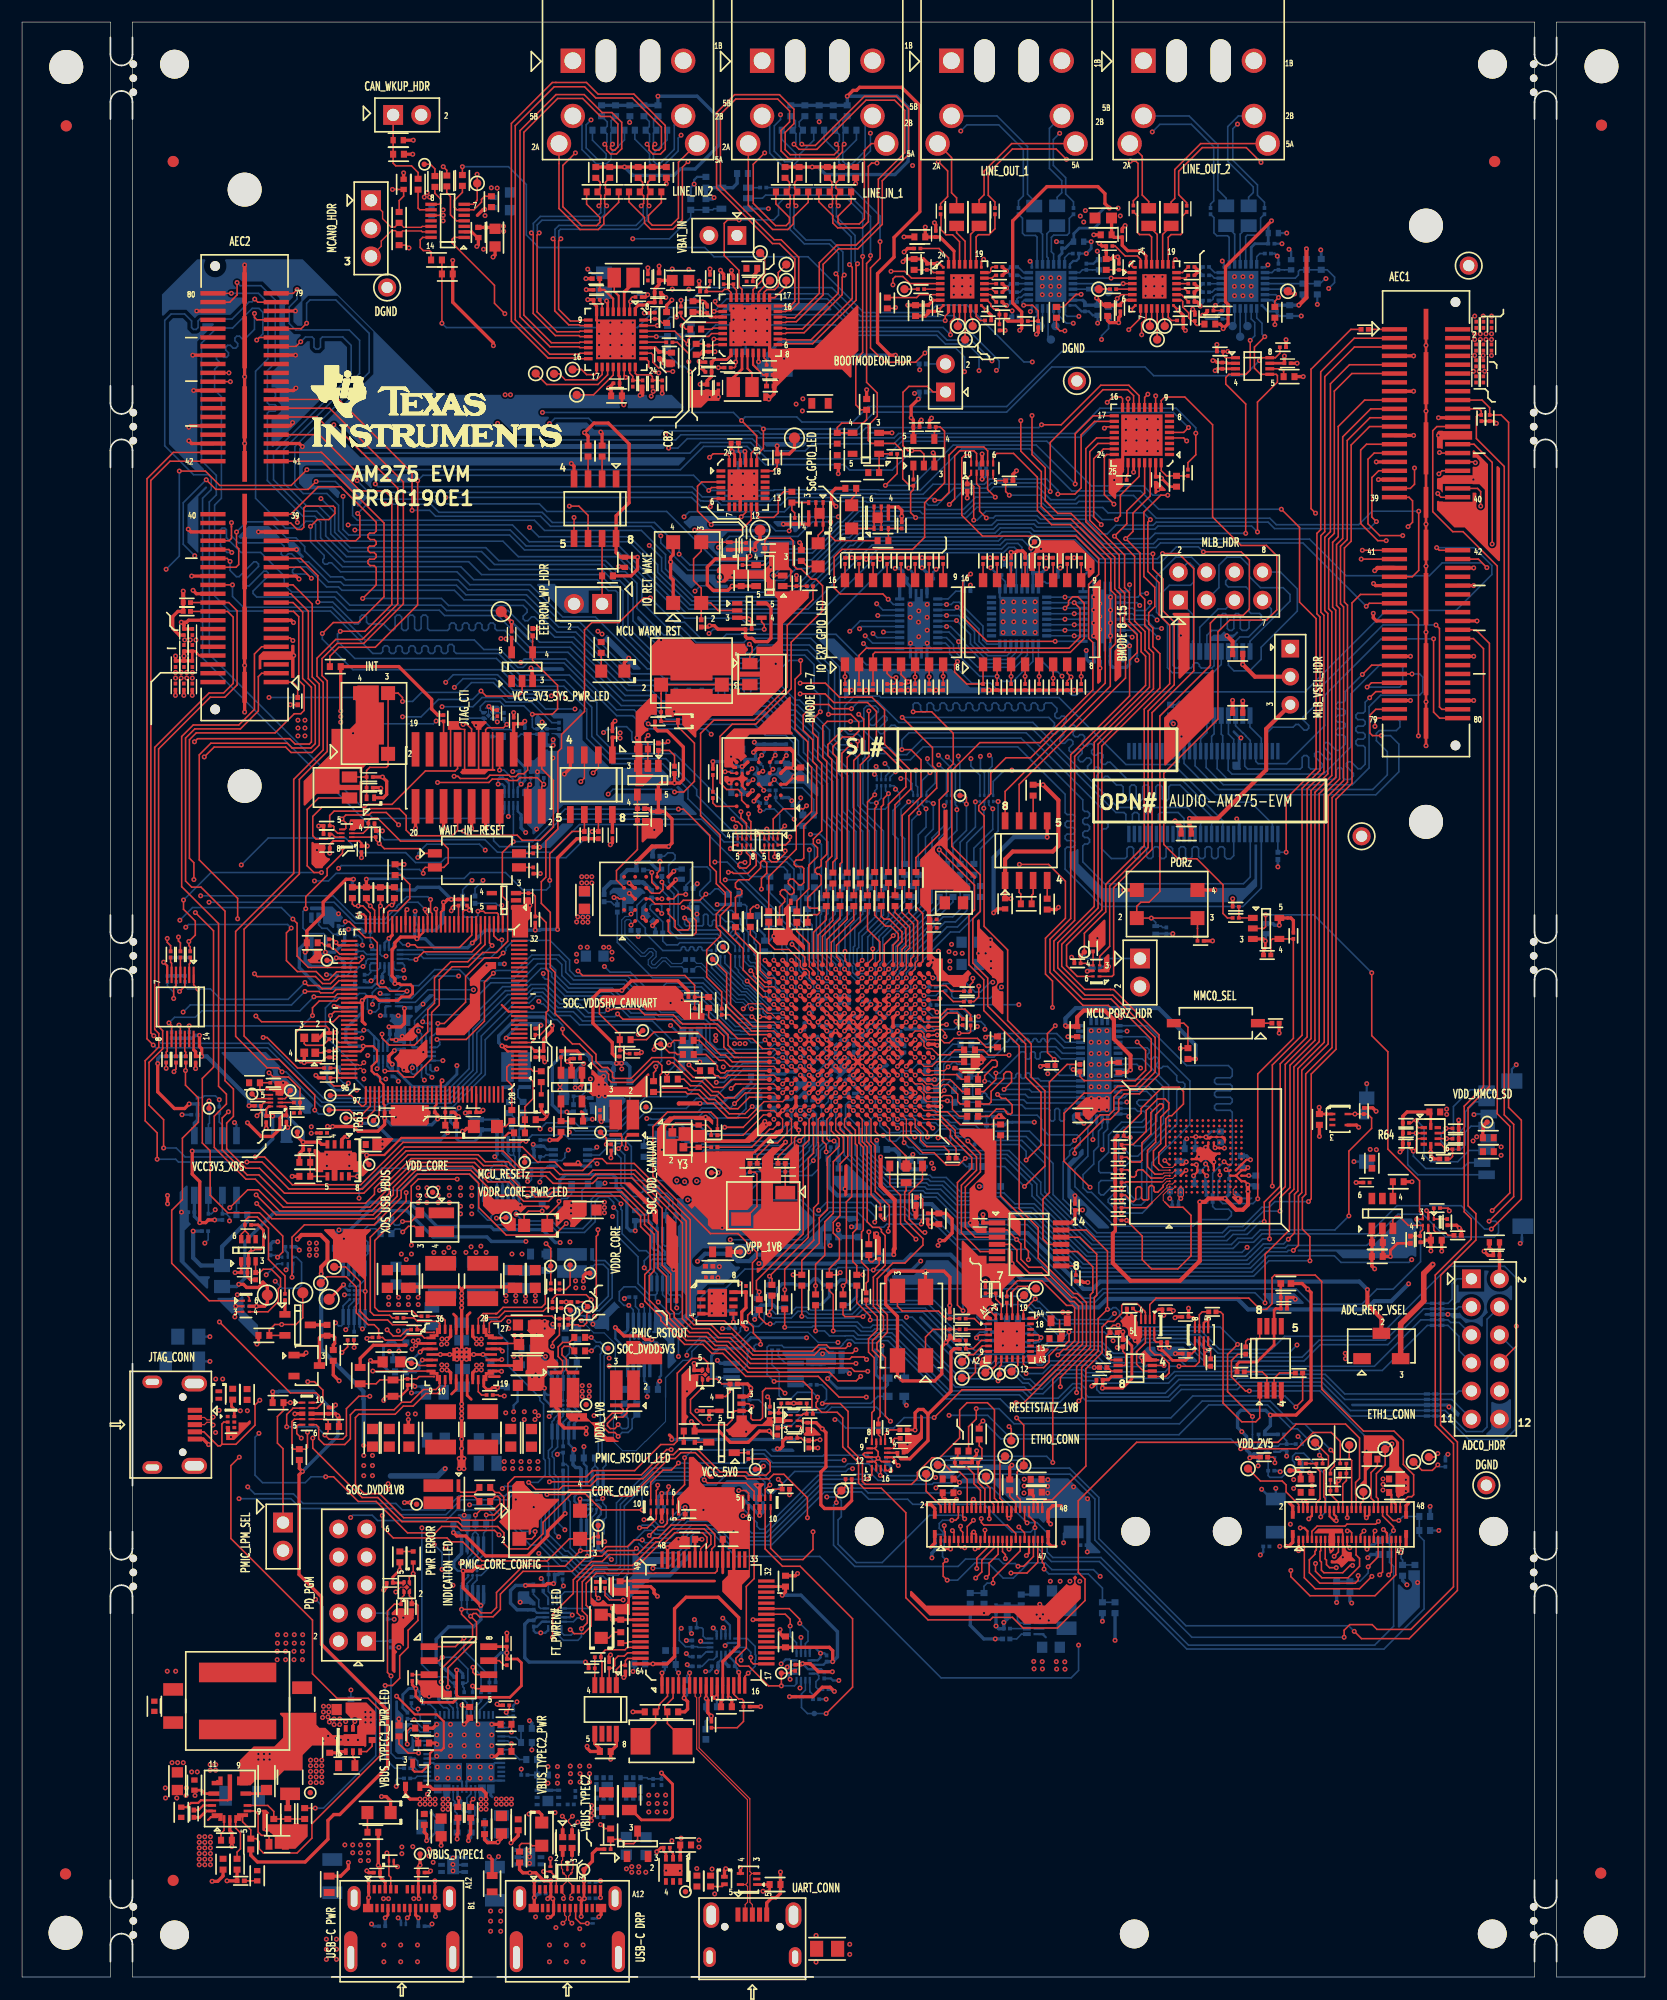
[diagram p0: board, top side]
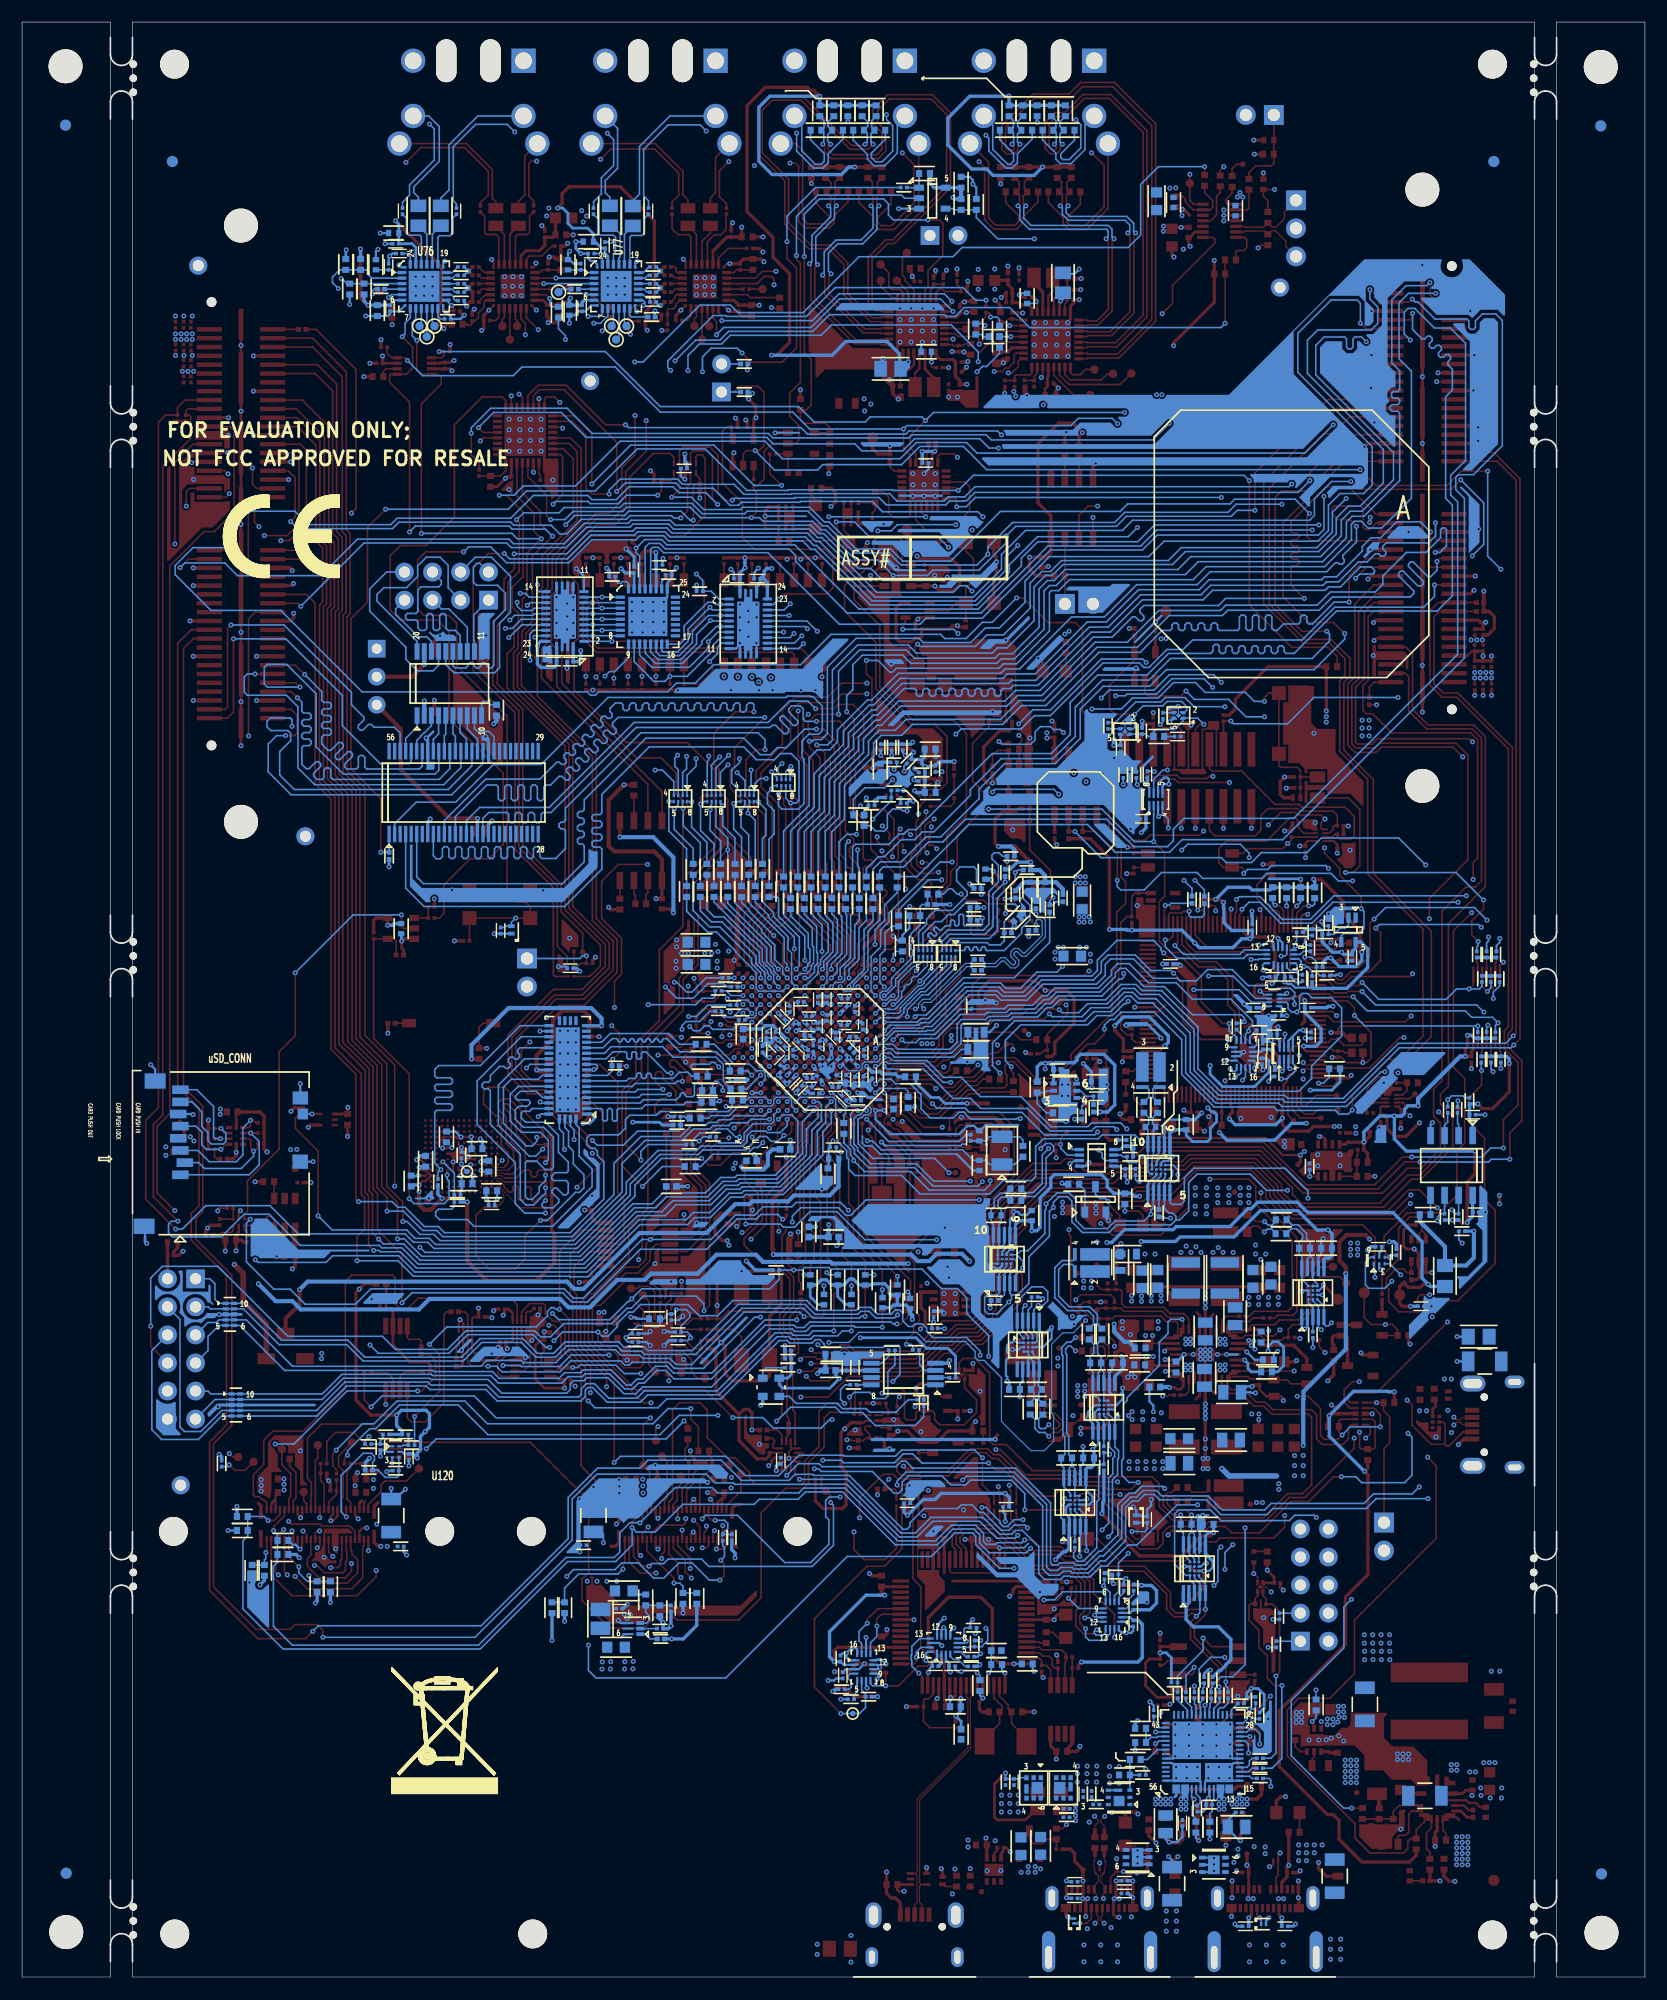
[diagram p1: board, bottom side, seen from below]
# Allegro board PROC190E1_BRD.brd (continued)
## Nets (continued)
EMMC_D2: R263.2 U49.A5(DAT2) U57.28(C6)
EMMC_D3: R275.2 U49.B2(DAT3) U57.40(C1)
EMMC_D4: R270.2 U49.B3(DAT4) U57.24(C8)
EMMC_D5: R267.2 U49.B4(DAT5) U57.26(C7)
EMMC_D6: R264.2 U49.B5(DAT6) U57.33(C4)
EMMC_D7: R262.2 U49.B6(DAT7) U57.31(C5)
EMMC_RSTN: R117.2 R5822.1 U26.4(Y) U49.K5(RST_N)
EN_VSYS_5V0: R3028.1 R3727.2 R5740.2 U134.7(EN/SYNC)
EPWM0_A: J12.3 U136.T2(SPI2_CS0)
EPWM0_B: J12.5 U136.R2(SPI2_CLK)
EPWM1_A: J13.3 U136.R1(SPI2_CS2)
EXT_CLKOUT0: R170.1 R337.1
EXT_CLKOUT0_R: R170.2 R5685.2 R5788.2 U136.P1(EXT_REFCLK1)
EXT_VMON2_1: J18.2 TP95.1(TP)
EXT_VMON2_2: J19.2 TP94.1(TP)
FT4232_DO: R321.1 R323.2 U61.4(DO)
FT4232_EECLK: R328.1 U61.2(CLK) U64.62(EECLK)
FT4232_EECS: R333.1 U61.1(CS) U64.63(EECS)
FT4232_EEDATA: R323.1 U61.3(DI) U64.61(EEDATA)
FT4232_REF: R609.2 U64.6(REF)
FT4232_RESET: C282.2 R357.1 U64.14(R\E\S\E\T\)
FT4232_SOC_UART2_RX_3V3: U64.16(ADBUS0) U125.13(2B1)
FT4232_SOC_UART2_TX_3V3: U64.17(ADBUS1) U125.15(1B1)
FT4232_SOC_UART3_RX_3V3: U64.26(BDBUS0) U126.13(2B1)
FT4232_SOC_UART3_TX_3V3: U64.27(BDBUS1) U126.15(1B1)
FT4232_UART2_RXD_1V8: R612.2 U125.8(2A1) U2351.7(S2B)
FT4232_UART2_TXD_1V8: R611.2 U125.6(1A1) U2351.9(S1B)
FT4232_UART3_RXD_1V8: R361.2 TP97.1(TP) U126.8(2A1) U2352.7(S2B)
FT4232_UART3_TXD_1V8: R631.2 TP117.1(TP) U126.6(1A1) U2352.9(S1B)
FT4232_USB_DM: J22.2(D-) U64.7(DM) U67.5(IO2)
FT4232_USB_DP: J22.3(D+) U64.8(DP) U67.3(IO1)
FT4232_USB_VBUS: C287.2 C291.2 C295.1 D3.2 J22.1(VBUS) TP96.1(TP) U66.4(EN) U66.6(IN) U67.1(VCC)
FT4232_WKUP_UART0_CTSN_3V3: U64.40(CDBUS2) U117.12(2B2)
FT4232_WKUP_UART0_RTSN_3V3: U64.41(CDBUS3) U117.14(1B2)
FT4232_WKUP_UART0_RXD_3V3: U64.38(CDBUS0) U117.13(2B1)
FT4232_WKUP_UART0_TXD_3V3: U64.39(CDBUS1) U117.15(1B1)
FT_PWREN#: R330.1 U64.60(P\W\R\E\N\)
GPIO1_23_INTN: R108.1 R547.2 U136.C7(WKUP_TIMER_IO1)
GPIO2_BUF_EN: R277.1 R278.2 U51.5(OE)
GPIO_CPSW1_RST: R364.1 U18.11(P11)
GPIO_CPSW2_RST: R604.1 U18.10(P10)
GPIO_EMMC_RSTN: R116.1 U21.9(P10)
GPIO_HYPERRAM_RSTN: R5697.1 U136.C12(OSPI1_CSN1)
GPIO_MCU_SOC: R546.1 R547.1 U98.5(2Y)
GPIO_MCU_SOC_INTN: R546.2 U136.C8(MCU_GPIO0_2)
GPIO_PCM1_RST: R84.1 U21.17(P20)
GPIO_PCM2_RST: R414.1 U21.19(P22)
HW/SW_CTRL_SEL: R83.2 R85.1 U15.23(HW_SW_CTRL)
HYPERBUS0_CK: R5694.1 R5754.2 U140.B2(CK)
HYPERBUS0_CK#: R5695.1 R5753.1 U140.B1(CK#)
HYPERBUS0_CS#: R5693.1 R5696.1 U140.A3(CS#)
HYPERBUS0_DQ0: R5715.1 RA8.1 U140.D3(DQ0)
HYPERBUS0_DQ1: R5716.1 RA8.2 U140.D2(DQ1)
HYPERBUS0_DQ2: R5712.1 RA8.4 U140.C4(DQ2)
HYPERBUS0_DQ3: R5710.1 RA8.3 U140.D4(DQ3)
HYPERBUS0_DQ4: R5717.1 RA9.1 U140.D5(DQ4)
HYPERBUS0_DQ5: R5714.1 RA9.4 U140.E3(DQ5)
HYPERBUS0_DQ6: R5713.1 RA9.2 U140.E2(DQ6)
HYPERBUS0_DQ7: R5711.1 RA9.3 U140.E1(DQ7)
HYPERBUS0_RST#: R5698.1 R5820.2 U140.A4(RESET#) U2348.4(Y)
HYPERBUS0_RWDS: R5709.1 R5752.1 R5810.1 U136.B15(OSPI1_DQS)
I2C0_SCL_1V8: C188.2 R234.2 R296.1 R598.2 U5.7(SCL) U6.7(SCL) U7.25(SCL_MOSI) U8.25(SCL_MOSI) U11.5(SCL_A) U15.12(SCL/GPIO3) U21.29(SCL) U76.7(SCL) U77.7(SCL) U2358.6(SCL)
I2C0_SCL_1V8_RC: R234.1 U136.M3(I2C0_SCL)
I2C0_SDA_1V8: C182.2 R210.2 R294.1 R603.2 U5.8(SDA) U6.8(SDA) U7.26(SDA_SSZ) U8.26(SDA_SSZ) U11.4(SDA_A) U15.19(SDA/GPIO2) U21.30(SDA) U76.8(SDA) U77.8(SDA) U2358.5(SDA)
I2C0_SDA_1V8_RC: R210.1 U136.N3(I2C0_SDA)
I2C3_SCL_1V8: J12.18 R465.2 U136.N1(UART0_CTSN)
I2C3_SDA_1V8: J12.20 R464.2 U136.L3(UART0_RTSN)
I2C5_SCL_1V8: J13.18 R685.2 U136.L4(MCAN0_TX)
I2C5_SDA_1V8: J13.20 R684.2 U136.M4(MCAN0_RX)
I2C_ADDR0_A0: J18.47 R641.1 R642.2
I2C_ADDR0_A2: J18.37 R638.1 R639.2
I2C_ADDR1_A0: J19.47 R628.2 R630.1
I2C_ADDR1_A2: J19.37 R626.2 R629.1
INA_ALERT: R305.2 R505.2 R586.2 R596.2 R597.1 R608.2 R5778.2 R5782.2 TP46.1(TP)
IO_EXP0_INTN: R108.2 R5761.2 U21.32(I\N\T\)
IO_EXP1_INTN: R98.1 U18.22(I\N\T\)
IO_EXP_ADDR: R456.1 U82.26(ADDR)
IO_EXP_TEST_LED: R441.1 U18.12(P12)
IO_MCAN0_EN: R5639.2 U21.10(P11)
IO_MCAN0_STB#: R102.2 R5692.1 U21.12(P13)
IORET_WAKE: U136.D7(MCU_GPIO0_16) U3070.4(Y)
JTAG_CTI_RTCK: J14.9 R476.1
JTAG_CTI_TCK: J14.11 R485.1 R487.1 U87.1(B) U88.1(B)
JTAG_DIR: R569.2 U110.4(1DIR) U110.5(2DIR)
JTAG_EMU0: J14.13 R211.2 U39.7(B1)
JTAG_EMU1: J14.14 R212.2 U39.6(B2)
JTAG_EMU_RSTN: J14.15 R482.2 U86.6(C)
JTAG_TCK: R483.1 U110.14(1B2)
JTAG_TDI: J14.3 U110.12(2B2)
JTAG_TDIS: J14.4 R490.2
JTAG_TDO: J14.7 U90.7(B1)
JTAG_TMS: J14.1 U110.13(2B1)
JTAG_TRST#: J14.2 R489.2 U110.15(1B1)
LDO_1V8: C303.1 U129.35(LDO_1V8)
LDO_3V3: C292.1 C300.2 C319.2 R195.1 R374.1 R378.1 R644.1 R646.1 R658.1 R660.1 R664.1 R678.1 R679.1 U69.8(VCC) U71.5(VCC) U129.9(LDO_3V3)
LM61460_BOOT: C3494.1 R5805.2 U134.14(CBOOT)
LM61460_FB: C3639.2 R3651.1 R3720.2 U134.4(FB)
LM61460_RT: R3652.1 U134.6(RT)
LM61460_SW: C3494.2 L24.1 U134.10(SW)
LM61460_VCC: C3627.2 U134.2(VCC)
MCAN0_CAN_H: J9.3 R88.2 U3068.13(CANH)
MCAN0_CAN_L: J9.1 R93.1 U3068.12(CANL)
MCAN0_EN: R5638.1 R5639.1 U3068.6(EN)
MCAN0_FAULT#: R5637.1 U3068.8(NFAULT)
MCAN0_RX: R81.1 U136.B4(MCU_GPIO0_6)
MCAN0_RX_R: R81.2 U3068.4(RXD)
MCAN0_STB#: R102.1 U3068.14(NSTB)
MCAN0_T: C107.1 R88.1 R93.2
MCAN0_TX: R82.2 U136.C4(MCU_GPIO0_5)
MCAN0_TX_R: R82.1 U3068.1(TXD)
MCAN0_WAKE_R: R5635.1 U3068.9(WAKE)
MCAN1_RX: R5670.1 U136.D5(MCU_GPIO0_8)
MCAN1_RX_R: J13.53 R5670.2
MCAN1_TX: J13.51 R5671.1
MCAN1_TX_R: R5671.2 U136.A4(MCU_GPIO0_7)
MCAN4_RX: R5650.1 U136.B6(MCU_GPIO0_14)
MCAN4_RX_R: J12.53 R5650.2
MCAN4_TX: J12.51 R5649.1
MCAN4_TX_R: R5649.2 U136.R4(SPI2_CS1)
MCASP0_ACLKR: J12.43 R5648.1 RA7.7
MCASP0_ACLKR_R: R5648.2 U136.R16(MCASP0_AXR12)
MCASP0_ACLKX: J12.37 R178.1 RA6.8
MCASP0_AFSR: J12.41 R498.2 RA7.6
MCASP0_AFSR_R: R498.1 U136.T17(MCASP0_AXR13)
MCASP0_AFSX: J12.39 R191.2 RA2.8
MCASP0_AFSX_R: R191.1 U136.M19(MCASP0_AFSX)
MCASP0_AXR0: J12.27 R176.2 RA5.8
MCASP0_AXR0_R: R176.1 U136.N17(MCASP0_AXR0)
MCASP0_AXR1: J12.29 R499.2 RA2.7
MCASP0_AXR1_R: R499.1 U136.M16(MCASP0_AXR1)
MCASP0_AXR2: J12.28 R493.2 RA2.6
MCASP0_AXR2_R: R493.1 U136.N18(MCASP0_AXR2)
MCASP0_AXR3: J12.30 R494.2 RA6.5
MCASP0_AXR3_R: R494.1 U136.M18(MCASP0_AXR3)
MCASP0_AXR4: J12.32 R495.2 RA7.5
MCASP0_AXR4_R: R495.1 U136.N16(MCASP0_AXR4)
MCASP0_AXR5: J12.34 R492.2 RA5.6
MCASP0_AXR5_R: R492.1 U136.P17(MCASP0_AXR5)
MCASP0_AXR6_R: R5718.1 U136.P18(MCASP0_AXR6)
MCASP0_AXR7: J12.38 R177.2 RA2.5
MCASP0_AXR7_R: R177.1 U136.P19(MCASP0_AXR7)
MCASP0_AXR8_R: R5719.1 U136.P16(MCASP0_AXR8)
MCASP0_AXR9: J12.40 R491.2 RA7.8
MCASP0_AXR9_R: R491.1 U136.R17(MCASP0_AXR9)
MCASP1_ACLKR_R: R179.2 U136.T18(MCASP0_AXR14)
MCASP1_ACLKX_R: R5646.2 U136.H19(MCASP1_ACLKX)
MCASP1_AFSR_R: R5640.1 U136.T19(MCASP0_AXR15)
MCASP1_AFSX_R: R5647.1 U136.J17(MCASP1_AFSX)
MCASP1_AXR0_R: R500.1 U136.J18(MCASP1_AXR0)
MCASP1_AXR1_R: R5645.1 U136.J19(MCASP1_AXR1)
MCASP1_AXR2_R: R190.1 U136.J16(MCASP1_AXR2)
MCASP2_ACLKR: J13.43 R5669.1
MCASP2_ACLKR_R: R5669.2 U136.G17(MCASP4_AXR1)
MCASP2_ACLKX: J13.37 R5668.1
MCASP2_ACLKX_R: R5668.2 U136.L19(MCASP2_ACLKX)
MCASP2_AFSR: J13.41 R5667.2
MCASP2_AFSR_R: R5667.1 U136.G16(MCASP4_AXR2)
MCASP2_AFSX: J13.39 R5666.2
MCASP2_AFSX_R: R5666.1 U136.K19(MCASP2_AFSX)
MCASP2_AXR0: J13.27 R5660.2
MCASP2_AXR0_R: R5660.1 U136.L17(MCASP2_AXR0)
MCASP2_AXR1: J13.29 R5661.2
MCASP2_AXR1_R: R5661.1 U136.K16(MCASP2_AXR1)
MCASP2_AXR2: J13.28 R5662.2
MCASP2_AXR2_R: R5662.1 U136.L18(MCASP2_AXR2)
MCASP2_AXR3: J13.30 R5663.2
MCASP2_AXR3_R: R5663.1 U136.K18(MCASP2_AXR3)
MCASP2_AXR4: J13.32 R5664.2
MCASP2_AXR4_R: R5664.1 U136.L16(MCASP2_AXR4)
MCASP2_AXR5: J13.34 R5665.2
MCASP2_AXR5_R: R5665.1 U136.M17(MCASP2_AXR5)
MCASP3_ACLKR: J13.78 R5683.1
MCASP3_ACLKX: J13.77 R5677.1
MCASP3_AFSR: J13.80 R5682.2
MCASP3_AFSX: J13.79 R5676.2
MCASP3_AXR0: J13.67 R5672.2
MCASP3_AXR1: J13.69 R5673.2
MCASP3_AXR2: J13.71 R5674.2
MCASP3_AXR3: J13.73 R5675.2
MCASP4_ACLKR: J12.78 U3072.54(1B1)
MCASP4_ACLKR_FET: R5651.1 RA6.6 U3072.2(1A)
MCASP4_ACLKR_HDR: J28.3 U2345.20(B1)
MCASP4_ACLKR_LT: U2345.1(A1) U3072.53(1B2)
MCASP4_ACLKR_R: R5651.2 U136.R18(MCASP0_AXR10)
MCASP4_ACLKX: J12.77 U3072.39(8B1)
MCASP4_ACLKX_FET: R5653.1 U3072.18(8A)
MCASP4_ACLKX_HDR: J28.1 U2345.12(B8)
MCASP4_ACLKX_LT: U2345.9(A8) U3072.37(8B2)
MCASP4_ACLKX_R: R5653.2 R5683.2 U136.F18(MCASP4_ACLKX)
MCASP4_AFSR: J12.80 U3072.52(2B1)
MCASP4_AFSR_FET: R5652.2 RA6.7 U3072.4(2A)
MCASP4_AFSR_HDR: J28.7 U2345.18(B2)
MCASP4_AFSR_LT: U2345.3(A2) U3072.51(2B2)
MCASP4_AFSR_R: R5652.1 U136.R19(MCASP0_AXR11)
MCASP4_AFSX: J12.79 U3072.41(7B1)
MCASP4_AFSX_FET: R5655.2 U3072.15(7A)
MCASP4_AFSX_HDR: J28.5 U2345.13(B7)
MCASP4_AFSX_LT: U2345.8(A7) U3072.40(7B2)
MCASP4_AFSX_R: R5655.1 R5682.1 U136.F17(MCASP4_AFSX)
MCASP4_AXR0: J12.67 U3072.50(3B1)
MCASP4_AXR0_FET: R5654.2 U3072.6(3A)
MCASP4_AXR0_HDR: J28.8 U2345.17(B3)
MCASP4_AXR0_LT: U2345.4(A3) U3072.48(3B2)
MCASP4_AXR0_R: R5654.1 U136.F19(MCASP4_AXR0)
MCASP4_AXR3: J12.69 U3072.43(6B1)
MCASP4_AXR3_FET: R5658.2 U3072.13(6A)
MCASP4_AXR3_LT: U2345.7(A6) U3072.42(6B2)
MCASP4_AXR3_MLB0_SIG_HDR: J28.6 U2345.14(B6)
MCASP4_AXR3_R: R5658.1 U136.U18(MLB0_MLBSIG)
MCASP4_AXR4: J12.71 U3072.47(4B1)
MCASP4_AXR4_FET: R5656.2 U3072.9(4A)
MCASP4_AXR4_LT: U2345.5(A4) U3072.46(4B2)
MCASP4_AXR4_MLB0_CLK_HDR: J28.4 U2345.16(B4)
MCASP4_AXR4_R: R5656.1 U136.U19(MLB0_MLBCLK)
MCASP4_AXR5: J12.73 U3072.45(5B1)
MCASP4_AXR5_FET: R5657.2 U3072.11(5A)
MCASP4_AXR5_LT: U2345.6(A5) U3072.44(5B2)
MCASP4_AXR5_MLB0_DAT_HDR: J28.2 U2345.15(B5)
MCASP4_AXR5_R: R5657.1 U136.V19(MLB0_MLBDAT)
MCASP4_FET_SEL: R5681.1 R5764.1 U18.4(P03) U3072.1(S)
MCASP_VSEL_HDR: C3702.1 J29.2 U2345.19(VCCB)
MCU_INTN: R299.1 U136.M2(I2C1_SDA)
MCU_OSC0_XI: R249.2 R252.2 U136.A2(MCU_OSC0_XI)
MCU_OSC0_XO: R253.2 R254.2 U136.B1(MCU_OSC0_XO)
MCU_PORZ: J32.1 R238.1 R242.2 R5775.1 R5776.1 TP49.1(TP) U43.4(Y) U136.E3(MCU_PORZ)
MCU_RESETZ: R550.2 TP50.1(TP) U98.7(1Y) U136.D9(MCU_RESETZ)
MCU_SAFETY_ERRORZ_1V8: R281.1 TP54.1(TP) U136.F3(MCU_ERRORN)
MIC1_BIAS: C3.1 C329.1 C379.1 R7.1 R8.1 R9.1 R10.1 R405.1 R406.1 R407.1 R408.1 U7.6(MICBIAS)
MIC2_BIAS: C2.1 C330.1 C363.1 R3.1 R4.1 R5.1 R6.1 R409.1 R410.1 R411.1 R412.1 U8.6(MICBIAS)
MMC0_CLK: R558.1 U57.2(A0)
MMC0_FET_EN: R5215.2 R5216.2 U18.3(P02) U57.8(EN)
MMC0_SD_EN: R21.1 U21.4(P03)
MMC0_SD_LS_EN: R17.1 R5823.2 U2.4(Y) U4.3(ON)
MMC0_SDIO_VSEL: U56.11(GPIO5) U3087.4(Y)
MMC0_SEL_1V8: U3077.4(A3) U3086.1(O\E\) U3087.1(B)
MMC0_SEL_3V3: R5758.1 U3077.11(B3)
OBSCLK0: R5719.2 RA5.5 TP587.1(TP)
OSC0: C217.2 U48.88(OSC0) Y5.3
OSC1: C223.2 U48.89(OSC1) Y5.1
OSC1_XI: R3732.1 U136.C1(OSC1_XI)
OSC1_XO: R3733.1 U136.C2(OSC1_XO)
OSPI0_CSN0: R206.2 U136.A17(OSPI0_CSN0)
OSPI0_RESET_OUT0: R121.1 U136.A16(OSPI0_CSN3)
OSPI_CLK: R197.1 R451.1 U28.B2(CK)
OSPI_CS: R206.1 R447.1 R5826.2 R5827.2
OSPI_DQ0: R446.1 RA3.1 U28.D3(DQ0)
OSPI_DQ1: R450.1 RA3.2 U28.D2(DQ1)
OSPI_DQ2: R452.1 RA3.3 U28.C4(DQ2)
OSPI_DQ3: R449.1 RA3.4 U28.D4(DQ3)
OSPI_DQ4: R448.1 RA4.1 U28.D5(DQ4)
OSPI_DQ5: R445.1 RA4.2 U28.E3(DQ5)
OSPI_DQ6: R444.1 RA4.3 U28.E2(DQ6)
OSPI_DQ7: R443.1 RA4.4 U28.E1(DQ7)
OSPI_DQS: R453.1 U28.C3(DS)
OSPI_DQS_SOC: R453.2 R454.1 R504.1 U136.B19(OSPI0_DQS)
OSPI_INTN: R123.1 R125.1
OSPI_RSTN: R124.1 R5821.2 U27.4(Y) U28.A4(RESET#)
P2_PP_EXT_ENABLE: R669.1 U129.49(GPIO17/PP_EXT2)
PCM1_ADDR_0: R20.2 R26.1 U7.24(ADDR0_SCLK)
PCM1_ADDR_1: R22.1 R23.2 U7.23(ADDR1_MISO)
PCM1_AREG: C89.1 C378.1 U7.2(AREG)
PCM1_BSTOUT: C92.2 C96.1 U7.5(BSTOUT)
PCM1_DREG: C81.1 C82.1 U7.32(DREG)
PCM1_GPIO1: R34.2 R432.1 U7.28(GPIO1)
PCM1_IN1N: C17.2 R9.2 U7.10(IN1M)
PCM1_IN1P: C18.2 R10.2 U7.9(IN1P)
PCM1_IN2N: C15.2 R7.2 U7.12(IN2M)
PCM1_IN2P: C16.2 R8.2 U7.11(IN2P)
PCM1_IN3N: C334.2 R408.2 U7.14(IN3M)
PCM1_IN3P: C333.2 R407.2 U7.13(IN3P)
PCM1_IN4N: C332.2 R406.2 U7.16(IN4M)
PCM1_IN4P: C331.2 R405.2 U7.15(IN4P)
PCM1_INT_1V8: R34.1 U21.15(P16)
PCM1_MCASP1_AXR0: R38.2 U7.29(SDOUT)
PCM1_RESETN: R68.2 R78.1 U7.22(SHDNZ) U14.4(Y)
PCM1_VREF: C87.1 U7.7(VREF)
PCM2_ADDR_0: R62.2 R63.1 U8.24(ADDR0_SCLK)
PCM2_ADDR_1: R60.2 R61.1 U8.23(ADDR1_MISO)
PCM2_AREG: C64.1 C368.1 U8.2(AREG)
PCM2_BSTOUT: C54.1 C60.2 U8.5(BSTOUT)
PCM2_IN1N: C13.2 R5.2 U8.10(IN1M)
PCM2_IN1P: C14.2 R6.2 U8.9(IN1P)
PCM2_IN2N: C11.2 R3.2 U8.12(IN2M)
PCM2_IN2P: C12.2 R4.2 U8.11(IN2P)
PCM2_IN3N: C338.2 R412.2 U8.14(IN3M)
PCM2_IN3P: C337.2 R411.2 U8.13(IN3P)
PCM2_IN4N: C336.2 R410.2 U8.16(IN4M)
PCM2_IN4P: C335.2 R409.2 U8.15(IN4P)
PCM2_INT_1V8: R46.1 U21.16(P17)
PCM2_MCASP1_AXR0: R431.2 R433.1
PCM2_RESETN: R415.2 R416.1 U8.22(SHDNZ) U75.4(Y)
PCM2_VREF: C65.1 U8.7(VREF)
PCM6240_MCASP1_ACLKR: R179.1 U7.30(BCLK) U8.30(BCLK)
PCM6240_MCASP1_AFSR: R5640.2 U7.31(FSYNC) U8.31(FSYNC)
PCM6240_MCASP1_AXR0: R38.1 R431.1 R500.2
PCM6240_MCASP1_AXR2: R190.2 R435.1
PD_GPIO0: R674.2 U129.16(GPIO0)
PD_HRESET: C301.1 R662.1 U129.44(HRESET)
PD_I2C_IRQ: R645.2 R655.1 U18.6(P05)
PD_MS_I2C1_IRQ: R660.2 U129.29(I\2\C\1\_\I\R\Q\)
PD_MS_I2C1_SCL: R633.1 R664.2 U129.27(I2C1_SCL)
PD_MS_I2C1_SDA: R627.1 R658.2 U129.28(I2C1_SDA)
PD_S_I2C2_IRQ: R655.2 U129.34(I\2\C\2\_\I\R\Q\)
PD_S_I2C2_SCL: R657.2 U129.32(I2C2_SCL)
PD_S_I2C2_SDA: R656.2 U129.33(I2C2_SDA)
PD_SPI_CLK: J21.7 R652.2 U69.6(CLK)
PD_SPI_MISO: J21.5 R644.2 R654.2 U69.2(DO(IO1))
PD_SPI_MOSI: J21.8 R653.2 U69.5(DI(IO0))
PD_SPI_SS: J21.9 R646.2 R651.2 U69.1(C\S\)
PD_VIN_3V3: C320.2 U129.5(VIN_3V3)
PMIC_EN: R317.2 U56.17(EN/PB/VSENSE)
PMIC_ENABLE: U54.6(C) U2356.10(D1)
PMIC_I2C_SCL_1V8: R296.2 TP72.1(TP) U56.1(SCL_I2C1/SCK_SPI)
PMIC_I2C_SDA_1V8: R294.2 TP73.1(TP) U56.2(SDA_I2C1/SDI_SPI)
PMIC_INT_B: R288.2 R299.2 R300.2 TP70.1(TP) U56.27(I\N\T\/EN_DRV)
PMIC_INTN: R205.1 R300.1 U136.P3(EXTINTN)
PMIC_LPM_EN0: R5737.1 R5750.2 TP75.1(TP) U2356.2(S1A) U2356.7(S2B)
PMIC_LPM_SEL: J16.1 R318.1 U2356.1(SEL1) U2356.5(SEL2)
PMIC_NSLEEP: U56.10(GPIO4) U2356.6(D2)
PMIC_POWERGOOD: R290.1 U86.1(A)
PMIC_RSTOUT: R286.1 R290.2 R291.2 TP67.1(TP) U56.28(R\S\T\O\U\T\)
PORT1_15W: R386.1 R5767.1 U71.2(A)
PORT2_15W: R381.1 R390.1 U71.1(B)
PP1_CABLE: C309.1 U129.25(PP1_CABLE)
PP2_CABLE: C631.1 R665.2 U129.46(PP2_CABLE)
PRI/SEC_REF_SEL: R75.2 R76.1 U15.4(REFSEL)
RESET_STATZ: R5738.1 TP592.1(TP) U136.H4(RESETSTATZ)
RESETSTATZ: R366.1 R605.1 U18.24(R\E\S\E\T\) U3077.13(B1)
RESETSTATZ_1V8: J12.55 J13.55 R377.2 R5738.2 R5760.2 TP100.1(TP) U2.3(B) U14.2(B) U15.8(PDN) U21.28(R\E\S\E\T\) U26.2(B) U27.2(B) U75.2(B) U2348.2(B) U3077.2(A1)
RGMII1_INH_3V3: J18.26 TP65.1(TP)
RGMII1_RX_ER: J18.39 TP99.1(TP)
RGMII1_RX_LINK: J18.43 R360.2 TP98.1(TP)
RGMII2_INH_3V3: J19.26 TP59.1(TP)
RGMII2_RX_ER: J19.39 TP89.1(TP)
RGMII2_RX_LINK: J19.43 R347.2 TP91.1(TP)
SD_MMC0_CLK: J26.5(CLK) R54.1 R202.1 U10.6(IO4) U57.41(B0)
SD_MMC0_CMD: J26.3(CMD) R66.1 U10.1(IO1) U57.23(B9)
SD_MMC0_D0: J26.7(DAT0) R65.1 U10.8(IO6) U57.38(B2)
SD_MMC0_D1: J26.8(DAT1) R57.1 U10.7(IO5) U57.36(B3)
SD_MMC0_D2: J26.1(DAT2) R64.1 U10.2(IO2) U57.29(B6)
SD_MMC0_D3: J26.2(CD/DAT3) R55.1 U10.3(IO3) U57.39(B1)
SD_MMC0_SDCD: J26.9(CD) R70.1 U12.5(IO2) U136.N2(I2C1_SCL)
SEC_REF_N: R74.1 U15.2(SECREF_N)
SEC_REF_P: R73.1 U15.1(SECREF_P)
SEL_XDS: U39.5(OE) U93.4(Y) U97.1(1\O\E\) U97.16(2\O\E\) U109.4(O\E\)
SEL_XDS110_INV: J14.8 R531.2 R536.1 U90.4(O\E\) U93.2(A) U102.5(OE) U110.1(1\O\E\) U110.16(2\O\E\) U2355.2(A)
SEL_XDS110_INV_3V3: R5735.1 U87.2(A) U88.2(A) U2355.4(Y)
SOC_CLKIN: R249.1 R349.2
SOC_DVDD1V8: C429.1 C437.1 C440.1 C453.1 C461.1 C502.1 C506.1 R334.3 TP86.1(TP) U56.24(FB_B3) U136.E13(VDDSHV1#E13) U136.F8(VDDSHV_MCU#F8) U136.F9(VDDSHV_MCU#F9) U136.F12(VDDSHV1#F12) U136.H14(VDDSHV3#H14) U136.J6(VMON_1P8_SOC) U136.J14(VDDSHV3#J14) U136.K6(VDDSHV0#K6) U136.K14(VDDSHV3#K14) U136.M6(VDDSHV0#M6)
SOC_DVDD1V8_N: C603.2 R335.1 U123.D1(BUS) U123.D2(IN-) U124.8(VBUS) U124.9(IN-)
SOC_DVDD1V8_P: C603.1 R331.1 U123.D3(IN+) U124.10(IN+)
SOC_DVDD3V3: C451.1 C471.1 FL19.1 R327.3 TP83.1(TP) U56.22(FB_B4) U136.H5(VMON_3P3_SOC) U136.P11(VDDSHV2#P11) U136.P12(VDDSHV2#P12)
SOC_DVDD3V3_FB1: C3645.1 FL19.2 U136.R9(VDDA_3P3_USB)
SOC_DVDD3V3_N: C428.2 R539.1 U91.8(VBUS) U91.9(IN-) U92.D1(BUS) U92.D2(IN-)
SOC_DVDD3V3_P: C428.1 R540.1 U91.10(IN+) U92.D3(IN+)
SOC_EMU0: R225.2 SW3.1 U39.2(A1) U102.2(A1) U136.C9(EMU0)
SOC_EMU1: R220.2 SW3.2 U39.3(A2) U102.3(A2) U136.C10(EMU1)
SOC_GPIO1_49: R213.1 U136.K17(MCASP1_AXR3)
SOC_HYPERBUS0_DQ0: RA8.8 U136.A13(OSPI1_D0)
SOC_HYPERBUS0_DQ1: RA8.7 U136.D12(OSPI1_D1)
SOC_HYPERBUS0_DQ2: RA8.5 U136.D13(OSPI1_D2)
SOC_HYPERBUS0_DQ3: RA8.6 U136.C13(OSPI1_D3)
SOC_HYPERBUS0_DQ4: RA9.8 U136.A15(OSPI1_D4)
SOC_HYPERBUS0_DQ5: RA9.5 U136.C15(OSPI1_D5)
SOC_HYPERBUS0_DQ6: RA9.7 U136.B14(OSPI1_D6)
SOC_HYPERBUS0_DQ7: RA9.6 U136.C14(OSPI1_D7)
SOC_I2C0_SCL: J18.40 J19.40 R56.2 R622.2 R625.1 R657.1 U11.8(SCL_B) U18.19(SCL) U25.2(SCLA) U91.2(A0) U91.5(SCL) U92.A1(SCL) U92.B3(A0) U113.A1(SCL) U114.5(SCL) U115.A1(SCL) U116.5(SCL) U118.1(A1) U118.5(SCL) U119.A1(SCL) U119.C3(A1) U123.A1(SCL) U124.5(SCL) U2357.8(SCL) U3078.5(SCL) U3079.2(A0) U3079.5(SCL) U3080.A1(SCL) U3081.A1(SCL) U3081.B3(A0)
SOC_I2C0_SDA: J18.42 J19.42 R58.2 R616.1 R618.2 R656.1 U11.1(SDA_B) U18.20(SDA) U25.3(SDAA) U91.4(SDA) U92.A2(SDA) U113.A2(SDA) U114.4(SDA) U115.A2(SDA) U116.4(SDA) U118.4(SDA) U119.A2(SDA) U123.A2(SDA) U124.4(SDA) U2357.7(SDA) U3078.2(A0) U3078.4(SDA) U3079.4(SDA) U3080.A2(SDA) U3080.B3(A0) U3081.A2(SDA)
SOC_MMC0_CLK: R558.2 U136.V5(MMC0_CLK)
SOC_MMC0_CMD: R5819.1 U57.14(A9)
SOC_MMC0_CMD_R: R5819.2 U136.T6(MMC0_CMD)
SOC_MMC0_DAT0: R5811.1 U57.4(A2)
SOC_MMC0_DAT0_R: R5811.2 U136.W4(MMC0_DAT0)
SOC_MMC0_DAT1: R5812.1 U57.5(A3)
SOC_MMC0_DAT1_R: R5812.2 U136.W5(MMC0_DAT1)
SOC_MMC0_DAT2: R5813.1 U57.11(A6)
SOC_MMC0_DAT2_R: R5813.2 U136.V6(MMC0_DAT2)
SOC_MMC0_DAT3: R5814.1 U57.3(A1)
SOC_MMC0_DAT3_R: R5814.2 U136.U6(MMC0_DAT3)
SOC_MMC0_DAT4: R5815.1 U57.13(A8)
SOC_MMC0_DAT4_R: R5815.2 U136.U7(MMC0_DAT4)
SOC_MMC0_DAT5: R5816.1 U57.12(A7)
SOC_MMC0_DAT5_R: R5816.2 U136.T7(MMC0_DAT5)
SOC_MMC0_DAT6: R5817.1 U57.6(A4)
SOC_MMC0_DAT6_R: R5817.2 U136.V7(MMC0_DAT6)
SOC_MMC0_DAT7: R5818.1 U57.7(A5)
SOC_MMC0_DAT7_R: R5818.2 U136.W7(MMC0_DAT7)
SOC_OSPI_CLK: R197.2 U136.B17(OSPI0_CLK)
SOC_OSPI_DQ0: RA3.8 U136.B16(OSPI0_D0)
SOC_OSPI_DQ1: RA3.7 U136.D17(OSPI0_D1)
SOC_OSPI_DQ2: RA3.6 U136.C17(OSPI0_D2)
SOC_OSPI_DQ3: RA3.5 U136.D16(OSPI0_D3)
SOC_OSPI_DQ4: RA4.8 U136.E16(OSPI0_D4)
SOC_OSPI_DQ5: RA4.7 U136.B18(OSPI0_D5)
SOC_OSPI_DQ6: RA4.6 U136.D18(OSPI0_D6)
SOC_OSPI_DQ7: RA4.5 U136.C18(OSPI0_D7)
SOC_PORZ: R480.2 U43.3(B) U86.4(Y)
SOC_PORZ_PB: R268.2 TP55.1(TP) U43.1(A) U98.2(3Y)
SOC_RGMII_MDC: R338.1 R352.1 R548.2
SOC_RGMII_MDIO: R340.1 R345.1 R541.2
SOC_TCK: R534.1 R544.1 R566.1 U136.A10(TCK)
SOC_TDI: R554.1 U97.6(1A1) U110.9(2A2) U136.D10(TDI)
SOC_TDO: R542.1 U90.2(A1) U109.2(A1)
SOC_TMS: R533.1 U97.8(2A1) U110.8(2A1) U136.C11(TMS)
SOC_TRST#: R564.1 U97.9(2A2) U110.6(1A1) U136.B10(TRSTN)
SOC_UART0_RXD: R5734.2 U136.L2(UART0_RXD)
SOC_UART0_RXD_XDS: R5730.1 U2353.15(1B1)
SOC_UART0_TXD: R5732.2 U2353.8(2A1)
SOC_UART0_TXD_XDS: R5731.1 U2353.13(2B1)
SOC_USB0_DM: L10.4(OUT2) R400.1 U136.W9(USB0_DM)
SOC_USB0_DP: L10.1(IN1) R399.1 U136.V9(USB0_DP)
SOC_USB0_DRVVBUS: U136.W2(USB0_DRVVBUS) U3077.5(A4)
SOC_USB0_DRVVBUS_3V3: R673.1 R674.1 U3077.10(B4)
SOC_USB0_RCALIB: R553.1 U136.V8(USB0_RCALIB)
SOC_USB0_VBUS: R398.1 R560.1 U136.U9(USB0_VBUS)
SOC_VDD_CANUART: C224.1 R3731.1 R5786.2 TP52.1(TP) U136.F6(VDD_CANUART)
SOC_VDD_CANUART_N: C3761.2 R5780.1 U3078.8(VBUS) U3078.9(IN-) U3080.D1(BUS) U3080.D2(IN-)
SOC_VDD_CANUART_P: C3761.1 R5781.1 U3078.10(IN+) U3080.D3(IN+)
SOC_VDDSHV5_SDIO: C3655.1 R243.2 U136.P9(VDDSHV5#P9) U136.R8(VDDSHV5#R8)
SOC_VDDSHV_CANUART: C512.1 R5787.2 TP597.1(TP) U136.F7(VDDSHV_CANUART)
SOC_VDDSHV_CANUART_N: C3763.2 R5784.1 U3079.8(VBUS) U3079.9(IN-) U3081.D1(BUS) U3081.D2(IN-)
SOC_VDDSHV_CANUART_P: C3763.1 R5785.1 U3079.10(IN+) U3081.D3(IN+)
SPI0_CLK: J12.17 R216.1
SPI0_CLK_R: R216.2 U136.M1(SPI0_CLK)
SPI0_CS0: J12.23 U136.J3(SPI0_CS0)
SPI0_CS1: J12.24 U136.J4(SPI0_CS1)
SPI0_D0: J12.19 U136.K3(SPI0_D0)
SPI0_D1: J12.21 U136.K4(SPI0_D1)
SPI1_CLK: J13.17 R5659.1
SPI1_CLK_R: R5659.2 U136.U2(SPI1_CLK)
SPI1_CS0: J13.23 U136.U1(SPI1_CS0)
SPI1_CS1: J13.24 U136.D15(OSPI0_CSN2)
SPI1_D0: J13.19 U136.T3(SPI1_D0)
SPI1_D1: J13.21 U136.U3(SPI1_D1)
SPI_HOLDN: R374.2 U69.7(H\O\L\D\(IO3))
SPI_WPN: R378.2 U69.3(W\P\(IO2))
SW_2V5: L11.1 U127.5(SW)
SYNC1_OUT: R5788.1 U3083.2(A1)
SYNC1_OUT_3V3: R5793.1 U3084.1(CLKIN)
SYNC1_OUT_ETH1: J18.38 R5791.2 TP93.1(TP)
SYNC1_OUT_ETH2: J19.38 R5792.2 TP87.1(TP)
SYS_BOOTMODE0: R153.1 SW2.1 U81.10(A8) U82.1(P00)
SYS_BOOTMODE1: R154.1 SW2.2 U81.9(A7) U82.2(P01)
SYS_BOOTMODE2: R155.1 SW2.3 U81.8(A6) U82.3(P02)
SYS_BOOTMODE3: R156.1 SW2.4 U81.7(A5) U82.4(P03)
SYS_BOOTMODE4: R157.1 SW2.5 U81.6(A4) U82.5(P04)
SYS_BOOTMODE5: R158.1 SW2.6 U81.5(A3) U82.6(P05)
SYS_BOOTMODE6: R159.1 SW2.7 U81.4(A2) U82.7(P06)
SYS_BOOTMODE7: R160.1 SW2.8 U81.3(A1) U82.8(P07)
SYS_BOOTMODE8: R145.1 SW1.1 U82.9(P10) U83.10(A8)
SYS_BOOTMODE9: R146.1 SW1.2 U82.10(P11) U83.9(A7)
SYS_BOOTMODE10: R147.1 SW1.3 U82.11(P12) U83.8(A6)
SYS_BOOTMODE11: R148.1 SW1.4 U82.12(P13) U83.7(A5)
SYS_BOOTMODE12: R149.1 SW1.5 U82.13(P14) U83.6(A4)
SYS_BOOTMODE13: R150.1 SW1.6 U82.14(P15) U83.5(A3)
SYS_BOOTMODE14: R151.1 SW1.7 U82.15(P16) U83.4(A2)
SYS_BOOTMODE15: R152.1 SW1.8 U82.16(P17) U83.3(A1)
SYSBOOT_BUF_ENZ: R377.1 U23.1(A)
TAD1_ADDR1: R29.2 R37.2 U5.13(ADDR)
TAD1_DREG_OUT: C42.1 C45.1 U5.1(DREG)
TAD1_GPI1: R31.1 U5.12(GPI1)
TAD1_MICBIAS: C66.1 U5.14(MICBIAS)
TAD1_VREF: C38.1 U5.24(VREF)
TAD2_ADDR2: R33.2 R36.2 U77.13(ADDR)
TAD2_DREG_OUT: C356.1 C358.1 U77.1(DREG)
TAD2_GPI1: R429.1 U77.12(GPI1)
TAD2_MICBIAS: C370.1 U77.14(MICBIAS)
TAD2_VREF: C354.1 U77.24(VREF)
TAD3_ADDR3: R30.1 R35.1 U6.13(ADDR)
TAD3_DREG_OUT: C43.1 C46.1 U6.1(DREG)
TAD3_GPI3: R32.1 U6.12(GPI1)
TAD3_MICBIAS: C67.1 U6.14(MICBIAS)
TAD3_VREF: C35.1 U6.24(VREF)
TAD4_ADDR4: R27.1 R28.1 U76.13(ADDR)
TAD4_DREG_OUT: C355.1 C357.1 U76.1(DREG)
TAD4_GPI4: R430.1 U76.12(GPI1)
TAD4_MICBIAS: C369.1 U76.14(MICBIAS)
TAD4_VREF: C353.1 U76.24(VREF)
TAD5212_1_DIN: R5641.2 U5.5(DIN)
TAD5212_2_DIN: R5642.2 U77.5(DIN)
TAD5212_3_DIN: R5643.2 U6.5(DIN)
TAD5212_4_DIN: R5644.2 U76.5(DIN)
TAD5212_MCASP1_ACLKX: R418.2 R419.1 R5646.1 U5.2(BCLK) U6.2(BCLK) U76.2(BCLK) U77.2(BCLK)
TAD5212_MCASP1_AFSX: R422.2 R423.1 R5647.2 U5.3(FSYNC) U6.3(FSYNC) U76.3(FSYNC) U77.3(FSYNC)
TAD5212_MCASP1_AXR1: R5641.1 R5642.1 R5643.1 R5644.1 R5645.2
TCA6424_EXP_INT: R457.1 U82.32(I\N\T\)
TEST_GPIO1: Q7.1(G) R235.1 R526.2
TEST_GPIO2: R283.1 R285.2 U21.18(P21)
TEST_GPIO3: J10.1 R227.1 R439.1 R516.2 U23.2(B)
TEST_GPIO4: R221.1 R511.2 U82.28(R\E\S\E\T\)
TEST_PORZN: R219.1 R507.2 U43.6(C)
TEST_POWERDOWN: R233.1 R524.2 U54.1(A)
TEST_WARMRESETN: Q12.1(G) R224.1 R513.2
TM4C129_TCK: TP66.1(TP) U48.100(PC0/TCK/SWCLK)
TM4C129_TDI: TP64.1(TP) U48.98(PC2/TDI)
TM4C129_TDO: TP62.1(TP) U48.97(PC3/TDO/SWO)
TM4C129_TMS: TP63.1(TP) U48.99(PC1/TMS/SWDIO)
TMP411_ALERT: R5741.2 U2357.6(A\L\E\R\T\/T\H\E\R\M\2\)
TMP411_THERM: R5742.2 U2357.4(T\H\E\R\M\)
TPS65224_EN: Q4.2(S) R303.1 R317.1 TP81.1(TP)
UART2_FET_SEL: R5799.2 U21.13(P14) U2351.1(SEL1) U2351.5(SEL2)
UART2_RXD: J12.62 U2351.4(S2A)
UART2_RXD_FET: R5718.2 RA5.7 U2351.6(D2)
UART2_TXD: J12.60 U2351.2(S1A)
UART2_TXD_FET: U136.T4(SPI1_CS1) U2351.10(D1)
UART3_FET_SEL: R5800.2 U21.14(P15) U2352.1(SEL1) U2352.5(SEL2)
UART3_RXD: J13.62 U2352.4(S2A)
UART3_RXD_FET: U136.C6(MCU_GPIO0_13) U2352.6(D2)
UART3_TXD: J13.60 U2352.2(S1A)
UART3_TXD_FET: U136.N4(GPIO1_47) U2352.10(D1)
UART_SHIELD: J22.6(SH1) J22.7(SH2) J22.8(SH3) J22.9(SH4) R385.2
USB_TYPEC1_EARTH: C648.1 J24.SH1 J24.SH2 J24.SH3 J24.SH4 R404.1
USB_TYPEC2_EARTH: C651.1 J25.SH1 J25.SH2 J25.SH3 J25.SH4 R403.1
USBC_CONN1_CC1: C307.1 D7.1(CATHODE) J24.A5(CC1) U129.24(C1_CC1)
USBC_CONN1_CC2: C306.1 D17.1(CATHODE) J24.B5(CC2) U129.26(C1_CC2)
USBC_CONN2_CC1: C305.1 D8.1(CATHODE) J25.A5(CC1) U129.45(C2_CC1)
USBC_CONN2_CC2: C312.1 D16.1(CATHODE) J25.B5(CC2) U129.47(C2_CC2)
USBC_CONN2_DM: D9.3(IO2) J25.A7(D-_1) J25.B7(D-_2) L10.3(OUT1) R400.2
USBC_CONN2_DP: D9.2(IO1) J25.A6(D+_1) J25.B6(D+_2) L10.2(IN2) R399.2
VMAIN: C310.1 C3625.1 C3628.1 C3629.1 C3630.1 C3631.1 C3697.2 R395.1 R5636.1 R5740.1 TP104.1(TP) U73.1(VOUT) U134.8(VIN1) U134.12(VIN2) U3068.10(VSUP)
VMAIN_EN: LD14.1(CATHODE) R382.1 U71.4(Y)
VMAIN_PD: C302.1 C322.1 C323.1 C324.1 U73.6(VIN) U129.1(PP_HV2) U129.11(PP_HV1)
VMON1: C3750.2 R5773.1 R5774.2 U56.9(VMON1)
VPHY_3V3_FT4232: C606.2 FL17.1 U64.4(VPHY)
VPLL_3V3_FT4232: C607.2 FL18.1 R357.2 U64.9(VPLL)
VPP_1V8: C517.1 R304.2 TP69.1(TP) U136.G5(VPP)
VPP_EN: R319.1 U21.5(P04)
VPP_SUPPLY: C247.2 C251.2 R304.1 U59.1(OUT)
VSEL_SD_SOC: R5751.2 U3086.2(A)
WD_DISABLE: R281.2 R282.2 TP56.1(TP) U56.29(GPIO6)
WKUP_I2C0_SCL: C245.1 R284.1 R297.1 R301.2
WKUP_I2C0_SCL_RC: R284.2 U136.B9(WKUP_I2C0_SCL)
WKUP_I2C0_SDA: C248.1 R256.1 R259.2 R307.1
WKUP_I2C0_SDA_RC: R256.2 U136.A8(WKUP_I2C0_SDA)
WKUP_LFOSCO_XI: C216.2 R568.1 U136.E1(WKUP_LFOSC0_XI) Y4.1
WKUP_LFOSCO_XO: C213.2 R261.2 R568.2 Y4.2
WKUP_UART0_CTSN: R322.2 U117.9(2A2) U136.D6(WKUP_UART0_CTSN)
WKUP_UART0_RTSN: R593.2 U117.7(1A2) U136.C5(WKUP_UART0_RTSN)
WKUP_UART0_RXD: R326.2 U117.8(2A1) U136.B5(WKUP_UART0_RXD)
WKUP_UART0_TXD: R592.2 U117.6(1A1) U136.A5(WKUP_UART0_TXD)
XDS110_DIR: R555.2 U97.4(1DIR) U97.5(2DIR)
XDS110_EMU0: R237.2 U48.42(PF0) U102.7(B1)
XDS110_EMU1: R236.2 U48.43(PF1) U102.6(B2)
XDS110_TCK: U48.35(PA2/SSI0CLK) U97.14(1B2)
XDS110_TDI: U48.38(PA5/SSI0XDAT1) U97.15(1B1)
XDS110_TDO: U48.37(PA4/SSI0XDAT0) U109.7(B1)
XDS110_TMS: U48.36(PA3/SSI0FSS) U97.13(2B1)
XDS110_TRST#: U48.40(PA6) U97.12(2B2)
XDS_GPIO1: R235.2 U40.2(1Y)
XDS_GPIO2: R283.2 U51.2(A1)
XDS_GPIO3: R227.2 U40.4(2Y)
XDS_GPIO4: R221.2 U40.6(3Y)
XDS_PORZN: R219.2 U40.8(4Y)
XDS_POWERDOWN: R233.2 U40.12(6Y)
XDS_RSTN: R549.1 R556.1 TP51.1(TP) U48.70(R\S\T\)
XDS_SHIELD: C605.2 J17.6(SH1) J17.7(SH2) J17.8(SH3) J17.9(SH4) R610.2
XDS_USB_DM: J17.2(D-) U48.93(PL7/USB0DM)
XDS_USB_DP: J17.3(D+) U48.94(PL6/USB0DP)
XDS_USB_ID: J17.4(ID) R271.2 U60.2(IO2)
XDS_USB_VBUS: C244.1 C250.1 C267.1 D1.2 J17.1(VBUS) R295.1 R314.1 R576.1 TP78.1(TP) U55.1(IN1) U55.2(IN2) U60.6(VCC)
XDS_VREF: C190.1 C215.2 R241.2 U41.3(CATHODE) U48.9(VREFA+)
XDS_WARMRESETN: R224.2 U40.10(5Y)
ZENER_CLAMP: D2.3(C) R298.1 R308.1
N16856152: C270.1 U64.3(OSCO) Y6.2
N16856224: C269.1 U64.2(OSCI) Y6.1
N16857368: C283.2 U66.2(NR/FB)
N16878497: R562.1 TP116.1(TP) U49.H5(DS)
N16880083: R18.1 R21.2 U2.1(A)
N16956459: R121.2 R122.1 U27.1(A)
N16994873: R483.2 U88.4(Y)
N16994875: R476.2 U87.4(Y)
N16995245: C417.1 R487.2
N16997746: R218.1 U48.59(RBAIS)
N17030208: R544.2 U97.7(1A2)
N17031262: LD9.2(ANODE) R402.2
N17078974: J10.2 R438.2
N17269599: R363.1 R366.2 U68.6(C)
N17269609: R362.1 R364.2 R367.1 U68.1(A)
N17378539: LD7.1(CATHODE) R330.2
N17479799: R314.2 U55.8(EN)
N17479805: C243.2 R306.2 R313.1 U55.5(NR/FB)
N17479881: C203.2 R246.1 U48.68(VBAT)
N17481587: LD5.2(ANODE) R287.2
N17481598: C225.2 R576.2 U48.96(PB1/USB0VBUS)
N17481613: R271.1 U48.95(PB0/USB0ID)
N17481619: R289.1 R295.2 U48.1(PD0/AIN15)
N17481621: R232.2 R520.1 U48.60(PK7)
N17481627: R276.1 U48.3(PD2/AIN13)
N17481631: LD3.2(ANODE) R276.2
N17481633: R229.2 R523.1 U48.63(PK4)
N17481635: R231.2 R521.1 U48.61(PK6)
N17481637: R287.1 U48.4(PD3/AIN12)
N17481641: R230.2 R522.1 U48.62(PK5)
N17824845: R654.1 U129.36(SPI_MISO/GPIO8)
N17824852: R653.1 U129.37(SPI_MOSI/GPIO9)
N17824859: R652.1 U129.38(SPI_CLK/GPIO10)
N17824866: R651.1 U129.39(S\P\I\_\S\S\/GPIO11)
N19741013: R390.2 U129.18(GPIO2)
N19806973: R566.2 U110.7(1A2)
N21761137: R5750.1 U136.A7(PMIC_LPM_EN0)
N21784165: R548.1 U136.V11(MDIO0_MDC)
N21784176: R541.1 U136.U11(MDIO0_MDIO)
N22498870: R602.1 R605.2 U120.6(C)
N22498881: R601.1 R604.2 R606.1 U120.1(A)
N22682556: J21.1 R633.2
N22682559: J21.3 R627.2
N24306091: C3746.2 R293.1 U3076.5(QOD) U3076.6(OUT)
N24306103: Q4.1(G) R293.2
N24306157: D5.3(K) R308.2
N24306190: Q4.3(D) R298.2
N24307354: R5828.2 U56.4(FB_B1)
N24307356: R5829.2 U56.6(FB_B2)
N24478126: C70.1 U4.4(CT)
N24517110: R214.2 SW3.3
N24517112: R217.2 SW3.4
N24605604: C18.1 J2.5A
N24605606: C16.1 J2.2A
N24605709: R84.2 R90.1 U14.1(A)
N24605835: TP5.1(TP) U7.20(GPIO2)
N24605846: L3.2 U7.4(BSTSW)
N24605909: C333.1 J2.5B
N24606047: TP8.1(TP) U7.19(GPI1)
N24606049: TP9.1(TP) U7.17(GPI2)
N24606166: C331.1 J2.2B
N24847876: R421.1 U77.4(DOUT)
N24847884: C348.1 J3.5B
N24847886: C347.1 J3.2B
N24847888: C347.2 U77.21(OUT2P)
N24847892: C344.2 U77.19(OUT1M)
N24847894: C343.2 U77.22(OUT2M)
N24847910: C348.2 U77.20(OUT1P)
N24847912: TP113.1(TP) U77.11(GPO1)
N24847957: C367.1 U77.15(IN1P)
N24847963: C365.1 U77.16(IN1M)
N24847969: C362.1 U77.17(IN2P)
N24847975: C360.1 U77.18(IN2M)
N24847993: TP112.1(TP) U77.9(GPIO1)
N24847995: TP115.1(TP) U77.10(GPIO2)
N24848039: R24.1 U5.4(DOUT)
N24848041: C25.1 J3.5A
N24848043: C24.1 J3.2A
N24848045: C24.2 U5.21(OUT2P)
N24848047: C23.2 U5.19(OUT1M)
N24848049: C22.2 U5.22(OUT2M)
N24848518: C25.2 U5.20(OUT1P)
N24848523: TP18.1(TP) U5.11(GPO1)
N24848568: C61.1 U5.15(IN1P)
N24848574: C56.1 U5.16(IN1M)
N24848580: C50.1 U5.17(IN2P)
N24848586: C47.1 U5.18(IN2M)
N24848600: R24.2 TP12.1(TP)
N24848612: R421.2 TP109.1(TP)
N24848616: TP17.1(TP) U5.9(GPIO1)
N24848618: TP22.1(TP) U5.10(GPIO2)
N24851304: R420.1 U76.4(DOUT)
N24851306: R420.2 TP14.1(TP)
N24851312: C346.1 J4.5B
N24851314: C345.1 J4.2B
N24851316: C345.2 U76.21(OUT2P)
N24851320: C342.2 U76.19(OUT1M)
N24851322: C341.2 U76.22(OUT2M)
N24851338: C346.2 U76.20(OUT1P)
N24851340: TP111.1(TP) U76.11(GPO1)
N24851385: C366.1 U76.15(IN1P)
N24851391: C364.1 U76.16(IN1M)
N24851397: C361.1 U76.17(IN2P)
N24851403: C359.1 U76.18(IN2M)
N24851421: TP110.1(TP) U76.9(GPIO1)
N24851423: TP114.1(TP) U76.10(GPIO2)
N24851452: R25.1 U6.4(DOUT)
N24851454: R25.2 TP11.1(TP)
N24851456: C27.1 J4.5A
N24851458: C26.1 J4.2A
N24851460: C26.2 U6.21(OUT2P)
N24851462: C21.2 U6.19(OUT1M)
N24851464: C20.2 U6.22(OUT2M)
N24851486: C27.2 U6.20(OUT1P)
N24851488: TP20.1(TP) U6.11(GPO1)
N24851535: C62.1 U6.15(IN1P)
N24851541: C57.1 U6.16(IN1M)
N24851547: C51.1 U6.17(IN2P)
N24851553: C48.1 U6.18(IN2M)
N24851571: TP19.1(TP) U6.9(GPIO1)
N24851573: TP23.1(TP) U6.10(GPIO2)
N25521527: TP6.1(TP) U7.18(GPIO3)
N25809420: C610.1 J18.SH1 J18.SH2 J18.SH3 J18.SH4 R623.2
N25815350: C611.1 J19.SH1 J19.SH2 J19.SH3 J19.SH4 R624.2
N26271323: R386.2 U129.17(GPIO1)
N27107689: C308.1 U73.3(CT)
N27107697: R382.2 U73.5(EN/UVLO)
N27107782: R395.2 U73.2(QOD)
N27116765: R319.2 R320.1 U59.5(EN)
N27118410: R240.2 U46.3(EN)
N27118414: R255.2 R258.1 U46.4(FB)
N27132714: R137.1 SW2.13
N27132716: R136.1 SW2.14
N27132718: R135.1 SW2.15
N27132720: R134.1 SW2.16
N27132816: R131.1 SW1.11
N27132818: R130.1 SW1.12
N27132820: R129.1 SW1.13
N27132822: R128.1 SW1.14
N27132824: R133.1 SW1.9
N27132826: R132.1 SW1.10
N27132828: R127.1 SW1.15
N27132836: R126.1 SW1.16
N27133243: R141.1 SW2.9
N27133247: R140.1 SW2.10
N27133249: R139.1 SW2.11
N27133251: R138.1 SW2.12
N27148451: R125.2 U28.A5(INT#)
N27161108: D6.3(C) R398.2 R401.1
N27162147: C640.1 Q8.1(S1) Q8.2(S2) Q8.5(S3) Q8.6(S4) Q8.8(S5) Q9.1(S1) Q9.2(S2) Q9.5(S3) Q9.6(S4) Q9.8(S5) R680.1
N27162183: C317.2 C318.2 C638.2 C639.2 C640.2 Q8.3(G) Q9.3(G) R675.2 R676.2 R677.1 R680.2
N27162293: Q10.1(D1) Q10.2(D2) Q10.5(D3) Q10.6(D4) Q10.8(D5) R677.2
N27162479: Q10.3(G) R669.2 R672.1 R673.2
N27173972: Q1.3(G) R203.2 R213.2
N27173989: Q5.3(G) R441.2 R442.2
N27174010: LD10.1(CATHODE) Q5.1(D1) Q5.2(D2) Q5.5(D3) Q5.6(D4) Q5.8(D5)
N27174034: LD1.1(CATHODE) Q1.1(D1) Q1.2(D2) Q1.5(D3) Q1.6(D4) Q1.8(D5)
N27174097: LD1.2(ANODE) R180.1
N27174144: LD10.2(ANODE) R440.1
N27175817: C104.2 R74.2 Y1.1
N27175821: C105.1 R73.2 Y1.3
N27175987: C121.1 C382.1 C383.1 C384.1 C385.1 C386.1 C387.1 R97.1 U15.3(VDD_REF) U15.15(VDDO_34) U15.16(VDDO_12) U15.24(VDD_VCO)
N27176057: TP36.1(TP) U15.7(OUT0)
N27176072: R89.2 U15.22(OUT1_P)
N27176107: TP39.1(TP) U15.21(OUT1_N)
N27176638: TP37.1(TP) U15.11(GPIO4)
N27176640: TP38.1(TP) U15.20(GPIO1)
N27224404: R432.2 R433.2 R435.2 U8.29(SDOUT)
N27224468: C337.1 J1.5B
N27224561: L2.2 U8.4(BSTSW)
N27224667: C335.1 J1.2B
N27224751: TP27.1(TP) U8.18(GPIO3)
N27224753: TP31.1(TP) U8.20(GPIO2)
N27224897: C14.1 J1.5A
N27225024: C77.1 C78.1 U8.32(DREG)
N27225078: C12.1 J1.2A
N27225127: TP26.1(TP) U8.19(GPI1)
N27225129: TP25.1(TP) U8.17(GPI2)
N27225150: R46.2 U8.28(GPIO1)
N27226002: R413.1 R414.2 U75.1(A)
N27239473: R591.2 U117.5(2DIR)
N27239479: R590.1 U117.4(1DIR)
N27239926: R635.2 U126.5(2DIR)
N27239932: R636.1 U126.4(1DIR)
N27240077: R613.2 U125.5(2DIR)
N27240083: R614.1 U125.4(1DIR)
N27243596: TP61.1(TP) U51.3(A2)
N27243598: TP58.1(TP) U51.6(B2)
N27248134: R579.2 U107.2(SCLA)
N27248136: R580.2 U107.3(SDAA)
N27566274: LD2.1(CATHODE) Q2.3(COLLECTOR)
N27566278: LD2.2(ANODE) R260.1
N27566306: Q2.1(BASE) R272.2
N27566380: LD4.2(ANODE) R292.1
N27566388: LD4.1(CATHODE) Q3.3(D)
N27566452: C613.2 D13.2 SW7.2
N27765807: C3639.1 R3661.2
N27766023: R5805.1 U134.13(RBOOT)
N27780868: R3723.2 R3724.1 U135.2(FB)
N27781327: R3725.2 U135.4(EN)
N27827107: TP594.1(TP) U136.A12(RSVD_A12)
N27866324: LD6.2(ANODE) R324.1
N27969798: R329.1 U62.1(OE/NC)
N27969912: R348.1 U65.2(1G)
N27970038: R349.1 U65.3(Y0)
N27970040: R358.1 U65.5(Y2)
N27970042: R359.1 U65.8(Y1)
N27972730: R261.1 U136.D2(WKUP_LFOSC0_XO)
N27975044: C205.2 R252.1 Y3.1
N27975050: C209.2 R253.1 Y3.3
N27975317: C3657.2 R3733.2 Y8.1
N27975321: C3658.1 R3732.2 Y8.3
N27995683: R5752.2 U140.C3(RWDS)
N28011359: R5758.2 R5759.1 SW9.2 U57.9(SEL1) U57.10(SEL2)
N28038972: R5213.1 U2.6(C)
N28044811: C1.1 J34.1 R5635.2 R5636.2
N28049053: R69.2 U11.6(OE)
N28061850: R178.2 U136.N19(MCASP0_ACLKX)
N28066355: R5672.1 U136.G18(MCASP3_AXR0)
N28066391: R5673.1 U136.H16(MCASP3_AXR1)
N28066418: R5674.1 U136.H18(MCASP3_AXR2)
N28066445: R5675.1 U136.H17(MCASP3_AXR3)
N28066472: R5676.1 U136.G19(MCASP3_AFSX)
N28066500: R5677.2 U136.E19(MCASP3_ACLKX)
N28071414: R5684.1 U2345.10(OE)
N28080788: R143.1 U29.4(O\E\)
N28081065: R5686.2 U2347.7(COM)
N28082506: TP586.1(TP) U136.B11(WKUP_CLKOUT0)
N28084397: R530.1 U136.U13(RGMII1_TD0)
N28084399: R535.1 U136.W13(RGMII1_TD1)
N28084409: R537.1 U136.T14(RGMII1_TD2)
N28084411: R529.1 U136.U14(RGMII1_TD3)
N28084427: R509.1 U136.V16(RGMII2_TD0)
N28084429: R518.1 U136.W16(RGMII2_TD1)
N28084431: R527.1 U136.V17(RGMII2_TD2)
N28084433: R528.1 U136.W18(RGMII2_TD3)
N28084995: R5687.1 U120.3(B)
N28086994: R5688.1 U68.3(B)
N28087268: R538.1 U136.V1(AUDIO_EXT_REFCLK0)
N28088261: R5694.2 U136.A14(OSPI1_CLK)
N28088302: R5695.2 U136.B13(OSPI1_LBCLKO)
N28088339: R5696.2 U136.B12(OSPI1_CSN0)
N28088462: R5697.2 R5699.1 U2348.1(A)
N28118724: R5730.2 U48.33(PA0/U0RX)
N28118727: R5731.2 U48.34(PA1/U0TX)
N28118756: R5732.1 U136.L1(UART0_TXD)
N28122339: R542.2 U136.A11(TDO)
N28129103: R5736.1 U2356.4(S2A) U2356.9(S1B)
N28133286: R5743.1 U2357.2(D+)
N28133288: R5743.2 U2357.3(D-)
N28157125: LD13.2(ANODE) R3933.2
N28224119: R297.2 U56.36(GPIO2)
N28224122: R307.2 U56.35(GPIO1)
N28224348: R5751.1 U136.B7(WKUP_TIMER_IO0)
N28238385: R166.2 U3077.8(OE)
N28248996: R5637.2 TP593.1(TP)
N28268314: R5757.1 U136.C16(OSPI0_CSN1)
N28271262: R115.2 R116.2 U26.1(A)
N28389021: R5766.1 U54.4(Y) U3076.3(ON)
N28496978: J12.1 R5775.2
N28497016: J13.1 R5776.2
N28557174: C615.2 R632.1 R634.2 U127.3(FB)
N28557887: R5777.2 U127.1(EN)
N28895418: R5790.2 U3084.2(1G)
N28895646: R5791.1 U3084.3(Y0)
N28895649: R5792.1 U3084.8(Y1)
N28896188: R5789.1 U3083.4(O\E\)
N28896306: R5793.2 U3083.7(B1)
N28962728: R5806.1 U3086.4(Y) U3087.2(A)
N29136309: R5808.1 U2353.5(2DIR)
N29136335: R5733.1 U2353.4(1DIR)
N29218455: R5734.1 U2353.6(1A1)
N29295413: R5826.1 U28.C2(CS#)
N29295438: R5827.1 U28.A3(DNU2)
N271759124: TP32.1(TP) U15.5(PRIREF_P)
N271759125: TP33.1(TP) U15.6(PRIREF_N)
N275664200: Q3.1(G) R286.2
N280409620: R3736.1 SW9.1
N284070661: LD14.2(ANODE) R195.2

Pads without a net: D2 2; D6 2; J12 13 14 48 52 54 56 59 61 63 64 68 70 72 74; J13 5 13 14 38 40 48 52 54 56 59 61 63 64 68 70 72 74; J14 17 18 19; J21 4 6; J22 4; J24 A2 A3 A6 A7 A8 A10 A11 B2 B3 B6 B7 B8 B10 B11; J25 A2 A3 A8 A10 A11 B2 B3 B8 B10 B11; J31 10; U10 4 9; U12 2 3; U15 9 10 13 14 17 18; U18 1 2 5 7 8 13 14 15 16 17; U21 1 2 3 6 7 8 11 20; U25 5; U28 A2 B1 B5 C5; U41 2 4 5; U48 2 5 6 11 12 13 14 15 18 19 20 21 22 23 24 25 27 29 30 31 32 41 44 45 46 53 54 56 57 65 67 75 83 84 85 86 91 92 102 103 104 105 106 107 108 109 110 111 112 116 117 118 119 120 121 123 124 125 126 127 128; U49 A1 A2 A7 A8 A9 A10 A11 A12 A13 A14 B1 B7 B8 B9 B10 B11 B12 B13 B14 C1 C3 C5 C7 C8 C9 C10 C11 C12 C13 C14 D1 D2 D3 D4 D12 D13 D14 E1 E2 E3 E5 E8 E9 E10 E12 E13 E14 F1 F2 F3 F10 F12 F13 F14 G1 G2 G3 G10 G12 G13 G14 H1 H2 H3 H12 H13 H14 J1 J2 J3 J12 J13 J14 K1 K2 K3 K6 K7 K10 K12 K13 K14 L1 L2 L3 L12 L13 L14 M1 M2 M3 M7 M8 M9 M10 M11 M12 M13 M14 N1 N3 N6 N7 N8 N9 N10 N11 N12 N13 N14 P1 P2 P7 P8 P9 P10 P11 P12 P13 P14; U55 7; U57 15 16 18 19 20 21 25 27 32 34; U59 2 3 6 7; U60 1 4 5; U61 6 7; U64 18 19 21 22 23 24 28 29 30 32 33 34 36 43 44 45 46 48 52 53 54 55 57 58 59; U65 7; U66 5; U67 2; U82 17 18 19 20 21 22 23 24; U92 B2 C2; U93 1; U113 B2 C2; U115 B2 C2; U119 B2 C2; U123 B2 C2; U129 21 22 23 30 31 40 41 42 43 48 50 53 54 55; U136 A3 A18 B3 E2 E4 G3 W8; U140 A2 A5 B5 C2 C5; U2355 1; U2358 1; U3068 11; U3070 1; U3072 3 5 7 10 12 14 16 20 21 22 23 24 25 26 27 28 29 30 31 32 33 34 35 36 55 56; U3076 4; U3077 6 9; U3080 B2 C2; U3081 B2 C2; U3084 5 7

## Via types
v1: diameter 0.457, hole 0.203, TOP to BOTTOM, 2888 vias

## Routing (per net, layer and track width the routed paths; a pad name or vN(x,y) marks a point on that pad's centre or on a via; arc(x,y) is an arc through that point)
AVDD_3V3_DAC: length 82.3
  TOP w0.254: U5.23 84.42,156.27 ; U6.23 101.82,155.83 101.35,156.3 100.15,156.3
  TOP w0.305: v1(90.37,149.1) 90.54,149.28 R33.1 ; 84.42,156.27 83.15,157.54 C29.1 81.82,157.54 C32.1 v1(81.81,158.44) ; v1(113.17,159) 109.01,154.84 109.01,151.66 109.24,151.43 R28.2 109.24,149.68 v1(108.8,149.24) 108.8,149.38 108.53,149.66 R35.2 ; FL1.2 98.69,159.26 C31.1 98.92,157.51 C30.1 99.65,156.79 100.15,156.3 ; R29.1 89.09,150.12 89.28,149.93 R33.1 ; v1(98.49,160.17) 98.09,160.57 98.09,161.47 97.45,162.1 92.83,162.1 89.73,159 89.73,151.56 90.54,150.75 R33.1
  L03_SIG1 w0.381: v1(90.37,149.1) 91.13,149.86 92.02,149.86 93.13,150.98 99.01,150.98 99.53,151.5 101.51,151.5 103.17,149.83 108.21,149.83 v1(108.8,149.24)
  BOTTOM w0.254: v1(98.49,160.17) 98.03,160.17 97.55,159.69 97.55,158.78 97.12,158.34 95.76,158.34 95.27,157.85 95.27,157.12 C350.1 95.08,157.12 94.49,156.52 C352.1 94.2,156.52 94.2,156.07 93.94,155.81 U77.23 ; U76.23 111.34,156.6 111.67,156.93 C351.1 C349.1 112.88,158.71 v1(113.17,159)
  vias: v1(99.28,160.15) v1(99.48,159.45)
DGND: length 1426
  TOP w0.091: U3087.3 61.04,54.54 C3774.1 ; U71.3 34.28,35.29 v1(33.85,34.86) ; v1(110.15,70.48) 109.85,70.79 109.8,70.79 109.71,70.88 109.71,71.3 U49.N2
  TOP w0.132: v1(70.35,76.68) 70.35,76.34 70.06,76.05 ; U136.W6 v1(82.64,81.26) ; 68.74,76.58 68.89,76.73 68.89,77.66 U136.B2 68.1,78.45 66.84,78.45 65.32,76.94
  TOP w0.147: C21.1 105.49,160.64 104.77,161.37 104.77,163.5 106.9,165.63 110.89,165.63 v1(112.23,164.3) ; v1(94.6,164.58) 93.67,165.51 89.71,165.51 87.52,163.32 87.52,161.32 88.13,160.71 C23.1 ; v1(77.44,164.24) 76.95,164.24 76.66,163.94 76.66,158.92 76.1,158.37 73.88,158.37 73.44,158.81 73.44,159.47 72.17,160.74 C17.1 ; v1(50.12,165.16) 48.99,164.03 48.99,160.27 50.69,158.57 52.04,158.57 52.34,158.88 52.34,159.31 51.14,160.51 C11.1 ; C22.1 83.2,160.56 83.84,161.2 83.84,163.52 v1(82.99,164.38) ; v1(100.38,164.4) 100.89,164.4 101.08,164.21 101.08,161.24 100.66,160.82 C20.1 ; C13.1 54.98,160.71 56.38,159.31 56.38,158.8 56.94,158.24 58.95,158.24 59.81,159.11 59.81,163.86 v1(60.32,164.36) ; C15.1 68.28,160.53 69.51,159.31 69.51,158.88 69.2,158.57 68.25,158.57 66.23,160.59 66.23,164.12 v1(67.27,165.16)
  TOP w0.152: v1(77.54,46.96) 77.54,47.57 77.24,47.86 ; v1(77.54,46.96) 77.24,46.66 ; v1(77.54,46.96) 77.44,47.06 U2353.11 76.41,47.06 76.16,47.31 76.32,47.46 U2353.10 ; v1(77.54,46.96) 77.84,46.66 U2353.1 ; U2353.9 77.24,47.86 ; 77.24,47.86 77.39,48.01 77.39,48.45 U2353.7 ; v1(103.51,73.93) 103.89,73.55 U49.A6 ; U2353.14 77.37,46.53 77.24,46.66 ; v1(84.92,44.78) 84.61,45.09 C272.2 ; C223.1 27.5,83.26 27.03,82.79 v1(25.56,82.79) 25.2,82.79 24.81,83.18 24.81,85.52 25.37,86.08 27.56,86.08 27.81,85.83 C217.1 ; 77.24,46.66 U2353.12 ; v1(23.65,80.96) 23.65,80.76 23.39,80.5 U51.4 ; R254.1 63.06,74.65 66.39,74.65 68.32,76.58 68.74,76.58 ; 69.74,73.39 69.74,74.24 69.97,74.48 69.97,75.96 70.06,76.05 ; U2353.16 78.17,46 78.33,45.85 v1(78.68,45.85)
  TOP w0.178: U39.4 30.11,103.91 30.27,104.06 30.27,104.32 30.07,104.52 v1(29.86,104.52) ; 65.32,76.94 v1(63.64,76.94) ; Y3.4 60.5,76.47 60.76,76.22 C205.1 61.33,76.22 61.81,75.74 66.18,75.74 U136.A1
  TOP w0.203: U3083.3 107.04,56.91 v1(107.21,56.74) ; J18.5 84.01,38.84 v1(84.1,38.75) 83.51,38.75 83.21,39.05 J18.1 ; U3083.6 107.04,59.22 v1(107.33,59.51) 107.44,59.41 U3083.5 ; U49.P4 111.02,72.55 111.04,72.57 v1(111.12,72.57) ; U48.55 34.73,96.51 v1(34.87,96.65) ; J19.16 118.44,41.71 118.84,41.31 v1(119.04,41.31) 119.04,41.68 118.84,41.88 J19.18 ; v1(111.27,73.99) 110.9,73.99 U49.P6 U49.N5 ; J18.8 84.41,42.69 84.42,42.7 84.42,43.02 v1(84.65,43.25) ; U48.48 37.53,96.63 v1(37.48,96.69) ; J18.21 87.22,39.63 v1(87.22,40.46) ; J19.41 123.64,40.19 v1(123.31,40.51) ; J19.8 116.84,41.79 116.82,41.77 116.82,41.75 v1(116.55,41.48) ; J13.8 16.06,119.64 15.67,120.04 C168.2 ; U48.17 v1(46.22,87.81) ; U68.2 69.11,50.37 68.96,50.51 R367.2 68.08,50.51 v1(68.04,50.47) ; U48.58 33.53,94.33 ; J19.21 v1(119.64,38) ; U49.K8 108.24,74.55 107.96,74.27 v1(107.96,73.8) U49.J5 ; J18.31 89.21,38.93 v1(89.4,38.74) 89.61,38.94 J18.33 ; U29.5 101.36,57.95 101.03,57.63 v1(100.83,57.63) ; v1(90.97,38.16) 91.21,38.39 J18.41 ; v1(92.19,55.85) 91.91,56.14 U15.A3 ; C55.2 66.19,153.76 66.37,153.94 v1(66.37,153.96) ; v1(115.78,40.66) 116.14,40.66 116.44,40.37 J19.5 ; U48.64 31.13,96.01 30.93,96.22 v1(30.55,96.22) ; J19.15 118.44,38.92 v1(118.59,38.77) 118.84,39.02 J19.17 ; v1(106.6,74.27) 106.38,74.05 U49.E7 ; v1(28.26,87.88) 28.59,87.88 28.67,87.81 U48.80 ; U5.A1 83.12,155.12 82.91,155.12 v1(82.9,155.13) ; J18.34 89.61,41.74 v1(89.4,41.53) 89.21,41.72 J18.32 ; U6.A2 v1(100.42,150.92) ; U136.A1 67.52,77.25 67.3,77.47 v1(67.28,77.47) ; U6.A1 100.66,154.8 100.46,155 v1(100.46,155.18) ; v1(107.31,72.54) 106.96,72.89 U49.G5 ; U40.7 13.14,91.56 v1(12.82,91.88) ; v1(87.1,155.52) 86.89,155.32 U5.A4 ; J18.15 86.01,40.17 86.12,40.28 v1(86.2,40.28) 86.41,40.08 J18.17 ; U5.A3 v1(87.33,150.91) ; J19.1 115.64,39.02 115.63,39.02 v1(115.63,38.6) ; D8.2 v1(47.86,10.71) ; U48.10 v1(43.85,85.01) ; J18.18 86.41,43.01 v1(86.16,43.25) 86.01,43.1 J18.16 ; J19.33 122.04,38.94 v1(121.83,38.74) 121.64,38.93 J19.31 ; D9.1 v1(49.39,10.33) ; v1(34,9.98) 33.87,9.98 33.67,10.19 D7.2 ; v1(38.04,81.15) 38.04,81.13 37.93,81.02 U48.114 ; C3750.1 34.92,53.2 34.3,52.58 R5773.2 32.96,52.58 32.76,52.37 v1(32.76,52.2) ; J19.24 v1(120.04,41.59) ; J19.32 121.64,41.71 v1(121.77,41.58) 122.04,41.84 J19.34 ; U6.A3 v1(104.73,150.91) ; U6.A4 104.29,155.32 v1(104.47,155.5) ; U54.2 v1(19.35,60.73) ; U49.H10 107.46,75.36 v1(107.21,75.11) ; C203.1 28.14,93.96 v1(28.43,93.67) 28.43,93.63 28.65,93.41 U48.66 ; U49.C4 104.96,72.56 v1(105.43,73.03) ; J18.24 v1(87.61,41.48) ; U5.A2 v1(83.02,150.92)
  TOP w0.229: v1(127.22,69.38) 127.38,69.23 U2.2
  TOP w0.254: C89.2 v1(63.07,145.71) ; v1(65.3,134.09) 65.05,133.84 U18.9 ; 62.97,25.51 U64.11 ; J12.81 v1(127.17,147.73) J12.82 v1(127.17,141.78) J12.83 J12.84 v1(127.17,131.54) J12.85 v1(127.17,127.73) J12.86 v1(127.17,121.76) J12.87 v1(127.17,115.46) J12.88 v1(127.17,111.48) ; v1(69.92,108.69) 69.22,107.99 U28.C1 ; C172.2 C168.2 ; U64.35 64.47,38.93 ; v1(58.74,88.19) 59.79,87.14 C245.2 ; U7.8 67.71,147.8 v1(67.49,148.02) ; U66.3 58.32,11.19 58.12,11.39 C283.1 57.86,11.71 v1(57.49,11.33) ; v1(63.42,67.84) 63.13,68.13 63.13,69.69 63.42,69.98 63.79,69.98 64.84,71.02 Y8.2 65.13,71.96 65.37,72.2 C3658.2 ; U10.5 v1(127.6,74.66) ; v1(46.39,7.18) J25.A1 v1(46.39,8.7) ; v1(62.48,60.1) 62.32,60.1 62.28,60.05 U59.4 ; U64.15 64.97,27.54 ; v1(112.62,93.8) 112.62,93.14 112.45,92.98 R5822.2 ; C97.1 v1(63.07,143.06) ; C182.1 77.64,66.65 77.41,66.88 v1(77.41,67.28) ; U64.25 v1(66.21,32.35) ; v1(42.28,115.04) 42.61,114.71 C415.1 ; v1(69.15,75.59) 67.43,73.87 67.43,73.53 ; U64.13 63.97,25.35 ; 52.04,150.02 U8.8 52.04,151.27 ; v1(37.39,8.7) J24.A12 v1(37.39,7.18) ; v1(98.42,91.48) 98.42,91.32 98.2,91.09 U43.2 ; U140.B3 55.51,97.61 v1(55,98.12) ; C3659.2 v1(94.73,85.14) ; U64.1 v1(57.97,27.53) ; v1(47.54,78.16) 47.54,77.9 47.27,77.63 R289.2 ; v1(107.21,56.74) 107.12,56.65 107.12,55.45 107.27,55.3 R5789.2 ; C3746.1 21.38,68.1 21.86,67.61 21.86,66.17 21.61,65.91 v1(20.9,65.91) 20.5,65.52 U3076.2 20.5,64.25 20.41,64.16 C3747.2 20.41,63.39 20.68,63.12 R5766.2 ; R5821.1 68.4,129.36 68.89,128.86 U27.3 ; U3068.2 40.74,158 41.25,157.49 ; U21.25 99.68,136.48 ; U64.51 v1(54.81,34.85) ; R5733.2 80.21,48.24 v1(80.21,48.23) 79.85,47.88 C3721.1 ; v1(58.31,152.06) 57.87,152.5 C63.2 C68.2 ; v1(123.94,65.24) 123.94,65.79 124.58,66.42 R5823.1 ; v1(31.39,7.18) J24.A1 v1(31.39,8.7) ; U11.2 109.16,146.11 109.1,146.17 C101.2 108.23,146.17 108.04,146.35 v1(107.87,146.35) ; v1(61.92,77.85) 59.05,77.85 57.96,76.75 v1(57.96,74.9) ; v1(29.12,62.67) 28.41,61.96 28.41,61.95 TP106.1 ; v1(83.23,78.82) 82.82,78.82 82.78,78.86 U136.W3 ; v1(18.92,48.89) 18.62,49.19 U60.3 ; J25.A12 v1(52.39,7.18) ; U64.5 v1(59.97,25.25) ; U64.10 62.47,25.47 ; U64.47 58.47,38.86
  TOP w0.279: v1(92.25,82.45) 92.32,82.52 R5216.1 ; v1(98.26,82.63) 98.45,82.81 C787.2
  TOP w0.305: U136.U5 v1(80.9,80.06) U136.U4 ; J14.16 v1(38.18,104) ; J12.50 v1(131.49,125.98) ; U55.9 28.63,73.58 28.6,73.58 28.31,73.28 U55.6 ; C270.2 60.03,24 60.28,24.26 60.28,24.94 v1(59.97,25.25) ; SW6.4 SW6.1 v1(57.88,121.05) ; v1(40.02,46.03) v1(40.02,46.94) 39.82,47.14 ; v1(40.02,46.03) 39.82,46.23 39.82,46.25 ; v1(40.02,46.03) v1(39.59,46.03) ; v1(39.82,56.36) v1(39.82,56.79) U56.32 v1(39.82,60.59) v1(39.82,61.02) v1(39.82,61.46) v1(39.82,61.89) 39.82,62.23 ; v1(39.82,56.36) v1(39.82,55.93) U56.14 v1(39.82,51.88) v1(39.82,51.45) v1(39.82,51.02) v1(39.82,50.58) v1(39.82,48.7) v1(39.82,47.85) 39.82,47.17 ; v1(39.82,56.36) v1(39.39,56.36) v1(38.73,56.36) ; v1(39.82,56.36) v1(40.25,56.36) v1(40.91,56.36) ; v1(54.81,34.85) C263.2 ; U46.2 49.77,82.61 49.49,82.89 v1(49.39,82.89) 49.65,83.16 C197.2 ; SW7.4 v1(50.54,43.29) ; 39.82,47.14 39.82,46.25 ; 39.82,47.14 39.82,47.17 ; 39.82,46.25 v1(39.59,46.03) ; J12.25 v1(126.05,139.58) ; C323.2 44.94,12.8 v1(44.29,12.14) ; C61.2 v1(89.18,152.93) C56.2 ; R217.1 v1(46.88,102.29) ; v1(46.39,7.18) 46.39,6.29 J25.B12 ; v1(73.7,87.25) U136.J13 v1(74.5,87.25) ; J13.57 24.58,143.64 v1(24.81,143.87) ; v1(75.3,85.65) U136.K12 v1(74.5,85.65) ; v1(47.34,59.35) 46.83,59.35 C242.2 46.83,58.71 v1(47.34,58.71) ; C149.1 70.07,108.53 v1(69.92,108.69) ; J13.88 J13.87 v1(20.16,144.89) J13.86 v1(20.16,138.85) J13.85 ; U136.G4 v1(72.1,79.26) U136.F4 ; U69.4 v1(36.87,25.41) ; C275.1 59.48,39.63 59.48,39.62 v1(59.45,39.62) ; U136.G6 v1(72.1,80.86) ; 39.82,62.23 40.08,62.49 44.56,62.49 C228.2 ; 39.82,62.23 39.56,62.49 35.08,62.49 C227.2 ; v1(55.97,143.21) 56.21,143.44 R61.2 ; U136.N6 v1(77.7,80.86) U136.P6 ; v1(79.3,88.05) U136.R14 v1(78.5,87.25) ; R37.1 v1(89.05,149.08) ; v1(60.22,53.03) 60.87,53.67 C3774.1 ; U136.E18 70.9,90.85 v1(70.5,90.45) ; 52.04,151.27 51.76,151.55 51.76,151.87 C65.2 v1(51.24,151.87) ; C3744.2 132.91,66.03 133.27,65.67 C3745.1 132.8,65.33 v1(132.43,65.71) ; v1(37.56,22.88) 37.22,22.53 C306.2 ; U136.G8 v1(72.1,83.26) U136.G9 ; C92.1 68.24,145.06 68.44,144.86 v1(68.44,144.61) ; LD5.1 40.75,76.83 40.27,76.83 40.02,76.58 v1(39.9,76.58) ; C3704.1 97.32,53.8 97.01,53.49 v1(96.89,53.49) ; v1(20.16,114.53) J13.81 v1(20.16,118.75) J13.82 J13.83 J13.84 ; U136.N13 v1(76.9,86.45) U136.M12 ; C326.2 36.86,9.46 v1(37,9.6) ; U136.T10 v1(79.3,84.85) ; U2348.3 55.74,111.15 R5760.1 v1(55.71,112.19) ; U136.N5 v1(76.9,80.06) ; v1(56.1,83.72) 55.98,83.6 C248.2 ; v1(24.71,50.98) 24.72,51 U2356.3 ; v1(77.7,82.46) U136.N7 v1(77.7,81.66) ; R303.2 21.41,57.44 v1(21.28,57.3) ; v1(52.25,5.45) 52.44,5.65 J25.B1 ; C235.1 v1(22.12,76.83) ; C305.2 v1(42.54,22.88) ; v1(97.58,156.97) 97.83,156.72 C35.2 98.2,156.17 98.2,156.17 C43.2 98.64,155.55 98.83,155.74 v1(99.24,155.74) 99.35,155.62 C46.2 ; v1(68.42,47.83) 68.67,47.83 68.9,48.06 68.9,48.52 69.18,48.8 R373.2 ; v1(26.61,81.64) 26.84,81.41 27.36,81.41 C225.1 ; v1(127.6,74.66) 127.6,74.37 127.91,74.07 R202.2 ; v1(87.16,59.82) 87.34,59.64 U15.A1 ; U136.D1 70.1,76.94 v1(70.35,76.68) ; v1(39.59,46.03) v1(39.59,46.94) 39.82,47.17 ; C3773.2 v1(61.12,51.26) ; C264.1 v1(53.5,33.33) ; C69.2 v1(120.84,71.93) ; C324.2 v1(37.96,11.91) ; R341.1 v1(121.79,47.64) ; J12.57 122.68,122.78 122.39,123.06 v1(122.39,123.47) ; C76.2 98.33,149.97 98.52,149.78 v1(99.33,149.78) 99.33,150.24 99.48,150.39 C73.2 ; R278.1 v1(23.65,80.96) ; TP41.1 66.85,130.23 66.41,129.79 v1(66.41,129.23) 66.35,129.29 C3741.1 65.09,129.29 65.03,129.23 D18.1 ; U136.F15 v1(72.1,88.85) ; v1(36.59,77.72) 36.83,77.96 C232.2 ; v1(68.7,9.51) C295.2 68.7,7.57 68.28,7.16 67.9,7.16 67.45,6.71 J22.5 ; v1(100.27,59.94) 100.07,60.15 R143.2 ; C233.2 39.13,78.29 v1(39.51,77.9) 39.31,77.7 C240.2 ; v1(87.33,150.91) 87.78,150.45 R31.2 ; v1(34.6,100.74) 34.59,100.75 R218.2 ; v1(73.93,136.11) 73.93,136.72 C109.2 ; U136.C3 v1(68.9,78.46) U136.B2 ; R560.2 81.02,69.62 v1(80.84,69.44) ; v1(67.64,142.86) 68.11,143.34 C96.2 ; v1(103.9,57) 103.73,57.17 C151.1 ; C3769.1 v1(104.46,56.44) ; Q5.7 Q5.4 R442.1 v1(68.95,131.55) ; U136.E14 v1(71.3,88.05) U136.F14 ; v1(106.04,151) 106.04,150.98 106.23,150.78 R30.2 ; C60.1 51.12,152.76 v1(51.1,152.77) ; C223.1 v1(28.34,83.26) ; C249.2 31.69,55.69 v1(31.56,55.82) ; C322.2 43.42,12.53 v1(43.1,12.21) 43.05,12.16 42.17,12.16 41.89,12.44 C325.2 ; J13.35 v1(21.4,130.84) ; v1(64.45,40.35) C281.1 64.45,38.95 64.47,38.93 ; v1(49.12,108.92) 49.66,109.46 U25.4 ; R85.2 v1(88.21,62.97) ; C172.2 C171.2 ; C171.2 v1(14.66,119.6) C167.2 C168.2 ; C171.2 C170.2 v1(13.9,119.6) ; v1(46.98,86.16) 46.7,85.87 C215.1 ; R27.2 107.36,150.77 107.05,150.46 v1(106.94,150.46) ; v1(70.25,36.53) 70.05,36.33 C289.1 ; U136.D14 v1(69.7,88.05) ; R381.2 34.33,32.75 v1(34.54,32.54) 34.59,32.59 35.12,32.59 35.3,32.77 R5767.2 ; Y3.2 58.18,75.13 v1(57.96,74.9) ; U136.F10 v1(71.3,84.85) ; v1(71.3,84.85) U136.E11 ; v1(71.3,84.85) U136.F11 ; v1(71.3,84.85) U136.E10 ; v1(39.41,12.5) 39.41,12.93 39.48,13 C319.1 ; v1(94.12,58.47) 94.12,57.89 C121.2 ; v1(68.39,138.63) R94.2 69.49,137.9 69.97,138.38 TP44.1 ; v1(104.73,150.91) 105.18,150.45 R32.2 105.18,149.28 v1(105.37,149.08) ; J13.65 v1(24.76,146.84) ; SW8.1 99.82,98.42 v1(99.79,98.39) ; C38.2 80.21,156.5 v1(79.89,156.18) ; U136.G15 v1(72.1,88.05) ; v1(79.8,155.31) 80.05,155.55 C42.2 81.65,155.55 81.95,155.24 C45.2 v1(82.9,155.13) ; v1(56.67,152.31) 56.46,152.11 C64.2 ; U4.2 123.22,66.54 C33.1 123.26,65.25 C28.2 v1(123.94,65.24) ; v1(26.71,102.03) 26.91,102.22 C3730.1 ; C32.2 v1(79.89,157.55) ; v1(61.71,42.29) 61.33,41.91 R5799.1 ; v1(31.18,99.39) 31.19,99.39 R230.1 ; U136.L7 v1(75.3,81.66) ; J13.46 15.35,138.84 v1(15.11,139.09) ; U136.U10 v1(80.9,84.85) ; v1(106.72,151.28) 106.72,151.37 106.44,151.66 C67.2 C62.2 v1(106.58,152.93) C57.2 ; v1(115.33,61.37) 115.18,61.52 C3772.1 C3771.1 ; 63.97,25.35 v1(64.1,25.22) 64.29,25.03 C280.1 ; C300.1 33.02,35.29 v1(32.76,35.03) ; v1(89.65,46.34) 89.46,46.15 R355.1 ; C147.2 53.47,102.7 v1(53.28,102.51) ; Y5.4 v1(25.56,82.79) ; v1(66.62,44.5) 66.81,44.31 U2352.3 ; v1(79.3,87.25) U136.R13 U136.R12 ; C31.2 v1(97.08,157.74) ; U136.P5 v1(77.7,80.06) ; SW10.4 58.98,128.78 58.74,128.55 v1(58.74,128.12) 58.74,126.72 58.98,126.49 SW10.1 ; D12.1 60.09,114.1 59.61,114.58 v1(59.07,114.58) 58.49,114.58 C609.1 ; J24.B1 v1(37.44,5.48) ; v1(34.99,50.47) 34.99,49.67 C257.2 ; U136.V18 v1(81.7,90.46) ; v1(121.07,76.93) 120.87,77.13 U12.4 ; U136.F16 v1(71.3,88.85) ; U136.M15 v1(76.1,88.05) ; v1(83.02,150.92) 82.91,150.81 82.08,150.81 C72.2 82.08,150.64 81.83,150.39 C75.2 ; U136.R7 v1(79.3,81.66) ; v1(71.52,49.53) 71.5,49.53 71.4,49.63 C293.2 ; U136.C19 v1(68.9,92.06) ; v1(75.3,84.85) U136.L10 76.07,84.09 v1(76.07,84.07) 75.7,83.71 U136.L9 ; C174.2 v1(13.89,116.04) ; J13.58 v1(15.55,143.64) ; U14.3 v1(78.79,139.81) ; J12.58 v1(131.79,122.78) ; v1(89.17,151.33) 89.1,151.33 88.8,151.64 C66.2 ; U136.R6 v1(78.5,80.86) ; v1(25.39,138.56) 25.11,138.84 J13.45 ; v1(99.92,158.57) 99.65,158.31 C30.2 ; v1(61.45,145.76) 61.46,145.76 C90.2 ; C221.2 C222.2 47.24,83.03 47.34,82.93 v1(47.34,82.85) ; U136.K11 v1(74.5,84.85) ; v1(31.39,7.18) 31.34,7.13 J24.B12 ; R155.2 v1(76.45,116.51) R154.2 ; Q1.7 Q1.4 79.38,133.1 79.68,132.8 v1(79.68,132.27) R203.1 ; C48.2 v1(106.58,154.45) C51.2 ; C231.1 33.59,78.29 33.85,78.03 v1(33.85,77.84) ; C100.2 53.36,143.64 v1(53.13,143.86) C95.2 ; v1(96.84,78.54) 96.54,78.24 C3660.2 ; C126.1 102.68,134.9 102.86,134.72 102.86,134.72 v1(102.9,134.67) ; v1(98.93,135.54) R107.2 99.5,136.29 99.68,136.48 ; v1(32.56,16.33) 32.99,16.33 33.38,15.94 LD13.1 ; v1(81.83,63.91) 78.76,63.91 78.22,63.37 78.22,60.88 79.29,59.81 Y1.2 79.29,54.42 79.75,53.97 82.66,53.97 83.31,54.62 83.31,57.08 v1(83.69,57.45) 84.03,57.8 C104.1 84.46,57.64 R76.2 ; v1(81.83,63.91) 83.5,63.91 84.04,63.37 v1(84.04,60.8) C105.2 ; v1(81.83,63.91) 81.83,63.72 81.83,63.71 Y1.4 ; C52.2 v1(57.7,154.91) ; LD6.1 54.56,119.01 v1(54.96,119.41) ; J12.26 v1(128.3,139.58) ; C3750.1 35.44,53.6 v1(35.58,53.47) ; C309.2 37.46,21.18 v1(37.58,21.06) ; U136.R15 v1(79.3,88.85) ; J13.22 15.79,125.24 15.49,125.55 v1(15.49,125.55) ; R26.2 61.41,153.03 61.33,153.1 v1(61.33,153.54) ; J13.26 v1(15.36,126.84) ; C303.2 40.54,23.37 v1(40.05,22.88) ; J12.35 v1(122.86,135.58) ; U136.D11 v1(70.5,84.85) ; J13.16 15.08,122.84 14.9,122.66 14.44,122.66 ; U3086.3 65.7,52.56 66.01,52.86 v1(66.01,53.31) 66.01,53.39 65.7,53.7 R5806.2 ; U136.V4 v1(80.9,79.26) ; U61.5 51.88,21.11 52.34,20.66 C262.1 51.48,20.42 51.18,20.72 v1(51.18,20.89) ; J12.76 v1(131.49,115.58) ; U136.U8 v1(80.1,82.46) ; v1(54.04,127.71) 54.25,127.71 54.33,127.63 C3733.2 ; U136.N14 v1(77.7,88.05) U136.N15 ; C241.2 26.65,76.42 26.65,76.42 ; v1(34.13,23.37) 34.14,23.36 C307.2 ; v1(49.75,137.03) 50,136.79 U2358.4 ; C312.2 42.91,19.98 v1(42.54,19.98) ; U136.T5 v1(80.1,80.06) ; C29.2 82.76,158.66 82.64,158.78 v1(82.64,158.83) ; v1(40.43,12.34) 40.43,12.78 40.63,12.97 C320.1 ; C164.2 v1(85.9,68.28) ; v1(88,96.35) 88.36,96.71 C3732.1 ; U136.W10 82.66,84.45 82.76,84.35 v1(82.9,84.35) ; v1(65.07,9.9) U67.4 ; v1(97.4,94.06) 97.01,93.67 R238.2 ; U2357.5 v1(92.85,103.2) ; C321.2 36.43,13.11 36.64,12.9 v1(36.64,12.34) ; C3731.2 28.16,51.56 v1(28.39,51.79) ; v1(52.42,139.88) 52.54,139.76 R5745.1 ; C70.2 v1(125.9,72) ; U136.L14 v1(76.1,87.25) U136.L13 ; R36.1 92.04,148.88 v1(91.89,148.73) ; v1(82.38,141.14) 82.2,140.96 R112.1 ; LD3.1 47.03,78.46 47.33,78.16 v1(47.54,78.16) ; U15.A4 91.76,59.64 v1(91.86,59.74) ; SW8.4 v1(108.06,98.42) ; C49.2 66.59,154.46 66.34,154.12 66.34,153.99 v1(66.37,153.96) ; v1(86.89,82.83) 86.84,82.87 R553.2 ; C301.2 43.13,24.6 v1(43.03,24.7) ; R156.2 v1(79.01,116.51) R157.2 v1(80.24,116.51) R158.2 ; v1(22.12,13.39) 22.17,13.33 R3727.1 23.54,13.33 23.85,13.02 R3652.2 ; J14.12 v1(40.72,104) ; U136.H3 v1(72.9,78.46) ; v1(68.66,31.46) 68.66,31.08 68.92,30.83 C288.1 ; C50.2 v1(89.18,154.45) C47.2 ; C74.2 62.07,151.41 61.81,151.66 v1(61.64,151.66) 61.57,151.73 C71.2 ; v1(71.3,89.65) U136.E17 ; R159.2 v1(82.78,116.51) R160.2 ; v1(56.36,150.66) 56.87,150.66 56.91,150.7 C78.2 ; C3.2 v1(75.51,162.38) ; C84.2 57.69,146.58 57.8,146.58 58.11,146.28 58.11,146.17 v1(58.12,146.16) 58.19,146.09 C85.2 ; v1(67.81,127.64) 68.01,127.83 U27.3 ; R152.2 v1(95.3,116.51) R151.2 R150.2 R149.2 R148.2 R147.2 R146.2 v1(87.6,116.51) R145.2 ; 14.44,122.66 14.65,122.46 14.65,122.41 14.66,122.39 C160.2 C161.2 ; 14.44,122.66 v1(14.42,122.66) ; C102.1 v1(117.51,76.11) ; U136.E5 v1(71.3,80.86) ; U134.3 18.82,13.25 19,13.07 C3627.1 v1(19,11.82) ; J13.25 24.81,126.84 v1(25.09,126.57) ; C3695.1 42.84,155.91 v1(42.66,155.73) ; R5800.1 v1(69.51,43.66) ; J12.15 v1(126.05,143.58) ; D2.1 25.52,56.31 v1(25.72,56.52) ; C246.2 v1(46.52,54.63) ; v1(73.7,88.85) U136.J15 v1(74.5,88.85) U136.K15 ; v1(16.9,48.2) 16.39,48.71 J17.5 ; R214.1 v1(46.94,99.9) ; J13.7 v1(24.6,119.64) ; C148.2 v1(64.33,126.91) ; U136.K8 v1(74.5,82.46) ; 62.47,25.47 62.69,25.25 62.83,25.25 v1(62.88,25.3) 62.88,25.43 62.97,25.51 ; C190.2 45.87,97.14 v1(46,97.01) 45.81,96.83 U41.1 ; v1(112.62,93.8) 112.43,93.99 U26.3 ; U3084.4 v1(114.06,51.84) ; v1(76.5,143.71) 76.5,143.7 R68.1 ; v1(34.56,163.35) C107.2 ; C234.2 40.2,78.29 v1(40.15,78.23) ; U28.B3 v1(66.29,106.46) ; U136.P14 v1(78.5,88.05) U136.P15 v1(78.5,88.85) ; v1(15.11,140.31) 15.24,140.44 J13.50 ; v1(81.45,140.97) 81.3,140.82 C136.2 ; U2347.4 101.63,55.87 v1(101.41,56.08) ; J12.49 122.6,125.98 v1(122.42,126.16) ; C165.1 v1(95.37,70.74) ; Q3.2 v1(65.59,49.37) ; v1(80.9,84.06) 81.3,84.45 U136.V10 ; R232.1 R231.1 R230.1 ; v1(63.74,9.8) 63.62,9.68 D3.1 ; Y5.2 26.93,85.03 27.38,85.48 C217.1 28.22,85.48 28.26,85.52 v1(28.44,85.52) ; C236.1 23.94,77.04 v1(24.07,76.91) ; U136.E9 v1(70.5,84.06) ; v1(52.47,77.44) 52.34,77.57 C207.2 ; J12.36 v1(131.46,135.58) ; C86.2 61.4,146.21 v1(61.33,146.28) ; U136.D19 v1(69.7,92.06) ; U3077.7 89.47,64.38 v1(89.68,64.59) ; v1(42.31,10.9) 42.58,10.63 R403.2 ; U2351.3 v1(57.94,41.25) ; C87.2 68.39,145.95 68.67,146.23 68.72,146.23 v1(69.03,146.53) ; v1(68.27,118.9) 68.12,118.75 Q12.3 ; J12.75 v1(125.76,115.58) ; R63.2 v1(57.99,143.38) ; U140.C1 v1(56.22,95.93) ; R230.1 R229.1 ; 58.47,38.86 v1(58.46,38.86) ; R153.2 v1(75.14,116.51) ; C495.2 C497.2 82.29,93.29 82.11,93.12 82.11,92.44 v1(82.5,92.06) U136.W19 ; TP42.1 44.34,122.68 v1(44.34,122.68) C3728.1 ; R5820.1 56.4,104.25 56.78,103.86 v1(57.27,103.86) 57.45,103.86 57.64,104.04 C3705.2 ; J13.66 v1(15.46,146.84) ; LD9.1 47.07,14.69 46.82,14.94 46.11,14.94 v1(45.92,14.75) ; U136.L5 v1(76.1,80.06) ; R404.2 28.86,9.13 29.56,9.83 v1(29.56,10.36) ; v1(24.58,122.63) 24.37,122.84 J13.15 ; v1(69.7,78.46) U136.D3 U136.D4 ; v1(115.49,146.11) C99.2 ; v1(62.76,147.16) C81.2 61.71,147.16 v1(61.69,147.14) 61.64,147.14 61.38,146.89 C82.2 ; R22.2 63.55,154.18 63.26,154.46 v1(63.26,154.53) ; v1(31.23,9.61) 31.39,9.45 C327.2 ; R258.2 48.82,76.09 48.51,75.78 v1(47.8,75.78) ; J12.7 v1(126.05,146.78) ; J13.36 15.3,130.84 v1(15.05,131.09) ; U3070.3 65.72,123.07 v1(65.85,122.94) 66.09,122.7 C3740.1 ; v1(116.62,45.66) 116.8,45.48 C273.2 ; 64.97,27.54 v1(64.92,27.59) ; C53.1 v1(56.69,154.75) ; U136.G13 v1(72.1,86.45) ; C77.2 58.38,151.35 v1(58.86,151.83) ; C175.2 v1(14.65,116.04) ; C1.2 v1(35.44,166.31) ; v1(72.9,85.65) U136.G12 ; U136.W1 v1(82.5,76.85) ; 33.53,94.33 v1(33.23,94.03) ; C169.2 v1(44.53,114.48) ; C3729.1 v1(30.74,101.35) ; v1(62.28,143.04) 62.05,143.27 C98.2 ; U136.A19 v1(67.3,92.06) ; C176.2 v1(15.42,116.04) ; R313.2 v1(24.46,72.49) ; J14.10 v1(41.99,104) ; U136.T9 v1(79.3,84.06) U136.R10 v1(78.5,84.85) ; U28.E5 v1(64.23,110.49) ; v1(82.52,138) 82.64,137.89 U23.3 ; v1(44.72,43.23) 45.04,42.91 SW7.1 ; J12.46 v1(131.49,127.58) ; U2355.3 46.24,117.93 46.19,117.98 46.19,118.41 v1(46.09,118.52) ; C37.2 v1(128.59,65.73) ; U136.H6 v1(72.9,80.86) ; J12.65 v1(125.76,119.58) ; J12.22 v1(128.3,141.18) ; C54.2 v1(51.07,153.77) ; J13.49 24.28,140.44 24.5,140.67 v1(24.5,140.74) ; C192.2 v1(15.72,82.25) ; v1(46.2,54.32) 46.2,53.89 C254.2 46.83,53.89 v1(46.83,54.31) ; J14.20 v1(35.64,104) ; D11.1 32.72,106.77 33.03,107.07 33.03,108.26 v1(32.64,108.65) C489.1 ; J12.31 v1(122.67,137.18) ; 41.25,157.49 C3692.1 41.33,156.83 v1(41.19,156.69) ; J13.75 v1(24.76,150.84) ; U136.T16 v1(80.1,89.65) ; v1(17.21,8.66) 17.72,8.66 18.2,9.14 R3651.2 ; v1(104.28,60.33) 104.23,60.33 104.11,60.45 C150.1 ; U136.T8 v1(79.3,82.46) ; U15.A2 87.3,56.14 v1(87.07,55.91) ; U136.J11 v1(73.7,85.65) U136.H11 ; v1(86.96,135.61) U2346.3 ; U136.M8 v1(76.9,83.26) U136.N9 ; U136.L15 v1(76.1,88.85) ; C292.2 v1(43.91,31.14) ; U136.D8 v1(69.7,83.26) ; C3738.2 v1(46.61,58.17) ; C140.2 53.47,113.47 v1(53.71,113.72) ; v1(104.44,59.69) 104.51,59.77 C3768.1 ; J12.66 v1(131.49,119.58) ; C2.2 v1(58.36,162.36) ; C202.2 82.48,68.16 v1(82.26,67.94) 82.03,68.18 C483.2 ; U136.R5 v1(78.5,80.06) ; U136.J7 v1(73.7,82.46) ; U136.E15 v1(70.5,88.85) ; U136.U17 v1(80.9,90.46) ; U136.E12 v1(70.5,85.65) ; 52.04,150.02 v1(52.27,149.8) ; R3736.2 v1(113.87,85.46) ; v1(24.86,129.24) J13.31 ; v1(55.33,24) C269.2 ; U140.E5 v1(59.03,100.11) ; C282.1 v1(66.9,24.48) ; J13.76 v1(15.82,150.84) ; U136.M5 v1(76.9,80.86)
  TOP w0.381: v1(109.14,121.44) 109.65,120.92 C3702.2 ; SW5.4 30.61,113.24 v1(29.98,112.61) 29.98,111.38 SW5.1 28.39,110.75 27.46,109.81 Q7.3 ; J13.88 v1(20.16,155.02) ; J12.45 122.77,127.58 v1(122.52,127.33) ; C3698.2 104.99,104.12 v1(104.44,104.67) ; C3701.2 v1(109.65,115.59)
  L02_GND1 w0.381: v1(37.39,8.7) v1(37.39,7.18) 37.39,6 37.44,5.95 v1(37.44,5.48) 37.44,5.1 v1(37.14,4.79) ; v1(31.65,4.79) 31.65,5.26 31.39,5.52 v1(31.39,7.18) v1(31.39,8.7) ; v1(52.39,8.7) v1(52.39,7.18) 52.39,6.07 52.25,5.92 v1(52.25,5.45) ; 50.46,4.93 50.54,4.85 50.54,4.39 v1(50.51,4.37) ; v1(46.39,7.18) v1(46.39,8.7)
  L03_SIG1 w0.102: v1(51.71,59.11) 50.94,59.87 50.49,59.87 50.38,59.77 48.07,59.77 47.67,60.17 41.6,60.17 41.22,59.79 36.85,59.79 34.13,57.07 v1(34.13,56.67)
  L04_PWR1 w0.102: v1(71.3,80.86) 70.51,80.86 70.11,80.46 66.33,80.46 65.46,79.59 65.46,77.1 62.17,73.81 59.68,73.81 54.17,68.3 54.17,63.86 52.52,62.2 52.52,59.59 52.04,59.11 v1(51.71,59.11)
  BOTTOM w0.091: U88.3 v1(47.1,113.63) ; U87.3 42.25,114.95 42.28,114.99 v1(42.28,115.04)
  BOTTOM w0.147: C342.1 107.65,160.52 107.94,160.81 107.94,165.71 105.91,167.74 103.06,167.74 v1(102.37,167.06) ; C341.1 112.54,160.68 111.9,161.32 111.9,162.26 109.67,164.49 109.67,167.34 v1(110.1,167.76) ; v1(85.03,167.14) 85.58,167.69 88.47,167.69 90.7,165.47 90.7,161.26 90.26,160.83 C344.1 ; v1(93.99,166.93) 93.41,166.36 93.41,164.02 94.53,162.91 94.53,161.44 95.24,160.74 C343.1 ; v1(68.7,168.61) 68.7,168.18 68.14,167.61 68.14,165.3 69.09,164.35 69.68,164.35 70.07,164.74 70.07,165.13 68.81,166.38 C334.1 ; v1(51.54,168.14) 51.1,167.7 51.1,165.61 52.15,164.55 52.74,164.55 52.91,164.73 52.91,165.06 51.67,166.31 C338.1 ; C336.1 55.51,166.41 56.84,165.07 56.84,164.26 57.32,163.78 57.88,163.78 59.43,165.33 59.43,166.49 v1(59.69,166.76) ; v1(76.84,166.94) 76.84,165.33 75.29,163.78 74.47,163.78 73.98,164.26 73.98,165.07 72.65,166.41 C332.1
  BOTTOM w0.152: 62.34,74.51 69.27,74.51 70.01,75.25 70.62,75.25 70.89,75.51 70.89,76.15 ; 61.56,75.41 61.82,75.41 61.94,75.29 68.85,75.29
  BOTTOM w0.178: U3081.C3 44.25,72.61 45.02,71.83 U3079.1
  BOTTOM w0.203: v1(61.92,27.66) 62.27,27.66 62.48,27.86 C608.1 ; C498.2 107.73,76.55 v1(107.23,76.05) ; v1(73.7,85.65) 73.56,85.51 C462.2 73.04,85.51 v1(72.9,85.65) ; C122.1 64.88,136.53 v1(65.3,136.12) ; U125.16 64.98,29.44 65.17,29.25 65.17,28.72 v1(65.13,28.67) ; U125.12 64.12,31.84 v1(63.47,32.49) ; U90.5 43.7,107.8 43.5,108 v1(43.12,108) 43.12,108.46 43.27,108.6 43.55,108.6 44.1,108.06 U90.6 ; v1(45.13,69.87) 45.13,70.02 45.02,70.13 U3079.1 ; v1(106.72,151.28) 106.73,151.29 106.73,151.37 106.96,151.59 C369.2 ; U81.13 98.58,124.95 v1(98.59,124.93) ; 52.71,154.2 51.67,154.2 v1(51.24,154.63) ; v1(39.72,37.47) 39.92,37.47 40.22,37.16 U123.C1 ; C642.2 41.9,12.69 42.37,12.21 v1(43.1,12.21) 43.42,12.53 C644.2 ; U117.16 47.65,31.41 47.4,31.16 v1(46.98,31.16) 46.53,31.16 46.35,31.34 C575.1 46.65,31.72 47.09,32.17 U117.1 ; U102.4 32.61,88.95 32.49,89.07 v1(32.43,89.07) ; C384.2 87.51,59.47 v1(87.16,59.82) ; U83.13 80.47,120.76 v1(80.48,120.77) ; v1(69.57,26.95) 69.46,27.07 69.46,27.34 69.59,27.47 U126.9 ; U76.A4 108.86,155.22 v1(108.72,155.36) ; v1(52.39,7.18) 52.34,7.12 C653.2 ; v1(90.11,57.18) 90.42,57.49 C387.2 ; v1(87.73,127.59) 88.15,127.18 R456.2 88.15,126.6 88.56,126.19 U82.25 88.56,124.93 88.86,124.63 v1(88.86,124.5) ; U118.7 51.14,46.22 50.88,46.48 C598.2 50.88,48.01 v1(50.89,48.02) ; U114.2 30.58,58.88 30.78,58.67 v1(30.83,58.67) 30.87,58.67 31.08,58.88 U114.1 ; U125.10 63.32,31.43 v1(63.52,31.63) 63.72,31.43 U125.11 ; C361.2 v1(106.58,154.45) C359.2 ; v1(48.08,110.37) 47.68,110.37 47.49,110.56 C416.1 ; v1(72.1,80.86) 72.35,81.11 C3751.2 ; v1(121.83,38.74) 122.24,39.15 122.51,39.15 R622.1 ; 31.89,85.17 31.34,85.72 v1(30.95,85.72) 30.93,85.72 30.76,85.55 C516.1 ; 31.89,85.17 32.29,84.77 U109.6 ; 31.89,85.17 U109.5 ; C434.2 71.41,87.95 v1(71.3,88.05) ; U3080.C1 58.22,65.68 57.52,66.38 U3078.7 57.52,68.59 57.19,68.91 v1(57.19,69.29) 56.81,69.29 56.53,69.01 55.98,69.01 55.59,69.4 C3762.2 ; U83.11 82.34,120.27 81.98,120.63 v1(81.98,120.77) 81.97,120.76 U83.12 ; U76.A1 112.63,154.8 v1(112.85,155.02) ; v1(55.03,167.92) 55.06,167.94 C330.2 ; C394.1 82.53,127.19 v1(82.8,127.46) ; v1(106.32,76.08) 106.28,76.04 C504.2 ; v1(32.16,82.24) 32.29,82.37 U109.3 ; U132.1 45.87,10.2 v1(45.96,10.3) ; C494.2 76,87.15 v1(76.1,87.25) ; C443.2 78.22,82.46 v1(77.7,82.46) ; D14.1 103.65,94.47 C622.1 v1(104.23,94.46) ; C388.2 64.26,110.53 v1(64.23,110.49) ; C485.2 74.45,84.81 v1(74.5,84.85) 74.61,84.74 C466.2 ; C538.2 19.58,60.73 v1(19.35,60.73) ; U110.11 36.71,83.37 v1(36.34,83.74) 36.37,83.77 U110.10 ; C617.1 73.27,27.03 73.45,26.85 v1(73.98,26.85) ; C555.2 44.89,52.12 44.52,51.75 v1(44.52,51.18) ; v1(76.9,80.06) 76.73,80.22 C429.2 ; v1(68.76,28.35) 69.16,28.75 69.54,28.75 69.62,28.67 U126.12 ; C473.1 v1(14.44,69.25) ; C216.1 60.86,73.02 62.34,74.51 ; v1(55.34,27.66) 55.46,27.78 C599.1 ; v1(42.54,19.98) 42.74,19.78 U129.51 ; R662.2 44.5,24.58 v1(44.82,24.91) ; C657.2 73.82,87.13 v1(73.7,87.25) ; v1(89.68,150.85) 89.7,150.83 89.7,150.3 ; C3727.1 44.48,109.18 v1(44.44,109.14) ; v1(43.15,10.9) 42.83,10.58 C651.2 ; U124.7 40.31,40.33 40.05,40.58 C604.2 v1(40.05,41.8) ; v1(69.03,146.53) 69.13,146.43 69.13,145.61 ; v1(29.15,66.84) 29.32,66.67 C525.2 29.32,65.98 29.32,65.44 29.58,65.19 U114.7 ; C484.2 70.59,83.96 v1(70.5,84.06) ; v1(135.35,82.6) 134.95,82.2 J26.SH2 ; R562.2 106.99,74.69 106.6,74.3 v1(106.6,74.27) ; C501.2 74.3,82.66 v1(74.5,82.46) ; C663.2 75.6,85.15 v1(75.3,84.85) 75.34,84.81 C658.2 ; C614.2 91.36,34.63 R632.2 ; v1(131.51,78.08) 131.57,78.13 J26.6 ; v1(77.7,88.05) 77.58,87.93 C662.2 ; Q10.7 Q10.4 ; U76.A2 112.85,150.81 C371.2 113.67,150.58 113.86,150.39 C373.2 v1(115.87,150.39) ; C469.1 34.53,90.55 v1(34.64,90.45) ; v1(69.15,75.59) 68.83,75.27 ; U117.11 49.64,32.57 v1(49.84,32.77) 49.64,32.97 U117.10 ; C350.2 v1(96.84,157.12) ; C224.2 71.39,80.95 v1(71.3,80.86) 71.17,80.98 C509.2 70.4,80.98 C3653.2 ; U126.16 71.35,29.65 71.52,29.82 71.82,29.82 v1(72.33,29.31) ; v1(80.1,80.06) v1(80.9,80.06) ; v1(72.1,79.26) 72,79.35 C508.2 ; C500.1 35.99,87.76 v1(36.31,88.09) ; C3655.2 79.3,84.42 v1(79.3,84.06) ; v1(74.5,82.46) 74.64,82.6 C3758.2 ; v1(74.5,82.46) 74.63,82.32 C660.2 ; v1(113.56,44.24) C611.2 113.17,43.28 v1(112.28,44.16) ; v1(28.66,96.26) R531.1 28.35,95.73 28.17,95.91 U93.3 ; v1(66.62,44.5) 66.89,44.23 66.89,43.6 66.55,43.27 C3719.2 ; v1(68.9,78.46) v1(69.7,78.46) 69.7,77.65 68.36,76.31 62.11,76.31 61.36,77.06 60.78,77.06 60.34,76.62 C213.1 60.24,76.62 59.72,77.14 56.75,77.14 ; C3718.2 58.14,42.1 57.94,41.9 v1(57.94,41.25) ; U77.A3 91.46,150.93 v1(91.33,150.8) ; v1(39.03,10.77) 39.07,10.8 U133.1 ; v1(48.58,68.5) 48.82,68.74 Q2.2 ; C641.2 37.79,14.18 C643.2 37.79,13.41 36.75,12.37 36.67,12.37 v1(36.64,12.34) ; U77.A4 91.46,155.18 v1(91.3,155.34) ; R609.1 60.24,25.51 59.98,25.25 v1(59.97,25.25) ; v1(57.97,27.53) 58.23,27.79 C606.1 ; v1(88.84,58.45) 88.46,58.45 88.4,58.39 C382.2 ; C351.2 v1(114.12,156.93) ; C437.2 73.03,80.72 v1(72.9,80.86) ; 135.86,66.98 135.86,67.88 J26.SH1 ; U107.4 19.42,77.18 v1(19.24,77.36) ; C385.2 91.33,59.59 91.48,59.74 v1(91.86,59.74) ; v1(52.67,81.53) 52.89,81.75 C3644.1 ; C368.2 56.53,152.45 v1(56.67,152.31) ; C493.2 77.03,83.38 v1(76.9,83.26) ; U115.C1 47.86,51.78 47.31,52.33 47.31,52.83 47.32,52.83 47.32,52.95 ; v1(89.17,151.33) 89.32,151.33 89.56,151.57 C370.2 ; R613.1 60.45,29 v1(60.17,29.28) ; C505.2 77.51,81.85 v1(77.7,81.66) ; v1(52.25,5.45) 52.09,5.29 D16.2 ; U126.10 69.5,27.87 v1(69.31,28.06) 69.31,28.07 69.51,28.27 U126.11 ; C440.2 70.62,85.78 v1(70.5,85.65) ; U132.3 45.93,11.5 v1(45.96,11.46) ; v1(41.75,56.36) 42.39,55.72 C561.2 ; C3767.2 76.25,84.26 v1(76.07,84.07) 75.93,84.07 C3752.2 ; U97.10 32.83,93.63 v1(33.23,94.03) U97.11 ; C367.2 v1(89.18,152.93) C365.2 ; U125.7 61.67,30.24 61.51,30.4 v1(61.46,30.4) ; C468.2 74.68,85.84 v1(74.5,85.65) ; 46.64,109.16 v1(46.68,109.12) ; v1(46.68,109.12) R489.1 ; v1(46.68,109.12) R490.1 ; v1(61.38,82.85) 60.83,82.85 60.6,83.08 60.06,83.08 59.85,83.29 R545.2 ; C455.1 v1(26.92,92.02) ; C358.2 97.05,155.13 97.47,155.55 97.55,155.55 97.55,156.1 v1(97.4,156.26) ; C602.2 v1(111.96,46.28) ; v1(70.46,26.17) 70.55,26.25 U126.7 ; U126.1 72.07,28.67 72.33,28.93 v1(72.33,29.31) ; R623.1 96.49,39.04 v1(96.49,38.49) ; v1(86.96,135.61) 87.04,135.61 87.33,135.9 C3703.2 ; U126.14 v1(70.55,30.75) ; U81.11 96.11,126.82 v1(96.78,127.49) ; U113.B3 U113.C3 31,62.16 v1(31.08,62.08) ; v1(44.05,105.07) 44.05,105.09 44.1,105.14 U90.3 ; C3649.2 78.5,84.82 v1(78.5,84.85) ; J26.SH4 v1(121.8,80.88) ; v1(39.03,10.19) 39.06,10.15 U133.2 ; v1(129.15,59.99) U2349.3 U2349.8 ; U77.A1 94.91,155.08 95.21,155.37 95.5,155.37 95.73,155.6 C354.2 v1(96.4,156.04) ; v1(64.92,27.59) 64.77,27.73 64.77,27.74 64.77,27.93 C612.1 64.56,28.5 64.12,28.94 U125.1 ; v1(72.83,25.15) R635.1 ; v1(59.76,88.44) 60.14,88.44 60.39,88.19 R564.2 ; v1(50.54,43.29) 50.66,43.17 U119.C1 ; C366.2 v1(106.58,152.93) C364.2 ; v1(46.6,103.94) 46.6,104.32 46.53,104.39 46.53,104.7 46.36,104.86 C3726.1 ; U132.2 45.93,10.85 v1(45.96,10.88) ; 47.32,52.95 47.57,52.7 48.24,52.7 48.51,52.97 U116.7 48.51,54.75 48.25,55 C560.2 ; 47.32,52.95 v1(47.32,53.31) ; C607.1 62.95,24.99 62.88,25.06 v1(62.88,25.3) ; v1(113.96,45.75) 113.95,45.75 113.86,45.84 R607.2 ; C378.2 65.55,147.93 v1(65.46,148.02) ; v1(72.1,88.05) 72.29,87.86 C448.2 ; C3645.2 79.35,84.85 v1(79.3,84.85) 79.45,85.01 C446.2 ; U76.A3 108.86,150.85 108.66,150.65 108.46,150.65 108.17,150.35 R430.2 107.28,150.13 v1(106.94,150.46) ; C340.2 61.15,162.99 60.88,162.71 v1(60.88,162.33) 60.57,162.02 R415.1 ; U3081.C1 44.25,73.84 43.52,74.57 U3079.7 43.52,77.24 43.14,77.63 C3764.2 ; v1(46.35,42.55) 46.09,42.28 D13.1 45.66,41.81 45.54,41.69 C613.1 45.09,42.33 44.72,42.7 v1(44.72,43.23) ; v1(57.3,56.81) 57.27,56.78 56.77,56.78 56.52,57.03 U92.C1 ; v1(68.1,94.23) 67.7,93.83 R504.2 67.26,94.33 66.62,94.96 R5709.2 ; C529.1 v1(14.49,78.07) ; v1(63.68,30) 63.93,30.24 U125.14 ; C360.2 v1(89.18,154.45) C362.2 ; R591.1 47.21,35.89 v1(47.02,36.08) ; U91.7 56.36,53.95 56.62,53.69 C427.2 56.62,52.55 v1(56.63,52.54) ; C352.2 93.84,157.08 93.79,157.12 v1(93.69,157.12) ; C386.2 90.31,58.25 v1(90.11,58.45) ; C518.2 111.71,72.52 111.17,72.52 v1(111.12,72.57) ; v1(50.36,73.74) 50.68,73.42 U98.4 ; v1(95.24,44.38) C610.2 v1(96.51,43.3) ; U115.C3 49.81,51.78 50.45,51.15 v1(50.45,50.56) 50.01,50.12 U116.1 ; C502.2 71.7,84.41 71.7,84.58 71.42,84.85 v1(71.3,84.85) 71.3,85 C3759.2 ; v1(72.33,29.31) 72.67,29.31 C618.1 ; R3724.2 52.64,79.15 52.8,79.31 v1(52.8,79.78) 52.99,79.59 U135.3 ; C353.2 113.47,156.04 v1(113.7,155.81) 113.8,155.71 C357.2 ; v1(34.07,5.35) 34.32,5.1 D17.2 ; v1(45.12,33.93) 45.24,34.06 45.79,34.06 46.04,33.81 C574.1 ; v1(39.03,9.6) 39.13,9.5 U133.3 ; U77.A2 95.43,151.35 95.97,150.81 C372.2 96.63,150.81 96.99,150.45 C374.2 v1(97.43,149.74) ; U3080.C3 58.22,64.47 58.63,64.06 v1(59.02,64.06) U3078.1 ; C605.1 v1(17.01,55.74) ; C511.1 v1(34.07,87.04) ; U86.2 24.07,64.19 v1(23.91,64.03) ; v1(88.94,128.44) 88.94,128.22 89,128.16 C391.1 ; v1(74.5,88.85) 74.82,88.85 C461.2 ; R422.1 v1(117.33,151.44) ; R618.1 v1(128.33,40.43) ; v1(112.62,93.8) 112.62,94.05 112.66,94.09 C146.2 ; v1(52.39,8.7) 52.31,8.61 C650.2 ; R610.1 v1(17.01,57.98) ; 114.95,155.55 114.95,156.24 v1(114.76,156.43) ; C408.2 99.14,119.37 v1(99.5,119.73) ; v1(37.56,19.98) 37.36,19.78 U129.20 ; v1(35.58,53.47) 36.06,53.47 C572.2 35.71,52.94 35.65,52.88 v1(35.27,52.88) ; v1(105.43,73.03) 105.31,72.92 C514.2 ; 81.31,146.05 v1(81.31,145.51) ; C329.2 v1(72.2,167.97) ; C453.2 73.78,88.77 v1(73.7,88.85) ; C349.2 v1(114.55,157.9) ; C520.2 107.18,72.41 v1(107.31,72.54) ; U81.12 97.08,124.95 v1(97.07,124.93) ; v1(72.1,88.85) 72.1,88.7 C432.2 ; v1(98.42,91.48) 97.77,91.48 C421.1 ; C441.2 73.52,82.63 v1(73.7,82.46) 73.65,82.41 C3647.2 ; v1(59.03,100.11) 59.23,100.31 C3708.2 ; v1(93,32.28) 92.76,32.04 U127.4 ; C460.2 75.32,85.65 v1(75.3,85.65) ; U120.2 113.93,47.55 114.08,47.69 R606.2 ; 36.88,56.36 v1(37.89,56.36) ; J26.SH3 v1(120.64,73.82) ; C3724.1 34.69,82.24 v1(34.59,82.14) ; U75.3 v1(67.6,160.11) ; C490.2 76.18,88.13 v1(76.1,88.05) ; C527.2 104.18,70.26 v1(103.96,70.49) 103.98,70.51 C521.2 ; C390.2 64.25,107.96 v1(64.05,108.15) ; C515.1 33.88,85.34 v1(33.88,84.84) ; C470.1 31.71,90.2 v1(31.62,90.2) 31.56,90.14 31.46,90.14 31.37,90.06 31.15,90.06 R555.1 ; U125.9 62.92,31.29 v1(62.6,31.6) ; R682.2 v1(39.41,12.5) ; v1(80.31,127.56) 80.58,127.29 80.58,127.24 80.69,127.12 C395.2 ; v1(29.12,62.67) 29.12,62.56 29.51,62.17 29.52,62.17 29.52,62.16 U113.C1 ; C3725.1 34.61,84.99 v1(34.43,85.17) 34.61,85.34 R569.1 ; v1(27.58,90.75) 27.96,90.75 28.04,90.68 R556.2 ; v1(40.43,12.34) 40.68,12.59 R681.2 ; C631.2 v1(46.17,20.56) ; v1(72.1,86.45) 72.25,86.3 C447.2 ; v1(112.16,38.21) 112.43,38.47 R624.1
  BOTTOM w0.254: C389.2 69.36,108.87 69.37,108.88 69.73,108.88 v1(69.92,108.69) ; C383.2 88.39,57.63 v1(88.84,57.18) ; v1(104.44,104.67) 104.44,104.67 104.75,104.36 U3072.19 ; v1(105.02,112.32) 105.02,112.12 104.75,111.86 U3072.38 ; v1(129.25,51.61) 129.08,51.79 U2350.3 U2350.8 ; R418.1 117.68,156.33 v1(117.63,156.37) ; C467.2 77.07,86.28 v1(76.9,86.45) 76.76,86.31 C463.2 ; v1(37.14,4.79) 36.93,4.59 C654.2 ; C659.2 72.29,83.45 v1(72.1,83.26) ; C655.2 31.86,4.59 v1(31.65,4.79) ; C3717.2 72.22,60.88 72.23,60.88 72.38,60.88 72.56,61.06 72.58,61.06 73.12,61.6 C3716.2 ; 135.86,66.98 135.86,66.57 v1(135.7,66.42) ; C3652.2 75.24,81.6 v1(75.3,81.66) 75.37,81.58 C454.2 ; C3661.2 77.51,81.05 v1(77.7,80.86) 77.88,81.04 C445.2 ; C3713.2 75.61,61.6 74.88,60.88 C3712.2 ; v1(72.1,80.86) 72.26,80.86 C517.2 ; R5829.1 33.28,54.79 32.73,55.33 32.73,57.02 33.22,57.51 33.7,57.51 34.13,57.07 v1(34.13,56.67) ; C3656.2 75.64,80 C506.2 75.94,80.21 v1(76.1,80.06) ; v1(92.3,129.3) 91.56,128.57 C393.1 ; R5728.2 74,71.6 74.26,71.35 v1(74.54,71.35) ; R5681.2 v1(113.75,100.51) ; v1(72.1,83.26) 72.3,83.06 C449.1 ; v1(72.1,83.26) 71.89,83.05 C512.2 ; C528.1 33.72,81.54 34.08,81.18 v1(34.08,81.1) ; v1(72.1,79.26) 72.24,79.4 C451.2 ; C520.2 107.18,71.27 107.29,71.17 R561.2 ; C284.1 C286.1 72.33,56.23 v1(72.51,56.41) 72.54,56.38 C290.2 ; U3072.8 110.25,104.62 v1(110.03,104.85) ; C478.1 v1(47.8,75.78) ; R451.2 66.67,106.46 v1(66.29,106.46) ; v1(96.4,156.04) 96.84,156.49 v1(96.84,157.12) ; v1(55,98.12) 55.16,97.96 R5754.1 ; U3072.49 110.25,112.04 v1(110.41,112.19) ; C188.1 v1(88.49,77.9) ; v1(78.5,87.25) C465.2
  BOTTOM w0.305: v1(62.98,55.83) 63.25,55.57 U65.4 ; C616.2 92.58,33.35 v1(92.19,33.74) ; v1(42.07,91.58) 42.21,91.72 C208.2 ; 67.7,60.95 67.82,60.83 68.06,60.83 68.3,60.6 C3715.2 ; 67.7,60.95 67.58,60.83 66.93,60.83 66.62,60.52 C3714.2 ; 67.7,60.95 C3710.2 68.26,61.74 68.45,61.93 68.45,62.35 68.86,62.76 69.98,62.76 70.08,62.66 C3711.2 71.18,62.66 71.71,63.19 72.04,63.19 72.57,62.66 C3716.2 73.68,62.66 74.14,63.12 74.6,63.12 75.06,62.66 C3713.2 ; U62.2 79.91,51.96 v1(80.1,51.77) ; C649.2 46.41,8.72 v1(46.39,8.7) ; v1(77.91,57.16) C265.2 C266.1 ; C471.2 78.6,84.85 v1(78.5,84.85) ; v1(40.15,78.23) 40.75,77.63 C3764.2 ; C488.2 28.81,87.76 28.69,87.88 v1(28.26,87.88) ; v1(77.7,82.46) 77.86,82.29 C477.2 ; v1(126.41,35.71) 126.17,35.95 R628.1 ; v1(78.68,45.85) 78.68,46.25 78.48,46.46 C3720.1 ; C3709.2 54.93,98.2 v1(55,98.12) 55.08,98.2 C3706.1 ; C430.1 35.57,96.03 35.6,96.06 v1(35.6,96.49) ; C409.1 v1(97.64,118.5) ; C414.1 24.81,66.12 v1(25.11,65.81) ; R626.1 v1(119.08,33.91) ; v1(63.49,60.1) 63.7,60.3 R320.2 ; C652.2 46.77,7.56 v1(46.39,7.18) ; C503.2 110.92,74.34 v1(111.27,73.99) ; R639.1 v1(87.13,32.95) ; R642.1 v1(97.86,32.21) ; C3707.2 56.22,95.95 v1(56.22,95.93) ; R606.2 v1(114.55,47.16)
  BOTTOM w0.381: U2345.11 105.37,121.05 v1(104.96,121.46) ; v1(92.85,103.2) 89.83,103.2 88,101.37 v1(88,96.35) ; v1(66.36,59.54) 66.36,59.89 66.57,60.1 C3714.2
  vias: v1(13.58,19.41) v1(14.09,19.41) v1(14.6,19.41) v1(15.36,18.57) v1(15.87,18.57) v1(17.04,19.23) v1(17.04,18.72) v1(17.54,54.14) v1(17.53,49.3) v1(17.54,19.23) v1(17.54,18.72) v1(17.85,51.31) v1(18.17,54.14) v1(21.4,20.19) v1(21.4,19.68) v1(21.91,20.19) v1(21.91,19.68) v1(22.42,20.19) v1(22.42,19.68) v1(26.2,76.98) v1(26.19,76.39) v1(27.29,21.37) v1(27.61,74.46) v1(27.61,73.44) v1(27.73,21.83) v1(28.42,21.62) v1(28.87,21.48) v1(29.24,11.96) v1(29.53,21.46) v1(29.64,74.46) v1(29.64,73.44) v1(29.95,11.96) v1(29.95,11.25) v1(30.42,21.46) v1(30.66,11.96) v1(30.66,11.25) v1(30.66,10.54) v1(30.95,81.31) v1(31.1,23.99) v1(31.11,23.52) v1(31.1,23.06) v1(31.31,83.44) v1(31.37,11.96) v1(31.37,11.25) v1(31.37,10.54) v1(31.56,23.97) v1(31.58,23.51) v1(31.58,23.05) v1(32.64,75.18) v1(32.65,75.66) v1(33.21,61.54) v1(33.2,60.9) v1(34.1,61.54) v1(34.1,60.88) v1(34.08,58.5) v1(34.99,61.54) v1(34.99,60.88) v1(34.96,50.98) v1(35.62,50.98) v1(35.88,61.54) v1(35.88,60.88) v1(36.43,161.16) v1(36.69,161.56) v1(36.91,161.16) v1(37.56,21.91) v1(38.81,22.88) v1(38.81,21.91) v1(38.81,20.95) v1(38.81,19.98) v1(39.39,56.79) v1(39.39,55.93) v1(40.05,21.91) v1(40.05,20.95) v1(40.05,19.98) v1(40.25,56.79) v1(40.25,55.93) v1(41.11,113.33) v1(41.3,22.88) v1(41.3,21.91) v1(41.3,20.95) v1(41.3,19.98) v1(41.8,156.44) v1(42.5,161.99) v1(42.54,21.91) v1(42.54,20.95) v1(43.04,161.97) v1(43.83,61.69) v1(43.83,61.19) v1(43.81,51.08) v1(44.52,50.47) v1(44.72,61.69) v1(44.72,61.19) v1(45.49,51.18) v1(45.49,50.47) v1(45.61,61.64) v1(45.61,61.17) v1(46.49,61.69) v1(46.49,61.19) v1(46.46,51.18) v1(46.46,50.47) v1(46.78,50.83) v1(47.63,19.05) v1(47.63,17.55) v1(48.28,14.88) v1(48.35,4.47) v1(48.49,19.05) v1(48.49,18.18) v1(48.49,17.55) v1(48.73,80.8) v1(48.73,80.34) v1(49.73,69.62) v1(49.73,69.14) v1(49.75,70.08) v1(50.23,92.6) v1(50.23,91.97) v1(50.34,14.02) v1(50.58,93.24) v1(50.69,99.62) v1(50.69,99.06) v1(51.15,99.62) v1(51.15,99.06) v1(51.19,93.24) v1(51.61,99.62) v1(51.61,99.06) v1(52.24,80.8) v1(52.24,79.78) v1(52.27,148.78) v1(52.27,147.76) v1(52.27,146.75) v1(52.8,80.8) v1(53.28,149.8) v1(53.28,148.78) v1(53.28,147.76) v1(53.28,146.75) v1(54.3,149.8) v1(54.3,148.78) v1(54.3,147.76) v1(54.3,146.75) v1(54.74,9.79) v1(55.23,9.99) v1(55.23,9.48) v1(55.32,149.8) v1(55.32,148.78) v1(55.32,147.76) v1(55.32,146.75) v1(55.86,9.99) v1(55.86,9.48) v1(56.5,9.48) v1(58.34,9.63) v1(59.58,9.61) v1(61.12,9.81) v1(61.31,12.4) v1(61.31,11.76) v1(62.48,61.87) v1(62.48,60.99) v1(62.5,9.78) v1(63.04,63.32) v1(63.16,64.31) v1(63.49,61.87) v1(63.49,60.99) v1(64.28,136.12) v1(64.28,135.1) v1(64.28,134.09) v1(64.44,151.07) v1(64.44,150.05) v1(64.44,149.04) v1(64.44,148.02) v1(65.02,62.81) v1(65.3,135.1) v1(65.46,151.07) v1(65.46,150.05) v1(65.46,149.04) v1(66.31,136.12) v1(66.31,135.1) v1(66.31,134.09) v1(66.47,151.07) v1(66.47,150.05) v1(66.47,149.04) v1(66.47,148.02) v1(67.49,151.07) v1(67.49,150.05) v1(67.49,149.04) v1(74.97,2.96) v1(74.97,2.05) v1(80.46,124.27) v1(80.46,123.11) v1(81.22,123.69) v1(81.19,122.67) v1(81.22,121.35) v1(81.98,124.27) v1(81.98,123.11) v1(81.98,121.94) v1(84.39,153.84) v1(84.39,153.08) v1(84.39,152.32) v1(84.9,43.86) v1(85.16,153.84) v1(85.16,153.08) v1(85.16,152.32) v1(85.92,153.84) v1(85.92,153.08) v1(85.92,152.32) v1(86.65,92.68) v1(87.28,92.68) v1(87.71,93.9) v1(87.71,93.27) v1(87.76,91.97) v1(87.76,91.34) v1(88.86,123.66) v1(88.86,122.7) v1(88.86,121.73) v1(89.83,124.5) v1(89.83,123.66) v1(89.83,122.7) v1(89.83,121.73) v1(90.79,124.5) v1(90.79,123.66) v1(90.79,122.7) v1(90.79,121.73) v1(91.76,124.5) v1(91.76,123.66) v1(91.76,122.7) v1(91.76,121.73) v1(91.9,32.81) v1(92.2,32.46) v1(92.41,153.84) v1(92.41,153.08) v1(92.41,152.32) v1(92.47,32.83) v1(92.92,45.03) v1(92.89,44.43) v1(92.9,43.82) v1(93.18,153.84) v1(93.18,153.08) v1(93.18,152.32) v1(93.68,28.55) v1(93.71,27.88) v1(93.94,153.84) v1(93.94,153.08) v1(93.94,152.32) v1(94.45,28.53) v1(94.47,27.87) v1(96.84,85.67) v1(96.84,84.63) v1(96.84,83.62) v1(96.84,82.63) v1(96.84,81.61) v1(96.84,80.59) v1(96.84,79.55) v1(97.07,123.77) v1(97.07,122.6) v1(97.07,121.43) v1(97.63,124.35) v1(97.63,123.18) v1(97.63,122.01) v1(97.55,85.67) v1(97.55,84.63) v1(97.55,83.62) v1(97.55,82.63) v1(97.55,81.61) v1(97.55,80.59) v1(97.55,79.55) v1(97.55,78.54) v1(98.26,85.67) v1(98.26,84.63) v1(98.26,83.62) v1(98.26,81.61) v1(98.26,80.59) v1(98.26,79.55) v1(98.26,78.54) v1(98.59,123.77) v1(98.59,122.6) v1(98.59,121.43) v1(99.99,141.05) v1(99.99,140.08) v1(99.99,139.12) v1(99.99,138.15) v1(100.95,141.05) v1(100.95,140.08) v1(100.95,139.12) v1(100.95,138.15) v1(101.77,153.95) v1(101.79,153.08) v1(101.77,152.22) v1(101.92,141.05) v1(101.92,140.08) v1(101.92,139.12) v1(101.92,138.15) v1(102.53,153.95) v1(102.53,152.22) v1(102.56,153.08) v1(102.88,141.05) v1(102.88,140.08) v1(102.88,139.12) v1(102.88,138.15) v1(103.29,153.95) v1(103.32,153.08) v1(103.29,152.22) v1(109.82,153.95) v1(109.81,153.08) v1(109.82,152.22) v1(110.58,153.95) v1(110.58,153.08) v1(110.58,152.22) v1(111.35,153.95) v1(111.34,153.08) v1(111.35,152.22) v1(116.84,44.48) v1(125.34,45.03) v1(125.34,44.5) v1(125.34,43.99) v1(129.04,78.58) v1(129.05,78.1) v1(131.58,150.38) v1(131.58,146.82) v1(132.35,150.38) v1(132.34,146.82) v1(133.11,150.38) v1(133.1,146.82) v1(133.98,75.16) v1(133.97,74.4)
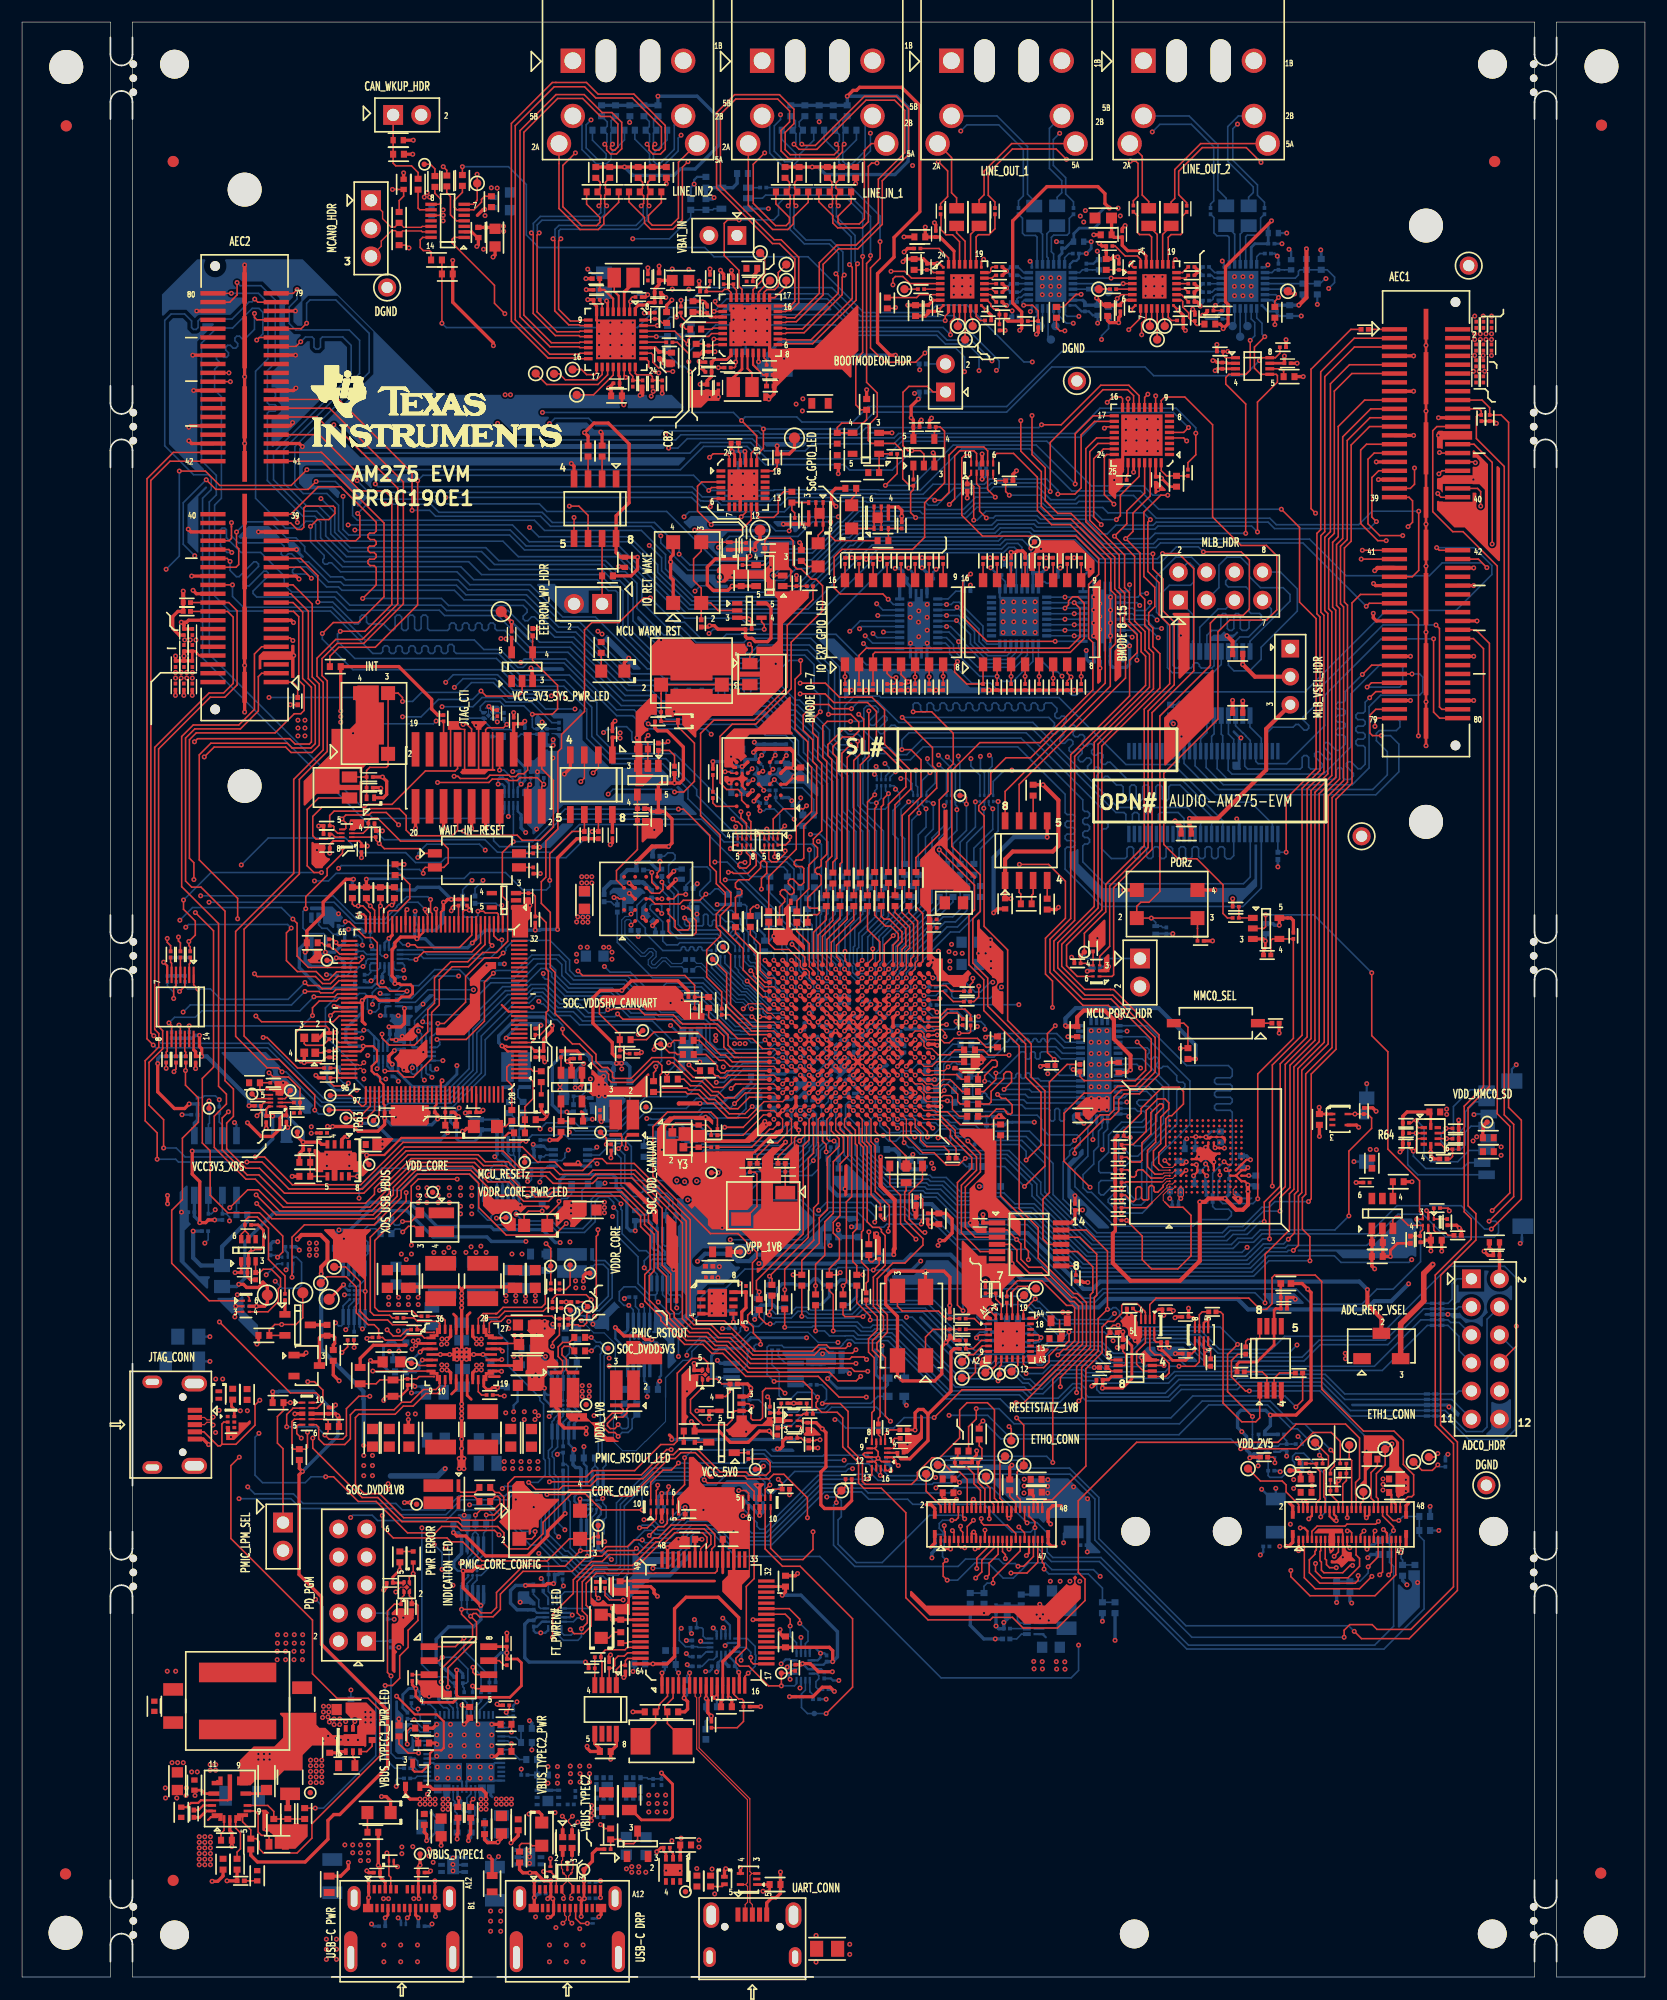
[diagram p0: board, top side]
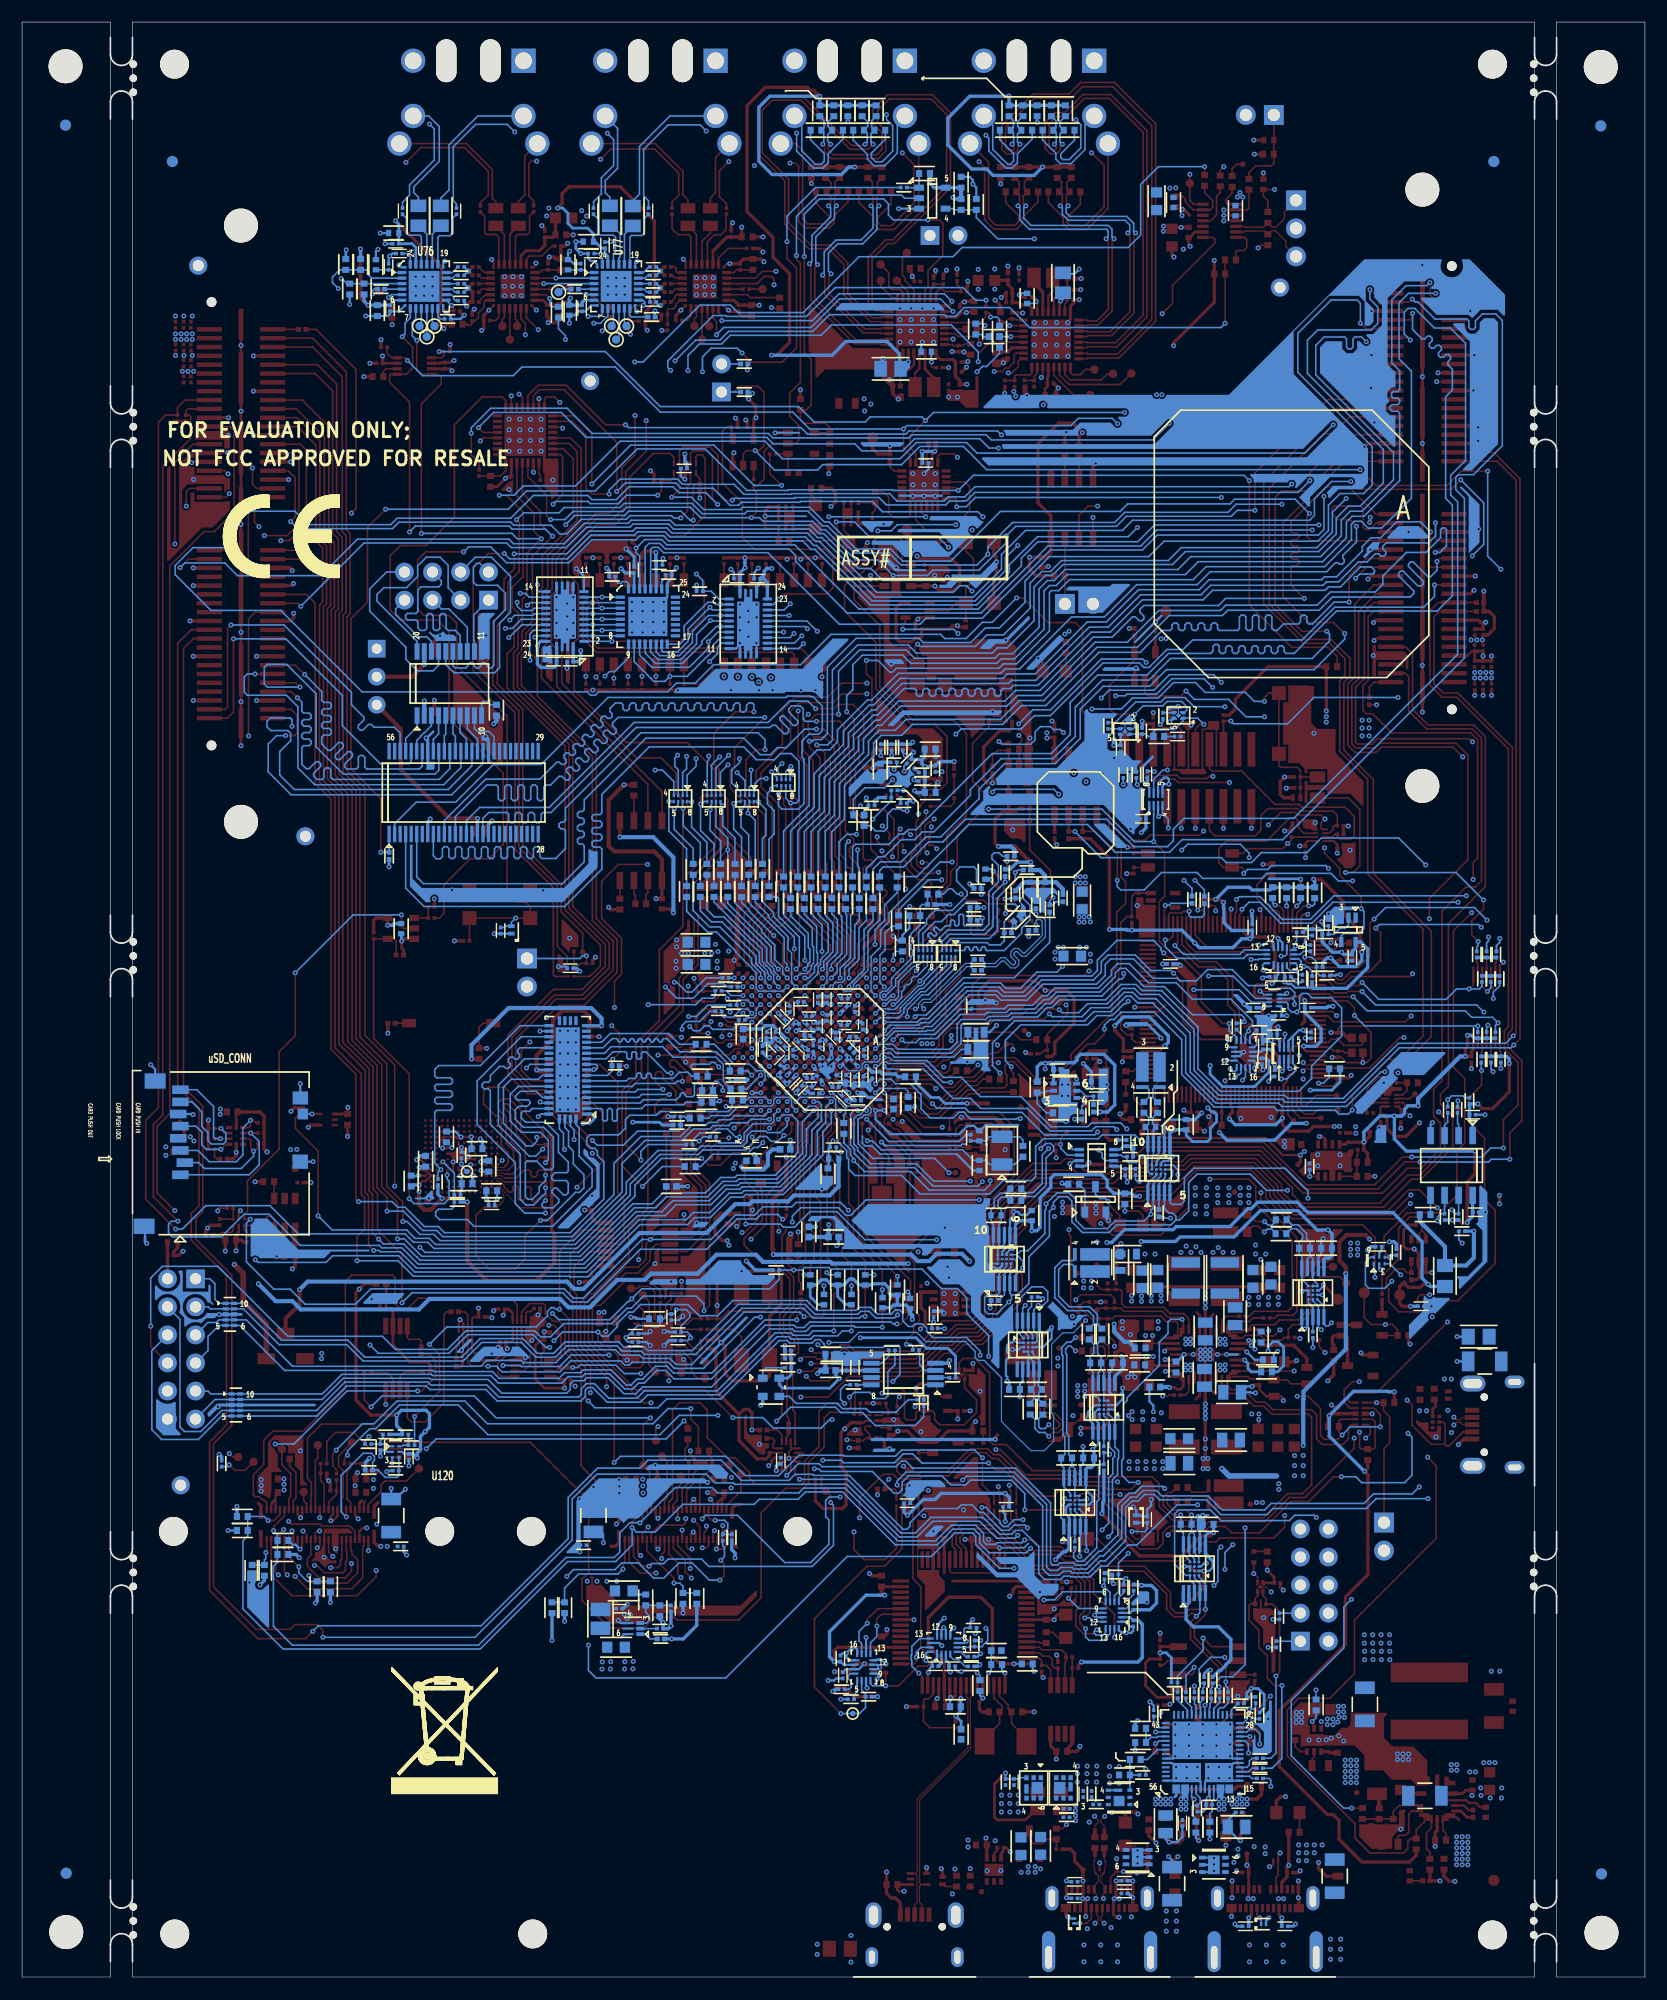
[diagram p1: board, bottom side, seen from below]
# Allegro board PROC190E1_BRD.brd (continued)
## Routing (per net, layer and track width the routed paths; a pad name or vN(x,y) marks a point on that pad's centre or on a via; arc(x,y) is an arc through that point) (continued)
DVDD1V8_ALERT: length 38.4
  TOP w0.147: R305.1 29.49,57.06 v1(28.97,56.54)
  L03_SIG1 w0.091: v1(29.76,41.61) 29.76,55.75 v1(28.97,56.54)
  BOTTOM w0.147: v1(29.76,41.61) 29.96,41.81 31.72,41.81 32.2,41.33 38.4,41.33 39.36,42.29 42.23,42.29 42.6,41.92 42.6,37.38 41.59,36.36 U123.A3 41.21,35.94 40.81,35.54 U124.3
DVDD3V3_ALERT: length 4
  BOTTOM w0.147: R505.1 55.56,60.71 55.86,60.41 U91.3 55.86,58.57 55.57,58.27 55.57,58.27 55.46,58.16 U92.A3
DVDD3V3_N: length 8.3
  TOP w0.147: v1(53.99,48.95) 53.99,49 53.69,49.3 53.14,49.3 52.67,49.77 52.67,50.27 53.45,51.05 54.28,51.05 54.43,51.2 54.43,51.4 54.08,51.76 R327.4
  BOTTOM w0.147: v1(53.99,48.95) 54.35,49.3 54.9,49.3 55.26,49.66 55.26,50.5 R539.2
DVDD3V3_P: length 7.1
  TOP w0.147: v1(53.99,50.01) 53.99,49.96 53.69,49.65 53.28,49.65 53.02,49.91 53.02,50.12 53.6,50.7 54.43,50.7 54.78,51.05 54.78,51.44 55.1,51.76 R327.1
  BOTTOM w0.147: v1(53.99,50.01) 54.35,49.65 54.75,49.65 54.91,49.81 54.91,50.56 R540.2
VBAT_IN: length 28.8
  TOP w0.254: v1(54.5,142.34) 54.34,142.51 C100.1 54.34,143.82 54.13,144.03 C95.1 54.13,144.9 54.04,144.98 U8.21
  L04_PWR1 w0.381: J7.1 63.33,159.11 58.87,159.11 55.72,155.96 55.72,150.32 55.89,150.15 55.89,144.47 54.5,143.08 v1(54.5,142.34)
VBUS_TYPEC1: length 15.2
  TOP w0.254: C326.1 J24.A9 35.89,7.13 ; v1(32.89,5.35) 33.14,5.6 J24.B9 ; J24.A4 32.89,8.59 ; J24.B4 35.64,5.6
  TOP w0.305: 32.89,8.59 32.42,9.06 C327.1 32.42,9.95 v1(32.26,10.11) R3933.1 ; 35.64,5.6 v1(35.89,5.35) ; C326.1 35.89,9.96 v1(36.05,10.12) TP107.1 ; D5.1 34.73,16.52 35.15,16.1 v1(36.04,16.1)
  BOTTOM w0.305: C654.1 v1(35.89,5.35) ; C655.1 v1(32.89,5.35)
  vias: v1(32.73,7.09) v1(33.19,7.09) v1(34.4,11.77) v1(34.4,11.16) v1(35.39,11.8) v1(35.48,7.09) v1(35.94,7.09) v1(36.04,15.65) v1(36.5,16.1) v1(36.5,15.65) v1(36.72,16.55) v1(36.87,11.57) v1(36.87,10.96) v1(36.95,16.1) v1(36.95,15.65) v1(37.24,10.38) v1(37.41,16.1) v1(37.41,15.65)
VBUS_TYPEC2: length 24
  TOP w0.254: 47.89,7.37 J25.A4 v1(47.89,8.7) ; v1(50.64,5.48) J25.B4 50.64,6.84 50.89,7.09 J25.A9 v1(50.89,8.7) ; 47.88,5.41 48.14,5.68 J25.B9 48.14,7.01
  TOP w0.305: D5.2 36.93,17.26 37.19,17 41.64,17 42.03,16.62 v1(42.03,16.1) ; 47.88,5.41 v1(47.63,5.41) ; v1(47.89,8.7) 47.26,8.7 46.53,9.43 v1(46,9.43) 45.36,9.43 45.06,9.73 R402.1 ; 47.89,7.37 v1(47.61,7.09) ; R401.2 52.04,11.57 51.66,11.19 51.66,10.49 TP108.1 v1(50.89,8.7) ; v1(48.07,7.09) 48.14,7.01
  BOTTOM w0.254: 41.82,16.27 41.82,16.86 U129.3 41.65,16.43 ; 41.57,16.94 41.49,16.86 41.49,16.27
  vias: v1(41.57,16.1) v1(41.57,15.65) v1(41.57,15.19) v1(42.03,15.65) v1(42.03,15.19) v1(46.51,5.44) v1(50.48,7.09) v1(50.94,7.09) v1(56.77,16.47) v1(56.77,15.7) v1(56.77,14.94) v1(57.53,16.47) v1(57.53,15.7) v1(57.53,14.94) v1(58.29,16.47) v1(58.29,15.7) v1(58.29,14.94)
VCC1V8_CLKBUF: length 30.3
  L03_SIG1 w0.305: v1(71.06,57.88) 71.06,55.19 72.08,54.18 v1(72.97,54.18)
  BOTTOM w0.254: C265.1 C266.2 77.35,55.64 R329.2 77.35,54.52 77.65,54.22 U62.4 78.41,53.63 78.1,53.31 73.83,53.31 v1(72.97,54.18) 73.31,54.52 FL10.1 72.83,54.92 C286.2 C284.2 71.23,54.92 U65.6 ; v1(71.06,57.88) 66.02,57.88 65.07,56.92 63.14,56.92 62.44,56.22 R348.2
VCC1V8_SYS: length 486.6
  TOP w0.178: C151.2 102.74,57.48 102.56,57.66 U29.8 ; U39.1 30.54,102.86 ; U3083.1 106.24,56.72 105.96,56.44 C3769.2
  TOP w0.203: U49.N4 U49.P5 110.79,73.05 v1(111.03,73.29) ; U49.N4 U49.M4 ; U49.N4 U49.P3 110.75,72.05 111.03,71.76 v1(111.03,71.71) ; C3729.2 30.74,102.65 30.54,102.86 ; U49.C6 105.21,73.55 v1(105.46,73.8) ; U2353.3 C3721.2
  TOP w0.229: C37.1 127.61,67.21 127.38,67.45 U2.5
  TOP w0.254: U21.31 C126.2 ; R5761.1 103.97,134.94 v1(103.22,135.69) ; U12.1 C102.2 ; U6.6 99.82,151.82 99.48,151.48 C73.1 ; v1(43.07,53.37) 42.59,53.37 42.44,53.21 42.08,53.21 41.82,53.48 U56.18 ; U21.27 v1(100.68,136.25) ; 98.39,54.08 98.68,54.37 U2347.8 ; U43.5 96.52,91.09 v1(96.49,91.06) ; R268.1 53.36,74.19 v1(53.33,74.17) ; v1(108.07,145.44) 108.24,145.61 C101.1 U11.3 ; v1(97.86,53.31) 99.69,53.31 100.53,54.15 100.53,57.15 99.96,57.71 R5795.1 ; 43.45,57.86 U56.26 ; v1(133.55,140.67) 133.34,140.87 R465.1 R464.1 ; 79.59,46.91 79.29,47.21 C3721.2 ; U5.6 82.53,151.82 ; v1(103.04,56.9) 103.19,56.74 103.29,56.74 104.21,55.83 105.38,55.83 ; R5808.2 v1(80.89,49.53)
  TOP w0.305: v1(87.05,69.03) C164.1 U3077.1 ; v1(127.61,65.74) C37.1 127.13,66.71 126.94,66.52 R17.2 ; R18.2 129.94,68.07 v1(130.19,67.81) 130.36,67.64 R5213.2 ; R69.1 v1(116.04,144.9) ; R5744.2 51.27,139.5 v1(50.94,139.83) 51.81,140.69 53.1,140.69 54.98,138.81 54.98,133.48 53.81,132.3 U2358.8 53.81,128.96 54.22,128.55 C3733.1 v1(55.75,128.55) 55.75,127.46 55.15,126.86 R5746.2 ; R288.1 49.75,61.11 v1(49.29,61.11) R291.1 ; R5698.2 56.74,105.79 57.01,105.51 57.61,105.51 C3705.1 ; R259.1 53.72,83.34 53.46,83.6 53.46,84.61 51.71,86.36 51.71,88.65 52.39,89.33 v1(54.32,89.33) 55.19,90.19 59.41,90.19 60.36,89.24 R301.1 ; v1(103.22,135.69) 103.06,135.84 C126.2 ; U28.D1 69.19,109.46 v1(69.92,109.46) 70.48,109.46 C149.2 ; R115.1 v1(109.66,97.62) ; U27.5 C148.1 v1(64.31,125.93) 63.93,125.55 62.59,125.55 62.07,126.07 62.07,127.66 62.81,128.4 R124.2 65.68,128.4 v1(65.93,128.65) ; R242.1 95.32,92.07 v1(95.06,92.33) ; v1(55,99.04) 55.43,98.61 U140.B4 ; U2352.8 v1(66.81,41.8) ; R123.2 v1(62.58,110.05) ; v1(117.49,78.74) 117.51,78.72 C102.2 ; R70.2 122.34,78.69 v1(122.65,78.38) ; R5699.2 v1(59.1,108.1) ; v1(59.1,108.1) 59.57,108.1 59.9,108.43 59.9,111.37 58.44,112.83 57.57,112.83 57.32,113.08 R615.1 ; v1(59.1,108.1) 57.84,108.1 57.64,107.9 U2348.5 C3705.1 ; 82.06,50.95 82.06,48.56 80.41,46.91 79.59,46.91 ; 82.06,50.95 84.14,53.04 84.14,56.61 84.42,56.88 R75.1 ; 82.06,50.95 81.63,51.39 81.2,51.39 80.89,51.08 v1(80.89,49.53) ; v1(73.4,27.64) 72.13,27.64 71.39,28.37 v1(70.69,28.37) 70.6,28.28 R361.1 ; U3087.5 C3774.2 v1(60.87,55.55) ; 98.39,54.08 97.89,54.08 C3704.2 97.88,53.33 v1(97.86,53.31) ; v1(32.49,107.63) 32.44,107.68 R559.1 ; v1(58.56,102.36) 58.87,102.67 58.87,104.84 58.18,105.53 C3705.1 ; v1(70.15,126.9) R122.2 ; C151.2 103.17,57.02 v1(103.04,56.9) ; v1(65.22,109.6) 65.33,109.6 U28.E4 ; R117.1 115.16,95.66 114.93,95.89 114.63,95.89 114.63,95.89 U26.5 v1(113.89,95.22) ; v1(73.58,25.86) 73.2,26.23 72.49,26.23 71.63,25.38 69.52,25.38 v1(69.51,25.38) ; v1(33.54,82.64) 33.23,82.95 33.23,83.38 v1(33.72,83.87) ; U28.B4 66.15,107.42 66.15,107.42 v1(66.16,107.42) ; R5798.1 89.76,136.06 v1(90.07,136.37) ; R684.1 R685.1 14.11,123.64 13.64,123.17 13.64,122.09 14.24,121.49 C160.1 ; C3769.2 105.68,56.13 105.38,55.83 ; R166.1 96.01,62.99 96.11,62.89 v1(96.54,62.89) ; v1(62.24,50.52) C3773.1 62.24,51.26 U3086.5 ; U2351.8 v1(57.94,43.79) ; R5796.1 99.28,58.42 v1(99.71,58.42) R5795.1 ; R375.1 v1(107.83,93.81) ; v1(32.64,103.77) 32.04,103.77 R225.1 32.03,104.08 31.92,104.19 R220.1 ; U2346.8 v1(86.96,137.9) ; U140.D1 v1(57.11,95.19) ; v1(97.33,152.01) 97.97,151.37 C76.1 98.98,151.37 C73.1 ; 82.53,151.82 C72.1 81.58,151.37 C75.1 v1(80.23,151.37) ; R83.1 v1(87.26,62.99) ; R262.1 99.02,75.95 R263.1 R264.1 R266.1 R267.1 R269.1 R270.1 R275.1 99.02,67.55 98.8,67.32 ; U2355.5 C3728.2 ; R5797.1 v1(85.62,133.91) ; 59.2,99.28 U140.E4 ; C3729.2 v1(31.27,102.4)
  TOP w0.381: v1(116.34,156.46) 116.34,152.06 v1(115.65,151.37) ; v1(24.94,66.8) 25.32,67.18 27.04,67.18 27.66,66.56 27.66,64.86 27.09,64.29 v1(27.09,63.68) ; v1(55.64,100.94) 57.07,102.36 v1(58.56,102.36) ; v1(69.92,109.46) 69.92,110.87 69.59,111.2 66.57,111.2 v1(66.25,110.89) ; 98.8,67.32 98.8,64.64 100.4,63.04 104.89,63.04 106.68,64.83 v1(106.68,70.17) 107.15,70.17 107.46,70.49 v1(108.96,70.49) 109.98,69.47 110.58,69.47 111.05,69.94 v1(111.05,71.11) 111.03,71.13 v1(111.03,71.71) ; R684.1 v1(14.6,125.48) ; C3701.1 v1(110.57,115.53)
  L03_SIG1 w0.305: v1(49.29,61.11) 48,62.41 48,66.62 47.56,67.06 47.56,69.03 48,69.47 48,70.92 48.53,71.46 48.53,73.15 v1(46.3,75.39) ; v1(32.63,90.09) 33.27,89.46 33.27,88.6 32.87,88.2 32.87,87.46 v1(32.45,87.04) 32.07,86.66 32.07,84.38 32.58,83.87 v1(33.72,83.87) ; v1(31.27,102.4) v1(32.64,103.77) 32.64,104.2 32.49,104.35 v1(32.49,107.63)
  L03_SIG1 w0.381: v1(60.87,55.55) 63.16,53.26 63.16,51.44 v1(62.24,50.52) 63.11,49.65 63.11,44.37 64.88,42.61 65.99,42.61 v1(66.81,41.8) ; v1(66.25,110.89) 66.25,111.72 v1(66.33,111.8) ; v1(43.76,143.26) 43.12,142.62 43.12,141.45 43.65,140.92 43.65,140.41 43.5,140.26 43.5,121.78 43.38,121.65 v1(43.38,121.18) ; v1(105.46,73.8) 105.38,73.8 104.86,73.27 104.86,72 v1(106.68,70.17)
  L03_SIG1 w0.508: v1(38.32,46.03) 38.32,45.96 40.39,43.89 41.39,43.89 41.9,44.4 41.9,52.2 v1(43.07,53.37) 42.69,53.74 42.69,57.32 v1(44.09,58.71) v1(44.09,59.35)
  L04_PWR1 w0.305: 46.78,59.64 45.85,58.71 v1(44.09,58.71)
  L04_PWR1 w0.381: v1(103.04,56.9) 103.04,58.01 102.79,58.27 ; v1(44.09,59.35) 44.37,59.35 45,58.71 ; v1(58.56,102.36) 58.56,103.43 58.46,103.53
  BOTTOM w0.203: C371.1 113.67,151.42 113.27,151.82 U76.6 ; 63.04,28.45 63.32,28.73 U125.3 ; U90.1 44.9,105.54 45.2,105.23 ; U102.1 33,87.9 32.9,87.8 C511.2 v1(32.45,87.04) ; C414.2 23.84,65.79 24.07,65.56 U86.5 ; 47.25,75.22 47.55,74.92 U98.8 ; v1(32.63,90.09) 32.62,90.09 32.61,90.08 32.54,90.08 32.37,89.91 32.02,89.91 31.68,89.57 30.18,89.57 30.15,89.6 ; v1(70.69,28.37) 71.19,27.87 U126.3 72.38,27.87 C617.2 ; U77.6 96.08,151.82 ; C528.2 33.46,82.1 33.09,82.47 U109.1 ; C470.2 32.63,90.82 32.83,91.03 U97.3 ; U110.3 34.77,83.77 34.61,83.92 C3725.2
  BOTTOM w0.254: R5716.2 57.37,94.93 v1(57.11,95.19) ; R5753.2 v1(55.82,94.21) ; R598.1 89.02,77.14 89.27,77.39 89.69,77.39 89.69,77.39 v1(91.69,77.39) ; R447.2 69.79,106.07 69.79,106.43 v1(69.72,106.5)
  BOTTOM w0.305: v1(23.16,66.57) 22.73,66.57 22.51,66.35 R480.1 ; v1(32.63,90.09) 32.63,90.12 32.63,90.12 C470.2 ; v1(113.89,95.22) 113.45,95.22 113.3,95.38 C146.1 ; 47.25,75.22 C478.2 46.46,75.22 v1(46.3,75.39) 46.3,74.96 46.36,74.89 R550.1 ; C3707.1 57.11,95.54 v1(57.11,95.19) ; v1(81.4,64.82) 80.58,64.01 R603.1 ; v1(66.25,110.89) 66.28,110.89 66.44,110.72 66.44,110.26 ; v1(108.96,70.49) 109.33,70.86 R575.1 ; C3718.1 57.58,43.43 v1(57.94,43.79) 63.75,43.79 64.31,43.23 65.37,43.23 v1(66.81,41.8) 67.11,42.1 C3719.1 ; 65.48,110.24 65.48,109.85 v1(65.22,109.6) ; 65.48,110.24 65.24,110.48 C388.1 ; 65.48,110.24 66.42,110.24 66.44,110.26 ; v1(65.22,109.6) 64.78,109.6 64.69,109.69 R448.2 64.27,109.7 63.93,110.04 63.74,110.04 63.73,110.05 v1(62.58,110.05) ; v1(65.22,109.6) R449.2 65.23,109.06 R452.2 C390.1 65.98,107.24 66.15,107.42 66.15,107.42 v1(66.16,107.42) ; R631.1 v1(69.51,25.38) ; 66.44,110.26 R446.2 ; 45.2,105.23 C3726.2 45.2,104.04 v1(45.62,103.63) ; R533.2 30.72,94.86 R534.2 v1(29.57,94.86) 29.4,94.86 29.22,94.68 R536.2 29.22,93.7 28.31,92.79 v1(27.48,92.79) 27.27,92.58 C455.2 26.5,92.86 26.21,93.15 U93.5 25.75,93.71 25.11,93.07 25.11,91.39 26.99,89.51 30.06,89.51 30.15,89.6 R554.2 ; R612.1 60.54,31.2 v1(60.65,31.1) ; R443.2 R444.2 R445.2 66.51,111.61 v1(66.33,111.8) ; U83.23 79.49,126.27 79.84,126.61 80.12,126.61 ; R5712.2 57.49,100.3 56.85,100.94 v1(55.64,100.94) ; R565.1 v1(106.68,70.17) ; R419.2 v1(116.34,156.46) ; 80.12,126.61 79.78,126.96 79.78,127.28 79.52,127.53 v1(79.09,127.53) ; 80.12,126.61 C395.1 80.13,126.21 80.47,125.87 U83.24 ; R611.1 v1(60.17,30.47) ; v1(86.96,137.9) 86.96,137.25 86.77,137.05 C3703.1 ; R423.2 116.02,151.74 v1(115.65,151.37) C373.1 C371.1 ; C3725.2 33.84,83.98 v1(33.72,83.87) ; v1(111.03,71.71) 111.62,71.71 C518.1 ; v1(69.72,106.5) 69.43,106.79 R454.2 ; 96.08,151.82 96.27,151.63 C372.1 C374.1 97.43,151.92 v1(97.33,152.01) ; C503.1 110.96,73.36 v1(111.03,73.29) ; U81.24 98.58,119.59 C408.1 98.58,118.81 98.82,118.57 100.02,118.57 100.32,118.88 v1(100.32,120.52) 100.32,120.63 100.02,120.93 U81.23 ; C528.2 v1(33.54,82.64) ; 63.04,28.45 C608.2 63.04,27.74 v1(62.91,27.62) ; R5810.2 v1(62.96,97.1) ; v1(60.25,28.28) 60.41,28.12 R614.2 ; v1(69.92,109.46) 69.92,109.55 69.62,109.85 C389.1 69.21,109.85 69.08,109.98 R450.2 ; v1(96.49,91.06) 96.77,91.34 C421.2 ; v1(73.58,25.86) 73.5,25.86 73.31,26.05 R636.2
  BOTTOM w0.381: C555.1 43.12,53.42 v1(43.07,53.37) ; v1(104.28,113.46) 104.03,113.72 R5684.2 ; R5713.2 v1(61.13,96.24) R5711.2 ; v1(61.16,98.98) 60.77,98.6 R5714.2 ; v1(27.09,63.68) 27.09,56.85 30.92,53.02 30.92,52.34 30.95,52.31 v1(30.95,48.13) ; v1(105.46,73.8) 105.35,73.9 C514.1 ; R5693.2 52.72,98.5 53.34,99.12 C3709.1 ; C3709.1 54.93,99.12 v1(55,99.04) 55.08,99.12 C3706.2 56.23,99.12 56.3,99.04 56.33,99.04 57.02,98.36 R5715.2 ; C3709.1 54.34,99.73 54.83,100.23 R5710.2 v1(55.64,100.94) ; v1(59.2,99.34) 59.25,99.39 C3708.1 ; v1(58.56,102.36) 57.42,102.36 57.12,102.06 R5717.2 ; U2345.2 v1(110.57,115.53)
  BOTTOM w0.508: v1(38.32,46.03) 37.66,45.36 33.38,45.36
  vias: v1(14.73,121.06) v1(15.23,121.06) v1(15.74,121.06) v1(24.88,132.16) v1(24.94,131.7) v1(24.99,113.79) v1(24.99,113.08) v1(24.99,112.37) v1(25.62,113.79) v1(25.62,113.08) v1(25.62,112.37) v1(26.03,66.45) v1(26.03,65.89) v1(26.03,65.35) v1(26.66,66.45) v1(26.66,65.89) v1(26.66,65.35) v1(30.95,47.22) v1(30.95,46.3) v1(30.95,45.39) v1(31.74,47.22) v1(31.74,46.3) v1(31.74,45.39) v1(43.83,121.16) v1(44.24,143.26) v1(70.12,142.41) v1(70.72,142.89) v1(70.68,141.79) v1(94.28,60.2) v1(94.76,60.16) v1(131.47,145.38) v1(131.98,145.38) v1(132.48,145.38)
VCC1V8_SYS_N: length 2.6
  TOP w0.147: R334.4 39.53,43.3 39.77,43.54 40.93,43.54 41.42,43.05 R335.2
VCC1V8_SYS_P: length 2.6
  TOP w0.147: R331.2 41.42,44.29 41.03,43.89 39.73,43.89 39.53,44.09 R334.1
VCC1V8_SYS_SW: length 1.5
  TOP w0.254: U56.13 39.32,53.2 38.91,52.78
VCC1V8_TA: length 67
  TOP w0.203: U51.1 23.84,78.82 23.94,78.71 C236.2
  TOP w0.254: R128.2 v1(89.59,128.99)
  TOP w0.305: R129.2 90.86,128.9 90.64,129.11 90.14,129.11 90.02,128.99 v1(89.59,128.99) ; R132.2 v1(95.3,128.5) R133.2 ; v1(12.29,82.7) 12.29,80.14 13.8,78.63 14.72,78.63 v1(15.13,79.05) ; R127.2 v1(87.68,128.5) R126.2 ; C236.2 23.92,78.03 23.64,78.03 23.36,77.75 23.36,76.81 22.66,76.11 21.65,76.11 v1(20.41,77.34) ; R131.2 v1(92.76,128.5) R130.2 ; U23.5 C136.1 80.74,140.98 v1(80.53,141.18) 80.53,142.21 v1(81.19,142.87) ; R134.2 v1(75.16,128.5) R135.2 76.33,128.5 v1(76.47,128.36) 76.61,128.5 R136.2 77.57,128.5 v1(77.71,128.36) 77.84,128.5 R137.2 R138.2 R139.2 81.12,128.5 81.13,128.52 81.51,128.52 v1(81.53,128.5) R140.2 R141.2
  BOTTOM w0.254: U82.27 89.56,127.37 ; C393.2 U82.31
  BOTTOM w0.305: U83.1 81.97,126.14 C394.2 81.97,127.14 v1(81.52,127.59) 81.52,128.02 81.53,128.03 v1(81.53,128.5) ; R461.2 v1(85.9,126.02) ; v1(81.19,142.87) 81.31,142.99 81.31,143.51 ; v1(96.4,120.11) 96.4,119.35 96.65,119.09 C409.2 U81.1 ; R457.2 93.82,127.34 v1(94.04,127.56) ; 89.56,127.37 C391.2 89.56,128.3 89.59,128.33 v1(89.59,128.99) ; U107.1 15.61,77.3 15.89,77.58 C529.2 R582.1 v1(15.13,79.05) ; R511.1 R516.1 R526.1 ; v1(12.29,82.7) 12.29,83.13 12.51,83.36 R507.1 R513.1 R524.1 ; v1(92.75,127.51) 92.36,127.13 C393.2 ; R583.1 v1(15.5,67.53)
  BOTTOM w0.381: v1(15.5,67.53) 15.5,65.12 16.2,64.42 R643.2 18.11,66.13 20.4,68.42 R578.1
  vias: v1(80.84,143.38)
VCC2V5_PG: length 1.5
  BOTTOM w0.147: U127.2 R637.1
VCC3V3_XDS: length 215.6
  TOP w0.203: v1(79.37,46.3) 79.1,46.57 79.1,46.78 78.81,47.06 U2353.2 ; U48.52 35.93,94.18 36.33,94.58 U48.51 ; U48.39 41.13,93.97 v1(40.78,93.62) ; U48.113 37.53,78.97 37.38,78.82 37.38,78.29 C232.1 ; U40.14 15.54,83.94 ; U48.16 44.05,87.41 43.45,88.01 ; U48.79 30.62,88.21 v1(30.82,88.41) ; C231.2 32.84,78.94 32.73,79.04 U48.101 32.73,80.8 32.43,81.1 32.43,81.46 32.15,81.74 31.95,81.74 31.67,82.02 31.67,82.45 32.15,82.93 32.15,83.91 31.78,84.28 v1(30.9,84.28) 30.88,84.25 30.88,84.01 30.68,83.81 U48.90 ; U48.7 43.97,83.81 v1(43.48,84.3) 43.86,84.3 43.95,84.21 U48.8 46.11,84.21 C221.1 ; U48.69 28.52,92.21 v1(28.46,92.27) ; U51.8 22.35,78.82 22.12,78.59 C235.2 ; U48.47 37.93,96.41 38.17,96.65 ; C234.1 U48.122
  TOP w0.254: v1(33.77,89.94) 34.18,89.94 34.28,89.84 35.2,89.84 35.37,89.66 35.37,89.05 35.08,88.75 34.37,88.75 34.03,88.41 32.32,88.41 31.98,88.75 31.62,88.75 31.59,88.77 31.18,88.77 v1(30.82,88.41)
  TOP w0.305: v1(16.07,85.26) 16.07,84.24 16.26,84.05 v1(16.26,83.36) C192.1 15.72,83.77 15.54,83.94 ; v1(17.44,68.55) 16.87,68.55 16.63,68.3 v1(16.1,68.3) 16.1,72.01 15.41,72.69 v1(15.41,74.78) ; v1(28.13,77.01) 30.02,77.01 30.45,76.58 32.23,76.58 32.84,77.18 v1(32.84,77.76) C231.2 ; v1(41.75,78.48) 41.56,78.29 C234.1 ; C221.1 C222.1 47.24,84.92 48.02,85.7 v1(48.02,86.13) ; v1(25.46,75.59) 26.93,75.59 27.12,75.39 U55.4 ; v1(25.46,75.59) 24.93,76.11 TP68.1 ; v1(25.46,75.59) C243.1 25.12,74.57 R306.1 ; R280.1 v1(20.55,78.88) ; U25.8 C147.1 ; 35.93,94.18 v1(35.76,94) 35.61,94.16 34.28,94.16 33.77,93.65 33.77,93.29 33.51,93.03 33.51,90.63 33.77,90.37 v1(33.77,89.94) ; 38.17,96.65 v1(38.17,97.31) 38.29,97.31 38.55,97.57 v1(38.88,97.57) R236.1 R237.1 ; v1(30.02,99.39) 29.35,99.39 27.27,97.31 27.27,96.19 25.8,94.71 R246.2 25.8,92.94 v1(25.65,92.79) ; R241.1 v1(46.48,94.78) ; 58.64,49.07 58.84,48.87 v1(58.84,48.67) ; v1(30.82,88.41) 30.82,86.52 31.08,86.26 ; C232.1 37.64,78.03 v1(37.64,77.69) ; v1(48.51,94.84) 48.51,101.32 50.25,103.06 R118.1 R119.1 ; v1(34.63,87.7) 34.63,86.33 34.33,86.03 v1(33.23,86.03) ; C235.2 v1(22.7,77.95)
  L03_SIG1 w0.381: 50.46,70.43 49.73,71.17 49.73,74.17 50.18,74.63 ; v1(41.75,78.48) 40.52,77.24 38.09,77.24 v1(37.64,77.69)
  BOTTOM w0.203: C515.2 33.31,84.99 33.09,84.77 U109.8 ; C469.2 33.23,90.76 U97.2 ; v1(34.63,87.7) 34.44,87.9 U102.8
  BOTTOM w0.305: v1(16.07,85.26) 15.69,85.26 15.43,84.99 R525.1 R517.1 R512.1 ; R519.1 R515.1 R510.1 ; v1(30.9,84.28) 29.79,84.28 29.33,84.73 29.33,85.86 30.82,87.34 C488.1 v1(30.82,88.41) ; v1(16.1,68.3) 16.1,68.37 15.61,68.86 C473.2 U107.8 ; v1(33.23,86.03) 33.31,85.95 C515.2 ; v1(22.7,77.95) 22.01,77.95 21.79,78.18 21.79,78.54 21.44,78.88 v1(20.55,78.88) ; v1(22.7,77.95) 24.01,77.95 25.46,76.51 v1(25.46,75.59) ; v1(22.7,77.95) 22.7,75.88 21.6,74.78 v1(15.41,74.78) ; R549.2 29.2,91.85 28.77,92.27 v1(28.46,92.27) 27.68,91.49 26.18,91.49 25.65,92.03 v1(25.65,92.79) ; C500.2 34.7,87.76 v1(34.63,87.7) ; v1(43.48,84.3) 43.17,84.61 43.17,85.22 44.88,86.92 47.23,86.92 v1(48.02,86.13) ; C208.1 v1(43.68,91.72) ; v1(38.17,97.31) 38.17,96.77 38.14,96.75 38.14,95.48 37.42,94.76 C430.2 35.57,94.2 v1(35.76,94) 36.52,94 37.33,93.19 40.36,93.19 v1(40.78,93.62) 41.95,94.78 v1(46.48,94.78) 46.92,94.78 46.97,94.84 v1(48.51,94.84) ; v1(38.88,97.57) 37.78,98.66 35.82,98.66 35.58,98.42 33.97,98.42 R520.2 R521.2 R522.2 R523.2 29.92,99.22 30.02,99.31 v1(30.02,99.39) ; v1(33.77,89.94) 33.7,90.02 33.67,90.02 33.44,90.25 33.44,90.32 33.44,90.32 C469.2 ; 69.99,48.67 v1(58.84,48.67) ; v1(37.64,77.69) 37.12,77.17 33.43,77.17 v1(32.84,77.76) ; R551.1 v1(17.44,68.55) R552.1
  BOTTOM w0.381: v1(20.55,78.88) 20.55,79.54 16.73,83.36 v1(16.26,83.36)
  vias: v1(27.67,77.02) v1(53.48,68.86)
VCC_0V85: length 4.3
  TOP w0.147: 44.79,57.36 43.93,57.36 ; v1(45.23,58.08) 45.23,57.49 44.92,57.18 44.6,57.49 v1(44.6,58.08)
  TOP w0.254: 43.93,57.36 U56.25
VCC_1V8_FT4232: length 35.7
  TOP w0.254: 63.47,36.59 U64.37 C281.2 ; 63.47,28.56 U64.12 63.47,25.09 ; 54.19,35.85 U64.49 62.73,35.85 ; v1(57.15,28.35) U64.64
  TOP w0.305: 63.47,25.09 63.31,24.94 C280.2 ; 63.47,28.56 64.92,30.01 64.92,32.54 63.07,34.38 60.14,34.38 59.1,33.34 59.1,29.02 58.43,28.35 v1(57.15,28.35) ; 54.19,35.85 C263.1
  BOTTOM w0.147: C599.2 v1(57.15,28.35)
VCC_1V8_IOVDD: length 12.7
  TOP w0.254: U7.27 62.84,150.3 62.84,150.29 62.45,150.29 62.45,150.3 62.32,150.3 62.07,150.55 C74.1 61.49,150.67 v1(61.46,150.7)
  TOP w0.279: v1(61.46,150.7) 61.41,150.75 C71.1 ; U8.27 56.93,147.52 56.93,147.52 57.32,147.52
  TOP w0.305: R20.1 v1(62.31,154.65) ; C85.1 58.24,147.07 58.16,147.14 C84.1 57.69,147.16 57.33,147.52 57.32,147.52 ; R23.1 64.44,154.05 64.25,154.23 v1(64.25,154.51)
  BOTTOM w0.305: R413.2 64.77,162.39 64.38,162.01 U75.5 C340.1 ; R416.2 62.55,160.98 v1(62.68,161.11)
  BOTTOM w0.381: R416.2 C340.1
  vias: v1(56.99,143.13) v1(57.17,143.56)
VCC_3V3_AVDD: length 31.2
  TOP w0.254: 62.69,146.44 63.83,146.44 64.21,146.82 U7.1 ; U8.1 55.54,151.08 55.85,151.38 ; 64.42,144.79 65.21,145.58 U7.3 ; 54.54,152.56 U8.3
  TOP w0.305: L3.1 64.42,144.79 ; 55.85,151.38 56.53,151.38 56.75,151.61 C68.1 57.3,152.83 57.7,153.24 C52.1 58.89,153.61 FL2.2 ; 54.54,152.56 55.34,153.35 L2.1 ; 62.69,146.44 C86.1 62.46,144.93 62.05,144.53 C98.1 v1(61.42,144.21)
  L04_PWR1 w0.508: v1(61.42,144.21) 60.55,144.21 59.61,145.15 59.61,146.05 58.36,147.29 58.36,150.14 57.45,151.05 57.45,152.27 58,152.83 v1(58.89,152.83) v1(58.89,154.65)
VCC_3V3_FT4232: length 47.2
  TOP w0.254: C275.2 U64.42 ; U64.31 C289.2 ; U64.50 56.94,35.35 ; U64.20 C288.2 ; C264.2 U64.56
  TOP w0.305: v1(53.32,19.72) C262.2 53.83,20.93 U61.8 ; C288.2 73.12,29.85 73.43,29.54 v1(73.43,28.55) ; v1(51.03,28.51) 51.32,28.23 R321.2 ; R333.2 54.65,27.26 v1(54.5,27.12) ; C275.2 61.53,39.63 61.54,39.62 v1(61.59,39.62) ; v1(68.85,34.56) 69.15,34.86 C289.2 ; v1(57.55,34.47) 57.24,34.77 57.24,35.04 56.94,35.35 ; v1(53.3,29.16) 53.18,29.04 R328.2 ; C285.1 59.62,11.95 U66.1 ; C264.2 v1(53.5,32.35) 53.5,32.5 53.2,32.8 LD7.2
  BOTTOM w0.203: C618.2 72.59,28.27 U126.2 ; C575.2 46.63,32.57 U117.2 ; 63.72,28.42 U125.2
  BOTTOM w0.305: v1(68.85,34.56) 69.34,34.56 69.34,34.57 70.55,34.57 73.86,31.27 73.86,28.98 v1(73.43,28.55) C618.2 ; v1(51.03,28.51) 45.93,28.51 45.53,28.91 45.53,31.94 45.88,32.28 C575.2 ; C612.2 63.72,28.42
  vias: v1(58.86,12.34) v1(59.7,12.57)
VCC_3V3_SYS: length 401.4
  TOP w0.178: U39.8 28.2,102.86 ; C3768.2 106.09,59.77 106.24,59.62 U3083.8
  TOP w0.203: C277.1 124.04,43.66 J19.44 ; 28.2,102.86 27.87,102.53 C3730.2 ; v1(106.11,72.54) 106.46,72.88 U49.F5 106.46,73.46 v1(106.37,73.55) U49.E6 ; v1(108.91,75.05) U49.K9 108.42,75.08 v1(108.07,75.08) 107.96,75.2 U49.J10 ; J18.46 92.01,42.91 91.84,43.08 ; J18.44 91.61,43.58 ; U68.5 70.58,50.37 70.75,50.19 C293.1 ; U29.1 102.56,60.09 102.68,60.22 ; J19.46 124.44,42.79 124.33,42.9 124.33,43.01 124.12,43.22
  TOP w0.254: v1(86.47,47.64) 86.47,47.27 86.04,46.84 R343.2 ; 102.91,60.45 102.68,60.22 ; v1(65.47,138.13) 65.55,138.05 U18.21 ; 75.15,45.09 75.15,43.13 ; v1(64.33,138.13) 64.33,138.05 64.55,137.83 U18.23 ; U11.7 C99.1
  TOP w0.279: v1(100.4,82.12) 100.32,82.12 100.09,81.89 C787.1
  TOP w0.305: v1(41.74,37.16) 41.17,37.16 40.77,36.76 v1(39.95,36.76) 39.95,35.24 v1(41.56,33.63) ; R351.2 119.4,45.1 v1(119.24,44.94) 119.07,44.77 R356.1 ; R342.1 R343.2 ; v1(26.87,104.21) 26.9,104.24 R212.1 R211.1 ; R5688.2 68.05,49.06 v1(67.68,49.43) 66.79,49.43 65.78,48.41 64.14,48.41 63.12,49.43 R292.2 60.92,50 v1(60.63,50.29) ; v1(53.74,58.8) 54.04,58.5 54.07,58.5 54.52,58.04 56.13,58.04 56.47,57.71 v1(57.04,57.71) ; 75.15,43.13 74.44,42.42 72.69,42.42 72.36,42.75 72.36,45.72 72.81,46.18 72.81,49.3 v1(72.48,49.63) 71.93,50.19 C293.1 ; R98.2 64.23,138.23 v1(64.33,138.13) ; R5687.2 111.28,47.07 v1(111.21,46.99) ; R5742.1 93.67,96.65 v1(93.87,96.85) ; v1(49.19,41.96) 47.62,40.39 47.62,39.95 45.79,38.13 41.98,38.13 40.18,39.93 39.38,39.93 v1(39.07,40.23) ; v1(115.54,46.96) 115.72,46.78 R344.1 ; U25.1 C140.1 54.11,112.23 ; v1(96.06,69.44) C165.2 95.37,68.66 94.99,68.28 U3077.14 ; v1(70.43,129.87) 70.59,129.71 R440.2 ; 102.91,60.45 C150.2 103.29,60.12 103.42,59.99 v1(103.42,59.92) ; R363.2 v1(69.9,51.95) R362.2 ; R482.1 37.66,114.25 37.1,114.81 37.1,115.67 34.13,118.64 R5764.2 v1(28.86,114.63) ; R58.1 v1(108.23,147.81) ; v1(46.7,122.1) 46.65,122.1 46.65,122.09 R5735.2 ; v1(45.54,113.7) 45.31,113.47 C169.1 J14.5 ; R5759.2 v1(106.29,83.12) ; 91.61,43.58 91.39,43.8 C279.1 ; FL23.2 115.94,62.79 v1(116.45,62.28) 116.76,61.98 116.76,52.23 115.4,50.88 v1(113.07,50.88) ; C3660.1 95.62,77.85 v1(96.18,77.29) ; C99.1 v1(114.35,146.76) ; R5824.1 v1(72.08,47.9) ; U4.1 122.27,66.51 C33.2 122.28,65.25 C28.1 122.27,64.37 v1(122.52,64.11) ; C3768.2 v1(105.66,60.55) ; R5741.1 v1(92.48,107.95) ; U2357.1 C3732.2 v1(89.58,97.63) ; v1(73.73,133.15) 73.32,133.55 73.32,134.42 73.69,134.78 R180.2 ; R56.1 v1(114.49,148.24) ; C3730.2 v1(27.87,101.75)
  TOP w0.381: U2357.1 89.04,101.21 89.74,101.9 93.36,101.9 93.87,102.41 93.87,106.55 v1(92.48,107.95) ; C3698.1 105.91,104.05 105.75,104.21 v1(105.75,104.9) 108.29,104.9 112.69,109.3 112.69,113 J29.3 ; v1(94.51,86.13) 94.59,86.06 C3659.1 95.57,86.92 96.16,87.5 98.06,87.5 98.9,86.66 98.9,84.94 100.4,83.44 v1(100.4,82.12)
  L03_SIG1 w0.305: v1(72.48,49.63) 72.05,50.06 71.3,50.06 70.93,49.7 70.93,48.61 71.65,47.9 v1(72.08,47.9)
  L03_SIG1 w0.381: v1(39.39,82.52) 39.95,81.97 39.95,79.04 v1(39.59,78.69) ; v1(47.4,56.18) 48.08,55.51 48.08,51.08 v1(47.74,50.75) ; v1(45.64,66.6) 46.1,67.06 46.1,70.36 v1(45.76,70.69) 42.82,73.63 v1(42.82,74.27) ; v1(60.63,50.29) 57.75,53.16 v1(57.75,53.95)
  L03_SIG1 w0.508: v1(127.54,42.61) 129.15,44.22 v1(129.15,47.33)
  L04_PWR1 w0.381: v1(55.54,67.56) 55.54,63.37 53.74,61.57 v1(53.74,58.8)
  L04_PWR1 w0.508: 53.89,37.77 53.87,37.8 v1(53.38,37.8)
  BOTTOM w0.178: v1(47.74,50.75) 48,51.01 48,51.25 48.14,51.38 U115.B1
  BOTTOM w0.203: v1(57.75,53.95) 57.75,54.33 57.88,54.46 57.88,55.83 57.55,56.15 57.56,56.16 57.56,56.39 57.78,56.61 57.78,57.01 57.78,57.02 57.78,57.18 57.52,57.44 57.31,57.44 v1(57.04,57.71) 57.04,57.61 56.86,57.43 U92.B1 ; U120.5 112.58,47.55 112.4,47.37 C602.1 ; 57.02,68.17 U3078.6 57.02,66.04 57.22,65.84 57.52,65.84 57.81,65.55 57.81,65.39 U3080.B1 ; U123.B1 v1(39.95,36.76) 39.47,36.76 39.11,37.12 ; v1(45.2,108) 44.9,107.69 U90.8 ; U115.B3 49.42,51.38 49.43,51.37 49.57,51.37 49.84,51.11 49.84,50.51 49.51,50.18 U116.2 49.51,48.27 v1(50.01,47.77) ; v1(42.82,74.27) 43.2,73.89 43.6,73.89 43.85,73.64 U3081.B1 ; U92.C3 54.52,57.03 53.74,57.81 v1(53.74,58.8) ; U113.B1 v1(29.2,61.76) ; U110.2 35.1,83.37 34.91,83.18 C3724.2 ; U123.B3 U123.C3 v1(41.74,37.16) ; U119.B3 52.04,42.76 52.22,42.76 52.43,42.56 52.43,41.89 52.24,41.71 52.24,41.68 52.14,41.57 U118.2 ; U118.6 50.64,44.09 50.03,43.49 50.03,43.07 50.34,42.77 U119.B1
  BOTTOM w0.254: v1(43.05,113.64) 42.71,113.98 U87.5 ; v1(96.18,77.29) 95.57,77.29 95.22,77.65 95.22,77.98 95.37,78.13 U57.1 ; v1(45.2,108) 45.56,108.36 45.56,109.5 44.59,110.46 ; C3724.2 34.29,83.18 34.06,82.94 34.06,81.92 35.36,80.62 38.27,80.62 38.57,80.92 38.57,80.93 39.39,81.74 v1(39.39,82.52) ; v1(39.07,40.23) 39.54,40.23 39.81,39.97 U124.6 ; C3764.1 41.55,76.21 40.98,75.64 39.62,75.64 39.36,75.9 39.36,76.86 38.8,77.42 38.8,78.08 39.06,78.33 39.24,78.33 v1(39.59,78.69) ; U88.5 C416.2 ; U91.1 54.86,58.58 54.61,58.32 54.22,58.32 v1(53.74,58.8) ; U3072.17 v1(105.75,104.9) ; U57.30 100.38,82.13
  BOTTOM w0.279: U57.17 v1(94.51,86.13) ; 100.38,82.13 v1(100.4,82.12)
  BOTTOM w0.305: v1(120.44,33.86) 120.28,34.02 R629.2 ; U118.2 52.14,39.8 52.16,39.78 52.16,38.81 52.47,38.51 52.67,38.51 v1(53.38,37.8) ; v1(64.33,138.13) v1(65.47,138.13) 65.44,138.09 C122.2 ; R601.2 R602.2 112.57,49.42 113.07,49.92 v1(113.07,50.88) 112.64,51.31 110.41,51.31 110.1,51 110.1,49.76 v1(110.48,49.38) 110.91,48.95 110.91,47.72 111.21,47.42 v1(111.21,46.99) 111.59,47.37 C602.1 ; R597.2 49.01,43.07 49.11,42.97 49.11,42.04 v1(49.19,41.96) ; v1(41.56,33.63) 41.81,33.88 U124.1 ; v1(41.56,33.63) 41.31,33.88 U124.2 ; v1(41.56,33.63) 41.56,32.37 40.89,31.7 38.63,31.7 37.51,30.58 37.51,28.73 37.95,28.28 37.95,28.23 38.45,27.74 38.58,27.74 R645.1 ; v1(57.75,53.95) 57.6,53.79 C427.1 ; R5215.1 v1(92.91,81.79) ; 39.11,37.12 39.11,37.62 39.49,38 39.49,38.02 39.81,38.34 U124.6 ; R616.2 v1(127.54,42.61) ; C520.1 106.2,72.46 v1(106.11,72.54) ; C3764.1 42.72,76.71 43.02,76.4 U3079.6 43.02,74.48 v1(42.82,74.27) ; R347.1 128.93,47.1 v1(129.15,47.33) ; U118.6 50.64,45.98 50.49,46.13 50.16,46.13 49.9,46.38 C598.1 49.9,47.6 50.01,47.71 v1(50.01,47.77) ; R638.2 85.89,31.83 87.11,30.61 v1(88.15,30.61) R5777.1 ; R630.2 125.05,35.9 v1(125.44,35.51) ; v1(47.4,56.18) 47.27,56.05 C560.1 47.27,55.11 48.01,54.37 U116.6 ; R485.2 v1(45.54,113.7) ; v1(45.64,66.6) 42.51,66.6 42.11,67.01 37.23,67.01 34.84,69.39 31.44,69.39 29.69,67.64 v1(28.7,67.64) 28.34,67.28 C525.1 28.34,65.35 28.6,65.1 28.93,65.1 29.08,64.95 U114.6 ; C604.1 v1(39.07,40.23) ; R625.2 122.18,38.26 v1(121.89,37.97) ; R5825.1 115.92,46.58 v1(115.54,46.96) ; C504.1 105.3,75.7 v1(105.5,75.89) ; R620.2 82.72,38.68 82.42,38.38 v1(82.42,37.95) ; v1(45.76,70.69) 46.25,70.69 46.51,70.95 R260.2 48.11,70.95 48.71,71.55 48.71,72.14 49.22,72.64 53.51,72.64 53.81,72.34 53.81,71.5 54.78,70.54 54.78,67.87 55.08,67.56 v1(55.54,67.56) C3762.1 56.71,68.48 57.02,68.17 ; R641.2 v1(99,30.48) ; C3727.2 45.06,108.14 v1(45.2,108) ; C416.2 v1(48.11,111.52)
  BOTTOM w0.381: v1(94.51,86.13) 94.51,86.79 95.45,87.73 102.94,87.73 106.29,84.38 v1(106.29,83.12) ; v1(48.11,111.52) v1(48.11,112.03)
  vias: v1(28.86,114.12) v1(28.86,113.61) v1(33.16,44.66) v1(33.16,44.15) v1(43.68,46.67) v1(43.68,46.03) v1(44.44,46.67) v1(44.44,46.03) v1(45.2,46.67) v1(45.2,46.03) v1(45.96,46.67) v1(45.96,46.03) v1(46.72,46.67) v1(46.72,46.03) v1(52.16,121.84) v1(52.54,121.59) v1(54.17,112.65) v1(54.17,112.17) v1(60.39,154.61) v1(60.39,152.81) v1(90.78,45.07) v1(90.77,44.46) v1(90.75,43.82) v1(95.86,159.43) v1(96.16,158.9) v1(96.31,159.93) v1(123.28,45.1) v1(123.28,44.6) v1(123.27,44.09)
VCC_3V3_SYS_CLK_BUF: length 10.9
  TOP w0.254: R5790.1 110.05,55.47 110.25,55.68 111.85,55.68 113.41,57.23 U3084.6 113.41,60.37 113.55,60.51 114.01,60.51 C3771.2 C3772.2 FL23.1
VCC_3V3_SYS_REG_SW: length 2
  TOP w0.254: 40.68,52.3 40.32,52.66 U56.15
VCC_5V0: length 91.8
  TOP w0.203: U134.1 17.1,14.48 16.84,14.22
  TOP w0.254: U3076.1 C3747.1 v1(19.29,63.78) ; v1(43.43,54.84) 43.4,54.86 U56.20 ; 35.9,57.36 U56.3
  TOP w0.305: U56.34 38.82,58.01 38.57,57.76 v1(38.47,57.76) ; 34.79,57.18 34.76,57.2 31.82,57.2 30.62,56.01 R5774.1 ; v1(18.56,8.7) R3661.1 R3720.1 ; C197.1 50.55,83.57 50.28,83.84 R240.1 ; v1(65.62,58.67) 65.19,59.1 65.19,60.22 65.57,60.6 C255.1 ; v1(41.17,54.97) 41.07,54.97 40.82,54.71 U56.16 ; v1(41.17,57.76) 41.07,57.76 40.82,58.01 U56.30 ; v1(67.15,46.25) 66.87,45.97 TP103.1 ; U46.1 50.72,80.75 50.56,80.59 v1(50.56,80.52) ; v1(38.47,54.97) 38.57,54.97 38.82,54.71 U56.12 ; 41.24,158.5 C3692.2 v1(42,158.41) 42.72,158.41 C3695.2
  TOP w0.33: U59.8 C255.1
  L03_SIG1 w0.147: v1(25.39,28.73) v1(25.39,29.49)
  L03_SIG1 w0.305: v1(18.56,8.7) 20.69,10.84 20.69,23.6 25.39,28.3 v1(25.39,28.73) ; 66.13,52.35 64.74,53.75 64.74,56.18 65.62,57.07 v1(65.62,58.67)
  L04_PWR1 w0.381: 43.68,53.67 43.68,53.58 44.79,52.48 48,52.48 49.85,54.33 56.79,54.33 57.12,54.66 61.13,54.66 61.99,55.52 61.99,56.06 64.61,58.67 v1(65.62,58.67) ; v1(51.66,77.67) 51.2,78.12 51.2,78.51
  L04_PWR1 w0.508: v1(41.6,54.97) 41.7,54.86 42.87,54.86 42.89,54.84 v1(43.43,54.84)
  BOTTOM w0.203: 92.73,30.76 92.44,31.05 U127.6 ; v1(58.74,86.16) 59.35,85.55 R543.1
  BOTTOM w0.305: R665.1 46.17,22.99 v1(45.96,23.21) ; v1(50.87,82.7) 50.15,81.98 C3643.1 ; R3725.1 v1(51.66,77.67)
  vias: v1(13.15,27.69) v1(13.9,118.12) v1(13.9,117.61) v1(13.91,27.69) v1(14.41,118.12) v1(14.41,117.61) v1(14.92,118.12) v1(14.92,117.61) v1(15.42,118.12) v1(15.42,117.61) v1(16.05,12.7) v1(16.05,12.19) v1(16.05,11.68) v1(16.05,11.18) v1(16.05,10.67) v1(16.05,10.16) v1(16.55,12.7) v1(16.55,12.19) v1(16.55,11.68) v1(16.55,11.18) v1(16.55,10.67) v1(16.55,10.16) v1(17.06,12.7) v1(17.06,12.19) v1(17.06,11.68) v1(17.06,11.18) v1(17.06,10.67) v1(17.06,10.16) v1(23.13,30.99) v1(23.13,30.23) v1(23.11,29.49) v1(23.11,28.73) v1(23.89,30.99) v1(23.89,30.23) v1(23.87,29.49) v1(23.87,28.73) v1(24.63,29.49) v1(24.63,28.73) v1(24.66,30.99) v1(24.66,30.23) v1(25.42,30.99) v1(25.42,30.23) v1(35.32,56.85) v1(35.43,57.58) v1(35.65,57.18) v1(35.88,57.63) v1(38.04,57.76) v1(37.99,57.28) v1(38.02,55.42) v1(38.04,54.97) v1(38.47,57.33) v1(38.47,55.4) v1(41.17,57.33) v1(41.17,55.4) v1(41.6,57.76) v1(41.6,57.3) v1(41.62,55.42) v1(43.6,158.52) v1(43.62,158.06) v1(49.65,19.09) v1(49.68,18.41) v1(49.68,17.65) v1(50.11,80.52) v1(50.52,19.09) v1(50.54,18.41) v1(50.54,17.65) v1(51.38,19.09) v1(51.41,18.41) v1(51.41,17.65) v1(51.48,81.31) v1(91.64,28.57) v1(91.67,27.9) v1(92.4,28.55) v1(92.42,27.89) v1(131.58,148.77) v1(131.58,148.27) v1(132.09,148.77) v1(132.09,148.27) v1(132.6,148.77) v1(132.6,148.27) v1(133.11,148.77) v1(133.11,148.27)
VCC_5V0_PG: length 78.5
  TOP w0.147: U134.5 19.97,14.06 20.72,13.31 R3653.1 21.21,12.53 21.48,12.26 21.48,11.61 21.86,11.23 24.91,11.23 26.26,12.57 26.26,13.87 32.4,20.01 32.4,24.19 31.35,25.24 28.53,25.24 26.31,27.46 26.31,32.31 18.92,39.7 18.92,46.3 v1(19.68,47.07) ; v1(19.27,59.77) 19.27,60.05 19.45,60.23 U54.3
  L03_SIG1 w0.091: v1(22.12,63.58) 20.36,61.82 20.36,60.86 v1(19.27,59.77) 19.27,58.01 19.86,57.43 19.86,53.24 18.61,51.99 17.16,51.99 16.68,51.51 16.68,49.4 17.22,48.87 17.88,48.87 v1(19.68,47.07)
  BOTTOM w0.147: v1(22.12,63.58) 23.11,64.57 U86.3
VCC_CORE:
  vias: v1(34.35,65.46) v1(34.8,64.97) v1(35.27,66.27) v1(35.27,65.46) v1(37.3,65.61) v1(38.21,65.61) v1(38.65,66.04) v1(39.13,65.61) v1(40.21,65.61) v1(40.67,66.11) v1(41.12,65.61) v1(41.56,66.17) v1(42.03,65.61) v1(44.37,65.46) v1(45.29,65.46)
VCC_CORE_N: length 3.3
  TOP w0.152: v1(34.46,68.4) 35.25,68.4 R265.2
  BOTTOM w0.147: v1(34.46,68.4) 34.13,68.07 33.77,68.07 33.43,68.41 R572.2
VCC_CORE_P: length 3.3
  TOP w0.147: v1(34.48,67.45) 35,67.97 35.54,67.97 R265.3
  BOTTOM w0.147: R571.2 33.46,67.37 33.8,67.72 34.22,67.72 v1(34.48,67.45)
VDD_0V85_N: length 10.2
  BOTTOM w0.147: R581.1 51.64,64.27 51.88,64.52 52.65,64.52 53.1,64.06 53.1,61.65 52.14,60.68 50.29,60.68 49.6,59.99 49.6,59.12 R585.2
VDD_0V85_P: length 10.7
  BOTTOM w0.147: R581.4 51.64,65.01 51.78,64.87 52.79,64.87 53.45,64.2 53.45,61.5 52.28,60.33 50.44,60.33 49.95,59.84 49.95,59.09 R584.2
VDD_1V8_N: length 4.2
  TOP w0.147: R311.2 49.61,57.1 49.11,57.1 48.91,56.9 48.91,56.32 49.31,55.92 49.31,54.95 49.53,54.73 R316.4
VDD_1V8_P: length 4.8
  TOP w0.147: R310.2 49.57,57.45 48.96,57.45 48.56,57.05 48.56,56.18 48.96,55.78 48.96,54.91 48.78,54.73 R316.1
VDD_2V5: length 9.5
  TOP w0.203: C278.1 83.33,43.78 83.33,43.43 83.61,43.15 J18.4 ; J19.4 116.04,42.99 115.94,43.08 ; 83.58,43.38 84.01,42.96 J18.6 ; 116.44,42.92 J19.6
  TOP w0.305: 116.27,43.08 116.44,42.92 ; C273.1 115.82,45.66 115.62,45.85 TP92.1
  BOTTOM w0.305: R634.1 89.24,32.41 88.93,32.11 v1(88.93,32.11) R637.2 88.92,31.53 88.47,31.53 v1(88.22,31.78) C615.1
  vias: v1(82.75,45.23) v1(82.78,44.28) v1(93.14,35.83) v1(94.03,35.83) v1(94.92,35.83) v1(95.81,35.83) v1(115.18,45.03) v1(115.18,44.23)
VDD_CANUART: length 0.9
  TOP w0.305: 50.67,78.33 50.81,78.19 R255.1
VDD_CANUART_ALERT: length 3.8
  BOTTOM w0.147: R5778.1 58.55,61.25 58.02,61.78 U3078.3 58.02,63.65 57.42,64.25 U3080.A3
VDD_CANUART_N: length 9.9
  TOP w0.147: v1(54.73,75.01) 54.68,75.06 54.68,76 54.93,76.25 R5786.1
  BOTTOM w0.147: R5780.2 56.13,70.67 55.27,70.67 54.24,71.69 54.24,74.14 53.83,74.55 53.81,74.55 53.56,74.8 53.56,75.21 53.81,75.46 54.27,75.46 v1(54.73,75.01)
VDD_CANUART_P: length 7.6
  TOP w0.147: R5786.4 54.17,76.25 54.33,76.09 54.33,75.32 v1(54.02,75.01)
  BOTTOM w0.147: v1(54.02,75.01) 54.59,74.43 54.59,71.83 55.41,71.02 56.13,71.02 R5781.2
VDD_CORE: length 97.6
  TOP w0.305: U136.G14 v1(72.9,87.25) U136.H13 v1(73.7,86.45) U136.J12 v1(74.5,86.45) U136.K13 ; U136.L8 v1(75.3,82.46) U136.K7 ; U136.L8 v1(76.1,83.26) U136.M9 ; U136.L8 v1(75.3,83.26) U136.K9 ; U136.L8 v1(76.1,82.46) U136.M7 v1(76.9,81.66) ; U136.G7 v1(72.1,81.66) ; v1(76.1,84.85) U136.L11 v1(76.1,85.65) U136.L12 ; U136.P13 v1(77.7,87.25) ; U136.K13 v1(75.3,86.45) U136.L12 ; U136.K13 v1(75.3,87.25) ; U136.M13 v1(76.1,86.45) U136.L12 ; U136.P7 v1(78.5,81.66) ; v1(72.9,83.26) U136.H9 v1(72.9,84.06) U136.H10 v1(72.9,84.85) U136.G11
  L03_SIG1 w0.102: v1(33.27,56.64) 33.27,56.97 34.08,57.78 34.43,57.78 36.76,60.11 41.05,60.11 41.4,60.46 47.89,60.46 48.3,60.05 50.27,60.05 50.39,60.17 51.5,60.17 v1(51.86,59.82)
  L04_PWR1 w0.102: v1(51.86,59.82) 52.29,60.25 52.29,62.31 53.84,63.86 53.84,68.45 59.61,74.22 62.15,74.22 65.19,77.27 65.19,79.71 66.75,81.26 71.49,81.26 71.7,81.06 71.7,80.67 71.91,80.46 75.03,80.46 75.84,79.65 77.89,79.65 78.1,79.86 78.1,80.26 78.29,80.46 78.78,80.46 78.99,80.67 78.99,81.17 v1(78.5,81.66) ; v1(76.1,86.45) 76.1,86.7 76.65,87.25 76.7,87.25
  L04_PWR1 w0.127: 76.5,81.69 76.5,81.89 76.32,82.07 75.91,82.07
  L04_PWR1 w0.132: 77.64,80.46 77.89,80.46 78.1,80.66 78.1,80.77
  L04_PWR1 w0.305: v1(76.1,83.26) v1(75.3,83.26) ; v1(78.5,81.66) 78.1,81.26 78.1,81.2 ; v1(76.1,82.46) v1(75.3,82.46) ; 76.52,81.2 76.9,81.58 v1(76.9,81.66) ; v1(76.1,84.85) v1(76.1,85.65) v1(76.1,86.45)
  L04_PWR1 w0.381: v1(77.7,87.25) 76.71,87.25 76.7,87.25
  BOTTOM w0.203: v1(33.27,56.64) 33.36,56.64 33.62,56.39 R5828.1
  BOTTOM w0.254: C445.1 78.31,81.47 v1(78.5,81.66) 78.32,81.83 C477.1
  BOTTOM w0.305: C468.1 75.24,86.4 v1(75.3,86.45) ; C441.1 73.08,83.07 v1(72.9,83.26) ; C662.1 77.58,87.37 v1(77.7,87.25) ; C460.1 75.93,86.29 v1(76.1,86.45) ; v1(76.1,84.85) 76.1,85.18 C663.1 76.16,85.6 v1(76.1,85.65) ; C3751.1 72.11,81.67 v1(72.1,81.66) ; v1(72.9,84.85) 73,84.95 C462.1 ; v1(72.9,87.25) 72.69,87.46 C448.1 ; C3752.1 75.98,83.38 v1(76.1,83.26) ; C657.1 74.38,86.57 v1(74.5,86.45) ; v1(72.9,84.06) 72.69,83.85 C659.1 ; v1(75.3,83.26) 75.3,83.73 C658.1 ; C3661.1 77.1,81.45 v1(76.9,81.66) ; v1(75.3,87.25) 75.3,87.12 C494.1 ; C660.1 75.19,82.35 v1(75.3,82.46)
  vias: v1(35.88,71.46) v1(35.88,70.77) v1(35.88,70.11) v1(36.67,71.46) v1(36.67,70.77) v1(36.67,70.11) v1(37.68,71.46) v1(37.68,70.77) v1(37.68,70.11) v1(38.7,71.46) v1(38.7,70.77) v1(38.7,70.11) v1(39.71,71.46) v1(39.71,70.77) v1(39.71,69.78) v1(39.71,69.1) v1(40.73,71.46) v1(40.73,70.77) v1(40.73,69.78) v1(40.73,69.1) v1(50.23,95.53) v1(50.34,95.99) v1(50.79,95.96) v1(50.79,95.5) v1(51.25,95.96) v1(51.25,95.5) v1(52.68,93.23) v1(53.16,93.23) v1(53.43,92.79) v1(53.43,92.15) v1(83.96,92.84) v1(84.04,91.97) v1(84.04,91.34) v1(84.19,93.5) v1(84.52,92.68) v1(85.16,92.68)
VDD_CORE_ALERT: length 3.1
  BOTTOM w0.147: U113.A3 30.48,61.04 30.08,60.64 U114.3 R586.1
VDD_CORE_N: length 9.1
  BOTTOM w0.147: 30.31,65.28 30.58,65.02 U114.9 ; 30.31,65.28 30.34,65.31 C524.2 30.34,66.53 30.65,66.85 30.65,67.34 31.41,68.1 32,68.1 R572.1 ; 30.31,65.28 30.08,65.05 U114.8 30.08,63.14 29.68,62.74 U113.D1 U113.D2
VDD_CORE_P: length 7
  BOTTOM w0.147: U113.D3 31.08,63.16 U114.10 31.08,64.16 31.08,65.25 31.32,65.49 C524.1 31.32,66.53 31,66.85 31,67.19 31.56,67.75 32.03,67.75 R571.1
VDD_CORE_REG_SW1: length 1.5
  TOP w0.254: U56.33 39.32,59.78 39.08,60.02
VDD_CORE_REG_SW2: length 1.7
  TOP w0.254: 40.58,60.15 40.32,59.89 U56.31
VDD_MMC0_SD: length 1.6
  TOP w0.305: C93.2 132.32,76.61 132.35,76.64 132.35,77.05 TP21.1
  vias: v1(122.12,74.93) v1(122.67,74.9) v1(131.43,75.7) v1(131.77,76.07)
VDDA1V8: length 9.2
  TOP w0.254: 43.24,54.36 U56.19
  TOP w0.305: v1(51.1,49.17) v1(51.1,49.71) 49.12,49.71 48.67,50.15 48.67,51.24 48.36,51.56 R316.2
  BOTTOM w0.381: C290.1 74.23,55.77 FL10.2 74.67,54.92 v1(74.95,54.64)
VDDA_1V8: length 38.7
  TOP w0.305: C483.1 C202.1 83.74,69.14 84.24,68.63 84.24,67.36 83.56,66.67 v1(83.13,66.67)
  L03_SIG1 w0.381: v1(73.93,67.64) 73.93,65.91 73.22,65.2 68.17,65.2 66.97,64.01 66.45,64.01 64.96,65.49 64.96,68.88 68.1,72.02 v1(68.1,77.65)
  L04_PWR1 w0.254: v1(50.74,52.55) v1(51.38,52.55)
  BOTTOM w0.381: FL6.1 79.03,74.93 79.44,74.52 79.44,73.51 79.82,73.13 81.64,73.13 81.88,73.37 ; v1(73.93,67.64) 73.93,67.64 73.96,67.61 FL20.1 FL22.1
  vias: v1(50.74,53.54) v1(50.74,53.04) v1(51.38,53.54) v1(51.38,53.04) v1(73.93,68.12) v1(82.39,73.69) v1(82.57,73.2) v1(82.97,66.24) v1(119.85,56.46) v1(119.88,55.98)
VDDA_1V8_ALERT: length 3.1
  BOTTOM w0.147: U119.A3 52.04,42.2 52.02,42.19 52.02,42.01 51.64,41.63 U118.3 R608.1
VDDA_1V8_FB1: length 16
  TOP w0.305: U136.M11 v1(76.9,85.65) ; U136.J10 v1(73.7,84.06) ; U136.J9 v1(73.7,83.26)
  L03_SIG1 w0.127: v1(76.9,85.65) U136.M11 76.5,84.61 76.65,84.46 77.06,84.46 77.3,84.22 77.3,82.19 77.16,82.05 74.28,82.05 74.09,82.24 74.09,83.66 v1(73.7,84.06)
  L04_PWR1 w0.127: 78.02,86.86 77.5,86.86 77.34,86.69
  L04_PWR1 w0.132: 78.02,86.86 78.02,86.87 78.1,86.79 ; 78,86.11 77.94,86.06 77.49,86.06 77.41,86.13
  L04_PWR1 w0.305: 77.13,86 76.9,85.77 v1(76.9,85.65)
  BOTTOM w0.305: v1(86.71,71.58) FL13.2 ; v1(76.9,85.65) 76.8,85.75 C463.1 ; C501.1 73.9,83.06 v1(73.7,83.26) v1(73.7,84.06) 73.7,84.33 C485.1
VDDA_1V8_FB2: length 13.3
  TOP w0.305: U136.K5 v1(74.5,80.06) ; v1(77.7,85.65) U136.N11
  L04_PWR1 w0.127: 77.28,82.07 77.29,82.06 77.91,82.06 78.12,82.27 ; 77.28,82.07 77.28,82.06 76.71,82.06 76.5,82.27 76.5,82.68 ; 77.28,82.07 77.31,82.09 77.31,82.25 ; 76.7,82.85 76.67,82.85 ; 77.29,83.78 77.29,84.69 77.29,85.25 76.71,85.25 76.5,85.04 76.5,83.64 ; 77.51,84.45 77.87,84.45 78.1,84.68 78.1,85.25 v1(77.7,85.65)
  L04_PWR1 w0.132: 77.29,83.78 77.28,83.77 ; 76.85,82.85 76.7,82.85 76.5,83.06 76.5,83.64 76.6,83.74 76.5,83.85 ; 76.67,82.85 76.5,82.68
  L04_PWR1 w0.305: v1(74.5,80.06) 74.5,79.56 74.49,79.55 ; v1(77.7,85.65) 77.29,85.25
  BOTTOM w0.305: v1(74.5,80.06) 74.55,80 C3656.1 ; C467.1 77.52,85.83 v1(77.7,85.65)
  BOTTOM w0.381: FL6.2 v1(77.41,75.77)
VDDA_1V8_FB3: length 6.7
  TOP w0.305: U136.H7 v1(72.9,81.66)
  L03_SIG1 w0.127: 73.3,79.36 73.3,81.26 v1(72.9,81.66) 72.5,81.26 72.5,79.36
  BOTTOM w0.305: v1(72.9,81.66) 73.24,81.66 C3647.1 ; v1(73.2,66.22) 73.04,66.38 FL20.2
VDDA_1V8_FB4: length 6
  TOP w0.305: v1(77.7,84.06) U136.P10
  L04_PWR1 w0.132: 79.75,84.45 78.3,84.45 77.9,84.06 v1(77.7,84.06) 78.1,83.66 79.75,83.66
  BOTTOM w0.305: v1(80.69,74.47) 80.46,74.25 FL21.2 ; C3649.1 77.89,84.24 v1(77.7,84.06)
VDDA_1V8_FB_OSC: length 3.8
  TOP w0.305: U136.F5 v1(71.3,80.06)
  BOTTOM w0.254: 69.11,79.43 69.68,79.43 69.88,79.63 70.38,79.63
  BOTTOM w0.305: C508.1 71.01,79.77 v1(71.3,80.06) 70.8,80.06 70.38,79.63
VDDA_1V8_N: length 17
  TOP w0.147: R311.1 v1(51.58,56.69)
  BOTTOM w0.147: 51.91,46.3 51.9,46.31 C597.2 52.19,47.29 52.19,49.04 52.37,49.22 52.37,56.38 52.47,56.48 52.47,56.87 52.22,57.12 52.01,57.12 v1(51.58,56.69) ; 51.91,46.3 51.64,46.02 U118.8 U119.D2 U119.D1 ; 51.91,46.3 52.14,46.07 U118.9
VDDA_1V8_P: length 16.2
  TOP w0.147: R310.1 v1(51.56,57.91)
  BOTTOM w0.147: U119.D3 52.04,43.77 52.64,44.37 U118.10 52.64,46.1 52.88,46.34 C597.1 52.54,47.33 52.54,48.89 52.72,49.07 52.72,56.24 52.82,56.34 52.82,57.01 52.36,57.47 52.01,57.47 51.58,57.91 v1(51.56,57.91)
VDDA_ADC0: length 2
  TOP w0.305: U136.J5 v1(74.5,80.86)
  L03_SIG1 w0.254: v1(74.5,80.86) 74.5,80.74 74.69,80.54
  BOTTOM w0.305: v1(74.5,80.86) 74.59,80.94 C3652.1 ; FL22.2 v1(75.13,67.92)
VDDA_CORE_USB: length 4.7
  TOP w0.305: U136.N10 v1(76.9,84.85)
  L03_SIG1 w0.127: 78.28,85.24 78.26,85.26 77.3,85.26 v1(76.9,84.85) 77.11,84.85 77.51,84.45 77.97,84.45
  L03_SIG1 w0.132: 79.01,84.45 77.97,84.45
  BOTTOM w0.305: v1(76.9,84.85) 76.7,84.66 C3767.1
  vias: v1(83,92.89)
VDDA_SYS_MON: length 15.5
  TOP w0.305: U136.H8 v1(72.9,82.46)
  BOTTOM w0.132: C449.2 72.13,82.06 71.13,82.06 70.89,82.3 70.89,82.62 70.65,82.86 69.53,82.86 69.29,83.1 69.29,83.42 69.06,83.65 68.33,83.65 67.96,83.29 65.19,83.29
  BOTTOM w0.147: R543.2 R545.1 61.91,83.98 62.6,83.29 65.19,83.29
  BOTTOM w0.254: C449.2 72.86,82.46 v1(72.9,82.46)
VDDC_1V2: length 23.5
  TOP w0.147: C240.1 38.55,76.9 v1(38.55,76.45)
  TOP w0.203: C240.1 38.33,77.74 C233.1 38.33,78.76 U48.115 ; v1(30.78,85.01) U48.87
  L03_SIG1 w0.102: v1(30.78,85.01) 30.42,84.65 30.42,84.12 30.7,83.85 31.11,83.85 31.18,83.92 31.56,83.92 31.74,83.74 31.74,82.85 31.44,82.55 31.44,78.05 v1(30.68,77.29)
  BOTTOM w0.147: 30.76,84.99 v1(30.78,85.01)
  BOTTOM w0.203: C516.2 30.76,84.99
  BOTTOM w0.305: v1(38.55,76.45) 37.86,75.77 33.52,75.77 32,77.29 v1(30.68,77.29)
VDDIM: length 3.9
  TOP w0.091: 105.2,71.3 105.2,70.74 v1(104.96,70.49) 104.71,70.74 104.71,71.3 U49.C2 105.2,71.3
  BOTTOM w0.254: C527.1 104.74,70.28 v1(104.96,70.49) C521.1
VDDR_CANUART: length 4.4
  TOP w0.305: U136.E7 v1(70.5,82.46)
  BOTTOM w0.305: R3731.2 67.65,81.51 67.9,81.76 69.08,81.76 69.26,81.94 C3653.1 70.5,82.45 v1(70.5,82.46)
VDDR_CORE: length 14.8
  TOP w0.305: v1(50.84,63.01) 50.84,63.47 51.1,63.72 TP60.1 ; U136.H12 v1(72.9,86.45) ; v1(76.9,88.05) U136.M14 ; U136.N8 v1(76.9,82.46) ; U136.G10 v1(72.1,84.85) ; U136.J8 v1(74.5,83.26) ; U136.K10 v1(74.5,84.06) ; U136.N12 v1(77.7,86.45) ; v1(76.9,84.06) U136.M10
  L03_SIG1 w0.127: 71.54,84.45 70.96,84.45 ; 73.3,87.45 73.5,87.66 73.93,87.66 74.08,87.5 74.13,87.55 74.16,87.55 74.26,87.65 74.73,87.65 74.81,87.58
  L03_SIG1 w0.305: v1(72.1,84.85) 72.1,85.57 72.58,86.05 ; 76.5,83.64 76.9,84.04 v1(76.9,84.06) ; v1(77.7,86.45) 77.7,86.58 77.51,86.77 ; v1(74.5,83.26) v1(74.5,84.06) ; v1(76.9,82.46) 76.88,82.46 76.54,82.79
  BOTTOM w0.305: C447.1 72.81,86.37 v1(72.9,86.45) ; C3759.1 72.1,85.05 v1(72.1,84.85) ; v1(74.5,83.26) 74.59,83.16 C3758.1 ; C490.1 76.74,88.22 v1(76.9,88.05) ; v1(74.5,84.06) 74.62,84.18 C466.1 ; C505.1 77.11,82.24 v1(76.9,82.46) ; C465.1 v1(77.7,86.45) ; R272.1 52.65,71.78 52.75,71.88 v1(52.8,71.88) ; v1(76.9,84.06) 77.01,83.94 C493.1
  vias: v1(50.13,63.02) v1(50.16,62.39) v1(50.85,62.4) v1(52.75,70.15) v1(52.75,69.67) v1(52.75,69.19) v1(64.53,84.51) v1(65.02,84.51) v1(65.5,84.51)
VDDR_CORE_ALERT: length 3.1
  BOTTOM w0.147: U115.A3 49.41,50.64 49.01,50.24 U116.3 R596.1
VDDR_CORE_N: length 7.7
  BOTTOM w0.147: R585.1 49.58,57.34 49.58,56.47 49.27,56.15 C559.2 49.27,55 49.24,54.98 ; 49.24,54.98 49.51,54.71 U116.9 ; 49.24,54.98 49.01,54.74 U116.8 U115.D2 U115.D1
VDDR_CORE_P: length 6.3
  BOTTOM w0.147: U115.D3 49.41,52.29 49.67,52.55 49.9,52.55 50,52.65 50,52.76 50.01,52.76 U116.10 50.01,54.78 50.25,55.02 C559.1 50.25,56.15 49.93,56.47 49.93,57.33 R584.1
VDDSHV_CANUART: length 181.6
  TOP w0.305: v1(48.14,35.62) 47.57,35.62 47.41,35.45 v1(45.6,35.45) ; R3653.2 20.72,11.02 21.32,10.41 25.65,10.41 27.7,12.47 27.7,14.17 28.24,14.71 28.77,14.71 33.11,19.05 33.11,24.13 27.12,30.12 27.12,34.41 25.09,36.44 25.09,45.47 v1(25.39,45.77) 25.11,46.05 R5736.2 ; v1(52.77,39.42) 52.6,39.42 52.49,39.32 R371.1 ; R326.1 v1(52.38,35.77) R322.1 ; R5756.1 62.15,122.22 v1(62.27,122.35) 62.7,122.35 63.02,122.03 C3740.2 65.53,121.36 65.67,121.21 66.11,121.21 66.41,120.9 67.53,120.9 67.84,121.21 67.84,123.99 67.45,124.37 U3070.5 ; v1(19.63,62.71) 20.06,62.71 20.34,62.43 21.43,62.43 21.73,62.74 21.73,62.84 21.81,62.92 22.22,62.51 TP80.1 22.22,60.98 21.96,60.73 v1(21.23,60.73) U54.5 ; v1(22.7,52.98) 22.7,52.73 22.69,52.73 R318.2 ; 41.24,159.5 41.72,159.99 41.86,159.99 v1(41.91,160.04) ; v1(42.69,147.7) 42.69,147.96 39.01,151.64 R5692.2 v1(39.01,155.42) ; U2356.8 C3731.1 28.41,51 v1(28.59,50.83) 28.7,50.71 R5737.2
  TOP w0.381: v1(54.3,82.73) v1(53.84,82.73)
  L03_SIG1 w0.381: v1(39.01,155.42) 41.11,157.53 41.11,159.71 41.44,160.04 v1(41.91,160.04)
  L04_PWR1 w0.305: v1(52.77,39.42) 51.81,40.39 v1(51.81,50.83)
  L04_PWR1 w0.381: 52.6,50.52 52.29,50.83 v1(51.81,50.83)
  BOTTOM w0.203: U117.3 46.63,32.97 C574.2
  BOTTOM w0.305: C574.2 45.8,33.25 44.84,33.25 44.24,33.85 44.24,34.99 44.7,35.45 v1(45.6,35.45) 45.68,35.54 R590.2 ; R593.1 48.67,36.56 48.55,36.44 R592.1 48.25,35.72 v1(48.14,35.62) ; v1(21.23,60.73) 21.23,60.73 C538.1 ; R643.1 19.43,62.52 v1(19.63,62.71) 20.19,63.27 20.19,66.57 22.83,69.22 30.55,69.22 31.49,70.15 35.07,70.15 35.65,69.57 35.96,69.57 37.58,67.94 42.46,67.94 42.74,67.67 47.13,67.67 48.3,66.5 v1(48.73,66.5) ; v1(25.39,45.77) 28.59,48.97 v1(28.59,50.83) 26.39,53.03 23.26,53.03 23.22,52.98 v1(22.7,52.98) ; v1(53.84,82.73) v1(54.3,82.73) 54.73,82.73 55.05,82.41 R3723.1 ; v1(53.84,82.73) 53.57,82.46 C3644.2 U135.1 ; v1(53.84,82.73) 53.41,82.73 53.36,82.78 51.73,82.78 51.68,82.83 51.63,82.83 51.43,83.03 51.43,83.24 51.12,83.54 49,83.54 48.02,82.57 48.02,78.97 48.67,78.32 v1(49.34,78.32) R3726.2
  vias: v1(41.94,159.48) v1(49.62,66.55) v1(54.32,82.22)
VDDSHV_CANUART_ALERT: length 3.5
  BOTTOM w0.147: R5782.1 U3079.3 44.02,71.82 43.45,72.39 U3081.A3
VDDSHV_CANUART_N: length 2
  BOTTOM w0.147: R5784.2 44.57,79.63 44.57,80.39 44.39,80.57 R5787.1
VDDSHV_CANUART_P: length 2
  BOTTOM w0.147: R5787.4 45.16,80.57 44.92,80.34 44.92,79.66 45.35,79.23 R5785.2
VDDSHV_CANUART_PG: length 2.5
  BOTTOM w0.147: U135.5 51.12,80.24 50.63,79.74 C3642.1 R3726.1
VDDSHV_SDIO: length 135.6
  TOP w0.254: U10.10 127.6,78.2 ; 44.9,55.36 U56.21
  TOP w0.305: v1(124.82,74.7) 125.07,74.96 R55.2 125.07,76.39 R64.2 125.08,77.32 R66.2 125.07,77.94 125.46,78.32 C103.2 127.6,78.2 ; 44.9,55.36 C246.1 45.21,55.67 45.21,56.15 v1(45.18,56.18) ; R54.2 R57.2 R65.2 v1(130.13,77.58)
  L03_SIG1 w0.381: v1(125.6,62.76) 125.06,62.76 123.11,64.72 123.11,67.49 127.17,71.55 128.24,71.55 130.52,73.84 130.52,77.19 v1(130.13,77.58)
  L04_PWR1 w0.381: v1(124.82,74.7) 124.82,78.26 125.95,79.4 129.38,79.4 130.13,78.65 v1(130.13,77.58) ; v1(44.54,56.18) v1(45.18,56.18) 45.71,56.18 46.42,55.47 49.07,55.47 50.92,57.33 54.45,57.33 55.54,58.42 55.54,61.32 57.32,63.09 60.55,63.09 63.06,65.61 64.48,65.61 65.5,64.59 v1(66.74,64.59)
  BOTTOM w0.381: v1(66.74,64.59) 73.62,64.59 73.77,64.74 79.88,64.74 80.53,65.39 84.1,65.39 85.82,63.68 90.04,63.68 90.59,63.12 93.08,63.12 95.57,60.63 97.5,60.63 98.26,61.39 110.1,61.39 111.05,60.44 121.76,60.44 122.51,61.19 124.02,61.19 v1(125.6,62.76)
VINT_LDO: length 3
  TOP w0.147: C249.1 35.15,55.69 TP74.1 35.76,55.57 35.97,55.36 U56.7
ADC0_AIN0: length 73.7
  TOP w0.147: v1(67.7,59.94) 67.7,60.3 67.93,60.53 R5720.2
  BOTTOM w0.147: v1(67.7,59.94) 67.97,59.67 69.67,59.67 70.27,60.27 71.04,60.27 71.3,60.01 75.19,60.01 76.08,60.9 82.12,60.9 86.3,56.72 90.32,56.72 90.62,57.02 92.47,57.02 92.94,57.49 97.82,57.49 98.85,56.47 100.31,56.47 101.64,57.8 105.5,57.8 107.19,56.12 115.96,56.12 117.49,57.66 123.49,57.66 126.82,60.99 U2349.10 U2349.1 129.17,60.99 129.53,61.36 129.53,62.76 129.98,63.21 J31.1
ADC0_AIN0_R: length 17.1
  TOP w0.132: 71.7,75.95 U136.F1
  TOP w0.147: R5720.1 67.93,63.22 v1(67.7,63.45) 71.22,66.97 71.22,74.12 71.7,74.6 71.7,75.95
  BOTTOM w0.147: C3710.1 v1(67.7,63.45)
ADC0_AIN1: length 69.6
  TOP w0.147: R5721.2 v1(70.63,59.82)
  BOTTOM w0.147: J31.3 130.14,60.67 129.96,60.49 U2349.2 U2349.9 126.96,60.49 123.72,57.25 117.59,57.25 116.11,55.77 107.04,55.77 105.36,57.45 101.79,57.45 100.45,56.12 98.69,56.12 97.67,57.14 93.1,57.14 92.63,56.67 90.92,56.67 90.63,56.37 85.99,56.37 81.81,60.55 76.24,60.55 75.35,59.66 71.14,59.66 70.99,59.82 v1(70.63,59.82)
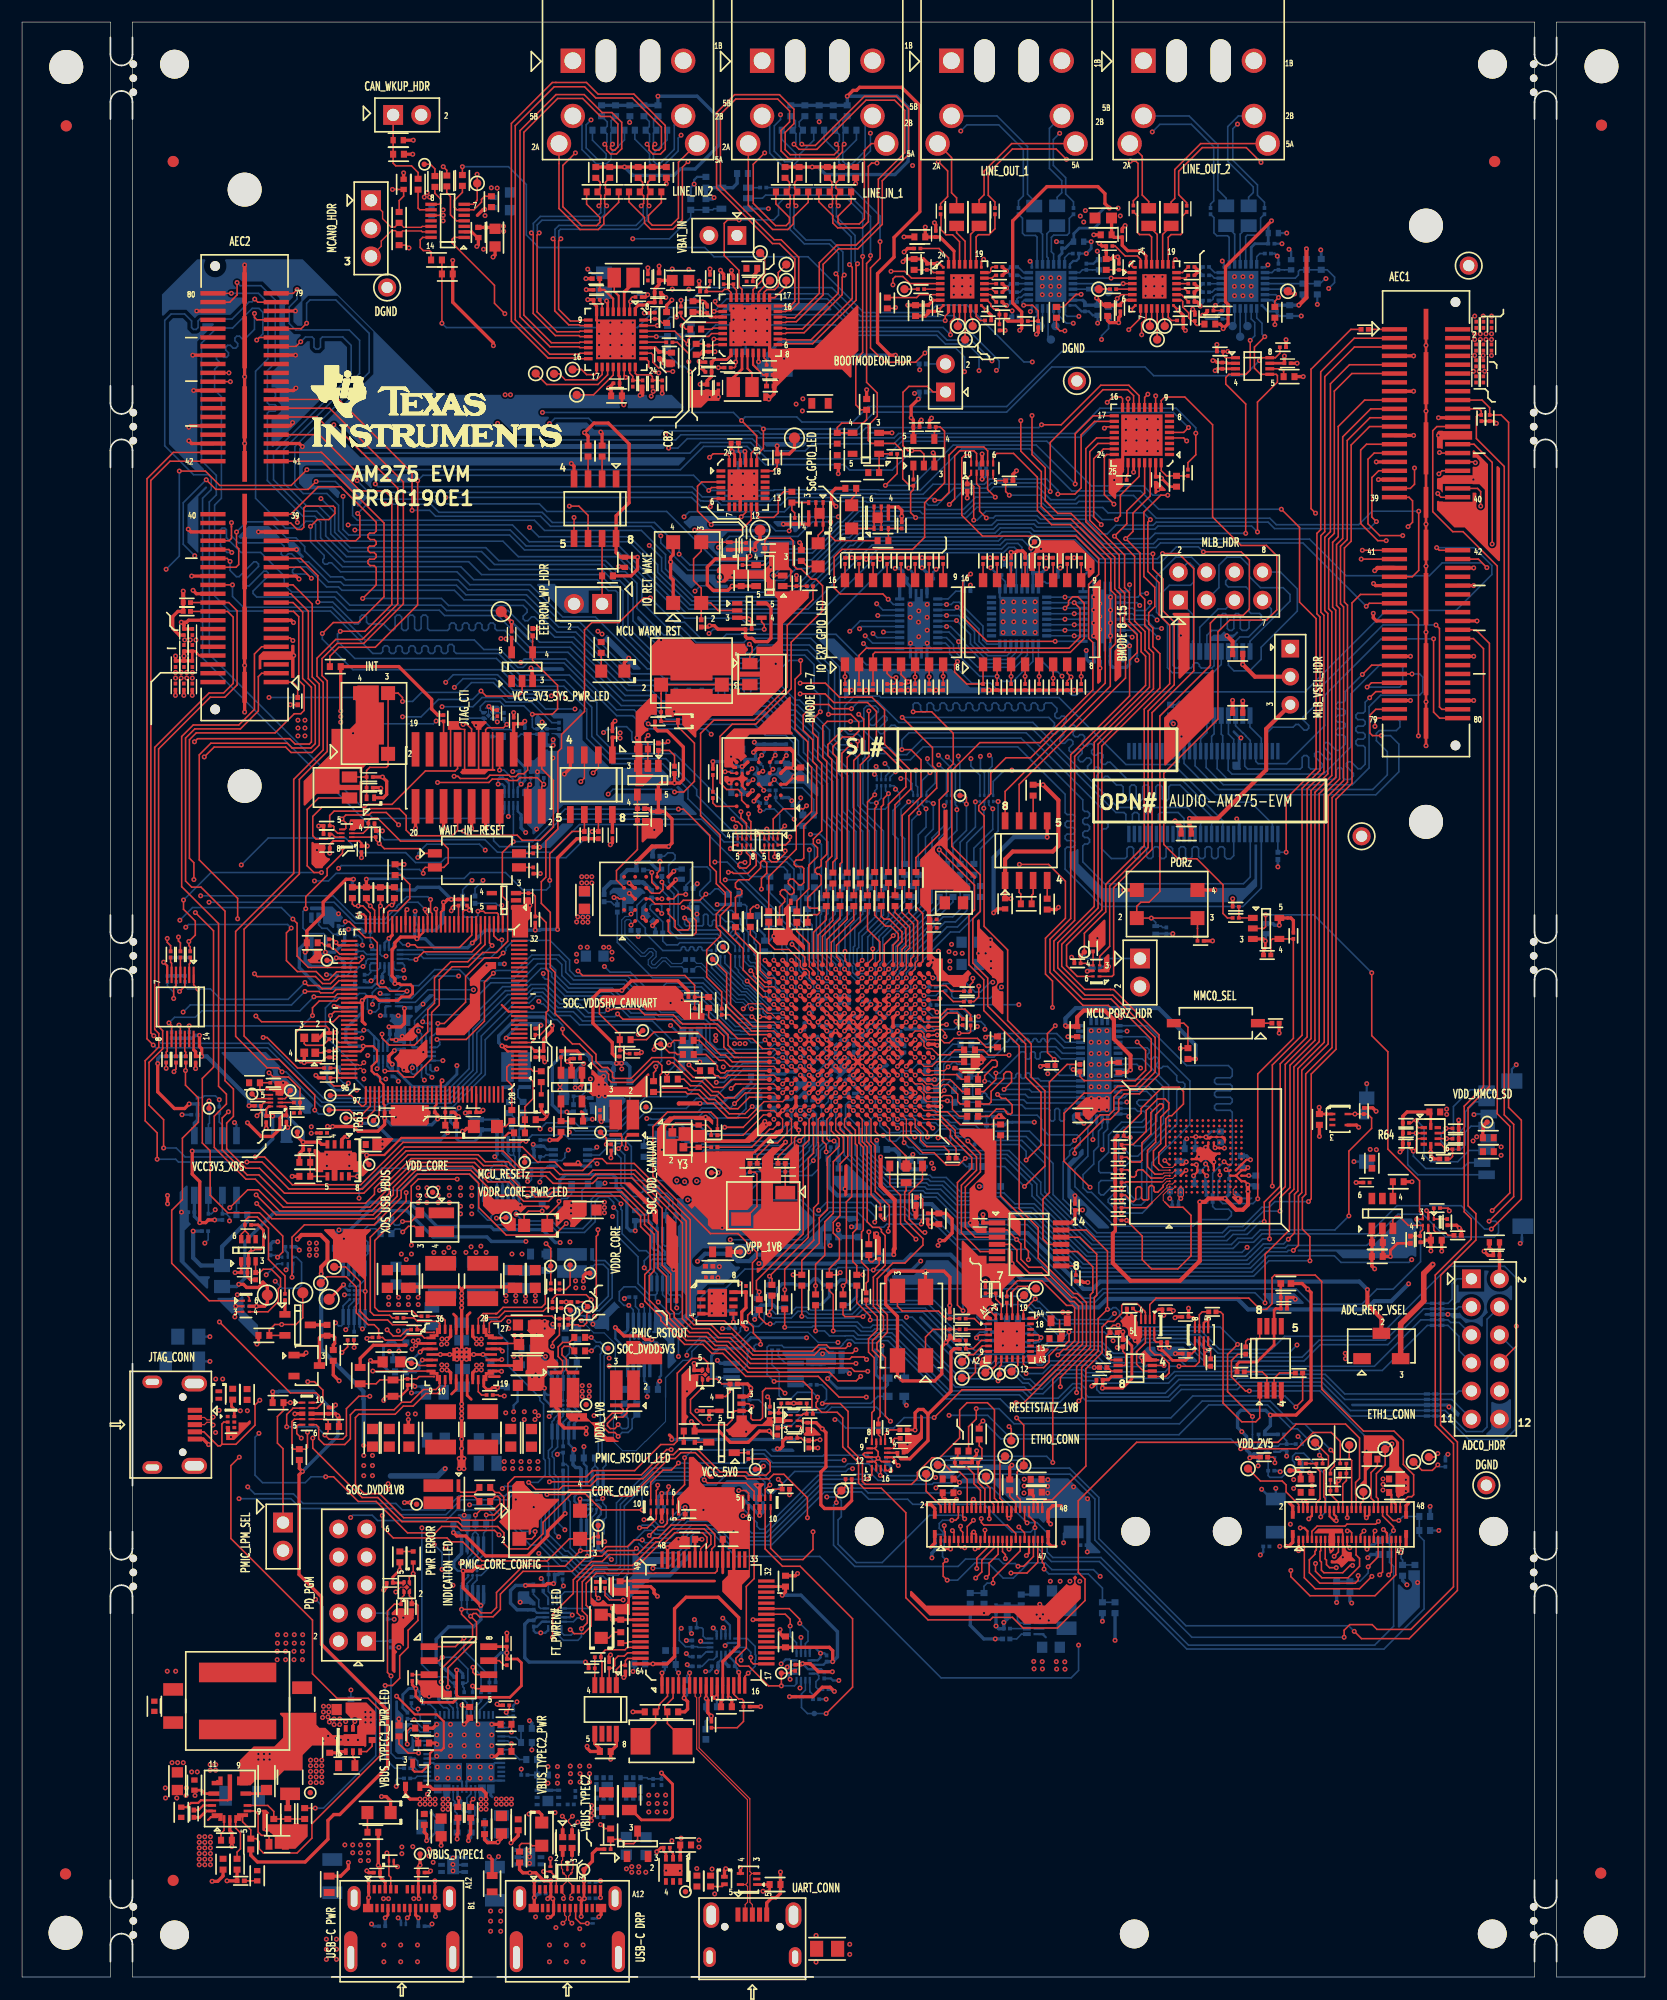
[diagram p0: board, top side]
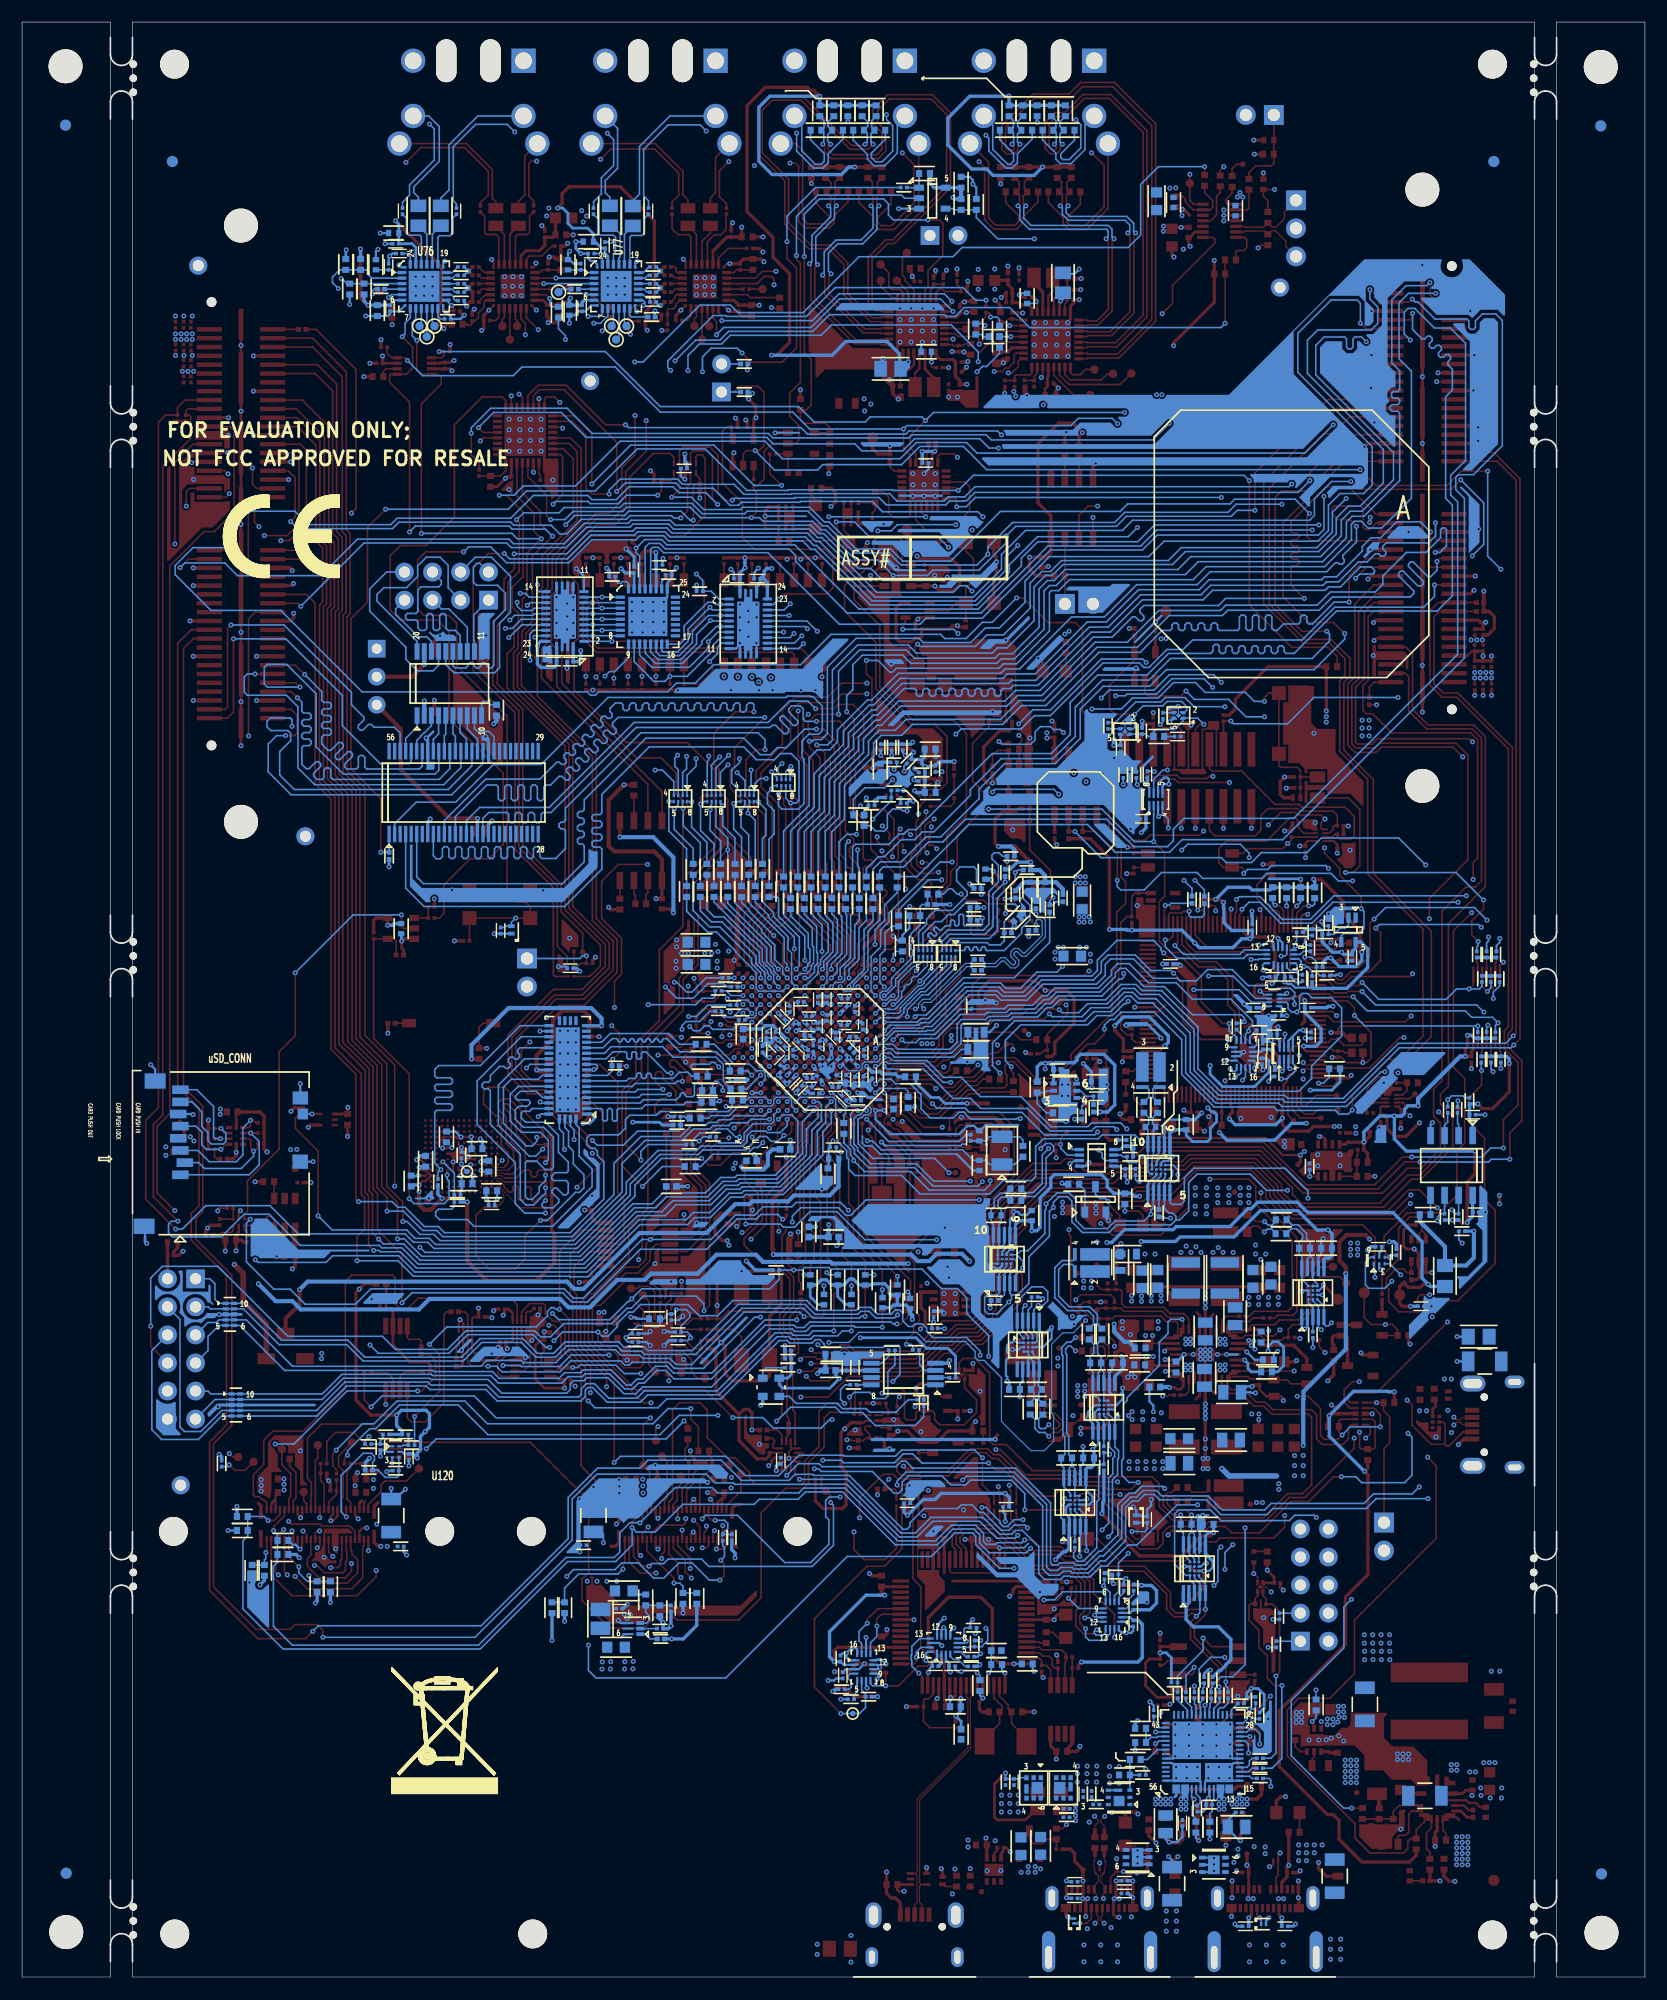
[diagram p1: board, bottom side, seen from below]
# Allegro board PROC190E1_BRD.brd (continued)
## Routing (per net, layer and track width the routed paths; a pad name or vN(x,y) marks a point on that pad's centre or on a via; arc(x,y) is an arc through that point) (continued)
ADC0_AIN1_R: length 16.9
  TOP w0.132: 73.3,76.61 U136.H1
  TOP w0.147: v1(69.84,63.58) R5721.1 70.63,64.87 72.2,66.45 72.2,68.73 72.94,69.47 72.94,74.14 74.01,75.21 74.01,75.9 73.3,76.61
  BOTTOM w0.147: R5721.1 v1(69.84,63.58)
ADC0_AIN2: length 63.6
  TOP w0.147: v1(76.17,59.79) 74.54,59.79 74.36,59.97 R5722.2
  BOTTOM w0.147: v1(76.17,59.79) 76.57,60.2 81.61,60.2 86.34,55.46 87.76,55.46 88.31,56.01 90.77,56.01 91.08,56.31 92.78,56.31 93.26,56.79 97.48,56.79 98.65,55.63 101.6,55.63 101.8,55.82 104.91,55.82 105.44,55.3 122.5,55.3 126.7,59.49 U2349.7 U2349.4 129.17,59.49 129.41,59.26 130.16,59.26 J31.5
ADC0_AIN2_R: length 17.8
  TOP w0.132: 74.5,76.98 74.5,77.66 U136.K2
  TOP w0.147: R5722.1 v1(74.36,62.59) 74.67,62.89 74.67,70.18 75.15,70.66 75.15,76.33 74.5,76.98
  BOTTOM w0.147: R5722.1 v1(74.36,62.59)
ADC0_AIN3: length 66
  TOP w0.147: R5723.2 75.61,61.06 76.83,59.84 v1(76.83,59.49)
  BOTTOM w0.147: v1(76.83,59.49) 79.72,59.49 84.52,54.69 87.98,54.69 88.59,55.3 89.63,55.3 90.8,54.13 91.31,54.13 91.84,53.59 92.25,53.59 93.62,54.97 96.16,54.97 96.41,54.71 97.86,54.71 98.37,54.2 103.78,54.2 104.39,54.81 109.67,54.81 109.77,54.92 123.21,54.92 127.29,58.99 U2349.6 U2349.5 129.16,58.99 130.16,58 130.16,56.72 J31.7
ADC0_AIN3_R: length 15.4
  TOP w0.147: v1(76.17,63.58) R5723.1 75.61,64.41 75.25,64.77 75.25,67.39 75.63,67.77 75.63,75.29 75.48,75.44 75.48,76.67 U136.K1
  BOTTOM w0.147: R5723.1 v1(76.17,63.58)
ADC0_AIN4: length 70.9
  TOP w0.147: R5724.2 66.77,59.76 67.4,59.13 v1(67.76,59.13)
  BOTTOM w0.147: v1(67.76,59.13) 68.11,59.13 68.28,59.3 75.67,59.3 76.16,58.8 76.86,58.8 77.07,59.02 79.68,59.02 84.55,54.15 87.94,54.15 88.71,54.91 89.5,54.91 90.64,53.77 91.15,53.77 91.69,53.24 92.4,53.24 93.77,54.61 96,54.61 96.26,54.36 97.53,54.36 98.11,53.77 103.85,53.77 104.54,54.46 109.82,54.46 109.93,54.57 118.04,54.57 119.81,52.79 U2350.10 U2350.1 129.89,52.79 130.16,53.05 J31.9
ADC0_AIN4_R: length 19.6
  TOP w0.132: U136.F2 71.3,77.66 71.3,75.8
  TOP w0.147: 71.3,75.8 70.76,75.26 70.76,67.28 66.52,63.05 66.52,62.28 v1(66.77,62.03) R5724.1
  BOTTOM w0.147: C3714.1 66.57,61.82 v1(66.77,62.03)
ADC0_AIN5: length 70.2
  TOP w0.147: R5725.2 v1(69.08,58.83)
  BOTTOM w0.147: v1(69.08,58.83) 71.54,58.83 71.67,58.95 75.51,58.95 76.01,58.45 77.01,58.45 77.23,58.67 79.3,58.67 84.55,53.42 90.8,53.42 91.41,52.81 92.47,52.81 93.92,54.25 95.85,54.25 96.12,53.99 97.04,53.99 97.35,53.68 97.35,53.18 97.67,52.86 103.55,52.86 104.79,54.1 109.97,54.1 110.09,54.22 117.89,54.22 119.82,52.29 U2350.9 U2350.2 129.51,52.29 J31.11
ADC0_AIN5_R: length 18.8
  TOP w0.132: 72.1,75.56 72.1,77.66 U136.G2
  TOP w0.147: R5725.1 v1(69.08,62.23) 69.08,64.08 71.7,66.7 71.7,69.62 72.13,70.05 72.13,75.54 72.1,75.56
  BOTTOM w0.147: C3715.1 69.08,61.54 v1(69.08,62.23)
ADC0_AIN6: length 81.5
  TOP w0.147: R5726.2 73.12,62.14 73.47,61.79 v1(73.47,58.5)
  BOTTOM w0.147: v1(73.47,58.5) 75.35,58.5 75.75,58.1 77.17,58.1 77.39,58.32 78.78,58.32 84.04,53.06 90.64,53.06 91.31,52.4 93.85,52.4 95.17,53.72 95.88,53.72 96.33,53.26 96.33,52.76 96.58,52.51 103.81,52.51 104.89,53.59 109.97,53.59 110.25,53.87 117.74,53.87 120.32,51.29 U2350.7 U2350.4 128.91,51.29 130.82,49.39 132.28,49.39 132.7,49.8 132.7,59.55 J31.4
ADC0_AIN6_R: length 17.3
  TOP w0.132: 74.1,76.75 U136.J1
  TOP w0.147: 74.1,76.75 74.8,76.05 74.8,74.32 74.09,73.61 74.09,68.94 73.47,68.33 73.47,67.36 74.03,66.8 74.03,65.05 73.12,64.14 R5726.1 73.91,63.58 v1(74.11,63.78)
  BOTTOM w0.147: R5726.1 73.91,63.58 v1(74.11,63.78)
ADC0_AIN7: length 82
  TOP w0.147: R5727.2 v1(71.87,58.5)
  BOTTOM w0.147: v1(71.87,58.5) 72.69,58.5 73.14,58.04 74.54,58.04 74.56,58.06 75.29,58.06 75.59,57.75 77.33,57.75 77.54,57.97 78.62,57.97 83.89,52.7 90.34,52.7 91,52.04 94,52.04 95.32,53.37 95.72,53.37 95.98,53.11 95.98,52.55 96.37,52.16 103.97,52.16 105,53.19 110.08,53.19 110.4,53.52 117.6,53.52 120.32,50.79 U2350.6 U2350.5 128.92,50.79 131.04,48.67 134.36,48.67 135.25,49.56 135.25,56.71 J31.6
ADC0_AIN7_R: length 18.5
  TOP w0.132: 73.7,76.69 73.7,77.66 U136.J2
  TOP w0.147: 73.7,76.69 74.39,76 74.39,74.73 73.48,73.81 73.48,69.14 72.71,68.38 72.71,65.35 71.87,64.52 v1(71.87,62.59) R5727.1
  BOTTOM w0.147: R5727.1 v1(71.87,62.59)
ADC0_EXT_TRIGGER: length 86.6
  TOP w0.132: 83.71,77.01 83.06,77.66 81.69,77.66 U136.V2
  TOP w0.147: v1(85.23,60.33) 84.73,60.83 84.73,71.93 86.02,73.23 86.02,74.19 84.09,76.12 84.09,76.63 83.71,77.01 ; J31.8 135.35,57.12 v1(135.35,58.93)
  BOTTOM w0.147: v1(85.23,60.33) 85.23,60.96 85.92,61.65 90.72,61.65 91.81,60.55 92.19,60.55 93.59,59.16 97.93,59.16 99.13,57.97 100.02,57.97 100.56,58.5 106.79,58.5 108.47,56.82 113.18,56.82 114.37,58.01 122.93,58.01 129.26,64.34 134.29,64.34 135.35,63.29 v1(135.35,58.93)
ADC0_REFN: length 5.7
  TOP w0.132: 72.9,75.88 72.9,77.66 U136.H2
  TOP w0.147: v1(73.55,75.69) 73.09,75.69 72.9,75.88
  BOTTOM w0.203: v1(73.55,75.69) 73.81,75.44 C3743.1 73.94,75 C3742.2 73.94,73.27 R5728.1
ADC0_REFP: length 63.7
  TOP w0.147: U136.G1 72.5,75.7 72.84,75.36 v1(72.84,74.7)
  TOP w0.381: SW11.2 123.13,59.62 121.86,60.88 v1(121.86,62.23)
  BOTTOM w0.203: v1(72.84,74.7) 73.12,74.7 73.25,74.83 C3743.2
  BOTTOM w0.381: C3742.1 73.02,73.51 73.04,73.48 73.04,71.58 73.86,70.76 77.08,70.76 77.61,70.23 80.87,70.23 81.12,69.98 82.39,69.98 85.01,67.36 91.08,67.36 96.13,62.31 96.99,62.31 97.66,62.97 121.12,62.97 v1(121.86,62.23)
ADC0_REFP_HDR: length 20.5
  TOP w0.305: J31.2 C3745.2 C3744.1
  TOP w0.508: SW11.3 124.88,59.12 126.97,61.21 126.97,63.7 v1(127.78,64.52)
  L03_SIG1 w0.508: J31.2 133.83,64.34 133.37,64.8 128.06,64.8 v1(127.78,64.52)
ADCIN1: length 3.8
  BOTTOM w0.147: R681.1 40.68,14.32 41.01,14.66 41.01,15.4 40.89,15.52 R679.2 40.29,15.78 40.29,16.21 40.65,16.57 U129.6
ADCIN2: length 3.1
  BOTTOM w0.147: U129.10 39.05,16.03 39.21,15.88 R678.2 39.21,14.99 39.41,14.79 R682.1
ADDR0_IO_EXP: length 1.6
  TOP w0.147: U21.26 100.18,136.1 100.06,135.97 R107.1
ADDR1_IO_EXP: length 1.8
  TOP w0.147: R94.1 68.39,136.75 68,136.36 U18.18
AEC1_GPIO0_0: length 161.9
  TOP w0.147: v1(128.14,129.41) 128.37,129.18 J12.42 ; v1(56.91,124.87) 56.3,124.87 54.07,122.63 51.61,122.63 50.94,121.97 50.94,114.58 48.86,112.5 48.86,111.25 48.54,110.93 48.54,103.94 47.44,102.85 47.44,99.58 47.03,99.17 47.03,97.21 47.85,96.39 47.85,91.39 48.28,90.96 48.28,87.25 51.99,83.54 51.99,82.91 52.54,82.35 53.03,82.35 53.48,81.89 53.48,81.48 53.61,81.36 55.16,81.36 57.04,83.24 59.02,83.24 60.8,81.46 61.74,81.46 62.65,80.55 63.52,80.55 64.23,81.26 U136.A6
  BOTTOM w0.147: v1(56.91,124.87) 59.12,122.66 60.01,122.66 61.48,121.19 63.42,121.19 63.8,121.57 73.73,121.57 76.47,118.82 84.35,118.82 86.02,117.14 87.72,117.14 88.51,116.36 94.79,116.36 95.09,116.05 95.5,116.05 95.8,116.36 116.2,116.36 123.57,123.73 129.89,123.73 133.14,126.98 133.14,127.8 131.52,129.41 v1(128.14,129.41)
AEC1_GPIO0_1: length 112.2
  TOP w0.147: J12.44 131.91,128.38 v1(132.68,127.61)
  L03_SIG1 w0.091: v1(63.7,99.34) 61.88,101.16 61.88,115.17 63.19,116.48 v1(63.19,126.75)
  BOTTOM w0.147: v1(63.7,99.34) 64.89,99.34 67.6,96.63 R5757.2 ; v1(63.19,126.75) 63.49,126.44 69.03,126.44 70.12,127.53 71.24,127.53 74.39,130.68 74.8,130.68 75.56,131.44 87.83,131.44 88.28,131.9 91.82,131.9 92.09,131.62 96.08,131.62 97.93,129.77 102.48,129.77 102.9,130.19 116.62,130.19 119.93,126.88 127.48,126.88 128.63,128.03 132.26,128.03 v1(132.68,127.61)
AEC1_REFCLK_SEL: length 25.8
  TOP w0.147: v1(97.76,131.5) 97.07,132.18 97.07,137.47 97.95,138.35 U21.23 ; v1(86.2,131.9) 86.2,134.95 85.97,135.18 R5797.2 85.62,135.68 85.96,136.02 U2346.1
  BOTTOM w0.147: v1(86.2,131.9) 86.5,131.9 87.31,132.72 92.04,132.72 92.42,132.33 96.92,132.33 v1(97.76,131.5)
AEC1_REFCLKIN: length 48
  TOP w0.147: v1(87.34,132.11) 86.73,132.72 86.73,134.92 86.46,135.2 U2346.2 ; v1(122.67,131.78) 122.27,132.18 122.27,135.76 122.88,136.38 J12.33
  BOTTOM w0.147: v1(122.67,131.78) 122.04,131.14 113.45,131.14 112.87,131.72 102.74,131.72 102.46,131.44 99.08,131.44 98.29,130.66 97.68,130.66 96.36,131.98 92.27,131.98 91.94,132.31 88.18,132.31 87.98,132.11 v1(87.34,132.11)
AEC1_REFCLKOUT: length 61
  TOP w0.147: U2346.9 86.46,137.94 86.23,138.18 84.93,138.18 84.47,137.72 84.47,133.8 v1(83.99,133.32) ; v1(126.51,132.72) 126.51,127.36 125.93,126.78 J12.47
  BOTTOM w0.147: v1(83.99,133.32) 85.06,134.39 87.5,134.39 88.03,134.92 92.02,134.92 93.18,133.76 95.37,133.76 95.75,134.14 100.68,134.14 102.74,132.08 113.02,132.08 113.61,131.5 121.07,131.5 122.29,132.72 v1(126.51,132.72)
AEC2_GPIO0_0: length 124.4
  TOP w0.147: J13.42 13.4,137.24 11.66,135.5 11.66,85.48 v1(11.93,85.22) ; v1(53.05,87.58) 53.41,87.58 53.48,87.65 55.87,87.65 56.41,87.12 58.98,87.12 59.82,86.28 62.98,86.28 63.95,85.32 63.95,84.35 64.65,83.66 U136.A9
  BOTTOM w0.147: v1(53.05,87.58) 52.77,87.3 51.3,87.3 50.49,88.11 48.71,88.11 47.31,89.51 46.25,89.51 45.69,88.95 43.99,88.95 40.84,85.8 40.84,82.08 38.59,79.83 32.63,79.83 32.35,79.55 27.32,79.55 22.34,84.54 12.61,84.54 v1(11.93,85.22)
AEC2_GPIO0_1: length 126.8
  TOP w0.132: 64.89,83.25 68.1,83.25 U136.B8
  TOP w0.147: v1(53.94,87.2) 54.42,86.72 58.89,86.72 59.68,85.93 62.83,85.93 63.57,85.19 63.57,84.2 64.52,83.25 64.89,83.25 ; J13.44 13.7,138.04 11.31,135.65 11.31,84.94 v1(11.88,84.38)
  BOTTOM w0.147: v1(11.88,84.38) 12.13,84.13 22.24,84.13 27.17,79.2 32.58,79.2 32.86,79.48 38.73,79.48 41.19,81.94 41.19,85.47 44.29,88.57 45.81,88.57 46.4,89.15 47.16,89.15 48.56,87.76 50.18,87.76 50.99,86.95 53.69,86.95 v1(53.94,87.2)
AEC2_REFCLK_SEL: length 18.8
  TOP w0.147: U21.24 98.24,137.85 98.04,137.65 98.04,134.21 v1(98.9,133.35) ; U2346.5 87.96,135.72 88.19,135.48 R5798.2 89.1,134.49 v1(89.43,134.16)
  BOTTOM w0.147: v1(98.9,133.35) 98.65,133.6 95.72,133.6 95.52,133.4 93.01,133.4 92.25,134.16 v1(89.43,134.16)
AEC2_REFCLKIN: length 75.6
  TOP w0.147: v1(30.4,132.51) 30.6,132.31 30.6,130.4 30.24,130.04 J13.33 ; v1(88.16,133.99) 87.46,134.68 U2346.4
  BOTTOM w0.147: v1(30.4,132.51) 31.69,133.8 37.16,133.8 37.58,133.38 46.86,133.38 47.54,132.69 58.39,132.69 62.88,128.2 67.23,128.2 68.32,129.29 71.44,129.29 73.91,131.75 74.34,131.75 75.66,133.07 81.7,133.07 81.91,132.87 85.26,132.87 86.38,133.99 v1(88.16,133.99)
AEC2_REFCLKOUT: length 73.2
  TOP w0.147: J13.47 26.92,139.64 30.35,136.22 v1(30.35,135.48) ; v1(82.67,133.71) 83.25,133.71 83.96,134.42 83.96,137.79 84.7,138.53 87.11,138.53 87.46,138.18 U2346.7
  BOTTOM w0.147: v1(30.35,135.48) 31.41,134.42 60.7,134.42 61.46,133.65 61.69,133.65 61.71,133.63 62.98,133.63 63.33,133.28 68.71,133.28 69.38,133.95 76.96,133.95 77.03,133.88 82.49,133.88 v1(82.67,133.71)
AUDIO_EXT_REFCLK0: length 93.9
  TOP w0.147: v1(90.95,73.96) 92.3,75.31 92.3,80.09 90.9,81.48 90.9,84.48 87.47,87.91 87.47,90.45 86.12,91.8 86.12,95.81 86.78,96.47 86.78,99.8 84.22,102.36 84.22,109.23 86.75,111.76 92.22,111.76 96.99,116.54 96.99,120.83 96.61,121.21 96.61,126.09 97.52,127 97.52,128.4 95.46,130.47 86.99,130.47 85.12,132.34 85.12,137.53 85.41,137.82 85.82,137.82 85.96,137.67 U2346.10
  BOTTOM w0.147: v1(90.95,73.96) 90.95,74.75 90.33,75.37 R538.2
AUDIO_EXT_REFCLK1: length 87.2
  TOP w0.147: v1(90.8,71.58) 92.65,73.43 92.65,80.24 91.41,81.48 91.41,84.48 89.27,86.61 89.27,92.99 87.14,95.12 87.14,105.13 86.66,105.61 86.66,106.05 87.75,107.14 87.75,109.02 89.12,110.39 91.36,110.39 98.11,117.14 98.11,128.35 94.96,131.5 93.26,131.5 91.97,132.79 91.97,135.79 89.81,137.95 88.31,137.95 87.96,137.6 U2346.6
  BOTTOM w0.147: v1(90.8,71.58) 88.99,73.38 R506.2
AUDIO_EXT_REFCLK1__R: length 8.8
  TOP w0.132: U136.T1 79.82,77.13 79.82,75.62 v1(79.9,75.54)
  BOTTOM w0.147: R506.1 85.53,73.38 84.41,74.5 81.35,74.5 80.74,75.11 80.33,75.11 v1(79.9,75.54)
AUDIO_EXT_REFCLK2: length 30.1
  TOP w0.147: R5689.1 88.64,70.74 90.83,68.55 90.83,66.06 91.15,65.74 v1(91.15,64.95) ; R5686.1 v1(97.12,55.18)
  L03_SIG1 w0.091: v1(91.15,64.95) 91.56,64.54 91.56,61.8 91.28,61.52 91.28,54.97 v1(90.95,54.64)
  BOTTOM w0.147: v1(90.95,54.64) 92.45,54.64 93.21,55.4 96.46,55.4 96.68,55.18 v1(97.12,55.18)
AUDIO_EXT_REFCLK2_R: length 8
  TOP w0.132: U136.V3 81.69,78.46 82.68,78.46 82.8,78.33
  TOP w0.147: R5689.2 84.96,77.19 83.81,78.33 82.8,78.33
AUDIO_EXT_REFCLK2_S0: length 154.4
  TOP w0.147: U2347.6 99.87,55.37 99.97,55.47 99.97,56.38 99.71,56.64 R5795.2 99.26,57.05 v1(99.2,57) ; U21.21 97.33,139.35 96.36,138.38 96.36,131.75 99.38,128.73 99.38,125.78 99.87,125.3 99.87,122.66 101.01,121.52 101.01,119.91 100.32,119.23 100.32,116 94.99,110.67 94.99,95.83 93.11,93.95 93.11,90.96 96.1,87.97 98.39,87.97 v1(99.49,86.87)
  L03_SIG1 w0.091: v1(115.49,57.23) 118.2,59.94 119.95,59.94 121.77,61.77 125.67,61.77 126.2,62.31 126.2,62.81 124.76,64.26 124.76,65.86 127.75,68.86 127.75,70.38 132.3,74.92 132.3,80.11 131.26,81.15 127.07,81.15 121.35,86.87 v1(99.49,86.87)
  BOTTOM w0.147: v1(115.49,57.23) 114.73,56.47 108.33,56.47 106.65,58.15 100.71,58.15 99.55,57 v1(99.2,57)
AUDIO_EXT_REFCLK2_S1: length 106.3
  TOP w0.147: U2347.5 98.64,55.87 98.19,56.32 98.19,57.89 98.19,57.89 98.19,58 98.53,58.34 R5796.2 98.54,58.73 98.81,59 v1(99.28,59) ; U21.22 97.46,138.85 96.72,138.11 96.72,131.89 99.87,128.74 99.87,125.79 100.3,125.36 100.3,122.73 101.36,121.67 101.36,119.99 101.77,119.58 101.77,116.94 95.34,110.51 95.34,95.67 93.46,93.79 93.46,91.16 96.08,88.54 98.65,88.54 102.28,84.91 102.28,82.09 100.86,80.67 99.26,80.67 98.61,80.03 96.2,80.03 94.38,78.21 94.38,73.86 v1(96.74,71.5)
  L03_SIG1 w0.091: v1(99.28,59) 100.09,59 100.7,59.61 100.7,64.54 97.27,67.97 97.27,70.97 v1(96.74,71.5)
BOOTMODE0: length 38.4
  L03_SIG1 w0.091: v1(100.32,126.06) 100.32,123.98 101.41,122.89 101.41,118.92 97.63,115.14 93.16,115.14 87.62,109.6 83.81,109.6 83.23,110.18 82.87,110.18 82.55,109.86 78.99,109.86 78.03,108.89 v1(77.21,108.89)
  BOTTOM w0.147: U81.14 100.18,125.43 100.32,125.58 v1(100.32,126.06) ; RA6.1 77.42,108.78 77.31,108.89 v1(77.21,108.89)
BOOTMODE1: length 41.2
  L03_SIG1 w0.091: v1(79.6,108.51) 80.13,108.51 80.46,108.18 89.73,108.18 94.96,113.41 98.42,113.41 104.03,119.02 104.03,123.44 102.2,125.27 v1(101.87,125.27)
  BOTTOM w0.147: v1(79.6,108.51) 80.15,108.51 80.61,108.05 80.61,107.42 80.72,107.31 RA2.1 ; U81.15 101.06,124.93 101.4,125.27 v1(101.87,125.27)
BOOTMODE2: length 33.2
  L03_SIG1 w0.091: v1(83.05,109.75) 83.48,109.32 87.75,109.32 93.26,114.83 97.73,114.83 101.68,118.79 101.68,123.73 v1(101.24,124.18)
  BOTTOM w0.147: v1(83.05,109.75) 83.74,109.06 RA5.1 ; v1(101.24,124.18) 100.99,124.43 U81.16
BOOTMODE3: length 36.8
  L03_SIG1 w0.091: v1(80.97,109.27) 81.25,109.55 82.33,109.55 82.87,109.02 87.85,109.02 93.39,114.55 97.86,114.55 102.15,118.85 v1(102.15,124.46)
  BOTTOM w0.147: v1(102.15,124.46) 102.15,124.11 101.77,123.72 100.8,123.72 100.6,123.93 U81.17 ; v1(80.97,109.27) 80.97,107.9 81.12,107.75 RA2.2
BOOTMODE4: length 34.6
  L03_SIG1 w0.091: v1(102.81,122.86) 102.81,122.25 102.43,121.87 102.43,118.67 98.04,114.27 97.8,114.27 97.79,114.27 93.64,114.27 88.1,108.74 82.54,108.74 v1(82.24,109.04)
  BOTTOM w0.147: v1(102.81,122.86) 102.38,123.29 100.73,123.29 100.59,123.43 U81.18 ; v1(82.24,109.04) 81.52,108.32 RA2.3
BOOTMODE5: length 38
  L03_SIG1 w0.091: v1(103.22,122.1) 103.73,121.59 103.73,119.13 98.29,113.69 93.87,113.69 89.93,109.75 89.93,109.6 90.09,109.45 90.09,109.09 89.83,108.84 88.61,108.84 88.23,108.46 80.59,108.46 79.93,109.12 v1(79.11,109.12)
  BOTTOM w0.147: v1(103.22,122.1) 102.61,122.1 101.77,122.93 U81.19 ; v1(79.11,109.12) 78.62,108.63 RA6.4
BOOTMODE6: length 27.3
  L03_SIG1 w0.091: v1(89.65,109.27) 89.65,109.88 93.77,114 97.66,114 97.68,113.97 97.91,113.97 97.93,114 98.19,114 102.91,118.72 v1(102.91,121.26)
  BOTTOM w0.147: v1(89.65,109.27) 88.99,109.27 87.96,108.24 RA7.4 ; U81.20 101.74,122.43 v1(102.91,121.26)
BOOTMODE7: length 29.1
  L03_SIG1 w0.091: v1(100.98,119.23) 97.35,115.6 93.2,115.6 87.49,109.88 84.4,109.88 v1(83.81,110.46)
  BOTTOM w0.147: v1(83.81,110.46) 84.54,109.74 RA5.3 ; v1(100.98,119.23) 100.98,119.58 101.03,119.63 101.03,121.08 101.01,121.1 101.01,121.62 100.69,121.93 U81.21
BOOTMODE8: length 20.9
  L03_SIG1 w0.091: v1(83,110.62) 83,111.4 79.7,114.71 78.99,114.71 77.59,116.1 77.59,118.08 76.22,119.46 v1(76.22,120.73)
  BOTTOM w0.147: RA5.2 84.14,109.47 v1(83,110.62) ; U83.14 76.67,120.27 v1(76.22,120.73)
BOOTMODE9: length 21.9
  L03_SIG1 w0.091: v1(82.01,110.31) 81.32,110.31 78.99,112.65 78.99,114.27 77.28,115.98 77.28,116.89 76.55,117.63 76.55,118.44 75.76,119.23 75.76,121.15 76.05,121.44 v1(76.37,121.44)
  BOTTOM w0.147: v1(82.01,110.31) 82.01,109.96 82.72,109.25 82.72,108.11 81.92,107.31 RA2.4 ; v1(76.37,121.44) 77.04,120.77 U83.15
BOOTMODE10: length 22.1
  L03_SIG1 w0.091: v1(77.08,121.64) 77.08,119.3 77.87,118.52 77.87,116.23 79.11,114.99 81.86,114.99 84.8,112.04 v1(84.8,110.54)
  BOTTOM w0.147: v1(77.08,121.64) 77.45,121.27 U83.16 ; v1(84.8,110.54) 84.8,110.19 84.94,110.05 RA5.4
BOOTMODE11: length 21.9
  L03_SIG1 w0.091: v1(85.95,110.31) 85.95,111.3 81.98,115.27 79.24,115.27 78.15,116.36 78.15,118.72 77.54,119.33 77.54,121.29 v1(78.02,121.77)
  BOTTOM w0.147: RA7.1 86.76,108.81 85.95,109.63 v1(85.95,110.31) ; U83.17 v1(78.02,121.77)
BOOTMODE12: length 19
  L03_SIG1 w0.091: v1(78.16,109.87) 78.16,114.69 76.95,115.9 76.95,116.81 76.27,117.5 76.27,118.31 75.38,119.2 75.38,121.59 v1(75.86,122.07)
  BOTTOM w0.147: RA6.3 78.22,108.74 78.53,109.04 78.53,109.5 v1(78.16,109.87) ; v1(75.86,122.07) 76.06,122.27 U83.18
BOOTMODE13: length 20.9
  L03_SIG1 w0.091: v1(77.36,109.6) 76.55,110.41 76.55,111.34 77.72,112.51 77.72,114.63 75.94,116.41 75.94,117.02 74.44,118.52 74.44,121.31 v1(74.97,121.84)
  BOTTOM w0.147: v1(74.97,121.84) 75.9,122.77 U83.19 ; v1(77.36,109.6) 77.82,109.14 RA6.2
BOOTMODE14: length 24.3
  L03_SIG1 w0.091: v1(86.81,110.52) 86.81,111.02 82.29,115.54 79.37,115.54 78.43,116.48 78.43,120.12 78.81,120.5 78.81,121.98 v1(77.51,123.27)
  BOTTOM w0.147: v1(77.51,123.27) U83.20 ; v1(86.81,110.52) 86.81,109.4 87.16,109.04 RA7.2
BOOTMODE15: length 25.7
  L03_SIG1 w0.091: v1(87.62,110.62) 82.39,115.85 80.28,115.85 78.73,117.4 78.73,120.02 79.19,120.47 79.19,122.56 v1(77.41,124.33)
  BOTTOM w0.147: U83.21 77.97,123.77 v1(77.41,124.33) ; RA7.3 87.56,109.31 87.87,109.62 87.87,110.37 v1(87.62,110.62)
BOOTMODE_I2C_EN: length 1.7
  BOTTOM w0.147: U107.5 R578.2
BOOTMODE_I2C_SCL: length 156.2
  TOP w0.147: v1(16.93,79.32) TP71.1
  L03_SIG1 w0.091: v1(30.14,131.01) 30.14,131.7 29.94,131.9 28.77,131.9 27.27,130.4 16.76,130.4 15.21,128.85 15.21,128.19 16.45,126.95 16.45,120.39 14.93,118.87 14.05,118.87 13.17,118 13.17,97.87 16.93,94.11 v1(16.93,79.32) 16.93,66.83 v1(16.55,66.45)
  BOTTOM w0.147: v1(16.93,79.32) 16.97,79.28 R579.1 ; v1(30.14,131.01) 44.21,131.01 45.66,129.57 54.07,129.57 60.14,123.49 72.26,123.49 76.93,128.17 76.93,128.7 77.53,129.31 88.73,129.31 89.22,129.8 90.21,129.8 90.56,129.45 U82.29 ; v1(16.55,66.45) 16.85,66.75 R583.2
BOOTMODE_I2C_SDA: length 135.5
  TOP w0.147: v1(91.38,129.36) 91.38,129.61 TP45.1
  L03_SIG1 w0.091: v1(29.53,131.47) 29.53,129.36 14.33,114.16 14.33,98.9 16.22,97.01 16.22,95.45 17.34,94.34 17.34,79.95 v1(17.86,79.43)
  BOTTOM w0.147: R582.2 16.33,79.61 16.5,79.78 17.51,79.78 v1(17.86,79.43) R580.1 ; v1(29.53,131.47) 44.42,131.47 45.94,129.95 54.99,129.95 56.48,128.46 56.48,127.76 60.39,123.85 71.19,123.85 77.01,129.67 88.59,129.67 89.07,130.15 90.6,130.15 v1(91.38,129.36) 91.38,128.98 91.06,128.66 U82.30
BOOTMODEON: length 58.2
  TOP w0.147: v1(78.45,124.74) 77.97,125.22 74.11,125.22 73.55,125.78 73.55,128.55 74.26,129.26 80.66,129.26 81.75,130.35 81.75,133.48 83.56,135.28 83.56,139.95 83.17,140.34 R112.2 82.76,139.99 82.64,139.87 U23.4
  L03_SIG1 w0.091: v1(78.45,124.74) 80.03,126.32 84.26,126.32 84.53,126.59 86.33,126.59 86.63,126.29 91.5,126.29 94.44,123.36 94.67,123.36 95.04,122.99 95.88,122.99 96.16,122.71 96.16,121.62 97.33,120.45 98.98,120.45 99.84,121.31 v1(100.55,121.31)
  BOTTOM w0.147: U83.22 78.92,124.27 v1(78.45,124.74) ; U81.22 100.43,121.43 v1(100.55,121.31)
BUF_BOOTMODE_I2C0_SCL: length 60.5
  TOP w0.147: v1(21.18,87.01) 21.7,86.49 28.19,86.49 28.71,87.01 U48.82 ; v1(51.63,103.71) 51.73,103.71 51.75,103.72 R119.2 U25.7
  L03_SIG1 w0.091: v1(21.18,87.01) 21.66,87.49 21.66,91.01 20.39,92.28 20.39,100.15 v1(19.86,100.69)
  BOTTOM w0.147: v1(19.86,100.69) 22.29,103.12 29.3,103.12 30.63,101.8 34.74,101.8 35.64,100.9 37.93,100.9 38.37,101.35 49.27,101.35 v1(51.63,103.71)
BUF_BOOTMODE_I2C0_SDA: length 47
  TOP w0.147: v1(27.93,87.05) 28.3,87.41 U48.81 ; U25.6 R118.2 49.82,103.72 47.8,101.7 v1(47.8,99.29)
  L03_SIG1 w0.091: v1(26.48,99.24) 26.89,98.83 26.89,96.11 28.9,94.11 28.9,87.48 28.47,87.05 v1(27.93,87.05)
  BOTTOM w0.147: v1(26.48,99.24) 27.75,99.24 28.44,99.92 34.26,99.92 34.71,99.47 40.05,99.47 40.58,100 43.78,100 45.36,98.42 47.49,98.42 47.8,98.73 v1(47.8,99.29)
BUF_BOOTMODE_I2C_SCL: length 57.1
  TOP w0.147: U48.49 37.13,96.28 37,96.42 v1(37,97.56)
  L03_SIG1 w0.091: v1(16.17,97.89) 16.5,97.56 16.5,96.34 17.67,95.17 17.67,80.54 18.31,79.91 18.31,79.2 17.49,78.38 v1(17.49,69.47)
  BOTTOM w0.147: v1(16.17,97.89) 28.17,97.89 30.3,95.76 32.85,95.76 33.95,96.87 33.95,96.96 34.1,97.1 34.16,97.1 34.86,97.81 36.75,97.81 v1(37,97.56) ; U107.7 R552.2 17.15,69.11 17.47,69.42 17.47,69.44 v1(17.49,69.47)
BUF_BOOTMODE_I2C_SDA: length 55.8
  TOP w0.147: U48.50 36.73,96.18 36.51,96.4 v1(36.51,96.67)
  L03_SIG1 w0.091: v1(16.93,97.31) 17.95,96.29 17.95,80.67 18.59,80.04 18.59,78.89 17.92,78.23 17.92,69.32 v1(18.79,68.45)
  BOTTOM w0.147: v1(16.93,97.31) 28.26,97.31 30.16,95.41 32.99,95.41 34.31,96.73 34.31,96.75 34.87,97.31 35.87,97.31 v1(36.51,96.67) ; U107.6 R551.2 18.49,69.11 18.79,68.81 v1(18.79,68.45)
BUF_TEST_GPIO1: length 18.3
  TOP w0.147: U48.74 28.71,90.21 27.98,89.48 27.17,89.48 26.89,89.77 25.9,89.77 v1(25.62,90.04) ; v1(15.92,89.46) 15.54,89.84 U40.1
  BOTTOM w0.147: v1(25.62,90.04) 24.09,88.52 18,88.52 17.06,89.46 v1(15.92,89.46) 15,89.46 14.76,89.7 R519.2
BUF_TEST_GPIO2: length 24.7
  TOP w0.147: U48.73 28.6,90.61 27.93,89.94 27.22,89.94 26.58,90.58 21.3,90.58 v1(21.05,90.83) ; U51.7 21.94,79.17 R280.2 21.64,78.34 v1(21.28,77.98)
  L03_SIG1 w0.091: v1(21.05,90.83) 20.44,90.22 20.44,83.54 21,82.98 21,78.25 v1(21.28,77.98)
BUF_TEST_GPIO3: length 29.2
  TOP w0.147: v1(14.27,89.23) 14.74,89.7 U40.3 ; U48.72 28.49,91.01 27.78,90.3 27.37,90.3 26.64,91.03 24.94,91.03 23.94,92.02 23.94,94.54 v1(24.38,94.97)
  L03_SIG1 w0.091: v1(14.27,89.23) 15.87,90.83 15.87,94.01 v1(14.83,95.05)
  BOTTOM w0.147: v1(14.83,95.05) 15.08,95.3 24.05,95.3 v1(24.38,94.97) ; v1(14.27,89.23) 13.96,89.53 R515.2
BUF_TEST_GPIO4: length 31.4
  TOP w0.147: v1(24.53,95.78) 24.91,95.4 24.91,92.43 25.93,91.41 U48.71 ; v1(13.73,88.6) 13.73,89.56 13.94,89.77 U40.5
  L03_SIG1 w0.091: v1(14.29,95.68) 14.29,94.87 14.67,94.49 14.67,90.73 13.73,89.79 v1(13.73,88.6)
  BOTTOM w0.147: v1(24.53,95.78) 23.48,96.83 15.44,96.83 v1(14.29,95.68) ; v1(13.73,88.6) 13.73,89.16 13.16,89.73 R510.2
BUF_TEST_PORZN: length 19.9
  TOP w0.147: v1(13.3,86.39) 13.54,86.15 U40.9 ; v1(26.43,88.75) 28.31,88.75 28.57,89.01 U48.77
  BOTTOM w0.147: R512.2 13.54,86.15 v1(13.3,86.39) 13.81,86.89 15.69,86.89 16.27,87.48 25.16,87.48 v1(26.43,88.75)
BUF_TEST_POWERDOWN: length 17.7
  TOP w0.147: U48.78 28.71,88.61 28.47,88.37 26.92,88.37 26.31,87.76 v1(26.31,87.05) ; v1(15.14,86.11) U40.13
  BOTTOM w0.147: R525.2 v1(15.14,86.11) 25.37,86.11 v1(26.31,87.05)
BUF_TEST_WARMRESETN: length 19.3
  TOP w0.147: v1(14.22,86.18) 14.34,86.06 U40.11 ; U48.76 28.44,89.41 28.14,89.1 27.04,89.1 26.92,89.23 v1(25.62,89.23)
  L03_SIG1 w0.091: v1(14.22,86.18) 14.22,86.99 v1(14.59,87.36)
  BOTTOM w0.147: v1(14.59,87.36) 15.23,88.01 24.4,88.01 v1(25.62,89.23) ; v1(14.22,86.18) 14.34,86.06 R517.2
CAN-FD_INH: length 168.1
  TOP w0.147: R3028.2 v1(26.56,15.29) ; U3068.7 40.86,160.5 41.22,160.86 TP585.1 41.22,163.21 v1(41.22,163.22)
  L03_SIG1 w0.091: v1(41.22,163.22) 40.15,163.22 37.53,160.6 37.53,154.74 34.89,152.09 34.89,106.67 33.57,105.36 33.57,100.71 30.02,97.16 30.02,94.69 29.79,94.46 29.79,90.86 32.22,88.42 32.22,87.43 31.49,86.69 31.49,84.4 32.02,83.87 32.02,82.73 31.73,82.44 31.73,61.62 27.96,57.85 27.96,50.75 28.54,50.16 28.54,44.91 25.49,41.86 25.49,35.28 v1(26.59,34.19)
  BOTTOM w0.147: v1(26.59,34.19) 27.27,33.51 27.27,29.8 32.04,25.03 32.04,23.32 32.04,23.32 32.04,20.03 27.3,15.29 v1(26.56,15.29)
CAP_VDDS0: length 0.9
  TOP w0.305: U136.L6 v1(76.1,81.66)
  BOTTOM w0.305: C454.1 75.93,81.49 v1(76.1,81.66)
CAP_VDDS1: length 0.9
  TOP w0.305: U136.F13 v1(71.3,87.25)
  BOTTOM w0.305: v1(71.3,87.25) 71.43,87.39 C434.1
CAP_VDDS2: length 0.9
  TOP w0.305: U136.R11 v1(79.3,85.65)
  BOTTOM w0.305: v1(79.3,85.65) 79.38,85.57 C446.1
CAP_VDDS3: length 0.9
  TOP w0.305: U136.H15 v1(72.9,88.85)
  BOTTOM w0.305: C432.1 72.78,88.73 v1(72.9,88.85)
CAP_VDDS5: length 1
  TOP w0.305: U136.P8 v1(77.7,83.26)
  BOTTOM w0.305: C443.1 77.93,83.02 v1(77.7,83.26)
CAP_VDDS_CANUART: length 0.9
  TOP w0.305: U136.E6 v1(70.5,81.66)
  BOTTOM w0.305: C509.1 70.68,81.66 v1(70.5,81.66)
CAP_VDDS_MCU: length 0.9
  TOP w0.147: U136.E8 v1(70.5,83.26)
  BOTTOM w0.305: v1(70.5,83.26) 70.64,83.4 C484.1
CDCE_CLKOUT_1: length 24.2
  TOP w0.147: v1(93.82,56.31) 94.33,56.82 94.56,56.82 95.34,57.61 95.34,60.6 95.14,60.81 94.61,60.81 92.37,63.04 90.16,63.04 89.2,62.08 R89.1 ; U2347.3 v1(103.44,55.37)
  BOTTOM w0.147: v1(93.82,56.31) 97.27,56.31 98.32,55.27 101.77,55.27 101.87,55.37 v1(103.44,55.37)
CLKOUT0: length 2.3
  BOTTOM w0.147: U65.1 65.19,53.62 65.33,53.48 R336.2
CLKOUT_OSC: length 13.6
  BOTTOM w0.147: U62.3 77.51,52.57 76.89,51.94 73.17,51.94 72.69,51.46 70.55,51.46 70.23,51.14 67.85,51.14 66.73,52.26 R336.1
CORE_CONFIG: length 43.4
  TOP w0.147: TP76.1 R371.2 51.75,39.88 51.54,39.67 SW7.3 49.57,39.67 47.57,37.67 41.65,37.67 39.92,39.4 38.85,39.4 38.5,39.75 33.62,39.75 32.63,40.74 v1(32.63,41.78) ; v1(31.77,54.86) U56.8
  L03_SIG1 w0.091: v1(32.63,41.78) 32.63,43 33.7,44.07 33.7,52.93 v1(31.77,54.86)
CPSW_ETH_INTN: length 55.3
  TOP w0.147: v1(83.72,37.73) 83.43,37.44 83.43,36.29 v1(83.8,35.93) ; U3077.12 95.81,66.98 97.34,65.45 97.34,61.71 97.12,61.49 97.12,56.85 95.52,55.24 v1(95.52,52.91)
  L03_SIG1 w0.091: v1(97.66,36.27) 97.66,46.84 95.06,49.43 95.06,52.45 v1(95.52,52.91)
  BOTTOM w0.147: v1(97.66,36.27) 97.05,36.88 93.29,36.88 92.68,37.49 91.18,37.49 90.42,36.73 90.39,36.73 89.78,36.12 88.87,36.12 87.5,37.49 86.3,37.49 84.74,35.93 v1(83.8,35.93) ; v1(83.72,37.73) 83.38,38.06 83.38,38.89 83.53,39.04 R621.1
CPSW_ETH_INTN_1V8: length 13.2
  TOP w0.147: v1(85.67,75.69) 86.81,74.55 86.81,72.9 85.44,71.53 85.44,67.87 86.33,66.98 U3077.3
  BOTTOM w0.147: v1(85.67,75.69) 85.29,76.07 R205.2
CPSW_RGMII1_BCLK: length 25.4
  TOP w0.147: U29.3 101.76,60.16 101.69,60.22 101.69,60.28 101.01,60.97 99.77,60.97 99.61,60.81 99.61,60.09 98.88,59.36 98.34,59.36 97.83,58.85 97.83,56.54 96.36,55.07 96.36,46.25 93.31,43.21 92.67,43.21 92.41,42.94 J18.48
CPSW_RGMII1_BCLK_1V8: length 5
  TOP w0.147: U2347.2 101.56,54.87 100.96,55.47 100.96,56.62 101.76,57.41 U29.6
CPSW_RGMII1_BRD_CONN_DET: length 2
  TOP w0.147: J18.36 90.01,43 89.46,43.55 R355.2
CPSW_RGMII1_COL: length 5.9
  TOP w0.147: TP590.1 83.61,46.35 84.22,45.75 84.9,45.75 85.61,45.04 J18.14
CPSW_RGMII1_CRS: length 5.1
  TOP w0.147: TP591.1 88.58,46.68 88.58,43.34 88.81,43.11 J18.30
CPSW_RGMII1_ETH1_CLK: length 38.4
  TOP w0.147: J18.28 88.41,43.02 88.08,43.34 88.08,51.36 87.44,51.99 85.59,51.99 84.93,51.33 84.93,48.82 83.12,47.01 82.43,47.01 81.09,45.68 81.09,45.13 80.57,44.6 76.39,44.6 76.12,44.87 76.12,46.71 74.82,48.01 74.82,51.21 74.11,51.92 v1(72.48,51.92)
  BOTTOM w0.147: R359.2 72.44,53.62 72.86,53.19 72.86,52.3 v1(72.48,51.92)
CPSW_RGMII1_MDC: length 6.9
  TOP w0.147: R338.2 84.76,47.17 84.49,46.91 R342.2 84.49,46.4 84.76,46.13 85.63,46.13 86.23,45.54 86.23,44.65 86.81,44.07 J18.20
CPSW_RGMII1_MDIO: length 6.8
  TOP w0.147: J18.22 87.21,44.18 86.6,44.79 R343.1 86.94,46.92 86.94,47.85 86.7,48.1 R340.2
CPSW_RGMII1_RD0: length 67.5
  TOP w0.147: U136.W11 82.51,85.25 82.54,85.29 v1(82.9,85.29) ; J18.23 87.61,39.05 86.48,37.92 v1(86.48,36.98)
  L03_SIG1 w0.091: v1(82.9,85.29) 83.33,84.86 83.33,84 84.35,82.98 84.35,81.25 84.75,80.85 84.75,77.98 85.01,77.72 85.01,75.31 85.87,74.45 85.87,70.36 84.88,69.37 84.88,63.6 82.69,61.42 82.69,54.19 81.37,52.86 81.37,50.13 81.59,49.91 81.59,45.84 80.23,44.48 80.23,37.9 81.75,36.37 84.88,36.37 85.95,37.44 87.95,37.44 88.64,36.75 88.64,36.59 88.47,36.42 88.21,36.42 87.65,36.98 v1(86.48,36.98)
CPSW_RGMII1_RD1: length 67.5
  TOP w0.147: U136.T11 v1(80.1,84.85) ; v1(86.38,36.12) 86.94,36.68 86.94,37.74 88.01,38.82 J18.25
  L03_SIG1 w0.091: v1(80.1,84.85) 80.47,84.48 81.1,84.48 81.93,83.64 82.64,83.64 83.02,83.26 83.02,79.15 82.85,78.97 82.85,78.54 83.1,78.28 83.48,78.28 84.29,77.47 84.29,63.91 82.14,61.75 82.14,54.4 80.66,52.93 80.66,49.91 80.46,49.71 80.46,49.35 80.92,48.9 80.92,46.08 79.6,44.75 79.6,35.86 81.04,34.42 85.41,34.42 86.38,35.38 v1(86.38,36.12)
CPSW_RGMII1_RD2: length 67.5
  TOP w0.147: U136.T12 v1(80.1,86.45) ; J18.27 88.41,38.28 87.6,37.47 87.6,36.44 v1(87.33,36.17)
  L03_SIG1 w0.091: v1(80.1,86.45) 80.33,86.23 80.33,86.11 82.47,83.97 82.9,83.97 83.51,83.36 83.51,81.03 84.27,80.26 84.27,78.05 84.6,77.72 84.6,63.78 82.42,61.59 82.42,54.3 81.09,52.98 81.09,50.02 81.32,49.79 81.32,46.07 79.9,44.65 79.9,36.14 80.71,35.33 84.78,35.33 86,36.55 86.95,36.55 v1(87.33,36.17)
CPSW_RGMII1_RD3: length 67.5
  TOP w0.147: J18.29 88.81,38.51 89.07,38.25 v1(89.07,37.88) ; U136.U12 v1(80.9,86.45)
  L03_SIG1 w0.091: v1(89.07,37.88) 90.25,37.88 90.42,38.05 90.42,39.09 90.06,39.45 89.36,39.45 87.99,38.07 83.99,38.07 81.73,40.34 81.73,45.2 82.14,45.61 82.14,50.13 81.92,50.36 81.92,52.63 83.25,53.97 83.25,61.01 85.46,63.22 85.46,68.96 87.13,70.63 87.13,72.34 86.63,72.85 86.63,77.17 85.44,78.36 85.44,81.97 84.96,82.45 84.96,83.29 84.19,84.05 84.19,85.09 82.83,86.45 v1(80.9,86.45)
CPSW_RGMII1_RESETN: length 29.7
  TOP w0.147: v1(85.39,41.48) 85.21,41.66 J18.12 ; U68.4 70.52,49.87 70.63,49.76 70.63,49.54 70.22,49.14 R373.1 70.57,48.8 70.81,48.56 R5824.2 71.85,48.56 71.93,48.64 v1(72.28,48.64)
  L03_SIG1 w0.091: v1(72.89,43.46) 72.89,48.03 v1(72.28,48.64)
  BOTTOM w0.147: v1(85.39,41.48) 85.06,41.81 82.19,41.81 77.91,37.52 75.57,37.52 73.92,39.18 73.92,41.39 74.21,41.68 74.21,43.14 73.89,43.46 v1(72.89,43.46)
CPSW_RGMII1_RX_DV: length 67.5
  TOP w0.132: v1(83.61,85.14) 83.61,85.49 83.32,85.78 82.75,85.78 82.63,85.66 81.93,85.66 81.54,86.05 U136.V12
  TOP w0.147: J18.45 92.01,37.56 91.03,36.58 v1(89.58,36.58)
  L03_SIG1 w0.091: v1(83.61,85.14) 83.86,84.89 83.86,83.9 84.65,83.11 84.65,82.3 85.11,81.84 85.11,78.18 86.2,77.09 86.2,70.15 85.16,69.11 85.16,63.48 82.98,61.3 82.98,54.08 81.64,52.75 81.64,50.24 81.87,50.02 81.87,45.73 81.42,45.28 81.42,38 82.16,37.26 85.31,37.26 85.84,37.8 88.36,37.8 v1(89.58,36.58)
CPSW_RGMII1_RXC: length 67.4
  TOP w0.147: v1(86.33,38.76) 86.68,38.76 86.81,38.89 J18.19 ; v1(83.74,86.23) 83.28,86.23 83.1,86.05 U136.W12
  L03_SIG1 w0.091: v1(83.74,86.23) 84.47,85.5 84.47,84.25 85.23,83.49 85.23,82.63 85.79,82.07 85.79,78.54 86.96,77.37 86.96,73.05 87.5,72.52 87.5,70.46 86.56,69.52 86.56,65.87 85.77,65.08 85.77,63.14 83.61,60.98 83.61,60.17 83.72,60.06 84.11,60.06 84.22,59.96 84.22,59.81 84.11,59.7 83.72,59.7 83.61,59.59 83.61,59.44 83.72,59.33 84.11,59.33 84.22,59.23 84.22,59.07 84.11,58.97 83.72,58.97 83.61,58.86 83.61,58.14 84.12,57.63 84.12,57.28 83.63,56.79 83.63,56.15 83.74,56.04 84.24,56.04 84.35,55.93 84.35,55.78 84.24,55.67 83.74,55.67 83.63,55.57 83.63,55.42 83.74,55.31 84.24,55.31 84.35,55.2 84.35,55.05 84.24,54.94 83.74,54.94 83.63,54.84 83.63,53.96 82.19,52.52 82.19,50.47 82.41,50.25 82.41,49.85 82.52,49.74 82.71,49.74 82.82,49.64 82.82,49.48 82.71,49.38 82.52,49.38 82.41,49.27 82.41,49.12 82.52,49.01 82.71,49.01 82.82,48.9 82.82,48.75 82.71,48.65 82.52,48.65 82.41,48.54 82.41,48.39 82.52,48.28 82.71,48.28 82.82,48.17 82.82,48.02 82.71,47.91 82.52,47.91 82.41,47.81 82.41,47.66 82.52,47.55 82.71,47.55 82.82,47.44 82.82,47.29 82.71,47.18 82.52,47.18 82.41,47.08 82.41,46.92 82.52,46.82 82.71,46.82 82.82,46.71 82.82,46.56 82.71,46.45 82.52,46.45 82.41,46.34 82.41,45.5 82.1,45.19 82.1,43.52 82.21,43.41 82.45,43.41 82.54,43.32 82.54,43.15 82.44,43.05 82.21,43.05 82.1,42.94 82.1,42.79 82.21,42.68 82.44,42.68 82.54,42.57 82.54,42.42 82.44,42.31 82.21,42.31 82.1,42.21 82.1,42.06 82.21,41.95 82.44,41.95 82.54,41.84 82.54,41.69 82.44,41.58 82.21,41.58 82.1,41.48 82.1,40.37 83.27,39.2 84.28,39.2 85.13,38.35 85.92,38.35 v1(86.33,38.76)
CPSW_RGMII1_TD0: length 59.6
  TOP w0.147: v1(84.27,40.41) 84.41,40.27 J18.7
  L03_SIG1 w0.091: v1(87.22,85.8) 86.89,85.8 86.68,85.6 86.68,84.99 89.65,82.02 89.65,77.65 89.32,77.32 89.32,65.38 89.1,65.15 89.1,63.75 89.32,63.53 89.32,62.03 88.89,61.59 88.89,59.51 88.14,58.76 88.14,54.95 85.95,52.76 85.95,50.39 88.77,47.57 88.77,40.92 87.39,39.55 85.54,39.55 84.68,40.41 v1(84.27,40.41)
  BOTTOM w0.147: R530.2 84.71,87.44 85.64,86.51 86.86,86.51 87.22,86.15 v1(87.22,85.8)
CPSW_RGMII1_TD1: length 59
  TOP w0.147: v1(84.88,85.45) 85.77,85.45 85.92,85.59 R535.2 ; J18.9 84.81,39.06 85.01,38.86 v1(85.39,38.86)
  L03_SIG1 w0.091: v1(84.88,85.45) 85.13,85.19 85.13,84.38 86.02,83.49 86.02,82.68 86.33,82.37 86.33,79.04 87.5,77.88 87.5,75.74 87.93,75.31 87.93,69.13 87.82,69.02 87.6,69.02 87.5,68.91 87.5,68.76 87.6,68.65 87.82,68.65 87.93,68.55 87.93,68.4 87.82,68.29 87.6,68.29 87.5,68.18 87.5,68.03 87.6,67.92 87.82,67.92 87.93,67.82 87.93,67.66 87.82,67.56 87.6,67.56 87.5,67.45 87.5,67.3 87.6,67.19 87.82,67.19 87.93,67.08 87.93,66.29 87.62,65.99 87.62,65.44 87.52,65.33 87.17,65.33 87.06,65.22 87.06,65.07 87.17,64.96 87.52,64.96 87.62,64.86 87.62,64.44 87.36,64.18 87.21,64.18 86.92,64.47 86.72,64.47 86.62,64.38 86.62,64.25 86.95,63.92 86.95,63.77 86.85,63.66 86.69,63.66 86.45,63.91 86.3,63.91 86.19,63.8 86.19,63.65 86.44,63.41 86.44,63.25 86,62.81 86,58.45 85.16,57.61 85.16,54.71 84.02,53.57 84.02,52.22 83.25,51.46 83.25,43.61 83.02,43.38 83.02,40.46 83.86,39.62 84.95,39.62 85.39,39.19 v1(85.39,38.86)
CPSW_RGMII1_TD2: length 60.9
  TOP w0.147: v1(85.01,40.82) 85.01,40.46 85.21,40.26 J18.11
  L03_SIG1 w0.091: v1(86.53,86.06) 86.3,85.83 86.3,84.96 89.37,81.89 89.37,77.77 89.04,77.44 89.04,65.51 88.82,65.28 88.82,63.63 89.04,63.4 89.04,62.15 88.59,61.7 88.59,59.61 87.83,58.85 87.83,55.04 85.62,52.83 85.62,49.43 88.49,46.56 88.49,41.07 87.27,39.85 85.76,39.85 85.67,39.94 85.67,40.73 85.58,40.82 v1(85.01,40.82)
  BOTTOM w0.147: R537.2 82.08,86.31 82.59,85.8 84.45,85.8 84.75,86.11 85.18,86.11 85.62,85.67 86.15,85.67 v1(86.53,86.06)
CPSW_RGMII1_TD3: length 61.3
  TOP w0.147: J18.13 85.61,40.78 85.92,41.1 85.92,41.1 v1(86.17,41.35)
  L03_SIG1 w0.091: v1(86.63,86.97) 86.3,86.97 86,86.66 86,84.86 88.69,82.17 88.69,81.58 87.93,80.82 87.93,79.07 88.92,78.08 88.92,77.72 88.77,77.57 88.77,65.63 88.54,65.41 88.54,63.5 88.77,63.27 88.77,62.28 88.31,61.82 88.31,59.74 87.52,58.95 87.52,55.14 85.34,52.96 85.34,47.98 85.77,47.55 85.77,47.4 85.59,47.22 85.59,47.07 85.7,46.96 85.85,46.96 86.03,47.14 86.18,47.14 86.29,47.03 86.29,46.88 86.11,46.7 86.11,46.55 86.21,46.44 86.37,46.44 86.54,46.62 86.7,46.62 86.8,46.51 86.8,46.36 86.62,46.18 86.62,46.03 86.73,45.93 86.88,45.93 87.06,46.1 87.21,46.1 88.05,45.26 88.05,41.17 87.77,40.89 86.63,40.89 v1(86.17,41.35)
  BOTTOM w0.147: R529.2 84.86,88 85.9,86.97 v1(86.63,86.97)
CPSW_RGMII1_TX_EN: length 63.8
  TOP w0.147: v1(86.89,41.5) 86.89,41.15 87.12,40.92 89.25,40.92 90.01,40.16 J18.35 ; U136.T13 v1(80.1,87.25)
  L03_SIG1 w0.091: v1(80.1,87.25) 80.47,87.63 81.05,87.63 81.32,87.36 81.32,87.1 81.54,86.88 83.04,86.88 83.41,87.25 84.7,87.25 85.72,86.23 85.72,84.63 87.62,82.73 87.62,78.56 88.05,78.13 88.05,76 88.49,75.56 88.49,66.04 88.26,65.81 88.26,63.83 87.77,63.35 87.77,62.89 86.71,61.82 86.71,59.66 87.04,59.33 87.04,57.68 86.61,57.25 86.61,54.81 84.88,53.09 84.88,46.05 85.25,45.68 85.4,45.68 85.68,45.96 85.84,45.96 85.94,45.85 85.94,45.7 85.66,45.42 85.66,45.27 85.77,45.16 85.92,45.16 86.2,45.44 86.35,45.44 86.46,45.33 86.46,45.18 86.18,44.9 86.18,44.75 86.89,44.04 86.89,43.8 86.99,43.69 87.34,43.69 87.44,43.59 87.44,43.44 87.34,43.33 86.99,43.33 86.89,43.22 86.89,43.07 86.99,42.96 87.25,42.96 87.34,42.87 87.34,42.69 87.25,42.6 86.99,42.6 86.89,42.49 v1(86.89,41.5)
CPSW_RGMII1_TXC: length 59.2
  TOP w0.132: 84.9,86.18 84.73,86.18 84.6,86.31 v1(84.6,86.51)
  TOP w0.147: v1(83.53,40.87) 83.53,40.39 83.61,40.32 J18.3 ; 84.9,86.18 R239.2
  L03_SIG1 w0.091: v1(84.6,86.51) 85.41,85.7 85.41,84.51 86.35,83.57 86.35,82.75 86.61,82.5 86.61,79.17 87.77,78 87.77,75.87 88.21,75.44 88.21,66.17 87.98,65.94 87.98,64.39 86.28,62.69 86.28,58.32 85.44,57.48 85.44,57.21 85.55,57.1 86.14,57.1 86.25,56.99 86.25,56.84 86.14,56.74 85.55,56.74 85.44,56.63 85.44,56.48 85.55,56.37 86.14,56.37 86.25,56.26 86.25,56.11 86.14,56 85.55,56 85.44,55.9 85.44,55.75 85.55,55.64 86.13,55.64 86.23,55.55 86.23,55.36 86.13,55.27 85.55,55.27 85.44,55.17 85.44,54.58 84.29,53.44 84.29,52.1 83.53,51.33 83.53,49.32 83.64,49.21 83.84,49.21 83.94,49.11 83.94,48.95 83.84,48.85 83.64,48.85 83.53,48.74 83.53,48.59 83.64,48.48 83.84,48.48 83.94,48.37 83.94,48.22 83.84,48.12 83.64,48.12 83.53,48.01 83.53,47.86 83.64,47.75 83.84,47.75 83.94,47.64 83.94,47.49 83.84,47.38 83.64,47.38 83.53,47.28 83.53,47.12 83.64,47.02 83.84,47.02 83.94,46.91 83.94,46.76 83.84,46.65 83.64,46.65 83.53,46.54 83.53,46.39 83.64,46.29 83.78,46.29 83.92,46.14 83.92,46.01 83.83,45.92 83.64,45.92 83.53,45.81 83.53,45.66 83.64,45.55 83.81,45.55 83.92,45.45 83.92,45.3 83.81,45.19 83.64,45.19 83.53,45.08 83.53,44.93 83.64,44.82 83.81,44.82 83.92,44.72 83.92,44.56 83.81,44.46 83.64,44.46 83.53,44.35 v1(83.53,40.87)
CPSW_RGMII2_BCLK: length 47
  TOP w0.147: U29.2 102.16,60.13 102.15,60.13 102.15,60.88 102.74,61.47 111.12,61.47 112.13,60.45 112.72,60.45 113.23,60.96 113.23,63.32 113.45,63.55 117.14,63.55 117.72,62.97 117.72,53.21 121.51,49.43 124.27,49.43 125.11,48.59 125.11,46.41 126.05,45.47 126.05,43.66 125.87,43.48 125.54,43.48 125.29,43.23 125.12,43.23 124.84,42.95 J19.48
CPSW_RGMII2_BCLK_1V8: length 6.4
  TOP w0.147: U29.7 102.16,56.79 102.61,56.34 103.12,56.34 103.9,55.56 103.9,54.68 103.59,54.37 U2347.1
CPSW_RGMII2_BRD_CONN_DET: length 4.9
  TOP w0.147: R341.2 122.77,46.24 122.19,45.67 122.19,43.36 122.44,43.11 J19.36
CPSW_RGMII2_COL: length 6.8
  TOP w0.147: J19.14 118.04,43.35 117.92,43.46 117.92,45.84 118.33,46.25 118.33,47.18 TP588.1
CPSW_RGMII2_CRS: length 1.7
  TOP w0.147: J19.30 121.24,42.86 121.5,43.12 TP589.1
CPSW_RGMII2_ETH2_CLK: length 95.1
  TOP w0.147: J19.28 120.84,43.65 120.79,43.69 120.79,44.78 121.15,45.14 121.15,48.79 119.88,50.06 115.41,50.06 113.76,48.41 100.96,48.41 95.67,43.13 95.67,36.63 96.28,36.02 96.28,34.09 93.79,31.6 90.67,31.6 89.71,32.56 87.93,32.56 87.7,32.33 82.06,32.33 80.05,34.34 80.05,42.04 77.84,44.25 76.24,44.25 75.77,44.73 75.77,46.57 74.34,48 74.34,50.62 73.83,51.13 72.42,51.13 71.93,51.63 71.93,52 72.05,52.13 v1(72.05,52.5)
  BOTTOM w0.147: R358.2 67.94,55.42 68.57,54.79 68.57,52.63 68.83,52.37 69.66,52.37 70.22,52.93 71.62,52.93 v1(72.05,52.5)
CPSW_RGMII2_MDC: length 3
  TOP w0.147: J19.20 119.24,42.97 118.51,43.7 R356.2 R352.2
CPSW_RGMII2_MDIO: length 4.3
  TOP w0.147: J19.22 119.64,44.63 119.96,44.95 R351.1 R345.2
CPSW_RGMII2_RD0: length 86.1
  TOP w0.147: v1(120.26,38.86) 120.04,39.09 J19.23 ; U136.U15 v1(80.9,88.85)
  L03_SIG1 w0.091: v1(80.9,88.85) 81.27,88.48 81.92,88.48 82.77,89.33 84.04,89.33 84.37,89 86.94,89 91.79,84.15 91.79,78.49 92.6,77.67 92.6,66.6 93.41,65.79 93.41,59.79 94.38,58.83 95.01,58.83 95.29,58.55 95.29,55.75 96.44,54.61 97.2,54.61 97.78,54.03 98.16,54.03 98.57,53.62 98.57,52.7 105.86,45.42 109.67,45.42 112.84,42.24 113.51,42.24 113.62,42.13 113.62,41.66 113.73,41.55 113.88,41.55 113.98,41.66 113.98,42.13 114.09,42.24 114.24,42.24 114.35,42.13 114.35,41.66 114.46,41.55 114.61,41.55 114.72,41.66 114.72,42.13 114.82,42.24 114.97,42.24 115.08,42.13 115.08,41.66 115.19,41.55 115.34,41.55 115.45,41.66 115.45,42.13 115.55,42.24 116.14,42.24 116.25,42.35 116.25,42.84 116.35,42.95 116.5,42.95 116.61,42.84 116.61,42.35 116.72,42.24 116.87,42.24 116.98,42.35 116.98,42.84 117.08,42.95 117.24,42.95 117.34,42.84 117.34,42.35 117.45,42.24 117.6,42.24 117.71,42.35 117.71,42.84 117.82,42.95 117.97,42.95 118.07,42.84 118.07,42.35 118.18,42.24 118.76,42.24 119.85,41.15 120.24,41.15 120.52,40.87 120.52,39.78 120.26,39.52 v1(120.26,38.86)
CPSW_RGMII2_RD1: length 86.1
  TOP w0.147: v1(120.04,40.38) 120.28,40.38 120.44,40.23 J19.25 ; U136.V15 v1(81.7,88.05)
  L03_SIG1 w0.091: v1(81.7,88.05) 82.02,88.05 82.94,88.97 83.87,88.97 84.12,88.72 86.76,88.72 91.51,83.97 91.51,78.36 92.32,77.55 92.32,66.45 93.13,65.63 93.13,58.98 93.69,58.42 93.69,57.76 94.53,56.92 94.53,56.06 96.36,54.23 97.17,54.23 97.66,53.75 98.04,53.75 98.29,53.49 98.29,53.14 98.04,52.88 98.04,52.55 105.48,45.11 109.57,45.11 115,39.67 115.3,39.67 115.41,39.78 115.41,39.9 115.51,40.01 115.67,40.01 115.77,39.9 115.77,39.78 115.88,39.67 116.26,39.67 116.42,39.83 116.42,40.76 116.53,40.87 116.68,40.87 116.79,40.76 116.79,39.83 116.89,39.73 117.05,39.73 117.15,39.83 117.15,40.76 117.26,40.87 117.41,40.87 117.52,40.76 117.52,39.83 117.63,39.73 117.78,39.73 117.88,39.83 117.88,40.76 117.99,40.87 118.14,40.87 118.25,40.76 118.25,39.83 118.36,39.73 118.51,39.73 118.62,39.83 118.62,40.76 118.72,40.87 118.87,40.87 118.98,40.76 118.98,39.43 119.19,39.22 119.45,39.22 120.04,39.81 v1(120.04,40.38)
CPSW_RGMII2_RD2: length 86.1
  TOP w0.147: v1(82.87,87.36) 82.57,87.65 U136.W14 ; J19.27 120.84,38.21 121.15,37.9 121.15,37.19 120.11,36.14 117.75,36.14 117.16,36.73 v1(117.16,37.44)
  L03_SIG1 w0.091: v1(117.16,37.44) 117.67,36.93 117.67,35.43 116.78,34.54 113.94,34.54 112.95,35.53 112.95,40.52 109.22,44.25 104.87,44.25 92.73,56.39 92.73,58.06 92.3,58.5 92.3,64.95 91.41,65.84 91.41,75.03 90.67,75.77 90.67,83.59 86.53,87.73 83.24,87.73 v1(82.87,87.36)
CPSW_RGMII2_RD3: length 86.1
  TOP w0.147: J19.29 121.24,40.06 121.55,40.38 v1(121.55,40.38) ; U136.T15 v1(80.1,88.85)
  L03_SIG1 w0.091: v1(121.55,40.38) 121.2,40.38 121,40.59 121,41.26 118.75,43.51 118.18,43.51 118.07,43.62 118.07,43.89 117.97,43.99 117.82,43.99 117.71,43.89 117.71,43.62 117.6,43.51 117.45,43.51 117.34,43.62 117.34,43.89 117.24,43.99 117.08,43.99 116.98,43.89 116.98,43.62 116.87,43.51 116.72,43.51 116.61,43.62 116.61,43.89 116.5,43.99 116.35,43.99 116.25,43.89 116.25,43.62 116.14,43.51 115.6,43.51 115.49,43.4 115.49,42.98 115.39,42.88 115.24,42.88 115.13,42.98 115.13,43.4 115.02,43.51 114.87,43.51 114.76,43.4 114.76,42.98 114.66,42.88 114.5,42.88 114.4,42.98 114.4,43.4 114.29,43.51 114.14,43.51 114.03,43.4 114.03,42.98 113.92,42.88 113.77,42.88 113.66,42.98 113.66,43.4 113.56,43.51 113.41,43.51 113.3,43.4 113.3,42.98 113.19,42.88 113.04,42.88 112.93,42.98 112.93,43.4 112.83,43.51 112.31,43.51 109.85,45.97 106.01,45.97 99.48,52.5 99.48,53.44 95.83,57.1 95.83,60.33 94.25,61.9 94.25,66.6 93.08,67.77 93.08,78.16 92.48,78.76 92.48,79.91 92.59,80.01 92.8,80.01 92.91,80.12 92.91,80.27 92.8,80.38 92.59,80.38 92.48,80.49 92.48,80.64 92.59,80.74 92.84,80.74 92.93,80.84 92.93,80.98 92.8,81.11 92.59,81.11 92.48,81.22 92.48,82.07 92.68,82.27 92.68,83.74 87.14,89.28 85.08,89.28 84.6,89.76 82.62,89.76 82.11,89.26 80.5,89.26 v1(80.1,88.85)
CPSW_RGMII2_RSTN: length 14.3
  TOP w0.147: J19.12 v1(117.64,41.66)
  BOTTOM w0.147: v1(117.64,41.66) 118.1,42.12 118.1,45.42 116.1,47.42 115.35,47.42 115.08,47.15 115.08,46.78 115.26,46.6 R5825.2 114.76,45.9 114.1,45.24 113.03,45.24 112.87,45.4 R607.1 112.87,47.04 U120.4
CPSW_RGMII2_RX_DV: length 86.1
  TOP w0.147: J19.45 124.44,36.41 122.55,34.52 116.65,34.52 114.93,36.25 v1(114.93,36.8) ; U136.V14 v1(81.7,87.25)
  L03_SIG1 w0.091: v1(114.93,36.8) 113.23,38.51 113.23,40.63 109.33,44.53 104.98,44.53 93.01,56.5 93.01,58.19 92.58,58.62 92.58,65.38 91.71,66.24 91.71,75.16 90.95,75.92 90.95,83.72 86.66,88.01 82.45,88.01 v1(81.7,87.25)
CPSW_RGMII2_RXC: length 86.1
  TOP w0.132: U136.W15 82.99,88.45 v1(83.13,88.6)
  TOP w0.147: J19.19 119.24,38.47 v1(118.85,38.09)
  L03_SIG1 w0.091: v1(83.13,88.6) 83.36,88.37 86.71,88.37 91.23,83.85 91.23,76.05 91.99,75.29 91.99,66.37 92.85,65.51 92.85,58.75 93.29,58.32 93.29,57.58 94.25,56.62 94.25,55.78 96.08,53.95 97.04,53.95 97.43,53.56 97.43,52.52 105.12,44.83 109.41,44.83 114.93,39.32 114.93,37.85 115.35,37.42 115.35,36.49 115.08,36.22 114.7,36.22 114.44,35.97 114.44,35.46 114.67,35.23 115.51,35.23 115.94,35.66 115.94,37.82 116.34,38.22 116.34,39.16 116.45,39.27 116.6,39.27 116.71,39.16 116.71,38.19 116.82,38.09 116.97,38.09 117.07,38.19 117.07,39.16 117.18,39.27 117.33,39.27 117.44,39.16 117.44,38.19 117.55,38.09 v1(118.85,38.09)
CPSW_RGMII2_TD0: length 96.8
  TOP w0.147: v1(122.86,41.25) 122.61,41 120.01,41 119.84,40.83 117.31,40.83 116.84,40.35 J19.7
  L03_SIG1 w0.091: v1(122.86,41.25) 123.36,41.75 123.36,42.06 119.04,46.38 114.71,46.38 113.39,47.69 113.12,47.69 113.01,47.8 113.01,48.02 112.91,48.13 112.75,48.13 112.65,48.02 112.65,47.8 112.54,47.69 112.39,47.69 112.28,47.8 112.28,48.02 112.17,48.13 112.02,48.13 111.92,48.02 111.92,47.8 111.81,47.69 111.66,47.69 111.55,47.8 111.55,48.02 111.44,48.13 111.29,48.13 111.18,48.02 111.18,47.8 111.08,47.69 110.85,47.69 110.56,47.4 109.84,47.4 109.73,47.51 109.73,48.02 109.62,48.13 109.47,48.13 109.37,48.02 109.37,47.51 109.26,47.4 109.11,47.4 109,47.51 109,48.02 108.89,48.13 108.74,48.13 108.63,48.02 108.63,47.51 108.53,47.4 108.38,47.4 108.27,47.51 108.27,48.02 108.16,48.13 108.01,48.13 107.9,48.02 107.9,47.51 107.79,47.4 107.65,47.4 107.56,47.49 107.56,48.02 107.45,48.13 107.3,48.13 107.2,48.02 107.2,47.53 107.06,47.4 106.74,47.4 96.72,57.43 96.72,60.66 95.12,62.26 95.12,62.83 95.22,62.94 95.97,62.94 96.08,63.05 96.08,63.2 95.97,63.3 95.22,63.3 95.12,63.41 95.12,63.56 95.22,63.67 95.97,63.67 96.08,63.78 96.08,63.93 95.97,64.04 95.22,64.04 95.12,64.14 95.12,64.29 95.22,64.4 95.95,64.4 96.08,64.53 96.08,64.68 95.99,64.77 95.22,64.77 95.12,64.87 95.12,65.03 95.22,65.13 95.95,65.13 96.06,65.24 96.06,65.39 95.95,65.5 95.22,65.5 95.12,65.61 95.12,65.76 95.22,65.86 95.92,65.86 96.03,65.97 96.03,66.12 95.92,66.23 95.22,66.23 95.12,66.34 95.12,67.11 93.95,68.28 93.95,82.52 94.35,82.93 94.35,83.97 v1(90.29,88.04)
  BOTTOM w0.147: R509.2 84.21,88.79 84.38,88.62 85.39,88.62 85.97,88.04 v1(90.29,88.04)
CPSW_RGMII2_TD1: length 99.5
  TOP w0.147: v1(121.02,36.35) 121.02,35.92 120.77,35.66 117.54,35.66 116.6,36.6 116.6,37.77 117.11,38.28 117.11,38.53 117.21,38.63 117.21,38.68 117.24,38.71 J19.9 ; R518.2 86.22,88.32 86.66,88.75 v1(86.66,89.71)
  L03_SIG1 w0.091: v1(86.66,89.71) 87.14,89.71 88.64,88.21 88.99,88.21 93.06,84.15 93.06,82.91 93.39,82.58 93.39,67.87 94.53,66.73 94.53,62.03 96.11,60.45 96.11,57.23 99.76,53.57 99.76,52.63 106.14,46.25 110.33,46.25 110.48,46.1 110.64,46.1 110.92,46.38 111.07,46.38 111.17,46.27 111.17,46.12 110.89,45.84 110.89,45.69 111,45.58 111.15,45.58 111.43,45.86 111.59,45.86 111.69,45.75 111.69,45.6 111.41,45.32 111.41,45.17 111.63,44.96 112.15,44.96 112.26,45.07 112.26,45.79 112.36,45.9 112.52,45.9 112.62,45.79 112.62,45.07 112.73,44.96 112.88,44.96 112.99,45.07 112.99,45.79 113.1,45.9 113.25,45.9 113.35,45.79 113.35,45.07 113.46,44.96 114.09,44.96 114.59,45.46 116.03,45.46 116.27,45.21 117.15,45.21 117.26,45.32 117.26,45.56 117.37,45.67 117.52,45.67 117.63,45.56 117.63,45.32 117.73,45.21 118.03,45.21 119.38,43.86 119.53,43.86 119.9,44.23 120.05,44.23 120.16,44.12 120.16,43.97 119.79,43.6 119.79,43.45 119.9,43.34 120.05,43.34 120.42,43.71 120.57,43.71 120.68,43.6 120.68,43.45 120.31,43.08 120.31,42.93 120.41,42.82 120.57,42.82 120.93,43.19 121.09,43.19 121.19,43.09 121.19,42.93 120.82,42.57 120.82,42.41 121.33,41.91 121.33,41.4 121.99,40.74 121.99,40.01 121.69,39.71 121.42,39.71 120.69,38.98 120.69,38.45 119.73,37.49 118.87,37.49 118.62,37.24 118.62,36.88 119.14,36.35 v1(121.02,36.35)
CPSW_RGMII2_TD2: length 98.4
  TOP w0.147: J19.11 117.64,38.6 117.57,38.53 117.57,37.69 117.7,37.57 117.7,36.83 117.92,36.6 119.63,36.6 120.29,37.26 v1(120.52,37.26)
  L03_SIG1 w0.091: v1(120.52,37.26) 121.19,37.26 121.38,37.45 121.38,38.89 121.65,39.16 123.58,39.16 124.66,40.24 124.66,40.77 124.13,41.29 124.13,42.23 122.24,44.12 122.24,45.26 119.3,48.21 115.31,48.21 114.85,48.68 107.6,48.68 104.8,51.48 104.65,51.48 104.54,51.36 104.36,51.36 104.25,51.47 104.25,51.6 104.39,51.74 104.39,51.89 104.28,51.99 104.13,51.99 104.02,51.88 103.87,51.88 103.76,51.99 103.76,52.14 103.87,52.25 103.87,52.4 103.77,52.51 103.62,52.51 103.5,52.4 103.35,52.4 103.24,52.5 103.24,52.65 103.36,52.77 103.36,52.92 103.25,53.03 103.1,53.03 102.98,52.91 102.83,52.91 102.72,53.02 102.72,53.17 102.84,53.29 102.84,53.44 102.73,53.55 102.58,53.55 102.47,53.43 102.31,53.43 102.21,53.54 102.21,53.69 102.32,53.8 102.32,53.96 102.22,54.06 102.06,54.06 101.95,53.95 101.8,53.95 101.69,54.05 101.69,54.21 101.81,54.32 101.81,54.47 101.7,54.58 101.55,54.58 101.43,54.47 101.28,54.47 101.17,54.57 101.17,54.72 101.29,54.84 101.29,54.99 101.18,55.1 101.03,55.1 100.91,54.98 100.76,54.98 100.66,55.09 100.66,55.24 100.77,55.36 100.77,55.51 100.66,55.61 100.51,55.61 100.4,55.5 100.25,55.5 100.14,55.61 100.14,55.76 100.25,55.87 100.25,56.02 100.07,56.21 98.75,56.21 97.33,57.63 97.33,65.89 94.51,68.71 94.51,82.29 95.6,83.38 95.6,86.16 92.12,89.64 v1(88.71,89.64)
  BOTTOM w0.147: v1(88.71,89.64) 87.7,88.62 86.2,88.62 84.87,89.95 83.46,89.95 83.17,89.65 R527.2
CPSW_RGMII2_TD3: length 98.5
  TOP w0.147: J19.13 118.04,37.86 118.15,37.74 118.15,37.34 118.43,37.06 v1(119.04,37.06)
  L03_SIG1 w0.091: v1(119.04,37.06) 119.69,37.06 120.96,38.33 120.96,38.86 121.54,39.44 123.45,39.44 123.74,39.72 123.74,42.09 121.26,44.57 121.26,44.7 121.59,45.03 121.59,45.18 121.48,45.28 121.31,45.28 121,44.98 120.85,44.98 120.74,45.09 120.74,45.24 121,45.49 121,45.64 120.89,45.75 120.74,45.75 120.48,45.5 120.33,45.5 120.23,45.6 120.23,45.75 120.48,46.01 120.48,46.16 120.37,46.27 120.22,46.27 119.97,46.01 119.82,46.01 119.71,46.12 119.71,46.27 119.96,46.53 119.96,46.68 119.86,46.79 119.7,46.79 119.45,46.53 119.3,46.53 119.09,46.74 116.38,46.74 114.71,48.4 106.86,48.4 106.24,49.03 106.09,49.03 105.97,48.91 105.82,48.91 105.72,49.02 105.72,49.17 105.83,49.28 105.83,49.44 105.72,49.54 105.57,49.54 105.46,49.43 105.31,49.43 105.2,49.54 105.2,49.69 105.31,49.8 105.31,49.95 105.2,50.06 105.05,50.06 104.94,49.95 104.79,49.95 104.68,50.06 104.68,50.21 104.79,50.32 104.79,50.47 104.69,50.58 104.53,50.58 104.42,50.47 104.27,50.47 104.16,50.57 104.16,50.72 104.28,50.84 104.28,50.99 104.17,51.09 104.02,51.09 103.9,50.98 103.75,50.98 103.65,51.09 103.65,51.24 103.76,51.35 103.76,51.5 103.65,51.61 103.5,51.61 103.39,51.5 103.24,51.5 103.13,51.61 103.13,51.76 103.24,51.87 103.24,52.02 103.13,52.13 102.98,52.13 102.87,52.02 102.72,52.02 102.61,52.12 102.61,52.28 102.72,52.39 102.72,52.54 102.62,52.65 102.46,52.65 102.35,52.53 102.2,52.53 102.09,52.64 102.09,52.79 102.21,52.91 102.21,53.06 102.1,53.16 101.95,53.16 101.84,53.05 101.68,53.05 101.58,53.16 101.58,53.31 101.69,53.42 101.69,53.57 101.58,53.68 101.43,53.68 101.32,53.57 101.17,53.57 101.06,53.68 101.06,53.83 101.17,53.94 101.17,54.09 101.06,54.2 100.91,54.2 100.8,54.09 100.65,54.09 100.54,54.19 100.54,54.35 100.65,54.46 100.65,54.61 100.55,54.72 100.4,54.72 100.28,54.6 100.13,54.6 100.03,54.71 100.03,54.86 100.14,54.97 100.14,55.13 100.03,55.23 99.88,55.23 99.77,55.12 99.62,55.12 99.51,55.23 99.51,55.38 99.62,55.49 99.62,55.64 99.33,55.93 98.62,55.93 97.04,57.51 97.04,65.77 94.23,68.58 94.23,82.4 94.79,82.96 94.79,84.23 92.14,86.87 92.14,87.73 91.1,88.77 88.9,88.77 87.93,89.74 v1(87.93,90.07)
  BOTTOM w0.147: R528.2 85.04,90.46 86.33,89.18 86.81,89.18 87.7,90.07 v1(87.93,90.07)
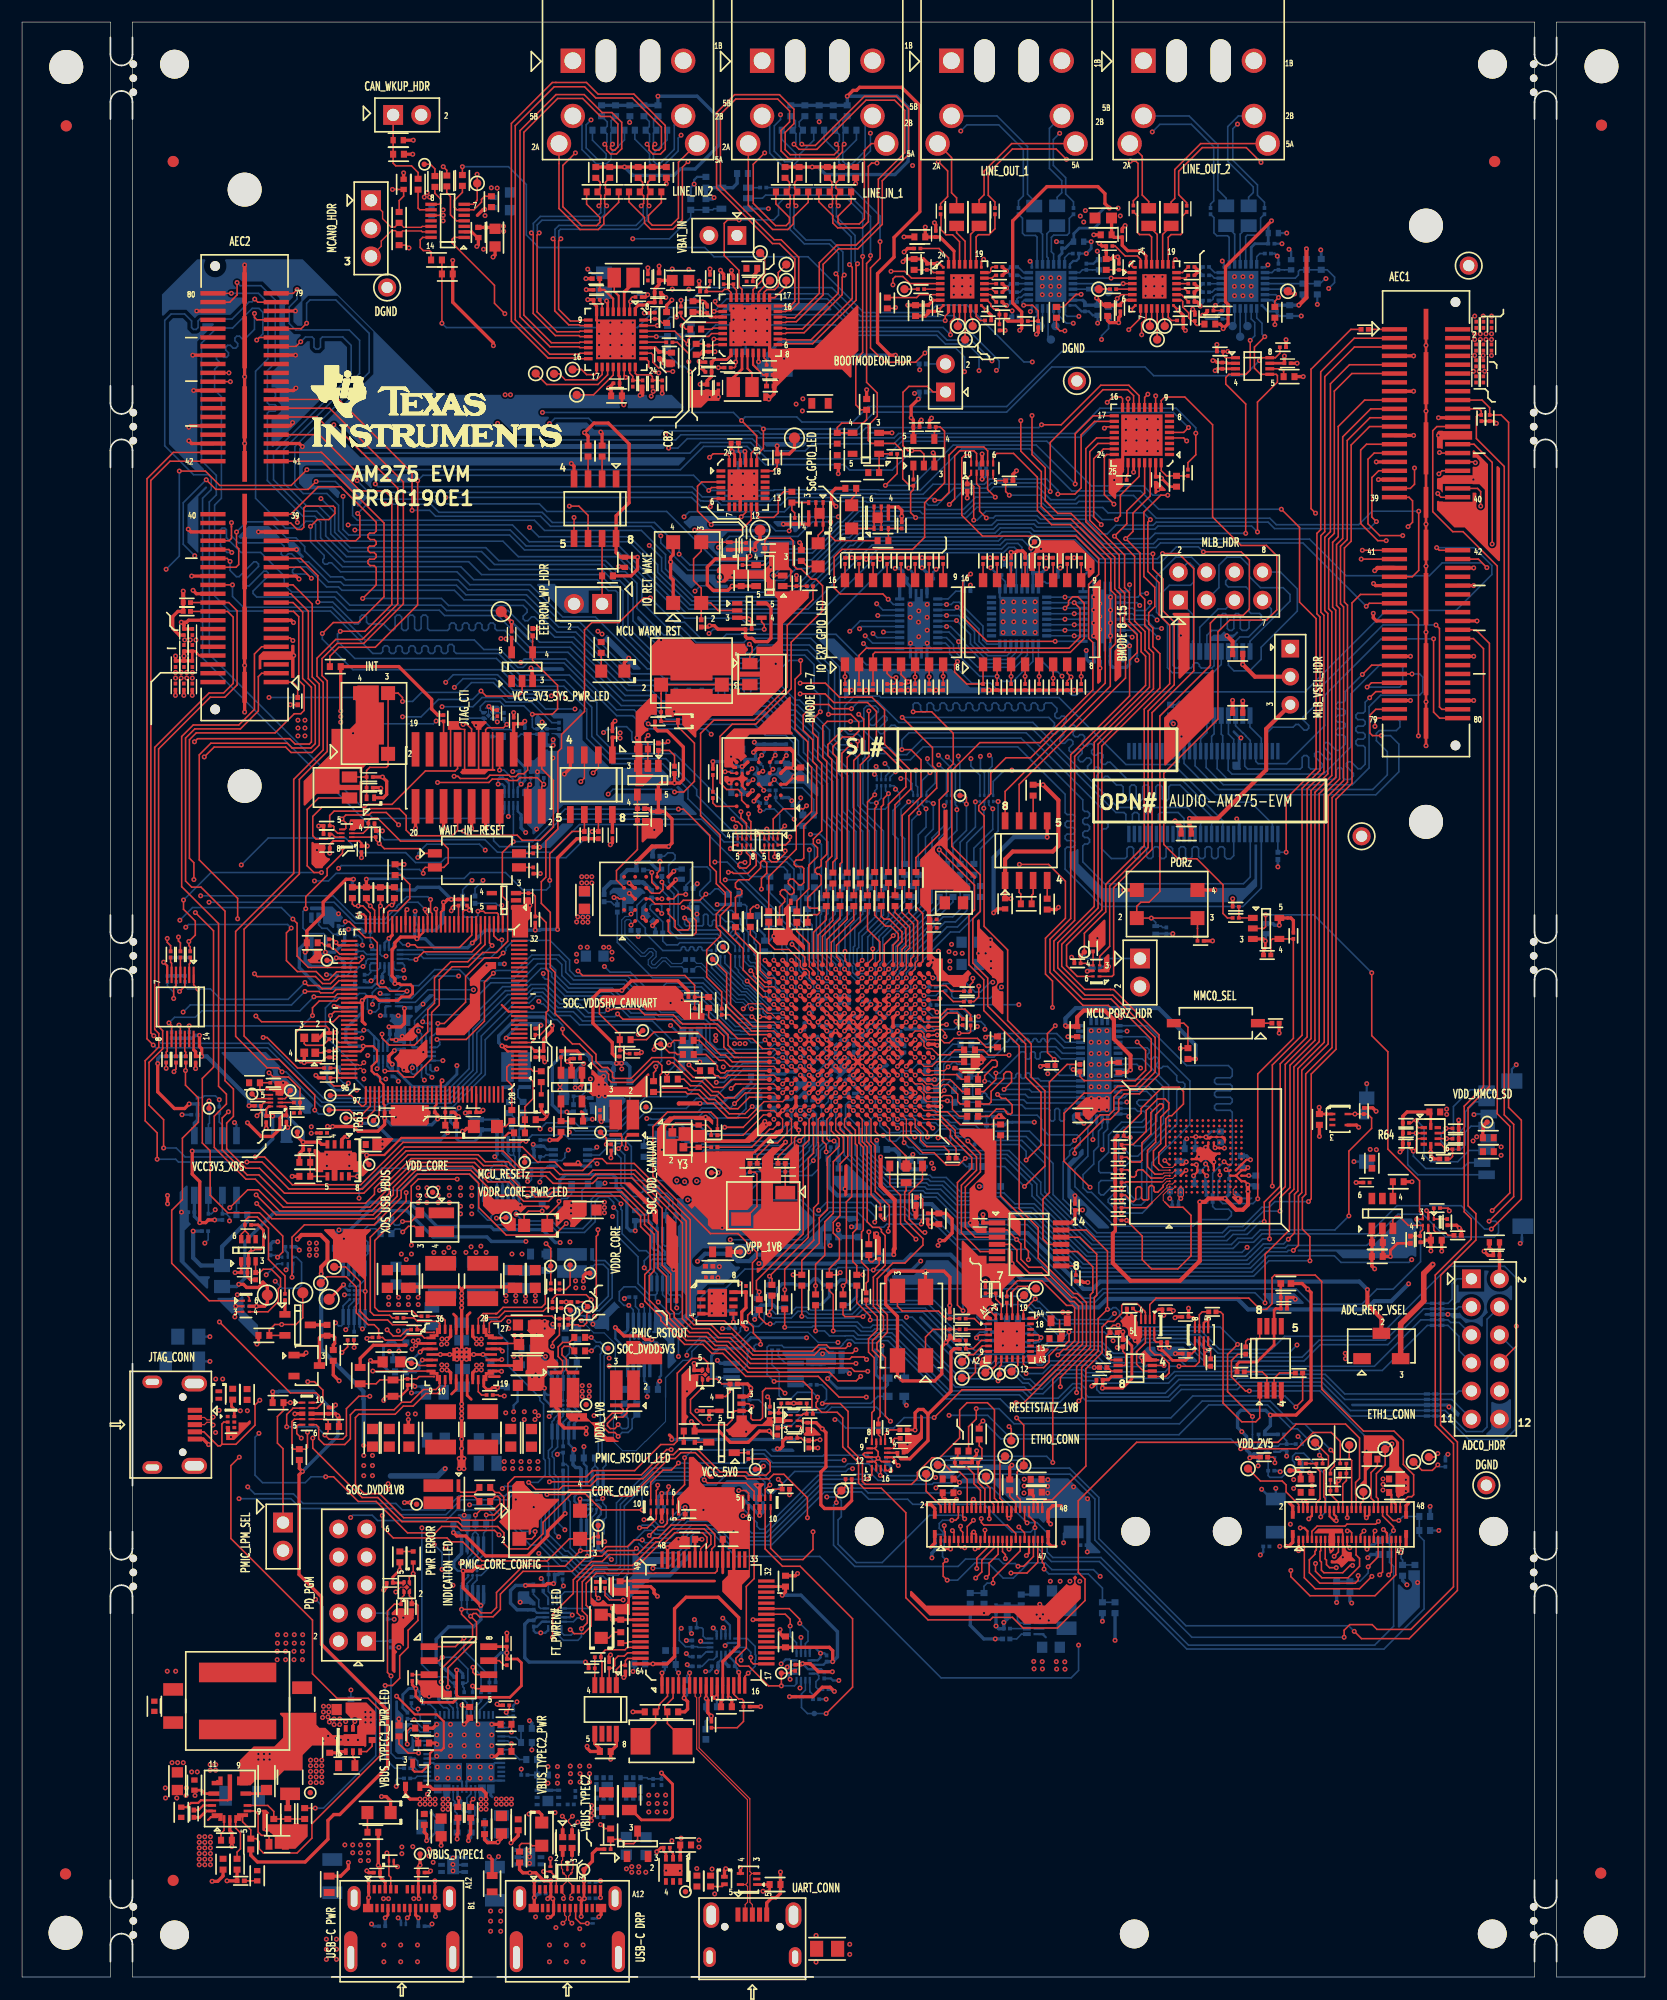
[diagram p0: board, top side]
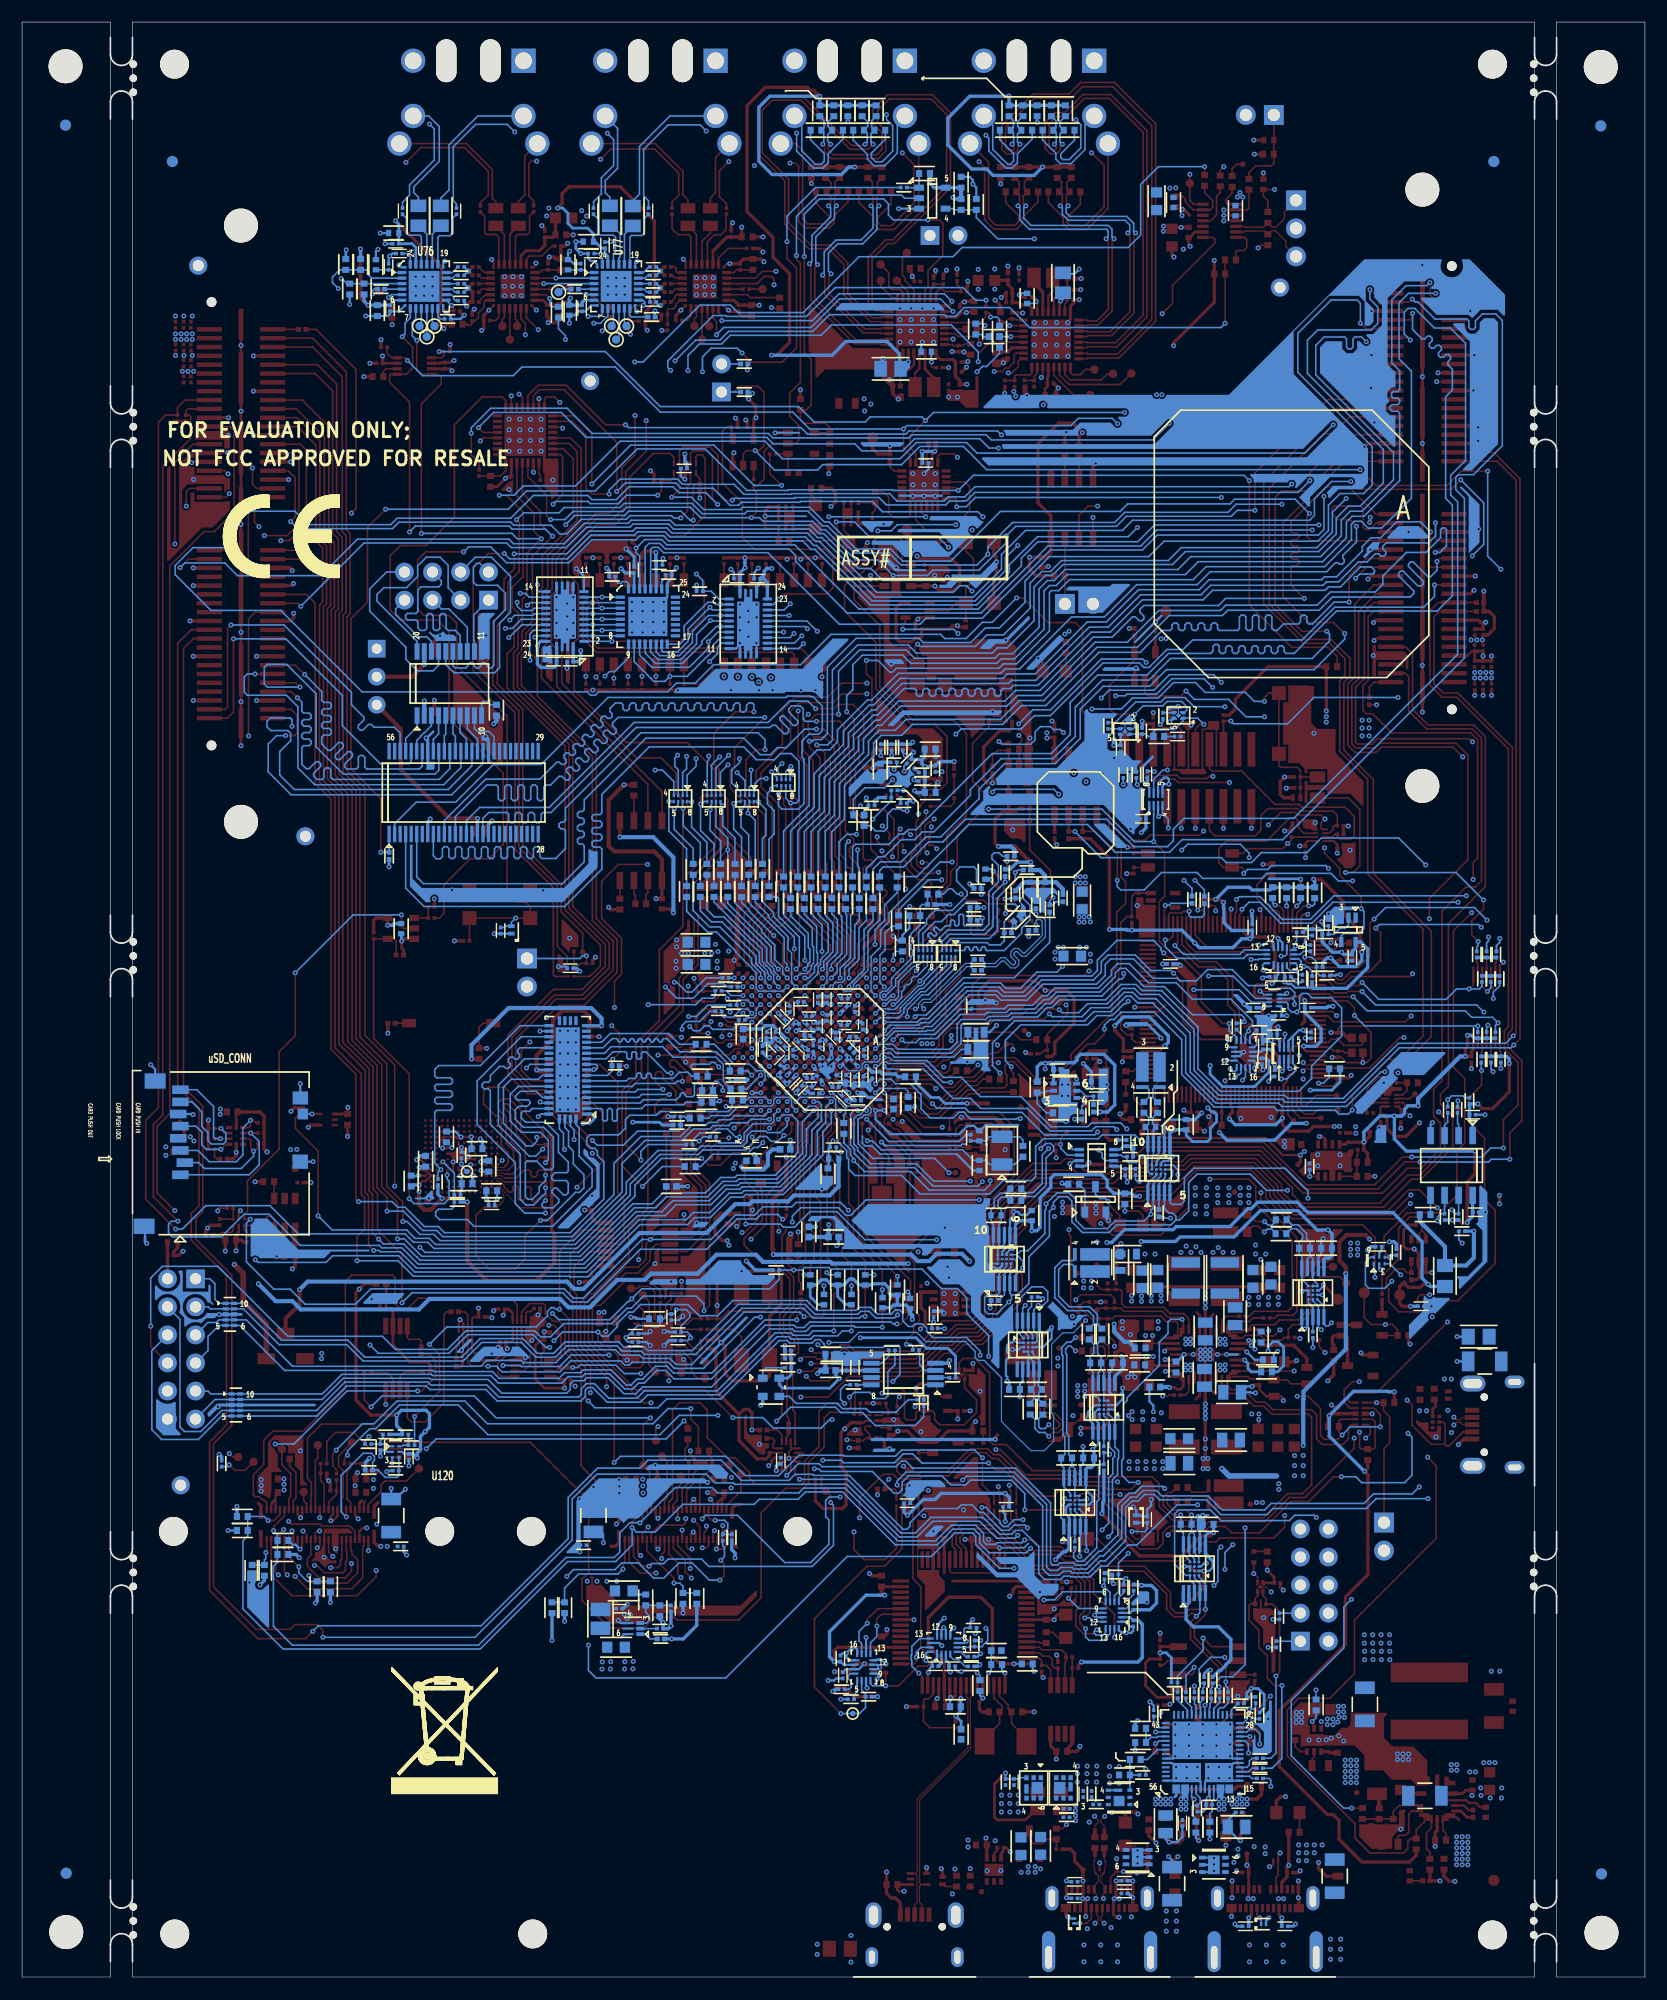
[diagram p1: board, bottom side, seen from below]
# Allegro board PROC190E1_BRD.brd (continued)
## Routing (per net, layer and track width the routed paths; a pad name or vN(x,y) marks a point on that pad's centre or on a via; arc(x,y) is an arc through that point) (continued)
CPSW_RGMII2_TX_EN: length 99.5
  TOP w0.147: v1(122.55,40.39) 122.44,40.27 J19.35 ; U136.U16 v1(80.9,89.65)
  L03_SIG1 w0.091: v1(122.55,40.39) 122.55,40.74 122.27,41.02 122.27,42.55 118.71,46.1 118.54,46.1 118.45,46.01 118.45,45.57 118.34,45.47 118.19,45.47 118.08,45.57 118.08,45.94 117.92,46.1 116.13,46.1 116.02,45.99 116.02,45.84 115.91,45.73 115.76,45.73 115.66,45.84 115.66,45.99 115.55,46.1 115.4,46.1 115.29,45.99 115.29,45.84 115.18,45.73 115.03,45.73 114.92,45.84 114.92,45.99 114.82,46.1 114.6,46.1 113.28,47.42 113.01,47.42 112.92,47.33 112.92,46.61 112.81,46.5 112.66,46.5 112.55,46.61 112.55,47.29 112.42,47.42 112.27,47.42 112.16,47.31 112.16,46.81 112.05,46.71 111.9,46.71 111.79,46.81 111.79,47.31 111.69,47.42 110.96,47.42 110.64,47.09 110.08,47.09 109.98,46.98 109.98,46.63 109.87,46.53 109.72,46.53 109.61,46.63 109.61,46.98 109.5,47.09 109.35,47.09 109.24,46.98 109.24,46.63 109.14,46.53 108.99,46.53 108.88,46.63 108.88,46.98 108.77,47.09 108.62,47.09 108.51,46.98 108.51,46.63 108.41,46.53 108.25,46.53 108.15,46.63 108.15,46.98 108.04,47.09 107.89,47.09 107.78,46.98 107.78,46.63 107.67,46.53 107.52,46.53 107.42,46.63 107.42,46.98 107.31,47.09 106.65,47.09 106.57,47.17 106.41,47.17 106.09,46.85 105.95,46.85 105.8,47 105.8,47.1 106.15,47.46 106.15,47.58 106.05,47.69 105.87,47.69 105.57,47.39 105.42,47.39 105.31,47.5 105.31,47.65 105.64,47.97 105.64,48.1 105.53,48.21 105.38,48.21 105.1,47.93 104.95,47.93 104.84,48.04 104.84,48.19 105.12,48.47 105.12,48.62 105.01,48.72 104.86,48.72 104.59,48.45 104.43,48.45 104.33,48.56 104.33,48.71 104.6,48.98 104.6,49.13 104.5,49.24 104.35,49.24 104.07,48.97 103.92,48.97 103.81,49.07 103.81,49.22 104.09,49.5 104.09,49.65 103.98,49.76 103.83,49.76 103.55,49.48 103.4,49.48 103.29,49.59 103.29,49.74 103.57,50.02 103.57,50.17 103.46,50.28 103.31,50.28 103.03,50 102.88,50 102.78,50.11 102.78,50.26 103.05,50.54 103.05,50.69 102.94,50.79 102.79,50.79 102.52,50.52 102.37,50.52 102.26,50.62 102.26,50.78 102.53,51.05 102.53,51.2 102.43,51.31 102.28,51.31 102,51.03 101.85,51.03 101.74,51.14 101.74,51.29 102.02,51.57 102.02,51.72 101.91,51.83 101.76,51.83 101.48,51.55 101.33,51.55 101.22,51.66 101.22,51.81 101.5,52.09 101.5,52.24 101.39,52.35 101.24,52.35 100.97,52.07 100.81,52.07 100.71,52.18 100.71,52.33 100.98,52.6 100.98,52.76 100.88,52.86 100.72,52.86 100.45,52.59 100.3,52.59 100.19,52.69 100.19,52.85 100.47,53.12 100.47,53.27 96.39,57.35 96.39,60.58 94.84,62.13 94.84,66.83 93.67,68 93.67,82.65 93.92,82.91 93.92,83.26 93.34,83.85 93.34,84.35 89.2,88.49 88.77,88.49 87.09,90.17 86.48,90.17 86.3,89.99 81.91,89.99 81.83,90.07 81.31,90.07 v1(80.9,89.65)
CPSW_RGMII2_TXC: length 95.9
  TOP w0.147: v1(86.12,90.42) 86.12,90.07 85.88,89.83 R228.2 ; J19.3 116.04,39.1 116.15,38.99 116.15,36.14 117.14,35.15 121.15,35.15 v1(122.27,36.27)
  L03_SIG1 w0.091: v1(122.27,36.27) 122.27,36.7 122.62,37.06 122.62,37.72 125.14,40.23 125.14,41.62 123.89,42.86 123.89,45.31 122.98,46.23 121.99,46.23 119.7,48.51 115.4,48.51 113.92,49.99 106.9,49.99 100.4,56.49 98.87,56.49 97.61,57.75 97.61,66.01 94.79,68.83 94.79,79.93 95.88,81.03 95.88,86.31 91.36,90.83 86.53,90.83 v1(86.12,90.42)
CPSW_RGMII2_TXC_R: length 3.6
  TOP w0.147: R228.1 84.2,89.25 83.68,89.77 82.38,89.77 U136.W17
CPSW_RGMII_INTN: length 52.9
  TOP w0.147: v1(117.52,47.24) 117.8,46.96 R346.1 ; J18.10 84.81,41.59 84.57,41.35 v1(84.22,41.35)
  L03_SIG1 w0.091: v1(83.96,50.85) 84.52,50.29 84.52,49.23 84.22,48.92 v1(84.22,41.35)
  BOTTOM w0.147: v1(84.22,41.35) 83.37,41.35 83.08,41.06 83.08,40.62 83.53,40.17 R621.2 82.73,40.07 R620.1 ; v1(117.52,47.24) 117.52,47.64 115.52,49.63 114.98,49.63 112.82,51.79 107.49,51.79 104.79,49.1 89.22,49.1 87.47,50.85 v1(83.96,50.85)
CPSW_RGMII_INTN_R: length 5.4
  TOP w0.147: R344.2 116.73,46.49 116.74,46.48 R346.2 117.24,46.1 117.57,45.77 117.57,43.28 117.42,43.13 117.42,43.13 117.24,42.95 J19.10
CPSW_RGMII_TXC_R: length 4.6
  TOP w0.132: 83.05,86.46 81.69,86.46
  TOP w0.147: 81.69,86.46 U136.V13 ; R239.1 85.21,86.75 84.69,87.27 83.86,87.27 83.05,86.46
DEBOUNCE_GPIO_INT_MCU_SOC: length 78.7
  TOP w0.147: D11.2 R559.2 31.21,108.05 C489.2 ; Q7.2 C489.2 ; C489.2 31.21,109.24 31.49,109.52 33.01,109.52 33.15,109.67 SW5.2 SW5.3 34.06,116.25 34.46,115.85 v1(34.46,115.49)
  L03_SIG1 w0.091: v1(52.09,73.63) 51.66,73.63 51.22,74.07 51.22,74.42 51.02,74.63 51.02,77.24 51.2,77.42 51.2,80.49 50.89,80.8 50.89,81.74 51.45,82.3 51.45,85.19 53.48,87.22 53.48,87.76 51.3,89.94 51.3,90.75 50.51,91.54 50.05,91.54 49.5,92.09 49.5,95.02 48.86,95.66 48.86,107.54 50.08,108.76 v1(50.08,114.81)
  BOTTOM w0.147: U98.3 51.7,73.92 51.99,73.63 v1(52.09,73.63) ; v1(50.08,114.81) 47.41,114.81 46.42,115.8 44.09,115.8 42.69,117.2 40.71,117.2 39.82,116.31 36.19,116.31 35.37,115.49 v1(34.46,115.49)
DEBOUNCE_IORET_WAKE: length 15.2
  TOP w0.147: R5756.2 SW10.2 ; SW10.2 62.38,124.41 63.06,123.72 U3070.2 ; SW10.2 61.52,125.75 60.83,126.44 60.83,128.41 61.52,129.1 SW10.3 D18.2 65.08,129.91 65.14,129.85 C3741.2
DEBOUNCE_MCU_RESETZ: length 65.3
  TOP w0.147: Q12.2 SW6.3 SW6.2 57.88,116.2 C609.2 57.88,114.2 R615.2 D12.2 59.41,113.21 60.9,111.72 60.9,108.25 59.94,107.29 v1(59.1,107.29)
  L03_SIG1 w0.091: v1(52.06,75.13) 53.56,76.63 53.56,81.71 52.52,82.75 52.52,84.35 54.93,86.77 54.93,87.63 53.54,89.03 53.54,91.21 53.92,91.59 53.92,93.5 52.52,94.89 52.52,99.97 50.84,101.65 50.84,104.85 v1(53.09,107.1)
  BOTTOM w0.147: v1(59.1,107.29) 58.85,107.54 53.53,107.54 v1(53.09,107.1) ; v1(52.06,75.13) 51.94,75.01 51.91,75.01 51.82,74.92 U98.1
DEBOUNCE_SOC_PORZ: length 185.5
  TOP w0.147: R375.2 106.47,94.94 106.47,94.94 SW8.3 v1(102.29,95.88) SW8.2 100.97,96.94 101.34,97.31 102.07,97.31 103.07,98.3 103.07,114.17 107.64,118.75 107.64,122.58 108.35,123.29 110.61,123.29 111.17,123.85 111.17,128.3 110.43,129.03 v1(107,129.03)
  L03_SIG1 w0.091: v1(45.97,131.24) 45.97,119.48 46.91,118.54 46.91,116.33 45.08,114.5 45.08,110.85 43.93,109.7 43.93,106.22 46.07,104.09 46.07,103.45 45.46,102.84 45.46,94.03 48.33,91.16 48.33,88.67 46.28,86.62 46.28,80.3 49.07,77.52 49.07,75.29 v1(49.47,74.88)
  BOTTOM w0.147: v1(107,129.03) 106.55,129.49 104.56,129.49 103.12,128.05 97.47,128.05 95.39,130.12 91.41,130.12 91.03,130.5 88.91,130.5 88.44,130.02 76.29,130.02 75.53,129.26 75.2,129.26 70.17,124.23 60.52,124.23 57.57,127.18 57.57,127.86 55.03,130.4 46.8,130.4 v1(45.97,131.24) ; v1(49.47,74.88) 49.17,74.57 49.17,74.19 48.89,73.92 U98.6 ; v1(102.29,95.88) 102.68,95.48 D14.2 103.19,95.15 103.31,95.02 C622.2
DIR: length 20.5
  TOP w0.147: v1(93.58,120.93) 87.42,120.93 85.21,123.14 85.21,126.32 v1(85.92,127.03)
  BOTTOM w0.147: U83.2 83.88,124.77 84.57,125.47 R461.1 85.34,126.45 v1(85.92,127.03) ; U81.2 v1(93.58,120.93)
DRAIN1: length 3.2
  BOTTOM w0.191: v1(37.61,18) 37.4,17.78 U129.15 ; v1(39.54,18) 39.85,17.69 U129.8 ; U129.19 37.25,19.38 v1(37.61,19.01)
  vias: v1(38.58,19.01) v1(38.58,18) v1(39.54,19.01)
DRAIN2: length 3.2
  BOTTOM w0.191: U129.56 42.69,17.78 v1(42.47,18) ; U129.7 40.25,17.71 v1(40.54,18) ; v1(42.47,19.01) 42.84,19.38 U129.52
  vias: v1(40.54,19.01) v1(41.5,19.01) v1(41.5,18)
ECAP0_IN_APWM_OUT: length 174.5
  TOP w0.147: v1(56.18,42.29) 52.47,42.29 51.02,43.74 49.75,43.74 47.19,41.17 47.19,40.13 45.81,38.76 44.14,38.76 43.65,39.25 43.65,40.22 43.08,40.79 39.91,40.79 39.48,41.22 34.41,41.22 32.22,43.41 30.8,43.41 26.33,47.88 v1(26.33,48.79) ; v1(24.53,121.01) 24.29,121.24 J13.11 ; v1(81.78,67.41) 81.55,67.41 80.36,68.61 80.36,70.97 81.56,72.17 R5685.1
  L03_SIG1 w0.091: v1(26.33,48.79) 25.75,48.21 24.76,48.21 23.36,49.61 23.36,54.66 24.27,55.58 24.27,62.43 23.28,63.42 23.28,64.08 22.11,65.26 22.11,67.63 22.85,68.38 22.85,76.89 22.27,77.47 22.27,81 21.94,81.33 21.94,83.6 22.6,84.25 22.6,91.01 21.25,92.35 21.25,103.94 23.46,106.15 23.46,119.94 v1(24.53,121.01) ; v1(81.78,67.41) 82.19,67.01 82.19,65.01 80.56,63.38 80.56,57.19 75.46,52.09 75.46,46.25 v1(75.23,46.02)
  BOTTOM w0.147: v1(75.23,46.02) 74.87,46.02 74.62,45.77 69.99,45.77 68,43.79 67.61,43.79 67.28,44.12 67.28,44.8 66.72,45.36 63.67,45.36 62.86,44.55 61.53,44.55 61.11,44.98 57.39,44.98 56.18,43.77 v1(56.18,42.29)
ECAP1_IN_APWM_OUT: length 132.8
  TOP w0.147: U136.P2 v1(78.5,77.65) ; v1(113,66.83) 113,70.13 114.42,71.55 114.42,82.63 116.76,84.96 116.76,107.42 118.28,108.94 118.28,123.44 118,123.72 118,130.35 118.51,130.86 118.51,144.25 120.24,145.98 J12.9
  BOTTOM w0.132: v1(78.5,77.65) 78.1,78.05 77.28,78.05
  BOTTOM w0.147: v1(113,66.83) 112.37,66.83 110.8,65.25 96.44,65.25 91.69,70 89.93,70 88.94,70.99 85.11,70.99 83.71,72.39 82.44,72.39 82.24,72.59 78.78,72.59 76.73,74.64 76.73,77.5 77.28,78.05
ECAP2_IN_APWM_OUT: length 125.2
  TOP w0.147: J12.11 120.46,145.18 118.86,143.59 118.86,130.71 118.36,130.2 118.36,123.88 118.64,123.6 118.64,108.79 117.11,107.26 117.11,84.81 114.85,82.55 114.85,71.48 113.94,70.56 v1(113.94,69.34) ; U136.R3 v1(79.3,78.46)
  BOTTOM w0.147: v1(79.3,78.46) 79.77,77.98 82.47,77.98 82.82,77.62 83.84,77.62 84.09,77.37 84.81,77.37 85.04,77.14 86.33,77.14 87.37,76.1 90.95,76.1 93.39,73.66 93.39,70.84 97.2,67.03 108.88,67.03 109.44,67.59 110.71,67.59 112.46,69.34 v1(113.94,69.34)
ECAP3_IN_APWM_OUT: length 156.9
  TOP w0.147: U136.P4 v1(78.5,79.26) ; v1(75.53,55.55) 65.96,55.55 63.97,57.53 62.93,57.53 62.12,58.34 60.47,58.34 59.07,59.74 59.07,60.15 58.77,60.45 58.77,63.65 57.98,64.44 57.98,69.6 55.24,72.34 52.16,72.34 51.68,71.86 48.1,71.86 47.44,72.52 44.75,72.52 43.81,73.46 41.8,73.46 41.16,74.09 35.24,74.09 32.91,71.76 32.91,71.11 31.5,69.71 23.66,69.71 21.13,72.24 20.28,72.24 17.41,75.11 17.41,77.94 18.51,79.04 18.51,79.93 17.8,80.64 17.8,95.38 14.46,98.72 14.46,112.31 15.5,113.36 19.63,113.36 21.05,114.78 21.05,119.79 21.7,120.44 J13.9
  L03_SIG1 w0.091: v1(75.53,55.55) 78.28,58.29 78.28,65.76 78.91,66.4 78.91,72.03 79.42,72.54 79.42,74.45 79.31,74.56 79.31,75.81 79.67,76.18 79.67,78.61 79.43,78.85 78.9,78.85 v1(78.5,79.26)
EEPROM_A1: length 2
  TOP w0.147: U2358.2 R5745.2
EEPROM_A2: length 2
  TOP w0.147: U2358.3 R5744.1
EEPROM_WP: length 5.9
  TOP w0.147: U2358.7 R5746.1 J33.1
EMMC_CLK: length 30.2
  TOP w0.147: U49.M6 109.21,73.55 108.94,73.81 v1(108.88,73.81)
  BOTTOM w0.147: v1(108.88,73.81) 107.85,72.78 R561.1 R565.2 107.85,69.77 108.09,69.52 109.29,69.52 109.54,69.27 109.54,68.93 109.18,68.58 106.67,68.58 106.06,67.97 98.95,67.97 95.37,71.55 95.37,73.15 96.54,74.32 96.54,76.89 96.83,77.18 U57.42
EMMC_CMD: length 31.1
  TOP w0.147: U49.M5 109.38,72.97 109.17,72.97 109.06,73.08 v1(109.06,73.1)
  BOTTOM w0.147: R575.2 109.33,72.83 v1(109.06,73.1) 109.47,73.51 109.47,73.56 109.62,73.71 109.62,78.3 109.45,78.47 108.19,78.47 108.02,78.64 108.02,78.89 108.19,79.06 109.45,79.06 109.62,79.23 109.62,79.47 109.45,79.65 108.19,79.65 108.02,79.82 108.02,80.06 108.19,80.24 109.45,80.24 109.62,80.41 109.62,80.65 109.45,80.83 108.19,80.83 108.02,81 108.02,81.24 108.19,81.41 109.45,81.41 109.62,81.59 109.62,82.17 109.26,82.52 105.48,82.52 101.87,86.13 U57.22
EMMC_D0: length 30.2
  TOP w0.091: 103.35,71.7 103.71,72.05 U49.A3
  TOP w0.147: v1(99.58,70.31) R269.2 99.94,70.79 100.52,70.21 100.68,70.21 100.88,70.4 100.88,71.37 101.05,71.55 101.26,71.55 101.41,71.4 101.41,70.51 101.56,70.36 101.96,70.36 102.05,70.45 102.05,71.5 102.21,71.65 102.38,71.65 102.53,71.51 102.53,71.17 102.64,71.07 102.89,71.07 103.35,71.54 103.35,71.7
  BOTTOM w0.147: U57.37 100.8,78.63 101.05,78.38 101.62,78.38 101.77,78.23 101.77,77.76 101.4,77.39 99.59,77.39 98.42,76.23 98.42,74.68 97.53,73.79 97.53,72.97 97.68,72.82 98.72,72.82 99.03,72.52 99.03,72.31 98.83,72.11 97.73,72.11 97.53,71.91 97.53,71.01 97.72,70.81 97.97,70.81 98.58,71.43 98.79,71.43 98.99,71.22 98.99,71.01 98.38,70.4 98.38,70.15 98.89,69.65 99.74,69.65 99.91,69.81 99.91,70.02 99.62,70.31 v1(99.58,70.31)
EMMC_D1: length 30.2
  TOP w0.091: 103.17,72.34 103.32,72.34 103.53,72.55 U49.A4
  TOP w0.147: 103.17,72.34 102.25,72.34 101.51,73.08 101.1,73.08 100.92,72.91 100.92,72.6 100.75,72.43 100.51,72.43 100.33,72.6 100.33,72.91 100.16,73.08 R266.2 v1(99.58,72.59)
  BOTTOM w0.147: v1(99.58,72.59) 99.58,72.11 100.16,71.54 100.16,71.03 100.78,70.41 101.16,70.41 101.41,70.66 101.41,73.73 101.27,73.88 100.4,73.88 99.62,73.1 99.08,73.1 98.87,73.3 98.87,76.05 99.76,76.94 101.59,76.94 102.33,77.67 102.33,78.52 102.03,78.82 101.82,78.82 101.8,78.84 101.24,78.84 100.98,79.1 100.98,79.24 101.16,79.41 102.15,79.41 102.29,79.56 102.29,79.77 101.87,80.19 100.41,80.19 99.86,79.63 U57.35
EMMC_D2: length 30.3
  TOP w0.091: 102.97,73.05 U49.A5
  TOP w0.147: 102.97,73.05 102.48,73.53 102.48,74.8 103.14,75.46 103.14,77.85 103.88,78.59 103.88,79.15 103.52,79.5 102.86,79.5 101.82,78.46 101.82,76.56 100.63,75.37 R263.2 99.58,75.21 v1(99.84,74.96)
  BOTTOM w0.147: v1(99.84,74.96) 100.47,74.32 101.06,74.32 103.85,77.11 103.85,80.75 101.47,83.13 U57.28
EMMC_D3: length 30.6
  TOP w0.091: U49.B2 104.21,71.3 103.85,71.3 103.37,70.82 103.37,70.31 103.52,70.15
  TOP w0.147: R275.2 v1(100.04,68.51) 101.47,67.08 101.47,64.95 102.3,64.11 104.69,64.11 105.88,65.3 105.88,68.96 105.15,69.7 103.98,69.7 103.52,70.15
  BOTTOM w0.147: v1(100.04,68.51) 99.4,68.51 96.87,71.04 96.51,71.04 96.11,71.45 96.11,72.64 97.07,73.61 97.07,74.78 97.5,75.21 97.5,76.58 97.83,76.91 U57.40
EMMC_D4: length 30.3
  TOP w0.091: U49.B3 104.2,71.8 103.84,71.8 103.7,71.65 103.7,71.48 102.38,70.15
  TOP w0.147: v1(99.58,69.16) R270.2 101.88,69.65 102.38,70.15
  BOTTOM w0.147: U57.24 101.78,85.13 105.78,81.13 105.78,77.19 102.33,73.74 102.33,70.03 101.47,69.16 v1(99.58,69.16)
EMMC_D5: length 30.3
  TOP w0.091: 103.17,71.99 103.31,71.99 103.62,72.3 104.2,72.3 U49.B4
  TOP w0.147: v1(99.58,71.45) R267.2 99.94,71.94 99.99,71.99 103.17,71.99
  BOTTOM w0.147: U57.26 101.91,84.13 102.11,83.94 102.11,83.69 101.94,83.53 101.94,83.28 102.11,83.11 102.36,83.11 102.53,83.28 102.77,83.28 102.94,83.11 102.94,82.86 102.77,82.69 102.77,82.45 102.95,82.28 103.19,82.28 103.36,82.44 103.75,82.44 104.59,81.61 104.59,81.18 104.76,81.01 105.15,81.01 105.33,80.84 105.33,80.59 105.15,80.42 104.76,80.42 104.59,80.25 104.59,77.22 101.87,74.5 101.87,70.41 101.36,69.9 100.65,69.9 99.58,70.97 v1(99.58,71.45)
EMMC_D6: length 30.4
  TOP w0.091: U49.B5 104.21,72.8 103.42,72.8 103.32,72.69 103.17,72.69
  TOP w0.147: 103.17,72.69 102.61,72.69 101.95,73.36 101.95,74.85 102.68,75.59 102.68,78.06 103.36,78.74 103.36,78.95 103.26,79.05 103.05,79.05 102.25,78.26 102.25,76.34 101.44,75.52 101.44,73.93 101.29,73.79 100.53,73.79 100.09,74.22 R264.2 v1(99.58,73.74)
  BOTTOM w0.147: v1(99.58,73.74) 99.33,73.99 99.33,75.77 100.04,76.48 101.77,76.48 102.79,77.5 102.79,79.91 102.06,80.63 U57.33
EMMC_D7: length 30.1
  TOP w0.091: 103.35,73.3 104.21,73.3 U49.B6
  TOP w0.147: 103.35,73.3 102.96,73.69 102.96,74.63 103.6,75.26 103.6,77.7 103.88,77.98 104.13,77.98 105.2,79.04 105.2,80.19 104.82,80.57 103.29,80.57 101.36,78.64 101.36,78.21 99.79,76.63 R262.2 99.92,76.02 v1(100.37,76.02)
  BOTTOM w0.147: v1(100.37,76.02) 100.37,75.67 100.79,75.25 101.35,75.25 103.4,77.29 103.4,80.57 102.68,81.28 100.22,81.28 99.87,81.63 U57.31
EMMC_RSTN: length 34.9
  TOP w0.147: U49.K5 108.46,72.97 108.5,72.92 v1(108.5,72.62) ; R5822.1 113.11,93.83 113.27,93.99 U26.4 R117.2 115.16,84.99 111.93,81.76 v1(111.93,70.46)
  BOTTOM w0.147: v1(111.93,70.46) 111.5,70.03 108.76,70.03 108.32,70.46 108.32,72.09 108.5,72.27 v1(108.5,72.62)
EN_VSYS_5V0: length 6.1
  TOP w0.147: R3028.1 R5740.2 R3727.2 22.8,14.99 22.26,15.53 U134.7
EPWM0_A: length 128.8
  TOP w0.132: 82.82,74.42 82.62,74.63 81.58,74.63 80.1,76.11 80.1,77.65
  TOP w0.147: J12.3 120.67,148.38 117.63,145.34 117.63,131.05 117.29,130.71 117.29,123.42 117.57,123.14 117.57,109.25 115.94,107.62 115.94,85.27 113.25,82.58 v1(113.25,71.6) ; 82.82,74.42 82.82,74.42 83.73,73.51 84.83,73.51 v1(85.44,74.12) ; 80.1,77.65 U136.T2
  L03_SIG1 w0.091: v1(113.25,71.6) 113.25,70.21 110.96,67.92 v1(110.96,66.07)
  BOTTOM w0.147: v1(110.96,66.07) 110.51,65.61 96.59,65.61 91.48,70.71 91.48,71.7 89.07,74.12 v1(85.44,74.12)
EPWM0_B: length 127
  TOP w0.147: J12.5 120.68,147.58 118,144.89 118,130.86 117.65,130.51 117.65,123.57 117.92,123.29 117.92,109.09 116.4,107.57 116.4,85.12 113.96,82.68 113.96,71.6 112.51,70.15 v1(112.51,68.4) ; U136.R2 v1(79.3,77.65)
  BOTTOM w0.147: v1(79.3,77.65) 80.99,77.65 81.3,77.34 82.75,77.34 83,77.09 84.4,77.09 84.7,76.78 86.17,76.78 87.22,75.74 90.57,75.74 92.65,73.66 92.65,71.07 97.05,66.67 109.14,66.67 109.69,67.23 110.96,67.23 112.13,68.4 v1(112.51,68.4)
EPWM1_A: length 148.2
  TOP w0.147: v1(75.53,56.79) 75.23,56.49 73.09,56.49 72.71,56.87 72.31,56.87 71.75,56.31 66.21,56.31 64.28,58.24 63.24,58.24 62.43,59.05 60.85,59.05 60.16,59.74 60.16,68.43 55.54,73.05 51.7,73.05 51.33,72.67 48.71,72.67 48.14,73.24 45.11,73.24 43.56,74.8 34.78,74.8 30.95,70.97 23.77,70.97 21.51,73.23 20.28,73.23 18.53,74.97 18.53,77.32 19.14,77.92 19.14,80.39 18.38,81.15 18.38,96.5 16.21,98.68 15.36,98.68 14.81,99.23 14.81,112.17 15.64,113 19.77,113 21.4,114.63 21.4,117.74 21.7,118.04 J13.3 ; U136.R1 v1(79.3,76.85)
  L03_SIG1 w0.091: v1(79.3,76.85) 79.3,76.13 79.04,75.87 79.04,72.57 78.55,72.09 78.55,68.33 77.92,67.69 77.92,67.08 75.53,64.69 v1(75.53,56.79)
EXT_CLKOUT0: length 41.8
  TOP w0.147: R170.1 80.08,71.2 79.95,71.07 79.95,68.5 81.6,66.85 81.6,66.27 79.98,64.64 78.88,64.64 77.46,63.22 77.46,60.88 78.38,59.97 78.38,58.37 77.44,57.43 77.44,56.84 78.2,56.08 78.2,50.77 v1(78.66,50.32)
  BOTTOM w0.147: v1(78.66,50.32) 77.39,51.59 73.32,51.59 72.84,51.1 70.88,51.1 69.71,49.94 66.11,49.94 65.33,50.72 R337.1
EXT_CLKOUT0_R: length 4.6
  TOP w0.132: 79.98,74.42 78.58,75.82 78.58,76.77 U136.P1
  TOP w0.147: R5685.2 80.08,74.32 79.98,74.42
EXT_VMON2_1: length 3.8
  TOP w0.147: J18.2 83.21,42.67 81.89,43.99 TP95.1
EXT_VMON2_2: length 6.8
  TOP w0.147: J19.2 115.64,42.78 114.5,43.92 114.5,44.56 114.15,44.91 112.17,44.91 TP94.1
FT4232_DO: length 2.5
  TOP w0.147: R323.2 R321.1 U61.4
FT4232_EECLK: length 5.3
  TOP w0.147: U61.2 R328.1 53.45,27.96 53.68,28.19 53.68,28.75 53.99,29.06 54.55,29.06 54.84,29.35 U64.62
FT4232_EECS: length 4.3
  TOP w0.147: U64.63 54.85,28.85 54.65,28.64 R333.1 54.22,28.22 53.83,27.83 U61.1
FT4232_EEDATA: length 6.7
  TOP w0.147: U61.3 52.53,28.51 52.44,28.6 R323.1 52.44,29.22 52.84,29.62 54.61,29.62 54.83,29.85 U64.61
FT4232_REF: length 1.9
  TOP w0.147: U64.6 v1(60.47,27.54)
  BOTTOM w0.147: R609.2 60.24,27.31 v1(60.47,27.54)
FT4232_RESET: length 6.9
  TOP w0.147: R357.1 64.77,22.57 65.35,23.14 C282.2 65.35,25.02 65.2,25.17 64.9,25.17 64.47,25.61 U64.14
FT4232_SOC_UART2_RX_3V3: length 6
  TOP w0.147: v1(65.77,27.51) 65.47,27.2 U64.16
  BOTTOM w0.147: U125.13 65.7,30.64 66.4,29.93 66.4,29.19 66.46,29.13 66.46,28.73 66.4,28.67 66.4,28.14 v1(65.77,27.51)
FT4232_SOC_UART2_TX_3V3: length 3.8
  TOP w0.147: v1(66.01,28.93) 66.01,28.58 66.24,28.35 U64.17
  BOTTOM w0.147: U125.15 65.57,29.84 66.01,29.41 v1(66.01,28.93)
FT4232_SOC_UART3_RX_3V3: length 5.7
  TOP w0.147: v1(69.57,31.78) 69.57,32.4 69.12,32.85 U64.26
  BOTTOM w0.147: v1(69.57,31.78) 69.57,30.84 70.15,30.26 U126.13
FT4232_SOC_UART3_TX_3V3: length 7
  TOP w0.147: U64.27 69.49,33.35 70.44,32.39 v1(70.44,32.03)
  BOTTOM w0.147: v1(70.44,32.03) 71.19,31.29 71.19,30.42 70.95,30.18 U126.15
FT4232_UART2_RXD_1V8: length 17.3
  TOP w0.147: v1(58.56,44.4) 58.56,44.05 58.44,43.92 U2351.7
  L03_SIG1 w0.091: v1(58.56,44.4) 58.56,41.53 60.9,39.19 v1(60.9,32.36)
  BOTTOM w0.147: U125.8 61.91,30.64 61.69,30.86 61.69,31.49 61.56,31.62 R612.2 61.1,32.16 v1(60.9,32.36)
FT4232_UART2_TXD_1V8: length 20.2
  TOP w0.147: v1(57.57,44.53) 57.57,44.17 57.44,44.04 U2351.9
  L03_SIG1 w0.091: v1(57.57,44.53) 56.89,43.84 56.89,41.3 59.71,38.48 v1(59.71,31.57)
  BOTTOM w0.147: U125.6 61.23,29.84 61.16,29.91 R611.2 60.09,29.91 59.53,30.47 59.53,31.39 v1(59.71,31.57)
FT4232_UART3_RXD_1V8: length 24
  TOP w0.147: U2352.7 66.31,36.06 65.6,35.36 65.6,29.79 64.66,28.85 64.66,28.47 64.99,28.14 65.83,28.14 67.61,26.36 v1(68.78,26.36) TP97.1 69.46,27.51 69.67,27.72 R361.2
  BOTTOM w0.147: U126.8 70.15,26.55 69.96,26.36 v1(68.78,26.36)
FT4232_UART3_TXD_1V8: length 29
  TOP w0.147: U2352.9 67.31,38.76 68.88,37.19 70.48,37.19 75.23,32.44 75.23,26.24 v1(72.84,23.85)
  BOTTOM w0.147: v1(72.84,23.85) TP117.1 71.14,23.85 70.6,24.4 R631.2 70.6,25.63 70.95,25.98 U126.6
FT4232_USB_DM: length 23.4
  TOP w0.107: J22.2 65.5,6.55 65.71,6.77 65.71,8.2 65.54,8.37 ; 65.54,8.37 U67.5 ; 65.54,8.37 65.7,8.53 65.7,16.05 61.11,20.65 61.11,25.28 60.97,25.42 U64.7
FT4232_USB_DP: length 23.4
  TOP w0.107: U67.3 66.1,9.37 ; 66.1,9.37 66.1,9.36 65.93,9.19 65.93,6.77 66.15,6.55 J22.3 ; 66.1,9.37 65.92,9.55 65.92,16.14 61.33,20.74 61.33,25.28 61.47,25.42 U64.8
FT4232_USB_VBUS: length 8.3
  TOP w0.147: C291.2 63.43,8.2 D3.2
  TOP w0.254: U67.1 C295.1 67.72,7.91 67.57,7.76 v1(67.11,7.76)
  L04_PWR1 w0.254: v1(62.73,7.52) 63.27,8.05 66.82,8.05 v1(67.11,7.76)
FT4232_WKUP_UART0_CTSN_3V3: length 22
  TOP w0.147: v1(50.74,32.51) 50.28,32.97 50.28,35.82 51.73,37.26 55.29,37.26 57.42,39.4 57.78,39.4 58.95,40.57 61.78,40.57 62.39,39.96 62.39,39.18 61.97,38.76 U64.40
  BOTTOM w0.147: U117.12 49.94,32.17 50.29,32.51 v1(50.74,32.51)
FT4232_WKUP_UART0_RTSN_3V3: length 24
  TOP w0.147: v1(50.67,31.54) 51.2,32.07 51.2,32.7 50.74,33.16 50.74,35.78 51.87,36.91 55.44,36.91 57.57,39.04 57.93,39.04 59.11,40.22 61.63,40.22 62.04,39.81 62.04,39.35 61.47,38.77 U64.41
  BOTTOM w0.147: U117.14 48.45,31.07 49.04,30.48 50.34,30.48 50.67,30.8 v1(50.67,31.54)
FT4232_WKUP_UART0_RXD_3V3: length 21.8
  TOP w0.147: v1(49.65,31.45) 50.01,31.08 50.86,31.08 51.55,31.77 51.55,33.21 51.1,33.65 51.1,35.64 52.01,36.55 57.35,36.55 57.37,36.58 62.77,36.58 62.97,36.77 U64.38
  BOTTOM w0.147: U117.13 48.85,31.19 49.09,30.96 49.73,30.96 49.87,31.1 49.87,31.3 49.73,31.45 v1(49.65,31.45)
FT4232_WKUP_UART0_TXD_3V3: length 24.4
  TOP w0.147: v1(48.05,30.75) 48.05,32.84 49.93,34.72 49.93,35.96 51.59,37.62 52.54,37.62 53.18,38.25 55.74,38.25 57.24,39.75 57.62,39.75 58.8,40.92 61.92,40.92 62.74,40.1 62.74,39.03 62.47,38.75 U64.39
  BOTTOM w0.147: U117.15 48.05,30.75 v1(48.05,30.75)
FT_PWREN#: length 1.8
  TOP w0.147: R330.1 54.79,30.23 54.9,30.35 U64.60
GPIO1_23_INTN: length 172.9
  TOP w0.147: U136.C7 v1(68.9,82.46) ; R108.1 105.61,137.11 106.32,137.82 v1(106.32,139.78)
  L03_SIG1 w0.091: v1(43.08,140.67) 42.85,140.44 42.84,140.44 42.13,139.73 42.13,116.15 40.51,114.53 40.51,109.75 42.05,108.2 42.05,105.97 43.6,104.42 43.6,99.29 44.44,98.45 44.44,93.7 45.97,92.18 45.97,89.08 45.23,88.34 45.23,79.07 47.13,77.17 47.41,77.17 v1(47.85,76.73) 47.62,76.5 47.49,76.5 47.34,76.35 46.75,76.35 46.27,76.83 45.26,76.83 44.66,76.24 44.66,74.2 v1(46.9,71.97)
  BOTTOM w0.132: 65.87,82.21 68.65,82.21 v1(68.9,82.46)
  BOTTOM w0.147: v1(106.32,139.78) 106.32,140.27 104.55,142.04 97.63,142.04 95.35,139.75 79.4,139.75 78.99,139.35 66.66,139.35 66.38,139.63 59.66,139.63 59.2,139.17 44.57,139.17 v1(43.08,140.67) ; v1(47.85,76.73) 48.1,76.98 49.76,76.98 50.13,76.61 53.92,76.61 55.95,78.64 60.16,78.64 61.08,79.55 62.68,79.55 65.34,82.21 65.87,82.21 ; v1(46.9,71.97) 46.9,72.2 47.08,72.38 R547.2
GPIO2_BUF_EN: length 2.7
  TOP w0.147: U51.5 21.95,79.87 21.55,80.27 R277.1 22.48,80.97 R278.2
GPIO_CPSW1_RST: length 92
  TOP w0.147: v1(67.53,52.53) 67.74,52.32 R364.1 ; U18.11 66.05,131.92 65.14,131.01 v1(60.93,131.01)
  L03_SIG1 w0.091: v1(67.53,52.53) 67.53,53.95 67.84,54.25 67.84,57.94 66.92,58.85 66.92,59.82 64.15,62.59 63.17,62.59 62.37,63.38 62.37,73.69 59.53,76.53 59.53,81.03 59.94,81.43 59.94,82.8 60.16,83.03 60.16,87.83 60.46,88.13 60.46,93.21 61.56,94.31 61.56,96.8 61.13,97.23 61.13,98.4 60.53,99 60.53,125.65 61.21,126.33 61.21,130.73 v1(60.93,131.01)
GPIO_CPSW2_RST: length 173.4
  TOP w0.147: U18.10 65.55,132.61 v1(65.14,132.21)
  L03_SIG1 w0.091: v1(115.57,48.94) 115.81,49.18 115.81,55.42 121.89,61.49 126.05,61.49 126.59,62.03 126.59,62.94 125.45,64.08 125.45,65.99 127.99,68.53 128.02,68.53 128.11,68.62 128.11,69.29 132.58,73.76 132.58,115.8 134.43,117.65 134.43,135.59 131.26,138.76 106.16,138.76 104.39,136.98 82.24,136.98 77.11,131.85 76.45,131.85 76.09,132.21 v1(73.93,132.21)
  BOTTOM w0.147: v1(115.57,48.94) 115.92,48.59 115.92,48.26 R604.1 ; v1(65.14,132.21) v1(73.93,132.21)
GPIO_EMMC_RSTN: length 64.9
  TOP w0.147: R116.1 109.18,95.89 108.78,96.29 108.78,98.88 106.42,101.24 104.72,101.24 103.42,102.54 103.42,108.99 108.32,113.89 108.32,121.79 109.39,122.86 112.74,122.86 113.66,123.77 113.66,128.68 112.72,129.62 110.41,129.62 107.84,132.18 107.84,140.54 105.33,143.05 103.51,143.05 103.18,142.73 U21.9
GPIO_HYPERRAM_RSTN: length 51.1
  TOP w0.147: R5697.1 58.37,111.71 v1(58.51,111.86) ; U136.C12 v1(68.9,86.45)
  L03_SIG1 w0.091: v1(52.67,112.67) 52.67,107.6 49.7,104.63 49.7,98.6 52.24,96.06 52.24,92 v1(52.75,91.49)
  BOTTOM w0.132: 68.05,86.45 v1(68.9,86.45)
  BOTTOM w0.147: v1(52.67,112.67) 52.95,112.95 53.59,112.95 53.84,113.21 54.75,113.21 55.24,112.73 55.24,112.01 55.64,111.61 58.26,111.61 v1(58.51,111.86) ; 68.05,86.45 65.93,86.45 65.61,86.77 64.91,86.77 61.69,89.99 58.36,89.99 57.88,89.51 56.56,89.51 55.08,90.98 53.26,90.98 v1(52.75,91.49)
GPIO_MCU_SOC: length 2.1
  BOTTOM w0.147: R546.1 R547.1 47.35,73.16 47.6,73.42 U98.5
GPIO_MCU_SOC_INTN: length 34.3
  TOP w0.147: U136.C8 v1(68.9,83.26)
  L03_SIG1 w0.091: v1(46.93,76.78) 46.5,77.22 45.23,77.22 44.39,76.37 44.39,73.44 v1(45.79,72.03)
  BOTTOM w0.132: 65.04,82.98 68.18,82.98 68.45,83.26 v1(68.9,83.26)
  BOTTOM w0.147: 65.04,82.98 63.52,81.46 61.94,81.46 60.19,79.71 56.51,79.71 53.79,76.99 50.46,76.99 50.12,77.33 47.48,77.33 v1(46.93,76.78) ; v1(45.79,72.03) 45.99,72.03 46.14,72.18 R546.2
GPIO_PCM1_RST: length 32.2
  TOP w0.147: R84.1 79.27,136.12 v1(78.2,135.05) ; v1(95.39,135.18) 95.39,139.72 97.02,141.35 U21.17
  BOTTOM w0.147: v1(95.39,135.18) 91.87,138.7 84.34,138.7 81.31,135.67 80.69,135.05 v1(78.2,135.05)
GPIO_PCM2_RST: length 51.4
  TOP w0.147: v1(81.78,147.04) 80.94,146.2 78.15,146.2 76.85,147.5 76.85,154.74 77.72,155.6 v1(77.72,157.12) ; U21.19 98.15,140.35 v1(98.04,140.23)
  L03_SIG1 w0.091: v1(85.37,145.34) 91.42,139.29 97.1,139.29 v1(98.04,140.23)
  BOTTOM w0.147: v1(81.78,147.04) 82.21,147.47 84.57,147.47 85.37,146.68 v1(85.37,145.34) ; R414.1 75.13,162.02 77.72,159.44 v1(77.72,157.12)
HW/SW_CTRL_SEL: length 3.3
  TOP w0.147: R83.2 88.2,61.9 R85.1 88.21,61.37 88.7,60.88 U15.23
HYPERBUS0_CK: length 12.7
  TOP w0.108: U140.B2 v1(55.16,96.24)
  BOTTOM w0.108: R5694.1 60.08,91.15 59.76,91.47 58.76,91.47 58.24,91.99 58.06,91.99 57.44,91.36 57.02,91.36 56.72,91.66 56.72,92.08 57.14,92.5 57.14,92.71 57.02,92.83 56.86,92.83 56.45,92.42 56.06,92.42 54.31,94.16 54.31,95.7 54.63,96.02 54.94,96.02 v1(55.16,96.24) R5754.2
HYPERBUS0_CK#: length 12.1
  TOP w0.108: U140.B1 v1(55.16,95.24)
  BOTTOM w0.108: R5753.1 v1(55.16,95.24) 55.16,95.62 55.05,95.73 54.75,95.73 54.6,95.58 54.6,94.28 56.18,92.71 56.33,92.71 56.74,93.12 57.14,93.12 57.43,92.83 57.43,92.38 57.01,91.96 57.01,91.78 57.14,91.65 57.32,91.65 57.94,92.28 58.36,92.28 58.88,91.76 59.72,91.76 R5695.1
HYPERBUS0_CS#: length 3.1
  TOP w0.147: U140.A3 54.09,97.61 53.96,97.74 v1(53.61,97.74)
  BOTTOM w0.147: v1(53.61,97.74) 53.92,97.43 R5696.1 53.61,97.08 53.33,97.36 R5693.1
HYPERBUS0_DQ0: length 13.8
  TOP w0.147: v1(57.96,97.61) U140.D3
  BOTTOM w0.147: v1(57.96,97.61) 57.58,97.61 57.5,97.69 R5715.1 56.35,97.69 55.69,97.03 55.69,95.73 56.46,94.97 56.46,94.51 58.03,92.94 59.62,92.94 59.73,93.05 59.73,93.17 59.84,93.28 59.99,93.28 60.1,93.17 60.1,93.05 60.2,92.94 60.36,92.94 60.46,93.05 60.46,93.17 60.57,93.28 60.72,93.28 60.83,93.17 60.83,93.05 60.94,92.94 61.09,92.94 61.2,93.05 61.2,93.17 61.31,93.28 61.46,93.28 61.57,93.17 61.57,93.05 61.68,92.94 RA8.1
HYPERBUS0_DQ1: length 11.7
  TOP w0.147: U140.D2 57.62,96.61 v1(57.94,96.29)
  BOTTOM w0.147: RA8.2 62.86,93.4 62.6,93.65 59.58,93.65 59.38,93.45 58.39,93.45 58.03,93.8 R5716.1 58.03,95.53 56.89,96.67 56.89,96.98 57.04,97.13 57.79,97.13 57.94,96.98 v1(57.94,96.29)
HYPERBUS0_DQ2: length 13.6
  TOP w0.147: U140.C4 57.03,98.12 57.73,98.12 58.06,98.45 58.06,99.03 v1(57.96,99.14)
  BOTTOM w0.147: R5712.1 v1(57.96,99.14) 59.05,98.04 59.05,95.12 59.76,94.41 63.01,94.41 63.66,93.76 RA8.4
HYPERBUS0_DQ3: length 14.1
  TOP w0.147: v1(57.04,100) 57.04,99.11 U140.D4
  BOTTOM w0.147: R5710.1 56.79,100.23 57.02,100 v1(57.04,100) 57.04,99.31 58.67,97.69 58.67,94.74 59.38,94.03 62.81,94.03 63.26,93.59 RA8.3
HYPERBUS0_DQ4: length 16.8
  TOP w0.147: U140.D5 57.53,99.97 57.78,100.21 v1(57.78,101.02)
  BOTTOM w0.147: RA9.1 64.59,93.36 63.16,94.79 59.94,94.79 59.43,95.3 59.43,98.27 58.56,99.14 58.56,100.66 59.15,101.24 59.15,101.57 58.95,101.78 58.49,101.78 58.18,101.47 R5717.1 v1(57.78,101.02)
HYPERBUS0_DQ5: length 16.6
  TOP w0.147: U140.E3 59,97.61 59.4,98.02 v1(60.11,98.02)
  BOTTOM w0.147: v1(60.11,98.02) R5714.1 60.11,98.83 60.55,99.26 60.55,100.28 60.77,100.51 62.04,100.51 62.35,100.2 62.35,99.24 61.38,98.27 61.38,97.94 62.76,96.57 64.28,96.57 65.07,95.79 65.07,95.33 65.79,94.6 RA9.4
HYPERBUS0_DQ6: length 16.2
  TOP w0.147: U140.E2 58.53,96.26 59.15,95.64 59.15,95.05 59.4,94.79 60.3,94.79 60.47,94.97 60.47,95.43 v1(60.01,95.89)
  BOTTOM w0.147: R5713.1 60.34,95.81 60.09,95.81 v1(60.01,95.89) 60.01,95.33 60.16,95.17 61.61,95.17 61.72,95.28 61.72,96.11 61.83,96.22 62.03,96.22 62.14,96.11 62.14,95.31 62.27,95.17 62.42,95.17 62.53,95.28 62.53,95.57 62.64,95.68 62.79,95.68 62.9,95.57 62.9,95.28 63.01,95.17 63.37,95.17 63.75,94.79 63.91,94.79 64.15,95.03 64.31,95.03 64.41,94.93 64.41,94.77 64.17,94.53 64.17,94.37 64.27,94.27 64.43,94.27 64.67,94.51 64.83,94.51 64.93,94.41 64.93,94.25 64.69,94.01 64.69,93.85 64.99,93.55 RA9.2
HYPERBUS0_DQ7: length 15.4
  TOP w0.147: v1(59.89,96.82) 60.32,96.82 60.67,96.47 60.67,96.04 61.05,95.66 61.05,94.56 60.83,94.34 58.87,94.34 58.53,94.67 U140.E1
  BOTTOM w0.147: v1(59.89,96.82) R5711.1 60.47,97.22 60.59,97.33 61.46,97.33 62.6,96.19 63.09,96.19 63.72,95.55 64.31,95.55 65.39,94.47 65.39,92.94
HYPERBUS0_RST#: length 9.5
  TOP w0.147: U2348.4 R5698.1 R5820.2 55.74,102.07 53.84,100.18 53.84,99.31 U140.A4
HYPERBUS0_RWDS: length 13.9
  TOP w0.147: U136.B15 v1(68.1,88.85)
  BOTTOM w0.132: 66.49,94.44 66.49,94.15 66.31,93.97 66.31,93.62 66.49,93.44 66.49,93.09 66.31,92.92 66.31,92.57 66.49,92.39 66.49,92.18 68.24,90.42 68.24,89.75 68.73,89.26 69.05,89.26 69.29,89.02 69.29,88.69 69.06,88.46 68.73,88.46 68.34,88.85 v1(68.1,88.85)
  BOTTOM w0.147: 66.49,94.44 65.64,95.28 R5709.1 65.64,96.93 65.47,97.1 R5810.1 R5752.1
I2C0_SCL_1V8: length 379.6
  TOP w0.147: v1(94.84,58.39) 94.84,57.61 94.4,57.18 93.95,57.18 93.03,56.26 93.03,55.67 92.53,55.17 91.04,55.17 90.7,55.51 U15.12 ; U21.29 101.68,134.35 100.07,132.74 100.07,131.57 v1(98.95,130.45) 100.78,128.63 100.78,122.76 101.72,121.82 101.72,120.14 102.13,119.74 102.13,116.79 97.11,111.78 97.11,96.93 93.82,93.64 93.82,91.36 96.28,88.9 98.8,88.9 102.63,85.06 102.63,81.94 101.01,80.31 99.56,80.31 98.9,79.65 98.9,78.49 98.47,78.05 97.66,78.05 v1(95.34,75.74) ; v1(62.78,151.71) 62.78,151.53 63.01,151.3 U7.25 ; v1(33.06,58.6) 33.62,58.04 34.28,58.04 34.86,58.61 R296.1 ; v1(111.9,130.84) 111.9,142.6 113.71,144.4 113.71,145 113.6,145.11 U11.5 112.19,145.11 111.63,145.67 111.63,147.58 v1(112.57,148.51) ; v1(83.62,149.97) 83.62,150.38 83.92,150.68 U5.7 ; v1(100.25,149.15) 101.32,150.22 U6.7 ; v1(49.57,133.17) 50.44,133.17 51.27,132.34 U2358.6 ; U8.25 56.52,146.52 56.76,146.28 56.76,145.8 57.32,145.24 v1(57.68,145.24)
  L03_SIG1 w0.091: v1(49.57,133.17) 52.03,133.17 53.41,134.56 53.41,137.86 56.6,141.05 57.98,141.05 58.64,141.71 58.64,144.27 v1(57.68,145.24) 57.68,147.19 56.69,148.18 56.69,150.11 57.04,150.47 58.18,150.47 59.1,151.38 59.86,151.38 60.98,152.5 62.35,152.5 62.78,152.07 v1(62.78,151.71) ; v1(33.06,58.6) 31.89,57.43 31.89,56.52 33.95,54.46 35.73,54.46 36.43,53.76 36.43,41.82 37.28,40.97 37.28,40.06 v1(38.4,38.94) ; v1(39.03,35.46) 39.9,34.59 46.35,34.59 47.97,36.22 49.01,36.22 51.66,33.58 52.88,33.58 54.96,35.66 54.96,43.97 55.94,44.95 58.75,44.95 59.1,44.6 59.1,41.71 60.06,40.74 61.5,40.74 62.53,41.77 62.53,46.86 61.74,47.65 61.74,50.65 61.94,50.85 61.94,52.2 60.22,53.92 v1(60.22,56.29) ; v1(112.57,148.51) 112.06,149.02 109.54,149.02 109.16,148.64 103.34,148.64 102.84,149.15 v1(100.25,149.15) 100.25,149.47 99.36,150.36 v1(95.72,150.36) 93.53,150.36 92.35,149.17 91.71,149.17 91.19,148.66 84.93,148.66 v1(83.62,149.97) ; v1(95.34,75.74) 96.31,74.78 96.31,70.92 96.92,70.31 96.92,67.87 100.04,64.74 100.04,60.56 98.82,59.34 v1(98.82,57.61)
  BOTTOM w0.147: v1(98.95,130.45) 99.59,131.09 102.61,131.09 102.89,131.37 111.37,131.37 v1(111.9,130.84) ; v1(60.22,56.29) 60.22,56.67 61.45,57.9 64.5,57.9 65.07,58.46 65.07,58.76 65.44,59.13 66.11,59.13 66.34,58.9 66.72,58.9 67.23,59.41 67.23,60.11 67.51,60.4 67.89,60.4 68.27,60.02 69.51,60.02 70.11,60.62 71.2,60.62 71.46,60.36 75.03,60.36 75.92,61.25 82.61,61.25 83.99,59.87 85.67,59.87 86.68,60.88 90.98,60.88 91.66,60.2 92.05,60.2 93.11,59.14 93.11,58.84 93.94,58.02 94.46,58.02 v1(94.84,58.39) 98.04,58.39 v1(98.82,57.61) ; R234.2 86.84,77.75 86.99,77.9 C188.2 R598.2 87.37,76.75 87.54,76.58 91.25,76.58 92.52,75.31 94.91,75.31 v1(95.34,75.74) ; v1(38.4,38.94) 38.68,38.66 38.68,35.81 v1(39.03,35.46) ; v1(112.57,148.51) 112.32,148.76 112.32,149.73 111.84,150.21 U76.7 ; U77.7 94.44,150.58 94.66,150.36 v1(95.72,150.36) ; v1(62.78,151.71) 63.47,152.4 72.99,152.4 75.42,149.97 v1(83.62,149.97)
I2C0_SCL_1V8_RC: length 11
  TOP w0.147: U136.M3 v1(76.9,78.46)
  BOTTOM w0.132: v1(76.9,78.46) 77.29,78.85 77.29,79.41 77.53,79.65 78.68,79.65 78.9,79.44 78.9,79.09 79.14,78.85 82.1,78.85
  BOTTOM w0.147: 82.1,78.85 82.96,77.99 84.56,77.99 84.8,77.75 R234.1
I2C0_SDA_1V8: length 354.9
  TOP w0.147: v1(101.41,148.69) 101.41,149.73 101.82,150.14 U6.8 ; U7.26 62.81,150.8 62.81,150.8 v1(62.68,150.8) ; U5.8 84.42,150.2 84.09,149.88 84.09,148.74 84.1,148.73 v1(84.1,148.69) ; v1(110.84,130.71) 110.84,142.42 109.03,144.22 109.03,144.83 109.31,145.11 U11.4 110.86,145.11 111.24,145.49 v1(111.24,148.18) ; U15.19 90.7,60.33 v1(91.78,61.4) ; U2358.5 v1(50,132.15) ; R294.1 31.33,57.91 v1(31.23,57.81) ; U21.30 102.18,134.09 100.63,132.54 100.63,130.89 v1(99.97,130.23) 101.26,128.93 101.26,125.17 101.69,124.74 101.69,122.35 102.07,121.97 102.07,120.29 102.48,119.89 102.48,116.64 97.46,111.62 97.46,96.78 94.18,93.5 94.18,91.5 96.26,89.42 98.57,89.42 98.59,89.41 98.87,89.41 102.99,85.29 102.99,81.74 101.21,79.96 99.84,79.96 99.33,79.45 99.33,78.41 98.57,77.65 97.96,77.65 95.34,75.03 v1(95.34,74.57) ; v1(77.11,64.01) 77.64,64.54 C182.2 77.3,65.01 77.04,64.75 76.85,64.75 76.7,64.9 R210.2 ; v1(58.95,145.36) 58.23,145.36 57.9,145.69 57.65,145.69 57.14,146.2 57.14,146.87 57,147.02 U8.26
  L03_SIG1 w0.091: v1(38.04,36.91) 38.68,36.27 46.61,36.27 47.1,36.75 48.95,36.75 51.84,33.86 52.75,33.86 54.6,35.71 54.6,44.07 55.92,45.39 58.79,45.39 59.48,44.7 59.48,42.5 59.89,42.09 60.81,42.09 61.05,42.34 61.05,45.95 61.46,46.35 61.46,50.98 61.56,51.08 61.56,51.69 61.13,52.12 60.24,52.12 59.45,52.91 v1(59.45,56.18) ; v1(31.23,57.81) 31.23,56.77 34.38,53.62 34.38,53.04 36.11,51.31 36.11,41.68 36.92,40.87 36.92,39.55 v1(37.33,39.14) ; v1(84.1,148.69) 84.75,148.03 92.8,148.03 94.51,149.73 v1(95.22,149.73) 96.26,148.69 v1(101.41,148.69) 102.89,148.69 103.22,148.36 109.29,148.36 109.52,148.59 110.84,148.59 v1(111.24,148.18) ; v1(50,132.15) 51.39,132.15 53.69,134.44 53.69,137.74 56.71,140.77 58.11,140.77 58.18,140.84 58.21,140.84 58.95,141.58 v1(58.95,145.36) 58.95,146.33 56.96,148.31 56.96,149.99 57.17,150.19 58.31,150.19 59.23,151.1 59.99,151.1 60.98,152.1 61.99,152.1 62.3,151.79 62.3,151.18 v1(62.68,150.8) ; v1(95.34,74.57) 96.03,73.89 96.03,70.79 96.61,70.21 96.61,67.77 99.61,64.77 99.61,60.73 v1(98.95,60.07)
  BOTTOM w0.147: v1(110.84,130.71) 102.63,130.71 102.15,130.23 v1(99.97,130.23) ; v1(95.22,149.73) 94.6,149.73 93.94,150.4 U77.8 ; v1(84.1,148.69) 83.43,149.35 75.53,149.35 72.94,151.94 63.82,151.94 v1(62.68,150.8) ; v1(38.04,36.91) 38.04,38.43 v1(37.33,39.14) ; v1(98.95,60.07) 98.39,59.51 93.77,59.51 92.13,61.15 92.02,61.15 v1(91.78,61.4) 90.87,62.31 79.27,62.31 78.43,63.15 R603.2 v1(77.11,64.01) 76.38,64.01 76.15,64.23 73.92,64.23 73.78,64.09 65.48,64.09 63.72,62.33 62.27,62.33 61.43,61.49 61.43,60.07 59.45,58.09 v1(59.45,56.18) ; U76.8 111.34,150.12 111.66,149.8 111.66,148.59 v1(111.24,148.18)
I2C0_SDA_1V8_RC: length 13.7
  TOP w0.147: U136.N3 v1(77.7,78.45) ; R210.1 v1(76.7,67.46)
  L03_SIG1 w0.091: v1(77.7,78.45) 78.1,78.05 78.1,77.44 78.48,77.06 78.48,73.66 77.69,72.87 77.69,69.67 76.7,68.68 v1(76.7,67.46)
I2C3_SCL_1V8: length 144.8
  TOP w0.147: v1(133.09,67.72) 135.8,70.43 135.8,77.57 134.65,78.73 134.65,140.75 133.98,141.43 R465.2 132.94,142.09 132.25,142.78 J12.18 ; v1(78,76.2) 77.64,76.2 77.3,76.54 U136.N1
  BOTTOM w0.147: v1(133.09,67.72) 132.48,67.72 130.36,69.84 124.54,69.84 121.99,67.28 112.31,67.28 111.55,66.52 110.25,66.52 109.69,65.96 96.74,65.96 91.91,70.79 91.91,71.78 89.22,74.47 85.74,74.47 85.34,74.88 81.45,74.88 80.23,76.1 79.57,76.1 79.14,75.67 78.53,75.67 v1(78,76.2)
I2C3_SDA_1V8: length 151.4
  TOP w0.147: U136.L3 v1(76.1,78.46) ; J12.20 131.98,141.98 132.17,141.78 R464.2 131.88,141.43 131.73,141.28 131.73,139.29 134.26,136.77 134.26,78.05 135.11,77.2 135.11,70.66 v1(132.89,68.43)
  BOTTOM w0.132: 74.9,77.82 74.9,78.62 75.13,78.85 75.7,78.85 v1(76.1,78.46)
  BOTTOM w0.147: v1(132.89,68.43) 133.47,68.43 133.74,68.16 133.74,67.37 133.37,67.01 128.95,67.01 126.89,69.06 124.63,69.06 121.81,66.24 114.65,66.24 114.42,66.01 112.59,66.01 111.12,64.54 96.13,64.54 91.38,69.29 89.04,69.29 88.05,70.28 84.75,70.28 83.36,71.68 82.14,71.68 81.92,71.89 78.48,71.89 75.95,74.42 75.95,76.77 74.9,77.82
I2C5_SCL_1V8: length 161.4
  TOP w0.147: v1(74.92,57.25) 74.59,56.92 73.17,56.92 72.86,57.23 72.15,57.23 71.59,56.67 66.36,56.67 63.62,59.41 61,59.41 60.52,59.89 60.52,68.58 55.44,73.66 52.98,73.66 52.55,74.09 51.86,74.09 50.79,73.03 49.01,73.03 48.25,73.79 46.68,73.79 45.32,75.15 34.63,75.15 30.83,71.35 24.17,71.35 21.73,73.79 v1(20.36,73.79) ; R685.2 J13.18 18.61,123.64 19.12,123.13 19.12,117.12 18.26,116.26 16.94,116.26 12.02,111.33 12.02,85.79 12.39,85.42 12.39,84.2 11.15,82.96 11.15,77.51 12.24,76.43 v1(12.24,74.04) ; U136.L4 v1(76.1,79.26)
  L03_SIG1 w0.091: v1(76.1,79.26) 75.72,78.88 75.72,73.34 76.73,72.34 76.73,70.08 76.24,69.6 76.24,67.54 75.25,66.55 75.25,57.58 v1(74.92,57.25)
  BOTTOM w0.147: v1(20.36,73.79) 14.17,73.79 13.91,74.04 v1(12.24,74.04)
I2C5_SDA_1V8: length 136.6
  TOP w0.147: v1(12.82,75.06) 12.82,77.62 11.5,78.94 11.5,82.81 12.74,84.04 12.74,85.68 12.37,86.05 12.37,111.19 17.05,115.87 18.37,115.87 19.47,116.98 19.47,123.7 18.73,124.44 J13.20 R684.2 ; v1(45.64,75.67) 45.28,75.67 45.18,75.56 34.51,75.56 30.68,71.73 24.48,71.73 21.96,74.24 v1(21.13,74.24) ; U136.M4 v1(76.9,79.26)
  BOTTOM w0.132: 73.88,79.65 76.5,79.65 ; 73.88,79.65 73.53,79.65 73.3,79.43 73.3,77.75
  BOTTOM w0.147: v1(12.82,75.06) 13.96,75.06 14.78,74.24 v1(21.13,74.24) ; 73.88,79.65 73.88,79.65 ; 76.5,79.65 v1(76.9,79.26) ; v1(45.64,75.67) 46.21,76.24 49.18,76.24 49.52,75.9 54.48,75.9 55.19,75.19 55.19,72.49 55.57,72.11 58.13,72.11 59.34,70.9 59.64,70.9 59.66,70.89 65.65,70.89 67.33,72.57 71.54,72.57 72.13,73.15 72.13,74.02 72.31,74.19 72.31,74.83 73.14,75.67 73.14,77.6 73.3,77.75
I2C_ADDR0_A0: length 11.2
  TOP w0.147: v1(92.58,36.93) 92.58,37.39 92.41,37.55 J18.47
  BOTTOM w0.147: R641.1 R642.2 97.86,35.21 96.58,36.49 93.02,36.49 v1(92.58,36.93)
I2C_ADDR0_A2: length 7.8
  TOP w0.147: J18.37 90.41,38.58 87.95,36.12 v1(87.95,35.66)
  BOTTOM w0.147: R638.1 R639.2 87.13,35.37 87.42,35.66 v1(87.95,35.66)
I2C_ADDR1_A0: length 3.5
  TOP w0.147: J19.47 124.84,38.52 v1(124.92,38.43)
  BOTTOM w0.147: R628.2 R630.1 125.05,37.76 124.92,37.89 v1(124.92,38.43)
I2C_ADDR1_A2: length 6.6
  TOP w0.147: v1(121.93,37.14) 122.84,38.05 J19.37
  BOTTOM w0.147: v1(121.93,37.14) 121.93,36.58 121.18,35.82 R629.1 R626.2
INA_ALERT: length 192.4
  TOP w0.147: v1(30.08,57) 30.05,57.02 R305.2 ; TP46.1 43.39,68.74 43.35,68.71 v1(42.97,68.71)
  L03_SIG1 w0.091: v1(41.95,102.03) 41.22,101.3 41.22,98.53 42.84,96.9 42.84,93.9 43.1,93.65 43.1,91.21 43.73,90.58 43.73,88.9 42.89,88.06 42.89,83.24 44.05,82.08 44.05,77.08 41.61,74.64 41.61,70.07 v1(42.97,68.71) ; v1(59.3,60.58) 58.21,61.67 58.21,64.14 57.45,64.9 55.8,64.9 54.55,63.65 v1(54.55,61.42) 54.32,61.19 54.32,51.03 54.53,50.83 54.53,48.36 53.48,47.32 v1(48.48,47.32) 48.48,46.74 48.73,46.48 48.73,42.34 47.77,41.38 47.77,38.23 46.73,37.19 42.87,37.19 42,38.05 37.2,38.05 34.31,40.94 32.4,40.94 30.08,43.27 v1(30.08,57) 30.08,58.63 32.63,61.19 32.63,69.88 33.04,70.28 33.04,72.72 32.12,73.63 32.12,77.95 35.96,81.79 35.96,83.24 35.45,83.74 35.45,85.67 35.15,85.98 35.15,88.93 35.48,89.26 35.48,90.85 34.74,91.59 31.74,91.59 31.03,90.88 30.69,90.88 30.35,91.23 30.35,93.54 32.02,95.22 32.02,97.54 v1(35.84,101.36)
  BOTTOM w0.147: v1(30.08,57) R586.2 ; v1(59.3,60.58) 59.22,60.66 R5778.2 ; v1(35.84,101.36) 35.84,101.75 36.66,102.57 41.42,102.57 v1(41.95,102.03) ; R5782.2 43.61,68.84 43.48,68.71 v1(42.97,68.71) ; R505.2 54.69,61.56 v1(54.55,61.42) ; v1(48.48,47.32) 48.64,47.48 R596.2 R597.1 49.28,46.42 49.48,46.22 49.48,43.2 49.65,43.03 49.65,38.86 50.87,37.64 51.4,37.64 51.76,38 51.76,38.4 51.64,38.52 R608.2
IO_EXP0_INTN: length 3.3
  TOP w0.147: U21.32 103.18,136.4 103.66,135.92 R5761.2 R108.2
IO_EXP1_INTN: length 1.8
  TOP w0.147: U18.22 65.05,137.94 64.89,138.1 R98.1
IO_EXP_ADDR: length 1.4
  BOTTOM w0.147: U82.26 89.06,126.34 88.71,126.69 R456.1
IO_EXP_TEST_LED: length 5.8
  TOP w0.147: R441.1 68.99,134.48 68.5,133.99 68.5,132.56 68.09,132.16 66.74,132.16 66.55,132.35 U18.12
IO_MCAN0_EN: length 76.6
  TOP w0.147: U21.10 v1(102.68,143.15) ; R5639.2 v1(39.88,163.91)
  L03_SIG1 w0.091: v1(91.51,146.23) 99.93,146.23 102.68,143.48 v1(102.68,143.15)
  BOTTOM w0.147: v1(91.51,146.23) 90.75,146.23 85.6,151.38 82.83,151.38 82.16,150.7 76.24,150.7 71.19,155.75 62.68,155.75 61.84,156.59 46.81,156.59 45.68,157.72 45.68,162.29 44.06,163.91 v1(39.88,163.91)
IO_MCAN0_STB#: length 75.3
  TOP w0.147: U21.12 101.68,143.02 v1(101.97,143.31) ; R102.2 R5692.1 v1(38.03,149.73)
  L03_SIG1 w0.091: v1(87.85,146.33) 88.84,146.33 89.4,145.77 99.51,145.77 v1(101.97,143.31)
  BOTTOM w0.147: v1(38.03,149.73) 38.42,149.34 55.73,149.34 57.55,151.15 61.67,151.15 62.47,150.35 63.27,150.35 63.43,150.51 73.87,150.51 75.38,149 83,149 83.79,148.21 85.97,148.21 v1(87.85,146.33)
IORET_WAKE: length 57.1
  TOP w0.147: U136.D7 v1(69.7,82.46) ; v1(67.23,122.02) 67.23,122.45 66.98,122.69 U3070.4
  L03_SIG1 w0.091: v1(62.88,81) 62.17,81.71 62.17,83.26 61.34,84.09 61.34,92.46 62.4,93.52 62.4,97.49 62.65,97.74 62.65,99.77 61.6,100.82 61.6,121.02 v1(62.22,121.64)
  BOTTOM w0.132: v1(69.7,82.46) 69.46,82.46 69.06,82.85 68.72,82.85 68.57,82.7 65.75,82.7
  BOTTOM w0.147: v1(62.88,81) 63.57,81 65.27,82.7 65.75,82.7 ; v1(62.22,121.64) 62.6,122.02 v1(67.23,122.02)
JTAG_CTI_RTCK: length 4.5
  TOP w0.147: J14.9 41.99,112.93 42.16,113.11 43.6,113.11 v1(43.91,113.41)
  BOTTOM w0.147: R476.1 43.65,113.64 43.88,113.41 v1(43.91,113.41)
JTAG_CTI_TCK: length 10.9
  TOP w0.147: J14.11 40.72,112.99 40.3,113.41 v1(39.95,113.41)
  BOTTOM w0.147: U88.1 R485.1 45.18,112.53 44.97,112.31 R487.1 44.53,112.69 44.26,112.95 42.61,112.95 41.86,113.71 U87.1 40.52,113.98 v1(39.95,113.41)
JTAG_DIR: length 3.1
  BOTTOM w0.147: U110.4 35.4,84.17 35.17,84.4 R569.2 35.79,85.13 U110.5
JTAG_EMU0: length 21.6
  TOP w0.147: U39.7 28.35,103.21 28.07,103.48 R211.2 27.87,103.27 27.63,103.03 26.63,103.03 26.33,103.33 26.33,105.08 27.17,105.92 31.11,105.92 31.36,106.17 33.51,106.17 36.53,109.19 39.23,109.19 39.45,109.41 J14.13
JTAG_EMU1: length 18.5
  TOP w0.147: U39.6 28.59,103.56 28.25,103.89 28.25,104.15 28.16,104.24 R212.2 27.87,105.17 28.26,105.56 31.26,105.56 31.48,105.79 34.16,105.79 34.79,105.16 34.79,103.84 35.3,103.33 38.96,103.33 39.45,103.82 J14.14
JTAG_EMU_RSTN: length 86.8
  TOP w0.147: J14.15 R482.2 38.15,113.72 v1(37.51,113.72)
  L03_SIG1 w0.091: v1(22.37,115.85) 22.37,114.99 16.02,108.64 16.02,105.16 20.92,100.25 20.92,92.23 22.32,90.83 22.32,84.38 21.67,83.73 21.67,78.86 21.98,78.55 21.98,77.56 21.56,77.14 21.56,75.08 22.38,74.26 22.38,69.38 20.41,67.41 20.41,65.18 20.9,64.69 22.22,64.69 22.93,63.98 v1(22.93,62.99)
  BOTTOM w0.147: v1(22.37,115.85) 29.99,115.85 32.37,113.47 37.26,113.47 v1(37.51,113.72) ; v1(22.93,62.99) 23.56,62.36 25.01,62.36 25.32,62.66 25.32,64.7 24.85,65.17 U86.6
JTAG_TCK: length 51.8
  L03_SIG1 w0.091: v1(38.04,115.01) 38.04,110.06 38.68,109.42 38.68,108.36 37.05,106.73 37.05,99.9 34.43,97.28 34.43,95.96 34.79,95.61 35.73,95.61 37.86,93.47 37.86,87.55 38.85,86.56 38.85,84.53 37.13,82.8 v1(37.13,81.46)
  BOTTOM w0.147: v1(37.13,81.46) 36.88,81.71 36.73,81.71 36.58,81.85 U110.14 ; R483.1 47.99,113.57 46.12,115.44 43.83,115.44 43.43,115.84 41.67,115.84 40.84,115.01 v1(38.04,115.01)
JTAG_TDI: length 38.7
  TOP w0.147: J14.3 45.8,109.28 45.46,108.94 44.95,108.94 44.7,108.69 44.24,108.69 44.11,108.81 42.38,108.81 42.08,108.51 39.69,108.51 39.49,108.71 v1(39.13,108.71)
  L03_SIG1 w0.091: v1(38.12,82.97) 39.13,83.99 39.13,86.69 38.15,87.68 38.15,93.82 36.03,95.94 36.03,98.27 37.33,99.57 37.33,105.94 39.13,107.75 v1(39.13,108.71)
  BOTTOM w0.147: v1(38.12,82.97) U110.12
JTAG_TDIS: length 2.7
  TOP w0.147: J14.4 45.8,107.77 v1(45.98,107.96)
  BOTTOM w0.147: R490.2 46.07,108.04 v1(45.98,107.96)
JTAG_TDO: length 4.7
  TOP w0.147: J14.7 43.26,109.28 v1(43.25,109.27)
  BOTTOM w0.147: U90.7 44.5,108.43 43.65,109.27 v1(43.25,109.27)
JTAG_TMS: length 42.7
  TOP w0.147: v1(39.97,103.76) 40.35,103.38 44.85,103.38 45.31,102.92 46.93,102.92 48.13,104.11 48.13,108.33 47.07,109.39 J14.1
  L03_SIG1 w0.091: v1(39.97,103.76) 39.97,102.46 38.65,101.14 38.65,100.05 36.44,97.84 36.44,97.51 37.03,96.93 37.03,95.45 38.57,93.9 38.57,87.66 39.41,86.82 39.41,83.64 37.98,82.21 v1(37.56,82.21)
  BOTTOM w0.147: U110.13 36.98,82.14 37.13,81.99 37.34,81.99 v1(37.56,82.21)
JTAG_TRST#: length 45.9
  TOP w0.147: v1(37.64,108.15) 42.28,108.15 42.59,108.46 43.96,108.46 44.09,108.33 44.85,108.33 45.1,108.58 46.66,108.58 v1(47.26,107.99) 47.07,107.8 J14.2
  L03_SIG1 w0.091: v1(36.44,81.2) 36.67,81.43 36.67,82.75 38.57,84.66 38.57,86.44 37.58,87.43 37.58,93.34 35.65,95.28 34.59,95.28 34.05,95.81 34.05,98.35 36.77,101.07 36.77,107.29 v1(37.64,108.15)
  BOTTOM w0.147: U110.15 36.19,81.46 v1(36.44,81.2) ; R489.2 v1(47.26,107.99)
LDO_1V8: length 1.7
  TOP w0.147: v1(39.84,24.61) 39.87,24.59 39.88,24.59 40.02,24.44 C303.1
  BOTTOM w0.147: U129.35 39.85,24.55 39.84,24.56 v1(39.84,24.61)
LDO_3V3: length 72.6
  TOP w0.254: 39.52,25.34 39.54,25.32 44.18,25.32 45.23,26.37 45.23,28.45 44.89,28.79 R374.1 v1(43.91,29.35) C292.1 U69.8 ; 39.52,25.34 39.36,25.49 v1(39.36,27.79) ; 39.52,25.34 39.05,24.87 36.21,24.87 35.66,25.42 v1(35.66,26.12) 35.34,26.44 R378.1 ; U71.5 C300.2 33.58,36.21 v1(34.21,36.83) 34.22,36.84 R195.1 ; v1(39.55,16.18) 39.55,15.46 C319.2
  L03_SIG1 w0.305: v1(39.55,16.18) 39.55,16.88 39.11,17.32 35.98,17.32 35.38,16.72 33.67,16.72 32.81,17.59 32.81,21.08 34.38,22.66 35.65,22.66 36.92,23.93 38.09,23.93 39.36,25.2 v1(39.36,27.79) 39.36,28.74 36.31,31.79 36.31,36.42 35.64,37.1 34.48,37.1 v1(34.21,36.83)
  BOTTOM w0.229: U129.9 39.45,16.28 v1(39.55,16.18) 39.77,15.97 R678.1 39.77,15.24 40.05,14.96 R679.1
  BOTTOM w0.254: v1(43.91,29.35) 43.35,29.35 42.89,28.89 R646.1 ; v1(39.36,27.79) 39.59,27.79 39.92,27.46 R644.1 ; R664.1 34.91,23.95 34.49,24.37 34.49,25.57 35.04,26.12 v1(35.66,26.12) 36.06,25.72 36.06,25.36 ; 36.06,25.36 36.31,25.1 R660.1 ; 36.06,25.36 R658.1
LM61460_BOOT: length 1.9
  TOP w0.254: U134.14 16.67,15.03 16.1,14.45 R5805.2
LM61460_FB: length 3.9
  TOP w0.147: R3720.2 19.47,11.3 19.78,11.61 19.78,13.06 19.35,13.49 U134.4
LM61460_RT: length 4.5
  TOP w0.147: R3652.1 22.37,12.68 22.22,12.83 21.68,12.83 21.38,13.13 21.38,14.76 21.11,15.03 U134.6
LM61460_SW: length 5.7
  TOP w0.203: U134.10 18.82,16.16 18.66,16 16.2,16 15.95,15.76 15.3,15.76 14.91,15.37 C3494.2
LM61460_VCC: length 2
  TOP w0.147: U134.2 18.3,13.27 18.02,13 C3627.2
MCAN0_CAN_H: length 7
  TOP w0.127: J9.3 32.53,156.71 32.53,157.18 33.47,158.12 33.83,158.12 R88.2 34.46,158.09 36.17,158.09 36.25,158 U3068.13
MCAN0_CAN_L: length 7.2
  TOP w0.127: U3068.12 36.25,158.5 36.17,158.42 34.56,158.42 R93.1 33.77,158.45 33.42,158.45 32.66,159.21 32.66,159.82 J9.1
MCAN0_EN: length 6.3
  TOP w0.147: R5639.1 39.88,161.58 39.15,160.85 39.15,160.24 39.39,160 U3068.6 40.92,160 41.62,160.7 41.62,160.95 41.9,161.23 R5638.1
MCAN0_FAULT#: length 2.6
  TOP w0.147: U3068.8 37.79,160.5 37.94,160.66 37.94,160.96 37.39,161.5 R5637.1
MCAN0_RX: length 119.5
  TOP w0.132: 64.89,79.43 65.51,80.05 68.1,80.05 U136.B4
  TOP w0.147: v1(38.15,163.91) 38.47,163.58 R81.1 ; v1(64.53,79.07) 64.89,79.43
  L03_SIG1 w0.091: v1(49.57,76.5) 49.57,77.47 46.56,80.49 46.56,86.47 48.56,88.47 48.56,88.49 48.61,88.54 48.61,91.29 46.93,92.96 46.93,96.7 46.37,97.26 46.37,103.1 47.03,103.76 47.03,107.54 46.12,108.46 46.12,113.54 47.31,114.73 47.31,131.09 46.27,132.13 46.27,155.85 44.85,157.28 44.85,160.76 41.28,164.33 38.57,164.33 v1(38.15,163.91)
  BOTTOM w0.147: v1(64.53,79.07) 64.13,78.66 61.56,78.66 61.18,78.28 56.43,78.28 54.4,76.25 49.83,76.25 v1(49.57,76.5)
MCAN0_RX_R: length 4.2
  TOP w0.147: R81.2 38.47,161.54 38.8,161.21 38.8,159.55 39.35,159 U3068.4
MCAN0_STB#: length 3.6
  TOP w0.147: U3068.14 36.29,157.5 36.06,157.28 36.06,156.59 36.34,156.31 36.9,156.31 37.05,156.16 R102.1
MCAN0_T: length 10.1
  TOP w0.147: v1(35.04,156.55) 34.79,156.8 R88.1 ; v1(33.55,161.85) C107.1 34.56,161.24 34.16,160.83 R93.2
  L03_SIG1 w0.091: v1(35.04,156.55) 33.55,158.05 v1(33.55,161.85)
MCAN0_TX: length 13.8
  TOP w0.132: 64.89,77.8 65.75,77.8 67.21,79.26 68.9,79.26 U136.C4
  TOP w0.147: R82.2 60.1,80.13 60.27,79.96 61.21,79.96 62.07,79.1 62.6,79.1 63.9,77.8 64.89,77.8
MCAN0_TX_R: length 94.1
  TOP w0.147: U3068.1 39.13,157.5 38.96,157.33 38.96,157 42.79,153.16 42.79,151.54 v1(43.73,150.6) ; v1(57.4,82.42) 57.4,82.07 57.2,81.87 R82.1
  L03_SIG1 w0.091: v1(43.73,150.6) 45.53,148.79 45.53,120.22 42.66,117.35 42.66,116.08 41.55,114.96 41.55,109.12 42.33,108.33 42.33,106.1 43.88,104.55 43.88,99.75 44.72,98.91 44.72,93.95 47.72,90.96 47.72,89.26 v1(46.8,88.34)
  BOTTOM w0.147: v1(46.8,88.34) 47.05,88.09 47.21,88.09 48.25,87.05 49.65,87.05 50.49,86.21 56.53,86.21 57.93,84.81 57.93,82.95 v1(57.4,82.42)
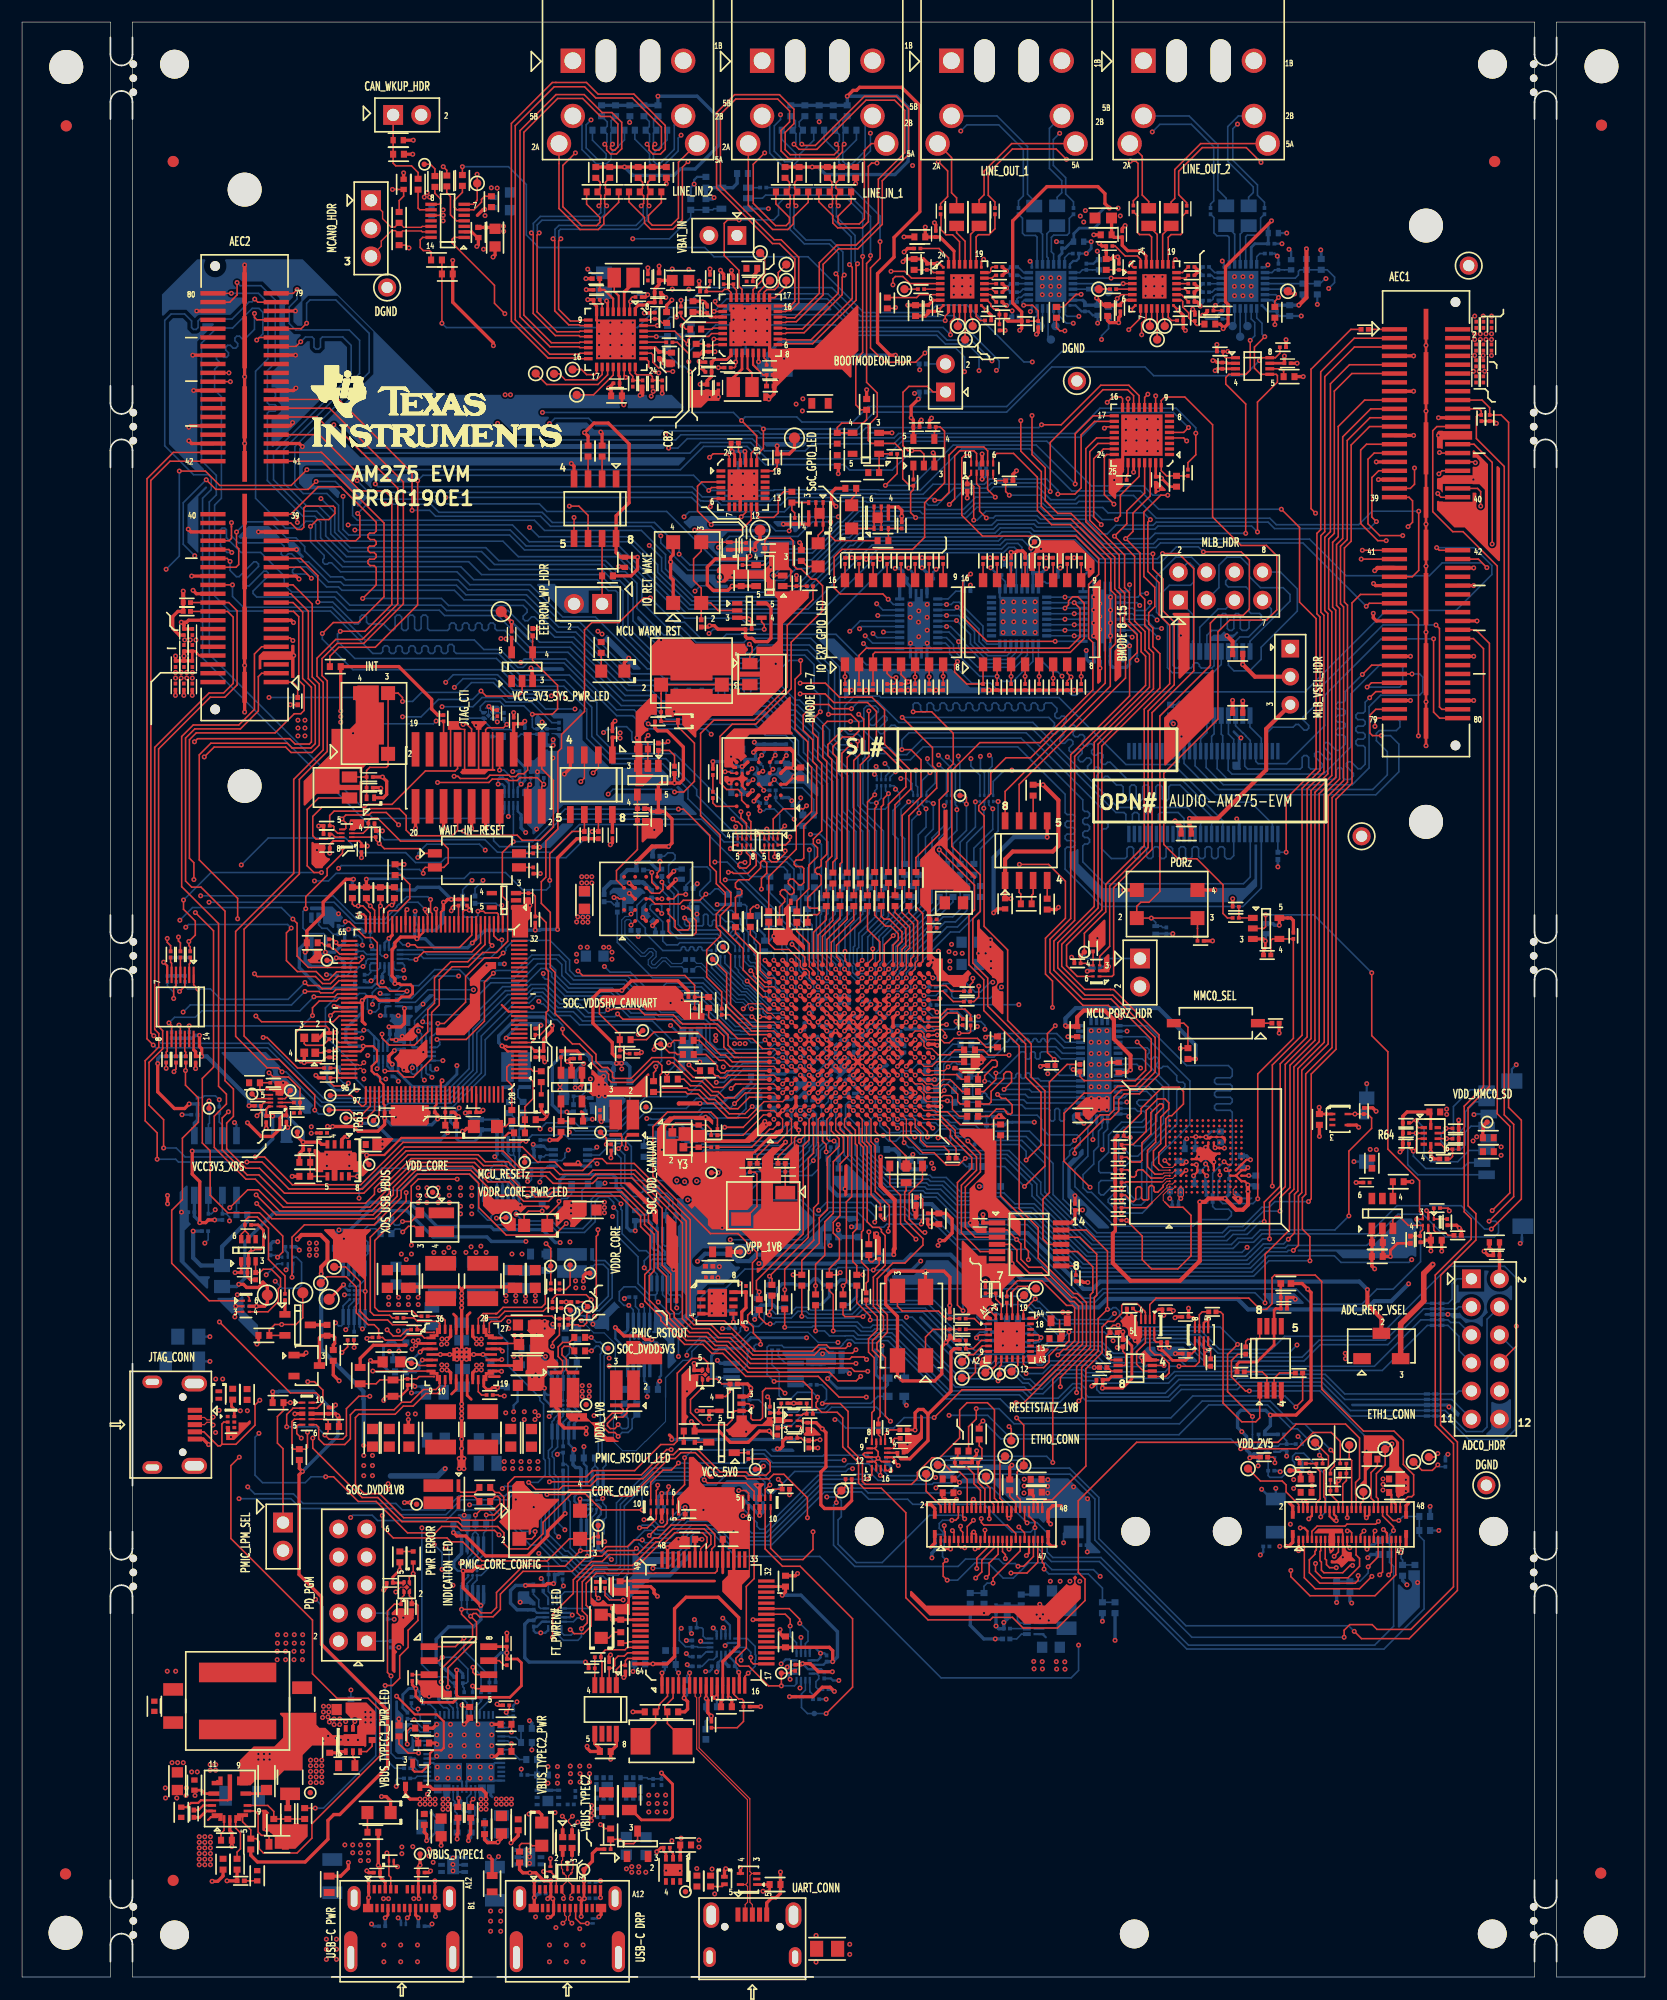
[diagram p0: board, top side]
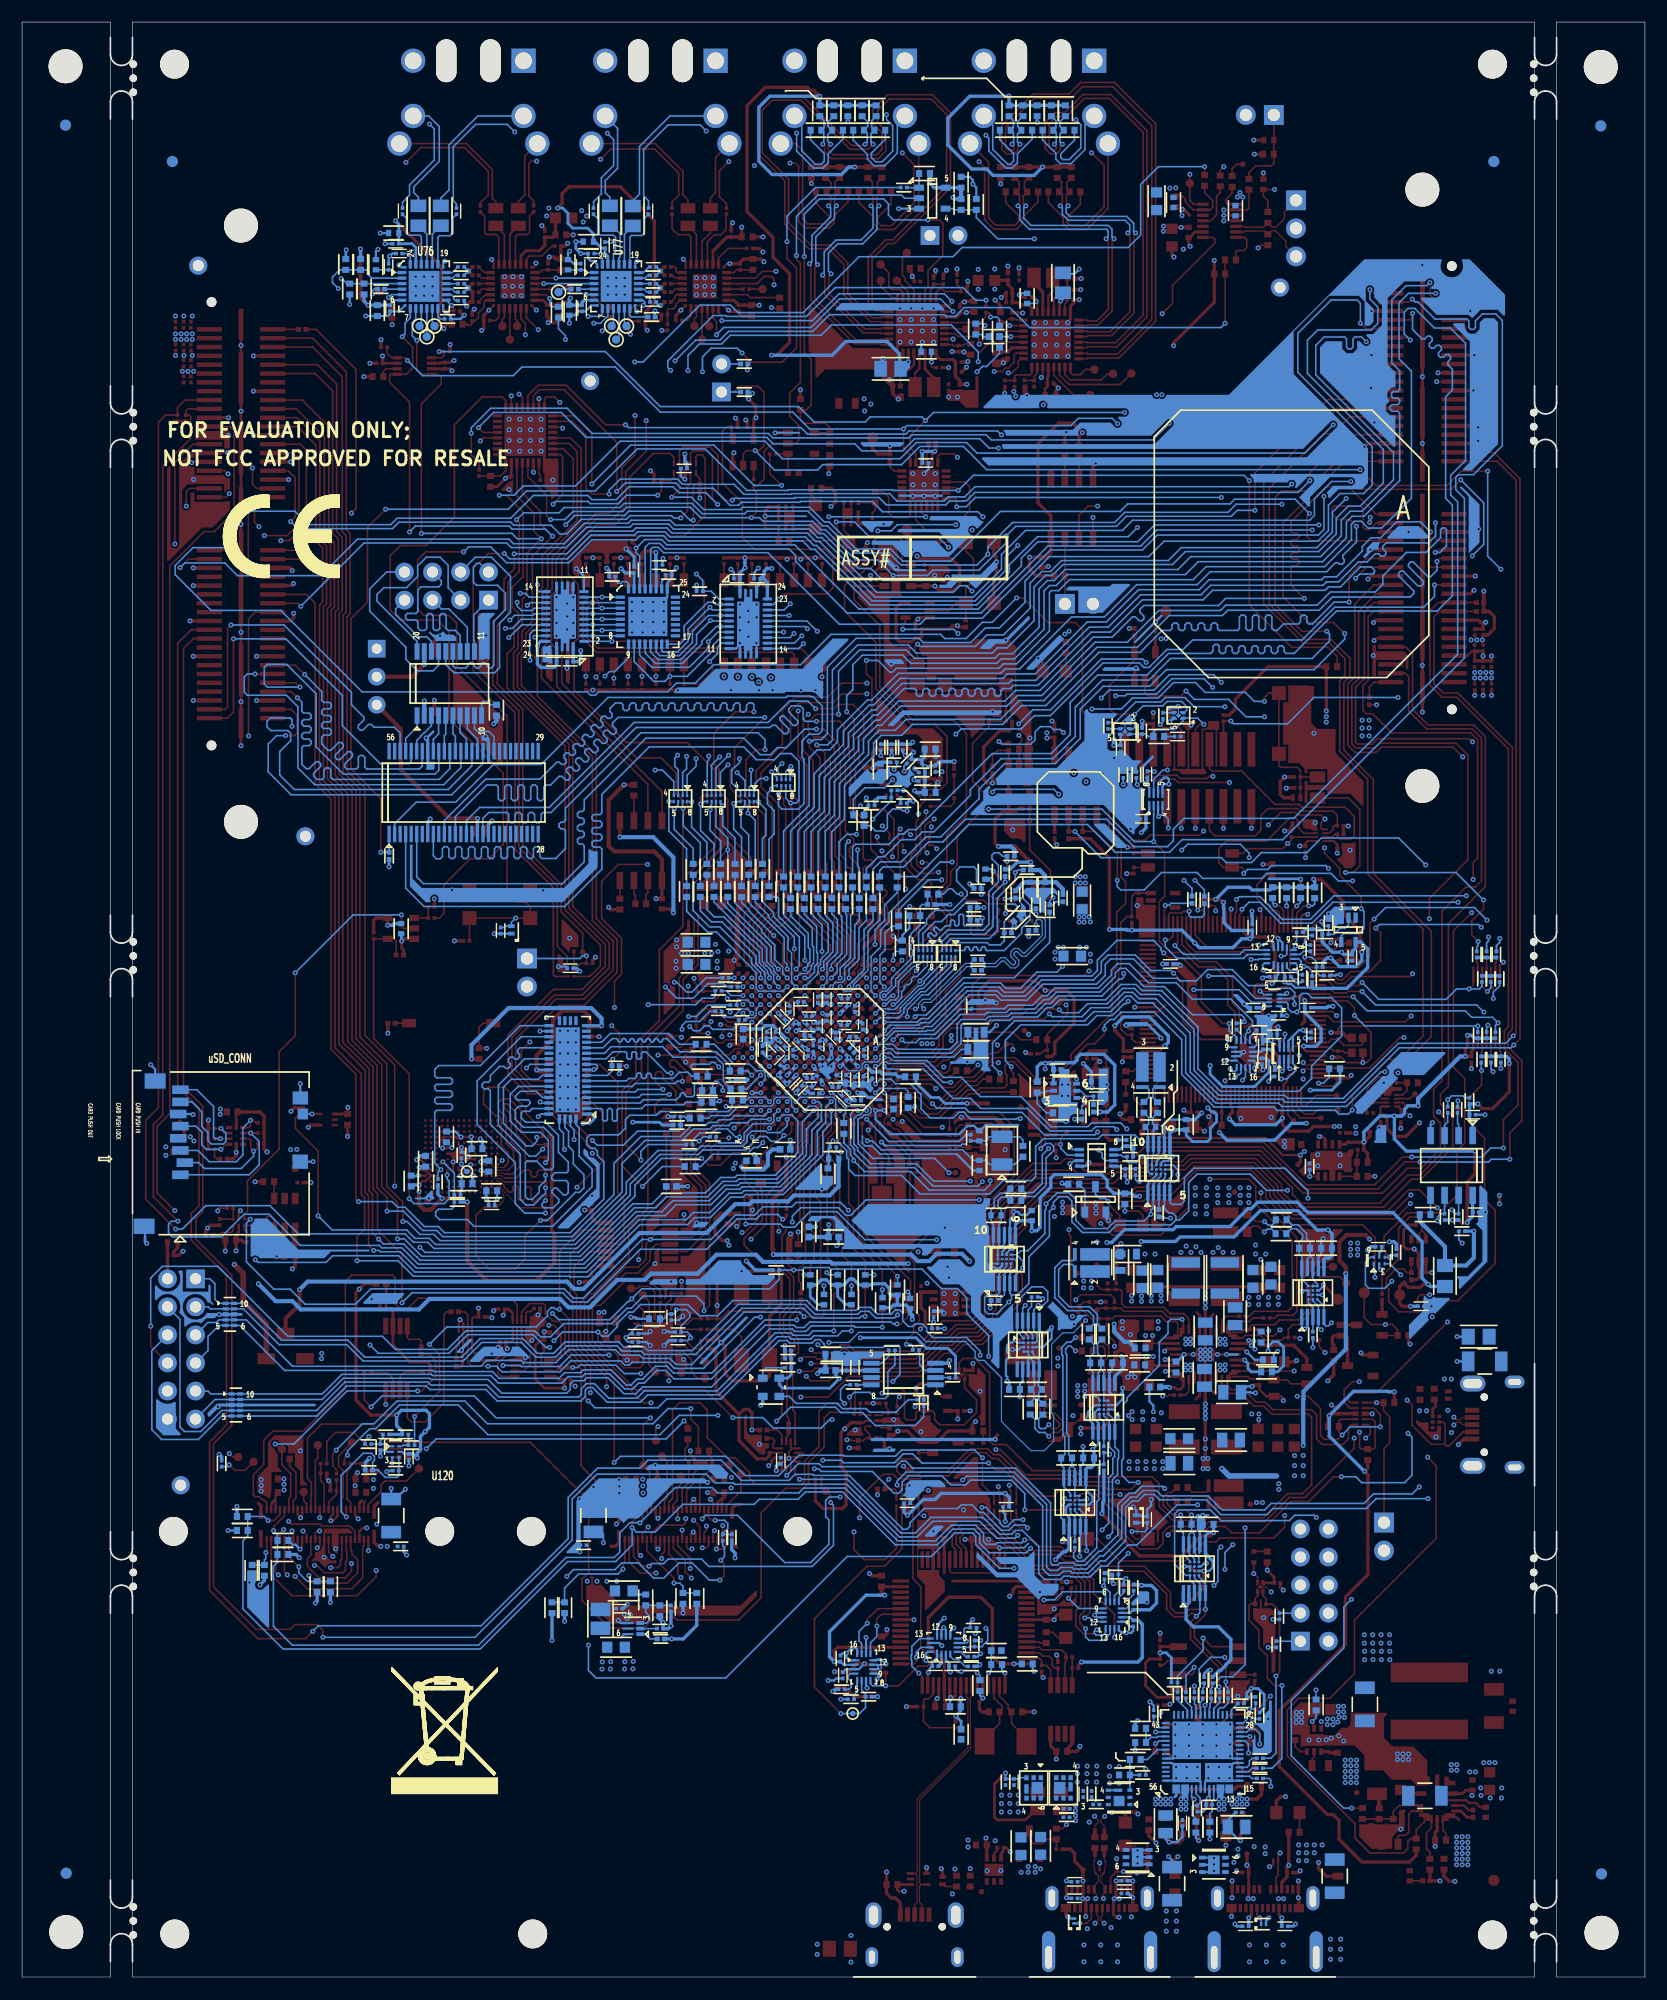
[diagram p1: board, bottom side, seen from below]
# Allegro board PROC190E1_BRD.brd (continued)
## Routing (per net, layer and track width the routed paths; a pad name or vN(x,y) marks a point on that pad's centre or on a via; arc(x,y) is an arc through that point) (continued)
MCAN0_WAKE_R: length 2.9
  TOP w0.147: R5635.1 35.87,160.15 36.02,160 U3068.9
MCAN1_RX: length 4.3
  TOP w0.147: U136.D5 v1(69.7,80.06)
  BOTTOM w0.132: v1(69.7,80.06) 69.3,80.45 67.02,80.45 66.74,80.18 R5670.1
MCAN1_RX_R: length 136.3
  TOP w0.132: v1(66.13,78.82) 65.47,78.16 64.89,78.16
  TOP w0.147: v1(26.51,78.49) 26.51,79.86 23.28,83.08 22.22,83.08 20.11,85.19 20.11,94.87 25.11,99.87 25.11,108.43 27.64,110.96 27.64,117.36 27.17,117.83 27.17,119.37 28.55,120.75 30.96,120.75 34.54,124.33 34.54,135.36 27.85,142.04 J13.53 ; v1(48.96,85.83) 48.96,85.37 49.85,84.48 50.49,84.48 51.63,83.34 51.63,82.75 52.39,81.99 52.88,81.99 53.13,81.74 53.13,81.25 53.38,81 55.31,81 57.19,82.88 57.6,82.88 57.96,82.52 57.96,81.84 57.8,81.69 57.8,80.75 58.06,80.49 60.24,80.49 60.42,80.31 61.36,80.31 62.22,79.45 62.76,79.45 64.05,78.16 64.89,78.16
  BOTTOM w0.132: R5670.2 66.25,78.7 v1(66.13,78.82)
  BOTTOM w0.147: v1(48.96,85.83) 48.96,86.18 48.45,86.69 48.1,86.69 47.44,87.35 44.44,87.35 41.95,84.86 41.95,81.71 39.01,78.77 33.62,78.77 33.32,78.46 28.03,78.46 27.71,78.13 26.86,78.13 v1(26.51,78.49)
MCAN1_TX: length 125
  TOP w0.147: J13.51 26.72,141.24 28.24,139.73 29.1,139.73 34.03,134.8 34.03,124.32 30.82,121.11 28.41,121.11 26.71,119.41 26.71,117.78 27.27,117.22 27.27,111.1 24.6,108.43 24.6,99.92 19.35,94.67 19.35,85.17 22.19,82.32 23.18,82.32 v1(23.55,81.95) ; R5671.1 v1(58.41,81.84)
  BOTTOM w0.147: v1(58.41,81.84) 59.1,82.52 59.1,84.57 57.1,86.56 50.77,86.56 49.93,87.4 48.4,87.4 47.01,88.8 46.55,88.8 45.94,88.19 44.59,88.19 41.6,85.19 41.6,81.85 38.87,79.12 33.19,79.12 32.89,78.82 27.04,78.82 23.9,81.95 v1(23.55,81.95)
MCAN1_TX_R: length 9.8
  TOP w0.147: U136.A4 65.88,79.66 64.84,78.62 64.1,78.62 62.91,79.81 62.37,79.81 61.49,80.7 60.55,80.7 59.95,81.29 R5671.2
MCAN4_RX: length 6.7
  TOP w0.132: U136.B6 68.1,81.65 64.89,81.65
  TOP w0.147: 64.89,81.65 63.94,81.65 63.7,81.41 63.24,81.41 63.05,81.59 62.81,81.59 62.39,82.02 R5650.1
MCAN4_RX_R: length 115.1
  TOP w0.147: R5650.2 60.94,82.06 v1(60.41,82.59) ; J12.53 122.03,124.38 v1(121.76,124.1)
  L03_SIG1 w0.091: v1(60.95,125.48) 60.95,100.1 61.69,99.36 61.69,98.91 61.51,98.73 61.51,97.26 61.84,96.93 61.84,94.18 60.77,93.12 60.77,87.71 60.6,87.53 60.6,82.78 v1(60.41,82.59)
  BOTTOM w0.147: v1(60.95,125.48) 61.43,125.96 62.07,125.96 62.65,125.37 69.59,125.37 74.54,130.33 74.95,130.33 75.71,131.09 87.98,131.09 88.44,131.55 91.66,131.55 91.94,131.27 95.88,131.27 97.72,129.42 102.69,129.42 103.11,129.84 116.03,129.84 v1(121.76,124.1)
MCAN4_TX: length 106.5
  TOP w0.147: v1(116.52,70.21) 116.77,70.46 116.77,81.75 119.02,84 119.02,106.63 120.46,108.08 120.46,124.41 121.23,125.18 J12.51
  BOTTOM w0.147: R5649.1 82.69,78.72 83.05,78.36 89.22,78.36 89.55,78.03 91.94,78.03 92.35,77.62 92.35,76.86 92.96,76.25 95.57,76.25 95.85,75.97 95.85,75.36 95.52,75.03 95.14,75.03 94.89,74.78 94.89,74.4 94.3,73.81 94.3,70.43 97.35,67.39 108.73,67.39 109.29,67.94 110.56,67.94 112.31,69.7 112.97,69.7 113.48,70.21 v1(116.52,70.21)
MCAN4_TX_R: length 3.2
  TOP w0.147: U136.R4 v1(79.3,79.26)
  BOTTOM w0.132: v1(79.3,79.26) 79.69,79.65 81.12,79.65 81.39,79.39
  BOTTOM w0.147: R5649.2 81.39,79.39
MCASP0_ACLKR: length 86.4
  TOP w0.147: v1(121.3,128.38) J12.43
  L03_SIG1 w0.091: v1(121.3,128.38) 120.65,128.38 118.36,126.09 117.36,126.09 117.26,126.19 117.26,126.74 117.15,126.85 117,126.85 116.89,126.74 116.89,126.19 116.78,126.09 116.63,126.09 116.52,126.19 116.52,126.74 116.42,126.85 116.27,126.85 116.16,126.74 116.16,126.19 116.05,126.09 115.9,126.09 115.79,126.19 115.79,126.74 115.69,126.85 115.53,126.85 115.43,126.74 115.43,126.19 115.32,126.09 115.17,126.09 115.06,126.19 115.06,126.74 114.95,126.85 114.8,126.85 114.7,126.74 114.7,126.19 114.59,126.09 114.44,126.09 114.33,126.19 114.33,126.74 114.22,126.85 114.07,126.85 113.96,126.74 113.96,126.19 113.86,126.09 111.9,126.09 111.24,125.43 111.24,122.71 101.97,113.44 101.97,112.95 101.39,112.37 101.24,112.37 100.68,112.93 100.53,112.93 100.42,112.82 100.42,112.67 100.98,112.11 100.98,111.96 100.87,111.85 100.72,111.85 100.16,112.41 100.01,112.41 99.9,112.3 99.9,112.15 100.46,111.59 100.46,111.44 100.35,111.33 100.2,111.33 99.64,111.89 99.49,111.89 99.38,111.79 99.38,111.63 99.94,111.08 99.94,110.92 99.84,110.82 99.68,110.82 99.12,111.38 98.97,111.38 98.87,111.27 98.87,111.12 99.43,110.56 99.43,110.41 99.32,110.3 99.17,110.3 98.61,110.86 98.46,110.86 98.35,110.75 98.35,110.6 98.91,110.04 98.91,109.89 98.8,109.78 98.65,109.78 98.09,110.34 97.94,110.34 97.83,110.23 97.83,110.08 98.39,109.52 98.39,109.37 98.28,109.26 98.13,109.26 97.57,109.82 97.42,109.82 97.31,109.72 97.31,109.57 97.87,109.01 97.87,108.85 97.77,108.75 97.62,108.75 97.06,109.31 96.9,109.31 96.8,109.2 96.8,109.05 97.36,108.49 97.36,108.34 97.25,108.23 97.1,108.23 96.54,108.79 96.39,108.79 96.28,108.68 96.28,108.53 96.84,107.97 96.84,107.82 96.73,107.71 96.58,107.71 96.02,108.27 95.87,108.27 95.76,108.17 95.76,108.01 96.32,107.45 96.32,107.3 96.22,107.2 96.06,107.2 95.5,107.76 95.35,107.76 95.25,107.65 95.25,107.5 95.81,106.94 95.81,106.79 95.7,106.68 95.55,106.68 94.99,107.24 94.84,107.24 94.73,107.13 94.73,106.98 95.29,106.42 95.29,106.27 95.18,106.16 95.03,106.16 94.47,106.72 94.32,106.72 94.21,106.61 94.21,106.46 94.77,105.9 94.77,105.75 94.36,105.34 87.59,105.34 v1(87.11,105.82)
  BOTTOM w0.147: RA7.7 87.16,105.87 v1(87.11,105.82) 87.11,104.24 85.56,102.69 R5648.1
MCASP0_ACLKR_R: length 11.8
  TOP w0.147: U136.R16 v1(79.3,89.65)
  BOTTOM w0.132: 79.75,90.98 79.75,90.78 79.7,90.73 79.7,90.06 v1(79.3,89.65)
  BOTTOM w0.147: 79.75,90.98 80.51,91.74 80.51,92.43 83.61,95.53 84.55,95.53 85.56,96.55 R5648.2
MCASP0_ACLKX: length 92.9
  TOP w0.147: J12.37 125.75,134.78 126.13,135.15 v1(126.13,136.63) ; R178.1 76.58,106.38 v1(77.23,107.04)
  L03_SIG1 w0.091: v1(77.23,107.04) 77.23,107.77 77.64,108.18 79.09,108.18 79.37,107.9 89.86,107.9 90.14,108.18 90.21,108.18 90.34,108.31 90.49,108.31 90.79,108.01 90.94,108.01 91.04,108.12 91.04,108.27 90.75,108.57 90.75,108.72 90.86,108.82 91.01,108.82 91.3,108.53 91.45,108.53 91.56,108.64 91.56,108.79 91.27,109.08 91.27,109.23 91.38,109.34 91.53,109.34 91.82,109.05 91.97,109.05 92.08,109.16 92.08,109.31 91.79,109.6 91.79,109.75 91.89,109.86 92.04,109.86 92.34,109.57 92.49,109.57 92.6,109.67 92.6,109.82 92.3,110.12 92.3,110.27 92.41,110.38 92.56,110.38 92.86,110.08 93.01,110.08 93.11,110.19 93.11,110.34 92.82,110.63 92.82,110.79 92.93,110.89 93.08,110.89 93.37,110.6 93.52,110.6 93.63,110.71 93.63,110.86 93.34,111.15 93.34,111.3 93.45,111.41 93.6,111.41 93.89,111.12 94.04,111.12 94.15,111.22 94.15,111.38 93.86,111.67 93.86,111.82 93.96,111.93 94.11,111.93 94.41,111.63 94.56,111.63 94.67,111.74 94.67,111.89 94.37,112.19 94.37,112.34 95.17,113.13 98.54,113.13 106.02,120.61 106.02,128.56 106.57,129.11 106.57,130.53 107.76,131.72 108.53,131.72 108.64,131.83 108.64,132.23 108.75,132.33 108.9,132.33 109.01,132.23 109.01,131.83 109.11,131.72 109.27,131.72 109.37,131.83 109.37,132.23 109.48,132.33 109.63,132.33 109.74,132.23 109.74,131.83 109.85,131.72 110,131.72 110.1,131.83 110.1,132.23 110.21,132.33 110.36,132.33 110.47,132.23 110.47,131.83 110.58,131.72 110.73,131.72 110.84,131.83 110.84,132.23 110.94,132.33 111.09,132.33 111.2,132.23 111.2,131.83 111.31,131.72 117.54,131.72 122.45,136.63 v1(126.13,136.63)
  BOTTOM w0.147: RA6.8 77.42,107.58 77.23,107.39 v1(77.23,107.04)
MCASP0_AFSR: length 85.7
  TOP w0.147: v1(121.4,129.18) J12.41
  L03_SIG1 w0.091: v1(87.93,105.77) 92.73,105.77 93.85,106.88 93.85,107.03 93.72,107.16 93.72,107.31 93.82,107.42 93.98,107.42 94.1,107.29 94.26,107.29 94.36,107.4 94.36,107.55 94.23,107.68 94.23,107.83 94.34,107.94 94.49,107.94 94.62,107.81 94.77,107.81 100.55,113.59 100.7,113.59 101.24,113.04 101.39,113.04 101.5,113.15 101.5,113.3 100.96,113.84 100.96,114 101.16,114.2 101.31,114.2 101.75,113.76 101.9,113.76 102.01,113.86 102.01,114.01 101.57,114.46 101.57,114.61 101.68,114.71 101.83,114.71 102.27,114.27 102.42,114.27 102.53,114.38 102.53,114.53 102.09,114.97 102.09,115.12 102.19,115.23 102.35,115.23 102.79,114.79 102.94,114.79 103.05,114.9 103.05,115.05 102.6,115.49 102.6,115.64 102.71,115.75 102.86,115.75 103.3,115.31 103.46,115.31 103.56,115.41 103.56,115.57 103.12,116.01 103.12,116.16 103.23,116.27 103.38,116.27 103.82,115.82 103.97,115.82 104.08,115.93 104.08,116.08 103.64,116.53 103.64,116.68 103.75,116.78 103.9,116.78 104.34,116.34 104.49,116.34 104.6,116.45 104.6,116.6 104.16,117.04 104.16,117.19 104.26,117.3 104.41,117.3 104.86,116.86 105.01,116.86 105.12,116.97 105.12,117.12 104.67,117.56 104.67,117.71 104.78,117.82 104.93,117.82 105.37,117.38 105.53,117.38 105.63,117.48 105.63,117.64 105.19,118.08 105.19,118.23 105.3,118.34 105.45,118.34 105.89,117.89 106.04,117.89 106.15,118 106.15,118.15 105.71,118.59 105.71,118.75 105.82,118.85 105.97,118.85 106.41,118.41 106.56,118.41 106.67,118.52 106.67,118.67 106.23,119.11 106.23,119.26 106.33,119.37 106.48,119.37 106.93,118.93 107.08,118.93 107.18,119.04 107.18,119.19 106.74,119.63 106.74,119.78 106.85,119.89 107,119.89 107.44,119.45 107.59,119.45 107.7,119.55 107.7,119.7 107.26,120.15 107.26,120.3 107.37,120.4 107.52,120.4 107.96,119.96 108.11,119.96 108.22,120.07 108.22,120.22 107.78,120.66 107.78,120.81 107.98,121.02 108.13,121.02 108.57,120.58 108.73,120.58 108.83,120.68 108.83,120.84 108.39,121.28 108.39,121.43 109.24,122.28 109.39,122.28 109.84,121.84 109.99,121.84 110.09,121.95 110.09,122.1 109.65,122.54 109.65,122.69 109.76,122.8 109.91,122.8 110.35,122.36 110.5,122.36 110.61,122.46 110.61,122.61 110.17,123.06 110.17,123.21 110.94,123.98 110.94,127.72 112.15,128.93 114.07,128.93 114.18,128.82 114.18,128.25 114.29,128.14 114.44,128.14 114.55,128.25 114.55,128.82 114.65,128.93 114.81,128.93 114.91,128.82 114.91,128.25 115.02,128.14 115.17,128.14 115.28,128.25 115.28,128.82 115.39,128.93 115.54,128.93 115.64,128.82 115.64,128.25 115.75,128.14 115.9,128.14 116.01,128.25 116.01,128.82 116.12,128.93 116.27,128.93 116.38,128.82 116.38,128.25 116.48,128.14 116.63,128.14 116.74,128.25 116.74,128.82 116.85,128.93 121.16,128.93 v1(121.4,129.18)
  BOTTOM w0.147: RA7.6 87.56,106.13 v1(87.93,105.77) 87.93,103.91 86.22,102.2 R498.2
MCASP0_AFSR_R: length 13
  TOP w0.147: U136.T17 v1(80.1,90.45)
  BOTTOM w0.132: 80.1,90.92 v1(80.1,90.45)
  BOTTOM w0.147: R498.1 86.22,96.56 84.73,95.07 83.79,95.07 80.92,92.2 80.92,91.74 80.1,90.92
MCASP0_AFSX: length 88.5
  TOP w0.147: J12.39 125.63,133.98 125.95,133.66 125.95,131.72 v1(125.54,131.32)
  L03_SIG1 w0.091: v1(125.54,131.32) 126.51,131.32 127.68,130.15 127.68,125.7 118.36,116.38 112.51,116.38 111.47,115.34 111.47,109.83 104.92,103.28 104.77,103.28 104.15,103.9 104,103.9 103.89,103.8 103.89,103.64 104.51,103.02 104.51,102.87 104.41,102.76 104.25,102.76 103.63,103.38 103.48,103.38 103.37,103.28 103.37,103.13 103.99,102.5 103.99,102.35 103.89,102.24 103.74,102.24 103.11,102.87 102.96,102.87 102.85,102.76 102.85,102.61 103.48,101.99 103.48,101.83 102.84,101.19 82.09,101.19 80.31,102.97 v1(80.31,106.4)
  BOTTOM w0.147: R191.2 79.94,103.06 79.62,103.38 79.62,105.71 v1(80.31,106.4) 80.34,106.43 RA2.8
MCASP0_AFSX_R: length 9.6
  TOP w0.147: v1(77.06,93.09) 77.06,92.21 U136.M19
  BOTTOM w0.147: v1(77.06,93.09) 77.06,94.16 78.94,96.04 78.94,96.37 79.94,97.37 R191.1
MCASP0_AXR0: length 86.7
  TOP w0.147: v1(123.56,130.05) 122.8,130.05 121.25,131.6 121.25,138.25 121.78,138.78 J12.27
  L03_SIG1 w0.091: v1(123.56,130.05) 123.56,127.76 122.7,126.9 122.24,126.9 118.03,122.68 112.49,122.68 103.68,113.87 103.68,111.28 101.62,109.23 101.62,109.08 101.8,108.9 101.8,108.75 101.69,108.64 101.54,108.64 101.37,108.82 101.21,108.82 101.11,108.71 101.11,108.56 101.28,108.38 101.28,108.23 101.18,108.12 101.02,108.12 100.85,108.3 100.7,108.3 100.59,108.19 100.59,108.04 100.77,107.87 100.77,107.71 100.66,107.61 100.51,107.61 100.33,107.78 100.18,107.78 100.07,107.68 100.07,107.52 100.25,107.35 100.25,107.2 100.14,107.09 99.99,107.09 99.81,107.26 99.66,107.26 99.56,107.16 99.56,107.01 99.73,106.83 99.73,106.68 99.62,106.57 99.47,106.57 99.3,106.75 99.15,106.75 99.04,106.64 99.04,106.49 99.21,106.31 99.21,106.16 99.11,106.06 98.95,106.06 98.78,106.23 98.63,106.23 96.33,103.94 94.33,103.94 94.22,103.83 94.22,103.28 94.11,103.17 93.96,103.17 93.86,103.28 93.86,103.83 93.75,103.94 92.34,103.94 92.24,103.83 92.24,103.15 92.13,103.05 91.98,103.05 91.87,103.15 91.87,103.83 91.76,103.94 91.61,103.94 91.5,103.83 91.5,103.15 91.4,103.05 91.25,103.05 91.14,103.15 91.14,103.83 91.03,103.94 90.88,103.94 90.77,103.83 90.77,103.15 90.67,103.05 90.51,103.05 90.41,103.15 90.41,103.83 90.3,103.94 90.15,103.94 90.04,103.83 90.04,103.15 89.93,103.05 89.78,103.05 89.68,103.15 89.68,103.83 89.57,103.94 89.19,103.94 89.09,103.83 89.09,103.12 88.98,103.01 88.83,103.01 88.72,103.12 88.72,103.83 88.61,103.94 85.64,103.94 v1(83.53,106.05)
  BOTTOM w0.147: RA5.8 83.74,106.19 83.59,106.05 v1(83.53,106.05) 83.53,104.24 82.43,103.13 R176.2
MCASP0_AXR0_R: length 11.9
  TOP w0.147: U136.N17 v1(77.7,90.45)
  BOTTOM w0.132: 78.81,92.13 78.1,91.42 78.1,90.86 v1(77.7,90.45)
  BOTTOM w0.147: R176.1 82.43,97.27 79.98,94.82 79.98,94.59 78.81,93.42 78.81,92.13
MCASP0_AXR1: length 88.9
  TOP w0.147: J12.29 122.48,137.98 121.92,137.42 121.92,131.57 122.98,130.51 v1(125.06,130.51)
  L03_SIG1 w0.091: v1(81.25,105.38) 81.25,104.93 84.27,101.9 100.4,101.9 105.16,106.66 105.31,106.66 105.6,106.37 105.75,106.37 105.86,106.48 105.86,106.63 105.57,106.92 105.57,107.07 105.67,107.18 105.82,107.18 106.12,106.89 106.27,106.89 106.38,106.99 106.38,107.15 106.08,107.44 106.08,107.59 106.19,107.7 106.34,107.7 106.63,107.4 106.79,107.4 106.89,107.51 106.89,107.66 106.6,107.96 106.6,108.11 106.71,108.21 106.86,108.21 107.15,107.92 107.3,107.92 107.41,108.03 107.41,108.18 107.12,108.47 107.12,108.62 109.09,110.59 109.09,116.46 111.75,119.13 119.75,119.13 125.57,124.94 125.57,130 v1(125.06,130.51)
  BOTTOM w0.147: RA2.7 81.12,105.87 81.25,105.74 v1(81.25,105.38) 80.59,104.72 R499.2
MCASP0_AXR1_R: length 10.2
  TOP w0.147: U136.M16 v1(76.9,89.65)
  BOTTOM w0.132: v1(76.9,89.65) 77.29,90.05 77.29,92.72 77.61,93.04
  BOTTOM w0.147: R499.1 80.59,97.33 79.39,96.14 79.39,95.96 77.61,94.18 77.61,93.04
MCASP0_AXR2: length 88.1
  TOP w0.147: J12.28 131.52,138.78 133.16,137.13 v1(133.16,129.74)
  L03_SIG1 w0.091: v1(133.16,129.74) 130.85,132.05 125.37,132.05 124.64,131.32 124.64,126.34 120.36,122.07 112.79,122.07 107.38,116.66 107.38,113.51 96.11,102.23 85.41,102.23 v1(81.88,105.77)
  BOTTOM w0.147: R493.2 81.18,103.41 81.88,104.11 v1(81.88,105.77) 81.52,106.13 RA2.6
MCASP0_AXR2_R: length 10.6
  TOP w0.147: U136.N18 v1(77.7,91.26)
  BOTTOM w0.132: 77.97,93.04 77.97,91.98 77.7,91.7 v1(77.7,91.26)
  BOTTOM w0.147: R493.1 81.18,97.29 77.97,94.08 77.97,93.04
MCASP0_AXR3: length 89.6
  TOP w0.147: J12.30 128.43,137.98 v1(128.39,138.02)
  L03_SIG1 w0.091: v1(79.11,107.54) 79.44,107.54 79.54,107.44 90.82,107.44 94.51,111.13 94.66,111.13 95.49,110.3 95.64,110.3 95.75,110.41 95.75,110.56 94.92,111.39 94.92,111.54 95.03,111.65 95.18,111.65 96,110.82 96.16,110.82 96.26,110.93 96.26,111.08 95.44,111.9 95.44,112.06 95.54,112.16 95.7,112.16 96.52,111.34 96.67,111.34 96.78,111.44 96.78,111.6 95.95,112.42 95.95,112.57 96.23,112.85 98.67,112.85 108.4,122.58 108.4,127.72 110.52,129.84 111.18,129.84 111.29,129.95 111.29,130.3 111.4,130.41 111.55,130.41 111.65,130.3 111.65,129.95 111.76,129.84 111.91,129.84 112.02,129.95 112.02,130.3 112.13,130.41 112.28,130.41 112.39,130.3 112.39,129.95 112.49,129.84 112.64,129.84 112.75,129.95 112.75,130.3 112.86,130.41 113.01,130.41 113.12,130.3 113.12,129.95 113.22,129.84 113.38,129.84 113.48,129.95 113.48,130.3 113.59,130.41 113.74,130.41 113.85,130.3 113.85,129.95 113.96,129.84 114.11,129.84 114.21,129.95 114.21,130.3 114.32,130.41 114.47,130.41 114.58,130.3 114.58,129.95 114.69,129.84 114.84,129.84 114.95,129.95 114.95,130.3 115.05,130.41 115.2,130.41 115.31,130.3 115.31,129.95 115.42,129.84 116.25,129.84 122.41,136 126.37,136 v1(128.39,138.02)
  BOTTOM w0.147: R494.2 79.34,103.02 78.88,103.48 78.88,105.61 79.49,106.22 79.49,107.17 v1(79.11,107.54) 79.11,107.71 78.97,107.86 RA6.5
MCASP0_AXR3_R: length 8.8
  TOP w0.147: U136.M18 v1(76.9,91.26)
  BOTTOM w0.132: v1(76.9,91.26) 76.6,91.55 76.6,93.04
  BOTTOM w0.147: R494.1 78.63,97.79 78.48,97.64 78.48,96.04 76.6,94.16 76.6,93.04
MCASP0_AXR4: length 83.2
  TOP w0.147: v1(131.64,137.11) 131.57,137.18 J12.32
  L03_SIG1 w0.091: v1(88.41,106.43) 89.09,106.43 89.2,106.54 89.2,106.95 89.3,107.06 89.46,107.06 89.56,106.95 89.56,106.54 89.67,106.43 89.82,106.43 89.93,106.54 89.93,106.95 90.04,107.06 90.19,107.06 90.29,106.95 90.29,106.54 90.4,106.43 90.55,106.43 90.66,106.54 90.66,106.95 90.77,107.06 90.92,107.06 91.03,106.95 91.03,106.54 91.13,106.43 91.28,106.43 91.39,106.54 91.39,106.95 91.5,107.06 91.65,107.06 91.76,106.95 91.76,106.54 91.87,106.43 92.3,106.43 93.61,107.74 93.61,107.9 93.28,108.23 93.28,108.38 93.39,108.49 93.54,108.49 93.87,108.15 94.02,108.15 94.13,108.26 94.13,108.41 93.8,108.74 93.8,108.9 93.91,109 94.06,109 94.39,108.67 94.54,108.67 94.65,108.78 94.65,108.93 94.32,109.26 94.32,109.41 94.43,109.52 94.58,109.52 94.91,109.19 95.06,109.19 95.17,109.3 95.17,109.45 94.84,109.78 94.84,109.93 94.94,110.04 95.09,110.04 95.43,109.71 95.58,109.71 98.44,112.57 98.8,112.57 108.68,122.45 108.68,127.62 110.45,129.39 119.5,129.39 120.05,129.94 120.05,130.09 119.73,130.41 119.73,130.56 119.84,130.67 119.99,130.67 120.31,130.35 120.46,130.35 120.57,130.45 120.57,130.61 120.25,130.92 120.25,131.08 120.36,131.18 120.51,131.18 120.82,130.86 120.98,130.86 121.08,130.97 121.08,131.12 120.77,131.44 120.77,131.59 120.87,131.7 121.02,131.7 121.34,131.38 121.49,131.38 121.6,131.49 121.6,131.64 121.28,131.96 121.28,132.11 121.39,132.22 121.54,132.22 121.86,131.9 122.01,131.9 122.12,132.01 122.12,132.16 121.8,132.48 121.8,132.63 121.91,132.73 122.06,132.73 122.38,132.42 122.53,132.42 125.32,135.2 126.46,135.2 128.36,137.11 v1(131.64,137.11)
  BOTTOM w0.147: R495.2 86.81,102.16 88.41,103.76 v1(88.41,106.43) RA7.5
MCASP0_AXR4_R: length 15
  TOP w0.147: U136.N16 v1(77.7,89.65)
  BOTTOM w0.132: v1(77.7,89.65) 78.09,89.26 80.26,89.26 80.5,89.5 80.5,90.95 82.36,92.81
  BOTTOM w0.147: R495.1 86.81,96.52 84.9,94.61 84.09,94.61 82.36,92.89 82.36,92.81
MCASP0_AXR5: length 86.7
  TOP w0.147: J12.34 128.62,136.38 v1(128.34,136.09)
  L03_SIG1 w0.091: v1(128.34,136.09) 128.34,135.53 129.15,134.72 129.15,134.09 128.74,133.68 126.16,133.68 122.83,130.35 122.83,128.42 117.37,122.96 112.36,122.96 102.53,113.13 102.53,112.87 102.64,112.76 102.83,112.76 102.94,112.65 102.94,112.5 102.83,112.39 102.64,112.39 102.53,112.29 102.53,112.13 102.64,112.03 102.83,112.03 102.94,111.92 102.94,111.77 102.83,111.66 102.64,111.66 102.53,111.55 102.53,111 102.19,110.65 102.19,110.5 102.27,110.42 102.27,110.26 102.17,110.16 102.01,110.16 101.93,110.24 101.78,110.24 101.67,110.14 101.67,109.98 101.76,109.9 101.76,109.75 101.65,109.64 101.5,109.64 101.41,109.73 101.26,109.73 101.15,109.62 101.15,109.47 101.24,109.38 101.24,109.23 101.13,109.12 100.98,109.12 100.89,109.21 100.74,109.21 100.64,109.1 100.64,108.95 100.72,108.86 100.72,108.71 100.61,108.6 100.46,108.6 100.38,108.69 100.23,108.69 100.12,108.58 100.12,108.43 100.2,108.35 100.2,108.19 100.1,108.09 99.95,108.09 99.86,108.17 99.71,108.17 99.6,108.07 99.6,107.92 99.69,107.83 99.69,107.68 99.58,107.57 99.43,107.57 99.34,107.66 99.19,107.66 99.08,107.55 99.08,107.4 99.17,107.31 99.17,107.16 99.06,107.05 98.91,107.05 98.82,107.14 98.67,107.14 98.57,107.03 98.57,106.88 98.65,106.79 98.65,106.64 98.55,106.54 98.39,106.54 98.31,106.62 98.16,106.62 98.05,106.51 98.05,106.36 98.14,106.28 98.14,106.13 98.03,106.02 97.88,106.02 97.79,106.1 97.64,106.1 97.53,106 97.53,105.85 97.62,105.76 97.62,105.61 97.51,105.5 97.36,105.5 97.27,105.59 97.12,105.59 97.01,105.48 97.01,105.33 97.1,105.24 97.1,105.09 96.99,104.98 96.84,104.98 96.76,105.07 96.6,105.07 96.5,104.96 96.5,104.81 96.58,104.73 96.58,104.57 96.48,104.47 96.32,104.47 96.24,104.55 96.09,104.55 95.8,104.27 95.4,104.27 95.29,104.37 95.29,104.68 95.18,104.79 95.03,104.79 94.92,104.68 94.92,104.37 94.82,104.27 94.66,104.27 94.56,104.37 94.56,104.68 94.45,104.79 94.3,104.79 94.19,104.68 94.19,104.37 94.08,104.27 93.93,104.27 93.83,104.37 93.83,104.68 93.72,104.79 93.57,104.79 93.46,104.68 93.46,104.37 93.35,104.27 93.2,104.27 93.09,104.37 93.09,104.68 92.99,104.79 92.84,104.79 92.73,104.68 92.73,104.37 92.62,104.27 92.47,104.27 92.36,104.37 92.36,104.68 92.26,104.79 92.1,104.79 92,104.68 92,104.37 91.89,104.27 91.74,104.27 91.63,104.37 91.63,104.68 91.52,104.79 91.37,104.79 91.27,104.68 91.27,104.37 91.16,104.27 91.01,104.27 90.9,104.37 90.9,104.68 90.79,104.79 90.64,104.79 90.53,104.68 90.53,104.37 90.43,104.27 90.28,104.27 90.17,104.37 90.17,104.68 90.06,104.79 89.91,104.79 89.8,104.68 89.8,104.37 89.7,104.27 89.54,104.27 89.44,104.37 89.44,104.68 89.33,104.79 89.18,104.79 89.07,104.68 89.07,104.37 88.96,104.27 88.81,104.27 88.7,104.37 88.7,104.68 88.6,104.79 88.45,104.79 88.34,104.68 88.34,104.37 88.23,104.27 88.08,104.27 87.97,104.37 87.97,104.68 87.87,104.79 87.71,104.79 87.61,104.68 87.61,104.37 87.5,104.27 87.35,104.27 87.24,104.37 87.24,104.68 87.13,104.79 86.98,104.79 86.88,104.68 86.88,104.44 86.78,104.35 86.66,104.35 85.89,105.11 85.74,105.11 85.44,104.82 85.29,104.82 85.19,104.93 85.19,105.08 85.48,105.37 85.48,105.52 85.31,105.69 v1(84.68,105.69)
  BOTTOM w0.147: RA5.6 84.54,106.13 84.68,105.99 v1(84.68,105.69) 84.68,103.81 83.73,102.86 R492.2
MCASP0_AXR5_R: length 12.1
  TOP w0.147: U136.P17 v1(78.5,90.45)
  BOTTOM w0.132: v1(78.5,90.45) 78.5,90.67 78.91,91.08 78.91,91.29 79.55,91.92
  BOTTOM w0.147: R492.1 83.73,97.35 79.55,93.17 79.55,91.92
MCASP0_AXR6_R: length 9
  TOP w0.147: U136.P18 v1(78.5,91.26)
  BOTTOM w0.132: 79.14,91.9 v1(78.5,91.26)
  BOTTOM w0.147: R5718.1 83.08,97.23 79.14,93.29 79.14,91.9
MCASP0_AXR7: length 90.9
  TOP w0.147: v1(132.12,133.17) 132.12,134.49 131.84,134.78 J12.38
  L03_SIG1 w0.091: v1(132.12,133.17) 131.89,133.4 126.27,133.4 124.15,131.28 124.15,127.25 119.25,122.35 112.67,122.35 107.1,116.79 107.1,113.67 98.93,105.49 98.78,105.49 98.64,105.63 98.48,105.63 98.38,105.52 98.38,105.37 98.52,105.23 98.52,105.08 98.41,104.97 98.26,104.97 98.12,105.11 97.97,105.11 97.86,105 97.86,104.85 98,104.71 98,104.56 97.89,104.45 97.74,104.45 97.6,104.59 97.45,104.59 97.34,104.49 97.34,104.34 97.48,104.19 97.48,104.04 97.38,103.94 97.22,103.94 97.08,104.08 96.93,104.08 96.82,103.97 96.82,103.82 96.97,103.68 96.97,103.53 96.86,103.42 96.71,103.42 96.57,103.56 96.41,103.56 96.31,103.45 96.31,103.3 96.45,103.16 96.45,103.01 96.11,102.67 95.19,102.67 95.08,102.77 95.08,103.35 94.97,103.45 94.82,103.45 94.71,103.35 94.71,102.77 94.61,102.67 88.57,102.67 88.23,103 88.23,103.55 88.13,103.66 87.97,103.66 87.87,103.55 87.87,103 87.76,102.9 87.61,102.9 87.5,103 87.5,103.55 87.39,103.66 87.24,103.66 87.14,103.55 87.14,103 87.03,102.9 86.88,102.9 86.77,103 86.77,103.55 86.66,103.66 86.51,103.66 86.4,103.55 86.4,103 86.3,102.9 86.15,102.9 86.04,103 86.04,103.55 85.93,103.66 85.13,103.66 84.63,104.17 84.47,104.17 84.25,103.94 84.1,103.94 83.99,104.05 83.99,104.2 84.22,104.42 84.22,104.58 84.11,104.68 83.96,104.68 83.73,104.46 83.58,104.46 83.47,104.56 83.47,104.72 83.7,104.94 83.7,105.09 83.59,105.2 83.44,105.2 83.21,104.97 83.06,104.97 82.95,105.08 82.95,105.23 83.18,105.46 83.18,105.61 v1(82.54,106.25)
  BOTTOM w0.147: R177.2 81.83,103.23 82.54,103.94 v1(82.54,106.25) 82.36,106.25 82.18,106.43 RA2.5
MCASP0_AXR7_R: length 7.7
  TOP w0.147: v1(78.91,94.28) 78.1,93.47 U136.P19
  BOTTOM w0.147: v1(78.91,94.28) 81.12,96.49 81.12,96.6 81.83,97.31 R177.1
MCASP0_AXR8_R: length 11.2
  TOP w0.147: U136.P16 v1(78.5,89.65)
  BOTTOM w0.132: v1(78.5,89.65) 78.9,90.06 78.9,90.69 79.19,90.98 79.19,91.19 79.95,91.95 79.95,93.04 80.77,93.86
  BOTTOM w0.147: 80.77,93.86 80.84,93.86 84.32,97.34 R5719.1
MCASP0_AXR9: length 85.6
  TOP w0.147: v1(128.24,134.32) 128.24,134.26 128.52,133.98 J12.40
  L03_SIG1 w0.091: v1(86.35,106.4) 86.35,105.33 86.62,105.06 96.07,105.06 96.63,105.63 96.63,105.78 96.19,106.23 96.19,106.38 96.3,106.49 96.45,106.49 96.89,106.04 97.04,106.04 97.15,106.15 97.15,106.3 96.71,106.75 96.71,106.9 96.81,107.01 96.96,107.01 97.41,106.56 97.56,106.56 97.67,106.67 97.67,106.82 97.22,107.26 97.22,107.42 97.33,107.52 97.48,107.52 97.93,107.08 98.08,107.08 98.19,107.18 98.19,107.34 97.74,107.78 97.74,107.93 97.85,108.04 98,108.04 98.44,107.59 98.6,107.59 98.7,107.7 98.7,107.85 98.26,108.3 98.26,108.45 98.36,108.56 98.52,108.56 98.96,108.11 99.11,108.11 99.22,108.22 99.22,108.37 98.77,108.82 98.77,108.97 98.88,109.07 99.03,109.07 99.48,108.63 99.63,108.63 99.74,108.74 99.74,108.89 99.29,109.33 99.29,109.48 99.4,109.59 99.55,109.59 100,109.15 100.15,109.15 100.25,109.25 100.25,109.41 99.81,109.85 99.81,110 99.92,110.11 100.07,110.11 100.51,109.66 100.66,109.66 100.77,109.77 100.77,109.92 100.33,110.37 100.33,110.52 100.43,110.63 100.59,110.63 101.03,110.18 101.18,110.18 101.29,110.29 101.29,110.44 100.84,110.89 100.84,111.04 100.95,111.14 101.1,111.14 101.55,110.7 101.7,110.7 102.25,111.25 102.25,113.26 112.23,123.24 117.24,123.24 117.88,123.88 117.88,124.03 117.59,124.33 117.59,124.48 117.7,124.59 117.85,124.59 118.14,124.29 118.29,124.29 118.4,124.4 118.4,124.55 118.11,124.85 118.11,125 118.21,125.1 118.36,125.1 118.66,124.81 118.81,124.81 118.92,124.92 118.92,125.07 118.62,125.36 118.62,125.51 118.73,125.62 118.88,125.62 119.17,125.33 119.33,125.33 119.43,125.44 119.43,125.59 119.14,125.88 119.14,126.03 119.25,126.14 119.4,126.14 119.69,125.85 119.84,125.85 119.95,125.95 119.95,126.1 119.66,126.4 119.66,126.55 119.76,126.66 119.92,126.66 120.21,126.36 120.36,126.36 122.37,128.37 122.37,130.45 126.23,134.32 v1(128.24,134.32)
  BOTTOM w0.147: RA7.8 86.38,106.43 v1(86.35,106.4) 86.35,104.11 84.97,102.73 R491.2
MCASP0_AXR9_R: length 12.8
  TOP w0.147: v1(79.3,90.46) U136.R17
  BOTTOM w0.132: 81.14,93.69 80.23,92.79 80.23,91.85 79.47,91.08 79.47,90.88 79.3,90.71 v1(79.3,90.46)
  BOTTOM w0.147: 81.14,93.69 83.43,95.99 84.29,95.99 84.97,96.66 R491.1
MCASP1_ACLKR_R: length 6.9
  TOP w0.132: 80.27,93.04 80.09,92.86 80.09,91.25 U136.T18
  TOP w0.147: 80.27,93.04 80.4,93.17 80.4,95.06 79.07,96.39 R179.2
MCASP1_ACLKX_R: length 6.1
  TOP w0.147: R5646.2 75.34,95.71 73.3,93.68 U136.H19
MCASP1_AFSR_R: length 8.2
  TOP w0.132: U136.T19 79.7,93.04 79.7,93.04
  TOP w0.147: R5640.1 78.48,96.49 80.05,94.92 80.05,93.39 79.7,93.04
MCASP1_AFSX_R: length 7.4
  TOP w0.147: U136.J17 v1(73.7,90.45)
  BOTTOM w0.132: v1(73.7,90.45) 73.17,90.98 73.17,91.72 72.31,92.58
  BOTTOM w0.147: R5647.1 72.41,96.24 72.31,96.14 72.31,92.58
MCASP1_AXR0_R: length 8.5
  TOP w0.147: U136.J18 v1(73.7,91.26)
  BOTTOM w0.132: 73.07,92.33 73.7,91.7 v1(73.7,91.26)
  BOTTOM w0.147: R500.1 73,96.28 72.74,96.01 72.74,92.66 73.07,92.33
MCASP1_AXR1_R: length 8.4
  TOP w0.147: U136.J19 74.1,92.06 73.78,92.38 73.78,93.42 75.93,95.57 R5645.1
MCASP1_AXR2_R: length 9
  TOP w0.147: U136.J16 v1(73.7,89.65)
  BOTTOM w0.132: 71.57,93.78 71.57,92.25 72.49,91.33 72.49,90.3 72.74,90.05 73.3,90.05 v1(73.7,89.65)
  BOTTOM w0.147: 71.57,93.78 71.57,95.25 71.16,95.66 R190.1
MCASP2_ACLKR: length 81.6
  TOP w0.147: J13.43 27.13,138.04 30.62,134.54 32.89,134.54 33.49,133.93 33.49,124.28 31.06,121.84 v1(28.82,121.84)
  BOTTOM w0.147: R5669.1 70.53,100.33 69.44,101.42 68.9,101.42 67.35,102.97 66.16,102.97 65.45,103.68 64.41,103.68 61.1,106.98 61.1,107.52 58.31,110.31 53.61,110.31 51.61,112.32 51.61,114.96 51.5,115.06 51.5,115.07 49.15,117.42 44.92,117.42 42.97,119.38 30.14,119.38 28.57,120.95 28.57,121.59 v1(28.82,121.84)
MCASP2_ACLKR_R: length 9.4
  TOP w0.147: U136.G17 v1(72.1,90.45)
  BOTTOM w0.132: v1(72.1,90.45) 72.1,91.22 71.65,91.67
  BOTTOM w0.147: R5669.2 70.53,95.66 71.19,95 71.19,92.13 71.65,91.67
MCASP2_ACLKX: length 82.8
  TOP w0.147: J13.37 24.34,131.64 24.92,131.06 25.32,131.06 25.52,131.27 25.52,133 25.69,133.17 28.19,133.17 28.34,133.02 28.34,132.51 27.78,131.95 26.74,131.95 v1(26.13,131.34)
  BOTTOM w0.147: R5668.1 78.02,103.76 75.71,106.07 75.71,110.36 74.97,111.1 73.86,111.1 73.14,111.81 73.14,112.9 70.43,115.62 70.05,115.62 67.63,118.03 58.34,118.03 57.93,118.44 56.63,118.44 51.94,123.14 48.96,123.14 46.04,126.06 40.56,126.06 39.39,127.23 28.85,127.23 28.03,128.05 27.79,128.05 27.66,127.92 27.41,127.92 27.24,128.09 27.24,128.34 27.37,128.46 27.37,128.71 26.13,129.95 v1(26.13,131.34)
MCASP2_ACLKX_R: length 8
  TOP w0.147: U136.L19 v1(76.1,92.06)
  BOTTOM w0.147: R5668.2 78.02,96.16 76.1,94.24 v1(76.1,92.06)
MCASP2_AFSR: length 82.3
  TOP w0.147: v1(27.2,121.64) 28.19,122.63 30.45,122.63 32.78,124.97 32.78,131.65 27.19,137.24 J13.41
  BOTTOM w0.147: v1(27.2,121.64) 27.2,121.13 29.96,118.36 43.35,118.36 44.85,116.87 49.07,116.87 51.15,114.78 51.15,112.14 53.43,109.86 58.01,109.86 60.32,107.54 60.32,106.68 63.77,103.23 65.12,103.23 67.38,100.97 69.26,100.97 69.92,100.3 R5667.2
MCASP2_AFSR_R: length 8.5
  TOP w0.147: U136.G16 v1(72.1,89.65)
  BOTTOM w0.147: R5667.1 69.92,95.63 70.73,94.82 70.73,91.19 72.1,89.82 v1(72.1,89.65)
MCASP2_AFSX: length 83.3
  TOP w0.147: v1(30.85,124.82) 32.07,126.03 32.07,127.61 31.9,127.79 31.53,127.79 31.34,127.99 31.34,128.23 31.48,128.38 31.9,128.38 32.07,128.55 32.07,128.79 31.9,128.97 31.53,128.97 31.34,129.16 31.34,129.41 31.48,129.55 31.9,129.55 32.07,129.73 32.07,129.97 31.9,130.14 31.53,130.14 31.34,130.34 31.34,130.59 31.48,130.73 31.9,130.73 32.07,130.91 32.07,131.72 28.87,134.92 26.82,134.92 24.34,132.44 J13.39
  BOTTOM w0.147: v1(30.85,124.82) 37.99,124.82 38.63,124.18 45.38,124.18 45.75,123.82 45.75,123.57 45.39,123.21 45.39,122.97 45.56,122.8 45.81,122.8 46.16,123.15 46.41,123.15 48.25,121.31 49.98,121.31 54.81,116.48 57.02,116.48 57.98,115.52 67.61,115.52 69.33,113.79 69.72,113.79 71.24,112.27 71.24,111.05 73.88,108.41 73.88,105.36 75.53,103.71 R5666.2
MCASP2_AFSX_R: length 7.6
  TOP w0.147: U136.K19 74.54,92.01 v1(74.54,92.86)
  BOTTOM w0.132: 74.54,93.21 v1(74.54,92.86)
  BOTTOM w0.147: R5666.1 75.53,96.27 74.54,95.28 74.54,93.21
MCASP2_AXR0: length 83
  TOP w0.147: J13.27 25.21,127.64 v1(26.21,126.64)
  BOTTOM w0.147: R5660.2 76.14,103.73 74.34,105.54 74.34,108.58 71.7,111.23 71.7,112.45 69.89,114.25 69.51,114.25 67.1,116.66 66.17,116.66 66,116.49 66,116.13 65.82,115.96 65.58,115.96 65.41,116.13 65.41,116.49 65.24,116.66 64.99,116.66 64.82,116.49 64.82,116.13 64.65,115.96 64.4,115.96 64.23,116.13 64.23,116.49 64.06,116.66 63.81,116.66 63.64,116.49 63.64,116.13 63.47,115.96 63.22,115.96 63.05,116.13 63.05,116.49 62.88,116.66 62.63,116.66 62.46,116.49 62.46,116.13 62.29,115.96 62.04,115.96 61.87,116.13 61.87,116.49 61.7,116.66 61.46,116.66 61.28,116.49 61.28,116.13 61.11,115.96 60.87,115.96 60.69,116.13 60.69,116.49 60.52,116.66 60.28,116.66 60.1,116.49 60.1,116.13 59.93,115.96 59.69,115.96 59.51,116.13 59.51,116.49 59.34,116.66 59.1,116.66 58.93,116.49 58.93,116.13 58.75,115.96 58.51,115.96 58.34,116.13 58.34,116.49 58.16,116.66 57.47,116.66 57.19,116.94 54.98,116.94 50.16,121.77 48.43,121.77 45.51,124.69 40.02,124.69 39.16,125.55 28.97,125.55 28.67,125.86 27.59,125.86 25.77,127.68 24.79,127.68 24.5,127.38 24.5,127.17 24.64,127.02 25.83,127.02 v1(26.21,126.64)
MCASP2_AXR0_R: length 8
  TOP w0.147: U136.L17 v1(76.1,90.45)
  BOTTOM w0.147: v1(76.1,90.45) 75.74,90.45 75.23,90.97 75.23,91.49 74.95,91.77 74.95,92.68 75.02,92.76 75.02,95.12 76.14,96.24 R5660.1
MCASP2_AXR1: length 82.8
  TOP w0.147: J13.29 25.22,128.44 26.79,126.87 v1(26.79,124.49)
  BOTTOM w0.147: R5661.2 73.65,103.68 72.51,104.83 72.51,107.87 69.87,110.52 69.87,111.73 69.18,112.42 67.33,112.42 66.34,113.41 58.18,113.41 56.48,115.11 54.27,115.11 49.45,119.94 45.71,119.94 43.73,121.92 43.01,121.92 42.84,122.09 42.84,122.42 42.67,122.59 42.42,122.59 42.25,122.42 42.25,122.09 42.08,121.92 41.83,121.92 41.66,122.09 41.66,122.42 41.49,122.59 41.24,122.59 41.07,122.42 41.07,122.09 40.9,121.92 40.65,121.92 40.48,122.09 40.48,122.42 40.31,122.59 40.06,122.59 39.89,122.42 39.89,122.09 39.72,121.92 39.47,121.92 39.3,122.09 39.3,122.42 39.13,122.59 38.89,122.59 38.71,122.42 38.71,122.09 38.54,121.92 36.91,121.92 36.73,122.09 36.73,123.13 36.56,123.31 36.32,123.31 36.15,123.13 36.15,122.09 35.97,121.92 35.73,121.92 35.56,122.09 35.56,123.13 35.38,123.31 35.14,123.31 34.97,123.13 34.97,122.09 34.79,121.92 34.55,121.92 34.38,122.09 34.38,123.13 34.21,123.31 33.96,123.31 33.79,123.13 33.79,122.09 33.62,121.92 33.32,121.92 32.73,122.5 31.37,122.5 31.2,122.68 31.2,123.13 31.03,123.31 30.78,123.31 30.61,123.13 30.61,122.68 30.44,122.5 30.12,122.5 28.14,124.49 v1(26.79,124.49)
MCASP2_AXR1_R: length 8.4
  TOP w0.147: U136.K16 v1(74.5,89.65)
  BOTTOM w0.132: 73.45,92.43 74.09,91.79 74.09,90.06 v1(74.5,89.65)
  BOTTOM w0.147: 73.45,92.43 73.14,92.74 73.14,95.74 73.65,96.24 R5661.1
MCASP2_AXR2: length 84.2
  TOP w0.147: v1(19.42,130.84) 19.42,129.52 19.63,129.31 19.63,127.89 19.38,127.64 J13.28
  BOTTOM w0.147: v1(19.42,130.84) 20.34,131.75 22.5,131.75 23.94,130.3 24.81,130.3 25.6,129.51 25.6,129.11 27.94,126.77 29.02,126.77 29.29,126.51 39.47,126.51 40.38,125.6 45.86,125.6 48.79,122.68 50.51,122.68 55.21,117.98 57.75,117.98 58.16,117.58 67.45,117.58 69.87,115.16 70.25,115.16 72.61,112.8 72.61,111.58 75.25,108.94 75.25,105.89 77.39,103.76 R5662.2
MCASP2_AXR2_R: length 6.9
  TOP w0.147: U136.L18 v1(76.1,91.26)
  BOTTOM w0.147: v1(76.1,91.26) 75.85,91.5 75.85,91.71 75.63,91.92 75.63,93.07 75.79,93.22 75.79,94.49 77.39,96.09 R5662.1
MCASP2_AXR3: length 82.5
  TOP w0.147: v1(18.84,128.17) 18.57,128.44 J13.30
  BOTTOM w0.147: v1(18.84,128.17) 18.84,127.36 19.41,126.79 19.65,126.79 21,128.14 21.21,128.14 21.42,127.93 21.42,127.72 20.07,126.37 20.07,126.13 20.24,125.95 20.56,125.95 21.89,127.28 22.14,127.28 22.31,127.11 22.31,126.87 20.92,125.48 20.92,125.27 21.25,124.94 28.31,124.94 29.51,123.75 37.79,123.75 38.27,123.27 43.1,123.27 45.97,120.4 49.62,120.4 54.45,115.57 56.66,115.57 58.36,113.87 66.92,113.87 67.91,112.88 69.36,112.88 70.32,111.91 70.32,110.69 72.97,108.05 72.97,105 74.25,103.72 R5663.2
MCASP2_AXR3_R: length 8.6
  TOP w0.147: U136.K18 v1(74.5,91.26)
  BOTTOM w0.147: R5663.1 74.25,96.15 73.55,95.45 73.55,92.81 74.39,91.97 74.39,91.36 v1(74.5,91.26)
MCASP2_AXR4: length 82.3
  TOP w0.147: J13.32 18.73,129.24 v1(18.99,128.98)
  BOTTOM w0.147: v1(18.99,128.98) 18.56,128.98 17.98,129.57 17.98,131.04 18.12,131.19 18.36,131.19 18.51,131.04 18.51,130.31 19.84,128.98 21.61,128.98 23.75,126.84 23.75,126.08 24.43,125.4 28.49,125.4 29.68,124.21 37.97,124.21 38.45,123.72 44.01,123.72 46.88,120.85 49.8,120.85 54.63,116.03 56.84,116.03 57.8,115.06 67.43,115.06 69.16,113.33 69.54,113.33 70.78,112.09 70.78,110.87 73.42,108.23 73.42,105.18 74.9,103.71 R5664.2
MCASP2_AXR4_R: length 8.9
  TOP w0.147: U136.L16 v1(76.1,89.65)
  BOTTOM w0.132: v1(76.1,89.65) 74.9,90.85 74.9,91.44 74.67,91.67 74.67,92.13 74.08,92.71
  BOTTOM w0.147: 74.08,92.71 73.98,92.81 73.98,95.33 74.9,96.24 R5664.1
MCASP2_AXR5: length 80.8
  TOP w0.147: v1(18.97,131.67) 18.97,131.32 18.97,131.32 18.97,130.25 18.76,130.04 J13.34
  BOTTOM w0.147: v1(18.97,131.67) 18.97,130.48 19.6,129.84 23.44,129.84 23.75,129.53 23.75,129.33 23.48,129.06 23.48,128.81 23.65,128.64 23.89,128.64 24.12,128.87 24.41,128.87 25.16,128.12 25.95,128.12 27.75,126.31 28.85,126.31 29.15,126.01 39.34,126.01 40.2,125.15 45.69,125.15 48.61,122.22 50.34,122.22 55.16,117.4 57.37,117.4 57.65,117.12 67.28,117.12 69.69,114.71 70.07,114.71 72.15,112.62 72.15,111.4 74.8,108.76 74.8,105.71 76.74,103.77 R5665.2
MCASP2_AXR5_R: length 10.3
  TOP w0.147: U136.M17 v1(76.9,90.45)
  BOTTOM w0.132: 76.5,90.85 75.94,90.85 75.51,91.29 75.51,91.59 75.3,91.8 75.3,93.04
  BOTTOM w0.147: 76.5,90.85 v1(76.9,90.45) ; 75.3,93.04 75.3,93.24 75.42,93.36 75.42,94.96 76.74,96.28 R5665.1
MCASP3_ACLKR: length 111.1
  TOP w0.147: v1(72.31,114.55) 71.62,113.87 71.62,112.65 72.08,112.19 72.08,110.24 72.43,109.88 72.43,103.78 71.67,103.02 71.67,102.62 72.05,102.23 72.05,101.45 71.26,100.66 71.26,98.53 70.19,97.45 R5683.1 ; J13.78 18.82,151.64 19.47,152.3 v1(19.47,153.42)
  BOTTOM w0.147: v1(19.47,153.42) 19.75,153.14 21.63,153.14 22.93,151.84 22.93,146.15 22.22,145.44 22.22,143.71 22.39,143.54 22.81,143.54 22.95,143.39 22.95,143.1 22.81,142.95 22.39,142.95 22.22,142.78 22.22,142.53 22.39,142.36 22.91,142.36 23.08,142.19 23.08,141.94 22.91,141.77 22.39,141.77 22.22,141.6 22.22,135.48 25.44,132.26 26.51,132.26 27.04,131.72 27.04,130.3 29.2,128.14 40.45,128.14 41.62,126.97 52.34,126.97 53.33,125.98 53.94,125.98 54.42,125.5 54.42,122.02 57.09,119.35 58.29,119.35 58.69,118.95 66.49,118.95 67.23,119.68 70.88,119.68 71.75,118.82 71.75,116.56 72.31,116 v1(72.31,114.55)
MCASP3_ACLKX: length 108
  TOP w0.147: v1(21.07,151.92) 21.35,151.64 J13.77
  BOTTOM w0.147: R5677.1 65.94,99.63 61.23,104.34 50.49,104.34 47.98,101.84 43.06,101.84 41.93,102.97 32.8,102.97 16.35,119.42 16.35,133.88 17.14,134.67 17.14,135.76 16.88,136.02 15.54,136.02 12.92,138.63 12.92,149.99 13.51,150.57 14.72,150.57 15.35,149.94 15.35,149.35 15.53,149.17 15.77,149.17 15.94,149.35 15.94,149.94 16.12,150.11 19.02,150.11 20.57,151.67 20.82,151.67 v1(21.07,151.92)
MCASP3_AFSR: length 108.4
  TOP w0.147: v1(70.53,119.2) 70.53,118.01 70.02,117.5 70.02,112.98 71.16,111.84 71.16,109.88 71.52,109.52 71.52,105.54 70.12,104.14 70.12,102.11 67.64,99.62 R5682.2 ; v1(18.96,152.44) J13.80
  BOTTOM w0.147: v1(18.96,152.44) 21.41,152.44 22.27,151.59 22.27,146.51 21.15,145.39 21.15,133.88 23.84,131.19 25.09,131.19 25.7,131.8 26.31,131.8 26.59,131.53 26.59,130.12 29.02,127.69 39.74,127.69 40.91,126.52 52.11,126.52 53.1,125.53 53.76,125.53 53.94,125.35 53.94,121.87 56.91,118.9 58.11,118.9 58.51,118.49 67.81,118.49 68.18,118.13 68.38,118.13 69.46,119.2 v1(70.53,119.2)
MCASP3_AFSX: length 110.3
  TOP w0.147: v1(24.91,152.78) 24.57,152.44 J13.79 ; R5676.2 74.09,100.77 74.26,100.94 74.26,110.79 v1(75.02,111.56)
  BOTTOM w0.147: v1(75.02,111.56) 74.03,111.56 73.6,111.99 73.6,118.31 71.32,120.6 66.72,120.6 65.98,119.86 59.12,119.86 58.64,120.35 57.78,120.35 55.34,122.78 55.34,125.86 54.3,126.9 53.69,126.9 52.7,127.89 42.79,127.89 41.62,129.06 29.56,129.06 27.96,130.66 27.96,132.08 26.87,133.17 25.8,133.17 23.7,135.27 23.7,138.31 30.57,145.19 30.57,148.18 29.63,149.12 24.78,149.12 24.2,149.71 24.2,151.21 24.91,151.92 v1(24.91,152.78)
MCASP3_AXR0: length 107.6
  TOP w0.147: v1(73.04,114.33) 75.07,114.33 75.79,113.61 75.79,112.8 75.25,112.27 74.31,112.27 73.45,111.4 73.45,110.77 73.8,110.41 73.8,101.3 73.44,100.93 R5672.2 ; v1(25.24,148.06) 24.83,147.64 J13.67
  BOTTOM w0.147: v1(25.24,148.06) 25.67,148.49 26.27,148.49 26.44,148.32 26.44,147.57 26.61,147.4 26.86,147.4 27.03,147.57 27.03,148.32 27.2,148.49 29.05,148.49 29.81,147.73 29.81,145.06 22.78,138.02 22.78,135.56 25.62,132.72 26.69,132.72 27.5,131.9 27.5,130.48 29.38,128.6 41.14,128.6 42.31,127.43 52.52,127.43 53.51,126.44 54.12,126.44 54.88,125.68 54.88,122.2 57.27,119.81 58.46,119.81 58.87,119.41 66.16,119.41 66.9,120.14 71.14,120.14 73.04,118.24 v1(73.04,114.33)
MCASP3_AXR1: length 104.3
  TOP w0.147: v1(21.25,148.21) 21.49,148.44 J13.69
  BOTTOM w0.147: R5673.2 69.32,100.16 68.98,100.51 67.15,100.51 64.89,102.77 63.59,102.77 61.54,104.83 48.77,104.83 46.29,102.34 43.24,102.34 42.72,102.87 42.72,103.92 41.73,104.9 31.81,104.9 16.96,119.75 16.96,133.55 17.59,134.19 17.59,135.96 16.25,137.3 16.25,147.93 17.62,149.3 19.07,149.3 20.85,151.08 21.46,151.08 21.81,150.72 21.81,148.77 v1(21.25,148.21)
MCASP3_AXR2: length 107.5
  TOP w0.147: R5674.2 74.74,110.41 75.68,111.35 v1(75.68,111.89) ; v1(25.77,149.73) 25.28,149.24 J13.71
  BOTTOM w0.147: v1(75.68,111.89) 75.4,111.89 75.25,112.04 74.59,112.04 74.06,112.57 74.06,118.59 71.44,121.21 65.75,121.21 65.37,120.83 61.05,120.83 59.73,122.15 58.46,122.15 56.15,124.46 56.15,126.39 53.94,128.6 44.95,128.6 43.55,130 29.63,130 28.67,130.96 28.67,133.25 27.6,134.32 25.47,134.32 24.71,135.08 24.71,138.56 31.44,145.29 31.44,148.82 28.41,151.84 26.08,151.84 25.77,151.54 v1(25.77,149.73)
MCASP3_AXR3: length 107.1
  TOP w0.147: J13.73 21.28,150.04 21.05,150.27 v1(21.05,150.62)
  BOTTOM w0.147: v1(21.05,150.62) 21.05,149.17 20.19,148.31 19.95,148.31 19.69,148.57 19.45,148.57 19.28,148.39 19.28,148.15 19.53,147.9 19.53,147.65 19.36,147.48 19.11,147.48 18.86,147.73 18.62,147.73 18.44,147.56 18.44,147.32 18.7,147.06 18.7,146.82 18.52,146.65 18.28,146.65 18.03,146.9 17.78,146.9 17.61,146.73 17.61,146.48 17.86,146.23 17.86,145.99 17.44,145.57 17.44,143.69 18.05,143.08 18.05,133.88 17.44,133.27 17.44,125.04 18.81,123.67 27.93,123.67 31.77,119.84 32.5,119.84 32.67,120.01 32.67,120.35 32.84,120.52 33.09,120.52 33.26,120.35 33.26,120.01 33.43,119.84 33.68,119.84 33.85,120.01 33.85,120.35 34.02,120.52 34.27,120.52 34.44,120.35 34.44,120.01 34.61,119.84 34.86,119.84 35.03,120.01 35.03,120.35 35.2,120.52 35.45,120.52 35.62,120.35 35.62,120.01 35.79,119.84 36.03,119.84 36.21,120.01 36.21,120.35 36.38,120.52 36.62,120.52 36.8,120.35 36.8,120.01 36.97,119.84 37.21,119.84 37.39,120.01 37.39,120.35 37.56,120.52 37.8,120.52 37.97,120.35 37.97,120.01 38.15,119.84 38.39,119.84 38.56,120.01 38.56,120.5 38.71,120.65 38.96,120.65 39.13,120.48 39.13,120.04 39.33,119.84 43.15,119.84 45.1,117.88 49.57,117.88 52.06,115.39 52.06,112.5 53.79,110.77 59.12,110.77 66.01,103.89 66.72,103.89 67.12,103.48 67.56,103.48 68.47,102.57 71.5,102.57 71.77,102.29 R5675.2
MCASP4_ACLKR: length 32.7
  TOP w0.147: J12.78 128.6,114.78 128.39,114.99 128.39,122.1 v1(128.07,122.42)
  BOTTOM w0.147: v1(128.07,122.42) 123.27,122.42 117.16,116.31 117.16,115.19 116.04,114.07 116.04,113.82 116.54,113.32 116.54,113.07 116.37,112.9 116.13,112.9 115.62,113.4 115.38,113.4 115.13,113.16 113.28,113.16 112.75,112.63 U3072.54
MCASP4_ACLKR_FET: length 69
  TOP w0.147: v1(78.48,107.14) 78.02,106.68 78.02,106.15 77.83,105.95 77.83,98.67 77.83,98.66 R5651.1
  BOTTOM w0.147: RA6.6 78.22,107.39 v1(78.48,107.14) 78.48,106.05 78.17,105.74 76.67,105.74 76.17,106.25 76.17,110.26 76.34,110.44 76.34,111.91 75.74,112.52 74.85,112.52 74.52,112.85 74.52,115.09 75.35,115.93 75.58,115.93 75.63,115.98 77.67,115.98 77.79,115.85 93.92,115.85 99.99,109.78 104.31,109.78 107.71,106.38 111.29,106.38 113.25,104.41 U3072.2
MCASP4_ACLKR_HDR: length 19
  BOTTOM w0.147: J28.3 108.41,125.79 108.41,127.82 109.14,128.55 110.38,128.55 111.17,127.76 111.17,126.8 112.17,125.79 114.23,125.79 114.85,125.17 114.85,124.57 111.22,120.94 U2345.20
MCASP4_ACLKR_LT: length 3.7
  BOTTOM w0.147: U2345.1 111.22,113.18 112.25,112.15 U3072.53
MCASP4_ACLKR_R: length 7.5
  TOP w0.132: U136.R18 79.29,91.25 79.29,93.32
  TOP w0.147: 79.29,93.32 79.7,93.73 79.7,94.63 78.55,95.78 78.07,95.78 77.83,96.03 R5651.2
MCASP4_ACLKX: length 32.2
  TOP w0.147: v1(123.13,112.39) 122.32,112.39 122.09,112.62 122.09,114.25 122.62,114.78 J12.77
  BOTTOM w0.147: U3072.39 105.25,109.88 108.09,107.04 122.62,107.04 124.71,109.12 124.71,111.63 123.94,112.39 v1(123.13,112.39)
MCASP4_ACLKX_FET: length 70.1
  TOP w0.147: v1(75.05,113.69) 72.94,113.69 72.53,113.28 72.53,110.41 72.89,110.06 72.89,101.65 72.38,101.14 72.38,100.62 72.21,100.45 72.03,100.45 71.85,100.28 71.85,100.03 72.03,99.86 72.21,99.86 72.38,99.69 72.38,98.93 71.17,97.72 71.17,96.95 71.34,96.77 72.06,96.77 72.23,96.6 72.23,96.36 72.06,96.18 71.34,96.18 71.17,96.01 R5653.1
  BOTTOM w0.147: U3072.18 105.25,104.9 104.72,105.44 103.1,105.44 102.93,105.26 102.93,104.69 102.76,104.51 102.51,104.51 102.34,104.69 102.34,105.26 102.17,105.44 101.93,105.44 101.75,105.26 101.75,104.69 101.58,104.51 101.34,104.51 101.16,104.69 101.16,105.26 100.99,105.44 100.75,105.44 100.57,105.26 100.57,104.69 100.4,104.51 100.16,104.51 99.98,104.69 99.98,105.26 99.81,105.44 99.08,105.44 91.38,113.13 79.25,113.13 79.05,113.33 78.73,113.33 77.98,112.58 77.74,112.58 77.57,112.75 77.57,113.02 78.35,113.81 78.35,114.01 78.21,114.16 78,114.16 77.16,113.32 76.92,113.32 76.74,113.5 76.74,113.74 77.56,114.55 77.56,114.82 77.3,115.08 76.51,115.08 76.25,114.82 76.25,113.9 76.04,113.69 v1(75.05,113.69)
MCASP4_ACLKX_HDR: length 5.2
  BOTTOM w0.147: U2345.12 106.02,120.94 106.09,121 106.09,123.32 J28.1
MCASP4_ACLKX_LT: length 4.6
  BOTTOM w0.147: U3072.37 104.25,112.31 104.72,112.78 105.76,112.78 106.02,113.04 U2345.9
MCASP4_ACLKX_R: length 5.3
  TOP w0.132: 71.3,93.04 71.3,91.49 71.7,91.09 U136.F18
  TOP w0.147: 71.3,93.04 71.3,93.56 70.19,94.68 R5683.2
MCASP4_AFSR: length 32.4
  TOP w0.147: v1(127.86,121.16) 127.86,114.53 128.41,113.98 J12.80
  BOTTOM w0.147: v1(127.86,121.16) 123.11,121.16 118,116.05 118,113.31 114.55,109.86 111.96,109.86 111.75,110.06 U3072.52
MCASP4_AFSR_FET: length 68.8
  TOP w0.147: R5652.2 77.23,105.79 77.39,105.95 v1(77.39,106.3)
  BOTTOM w0.147: U3072.4 112.25,98.59 110.58,96.93 97.86,96.93 94.48,100.3 94.48,102.13 94.65,102.3 95.2,102.3 95.37,102.47 95.37,102.72 95.2,102.89 94.65,102.89 94.48,103.06 94.48,103.31 94.65,103.48 95.2,103.48 95.37,103.65 95.37,103.9 95.2,104.07 94.65,104.07 94.48,104.24 94.48,104.49 94.65,104.66 95.2,104.66 95.37,104.83 95.37,105.08 95.2,105.25 94.65,105.25 94.48,105.42 94.48,107.09 90.19,111.38 81.63,111.38 80.46,110.21 78.86,110.21 78.3,110.77 77.33,110.77 76.62,110.07 76.62,106.53 76.85,106.3 v1(77.39,106.3) 77.82,106.74 RA6.7
MCASP4_AFSR_HDR: length 6.8
  BOTTOM w0.147: U2345.18 109.92,120.94 110.31,121.33 111.1,121.33 113.16,123.39 113.16,123.87 J28.7
MCASP4_AFSR_LT: length 3.8
  BOTTOM w0.147: U3072.51 111.25,111.96 110.86,112.35 110.86,112.38 110.59,112.65 110.56,112.65 109.92,113.29 U2345.3
MCASP4_AFSR_R: length 8.8
  TOP w0.147: U136.R19 78.9,93.42 79.36,93.89 79.36,94.47 78.69,95.15 78.21,95.15 77.23,96.13 R5652.1
MCASP4_AFSX: length 32.6
  TOP w0.147: J12.79 122.81,113.98 122.55,113.72 v1(122.55,113.23)
  BOTTOM w0.147: U3072.41 106.25,109.67 108.4,107.52 122.34,107.52 123.66,108.84 123.66,110.95 122.67,111.94 122.67,112.6 122.93,112.85 124.48,112.85 124.81,113.18 124.81,113.69 124.5,114 122.69,114 122.55,113.85 v1(122.55,113.23)
MCASP4_AFSX_FET: length 67.7
  TOP w0.147: R5655.2 68.62,96.89 69.08,97.36 69.08,97.63 68.68,98.03 68.68,98.28 68.85,98.45 69.09,98.45 69.52,98.02 69.74,98.02 69.91,98.19 69.91,98.49 69.41,98.99 69.41,99.24 69.58,99.41 69.83,99.41 70.37,98.86 70.58,98.86 70.81,99.09 70.81,100.37 70.63,100.55 70.12,100.55 69.94,100.72 69.94,100.96 70.12,101.13 70.63,101.13 70.81,101.31 70.81,104.19 71.98,105.36 71.98,109.7 71.62,110.06 71.62,112.01 70.76,112.88 70.76,114.25 71.72,115.21 73.07,115.21 73.45,114.83 v1(75.13,114.83)
  BOTTOM w0.147: U3072.15 106.75,104.7 105.55,105.89 99.26,105.89 91.56,113.59 79.42,113.59 77.48,115.53 75.82,115.53 v1(75.13,114.83)
MCASP4_AFSX_HDR: length 6.4
  BOTTOM w0.147: J28.5 109.02,123.87 108.34,123.87 106.67,122.2 U2345.13
MCASP4_AFSX_LT: length 3.6
  BOTTOM w0.147: U2345.8 106.67,113 105.75,112.08 U3072.40
MCASP4_AFSX_R: length 8.1
  TOP w0.132: 68.19,93.04 69.46,93.04 70.5,92 70.5,91.49 70.73,91.26 71.05,91.26 71.3,91.01 71.3,90.45 U136.F17
  TOP w0.147: 68.19,93.04 67.64,93.6 R5655.1
MCASP4_AXR0: length 32.3
  TOP w0.147: J12.67 122.25,118.78 v1(121.4,117.93)
  BOTTOM w0.147: v1(121.4,117.93) 119.85,116.38 119.85,115.57 119.68,115.4 119.16,115.4 118.99,115.23 118.99,114.98 119.16,114.81 119.68,114.81 119.85,114.64 119.85,114.39 119.68,114.22 119.16,114.22 118.99,114.05 118.99,113.8 119.16,113.63 119.68,113.63 119.85,113.46 119.85,113.22 119.68,113.04 119.16,113.04 118.99,112.87 118.99,112.63 119.16,112.45 119.68,112.45 119.85,112.28 119.85,111.63 119.28,111.06 119.04,111.06 118.33,111.77 118.09,111.77 117.91,111.6 117.91,111.35 118.62,110.64 118.62,110.4 118.45,110.23 118.21,110.23 117.5,110.94 117.25,110.94 117.08,110.76 117.08,110.52 117.79,109.81 117.79,109.57 117.59,109.37 116.71,109.37 116.54,109.54 116.54,110.42 116.37,110.59 116.12,110.59 115.95,110.42 115.95,109.54 115.78,109.37 111.02,109.37 110.75,109.64 U3072.50
MCASP4_AXR0_FET: length 69.7
  TOP w0.147: R5654.2 72.85,100.97 73.35,101.47 73.35,110.24 72.99,110.59 72.99,111.58 74.39,112.98 v1(75.05,112.98)
  BOTTOM w0.147: U3072.6 111.25,99.6 110.63,98.98 98.06,98.98 96.08,100.97 96.08,102.41 96.25,102.58 96.52,102.58 96.69,102.75 96.69,103 96.52,103.17 96.25,103.17 96.08,103.34 96.08,103.59 96.25,103.76 96.52,103.76 96.69,103.93 96.69,104.18 96.52,104.35 96.25,104.35 96.08,104.52 96.08,104.77 96.25,104.94 96.52,104.94 96.69,105.11 96.69,105.36 96.52,105.53 96.25,105.53 96.08,105.7 96.08,106.58 90.49,112.17 81.63,112.17 80.13,110.67 79.21,110.67 78.58,111.3 77.79,111.3 76.12,112.98 v1(75.05,112.98)
MCASP4_AXR0_HDR: length 16.4
  BOTTOM w0.147: J28.8 113.99,127.2 115.51,125.68 115.51,123.67 112.23,120.4 112.23,119.3 111.19,118.26 109.77,118.26 109.27,118.76 U2345.17
MCASP4_AXR0_LT: length 3.4
  BOTTOM w0.147: U3072.48 109.75,112.06 109.27,112.54 U2345.4
MCASP4_AXR0_R: length 5.8
  TOP w0.147: U136.F19 71.7,94.59 72.85,95.74 R5654.1
MCASP4_AXR3: length 32.5
  TOP w0.147: J12.69 v1(125.9,117.98)
  BOTTOM w0.147: v1(125.9,117.98) 126.59,117.98 126.87,117.7 126.87,116.34 126.59,116.05 123.06,116.05 122.01,115.01 122.01,109.47 120.49,107.95 108.81,107.95 107.25,109.5 U3072.43
MCASP4_AXR3_FET: length 68.9
  TOP w0.147: v1(79.72,114.05) 82.47,111.3 82.47,109.68 82.85,109.3 82.85,107.65 80.33,105.13 R5658.2
  BOTTOM w0.147: U3072.13 107.75,105.07 104.89,107.92 104.04,107.92 103.87,107.75 103.87,106.68 103.69,106.51 103.45,106.51 103.28,106.68 103.28,107.75 103.1,107.92 102.86,107.92 102.69,107.75 102.69,106.68 102.51,106.51 102.27,106.51 102.1,106.68 102.1,107.75 101.93,107.92 101.68,107.92 101.51,107.75 101.51,106.68 101.34,106.51 101.09,106.51 100.92,106.68 100.92,107.75 100.75,107.92 100.5,107.92 100.33,107.75 100.33,106.68 100.16,106.51 99.91,106.51 99.74,106.68 99.74,107.75 99.57,107.92 99.13,107.92 98.35,108.71 98.1,108.71 97.76,108.37 97.52,108.37 97.35,108.54 97.35,108.78 97.69,109.12 97.69,109.37 97.51,109.54 97.27,109.54 96.93,109.2 96.68,109.2 96.51,109.37 96.51,109.62 96.85,109.96 96.85,110.2 96.68,110.37 96.44,110.37 96.1,110.03 95.85,110.03 95.68,110.21 95.68,110.45 96.02,110.79 96.02,111.03 95.85,111.21 95.6,111.21 95.26,110.87 95.02,110.87 94.85,111.04 94.85,111.28 95.19,111.62 95.19,111.87 95.01,112.04 94.77,112.04 94.43,111.7 94.18,111.7 94.01,111.87 94.01,112.12 94.35,112.46 94.35,112.7 94.18,112.87 93.94,112.87 93.6,112.53 93.35,112.53 93.18,112.71 93.18,112.95 93.52,113.29 93.52,113.53 93.01,114.05 v1(79.72,114.05)
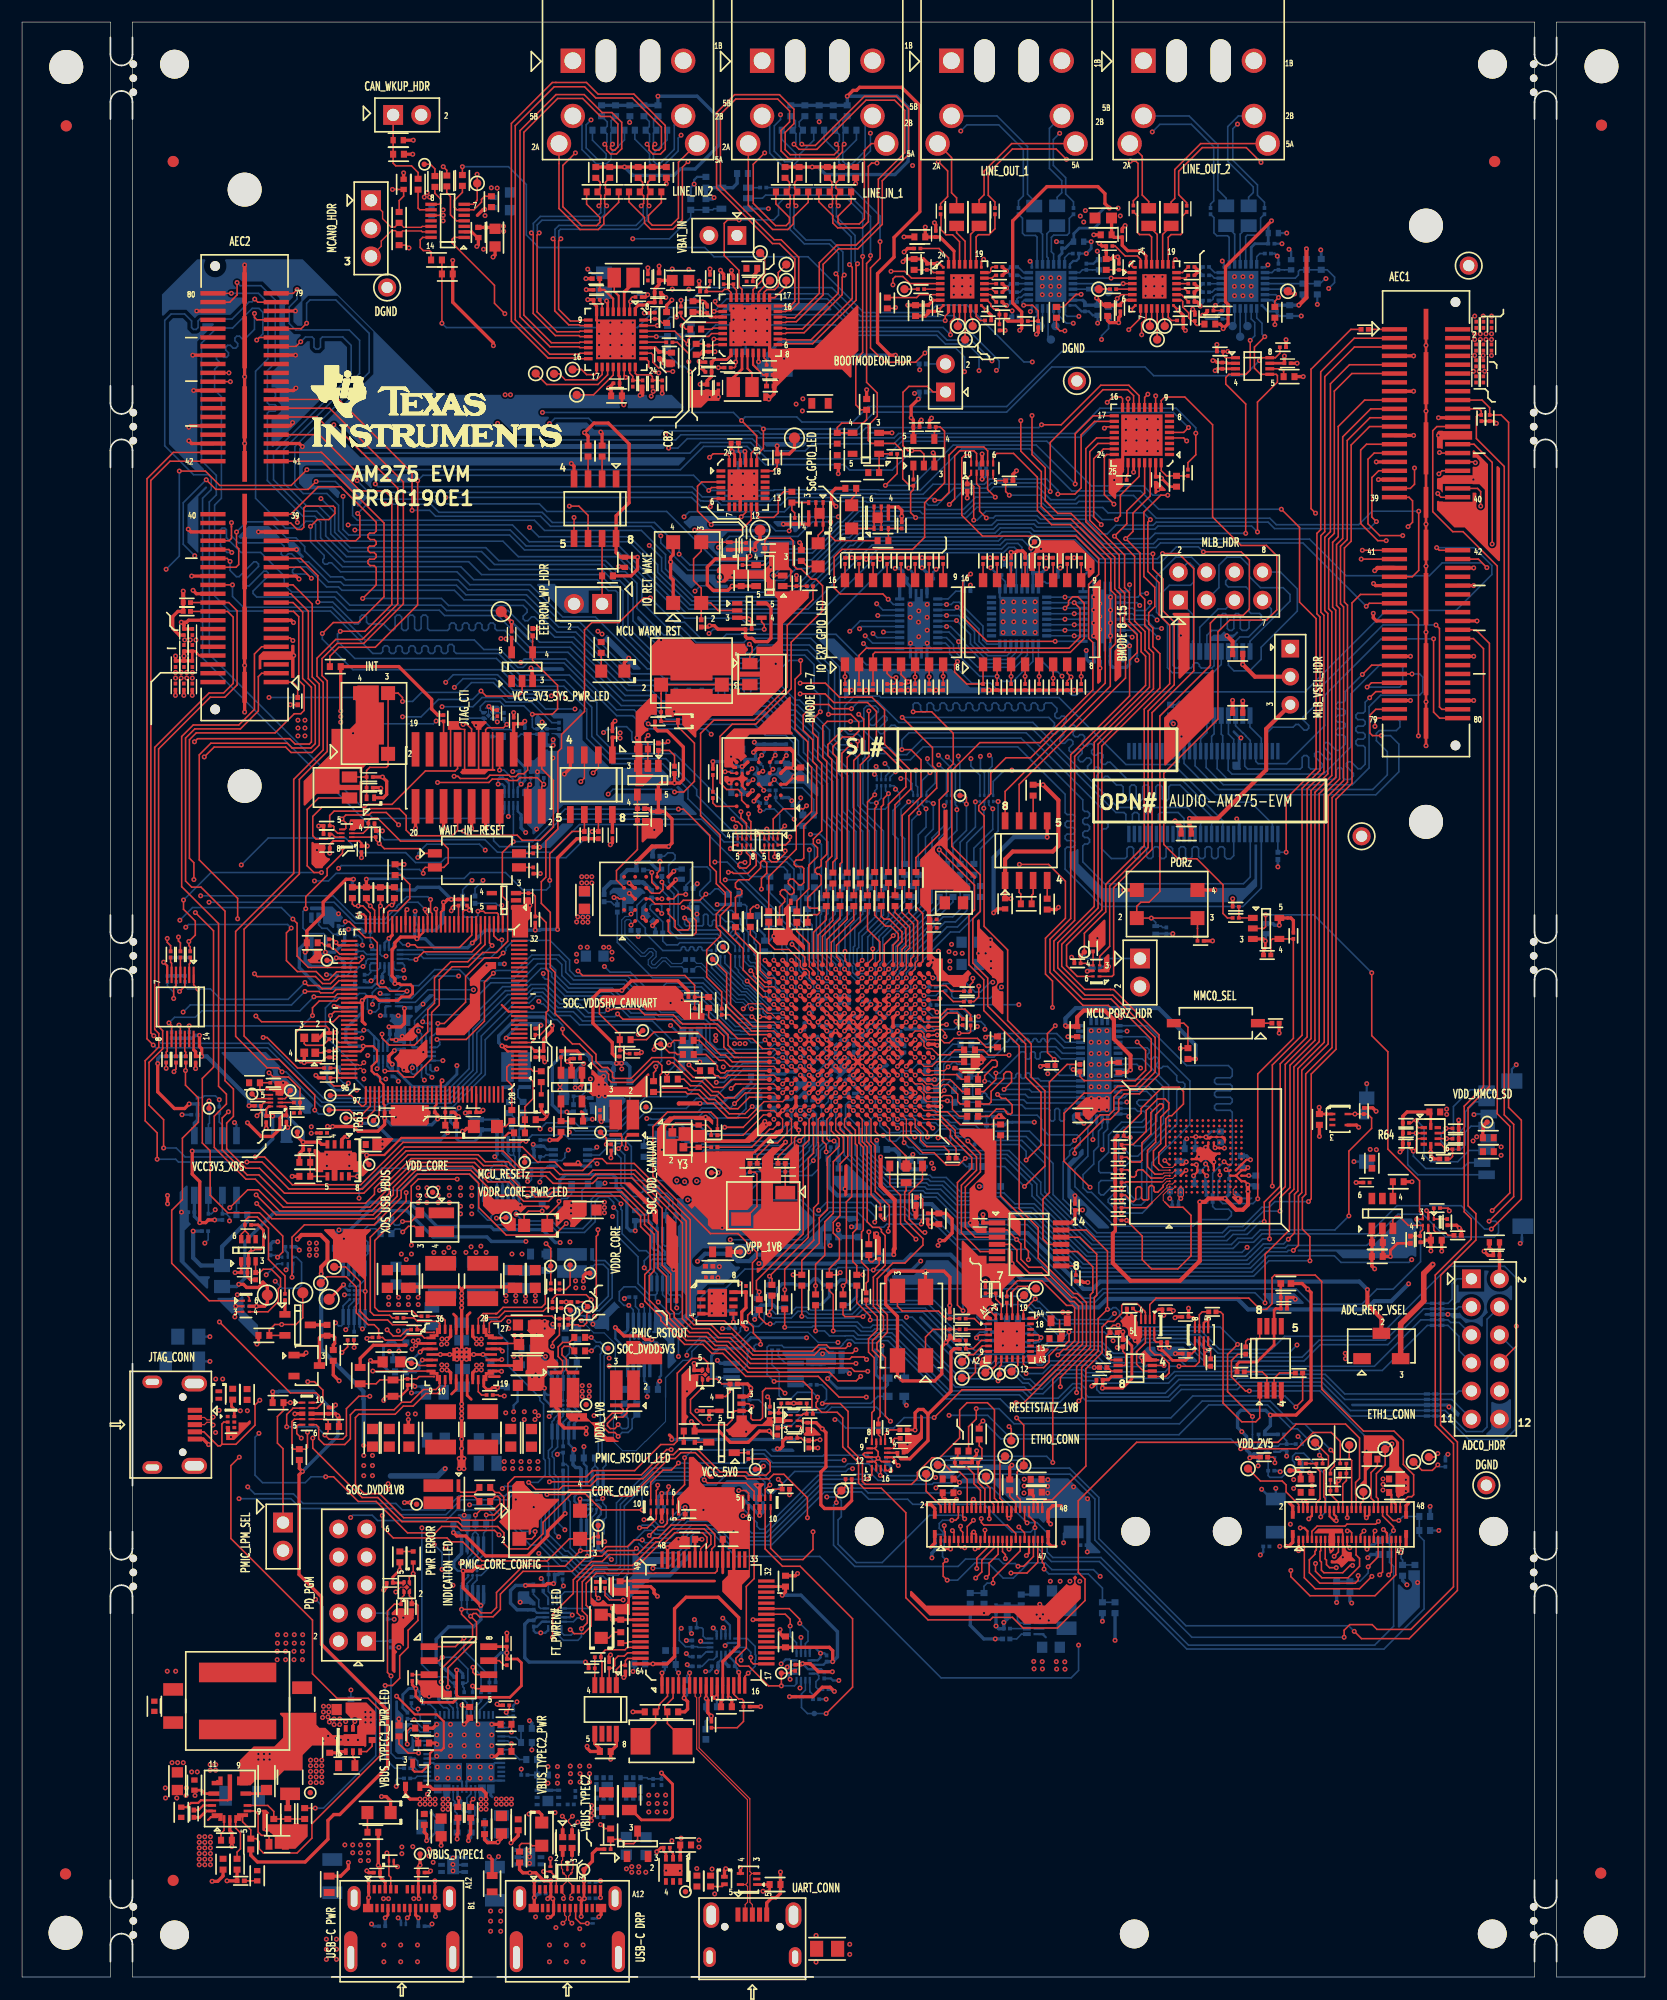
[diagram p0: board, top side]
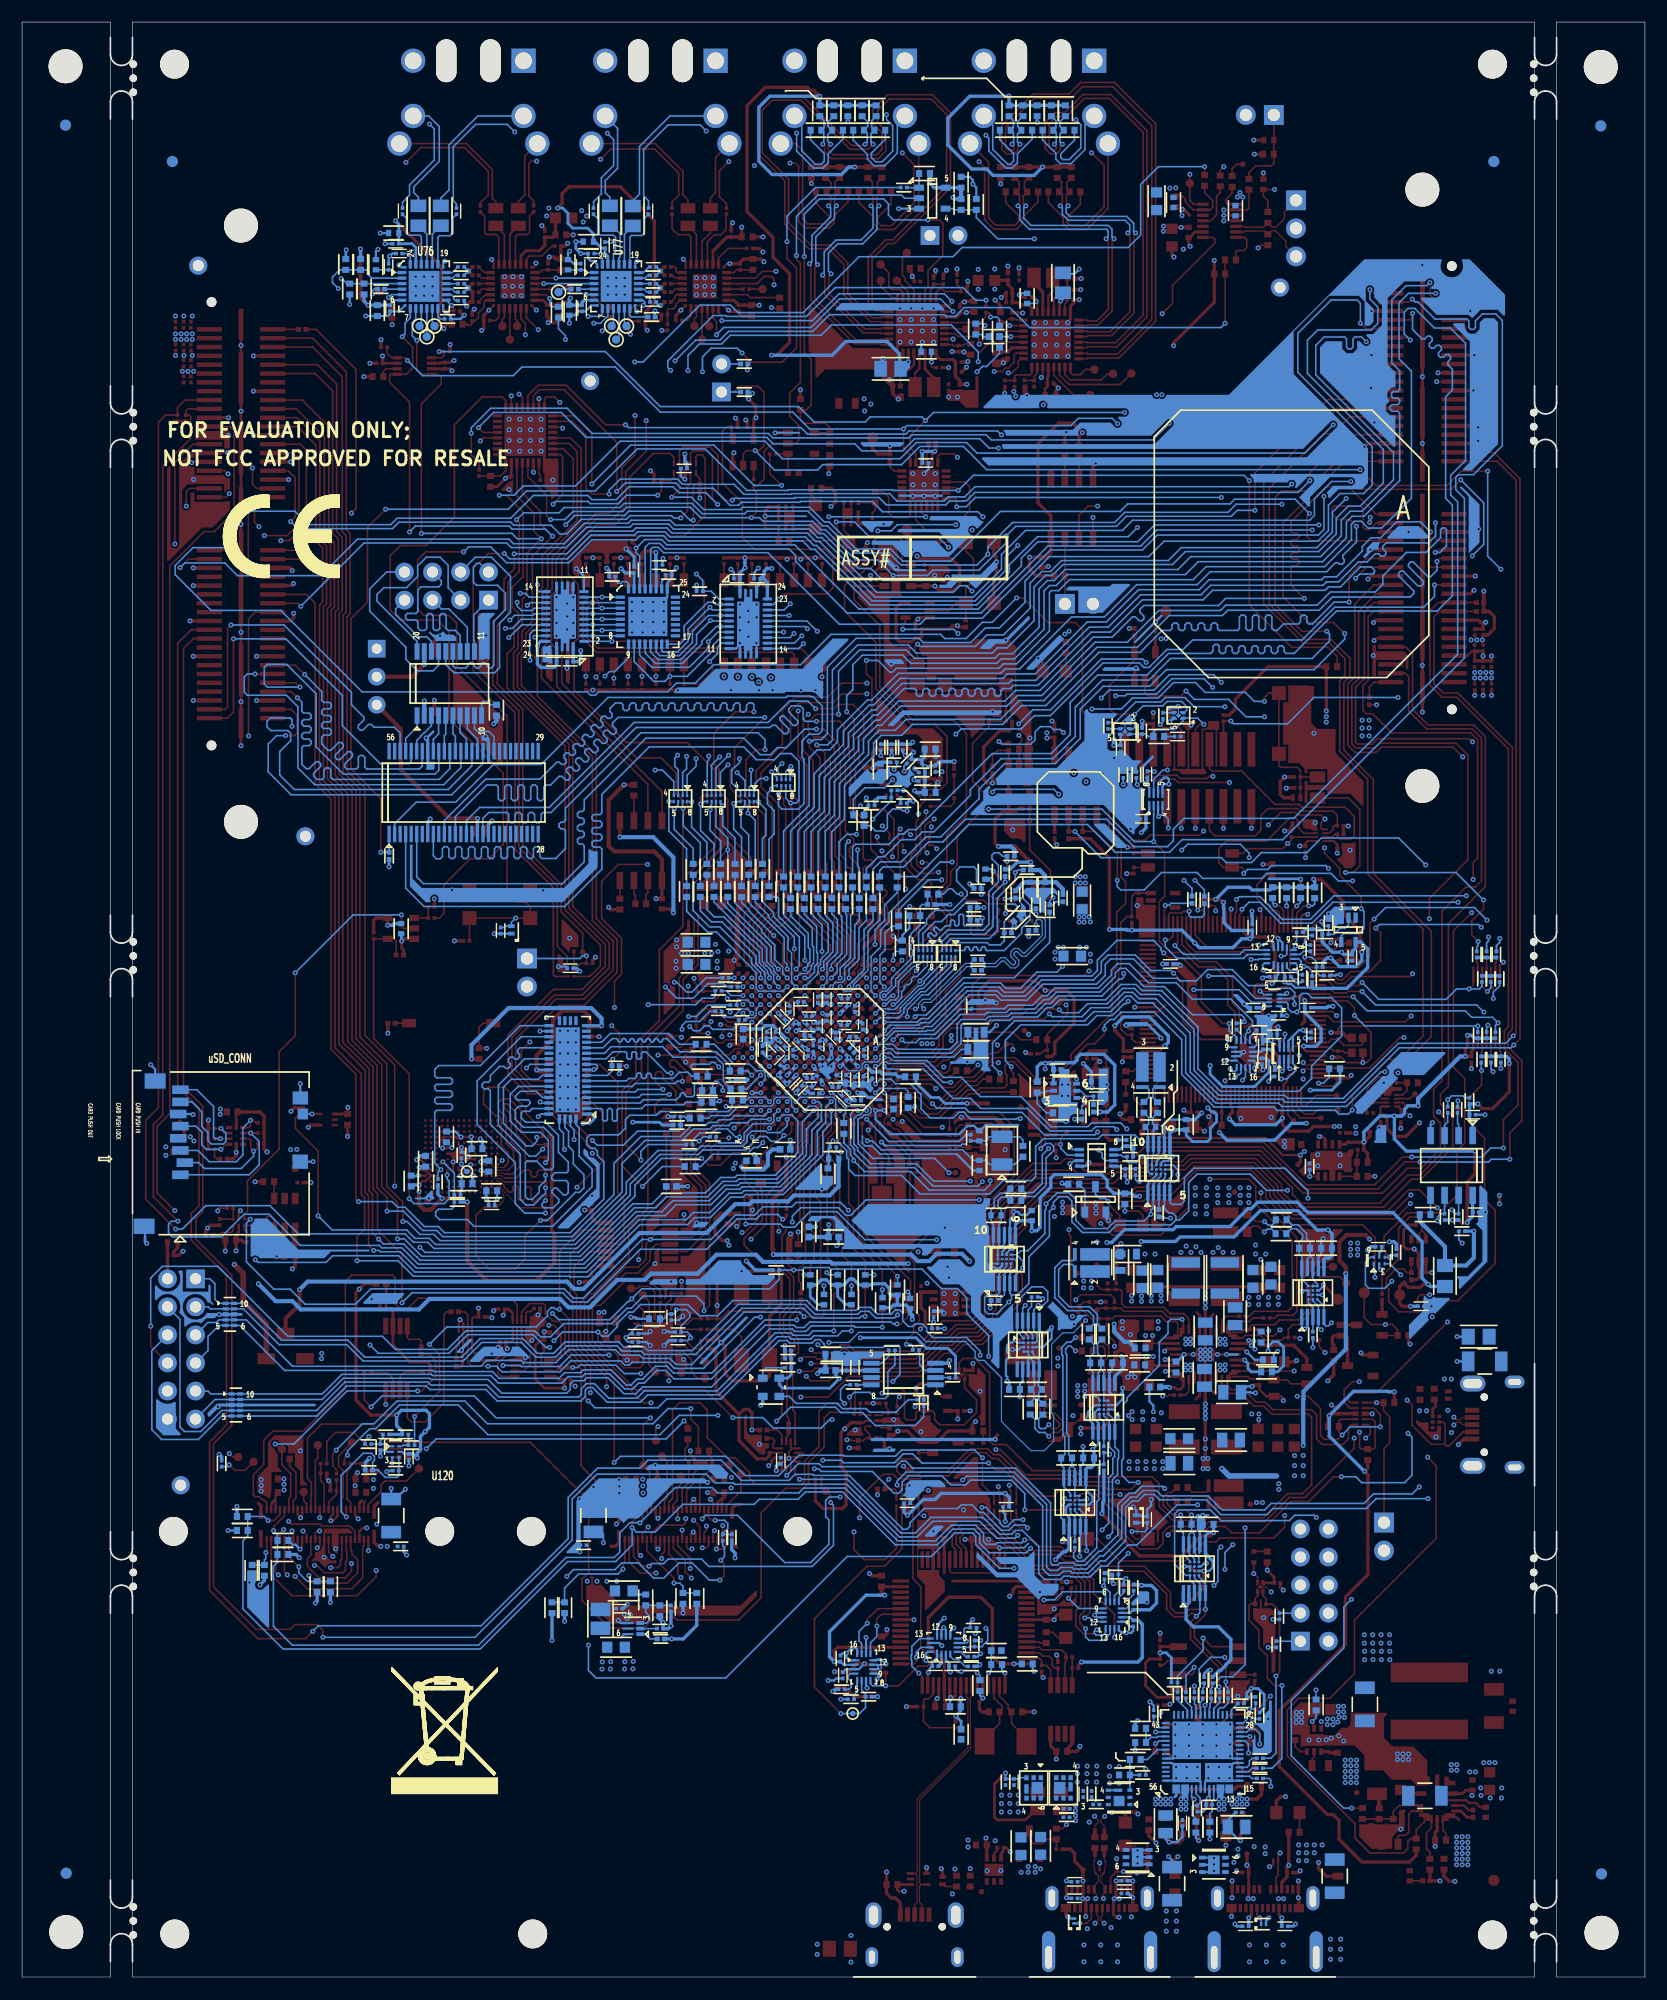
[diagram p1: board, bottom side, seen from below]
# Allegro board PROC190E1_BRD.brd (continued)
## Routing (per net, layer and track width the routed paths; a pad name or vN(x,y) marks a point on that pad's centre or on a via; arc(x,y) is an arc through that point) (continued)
MCASP4_AXR3_LT: length 3.5
  BOTTOM w0.147: U3072.42 106.75,112.09 107.32,112.66 U2345.7
MCASP4_AXR3_MLB0_SIG_HDR: length 19.9
  BOTTOM w0.147: J28.6 109.02,126.41 109.02,126.1 109.26,125.86 110.86,125.86 111.14,125.58 111.14,123.63 111.32,123.46 112.09,123.46 112.26,123.29 112.26,123.04 112.09,122.87 111.32,122.87 111.14,122.7 111.14,122.15 110.91,121.92 110.53,121.92 110.35,122.09 110.35,123.27 110.18,123.44 109.94,123.44 109.76,123.27 109.76,122.09 109.59,121.92 109.35,121.92 109.17,122.09 109.17,123.27 109,123.44 108.76,123.44 108.59,123.27 108.59,122.09 108.41,121.92 107.76,121.92 107.32,121.48 U2345.14
MCASP4_AXR3_R: length 6.7
  TOP w0.132: U136.U18 80.89,91.25 80.89,91.82 81.12,92.05
  TOP w0.147: 81.12,92.05 81.12,95.6 80.33,96.39 R5658.1
MCASP4_AXR4: length 32.2
  TOP w0.147: v1(121.84,116.79) 122.23,117.18 J12.71
  BOTTOM w0.147: v1(121.84,116.79) 124.78,116.79 125.06,117.07 125.06,118.57 124.78,118.85 123.03,118.85 120.36,116.18 120.36,111.38 117.9,108.92 109.59,108.92 109.25,109.26 U3072.47
MCASP4_AXR4_FET: length 67.7
  TOP w0.147: v1(79.7,111.12) 80.51,111.12 81.42,110.21 81.42,106.86 79.72,105.15 R5656.2
  BOTTOM w0.147: U3072.9 109.75,101.53 109.47,101.24 109.13,101.24 108.93,101.44 108.93,102.16 108.76,102.34 108.51,102.34 108.34,102.16 108.34,101.44 108.17,101.27 107.92,101.27 107.75,101.44 107.75,102.16 107.58,102.34 107.33,102.34 107.16,102.16 107.16,101.44 106.99,101.27 106.74,101.27 106.57,101.44 106.57,102.16 106.4,102.34 106.15,102.34 105.98,102.16 105.98,101.44 105.81,101.27 105.57,101.27 105.39,101.44 105.39,102.16 105.22,102.34 104.98,102.34 104.8,102.16 104.8,101.44 104.63,101.27 104.39,101.27 104.21,101.44 104.21,102.16 104.04,102.34 103.8,102.34 103.63,102.16 103.63,101.44 103.45,101.27 103.21,101.27 103.04,101.44 103.04,102.16 102.86,102.34 102.62,102.34 102.45,102.16 102.45,101.44 102.27,101.27 102.03,101.27 101.86,101.44 101.86,102.16 101.68,102.34 101.44,102.34 101.27,102.16 101.27,101.44 101.1,101.27 100.85,101.27 100.68,101.44 100.68,102.16 100.51,102.34 100.26,102.34 100.09,102.16 100.09,101.44 99.92,101.27 98.67,101.27 97.78,102.16 97.78,103.79 97.95,103.96 98.19,103.96 98.37,104.13 98.37,104.38 98.19,104.55 97.95,104.55 97.78,104.72 97.78,105.82 90.95,112.65 80.33,112.65 79.7,112.01 v1(79.7,111.12)
MCASP4_AXR4_LT: length 3.3
  BOTTOM w0.147: U3072.46 108.75,112.4 108.62,112.53 U2345.5
MCASP4_AXR4_MLB0_CLK_HDR: length 21
  BOTTOM w0.147: J28.4 105.94,128.55 104.49,128.55 102.76,126.82 102.76,123.56 103.75,122.57 103.75,118.54 104.21,118.08 107.87,118.08 108.62,118.84 U2345.16
MCASP4_AXR4_R: length 7.9
  TOP w0.147: R5656.1 79.72,96.37 80.75,95.34 80.75,92.42 80.5,92.16 U136.U19
MCASP4_AXR5: length 32.2
  TOP w0.147: v1(122.06,115.82) 122.62,116.38 J12.73
  BOTTOM w0.147: U3072.45 108.25,109.39 109.21,108.43 118.88,108.43 119.05,108.61 119.05,109.3 119.22,109.47 119.47,109.47 119.64,109.3 119.64,108.61 119.81,108.43 120.29,108.43 120.59,108.74 120.59,108.98 119.96,109.61 119.96,109.86 120.13,110.03 120.38,110.03 121.01,109.4 121.25,109.4 121.66,109.8 121.66,111.32 121.49,111.49 120.99,111.49 120.82,111.66 120.82,111.91 120.99,112.08 121.49,112.08 121.66,112.25 121.66,112.5 121.49,112.67 120.99,112.67 120.82,112.84 120.82,113.08 120.99,113.26 121.49,113.26 121.66,113.43 121.66,113.67 121.49,113.85 120.99,113.85 120.82,114.02 120.82,114.26 120.99,114.44 121.49,114.44 121.66,114.61 121.66,115.42 v1(122.06,115.82)
MCASP4_AXR5_FET: length 67.8
  TOP w0.147: R5657.2 80.97,101.35 83.08,103.45 83.08,106.58 83.86,107.37 83.86,109.37 84.35,109.86 84.35,112.6 82.39,114.55 v1(80.71,114.55)
  BOTTOM w0.147: U3072.11 108.75,104.7 105,108.46 100.09,108.46 98.57,109.98 98.32,109.98 98.13,109.79 97.89,109.79 97.71,109.96 97.71,110.21 97.91,110.4 97.91,110.64 97.73,110.82 97.49,110.82 97.3,110.62 97.05,110.62 96.88,110.8 96.88,111.04 97.07,111.23 97.07,111.48 96.9,111.65 96.66,111.65 96.46,111.46 96.22,111.46 96.05,111.63 96.05,111.87 96.24,112.07 96.24,112.31 96.07,112.48 95.82,112.48 95.63,112.29 95.39,112.29 95.21,112.46 95.21,112.71 95.46,112.95 95.46,113.17 95.28,113.34 95.02,113.34 94.8,113.12 94.55,113.12 94.38,113.3 94.38,113.54 94.57,113.73 94.57,113.98 94.4,114.15 94.16,114.15 93.96,113.96 93.72,113.96 93.55,114.13 93.55,114.38 93.74,114.57 93.74,114.86 93.25,115.36 92.73,115.36 92.58,115.21 92.58,114.84 92.41,114.67 92.17,114.67 91.99,114.84 91.99,115.13 91.77,115.36 91.55,115.36 91.4,115.21 91.4,114.84 91.23,114.67 90.99,114.67 90.81,114.84 90.81,115.13 90.59,115.36 90.37,115.36 90.23,115.21 90.23,114.84 90.05,114.67 89.81,114.67 89.64,114.84 89.64,115.13 89.41,115.36 89.19,115.36 89.05,115.21 89.05,114.84 88.87,114.67 88.63,114.67 88.46,114.84 88.46,115.13 88.23,115.36 88.02,115.36 87.87,115.21 87.87,114.84 87.7,114.67 87.45,114.67 87.28,114.84 87.28,115.13 87.06,115.36 86.84,115.36 86.69,115.21 86.69,114.84 86.52,114.67 86.27,114.67 86.1,114.84 86.1,115.13 85.88,115.36 85.66,115.36 85.51,115.21 85.51,114.84 85.34,114.67 85.09,114.67 84.92,114.84 84.92,115.13 84.7,115.36 84.48,115.36 84.33,115.21 84.33,114.84 84.16,114.67 83.92,114.67 83.74,114.84 83.74,115.13 83.52,115.36 83.3,115.36 83.15,115.21 83.15,114.84 82.98,114.67 82.74,114.67 82.56,114.84 82.56,115.13 82.34,115.36 82.12,115.36 81.98,115.21 81.98,114.69 81.83,114.54 81.58,114.54 81.39,114.74 81.39,115.13 81.16,115.36 80.86,115.36 80.71,115.21 v1(80.71,114.55)
MCASP4_AXR5_LT: length 3.3
  BOTTOM w0.147: U2345.6 107.97,112.55 107.75,112.33 U3072.44
MCASP4_AXR5_MLB0_DAT_HDR: length 19.8
  BOTTOM w0.147: U2345.15 107.97,118.72 107.76,118.52 106.81,118.52 106.64,118.69 106.64,118.81 106.47,118.99 106.22,118.99 106.05,118.81 106.05,118.69 105.88,118.52 105.64,118.52 105.46,118.69 105.46,118.81 105.29,118.99 105.05,118.99 104.87,118.81 104.87,118.69 104.7,118.52 104.49,118.52 104.26,118.75 104.26,122.76 103.22,123.8 103.22,125.3 103.93,126.01 105.83,126.01 106.11,126.29 106.11,127.69 105.8,128 105.54,128 J28.2
MCASP4_AXR5_R: length 7.8
  TOP w0.147: R5657.1 80.97,96.9 81.58,96.29 81.58,91.94 U136.V19
MCASP4_FET_SEL: length 142
  TOP w0.147: U18.4 62.46,134.86 v1(62.2,134.59) ; v1(35.83,135.48) 35.83,124.23 32,120.4 28.69,120.4 27.88,119.58 R5764.1 ; v1(114.5,101.84) 114.5,106.69 117.21,109.4 117.21,122.99 115.71,124.49 115.71,131.25 v1(114.07,132.89)
  BOTTOM w0.147: U3072.1 R5681.1 v1(114.5,101.84) ; v1(114.07,132.89) 102.96,132.89 101.31,134.54 95.09,134.54 91.28,138.35 85.11,138.35 81.35,134.6 77.64,134.6 77.58,134.65 68.12,134.65 68.06,134.59 v1(62.2,134.59) 60.83,135.97 36.31,135.97 v1(35.83,135.48)
MCASP_VSEL_HDR: length 6.9
  TOP w0.381: C3702.1 v1(110.57,118.83) 111.68,117.73 J29.2
  BOTTOM w0.381: U2345.19 v1(110.57,118.83)
MCU_INTN: length 91.7
  TOP w0.132: 77.28,75.23 76.89,75.63 76.89,77.66 U136.M2
  TOP w0.147: 77.28,75.23 77.28,71.12 78.55,69.85 78.55,67.97 78.45,67.87 v1(78.45,67.51) ; v1(71.14,41.58) 71.14,43.38 69,45.51 68.07,45.51 67.65,45.09 65.69,45.09 65.42,45.36 63.09,45.36 60.98,47.47 59.68,47.47 59.15,46.94 58.59,46.94 55.19,43.54 53.56,43.54 53.01,44.09 49.57,44.09 49.17,43.69 v1(47.54,43.69) ; v1(48.05,57.1) 48.05,57.51 48.67,58.13 R299.1
  L03_SIG1 w0.091: v1(47.54,43.69) 45.38,43.69 43.25,45.82 43.25,51.57 45.61,53.93 45.61,56.13 46.58,57.1 v1(48.05,57.1) ; v1(71.14,41.58) 71.62,41.58 73.32,43.28 73.32,47.52 74.33,48.53 74.33,54.98 77.99,58.64 77.99,66.03 78.45,66.5 v1(78.45,67.51)
MCU_OSC0_XI: length 5.5
  TOP w0.132: U136.A2 67.15,78.05 65.31,76.21 64.89,76.21
  TOP w0.147: 64.89,76.21 R249.2
MCU_OSC0_XO: length 6.4
  TOP w0.132: U136.B1 68,76.76 67.72,76.76
  TOP w0.147: R253.2 66.09,75.13 67.72,76.76
MCU_PORZ: length 264.1
  TOP w0.147: v1(102.2,131.95) 101.97,131.72 101.97,127.25 102.99,126.24 102.99,123.34 103.95,122.38 103.95,117.09 101.64,114.78 101.64,102.41 98.16,98.93 98.16,96.44 96.22,94.5 TP49.1 v1(95.88,92.45) R242.2 96.38,91.78 96.56,91.59 U43.4 R238.1 ; U136.E3 v1(70.5,78.46) ; v1(117.16,132.54) 116.76,132.94 116.76,145.57 120.37,149.18 R5775.1 ; R5776.1 v1(24.3,115.19)
  L03_SIG1 w0.091: v1(61.1,72.06) 61.1,73.05 58.71,75.45 58.71,81.42 59.1,81.81 59.1,83.19 59.34,83.43 59.34,84.95 58.32,85.97 58.32,88.83 59.28,89.79 59.28,98.63 59.63,98.98 59.63,104.48 58.67,105.43 58.67,109.3 58.94,109.57 58.94,112.55 58.65,112.85 58.65,126.5 59.52,127.37 v1(59.52,128.83) ; v1(117.16,132.54) 116.07,133.63 103.88,133.63 v1(102.2,131.95) ; v1(32.89,133.35) 32.89,131.85 32.45,131.42 32.45,118.95 28.69,115.19 v1(24.3,115.19)
  BOTTOM w0.132: v1(70.5,78.46) 70.74,78.46 71.13,78.06 71.31,78.06 71.65,77.72
  BOTTOM w0.147: 71.65,77.72 71.65,75.41 71.32,75.08 71.32,74.83 70.12,73.63 66.01,73.63 64.43,72.06 v1(61.1,72.06) ; v1(32.89,133.35) 37.03,133.35 37.76,132.61 47.11,132.61 48.03,131.69 57.28,131.69 59.52,129.46 v1(59.52,128.83) 60.5,127.85 67.38,127.85 68.46,128.93 71.59,128.93 74.06,131.39 74.49,131.39 75.82,132.72 81.32,132.72 81.55,132.49 85.39,132.49 86.32,133.42 92.45,133.42 92.83,133.05 97.88,133.05 98.37,132.56 101.59,132.56 v1(102.2,131.95) ; J32.1 96.47,92.22 96.23,92.45 v1(95.88,92.45)
MCU_RESETZ: length 54.1
  TOP w0.147: v1(45.53,74.3) TP50.1 ; U136.D9 v1(69.7,84.06)
  L03_SIG1 w0.091: v1(45.53,74.3) 44.94,74.89 44.94,76.11 45.2,76.38 46.32,76.38 46.63,76.07 47.46,76.07 47.62,76.23 48.3,76.23 48.46,76.38 48.46,77.01 48.01,77.45 47.25,77.45 45.51,79.2 45.51,88.21 47.21,89.92 v1(47.21,90.86)
  BOTTOM w0.132: 65.04,84 67.66,84 68.11,84.45 69.3,84.45 v1(69.7,84.06)
  BOTTOM w0.147: v1(45.53,74.3) 46.09,73.74 46.78,73.74 46.92,73.88 R550.2 47.28,74.27 47.43,74.42 U98.7 ; 65.04,84 62.96,84 62.3,84.66 62.3,86.31 61.92,86.69 59.73,86.69 59.45,86.97 57.7,86.97 57.4,87.27 55.16,87.27 54.3,88.14 53.84,88.14 53.15,88.82 49.17,88.82 47.64,90.35 47.39,90.35 47.21,90.53 v1(47.21,90.86)
MCU_SAFETY_ERRORZ_1V8: length 91.5
  TOP w0.147: U136.F3 v1(71.3,78.46) ; v1(58.79,47.75) 58.39,47.75 56.1,45.47 51.96,45.47 51.33,44.83 v1(47.77,44.83) ; v1(47.46,66.4) 47.89,65.97 TP54.1 R281.1
  L03_SIG1 w0.091: v1(58.79,47.75) 61.05,50.01 61.05,50.72 59.03,52.75 59.03,56.37 60.39,57.73 60.39,68.25 61.27,69.12 61.27,70.76 60.68,71.35 60.33,71.35 60.01,71.67 v1(60.01,72.01) ; v1(47.77,44.83) 47.44,45.16 47.44,47.8 49.34,49.71 49.34,56.59 50.23,57.48 52.34,57.48 52.82,57.96 52.82,60.02 52.04,60.81 50.24,60.81 50.11,60.68 48.63,60.68 47.19,62.13 47.19,66.12 v1(47.46,66.4)
  BOTTOM w0.147: v1(60.01,72.01) 60.42,71.61 64.45,71.61 64.55,71.7 64.58,71.7 66.16,73.28 70.32,73.28 71.59,74.55 71.59,74.96 71.95,75.31 71.95,78.16 71.65,78.46 v1(71.3,78.46)
MIC1_BIAS: length 81.4
  TOP w0.254: U7.6 v1(66.71,146.25)
  TOP w0.305: v1(74.75,170.29) 75.27,170.81 75.58,170.81 75.86,171.09 79.67,171.09 81.32,169.44 81.32,159.84 78.98,157.5 78.98,155.72 77.49,154.23 77.49,147.99 78.64,146.84 v1(79.11,146.84) ; R7.1 R8.1 v1(71.57,163.88) R9.1 R10.1 C3.1
  BOTTOM w0.305: v1(79.11,146.84) 73.63,146.84 72.38,148.08 68.65,148.08 67.53,146.97 67.53,145.61 C379.1 66.9,145.61 66.71,145.8 v1(66.71,146.25) ; v1(71.57,163.88) 72.11,163.88 72.79,163.19 79.06,163.19 80.26,164.39 80.26,169.29 79.26,170.29 v1(74.75,170.29) R405.1 R406.1 C329.1 R407.1 R408.1
  vias: v1(80.66,164.01)
MIC2_BIAS: length 45.9
  TOP w0.254: 53.04,151.65 U8.6
  TOP w0.305: v1(52.94,151.75) 53.04,151.65 ; R3.1 R4.1 v1(54.57,163.88) R5.1 R6.1 C2.1
  L03_SIG1 w0.305: v1(54.57,163.88) 54.57,160.54 52.94,158.92 v1(52.94,151.75)
  BOTTOM w0.305: R412.1 R411.1 C330.1 R410.1 R409.1 v1(57.6,170.29) 61.15,170.29 63.14,168.3 63.14,165.86 60.98,163.7 59.63,163.7 59.05,163.12 55.33,163.12 v1(54.57,163.88) ; 52.71,152.6 C363.1 52.71,151.98 v1(52.94,151.75)
MMC0_CLK: length 14.6
  BOTTOM w0.147: R558.1 86.86,79.2 87.09,78.97 90.54,78.97 90.88,78.63 92.97,78.63 93.1,78.5 93.1,77.62 93.23,77.5 93.41,77.5 93.54,77.62 93.54,78.5 93.67,78.63 93.85,78.63 93.98,78.5 93.98,77.62 94.11,77.5 94.29,77.5 94.42,77.62 94.42,78.5 94.55,78.63 U57.2
MMC0_FET_EN: length 91
  TOP w0.147: R5216.2 93.57,83.01 v1(93.49,83.08) 92.88,83.69 92.88,85.42 v1(93.59,86.13) ; v1(62.43,131.5) 61.18,132.74 61.18,134.98 61.56,135.36 U18.3 ; v1(93.34,87.78) 93.34,90.17 92.7,90.81 92.7,94.06 94.51,95.86 94.51,99.21 92.98,100.74 v1(90.34,100.74)
  L03_SIG1 w0.091: v1(93.34,87.78) 93.34,86.39 v1(93.59,86.13) ; v1(69.49,130.94) 69.49,129.72 70.66,128.55 70.66,121.01 74.36,117.3 74.95,117.3 75.66,116.59 75.66,116.28 77.31,114.63 77.31,112.88 75.74,111.3 75.74,110.46 75.31,110.04 75.31,101.14 77.23,99.21 88.82,99.21 v1(90.34,100.74)
  BOTTOM w0.147: U57.8 93.96,81.63 93.57,82.03 R5216.2 93.57,83.01 v1(93.49,83.08) ; v1(69.49,130.94) 68.27,130.94 67.71,131.5 v1(62.43,131.5)
MMC0_SD_EN: length 104.6
  TOP w0.147: v1(105.49,139.08) 105.22,139.35 U21.4 ; R21.1 129.19,69.62 129.28,69.52 v1(129.28,69.37)
  L03_SIG1 w0.091: v1(129.28,69.37) 132.91,73 132.91,115.52 135.45,118.06 135.45,136.3 131.06,140.69 110.05,140.69 108.44,139.08 v1(105.49,139.08)
MMC0_SD_LS_EN: length 5.9
  TOP w0.147: R5823.2 R17.1 126.65,67.44 126.88,67.67 U2.4 125.57,68.05 124.76,68.86 124.43,68.86 124.17,68.6 U4.3
MMC0_SDIO_VSEL: length 61
  TOP w0.147: U56.11 38.32,53.52 37.64,52.83 36.57,52.83 35.43,51.69 34.54,51.69 33.8,50.95 30.5,50.95 30.19,50.65 30.19,44.57 31,43.76 32.38,43.76 34.56,41.58 39.62,41.58 39.85,41.35 42.77,41.35 44.01,42.59 44.01,44.68 44.62,45.29 51.1,45.29 51.66,45.85 55.49,45.85 57.85,48.21 59.03,48.21 59.35,48.53 59.35,54.67 60.68,56 61.74,56 62.11,55.63 U3087.4
MMC0_SEL_1V8: length 61.4
  TOP w0.147: v1(69.11,52.86) 68.67,53.29 67.35,53.29 67.07,53.01 67.07,50.62 66.87,50.42 66.18,50.42 66.03,50.57 66.03,51.05 65.83,51.26 U3086.1 64.58,51.26 64.33,51 64.33,50.45 63.87,49.99 61.66,49.99 60.55,51.1 60.55,52.28 61.63,53.37 U3087.1 ; v1(82.62,50.65) 85.13,53.16 91.41,53.16 95.7,57.45 95.7,60.76 95.29,61.16 94.91,61.16 92.35,63.73 91.23,63.73 90.11,64.85 90.11,65.81 89.59,66.33 U3077.4
  L03_SIG1 w0.091: v1(73.63,50.47) 72.94,51.16 72.41,51.16 70.71,52.86 v1(69.11,52.86)
  BOTTOM w0.147: v1(73.63,50.47) 73.86,50.47 74.62,49.71 78.96,49.71 79.9,50.65 v1(82.62,50.65)
MMC0_SEL_3V3: length 19.7
  TOP w0.147: U3077.11 92.97,66.33 92.47,66.83 92.47,70.43 93.06,71.02 93.06,81.03 94.66,82.63 R5758.1
OBSCLK0: length 9.9
  TOP w0.147: TP587.1 85.38,106.97 85.54,106.82 v1(85.54,106.2)
  BOTTOM w0.147: RA5.5 85.2,106.43 85.44,106.2 v1(85.54,106.2) 85.54,103.81 84.32,102.59 R5719.2
OSC0: length 5
  TOP w0.147: U48.88 28.69,84.61 28.39,84.92 C217.2 27.81,84.9 27.26,84.36 25.7,84.36 25.56,84.5 Y5.3
OSC1: length 3.3
  TOP w0.147: Y5.1 27.19,83.68 27.33,83.82 C223.2 28.19,83.82 28.57,84.21 U48.89
OSC1_XI: length 5.1
  TOP w0.132: 68.97,76.05 69.3,76.37 U136.C1
  TOP w0.147: 68.97,76.05 68.97,76.05 68.43,75.51 67.78,75.51 66.59,74.32 R3732.1
OSC1_XO: length 5.1
  TOP w0.132: U136.C2 69.69,77.66 69.69,75.49 68.63,74.42
  TOP w0.147: R3733.1 68.47,74.27 68.63,74.42
OSPI0_CSN0: length 6.5
  TOP w0.147: U136.A17 67.29,90.05 66.54,90.81 66.54,92.58 64.62,94.51 R206.2
OSPI0_RESET_OUT0: length 46.7
  TOP w0.132: U136.A16 67.23,89.25 65.32,91.16 65.32,93.12 65.04,93.4
  TOP w0.147: R121.1 71.64,124.71 69.31,122.38 69.31,116.79 66.31,113.79 62.65,113.79 61.46,112.6 61.46,105.16 63.24,103.38 63.24,99.14 64.2,98.17 64.2,97.05 63.24,96.09 63.24,95.2 65.04,93.4
OSPI_CLK: length 29.7
  TOP w0.147: v1(66.59,96.93) 66.24,96.93 65.96,96.65 R197.1 ; v1(67.41,106.71) 67.44,106.71 U28.B2
  L03_SIG1 w0.091: v1(67.41,106.71) 67.18,106.94 65.29,106.94 65.16,107.07 65.16,108.28 65.05,108.39 64.9,108.39 64.79,108.28 64.79,107.03 64.7,106.94 64.56,106.94 64.45,107.04 64.45,107.62 64.35,107.73 64.19,107.73 64.09,107.62 64.09,107.04 63.98,106.94 63.83,106.94 63.72,107.04 63.72,107.62 63.61,107.73 63.46,107.73 63.36,107.62 63.36,107.04 63.25,106.94 63.01,106.94 62.73,106.65 62.73,106.37 62.84,106.26 63.54,106.26 63.64,106.15 63.64,106 63.54,105.89 62.84,105.89 62.73,105.79 62.73,105.63 62.84,105.53 63.54,105.53 63.64,105.42 63.64,105.27 63.54,105.16 62.84,105.16 62.73,105.05 62.73,104.9 62.84,104.8 63.54,104.8 63.64,104.69 63.64,104.54 63.54,104.43 62.84,104.43 62.73,104.32 62.73,104.06 63.21,103.58 64.81,103.58 65.91,102.49 65.91,101.24 66.54,100.61 66.54,98.32 66.95,97.92 66.95,97.28 v1(66.59,96.93)
  BOTTOM w0.147: v1(67.41,106.71) R451.1
OSPI_CS: length 23
  TOP w0.147: v1(66.97,98.5) 66.97,99.46 67.45,99.94 67.45,100.86 67.25,101.06 67.04,101.06 66.9,100.91 66.9,100.41 65.83,99.34 64.91,99.34 64.62,99.04 64.62,98.68 64.79,98.51 65.05,98.51 65.19,98.36 65.19,98.07 65.05,97.92 64.79,97.92 64.62,97.75 R206.1
  L03_SIG1 w0.091: v1(70.53,106.76) 70.2,106.43 70.2,106.15 68.6,104.55 68.6,103.89 67.71,103 66.87,103 66.29,102.41 66.29,101.4 66.97,100.71 v1(66.97,98.5)
  BOTTOM w0.147: v1(70.53,106.76) 70.53,106.53 70.34,106.34 R447.1 70.35,106.06 70.73,105.68 R5827.2
OSPI_DQ0: length 9.6
  TOP w0.147: v1(65.8,105.31) 65.8,104.83 66.02,104.61 RA3.1 ; v1(67.1,109.17) 67.05,109.12 66.85,109.12 U28.D3
  L03_SIG1 w0.091: v1(67.1,109.17) 67.42,109.17 67.71,108.88 67.71,108.23 67.89,108.06 67.89,106.5 67.61,106.22 66.87,106.22 66.64,105.99 66.11,105.99 65.8,105.69 v1(65.8,105.31)
  BOTTOM w0.147: R446.1 67.1,109.63 67.1,109.61 67.12,109.59 67.12,109.19 v1(67.1,109.17)
OSPI_DQ1: length 11.5
  TOP w0.147: v1(65.12,105.51) 65.12,104.95 65.62,104.45 RA3.2 ; U28.D2 67.73,109.06 v1(68.01,109.35)
  L03_SIG1 w0.091: v1(68.01,109.35) 68.57,108.79 68.57,108.22 68.17,107.82 68.17,106.25 66.74,104.83 65.48,104.83 65.12,105.19 v1(65.12,105.51)
  BOTTOM w0.147: R450.1 67.77,109.59 v1(68.01,109.35)
OSPI_DQ2: length 15.2
  TOP w0.147: U28.C4 65.8,107.99 v1(66.21,108.41) ; v1(64.38,104.85) 64.63,104.6 64.83,104.6 65.22,104.22 RA3.3
  L03_SIG1 w0.091: v1(64.38,104.85) 64.76,104.85 65.12,104.5 66.82,104.5 68.45,106.12 68.45,107.7 68.85,108.1 68.85,109.11 68.19,109.77 67.73,109.77 67.56,109.6 66.93,109.6 66.56,109.23 66.56,108.76 v1(66.21,108.41)
  BOTTOM w0.147: R452.1 66.12,108.29 66.21,108.38 v1(66.21,108.41)
OSPI_DQ3: length 14.2
  TOP w0.147: v1(64.64,104.14) 64.64,103.58 64.82,103.4 RA3.4 ; U28.D4 v1(66.13,109.4)
  L03_SIG1 w0.091: v1(64.64,104.14) 66.87,104.14 68.72,105.99 68.72,107.57 69.21,108.05 69.21,109.19 68.35,110.05 67.6,110.05 67.43,109.88 66.61,109.88 v1(66.13,109.4)
  BOTTOM w0.147: R449.1 65.8,109.06 v1(66.13,109.4)
OSPI_DQ4: length 18.9
  TOP w0.147: U28.D5 64.23,108.99 64.09,109.13 v1(63.68,109.13) ; v1(69.08,104.22) 68.44,103.57 RA4.1
  L03_SIG1 w0.091: v1(69.08,104.22) 69.51,104.65 69.51,105 69.77,105.26 70.38,105.26 70.63,105.51 70.63,106.22 71.04,106.63 71.04,109.88 69.72,111.2 67.99,111.2 67.61,110.82 67.61,110.52 67.25,110.15 64.7,110.15 v1(63.68,109.13)
  BOTTOM w0.147: v1(63.68,109.13) R448.1
OSPI_DQ5: length 16.3
  TOP w0.147: v1(67,110.62) 66.73,110.35 U28.E3 ; 68.04,103.04 68.04,104.85 68.95,105.77 70.78,105.77 v1(71.06,106.05)
  L03_SIG1 w0.091: v1(71.06,106.05) 71.44,106.43 71.44,110.24 70.2,111.48 67.86,111.48 v1(67,110.62)
  BOTTOM w0.147: v1(67,110.62) 67.23,110.85 R445.1
OSPI_DQ6: length 10.5
  TOP w0.147: v1(68.23,110.62) 67.98,110.37 67.98,110.24 U28.E2 ; v1(67.45,103.94) 67.45,103.92 67.64,103.74 RA4.3
  L03_SIG1 w0.091: v1(68.23,110.62) 68.55,110.62 69.21,109.96 69.21,109.6 69.49,109.32 69.49,107.92 69,107.44 69,105.87 67.91,104.78 67.91,104.39 v1(67.45,103.94)
  BOTTOM w0.147: R444.1 v1(68.23,110.62)
OSPI_DQ7: length 13
  TOP w0.147: v1(69.23,110.59) 68.98,110.34 68.98,110.24 U28.E1 ; RA4.4 67.24,103.48 67.05,103.68 66.77,103.68 v1(66.52,103.43)
  L03_SIG1 w0.091: v1(66.52,103.43) 67.71,103.43 68.19,103.91 68.19,104.65 69.28,105.74 69.28,106.98 70.45,108.15 70.45,110.01 69.87,110.59 v1(69.23,110.59)
  BOTTOM w0.147: R443.1 v1(69.23,110.59)
OSPI_DQS: length 1.3
  TOP w0.147: U28.C3 67.15,107.57 67.15,107.47 v1(67.18,107.44)
  BOTTOM w0.147: R453.1 v1(67.18,107.44)
OSPI_DQS_SOC: length 36
  TOP w0.147: U136.B19 v1(68.1,92.06)
  L03_SIG1 w0.091: v1(68.1,92.06) 67.4,92.75 67.4,92.92 67.3,93.03 66.64,93.03 66.54,93.14 66.54,93.29 66.64,93.4 67.3,93.4 67.4,93.5 67.4,93.66 67.3,93.76 66.64,93.76 66.54,93.87 66.54,94.02 66.64,94.13 67.3,94.13 67.4,94.24 67.4,94.39 67.3,94.49 66.64,94.49 66.54,94.6 66.54,94.75 66.64,94.86 67.3,94.86 67.4,94.97 67.4,95.12 67.3,95.23 66.64,95.23 66.54,95.33 66.54,95.48 66.64,95.59 67.3,95.59 67.4,95.7 67.4,95.85 67.3,95.96 66.64,95.96 66.54,96.06 66.54,96.22 66.64,96.32 67.3,96.32 67.4,96.43 67.4,97 67.81,97.41 67.81,98.2 67.7,98.3 67.51,98.3 67.4,98.41 67.4,98.56 67.51,98.67 67.7,98.67 67.81,98.78 67.81,98.93 67.7,99.03 67.51,99.03 67.4,99.14 67.4,99.29 67.51,99.4 67.7,99.4 67.81,99.51 67.81,99.66 67.7,99.77 67.51,99.77 67.4,99.87 67.4,100.02 67.51,100.13 67.7,100.13 67.81,100.24 67.81,100.46 66.67,101.6 66.67,102.26 67.05,102.64 68.3,102.64 69.98,104.32 70.53,104.32 72.15,105.94 72.15,106.28 72.06,106.38 71.82,106.38 71.72,106.27 71.72,106.1 70.45,104.83 v1(69.94,104.83)
  BOTTOM w0.132: v1(68.1,92.06) 68.1,92.63 67.87,92.85 R504.1
  BOTTOM w0.147: v1(69.94,104.83) 68.26,106.51 R454.1 68.26,107.44 R453.2
OSPI_INTN: length 1.5
  TOP w0.147: R125.1 R123.1
OSPI_RSTN: length 39.2
  TOP w0.147: R124.1 65.26,127.83 U27.4 67.11,127.83 67.28,128 R5821.2 67.28,130.05 67.51,130.28 69.59,130.28 69.84,130.02 69.84,127.84 70.2,127.48 70.58,127.48 71.49,126.57 71.9,126.57 72.51,125.96 72.51,123.69 69.66,120.85 69.66,116.64 66.46,113.44 64.33,113.44 63.22,112.33 63.22,108.12 63.82,107.52 64.84,107.52 65.18,107.18 65.18,106.54 U28.A4
P2_PP_EXT_ENABLE: length 2.6
  BOTTOM w0.147: R669.1 45.06,19.69 44.17,20.58 U129.49
PCM1_ADDR_0: length 4
  TOP w0.147: U7.24 64.21,152.52 63.93,152.81 63.63,152.81 63.42,152.6 61.98,152.6 ; 61.98,152.6 61.98,152.88 62.31,153.21 R20.2 ; 61.98,152.6 R26.1
PCM1_ADDR_1: length 2.2
  TOP w0.147: R22.1 R23.2 64.44,153.02 64.71,152.74 U7.23
PCM1_AREG: length 2.7
  TOP w0.147: C89.1 64.53,145.71 64.63,145.82 v1(64.63,146.22) 64.71,146.3 U7.2
  BOTTOM w0.147: C378.1 v1(64.63,146.22)
PCM1_BSTOUT: length 3.7
  TOP w0.147: 66.6,145.58 67.12,145.06 C92.2 67.43,145.06 C96.1
  TOP w0.203: 66.6,145.58 66.21,145.97 U7.5
PCM1_DREG: length 2.5
  TOP w0.147: U7.32 62.74,147.8 62.66,147.72 C81.1 61.75,147.72 61.6,147.87 C82.1
PCM1_GPIO1: length 6.6
  TOP w0.147: U7.28 60.23,149.8 59.68,150.34 R34.2 59.43,150.7 59.28,150.55 v1(59.28,150.29)
  BOTTOM w0.147: v1(59.28,150.29) 58.69,150.29 58.46,150.06 R432.1
PCM1_IN1N: length 20.6
  TOP w0.147: R9.2 72.99,162.9 73.35,162.53 73.35,161.85 73.15,161.65 C17.2 73.15,161.57 73.41,161.31 73.41,160.54 v1(73.23,160.36) ; v1(74.95,155.04) 75.2,154.79 75.2,151.96 71.46,148.22 69.24,148.22 69.16,148.3 U7.10
  BOTTOM w0.147: v1(73.23,160.36) 73.41,160.18 73.41,159.23 75.1,157.54 75.1,155.2 v1(74.95,155.04)
PCM1_IN1P: length 21.4
  TOP w0.147: U7.9 69.16,147.8 69.24,147.87 71.6,147.87 75.55,151.82 75.55,154.99 v1(75.68,155.12) ; v1(73.94,160.36) 73.76,160.54 73.76,161.27 C18.2 74.07,161.63 73.71,161.99 73.71,162.42 74.18,162.9 R10.2
  BOTTOM w0.147: v1(75.68,155.12) 75.45,155.34 75.45,157.68 73.76,159.37 73.76,160.18 v1(73.94,160.36)
PCM1_IN2N: length 21.1
  TOP w0.147: v1(73.72,154.21) 73.93,153.99 73.93,152.46 70.69,149.22 69.24,149.22 69.16,149.3 U7.12 ; R7.2 69.51,162.5 69.51,161.88 C15.2 69.57,161.32 69.57,160.54 v1(69.39,160.36)
  BOTTOM w0.147: v1(69.39,160.36) 69.57,160.18 69.57,158.21 70.86,156.92 73.11,156.92 73.95,156.08 73.95,154.45 v1(73.72,154.21)
PCM1_IN2P: length 21.7
  TOP w0.147: U7.11 69.16,148.8 69.24,148.87 70.84,148.87 74.28,152.32 74.28,153.9 v1(74.48,154.09) ; R8.2 69.98,162.5 69.98,161.87 C16.2 69.92,161.32 69.92,160.54 v1(70.1,160.36)
  BOTTOM w0.147: v1(70.1,160.36) 69.92,160.18 69.92,158.35 71,157.27 73.26,157.27 74.35,156.18 74.35,154.22 v1(74.48,154.09)
PCM1_IN3N: length 41
  TOP w0.147: U7.14 69.16,150.3 69.24,150.22 69.99,150.22 72.21,152.44 72.21,155.21 73.81,156.81 75.55,156.81 77.56,158.83 77.56,162.78 79.96,165.17 79.96,169.01 79.03,169.93 76.45,169.93 72,165.48 70.38,165.48 v1(69.92,165.95)
  BOTTOM w0.147: v1(69.92,165.95) 70.1,166.12 70.1,166.91 C334.2 70.05,167.46 70.05,168.07 R408.2
PCM1_IN3P: length 41.3
  TOP w0.147: v1(70.63,165.95) 70.74,165.83 71.85,165.83 76.3,170.28 79.18,170.28 80.31,169.15 80.31,165.02 77.91,162.63 77.91,158.68 75.7,156.46 73.96,156.46 72.56,155.07 72.56,152.3 70.13,149.87 69.24,149.87 69.16,149.8 U7.13
  BOTTOM w0.147: R407.2 70.4,167.97 70.4,167.57 70.73,167.24 C333.2 70.45,166.93 70.45,166.13 v1(70.63,165.95)
PCM1_IN4N: length 43.4
  TOP w0.147: v1(73.76,165.95) 73.96,165.74 73.96,165.4 73.56,164.99 69.58,164.99 69.12,165.45 69.12,167.01 69.92,167.8 69.92,169.11 68.61,170.43 64.54,170.43 62.91,168.79 62.91,162.01 67.97,156.94 68.61,156.94 70,155.56 70,151.72 69.5,151.22 69.24,151.22 69.16,151.3 U7.16
  BOTTOM w0.147: v1(73.76,165.95) 73.85,166.04 73.85,166.06 74.03,166.24 74.03,166.81 C332.2 74.01,167.59 74.01,167.95 R406.2
PCM1_IN4P: length 43.6
  TOP w0.147: v1(74.47,165.95) 74.31,165.79 74.31,165.25 73.7,164.64 69.44,164.64 68.75,165.33 68.75,167.19 69.52,167.97 69.52,168.95 68.44,170.03 64.64,170.03 63.26,168.65 63.26,162.16 68.12,157.29 68.76,157.29 70.35,155.7 70.35,151.57 69.65,150.87 69.24,150.87 69.16,150.8 U7.15
  BOTTOM w0.147: v1(74.47,165.95) 74.38,166.03 74.38,167 C331.2 74.36,167.45 74.36,168.09 R405.2
PCM1_INT_1V8: length 47.4
  TOP w0.147: R34.1 v1(59.68,151.82) ; v1(100.18,142.9) U21.15
  L03_SIG1 w0.091: v1(100.18,142.9) 99.95,143.13 90.59,143.13 v1(88.26,145.47)
  BOTTOM w0.147: v1(59.68,151.82) 60.62,151.82 61.77,152.96 73.35,152.96 75.96,150.35 83.16,150.35 83.24,150.43 84.4,150.43 88.51,146.32 88.51,145.72 v1(88.26,145.47)
PCM1_MCASP1_AXR0: length 2
  TOP w0.147: U7.29 62.6,149.3 62.5,149.2 R38.2
PCM1_RESETN: length 46.4
  TOP w0.147: v1(64.95,159.09) 63.91,159.09 63.6,158.78 63.6,155.86 64.93,154.53 64.93,153.09 65.21,152.81 U7.22 ; U14.4 R78.1 73.84,140.29 74.24,140.69 76.19,140.69 76.5,141 R68.2 75.97,141.89 75.52,142.34 75.52,146.46 76.14,147.08 v1(76.14,155.78)
  BOTTOM w0.147: v1(76.14,155.78) 76.14,159.62 74.78,160.98 68.95,160.98 68.52,160.55 68.52,159.53 68.08,159.09 v1(64.95,159.09)
PCM1_VREF: length 1.2
  TOP w0.147: U7.7 67.21,146.58 67.43,146.36 C87.1
PCM2_ADDR_0: length 3.5
  TOP w0.147: U8.24 55.54,145.2 55.69,145.06 56.95,145.06 57.1,144.91 R62.2 R63.1
PCM2_ADDR_1: length 2.2
  TOP w0.147: U8.23 55.04,145.2 55.32,144.93 R60.2 R61.1
PCM2_AREG: length 2.6
  TOP w0.147: C64.1 55.27,152.11 55.13,151.96 v1(55.13,151.69) 55.04,151.6 U8.2
  BOTTOM w0.147: C368.1 55.29,151.53 v1(55.13,151.69)
PCM2_BSTOUT: length 3.8
  TOP w0.203: U8.5 53.54,151.96 52.74,152.76 C60.2 C54.1
PCM2_IN1N: length 23.8
  TOP w0.147: v1(48.09,157.38) 48.25,157.22 48.25,150.85 49.52,149.59 50.48,149.59 50.54,149.52 U8.10 ; R5.2 56.21,162.5 56.21,161.93 55.96,161.67 C13.2 56.3,161.28 56.3,160.58 v1(56.08,160.36)
  BOTTOM w0.147: v1(48.09,157.38) 48.27,157.56 48.27,158.24 48.63,158.59 55.61,158.59 56.26,159.24 56.26,160.18 v1(56.08,160.36)
PCM2_IN1P: length 23.1
  TOP w0.147: v1(48.8,157.38) 48.6,157.18 48.6,151 49.66,149.94 50.46,149.94 50.54,150.02 U8.9 ; R6.2 56.68,162.5 56.68,161.93 56.93,161.67 C14.2 56.65,161.36 56.65,160.5 v1(56.79,160.36)
  BOTTOM w0.147: v1(56.79,160.36) 56.61,160.18 56.61,159.1 55.76,158.24 48.77,158.24 48.62,158.09 48.62,157.56 v1(48.8,157.38)
PCM2_IN2N: length 24.4
  TOP w0.147: U8.12 50.54,148.52 50.45,148.62 48.3,148.62 46.3,150.62 46.3,157.75 v1(46.13,157.91) ; R3.2 52.37,162.5 52.37,161.93 52.12,161.67 C11.2 52.42,161.32 52.42,160.54 v1(52.24,160.36)
  BOTTOM w0.147: v1(46.13,157.91) 46.16,157.91 46.31,158.06 46.31,158.78 46.94,159.41 52.08,159.41 52.42,159.74 52.42,160.19 v1(52.24,160.36)
PCM2_IN2P: length 23.8
  TOP w0.147: U8.11 50.54,149.02 50.49,148.97 48.45,148.97 46.65,150.77 46.65,157.72 v1(46.84,157.91) ; v1(52.96,160.36) 52.78,160.54 52.78,161.34 C12.2 53.09,161.65 53.09,161.67 52.84,161.93 52.84,162.5 R4.2
  BOTTOM w0.147: v1(52.96,160.36) 52.77,160.17 52.77,159.6 52.23,159.05 47.08,159.05 46.66,158.63 46.66,158.09 v1(46.84,157.91)
PCM2_IN3N: length 43.6
  TOP w0.147: v1(52.77,165.95) 52.95,165.76 52.95,165.41 53.31,165.06 53.84,165.06 54.32,165.54 54.32,167.92 53.43,168.81 52.54,168.81 50.92,170.43 48.37,170.43 45.1,167.17 45.1,150.32 47.82,147.6 50.47,147.6 50.54,147.52 U8.14
  BOTTOM w0.147: v1(52.77,165.95) 52.98,166.15 52.98,166.88 C338.2 53.01,167.57 53.01,167.97 R412.2
PCM2_IN3P: length 40.6
  TOP w0.147: v1(53.48,165.95) 53.3,165.76 53.3,165.56 53.45,165.41 53.7,165.41 53.97,165.68 53.97,167.78 53.29,168.46 52.4,168.46 50.77,170.08 48.51,170.08 45.45,167.03 45.45,150.46 47.95,147.97 50.49,147.97 50.54,148.02 U8.13
  BOTTOM w0.147: R411.2 53.36,168.08 53.36,167.46 53.59,167.24 C337.2 53.33,166.95 53.33,166.1 v1(53.48,165.95)
PCM2_IN4N: length 51.1
  TOP w0.147: v1(56.61,165.95) 56.79,165.76 56.79,165.4 57.14,165.05 57.83,165.05 58.26,165.48 58.26,167.64 55.42,170.48 52.17,170.48 51.12,171.53 48.36,171.53 48.03,171.53 44.32,167.82 44.32,149.91 47.64,146.58 50.48,146.58 50.54,146.52 U8.16
  BOTTOM w0.147: v1(56.61,165.95) 56.84,166.17 56.84,166.86 C336.2 56.82,167.54 56.82,167.99 R410.2
PCM2_IN4P: length 48
  TOP w0.147: v1(57.32,165.95) 57.14,165.78 57.14,165.55 57.29,165.4 57.69,165.4 57.91,165.63 57.91,167.49 55.28,170.13 51.97,170.13 50.96,171.14 48.2,171.14 44.67,167.62 44.67,150.05 47.79,146.93 50.46,146.93 50.54,147.02 U8.15
  BOTTOM w0.147: v1(57.32,165.95) 57.19,166.08 57.19,166.95 C335.2 57.2,167.46 57.2,168.08 R409.2
PCM2_INT_1V8: length 48.6
  TOP w0.147: v1(60.39,146.25) 60.39,146.96 59.35,148.01 R46.1 ; v1(98.29,142.57) 98.77,143.05 99.53,143.05 99.68,142.9 U21.16
  L03_SIG1 w0.091: v1(98.29,142.57) 89.55,142.57 v1(86.68,145.44)
  BOTTOM w0.147: v1(86.68,145.44) 86.68,146.81 85.64,147.85 83.63,147.85 82.85,148.64 74.62,148.64 73.68,149.58 62.83,149.58 60.39,147.14 v1(60.39,146.25)
PCM2_MCASP1_AXR0: length 1.3
  BOTTOM w0.147: R433.1 59.93,148.52 60.13,148.72 R431.2
PCM2_RESETN: length 24.1
  TOP w0.147: U8.22 54.54,144.97 v1(54.68,144.83)
  L03_SIG1 w0.091: v1(54.68,144.83) 53.79,145.72 53.79,155.85 v1(55.31,157.38)
  BOTTOM w0.147: v1(55.31,157.38) 58.63,157.38 60.57,159.32 R415.2 R416.1 62.56,160 62.66,160.11 U75.4
PCM2_VREF: length 1.2
  TOP w0.147: C65.1 52.32,151.73 52.54,151.51 U8.7
PCM6240_MCASP1_ACLKR: length 72.7
  TOP w0.147: R179.1 79.07,106.13 80.51,107.57 80.51,109.22 78.12,111.61 78.12,114.73 76.98,115.87 74.03,115.87 72.76,117.14 v1(70.48,117.14) ; U7.30 62.45,148.8 62.2,148.54 60.6,148.54 60.3,148.24 v1(60.3,147.84) 59.12,149.02 U8.30
  L03_SIG1 w0.091: v1(70.48,117.14) 68.14,117.14 66.51,118.77 66.51,122.33 66.85,122.66 66.85,129.4 63.67,132.58 63.67,143.33 62.32,144.68 62.32,147.27 61.76,147.84 v1(60.3,147.84)
PCM6240_MCASP1_AFSR: length 68
  TOP w0.147: v1(57.55,149.52) U8.31 ; R5640.2 78.48,106.17 80.05,107.75 80.05,109.04 77.39,111.71 77.39,114.59 76.58,115.39 73.53,115.39 72.74,116.18 v1(70.48,116.18) ; U7.31 v1(62.66,148.3)
  L03_SIG1 w0.091: v1(57.55,149.52) 59.11,149.52 59.59,150.01 60.95,150.01 v1(62.66,148.3) 64.08,146.88 64.08,141.22 64.87,140.43 64.87,133.29 67.2,130.96 67.2,122.61 66.79,122.2 66.79,121.44 70.9,117.33 70.9,116.61 v1(70.48,116.18)
PCM6240_MCASP1_AXR0: length 67.7
  TOP w0.147: R38.1 60.11,149.2 v1(59.78,149.53)
  L03_SIG1 w0.091: v1(59.78,149.53) 59.78,147.6 60.9,146.48 60.9,145.54 61.85,144.59 61.85,141.21 63.29,139.78 63.29,130.58 65.37,128.5 65.37,127.97 65.48,127.87 66.01,127.87 66.11,127.76 66.11,127.61 66.01,127.5 65.48,127.5 65.37,127.39 65.37,127.24 65.48,127.14 66.01,127.14 66.11,127.03 66.11,126.88 66.01,126.77 65.48,126.77 65.37,126.66 65.37,126.51 65.48,126.4 66.01,126.4 66.11,126.3 66.11,126.15 66.01,126.04 65.48,126.04 65.37,125.93 65.37,125.78 65.5,125.65 66.18,125.65 66.29,125.54 66.29,125.39 66.18,125.28 65.46,125.28 65.37,125.19 65.37,125.05 65.5,124.92 66.18,124.92 66.29,124.81 66.29,124.66 66.18,124.55 65.46,124.55 65.37,124.46 65.37,124.32 65.5,124.18 66.18,124.18 66.29,124.08 66.29,123.93 66.18,123.82 65.51,123.82 65.42,123.73 65.42,119.33 73.37,111.38 73.37,105.41 v1(71.42,103.45)
  BOTTOM w0.147: R500.2 73,102.76 72.31,103.45 v1(71.42,103.45) ; R431.1 59.95,149.7 v1(59.78,149.53)
PCM6240_MCASP1_AXR2: length 66.2
  L03_SIG1 w0.091: v1(71.32,102.06) 70.83,102.54 70.83,103.5 73.09,105.77 73.09,111.25 65.04,119.3 65.04,122.02 64.95,122.11 64.11,122.11 64,122.22 64,122.37 64.11,122.48 64.99,122.48 65.09,122.58 65.09,122.73 64.99,122.84 64.13,122.84 64.03,122.95 64.03,123.1 64.13,123.21 64.99,123.21 65.09,123.31 65.09,123.47 64.99,123.57 64.18,123.57 64.08,123.68 64.08,123.83 64.18,123.94 64.99,123.94 65.09,124.05 65.09,124.2 64.99,124.3 64.26,124.3 64.15,124.41 64.15,124.56 64.26,124.67 64.99,124.67 65.09,124.78 65.09,124.93 64.99,125.04 64.26,125.04 64.15,125.14 64.15,125.29 64.26,125.4 64.99,125.4 65.09,125.51 65.09,128.32 62.98,130.43 62.98,137.72 60.5,140.21 v1(60.5,145.34)
  BOTTOM w0.147: R190.2 71.16,100.41 71.32,100.56 v1(71.32,102.06) ; R435.1 58.46,146.99 59.63,145.82 60.01,145.82 v1(60.5,145.34)
PD_GPIO0: length 1.6
  BOTTOM w0.147: R674.2 35.6,17.98 35.8,18.18 U129.16
PD_HRESET: length 3.5
  TOP w0.147: v1(43.86,23.96) 44.13,24.23 C301.1
  BOTTOM w0.147: U129.44 44.04,22.58 44.5,23.04 R662.1 44.07,23.6 43.97,23.7 43.97,23.84 v1(43.86,23.96)
PD_I2C_IRQ: length 147.5
  TOP w0.147: U18.6 62.5,133.86 62.35,133.71 v1(62.35,133.12)
  L03_SIG1 w0.091: v1(38.37,133.96) 38.37,131.09 36.34,129.06 36.34,101.14 33.06,97.87 33.06,96.27 34.41,94.92 35.45,94.92 37.3,93.07 37.3,87.3 38.29,86.32 38.29,84.83 36.34,82.88 36.34,81.74 34.46,79.86 34.46,74.6 33.77,73.91 33.77,70.61 33.16,70 33.16,63.78 33.65,63.3 33.65,60.73 33.37,60.45 33.27,60.45 30.8,57.99 30.8,55.88 31.31,55.37 31.95,55.37 34.1,53.21 34.1,42.27 35.7,40.67 v1(36.21,40.67)
  BOTTOM w0.147: v1(38.37,133.96) 60.65,133.96 61.49,133.12 v1(62.35,133.12) ; v1(36.21,40.67) 36.21,28.3 37.33,27.18 38.4,27.18 38.97,26.6 R645.2 39.16,26.26 39.29,26.13 R655.1
PD_MS_I2C1_IRQ: length 1.3
  BOTTOM w0.147: U129.29 37.45,24.19 R660.2
PD_MS_I2C1_SCL: length 10
  L03_SIG1 w0.091: v1(35.51,23.29) 35.09,23.72 35.09,24.9 34.13,25.86 v1(34.13,29.84)
  BOTTOM w0.147: R633.1 v1(34.13,29.84) ; U129.27 36.22,22.58 v1(35.51,23.29) 35.43,23.38 R664.2
PD_MS_I2C1_SDA: length 12.9
  L03_SIG1 w0.091: v1(35.86,24.26) 35.86,24.58 36.37,25.09 36.37,29.73 v1(33.71,32.38)
  BOTTOM w0.147: R658.2 35.26,24.45 35.46,24.26 v1(35.86,24.26) 35.86,23.86 36.07,23.65 36.07,23.3 36.39,22.98 U129.28 ; R627.1 v1(33.71,32.38)
PD_S_I2C2_IRQ: length 1.6
  BOTTOM w0.147: U129.34 39.45,24.34 39.39,24.41 39.39,24.77 39.29,24.87 R655.2
PD_S_I2C2_SCL: length 2
  BOTTOM w0.147: U129.32 38.65,24.1 38.65,24.1 38.65,24.21 38.47,24.38 38.16,24.38 37.76,24.78 R657.2
PD_S_I2C2_SDA: length 1.7
  BOTTOM w0.147: R656.2 38.52,24.84 39.01,24.36 39.01,24.33 39.03,24.31 39.03,24.28 39.05,24.26 U129.33
PD_SPI_CLK: length 22
  TOP w0.147: U69.6 41.05,27.37 40.84,27.59 v1(40.84,28.04)
  L03_SIG1 w0.091: v1(40.84,28.04) 40.84,28.47 37.33,31.98 37.33,36.78 35.31,38.8 31.99,38.8 J21.7
  BOTTOM w0.147: v1(40.84,28.04) 41.57,27.31 R652.2
PD_SPI_MISO: length 17.8
  TOP w0.147: U69.2 37.75,28.64 v1(38.05,28.94)
  L03_SIG1 w0.091: J21.5 34.33,35.48 35.58,34.24 35.58,31.42 v1(38.05,28.94)
  BOTTOM w0.147: v1(38.05,28.94) 39.32,28.94 40.38,27.89 40.38,26.75 40.23,26.6 R644.2 39.92,26.28 40.05,26.15 R654.2
PD_SPI_MOSI: length 23.5
  TOP w0.147: U69.5 41.05,26.1 v1(40.81,26.34)
  L03_SIG1 w0.091: v1(40.81,26.34) 40.05,27.1 40.05,28.75 36.87,31.93 36.87,36.75 35.98,37.64 33.01,37.64 32.25,36.88 29.81,36.88 J21.8
  BOTTOM w0.147: R653.2 v1(40.81,26.34)
PD_SPI_SS: length 24.8
  TOP w0.147: v1(40.02,30.68) 39.25,29.91 U69.1
  L03_SIG1 w0.091: J21.9 33.95,40.56 37.61,36.91 37.61,32.49 39.41,30.68 v1(40.02,30.68)
  BOTTOM w0.147: v1(40.02,30.68) 40.02,29.57 42.33,27.25 R646.2 R651.2
PD_VIN_3V3: length 1.8
  TOP w0.147: C320.2 40.63,15.88 v1(40.86,16.11)
  BOTTOM w0.147: v1(40.86,16.11) 41.05,16.3 U129.5
PMIC_EN: length 2
  TOP w0.147: R317.2 41.62,52.69 41.32,52.99 U56.17
PMIC_ENABLE: length 18
  TOP w0.147: U2356.10 26.67,52 26.87,52.2 26.87,52.65 26.64,52.88 24.3,52.88 v1(17.87,59.31) ; U54.6 20.59,61.5 20.32,61.77 v1(19.5,61.77)
  L03_SIG1 w0.091: v1(19.5,61.77) 18.79,61.77 17.87,60.86 v1(17.87,59.31)
PMIC_I2C_SCL_1V8: length 13.2
  TOP w0.147: U56.1 36.57,58.36 36.32,58.61 R296.2 35.79,58.86 35.6,59.05 33.55,59.05 33.11,59.49 31.42,59.49 30.62,60.28 30.62,62.97 29.3,64.29 TP72.1
PMIC_I2C_SDA_1V8: length 14.7
  TOP w0.147: TP73.1 27.62,63.4 29.35,63.4 30.27,62.48 30.27,60.14 31.35,59.06 31.89,59.06 32.3,58.65 R294.2 32.65,57.91 32.9,57.66 34.4,57.66 34.83,58.09 36.21,58.09 36.44,57.86 U56.2
PMIC_INT_B: length 11.7
  TOP w0.147: R288.2 50.82,61.12 TP70.1 50.15,59.61 R300.2 R299.2 48.23,59.61 48,59.84 43.86,59.84 43.38,59.36 42.49,59.36 42.32,59.19 U56.27
PMIC_INTN: length 58.6
  TOP w0.147: v1(52.16,67.67) 52.16,67.21 52.01,67.06 52.01,60.71 51.45,60.15 51.3,60.15 51.15,59.99 51.15,59.23 50.87,58.95 50.46,58.95 50.37,59.05 R300.1 ; U136.P3 v1(78.5,78.46)
  L03_SIG1 w0.091: v1(60.29,70.36) 56.99,67.06 52.77,67.06 v1(52.16,67.67) ; v1(77.23,68.35) 78.15,69.27 78.15,72.09 78.76,72.69 78.76,75.92 78.87,76.04 78.87,78.08 v1(78.5,78.46)
  BOTTOM w0.132: v1(78.5,78.46) 78.9,78.05 78.9,77.49 79.13,77.26 80.77,77.26
  BOTTOM w0.147: R205.1 84.13,75.76 83.88,75.51 81.91,75.51 81.6,75.82 81.6,76.43 80.77,77.26 ; v1(60.29,70.36) 70.55,70.36 71.95,68.96 72.36,68.96 73.04,69.65 76.47,69.65 77.23,68.88 v1(77.23,68.35)
PMIC_LPM_EN0: length 104.8
  TOP w0.147: v1(57.25,83.97) 57.25,84.36 57.37,84.48 TP75.1 58.62,83.69 59.17,83.69 59.34,83.53 R5750.2 ; U2356.2 24.55,51.5 23.97,50.93 v1(23.97,49.81) ; v1(31.49,52.58) 30.5,52.58 29.38,51.46 29.38,49.02 29.05,48.69 27.81,48.69 v1(27.42,49.07) 27.72,49.37 R5737.1 27.72,50.33 27.55,50.5 U2356.7
  L03_SIG1 w0.091: v1(57.25,83.97) 56.41,83.12 56.41,81.99 56.76,81.64 56.76,80.57 56.08,79.88 56.08,69.42 54.25,67.59 52.85,67.59 52.34,68.1 51.99,68.1 51.55,67.67 51.55,62.53 53.26,60.83 53.26,57.73 52.72,57.2 50.36,57.2 49.62,56.46 49.62,49.58 47.72,47.68 47.72,47.02 48.28,46.46 48.28,42.29 47.46,41.48 47.46,38.38 46.55,37.47 43.1,37.47 42.23,38.33 37.53,38.33 34.63,41.24 32.55,41.24 32.07,41.71 32.07,44.42 32.99,45.34 32.99,51.08 v1(31.49,52.58)
  BOTTOM w0.147: v1(23.97,49.81) 26.69,49.81 v1(27.42,49.07)
PMIC_LPM_SEL: length 18.4
  TOP w0.147: U2356.5 25.03,50 24.88,49.86 24.88,49.2 v1(25.29,48.79) ; U2356.1 v1(24.31,52) R318.1 23.67,51.29 23.13,50.74 23.13,48.34 23.64,47.83 J16.1
  L03_SIG1 w0.091: v1(24.31,52) 25.29,51.02 v1(25.29,48.79)
PMIC_NSLEEP: length 17
  TOP w0.147: U2356.6 26.64,50 26.87,49.78 26.87,48.72 27.37,48.21 29.23,48.21 29.74,48.72 29.74,50.9 30.19,51.36 33.7,51.36 34.38,52.04 35.2,52.04 36.34,53.19 37.49,53.19 37.82,53.52 U56.10
PMIC_POWERGOOD: length 49.5
  TOP w0.147: v1(51.55,61.32) 51.1,61.77 48.41,61.77 48.04,61.4 R290.1 ; v1(24.45,63.35) 24.45,66.98 25.57,68.1 31.88,68.1 34.34,70.55 34.34,71.21 35.82,72.69 40.51,72.69 41.37,71.84 41.37,69.67 43.86,67.17 48.24,67.17 v1(49.29,68.22)
  L03_SIG1 w0.091: v1(51.55,61.32) 50.46,61.32 49.65,62.13 49.65,65.96 50.06,66.37 50.06,67.46 v1(49.29,68.22)
  BOTTOM w0.147: U86.1 24.57,63.82 24.45,63.7 v1(24.45,63.35)
PMIC_RSTOUT: length 55.6
  TOP w0.147: v1(45.89,44.78) 46.53,44.15 48.66,44.15 48.99,44.48 51.48,44.48 52.11,45.11 56.25,45.11 58.44,47.29 59,47.29 59.53,47.83 61.13,47.83 63.24,45.72 65.58,45.72 65.85,45.44 67.41,45.44 67.76,45.8 67.76,46.58 67.44,46.91 R286.1 ; U56.28 41.82,59.44 v1(41.93,59.54) 42.1,59.72 43.17,59.72 43.73,60.27 47.21,60.27 47.49,60.55 R290.2 R291.2 49.48,60.55 TP67.1
  BOTTOM w0.147: v1(41.93,59.54) 42.96,59.54 43.2,59.31 43.2,58.27 43.99,57.48 43.99,56.86 43.99,55.37 46.91,52.45 46.91,52.2 47.24,51.87 47.24,46.93 47.39,46.78 47.39,45.44 46.73,44.78 v1(45.89,44.78)
PORT1_15W: length 19.4
  TOP w0.147: v1(32.89,26.39) 33.55,26.39 34.21,27.05 34.21,29.08 34.97,29.84 34.97,31.39 35.86,32.28 35.86,33.65 35.71,33.8 R5767.1 35.3,34.29 35.08,34.51 U71.2
  BOTTOM w0.147: v1(32.89,26.39) 32.89,19.79 33.77,18.9 R386.1
PORT2_15W: length 17.1
  TOP w0.147: U71.1 34.6,34.56 34.33,34.28 R381.1 33.72,33.76 33.1,33.13 33.1,27.58 v1(33.42,27.25)
  BOTTOM w0.147: R390.1 33.88,19.81 33.42,20.27 v1(33.42,27.25)
PP1_CABLE: length 1.6
  TOP w0.147: v1(35.77,21.77) 35.88,21.66 C309.1
  BOTTOM w0.147: v1(35.77,21.77) 35.79,21.78 U129.25
PP2_CABLE: length 3.3
  BOTTOM w0.147: U129.46 44.11,21.78 44.19,21.7 44.73,21.7 C631.1 R665.2
PRI/SEC_REF_SEL: length 3.1
  TOP w0.147: U15.4 86.89,57.64 86.14,56.88 R75.2 R76.1
RESET_STATZ: length 20.3
  TOP w0.147: v1(63.04,72.82) TP592.1 ; v1(73.7,80.06) U136.H4
  BOTTOM w0.132: 72.41,78.64 73.04,79.27 73.04,79.53 73.56,80.06 v1(73.7,80.06) ; 72.41,78.64 72.19,78.85 70.33,78.85 70.1,78.62 70.1,78.29 70.33,78.06 70.65,78.06 ; 72.41,78.64 72.41,78.21 72.56,78.05 R5738.1 ; 71.26,77.65 71.11,77.8 70.93,77.8 70.68,78.05
  BOTTOM w0.147: 71.26,77.65 71.26,75.44 69.94,74.12 64.33,74.12 v1(63.04,72.82) ; 70.68,78.05 70.66,78.05 70.65,78.06
RESETSTATZ: length 177.5
  TOP w0.147: v1(68.12,53.92) 70.76,53.92 71.54,53.14 71.54,51.28 71.63,51.19 R366.1 ; v1(111.45,50.75) 109.19,53 109.19,56.37 v1(110.1,57.28) ; U18.24 64.05,137.69 63.83,137.91 62.59,137.91 v1(62.27,137.59) ; v1(95.72,52.16) 95.98,52.41 95.98,55.19 97.48,56.69 97.48,59.61 v1(98.32,60.45) 98.32,65.71 96.39,67.63 U3077.13
  L03_SIG1 w0.091: v1(68.12,53.92) 68.12,58.09 67.23,58.98 67.23,59.97 63.42,63.78 63.09,63.78 62.66,64.21 62.66,71.63 63.46,72.44 63.46,73.11 59.8,76.76 59.8,80.79 60.93,81.92 60.93,87.35 61.05,87.48 61.05,92.84 62.12,93.9 62.12,97.61 62.37,97.87 62.37,99.64 61.33,100.69 61.33,125.01 61.74,125.43 61.74,132.79 61.18,133.35 61.18,136.5 v1(62.27,137.59)
  BOTTOM w0.147: v1(68.12,53.92) 67.48,54.56 67.48,57.02 67.64,57.19 68.82,57.19 69,57 74.09,57 74.36,57.27 74.36,57.33 74.73,57.71 75.13,57.71 75.43,57.4 77.49,57.4 77.7,57.62 78.42,57.62 83.69,52.34 88.59,52.34 89.4,51.54 95.1,51.54 v1(95.72,52.16) ; v1(111.45,50.75) 111.45,49.13 111.45,49.12 R605.1 ; v1(98.32,60.45) 98.67,60.45 98.82,60.6 99.08,60.6 99.41,60.27 99.41,59.87 100.42,58.85 108.52,58.85 v1(110.1,57.28)
RESETSTATZ_1V8: length 393.9
  TOP w0.147: v1(88.41,53.98) 88.41,54.45 TP100.1 88.55,55.28 88.7,55.43 U15.8 ; v1(112.64,96.16) 112.64,95.1 112.48,94.94 U26.2 ; v1(126.48,112.37) 126.48,122.98 125.89,123.58 J12.55 ; v1(126.33,68.61) 126.83,68.61 U2.3 126.88,69.01 126.59,69.3 126.59,72.09 123.72,74.96 123.72,83.77 122.26,85.23 v1(122.26,90.92) ; U2348.2 R5760.2 56.69,111.67 56.46,111.9 56.46,112.17 v1(56.71,112.42) ; v1(68.09,126.9) 68.1,126.88 U27.2 ; J13.55 28.68,142.84 35.32,136.19 v1(35.32,132.79) ; v1(99.13,131.95) 99.48,132.31 99.48,134.16 101.18,135.86 U21.28 ; v1(76.85,155.85) 76.85,155.5 76.5,155.14 76.5,144.39 77.46,143.42 77.46,141.3 76.65,140.49 76.65,139.12 76.91,138.86 U14.2 79.06,138.86 79.77,138.15 79.77,135.64 80.4,135.02 R377.2 80.74,134.67 80.48,134.42 80.48,132.59 v1(80.94,132.13) ; U3077.2 89.23,67.63 v1(90.09,66.78) 90.48,66.38 90.48,64.98 91.2,64.26 92.36,64.26 95.1,61.52 95.45,61.52 96.06,60.91 96.06,57.3 90.75,51.99 v1(90.04,51.99)
  L03_SIG1 w0.091: v1(90.04,51.99) 88.41,53.62 v1(88.41,53.98) ; v1(59.3,72.11) 57.32,74.09 57.32,81.89 56.98,82.23 56.98,82.66 57.95,83.64 57.95,85.52 57.77,85.71 57.77,89.42 58.69,90.35 58.69,98.65 58.39,98.96 58.39,99.31 56.84,100.86 56.84,112.29 v1(56.71,112.42) 56.08,113.06 56.08,123.24 57.85,125.02 v1(57.85,130.48) ; v1(112.64,96.16) 112.64,102.29 120.67,110.31 124.43,110.31 v1(126.48,112.37) ; v1(72.15,69.42) 71.67,69.9 v1(71.67,73.91)
  BOTTOM w0.147: U75.2 67.07,161.06 67.35,161.33 74.93,161.33 76.85,159.41 v1(76.85,155.85) ; v1(35.32,132.79) 36.92,132.79 37.46,132.26 46.96,132.26 47.87,131.34 56.99,131.34 v1(57.85,130.48) 57.85,129.85 60.33,127.37 64.52,127.37 64.99,126.9 v1(68.09,126.9) 69.49,128.3 71.49,128.3 74.24,131.04 74.64,131.04 75.4,131.8 79.88,131.8 80.21,132.13 v1(80.94,132.13) 85.54,132.13 86.48,133.07 92.22,133.07 92.6,132.69 97.1,132.69 97.83,131.95 v1(99.13,131.95) ; v1(112.64,96.16) 117.01,96.16 v1(122.26,90.92) ; R5738.2 72.56,75.51 71.95,74.9 71.95,74.4 71.67,74.12 v1(71.67,73.91) 70.68,72.92 66.51,72.92 64.85,71.25 59.8,71.25 59.3,71.76 v1(59.3,72.11) ; v1(126.33,68.61) 126.68,68.26 126.68,64.76 124.2,62.28 122.73,62.28 121.36,60.91 116.8,60.91 115.41,62.31 97.88,62.31 97.05,61.47 96.16,61.47 90.85,66.78 v1(90.09,66.78) 84.6,66.78 82.39,68.99 80.64,68.99 79.89,69.74 77.27,69.74 76.88,70.13 72.86,70.13 v1(72.15,69.42)
RGMII1_INH_3V3: length 3.3
  TOP w0.147: J18.26 88.01,42.79 87.67,43.13 87.67,44.27 87.32,44.63 TP65.1
RGMII1_RX_ER: length 12.1
  TOP w0.147: TP99.1 89.6,49.64 v1(89.4,49.83) ; v1(90.29,40.74) 90.81,40.22 J18.39
  L03_SIG1 w0.091: v1(90.29,40.74) 90.29,48.95 v1(89.4,49.83)
RGMII1_RX_LINK: length 27.8
  TOP w0.147: R360.2 74.59,44.42 TP98.1 73.75,43.58 v1(73.75,42.95) ; J18.43 91.61,38.07 90.72,37.19 v1(90.21,37.19)
  BOTTOM w0.147: v1(90.21,37.19) 89.96,37.44 89.27,37.44 89.26,37.43 88.88,37.43 88.47,37.84 85.46,37.84 84.79,37.17 75.42,37.17 73.5,39.09 73.5,42.7 v1(73.75,42.95)
RGMII2_INH_3V3: length 5.9
  TOP w0.147: J19.26 120.44,46.76 120.21,46.99 TP59.1
RGMII2_RX_ER: length 17.4
  TOP w0.147: v1(128.24,47.4) 127.91,47.07 TP89.1 ; v1(122.98,36.41) 123.24,36.67 J19.39
  L03_SIG1 w0.091: v1(128.24,47.4) 126.18,45.34 126.18,40.74 122.98,37.54 v1(122.98,36.41)
RGMII2_RX_LINK: length 19.1
  TOP w0.147: v1(128.24,46.37) 127.74,45.87 126.8,45.87 TP91.1 ; v1(123.78,36.4) 124.04,36.66 J19.43
  L03_SIG1 w0.091: v1(128.24,46.37) 126.76,44.89 126.76,38.63 124.53,36.4 v1(123.78,36.4)
  BOTTOM w0.147: v1(128.24,46.37) 128.41,46.2 R347.2
SD_MMC0_CLK: length 44.4
  TOP w0.147: R202.1 129.35,74.07 129.57,74.29 R54.1 129.01,74.95 v1(128.99,74.93) 128.52,75.4 U10.6
  L03_SIG1 w0.091: v1(96.99,75.82) 98.54,77.37 112.49,77.37 115.59,74.27 123.41,74.27 124.35,75.2 128.72,75.2 v1(128.99,74.93)
  BOTTOM w0.147: v1(96.99,75.82) 96.99,76.71 97.33,77.04 U57.41 ; v1(128.99,74.93) 130.31,74.93 130.73,75.35 130.73,76.5 131.25,77.03 J26.5
SD_MMC0_CMD: length 43.5
  TOP w0.147: R66.1 125.84,77.33 126.07,77.57 v1(126.31,77.57) 126.31,77.09 126.49,76.9 U10.1
  L03_SIG1 w0.091: v1(100.08,85.63) 100.08,84.59 104.61,80.06 114.09,80.06 116.25,77.9 119.12,77.9 120.03,78.81 125.06,78.81 v1(126.31,77.57)
  BOTTOM w0.147: v1(126.31,77.57) 126.99,76.88 126.99,74.42 127.6,73.81 130.04,73.81 131.06,74.83 J26.3 ; U57.23 v1(100.08,85.63)
SD_MMC0_D0: length 43
  TOP w0.147: U10.8 128.7,76.4 128.98,76.69 v1(128.98,76.83) R65.1
  L03_SIG1 w0.091: v1(100.25,77.9) 100.68,78.33 101.81,78.33 101.91,78.23 101.91,78.09 102.02,77.98 102.17,77.98 102.28,78.09 102.28,78.23 102.39,78.33 102.54,78.33 102.64,78.23 102.64,78.09 102.75,77.98 102.9,77.98 103.01,78.09 103.01,78.23 103.12,78.33 103.27,78.33 103.38,78.23 103.38,78.09 103.48,77.98 103.63,77.98 103.74,78.09 103.74,78.23 103.85,78.33 112.44,78.33 115.18,75.59 127.74,75.59 v1(128.98,76.83)
  BOTTOM w0.147: v1(128.98,76.83) 128.54,76.39 128.54,75.66 128.78,75.42 129.85,75.42 130.17,75.74 130.17,76.45 130.73,77.01 130.73,78.33 131.62,79.23 J26.7 ; v1(100.25,77.9) 100.02,78.13 U57.38
SD_MMC0_D1: length 42.6
  TOP w0.147: U10.7 v1(129.03,75.9) 129.56,75.9 R57.1
  L03_SIG1 w0.091: v1(129.03,75.9) 129.52,75.9 129.66,76.05 129.66,76.91 129.1,77.47 128.08,77.47 126.59,75.97 120.08,75.97 119.3,76.76 115.05,76.76 112.97,78.84 100.45,78.84 v1(100.07,79.22)
  BOTTOM w0.147: v1(100.07,79.22) 99.98,79.13 U57.36 ; J26.8 131.18,80.33 129.65,78.81 129.65,76.07 129.49,75.9 v1(129.03,75.9)
SD_MMC0_D2: length 43
  TOP w0.147: U10.2 v1(126.29,76.4) R64.1
  L03_SIG1 w0.091: v1(101.31,82.3) 101.31,79.98 101.92,79.38 113.81,79.38 115.87,77.32 119.52,77.32 120.44,76.4 v1(126.29,76.4)
  BOTTOM w0.147: J26.1 126.42,72.63 125.52,73.53 125.52,75.64 v1(126.29,76.4) ; v1(101.31,82.3) 100.98,82.63 U57.29
SD_MMC0_D3: length 44.2
  TOP w0.147: R55.1 125.63,75.07 125.93,74.78 v1(126.03,74.78) 126.28,75.03 126.28,75.76 126.43,75.9 U10.3
  L03_SIG1 w0.091: v1(126.03,74.78) 124.45,73.2 115.54,73.2 111.9,76.83 99.79,76.83 v1(97.86,74.9)
  BOTTOM w0.147: U57.39 98.33,76.77 97.96,76.4 97.96,75.03 97.86,74.93 v1(97.86,74.9) ; J26.2 131,73.73 130.47,73.2 127.14,73.2 126.03,74.32 v1(126.03,74.78)
SD_MMC0_SDCD: length 63.1
  TOP w0.147: U12.5 v1(120.73,78.13) R70.1 121.88,78.13 122.24,77.78 122.24,76.83 120.19,74.78 v1(120.19,68.91) ; U136.N2 v1(77.7,77.65)
  BOTTOM w0.147: v1(120.19,68.91) 118.92,67.64 112.16,67.64 111.4,66.88 110.1,66.88 109.54,66.32 96.89,66.32 92.27,70.94 92.27,71.96 89.4,74.83 85.9,74.83 85.49,75.23 81.7,75.23 81.32,75.62 81.32,76.16 80.9,76.58 79.62,76.58 79.49,76.45 78.33,76.45 77.7,77.08 v1(77.7,77.65) ; J26.9 v1(120.73,78.13)
SEC_REF_N: length 2.1
  TOP w0.147: U15.2 R74.1
SEC_REF_P: length 2.3
  TOP w0.147: U15.1 86.74,59.14 86.26,59.61 R73.1
SEL_XDS: length 59.1
  TOP w0.147: U39.5 29.22,103.91 29.33,104.01 29.33,104.5 v1(28.97,104.85) 29.33,105.21 31.41,105.21 31.64,105.44 32.99,105.44 v1(34.1,104.32) ; v1(29.02,102.23) 29.02,101.75 27.63,100.36 27.63,99.74 25.7,97.81 v1(25.7,96.72)
  L03_SIG1 w0.091: v1(28.97,104.85) 28.67,104.55 28.67,102.59 v1(29.02,102.23) ; v1(32.94,81.31) 34.87,83.24 34.87,85.45 34.61,85.7 34.23,85.7 33.29,86.64 33.29,87.58 34.41,88.7 34.41,89.48 35.07,90.14 35.07,90.65 v1(34.56,91.16) 31.72,91.16 31.16,90.6 30.45,90.6 30.07,90.98 30.07,94.21 31.11,95.25 31.11,97.64 34.1,100.63 v1(34.1,104.32)
  BOTTOM w0.147: U93.4 27.51,94.27 27.31,94.47 25.94,94.47 25.45,94.97 25.45,96.47 v1(25.7,96.72) ; v1(32.94,81.31) 32.43,81.31 31.64,82.09 31.64,82.48 31.89,82.73 U109.4 ; U97.16 34.46,91.78 34.64,91.6 34.64,91.24 v1(34.56,91.16) 33.85,91.16 33.63,91.38 U97.1
SEL_XDS110_INV: length 79.7
  TOP w0.147: v1(43.17,104.04) 43.2,104.06 43.2,104.11 43.26,104.18 J14.8 ; v1(41.57,116.43) 42.03,115.98 44.98,115.98 45.29,116.29 U2355.2 ; v1(34.87,89.26) 33.32,89.26 32.94,89.64 32.43,89.64 32.17,89.89 32.17,93.65 31.72,94.11 31.09,94.11 29.65,95.55 v1(29.28,95.55)
  L03_SIG1 w0.091: v1(34.87,89.26) 34.87,88.67 33.57,87.38 33.57,86.77 34.36,85.98 34.74,85.98 35.15,85.57 35.15,83.21 35.35,83.01 v1(35.35,82.32) ; v1(43.17,104.04) 41.72,105.49 41.72,108.13 39.39,110.46 39.39,114.25 v1(41.57,116.43) ; v1(29.28,95.55) 29.28,96.82 33.29,100.84 33.29,105.49 34.46,106.65 v1(34.46,114.1)
  BOTTOM w0.147: v1(43.17,104.04) 43.17,104.85 43.7,105.38 U90.4 ; v1(29.28,95.55) 29.28,95.35 29.1,95.17 R531.2 R536.1 28.17,94.4 27.63,94.95 27.18,94.95 26.86,95.27 U93.2 ; U110.1 35.5,82.97 35.35,82.82 v1(35.35,82.32) 35.24,82.21 35.24,81.88 35.38,81.74 35.6,81.74 35.79,81.93 U110.16 ; U102.5 34.52,88.95 34.83,89.26 v1(34.87,89.26) ; v1(34.46,114.1) 36.14,114.1 37.71,115.67 40.81,115.67 v1(41.57,116.43)
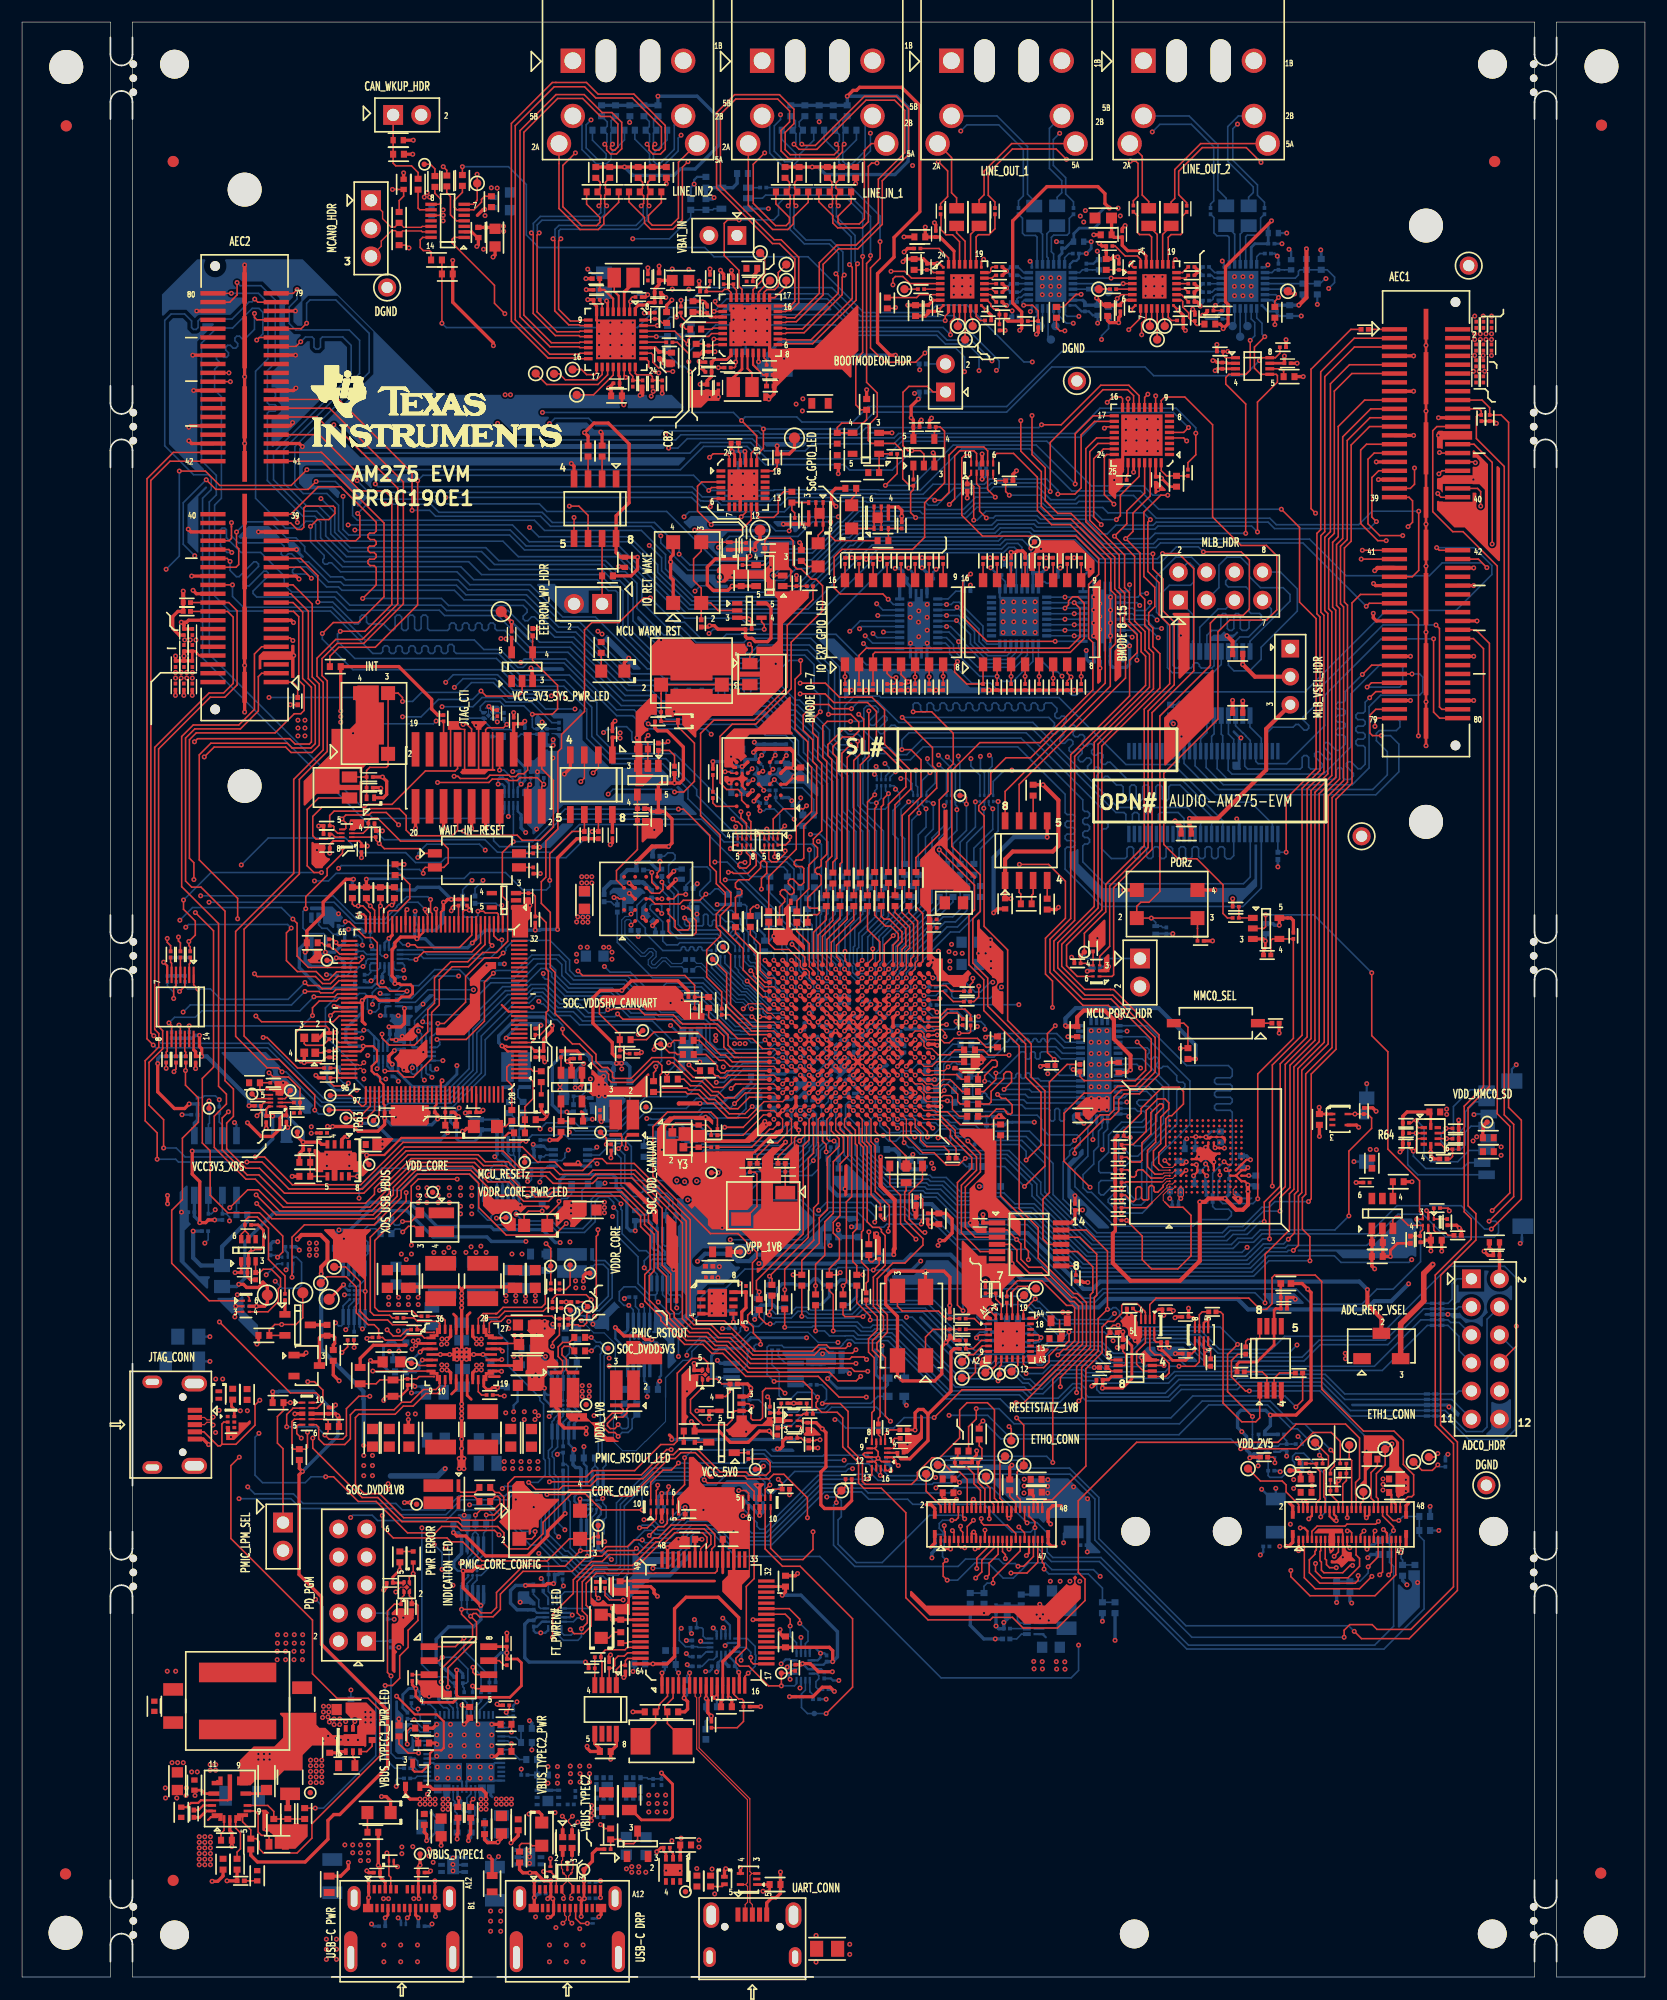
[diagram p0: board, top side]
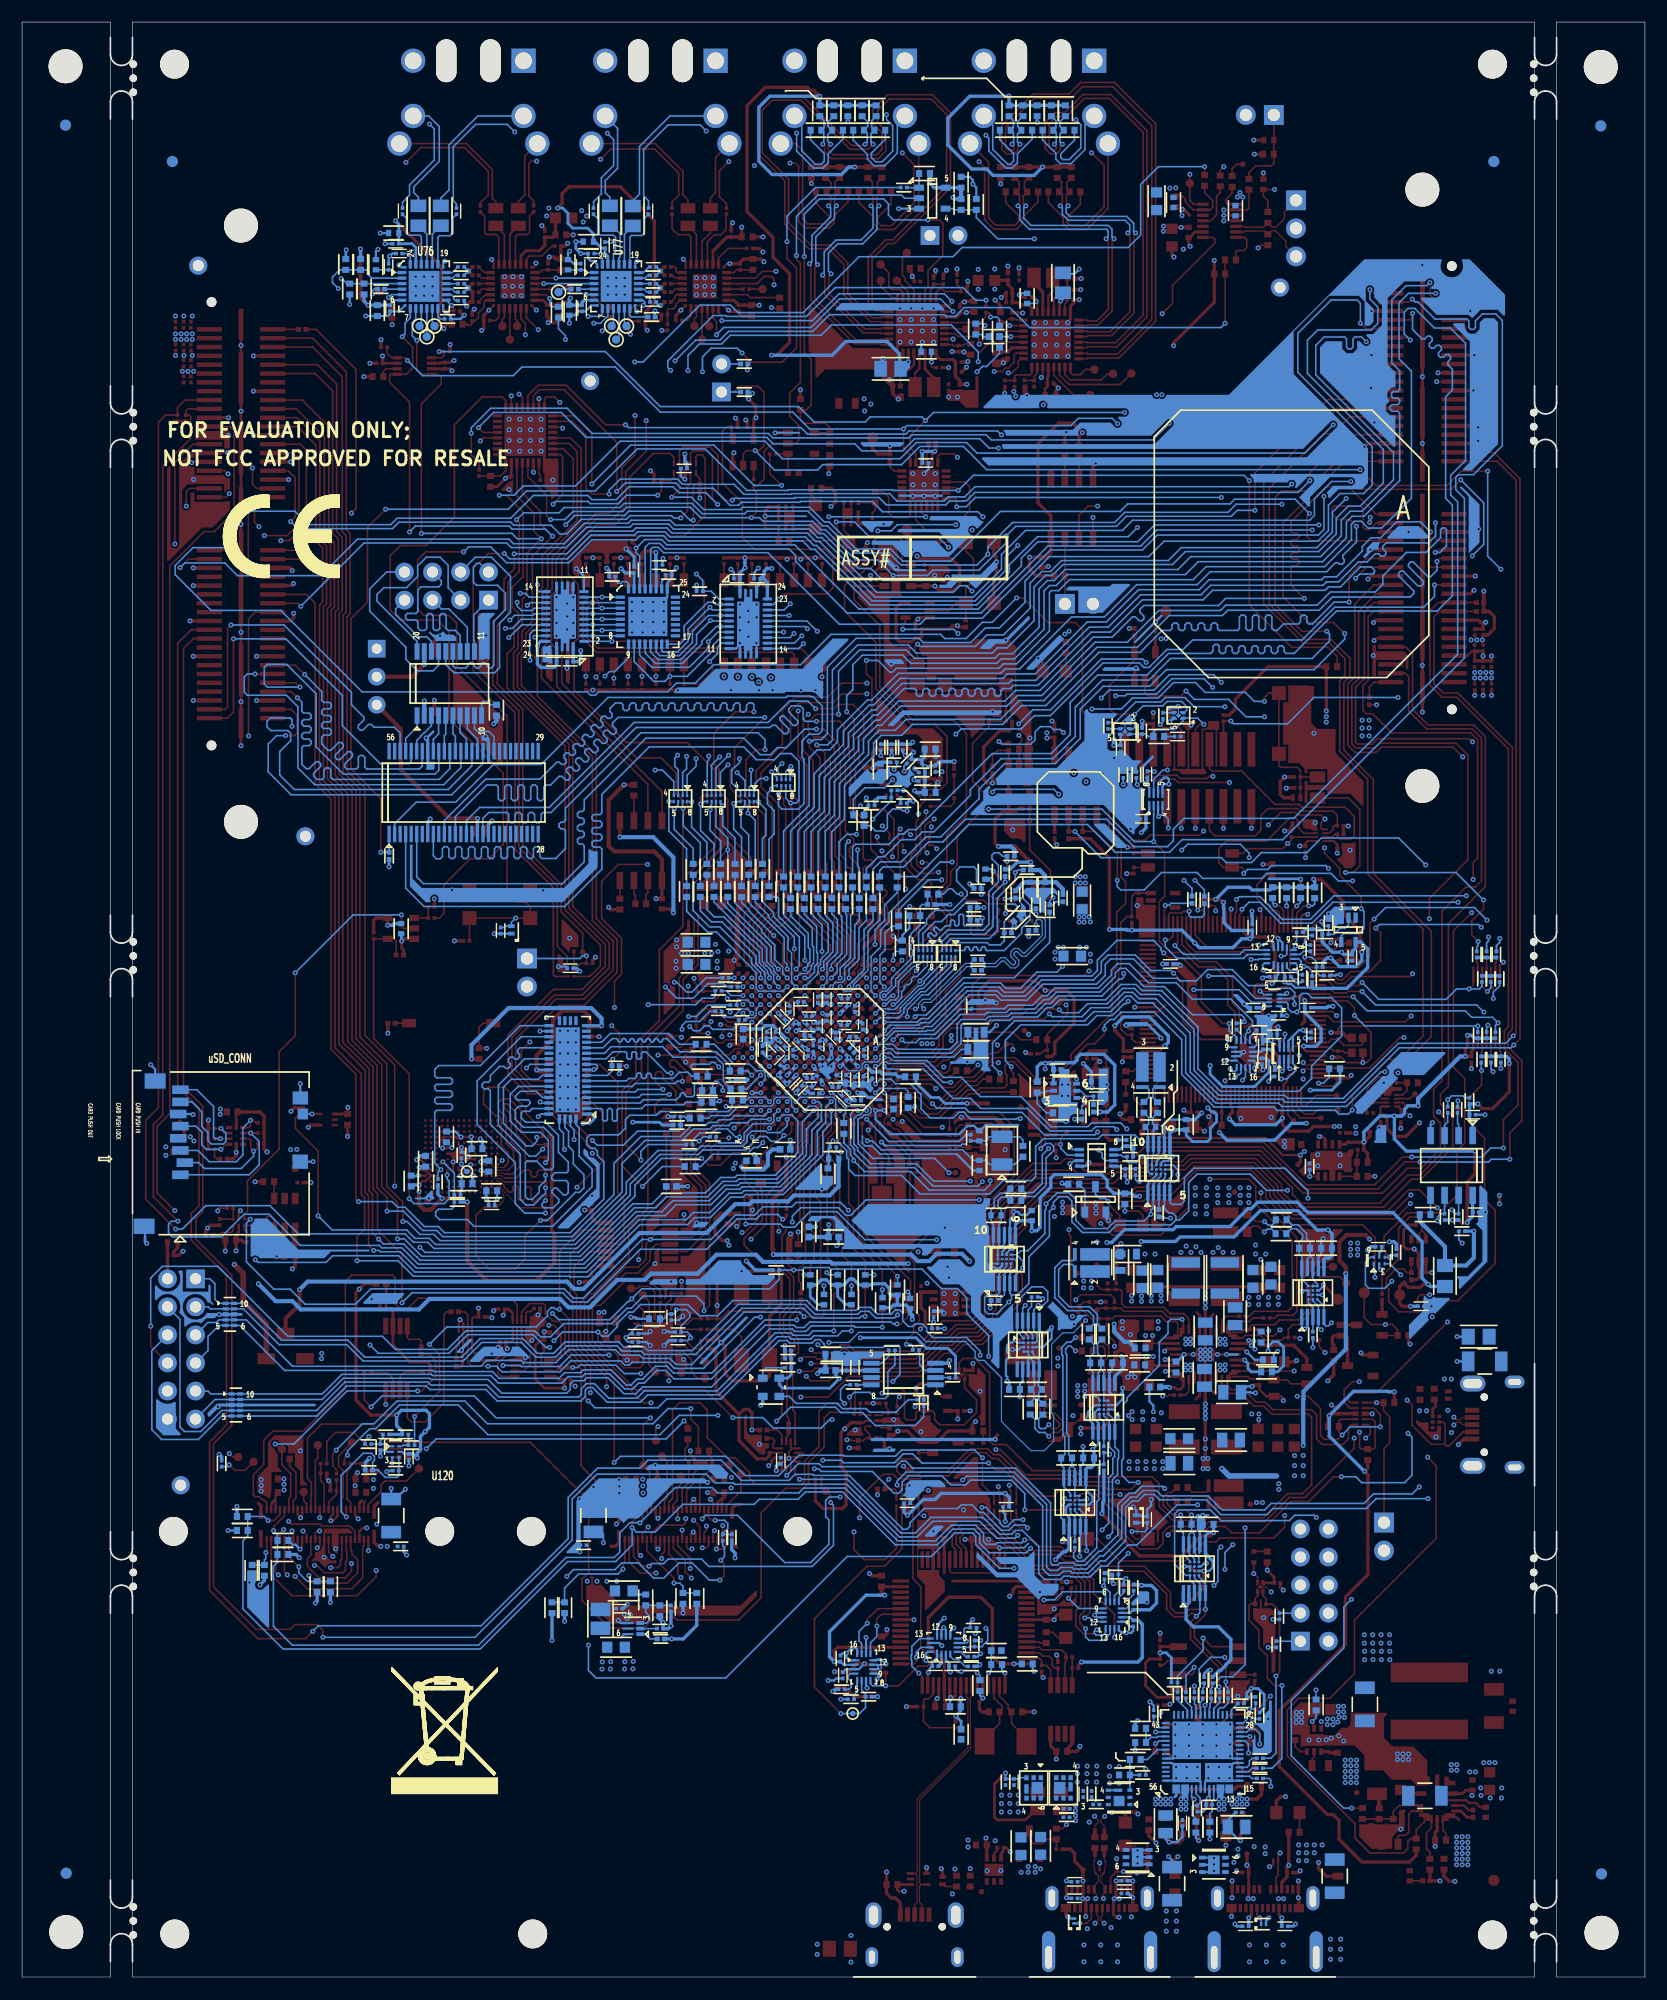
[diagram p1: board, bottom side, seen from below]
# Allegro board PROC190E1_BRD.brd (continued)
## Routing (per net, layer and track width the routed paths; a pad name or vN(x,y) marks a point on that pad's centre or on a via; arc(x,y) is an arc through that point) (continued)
SEL_XDS110_INV_3V3: length 17.9
  TOP w0.147: v1(46.22,114.33) 48.02,114.33 48.51,114.81 48.51,116.95 46.24,119.21 U2355.4 46.24,120.9 46.25,120.9 R5735.1
  BOTTOM w0.147: U87.2 41.74,114.46 41.51,114.7 41.51,115.02 41.98,115.49 43.28,115.49 43.68,115.09 45.46,115.09 v1(46.22,114.33) 46.22,113.87 46.22,113.87 46.22,113.16 46.37,113.01 U88.2
SOC_CLKIN: length 34.5
  TOP w0.147: v1(66.9,57.28) 66.9,57.63 66.24,58.29 66.24,58.85 65.73,59.36 65.73,59.92 66.16,60.35 66.16,64.67 66.57,65.07 66.57,65.61 64.86,67.31 62.35,67.31 57.14,72.52 57.14,76.99 58.46,78.31 62.4,78.31 62.98,77.72 62.98,77.14 R249.1
  BOTTOM w0.147: R349.2 66.31,57.12 66.47,57.28 v1(66.9,57.28)
SOC_DVDD1V8: length 92.8
  TOP w0.254: U56.24 43.31,56.86
  TOP w0.305: U136.J14 v1(73.7,88.05) ; U136.F12 v1(71.3,86.45) U136.E13 ; U136.F9 v1(71.3,84.06) ; U136.K14 v1(74.5,88.05) ; U136.K6 v1(75.3,80.86) ; v1(76.1,80.86) U136.M6 ; U136.J6 v1(73.7,80.86) ; v1(34.64,42.96) v1(35.19,42.96) ; 43.31,56.86 v1(43.5,56.67) ; U136.H14 v1(72.9,88.05) ; U136.F8 v1(71.3,83.26)
  L03_SIG1 w0.102: v1(50.67,59.44) 50.06,58.83 48.73,58.83 47.44,57.53 44.37,57.53 v1(43.5,56.67) ; v1(73.7,80.86) 74.1,80.46 74.1,69.76 74.52,69.34 74.52,65.61 73.37,64.47 73.37,61.21 73.91,60.68 v1(73.91,57.45)
  L03_SIG1 w0.254: 71.3,83.8 71.66,83.44 ; 71.3,83.8 70.93,83.44 ; 71.3,83.8 v1(71.3,83.26) ; 71.3,83.8 v1(71.3,84.06) ; v1(71.3,84.06) 70.84,83.6 ; v1(71.3,84.06) 71.75,83.6 ; 73.7,88.08 v1(73.7,88.05)
  L03_SIG1 w0.305: v1(73.7,80.86) 73.7,81.51
  L03_SIG1 w0.381: v1(74.5,88.05) v1(73.7,88.05) v1(72.9,88.05) v1(71.3,86.45) 70.75,87
  BOTTOM w0.102: v1(50.67,59.44) 51.78,58.32 52.72,58.32 53.74,57.3 53.74,51 53.56,50.83 53.56,48.49 54.4,47.65 55.61,47.65 56.45,48.49 56.48,48.49 58.29,50.29 58.29,52.5
  BOTTOM w0.127: 58.29,52.5 58.29,54.25 59.86,55.83 60.39,55.83 60.67,56.11 60.67,56.64 61.56,57.53 65.12,57.53 65.96,58.37 71.2,58.37 72.11,57.45 v1(73.91,57.45)
  BOTTOM w0.254: C461.1 74.79,88.05
  BOTTOM w0.305: v1(71.3,86.45) 70.98,86.45 C440.1 ; v1(76.1,80.86) 76.26,80.7 C429.1 ; v1(71.3,84.06) 71.64,83.71 C502.1 ; v1(73.7,80.86) 73.59,80.75 C437.1 ; 74.79,88.05 v1(74.5,88.05) 74.34,88.21 C453.1 73.94,88.05 v1(73.7,88.05) ; v1(75.3,80.86) 75.45,80.7 C506.1
  vias: v1(62.83,85.24) v1(62.83,84.79)
SOC_DVDD1V8_N: length 11.9
  TOP w0.147: v1(41.07,41.82) 41.53,42.29 42.71,42.29 43.28,42.86 43.28,43.3 43.07,43.51 42.86,43.51 R335.1
  BOTTOM w0.147: v1(41.07,41.82) C603.2 41.07,40.35 41.04,40.32 ; U123.D2 40.81,37.84 41.31,38.34 U124.9 41.31,40.06 41.04,40.32 ; U123.D1 40.41,37.98 40.81,38.38 U124.8 40.81,40.09 41.04,40.32
SOC_DVDD1V8_P: length 8.9
  TOP w0.147: v1(42.05,41.83) 42.75,41.83 43.63,42.71 43.63,43.45 43.22,43.86 42.86,43.86 R331.1
  BOTTOM w0.147: v1(42.05,41.83) C603.1 42.05,40.44 41.81,40.2 U124.10 41.81,38.25 41.21,37.65 U123.D3
SOC_DVDD3V3: length 58.7
  TOP w0.254: U56.22 43.41,55.86 v1(43.45,55.91)
  TOP w0.305: U136.H5 v1(72.9,80.06) ; U136.P12 v1(78.5,85.65) U136.P11 v1(77.7,84.85)
  L04_PWR1 w0.102: v1(43.45,55.91) 45.53,53.82 48.13,53.82 49.37,55.07 50.79,55.07 52.54,56.82 54.96,56.82 58.23,60.1 58.23,60.96 59.45,62.18 60.32,62.18 63.01,64.87 64,64.87 64.74,64.14 66.92,64.14 67.47,64.68 67.47,74.79 67.68,75.01 67.68,78.31 68.57,79.2 69.82,79.2 70.27,79.65 72.45,79.65
  L04_PWR1 w0.127: 72.45,79.65 72.47,79.63 v1(72.9,80.06)
  BOTTOM w0.203: v1(72.9,80.06) 72.72,79.87 C451.1
  BOTTOM w0.305: FL19.1 80.01,85.83 79.71,86.14 78.98,86.14 v1(78.5,85.65) ; v1(78.5,85.65) 78.68,85.65 C471.1 ; v1(78.5,85.65) v1(77.7,84.85)
  vias: v1(53.18,56.03) v1(53.18,55.32)
SOC_DVDD3V3_FB1: length 1.4
  TOP w0.305: U136.R9 v1(79.3,83.26)
  BOTTOM w0.305: v1(79.3,83.26) 79.47,83.26 C3645.1
SOC_DVDD3V3_N: length 6.9
  BOTTOM w0.147: U92.D1 U92.D2 55.84,56.61 55.84,56.3 55.66,56.12 ; R539.1 55.68,52.01 55.34,52.35 55.34,52.94 C428.2 55.29,53.52 55.29,53.97 55.36,54.05 U91.9 55.36,55.7 55.66,56 55.66,56.12 ; 55.66,56.12 55.86,55.92 U91.8
SOC_DVDD3V3_P: length 5.4
  BOTTOM w0.147: U92.D3 55.46,56.46 54.86,55.86 U91.10 54.86,54.05 54.94,53.97 54.94,53.52 C428.1 54.91,52.92 54.91,52.27 R540.1
SOC_EMU0: length 94.7
  TOP w0.147: SW3.1 36.41,101.73 35.98,102.16 32.82,102.16 v1(32.35,102.63) 32.03,102.95 R225.2 U39.2 ; U136.C9 v1(68.9,84.06)
  L03_SIG1 w0.091: v1(31.54,87.37) 30.88,87.37 29.2,89.05 29.2,94.2 27.55,95.85 27.55,99.97 28.49,100.91 31.54,100.91 32.35,101.73 v1(32.35,102.63)
  BOTTOM w0.132: v1(68.9,84.06) 68.25,84.06 67.84,83.64
  BOTTOM w0.147: U102.2 32.47,88.25 32.33,88.1 32.33,87.69 32.01,87.37 v1(31.54,87.37) 31.29,87.62 31.29,88.82 31.06,89.05 30.55,89.05 30.17,88.67 28.41,88.67 27.48,87.74 27.48,85.19 30.19,82.47 30.19,81.35 31.35,80.19 38.45,80.19 40.49,82.23 40.49,86.01 43.78,89.31 45.53,89.31 46.09,89.87 47.46,89.87 48.86,88.47 53,88.47 53.69,87.78 54.15,87.78 55.01,86.92 57.24,86.92 57.55,86.61 59.3,86.61 59.58,86.33 61.75,86.33 61.94,86.14 61.94,84.52 62.82,83.64 67.84,83.64
SOC_EMU1: length 83.7
  TOP w0.147: U39.3 30.89,103.56 31.36,104.03 R220.2 31.36,104.65 31.64,104.93 32.2,104.93 34.28,102.84 37.91,102.84 38.6,102.16 38.6,100.86 38.2,100.46 SW3.2 36.53,100.46 36.34,100.28 v1(36.34,99.92) ; U136.C10 v1(68.9,84.85)
  L03_SIG1 w0.091: v1(31.74,88.06) 31.74,88.44 29.48,90.7 29.48,94.31 27.88,95.91 27.88,99.59 v1(28.67,100.38)
  BOTTOM w0.147: 31.92,88.6 31.73,88.79 31.73,89.13 32.12,89.52 33.28,89.52 33.44,89.36 33.98,89.36 34.38,89.76 35.93,89.76 37.38,91.21 39.62,91.21 40.63,90.2 42.13,90.2 42.36,90.42 44.57,90.42 46.32,92.18 48.38,92.18 48.89,91.67 48.89,90.68 49.67,89.89 54.53,89.89 55.97,88.44 58.34,88.44 58.82,88.93 61.23,88.93 64.46,85.7 65.04,85.7 65.12,85.62 67.94,85.62 68.71,84.85 v1(68.9,84.85) ; 31.92,88.6 U102.3 ; 31.92,88.6 31.74,88.41 v1(31.74,88.06) ; v1(28.67,100.38) 28.92,100.63 33.8,100.63 34.16,100.28 35.98,100.28 v1(36.34,99.92)
SOC_GPIO1_49: length 63.3
  TOP w0.147: v1(73.25,131.75) 73.25,131.4 73.14,131.3 73.14,130.56 73.65,130.05 R213.1 ; U136.K17 v1(74.5,90.45)
  L03_SIG1 w0.091: v1(63.09,129.44) 63.09,127.53 63.64,126.97 63.64,119.86 72.59,110.92 72.59,105.66 70.48,103.56 70.48,101.9 74.92,97.46 74.92,90.88 v1(74.5,90.45)
  BOTTOM w0.147: v1(73.25,131.75) 71.59,131.75 70.27,130.43 64.08,130.43 v1(63.09,129.44)
SOC_HYPERBUS0_DQ0: length 8.5
  TOP w0.147: U136.A13 67.39,86.85 67.3,86.94 v1(66.82,86.94)
  BOTTOM w0.132: 64.97,88.93 65.47,88.93 66.82,87.58 v1(66.82,86.94)
  BOTTOM w0.147: RA8.8 62.46,91.38 64.91,88.93 64.97,88.93
SOC_HYPERBUS0_DQ1: length 10.6
  TOP w0.147: U136.D12 v1(69.7,86.45)
  BOTTOM w0.132: 67.95,86.85 69.3,86.85 v1(69.7,86.45) ; 67.07,87.73 65.6,89.2 65.17,89.2 64.81,89.56
  BOTTOM w0.147: 67.95,86.85 67.6,86.85 67.12,87.33 67.12,87.68 67.07,87.73 ; 64.81,89.56 62.86,91.52 RA8.7
SOC_HYPERBUS0_DQ2: length 9.2
  TOP w0.147: U136.D13 v1(69.7,87.25)
  BOTTOM w0.132: 64.89,90.56 65.28,90.17 65.28,90.01 65.54,89.74 65.82,89.74 67.96,87.6 68.42,87.6 68.47,87.65 69.3,87.65 v1(69.7,87.25)
  BOTTOM w0.147: 64.89,90.56 63.66,91.8 RA8.5
SOC_HYPERBUS0_DQ3: length 9
  TOP w0.147: U136.C13 v1(68.9,87.25)
  BOTTOM w0.132: 64.88,90.02 65.41,89.48 65.7,89.48 67.43,87.76 67.43,87.45 67.63,87.25 v1(68.9,87.25)
  BOTTOM w0.147: 64.88,90.02 63.26,91.64 RA8.6
SOC_HYPERBUS0_DQ4: length 5.4
  TOP w0.147: U136.A15 67.41,88.74 67.11,88.74 v1(65.68,90.17)
  BOTTOM w0.132: 64.89,91.16 64.89,90.98 65.68,90.2 v1(65.68,90.17)
  BOTTOM w0.147: RA9.8 64.59,91.46 64.89,91.16
SOC_HYPERBUS0_DQ5: length 5.7
  TOP w0.147: U136.C15 v1(68.9,88.85)
  BOTTOM w0.132: RA9.5 65.79,92.07 66.01,91.85 66.36,91.85 67.89,90.32 67.89,89.74 68.77,88.85 v1(68.9,88.85)
SOC_HYPERBUS0_DQ6: length 6.6
  TOP w0.147: U136.B14 v1(68.1,88.05)
  BOTTOM w0.132: RA9.7 64.99,91.54 65.94,90.59 66.19,90.59 66.44,90.35 66.44,90.09 66.67,89.87 66.87,89.87 67.11,89.63 67.11,89.43 67.33,89.2 67.33,88.65 67.92,88.05 v1(68.1,88.05)
SOC_HYPERBUS0_DQ7: length 6.9
  TOP w0.147: U136.C14 v1(68.9,88.05)
  BOTTOM w0.132: 65.39,92.39 65.39,92.01 65.88,91.52 66.24,91.52 67.61,90.14 67.61,88.78 67.93,88.46 68.3,88.46 68.71,88.05 v1(68.9,88.05)
SOC_I2C0_SCL: length 479.6
  TOP w0.147: U25.2 52.2,109.49 v1(51.73,109.02) ; J18.40 90.81,41.34 v1(91.04,41.11) ; U2357.8 89.04,107.34 98.57,116.87 98.57,120.24 99.05,120.72 99.05,125.12 98.62,125.55 98.62,128.4 94.99,132.03 93.46,132.03 92.32,133.17 92.32,136.3 90.47,138.15 v1(90.47,140.92) ; v1(124.22,40.41) 124.22,40.76 123.24,41.75 J19.40 ; v1(112.08,146.35) 112.34,146.61 U11.8 113.52,146.61 113.93,147.02 R56.2 ; U18.19 66.55,137.8 67.15,138.4 v1(67.15,140.16) ; v1(56.18,39.57) 55.44,39.57 54.83,38.96 52.89,38.96 52.52,38.6 v1(50.58,38.6) 49.17,37.19 45.34,37.19 42.97,34.82 42.97,33.46 42.49,32.97 41.58,32.97 41.26,33.28 v1(39.81,33.28) 39.81,32.85 40.81,31.84 40.81,30.74 37.97,27.9 v1(37.97,26.72)
  L03_SIG1 w0.091: v1(50.58,38.6) 49.87,38.6 v1(48.61,39.85) 48.61,40.56 50.54,42.49 51.76,42.49 v1(52.6,43.33) 52.6,45.64 54.96,48.01 v1(54.96,60.81) 56.35,62.2 v1(56.35,64.21) ; v1(112.08,146.35) 107.23,141.5 92.7,141.5 92.12,140.92 v1(90.47,140.92) ; v1(42.31,72.64) 43.7,71.25 43.7,70.11 v1(44.75,69.06) ; v1(54.25,70) 54.25,70.46 53.43,71.27 53.43,73.3 52.16,74.57 51.96,74.57 51.64,74.9 51.64,75.6 53.23,77.19 53.23,81.64 52.25,82.62 52.25,84.49 54.64,86.88 54.64,87.51 51.96,90.2 51.96,95.94 49.43,98.47 49.43,106.13 51.73,108.43 v1(51.73,109.02) 51.73,114.96 48.38,118.31 48.38,133.15 47.77,133.76 v1(47.77,140.64) ; v1(30.52,70.51) 29.84,69.82 29.84,60.68 v1(28.39,59.23)
  BOTTOM w0.147: U123.A1 40.41,36.26 39.81,35.66 U124.5 v1(39.81,33.28) ; U92.B3 55.32,57.43 55.31,57.43 55.21,57.43 55.19,57.45 55.18,57.45 55.06,57.57 55.06,58.22 55.24,58.39 55.24,58.4 55.36,58.53 U91.2 55.36,60.4 v1(54.96,60.81) 54.52,60.81 54.1,61.23 54.1,62.05 54.53,62.48 55.54,62.48 56.86,61.17 U91.5 56.86,58.43 U92.A1 ; U118.1 52.64,41.34 52.91,41.62 52.91,42.58 52.6,42.9 v1(52.6,43.33) 52.43,43.17 U119.C3 ; v1(30.52,70.51) 30.52,71.17 32.58,73.23 40.84,73.23 41.72,72.34 41.72,70.26 42.03,69.95 42.86,69.95 43.02,70.11 U3079.5 43.02,71.88 42.93,71.97 42.63,71.97 42.31,72.29 v1(42.31,72.64) 42.31,73.08 42.75,73.52 U3081.A1 ; U3078.5 57.02,63.55 v1(56.35,64.21) 56.35,64.85 56.9,65.39 ; 56.9,65.39 U3080.A1 ; 56.9,65.39 56.53,65.76 55.9,65.76 54.35,67.31 54.35,69.4 54.25,69.51 v1(54.25,70) 53.26,70.99 53.24,70.99 53.23,70.99 52.14,70.99 51.55,70.41 51.55,68.53 50.79,67.77 48.68,67.77 48,68.45 45.36,68.45 v1(44.75,69.06) 44.75,69.42 44.52,69.64 U3079.2 44.52,71.83 43.85,72.5 U3081.B3 ; v1(124.22,40.41) 123.87,40.05 R622.2 R625.1 123.87,37.54 124.24,37.17 124.24,31.76 122.52,30.05 105.66,30.05 97.72,37.98 93.36,37.98 92.86,38.49 92.86,40.21 91.93,41.14 91.06,41.14 v1(91.04,41.11) 87.84,44.31 84.49,44.31 84,43.83 76.64,43.83 76.2,44.26 72.45,44.26 67.68,39.49 64.24,39.49 62.82,40.91 60.63,40.91 59.91,40.18 59.91,39.44 59.64,39.17 58.82,39.17 58.67,39.32 56.43,39.32 v1(56.18,39.57) ; U113.A1 29.08,60.76 U114.5 29.08,59.1 28.93,58.95 28.67,58.95 v1(28.39,59.23) ; R657.1 37.76,26.16 37.97,26.37 v1(37.97,26.72) ; v1(112.08,146.35) 110.71,144.99 102.5,144.99 101.72,145.77 93.27,145.77 89.18,141.69 77.19,141.69 75.66,140.16 v1(67.15,140.16) 66.85,140.46 51.99,140.46 51.33,141.12 48.25,141.12 v1(47.77,140.64) ; v1(48.61,39.85) 48.23,40.23 48.23,45.02 47.77,45.47 47.77,46.89 47.68,46.99 47.68,47.65 48.01,47.99 U116.5 48.01,50.28 48.2,50.47 48.2,50.57 U115.A1 ; U119.A1 50.64,41.77 U118.5 50.64,39.11 50.58,39.05 v1(50.58,38.6)
SOC_I2C0_SDA: length 475.4
  TOP w0.147: v1(109.21,147.17) 109.19,147.17 109.18,147.17 R58.2 108.79,146.83 109.01,146.61 U11.1 ; v1(38.58,26.25) 38.58,27.99 41.17,30.58 41.17,32.13 v1(40.63,32.66) 40.88,32.91 41.14,32.91 41.44,32.61 42.66,32.61 43.32,33.27 43.32,34.67 45.38,36.73 49.83,36.73 v1(51.2,38.1) 52.52,38.1 53.03,38.61 55.44,38.61 v1(55.64,38.81) ; v1(91.48,141.38) 91.48,137.85 92.68,136.65 92.68,133.65 93.82,132.51 95.01,132.51 98.98,128.55 98.98,125.69 99.48,125.18 99.48,120.7 99.95,120.23 99.95,117.61 90.31,107.98 U2357.7 ; U25.3 50.93,108.55 v1(50.61,108.23) ; v1(65.17,140.92) 66.54,139.55 66.54,138.46 66.05,137.96 U18.20 ; J19.42 123.64,41.88 124.18,41.33 v1(124.71,41.33) ; v1(91.74,40.68) 91.74,41.2 91.21,41.74 J18.42
  L03_SIG1 w0.091: v1(56.13,60.81) 56.13,61.37 56.4,61.64 57.42,61.64 57.62,61.44 v1(57.62,61.11) 57.62,60.25 55.67,58.29 55.67,48.18 53.84,46.35 53.84,42.6 52.85,41.61 50.28,41.61 v1(49.17,40.49) 49.17,39.83 49.85,39.14 50.74,39.14 51.2,38.68 v1(51.2,38.1) ; v1(91.48,141.38) 92.17,142.06 105.29,142.06 109.21,145.98 v1(109.21,147.17) ; v1(53.59,69.67) 53.59,70.7 53.49,70.79 52.93,70.79 52.19,71.53 52.19,72.82 52.62,73.25 52.62,73.71 52.19,74.14 51.99,74.14 51.35,74.78 51.35,75.72 51.36,75.73 51.36,75.73 52.9,77.27 52.9,77.81 51.81,78.89 51.81,80.98 52.19,81.36 52.19,81.61 51.94,81.86 51.94,84.58 54.37,87.02 54.37,87.38 51.68,90.07 51.68,93.4 49.15,95.93 49.15,106.77 v1(50.61,108.23) 50.84,108.46 50.84,115.24 47.9,118.19 47.9,132.79 47.13,133.55 v1(47.13,141.66) ; v1(29.32,58.61) 32.15,61.43 32.15,70.99 v1(32.38,71.22)
  BOTTOM w0.147: v1(124.71,41.33) 125.07,41.7 R616.1 R618.2 126.56,39.93 126.99,39.5 126.99,33.32 123.36,29.69 105.5,29.69 97.58,37.62 93.23,37.62 91.74,39.1 v1(91.74,40.68) 91.35,40.29 89.65,40.29 87.14,42.79 80.68,42.79 80.22,43.26 76.7,43.26 76.04,43.91 72.68,43.91 67.91,39.14 64.09,39.14 62.67,40.56 60.78,40.56 60.26,40.04 60.26,39.29 59.38,38.41 56.05,38.41 v1(55.64,38.81) ; v1(51.2,38.1) 51.2,38.45 51.14,38.52 U118.4 51.14,41.68 51.63,42.18 51.63,42.35 51.64,42.36 U119.A2 ; R656.1 38.52,26.2 v1(38.58,26.25) ; v1(32.38,71.22) 34.26,71.22 35.73,72.69 40.58,72.69 41.32,71.96 41.32,69.37 42.16,68.53 42.49,68.53 ; v1(109.21,147.17) 94.17,147.17 89.19,142.19 76.65,142.19 75.25,140.79 70.63,140.79 70.17,141.25 65.5,141.25 v1(65.17,140.92) 64.43,141.66 v1(47.13,141.66) ; v1(56.13,60.81) 56.36,60.57 U91.4 56.36,58.52 55.86,58.02 U92.A2 ; U3080.B3 57.82,64.32 58.52,63.62 U3078.2 58.52,61.89 58.66,61.75 59.58,61.75 59.73,61.59 59.73,61.54 59.81,61.47 59.81,60.35 59.5,60.05 58.69,60.05 v1(57.62,61.11) 57.38,61.36 57.38,61.75 ; 57.38,61.75 56.83,61.75 55.8,62.79 55.8,65.21 53.94,67.07 53.94,69.32 v1(53.59,69.67) 53.59,70.13 53.08,70.63 52.29,70.63 51.91,70.26 51.91,68.38 50.94,67.41 48.53,67.41 47.85,68.1 42.92,68.1 42.49,68.53 ; 57.38,61.75 57.52,61.89 U3078.4 57.52,63.63 56.94,64.21 56.94,64.83 57.1,64.99 U3080.A2 ; v1(49.17,40.49) 48.58,41.08 48.58,45.16 48.2,45.54 48.2,46.96 48.03,47.13 48.03,47.51 48.51,47.99 U116.4 48.51,50.29 49.01,50.79 U115.A2 ; U113.A2 30.08,61.22 29.58,60.72 U114.4 29.58,58.86 v1(29.32,58.61) ; U123.A2 40.81,36.11 40.31,35.61 U124.4 40.31,33.76 40.31,33.76 40.31,32.99 v1(40.63,32.66) ; 42.49,68.53 42.49,68.87 42.78,69.16 43.12,69.16 43.52,69.57 U3079.4 43.52,71.84 42.79,72.57 42.79,72.97 42.94,73.12 U3081.A2
SOC_MMC0_CLK: length 4.1
  TOP w0.132: v1(83.81,79.32) 83.1,79.32 83.04,79.26 81.93,79.26 81.69,79.5 81.69,79.93 81.3,80.33 U136.V5
  BOTTOM w0.147: v1(83.81,79.32) 83.94,79.2 R558.2
SOC_MMC0_CMD: length 10.6
  BOTTOM w0.147: U57.14 94.51,84.63 93.72,85.42 88.44,85.42 87.47,84.45 R5819.1
SOC_MMC0_CMD_R: length 8.1
  TOP w0.147: U136.T6 v1(80.1,80.86)
  BOTTOM w0.132: v1(80.1,80.86) 79.7,81.25 79.7,81.92 79.83,82.05 80.49,82.05 81.09,82.65 82.49,82.65 82.9,83.06
  BOTTOM w0.147: 82.9,83.06 84.29,84.45 R5819.2
SOC_MMC0_DAT0: length 13.7
  TOP w0.147: v1(88.36,79.91) 88.71,79.55 89.1,79.55 89.68,78.97 89.68,78.25 89.53,78.11 89.29,78.11 89.15,78.25 89.15,78.36 88.92,78.59 88.26,78.59 87.6,77.93 R5811.1
  BOTTOM w0.147: v1(88.36,79.91) 90.87,79.91 91.15,79.63 U57.4
SOC_MMC0_DAT0_R: length 5
  TOP w0.132: U136.W4 83.3,79.66 83.46,79.81 84.11,79.81 84.27,79.65 84.27,78.56 84.9,77.93
  TOP w0.147: 84.9,77.93 R5811.2
SOC_MMC0_DAT1: length 13.9
  TOP w0.147: R5812.1 87.6,79.04 87.77,79.22 87.77,80.19 88.92,81.33 88.92,81.74 89.15,81.97 89.48,81.97 89.63,81.82 89.63,81.05 v1(88.95,80.36)
  BOTTOM w0.147: U57.5 91.46,80.13 91.23,80.36 v1(88.95,80.36)
SOC_MMC0_DAT1_R: length 4.8
  TOP w0.132: U136.W5 83.06,80.46 83.41,80.8 83.89,80.8 84.75,79.93 84.75,79.27 84.9,79.12
  TOP w0.147: R5812.2 84.98,79.04 84.9,79.12
SOC_MMC0_DAT2: length 13.4
  TOP w0.147: v1(88.21,81.84) 88.21,81.25 87.11,80.16 R5813.1
  BOTTOM w0.147: U57.11 94.1,83.13 93.46,83.77 92.35,83.77 92.22,83.64 92.22,83.24 92.09,83.11 91.91,83.11 91.78,83.24 91.78,83.64 91.65,83.77 91.47,83.77 91.34,83.64 91.34,83.24 91.21,83.11 91.03,83.11 90.9,83.24 90.9,83.64 90.77,83.77 90.49,83.77 88.56,81.84 v1(88.21,81.84)
SOC_MMC0_DAT2_R: length 5.2
  TOP w0.132: 84.9,80.42 84.07,81.25 83.38,81.25 82.85,80.72 82.54,80.72 82.41,80.85 81.93,80.85 81.53,81.26 U136.V6
  TOP w0.147: R5813.2 85.16,80.16 84.9,80.42
SOC_MMC0_DAT3: length 12.7
  BOTTOM w0.147: U57.3 91.01,79.13 90.72,79.43 87.73,79.43 87.38,79.78 87.38,79.91 87.25,80.04 87.06,80.04 86.93,79.91 86.93,79.83 86.8,79.71 86.25,79.71 86.1,79.86 86.1,80.77 85.97,80.9 85.55,80.9 85.4,80.76 R5814.1
SOC_MMC0_DAT3_R: length 6
  TOP w0.132: U136.U6 80.89,80.86 81.54,80.86 81.7,80.7 81.7,80.29 81.93,80.06 83.3,80.06 83.51,80.26 v1(83.53,80.26)
  BOTTOM w0.147: v1(83.53,80.26) 83.53,80.62 84,81.09 84.24,81.09 84.42,80.9 R5814.2
SOC_MMC0_DAT4: length 16.9
  BOTTOM w0.147: R5815.1 82.89,82.53 84.12,83.77 87.42,83.77 88.61,84.96 88.89,84.96 89,84.86 89,84.78 89.1,84.67 89.26,84.67 89.36,84.78 89.36,84.86 89.47,84.96 89.62,84.96 89.73,84.86 89.73,84.78 89.84,84.67 89.99,84.67 90.1,84.78 90.1,84.86 90.21,84.96 90.36,84.96 90.47,84.86 90.47,84.78 90.58,84.67 90.73,84.67 90.84,84.78 90.84,84.86 90.94,84.96 91.1,84.96 91.2,84.86 91.2,84.78 91.31,84.67 91.47,84.67 91.57,84.78 91.57,84.86 91.68,84.96 91.83,84.96 91.94,84.86 91.94,84.78 92.05,84.67 92.2,84.67 92.31,84.78 92.31,84.86 92.42,84.96 92.57,84.96 92.68,84.86 92.68,84.78 92.79,84.67 92.94,84.67 93.05,84.78 93.05,84.86 93.15,84.96 93.54,84.96 94.37,84.13 U57.13
SOC_MMC0_DAT4_R: length 1.7
  TOP w0.132: U136.U7 v1(80.9,81.66)
  BOTTOM w0.147: v1(80.9,81.66) 81.28,82.04 R5815.2
SOC_MMC0_DAT5: length 15.8
  BOTTOM w0.132: 84.9,83.29 84.14,83.29 83.48,82.63 83.48,81.1 82.81,80.43 R5816.1
  BOTTOM w0.147: U57.12 94.24,83.63 93.64,84.23 88.97,84.23 88.03,83.29 84.9,83.29
SOC_MMC0_DAT5_R: length 2.8
  TOP w0.147: U136.T7 v1(80.1,81.66)
  BOTTOM w0.132: 80.99,80.77 v1(80.1,81.66)
  BOTTOM w0.147: 80.99,80.77 81.36,80.39 R5816.2
SOC_MMC0_DAT6: length 14.1
  TOP w0.147: R5817.1 86.6,81.77 87.83,83.01 88.19,83.01 88.33,82.86 88.33,82.52 88.19,82.37 87.95,82.37 87.19,81.61 v1(87.19,81.1)
  BOTTOM w0.147: U57.6 91.72,80.63 91.46,80.9 87.85,80.9 87.65,81.1 v1(87.19,81.1)
SOC_MMC0_DAT6_R: length 4.7
  TOP w0.132: 81.69,81.66 81.7,81.65 82.41,81.65 82.46,81.7 82.86,81.7
  TOP w0.147: 82.86,81.7 84.66,81.7 85.08,81.28 R5817.2 ; 81.69,81.66 U136.V7
SOC_MMC0_DAT7: length 11.7
  BOTTOM w0.147: U57.7 92.27,81.13 92.04,81.36 91.46,81.36 91.33,81.49 91.33,81.71 91.2,81.84 91.02,81.84 90.89,81.71 90.89,81.49 90.76,81.36 90.58,81.36 90.45,81.49 90.45,81.68 90.32,81.81 90.14,81.81 90.01,81.68 90.01,81.49 89.88,81.36 88.03,81.36 87.47,81.92 86.7,81.92 86.34,81.56 R5818.1
SOC_MMC0_DAT7_R: length 7
  TOP w0.132: U136.W7 83.55,82.06 v1(83.89,82.4)
  BOTTOM w0.132: v1(83.89,82.4) 84.29,82.8 84.56,82.8 84.72,82.64 84.9,82.64
  BOTTOM w0.147: R5818.2 84.91,82.05 85.05,82.2 86.26,82.2 86.4,82.35 86.4,82.49 86.26,82.64 84.9,82.64
SOC_OSPI_CLK: length 6.4
  TOP w0.132: U136.B17 68.1,90.45 67.54,90.45 66.85,91.14 66.85,92.25
  TOP w0.147: R197.2 65.96,94.37 66.85,93.49 66.85,92.25
SOC_OSPI_DQ0: length 26.8
  TOP w0.132: v1(66,91.11) 66.26,90.85 66.26,90.68 67.29,89.65 68.1,89.65 U136.B16
  TOP w0.147: v1(63.98,100.03) 64.33,100.03 64.43,99.92 65.75,99.92 66.49,100.66 66.49,101.57 66.02,102.05 RA3.8
  L03_SIG1 w0.091: v1(63.98,100.03) 64.36,99.65 64.36,98.83 63.44,97.92 63.44,96.77 63.24,96.57 63.24,95.97 63.35,95.86 63.69,95.86 63.8,95.75 63.8,95.6 63.69,95.5 63.12,95.5 63.01,95.39 63.01,95.24 63.12,95.13 63.69,95.13 63.8,95.02 63.8,94.87 63.69,94.76 63.12,94.76 63.01,94.66 63.01,94.51 63.12,94.4 63.69,94.4 63.8,94.29 63.8,94.14 63.69,94.03 63.12,94.03 63.01,93.93 63.01,93.77 63.12,93.67 63.69,93.67 63.8,93.56 63.8,93.41 63.69,93.3 63.12,93.3 63.01,93.19 63.01,93.04 63.12,92.94 63.69,92.94 63.8,92.83 63.8,92.68 63.69,92.57 63.12,92.57 63.01,92.46 63.01,91.72 63.62,91.11 v1(66,91.11)
SOC_OSPI_DQ1: length 25
  TOP w0.147: RA3.7 65.62,101.79 65.96,101.45 65.96,100.76 65.6,100.41 65,100.41 64.86,100.55 64.86,100.77 65,100.92 v1(65.48,100.92) ; U136.D17 v1(69.7,90.45)
  L03_SIG1 w0.091: v1(69.7,90.45) 69.3,90.86 67.68,90.86 66.16,92.37 66.16,93.12 66.06,93.23 65.38,93.23 65.27,93.33 65.27,93.49 65.38,93.59 66.06,93.59 66.16,93.7 66.16,94.05 66.06,94.16 65.05,94.16 64.94,94.27 64.94,94.42 65.05,94.53 66.06,94.53 66.16,94.63 66.16,94.79 66.06,94.89 65.05,94.89 64.94,95 64.94,95.15 65.05,95.26 66.06,95.26 66.16,95.37 66.16,97.52 66.06,97.63 65.93,97.63 65.82,97.74 65.82,97.89 65.93,98 66.06,98 66.16,98.1 66.16,98.26 66.06,98.36 65.93,98.36 65.82,98.47 65.82,98.62 65.93,98.73 66.06,98.73 66.16,98.84 66.16,98.99 66.06,99.09 65.93,99.09 65.82,99.2 65.82,99.35 65.93,99.46 66.06,99.46 66.16,99.57 66.16,100.23 v1(65.48,100.92)
SOC_OSPI_DQ2: length 20.8
  TOP w0.147: v1(65.02,101.78) 65.22,101.98 RA3.6 ; U136.C17 v1(68.9,90.45)
  L03_SIG1 w0.091: v1(68.9,90.45) 67.63,90.45 64.66,93.42 64.66,95.48 64.77,95.58 65.52,95.58 65.63,95.69 65.63,95.84 65.52,95.95 64.77,95.95 64.66,96.06 64.66,96.21 64.77,96.32 65.52,96.32 65.63,96.42 65.63,96.57 65.52,96.68 64.77,96.68 64.66,96.79 64.66,96.94 64.77,97.05 65.52,97.05 65.63,97.16 65.63,97.31 65.52,97.41 64.77,97.41 64.66,97.52 64.66,97.74 65.55,98.63 65.55,100.18 65.02,100.71 v1(65.02,101.78)
SOC_OSPI_DQ3: length 21.9
  TOP w0.147: v1(69.7,89.65) U136.D16 ; v1(64.15,102.16) 64.48,102.49 RA3.5
  L03_SIG1 w0.091: v1(69.7,89.65) 69.3,90.06 67.59,90.06 64.2,93.45 64.2,97.99 65.19,98.98 65.19,100 64.25,100.94 63.62,100.94 62.91,101.65 62.91,102.92 63.21,103.23 63.87,103.23 64.15,102.95 v1(64.15,102.16)
SOC_OSPI_DQ4: length 17.4
  TOP w0.147: RA4.8 69.16,102.49 69.54,102.87 v1(69.54,103.23) ; U136.E16 v1(70.5,89.65)
  L03_SIG1 w0.091: v1(69.54,103.23) 69.97,102.8 69.97,101.5 71.62,99.85 71.62,92.46 70.12,90.96 70.12,90.03 v1(70.5,89.65)
SOC_OSPI_DQ5: length 19.9
  TOP w0.147: U136.B18 v1(68.1,91.26) ; 68.04,102.49 68.04,102.13 68.17,102.01 v1(68.17,101.42)
  L03_SIG1 w0.091: v1(68.1,91.26) 68.47,91.63 68.47,93.49 68.58,93.6 68.83,93.6 68.96,93.73 68.96,93.88 68.87,93.97 68.58,93.97 68.47,94.07 68.47,94.23 68.58,94.33 68.9,94.33 69.01,94.44 69.01,94.59 68.9,94.7 68.58,94.7 68.47,94.81 68.47,94.96 68.58,95.06 68.9,95.06 69.01,95.17 69.01,95.32 68.9,95.43 68.58,95.43 68.47,95.54 68.47,95.69 68.58,95.8 68.9,95.8 69.01,95.9 69.01,96.06 68.9,96.16 68.58,96.16 68.47,96.27 68.47,96.42 68.58,96.53 68.9,96.53 69.01,96.64 69.01,96.79 68.9,96.89 68.58,96.89 68.47,97 68.47,97.15 68.58,97.26 68.9,97.26 69.01,97.37 69.01,97.52 68.9,97.63 68.58,97.63 68.47,97.73 68.47,97.88 68.58,97.99 68.9,97.99 69.01,98.1 69.01,98.25 68.9,98.36 68.58,98.36 68.47,98.46 68.47,98.62 68.58,98.72 68.9,98.72 69.01,98.83 69.01,98.98 68.9,99.09 68.58,99.09 68.47,99.2 68.47,99.35 68.58,99.45 68.9,99.45 69.01,99.56 69.01,99.71 68.9,99.82 68.58,99.82 68.47,99.93 68.47,100.08 68.58,100.19 68.73,100.19 68.83,100.28 68.83,100.46 68.73,100.55 68.58,100.55 68.47,100.66 68.47,101.12 v1(68.17,101.42)
SOC_OSPI_DQ6: length 25.6
  TOP w0.147: v1(69.12,101.96) 69.12,101.74 68.35,100.97 67.88,100.97 67.64,101.21 RA4.6 ; U136.D18 v1(69.7,91.26)
  L03_SIG1 w0.091: v1(69.12,101.96) 69.12,101.54 70.32,100.34 70.32,99.84 70.43,99.74 70.93,99.74 71.04,99.63 71.04,99.48 70.93,99.37 70.43,99.37 70.32,99.26 70.32,99.11 70.43,99.01 70.9,99.01 71.01,98.9 71.01,98.75 70.9,98.64 70.43,98.64 70.32,98.53 70.32,98.38 70.43,98.27 70.9,98.27 71.01,98.17 71.01,98.02 70.9,97.91 70.43,97.91 70.32,97.8 70.32,97.65 70.43,97.54 70.9,97.54 71.01,97.44 71.01,97.28 70.9,97.18 70.43,97.18 70.32,97.07 70.32,96.92 70.43,96.81 70.9,96.81 71.01,96.7 71.01,96.55 70.9,96.45 70.43,96.45 70.32,96.34 70.32,96.19 70.43,96.08 70.9,96.08 71.01,95.97 71.01,95.82 70.9,95.71 70.43,95.71 70.32,95.61 70.32,95.46 70.43,95.35 70.9,95.35 71.01,95.24 71.01,95.09 70.9,94.98 70.43,94.98 70.32,94.88 70.32,94.72 70.43,94.62 70.9,94.62 71.01,94.51 71.01,94.36 70.9,94.25 70.43,94.25 70.32,94.14 70.32,93.99 70.43,93.89 70.9,93.89 71.01,93.78 71.01,93.63 70.9,93.52 70.43,93.52 70.32,93.41 70.32,91.88 v1(69.7,91.26)
SOC_OSPI_DQ7: length 23.1
  TOP w0.147: RA4.5 67.24,102.04 v1(67.1,101.9) ; U136.C18 v1(68.9,91.26)
  L03_SIG1 w0.091: v1(68.9,91.26) 69.28,91.64 69.28,94.29 69.39,94.4 69.89,94.4 69.99,94.51 69.99,94.66 69.89,94.76 69.39,94.76 69.28,94.87 69.28,95.02 69.39,95.13 69.89,95.13 69.99,95.24 69.99,95.39 69.89,95.5 69.39,95.5 69.28,95.6 69.28,95.75 69.39,95.86 69.89,95.86 69.99,95.97 69.99,96.12 69.89,96.23 69.39,96.23 69.28,96.33 69.28,96.49 69.39,96.59 69.89,96.59 69.99,96.7 69.99,96.85 69.89,96.96 69.39,96.96 69.28,97.07 69.28,97.22 69.39,97.32 69.89,97.32 69.99,97.43 69.99,97.58 69.89,97.69 69.39,97.69 69.28,97.8 69.28,97.95 69.39,98.06 69.89,98.06 69.99,98.16 69.99,98.31 69.89,98.42 69.39,98.42 69.28,98.53 69.28,98.68 69.39,98.79 69.89,98.79 69.99,98.89 69.99,99.05 69.89,99.15 69.39,99.15 69.28,99.26 69.28,99.41 69.39,99.52 69.93,99.52 70.02,99.61 70.02,99.75 69.89,99.88 69.39,99.88 69.28,99.99 69.28,100.99 68.37,101.9 v1(67.1,101.9)
SOC_PORZ: length 219.5
  TOP w0.147: v1(26.64,135.41) 25.93,134.7 17.54,134.7 v1(16.68,135.56) ; U43.3 97.61,92.41 98.52,93.32 98.52,98.78 102,102.26 102,114.63 104.36,116.99 104.36,122.68 103.34,123.7 103.34,126.57 102.43,127.48 v1(102.43,128.85) ; v1(15.69,96.37) 17.34,94.73 17.34,82.37 16.32,81.36 16.32,75.51 17.04,74.8 17.04,70.78 18.63,69.19 21.51,69.19 23.61,67.08 23.61,65.64 v1(23.14,65.17)
  L03_SIG1 w0.091: v1(15.64,128.68) 16.91,127.41 16.91,118.49 15.59,117.17 14.42,117.17 13.46,116.22 13.46,98.07 15.16,96.37 v1(15.69,96.37)
  BOTTOM w0.147: v1(102.43,128.85) 97.68,128.85 95.62,130.91 91.69,130.91 91.4,131.2 88.59,131.2 88.13,130.73 75.86,130.73 75.1,129.97 74.77,129.97 69.74,124.94 60.83,124.94 58.29,127.48 58.29,128.79 56.1,130.97 47.33,130.97 46.41,131.9 30.37,131.9 29.94,132.33 29.94,133.84 28.37,135.41 v1(26.64,135.41) ; R480.2 22.97,65.34 v1(23.14,65.17) U86.4 ; v1(15.64,128.68) 14.6,129.72 14.6,133.48 v1(16.68,135.56)
SOC_PORZ_PB: length 163
  TOP w0.147: U43.1 98.73,90.59 98.88,90.74 98.88,98.63 102.35,102.11 102.35,114.48 106.14,118.26 106.14,127.51 104.77,128.88 v1(103.31,128.88) ; R268.2 v1(52.93,75.39) 52.93,75.96 TP55.1
  L03_SIG1 w0.091: v1(56.81,129.62) 55.69,129.62 54.48,128.4 54.48,115.72 55.21,114.99 55.21,111.48 53.56,109.83 53.56,105.64 52.11,104.19 52.11,100.86 52.8,100.18 52.8,95.02 54.2,93.62 54.2,91.47 53.81,91.08 53.81,89.2 55.19,87.83 55.19,87.78 55.21,87.76 55.21,86.64 52.8,84.23 52.8,82.88 54.25,81.43 54.25,76.38 53.25,75.39 v1(52.93,75.39)
  BOTTOM w0.147: v1(52.93,75.39) 52.93,75.03 52.31,74.42 U98.2 ; v1(56.81,129.62) 57.93,128.5 57.93,127.33 60.67,124.59 69.99,124.59 75.02,129.62 75.28,129.62 76.04,130.38 88.28,130.38 88.75,130.85 91.24,130.85 91.53,130.56 95.47,130.56 97.63,128.4 102.83,128.4 v1(103.31,128.88)
SOC_RGMII_MDC: length 83.5
  TOP w0.147: v1(89.4,83.46) 87.55,83.46 87.07,83.94 R548.2 ; R338.1 85.74,49.83 86.43,50.52 v1(86.43,51.46) ; v1(118.54,47.71) 118.86,47.39 118.86,46.28 118.51,45.93 R352.1
  L03_SIG1 w0.091: v1(86.43,51.46) 86.86,51.89 88.84,51.89 89.58,51.16 90.29,51.16 90.62,51.49 90.62,53.21 89.45,54.38 89.45,60.66 90.39,61.59 90.39,65.2 90.52,65.33 90.52,67.77 89.93,68.35 89.93,75.34 90.11,75.51 90.11,82.75 v1(89.4,83.46)
  BOTTOM w0.147: v1(118.54,47.71) 116.16,50.09 115.11,50.09 113.05,52.15 106.9,52.15 104.84,50.09 89.86,50.09 88.49,51.46 v1(86.43,51.46)
SOC_RGMII_MDIO: length 80.5
  TOP w0.147: R345.1 119.4,48.49 118.58,49.3 116.96,49.3 115.49,47.83 v1(110.38,47.83) ; v1(87.28,85.08) 87.43,85.23 87.79,85.23 87.87,85.16 R541.2 ; v1(87.04,50.34) 86.7,50 R340.1
  L03_SIG1 w0.091: v1(87.28,85.08) 88.39,85.08 90.39,83.08 90.39,75.23 90.21,75.06 90.21,68.48 90.87,67.82 90.87,65.28 90.72,65.13 90.72,64.44 91.25,63.91 91.25,61.9 90.8,61.44 90.8,55.98 90.52,55.7 90.52,54.46 91.2,53.77 91.2,50.6 90.67,50.06 90.04,50.06 89.76,50.34 v1(87.04,50.34)
  BOTTOM w0.147: v1(87.04,50.34) 88.66,48.72 109.49,48.72 v1(110.38,47.83)
SOC_TCK: length 51.9
  TOP w0.147: U136.A10 v1(67.3,84.85)
  L03_SIG1 w0.091: v1(36.29,86.49) 36.75,86.94 36.75,91.67 35.65,92.76 35.02,92.76 34.38,93.4 32.3,93.4 31.82,92.91 31.34,92.91 v1(30.83,93.42)
  BOTTOM w0.147: R534.1 30.46,94.3 30.83,93.93 v1(30.83,93.42) 30.79,93.42 30.78,93.43 R544.1 ; v1(67.3,84.85) 67.05,84.61 66.03,84.61 65.68,84.96 64.18,84.96 61.99,87.15 59.78,87.15 59.61,87.33 57.85,87.33 57.55,87.63 55.31,87.63 54.45,88.49 53.99,88.49 53.31,89.18 49.37,89.18 47.97,90.58 47.97,90.91 47.57,91.31 47.01,91.31 45.36,89.66 43.53,89.66 40.99,87.12 36.57,87.12 36.29,86.84 v1(36.29,86.49) 36.43,86.35 R566.1
SOC_TDI: length 60.3
  TOP w0.147: U136.D10 v1(69.7,84.85) ; v1(37.58,84.89) 40.23,84.89 41.88,86.54 41.88,90.07 v1(42.69,90.88)
  L03_SIG1 w0.091: v1(30.88,91.49) 32.45,93.07 34.1,93.07 36.14,91.03 36.14,89.1 35.86,88.82 35.86,86.31 36.31,85.85 37.05,85.85 37.58,85.32 v1(37.58,84.89)
  BOTTOM w0.132: v1(69.7,84.85) 69.29,85.26 68.73,85.26 68.09,85.9 65.42,85.9 65.27,86.06
  BOTTOM w0.147: U110.9 37.6,84.17 37.83,84.41 37.83,84.64 v1(37.58,84.89) ; U97.6 31.35,92.18 31.16,91.99 31.16,91.77 v1(30.88,91.49) 30.85,91.47 30.54,91.47 30.15,91.07 R554.1 ; 65.27,86.06 64.61,86.06 61.38,89.28 58.67,89.28 58.18,88.8 56.13,88.8 54.65,90.27 49.95,90.27 49.24,90.98 49.24,91.92 48.63,92.53 46.17,92.53 44.77,91.13 42.94,91.13 v1(42.69,90.88)
SOC_TDO: length 72.1
  TOP w0.147: v1(32.86,82.02) 34.05,82.02 34.59,81.48 35.45,81.48 37.1,83.13 37.1,87.33 37.79,88.01 37.79,90.3 38.96,91.47 40.43,91.47 41.72,92.76 42.97,92.76 43.99,93.78 43.99,97.36 43.5,97.84 43.5,101.81 v1(44.49,102.8) ; v1(59.45,105.74) 59.91,105.74 62.3,103.35 62.3,100.66 62.88,100.08 62.88,98.98 63.7,98.17 63.7,97.05 62.88,96.24 62.88,95.05 63.26,94.67 63.26,94.26 62.01,93.01 62.01,90.56 63.37,89.2 R542.1
  BOTTOM w0.147: U90.2 44.5,105.27 44.5,105.26 44.5,103.16 44.49,103.15 v1(44.49,102.8) 46.25,102.8 49.19,105.74 v1(59.45,105.74) ; v1(32.86,82.02) 32.81,82.02 32.69,82.14 32.69,82.47 32.69,82.48 U109.2
SOC_TMS: length 57.2
  TOP w0.147: v1(43.58,92.71) 43.15,92.28 41.88,92.28 40.18,90.58 40.18,88.27 38.24,86.33 v1(37.66,86.33) ; U136.C11 v1(68.9,85.65)
  L03_SIG1 w0.091: v1(37.66,86.33) 37.03,86.97 37.03,92 34.57,94.46 32.75,94.46 v1(31.64,93.34)
  BOTTOM w0.132: 65.75,86.23 65.8,86.18 68.37,86.18 v1(68.9,85.65)
  BOTTOM w0.147: U97.8 31.83,93.15 v1(31.64,93.34) 31.64,93.7 31.55,93.79 R533.1 ; U110.8 36.98,85.11 37.12,85.25 37.26,85.25 37.66,85.65 v1(37.66,86.33) ; v1(43.58,92.71) 43.83,92.96 43.83,93.16 44.52,93.85 47.82,93.85 49.6,92.08 49.6,91.13 50.1,90.63 54.86,90.63 56.33,89.15 58.03,89.15 58.51,89.64 61.54,89.64 64.76,86.41 65.58,86.41 65.75,86.23
SOC_TRST#: length 50.7
  TOP w0.147: U136.B10 v1(68.1,84.85)
  L03_SIG1 w0.091: v1(32.96,92.43) 34.28,92.43 35.81,90.91 35.81,89.18 35.45,88.82 35.45,86.11 v1(35.91,85.65)
  BOTTOM w0.132: v1(68.1,84.85) 67.61,85.34 65.17,85.34
  BOTTOM w0.147: U97.9 32.43,92.61 32.61,92.43 v1(32.96,92.43) ; 65.17,85.34 64.31,85.34 62.02,87.63 R564.1 59.81,87.63 59.76,87.68 58.01,87.68 57.7,87.99 55.47,87.99 54.6,88.85 54.15,88.85 53.46,89.53 49.52,89.53 48.33,90.73 48.33,91.19 47.77,91.74 46.7,91.74 44.98,90.02 42.46,90.02 40.99,88.54 37.51,88.54 35.55,86.59 35.55,86.23 35.91,85.88 v1(35.91,85.65) 36.19,85.37 U110.6
SOC_UART0_RXD: length 30.9
  TOP w0.132: 76.1,76.79 76.1,77.65 U136.L2
  TOP w0.147: 76.1,76.79 76.1,75.63 76.55,75.18 76.55,68.38 77.06,67.87 77.64,67.87 77.84,67.67 77.84,67.46 78.17,67.13 78.17,64.43 77.11,63.36 77.11,60.73 78.02,59.82 78.02,58.62 77.03,57.63 77.03,56.74 77.72,56.06 77.72,50.75 77.56,50.6 R5734.2
SOC_UART0_RXD_XDS: length 126.4
  TOP w0.147: U2353.15 77.77,45.47 77.74,45.44 v1(77.74,45.42)
  L03_SIG1 w0.091: v1(41.75,99.29) 42.61,99.29 44.16,97.74 44.16,93.24 45.53,91.87 45.53,89.05 44.95,88.47 44.95,78.94 45.53,78.36 45.53,78.16 41.88,74.5 41.88,72.46 43.4,70.95 43.4,67.99 42.72,67.31 37.03,67.31 36.16,66.45 36.16,63.09 35.45,62.38 35.45,60.63 34.74,59.92 34.74,58.55 34.26,58.06 33.72,58.06 32.83,57.18 32.83,56.46 34.03,55.27 35.73,55.27 37.1,53.9 37.1,45.36 39.24,43.23 42.51,43.23 v1(43.5,44.22)
  BOTTOM w0.147: v1(77.74,45.42) 76.68,46.47 74.81,46.47 74.55,46.21 67.84,46.21 67.34,46.71 66.96,46.71 66.33,46.08 57,46.08 53.84,42.92 53.84,37.49 53.67,37.31 53.21,37.31 53.03,37.49 51.76,37.49 51.55,37.29 50.72,37.29 49.45,38.56 49.22,38.56 47.74,40.03 47.74,42.78 46.71,43.81 46.19,43.81 45.59,44.42 43.71,44.42 v1(43.5,44.22) ; R5730.1 41.03,98.57 v1(41.75,99.29)
SOC_UART0_TXD: length 13.9
  TOP w0.147: U2353.8 76.97,51.1 77.18,51.31 77.18,56.06 76.67,56.57 76.67,57.78 77.46,58.57 77.46,59.79 76.46,60.8 R5732.2
SOC_UART0_TXD_XDS: length 119.9
  TOP w0.147: U2353.13 76.97,45.46 v1(76.57,45.06)
  L03_SIG1 w0.091: v1(40.53,42.75) 39.13,42.75 36.72,45.16 36.72,53.87 35.68,54.91 33.9,54.91 32.4,56.41 32.4,57.33 33.65,58.57 33.65,59.33 34.56,60.25 34.56,63.37 33.81,64.12 33.81,65.85 36.34,68.38 40.96,68.38 41.17,68.58 41.17,74.6 43.78,77.21 43.78,81.95 41.62,84.1 41.62,92.94 42,93.32 42,97.1 40.76,98.35 v1(40.76,99.29)
  BOTTOM w0.147: v1(40.53,42.75) 42.38,42.75 46.01,39.12 46.83,39.12 48.73,37.21 49.27,37.21 50.26,36.22 52.01,36.22 52.09,36.3 52.62,36.3 52.93,35.99 54.37,35.99 54.91,36.53 54.91,38.95 56.4,40.43 57.02,40.43 57.36,40.09 58.44,40.09 59.95,41.61 64.68,41.61 66.1,40.19 67.37,40.19 72.24,45.06 v1(76.57,45.06) ; v1(40.76,99.29) 39.91,98.44 R5731.1
SOC_USB0_DM: length 93.9
  TOP w0.107: U136.W9 v1(82.5,83.26) ; L10.4 49.82,13.69 49.5,14.01 49.5,14.2 v1(49.85,14.55)
  L03_SIG1 w0.094: v1(49.85,14.55) 49.55,14.86 49.55,15.98 50.36,16.8 51.58,16.8 52.46,17.68 52.46,25.22 53.36,26.12 62.78,26.12 64.55,27.89 64.55,34.24 69.72,39.4 71.72,39.4 74.81,42.49 74.81,44.02 76.05,45.26 76.05,49.85 81.59,55.39 81.59,62.1 83.85,64.36 83.85,76.71 82.43,78.13 82.43,80.57 81.82,81.18 81.82,81.69 82.2,82.06 82.2,82.95 v1(82.5,83.26)
SOC_USB0_DP: length 93.9
  TOP w0.107: v1(48.94,14.55) 49.28,14.21 49.28,14.01 48.97,13.69 L10.1 ; U136.V9 v1(81.7,83.26)
  L03_SIG1 w0.094: v1(81.7,83.26) 81.95,83 81.95,82.16 81.58,81.79 81.58,81.07 82.19,80.46 82.19,78.03 83.61,76.6 83.61,64.47 81.35,62.21 81.35,55.49 75.81,49.95 75.81,45.36 74.57,44.12 74.57,42.6 71.62,39.65 69.61,39.65 64.31,34.34 64.31,27.99 62.68,26.37 53.26,26.37 52.21,25.32 52.21,17.78 51.48,17.04 50.26,17.04 49.3,16.09 49.3,14.92 v1(48.94,14.55)
SOC_USB0_DRVVBUS: length 17.6
  TOP w0.132: 84.9,75.81 84.52,76.19 84.52,76.66
  TOP w0.147: U3077.5 86.79,65.68 85.08,67.39 85.08,71.68 86.45,73.05 86.45,74.26 84.9,75.81 ; 84.52,76.66 83.13,78.05 U136.W2
SOC_USB0_DRVVBUS_3V3: length 139.3
  TOP w0.147: v1(94.05,53.44) 94.05,54.28 96.77,57 96.77,61.77 96.99,62 96.99,64.3 95.61,65.68 U3077.10
  L03_SIG1 w0.091: v1(94.05,53.44) 94.05,48.97 95.72,47.29 95.72,36.53 96.69,35.56 96.69,31.04 v1(95.7,30.05) ; v1(45.21,18.82) 44.86,18.47 35.1,18.47 v1(33.89,17.26) 33.89,20.69 35.4,22.19 36.19,22.19 36.9,21.49 42.79,21.49 45.26,23.95 48.7,23.95 56.86,32.12 56.86,36.73 v1(57.14,37.01)
  BOTTOM w0.147: v1(33.89,17.26) 33.89,17.82 34.05,17.98 R674.1 ; R673.1 v1(45.21,18.82) ; v1(95.7,30.05) 95.7,27.76 95.02,27.08 83.25,27.08 72.26,38.07 64.64,38.07 62.5,40.21 60.92,40.21 60.61,39.89 60.61,39.15 58.47,37.01 v1(57.14,37.01)
SOC_USB0_RCALIB: length 4.4
  TOP w0.132: U136.V8 81.69,82.46 82.43,82.46 82.84,82.87 84.88,82.87
  TOP w0.147: 84.88,82.87 R553.1
SOC_USB0_VBUS: length 120.7
  TOP w0.147: R560.1 81.41,70.59 81.58,70.42 81.58,68.65 81.45,68.53 v1(81.45,68.17) ; U136.U9 v1(80.9,83.26) ; R398.1 52.75,13.44 v1(52.39,13.8)
  L03_SIG1 w0.091: v1(80.9,83.26) 80.52,82.88 80.52,81.47 81.4,80.59 81.4,79.1 81.91,78.59 81.91,76.68 82.39,76.2 82.39,75.9 81.91,75.41 81.91,68.63 v1(81.45,68.17) ; v1(52.39,13.8) 51.98,13.39 48.89,13.39 47.85,14.42 47.85,15.6 49.22,16.97 49.22,23.57 55.08,29.44 59,29.44 59.58,28.85 60.9,28.85 63.03,30.98 63.03,31.78 62.76,32.06 62.76,34.42 70.55,42.21 70.55,49.86 71.14,50.44 72.33,50.44 72.73,50.04 73.8,50.04 74.05,50.29 74.05,55.68 72.69,57.05 72.69,60.1 69.77,63.02 67.51,63.02 66.95,63.58 66.29,63.58 64.15,65.71 v1(64.15,66.75)
  BOTTOM w0.147: v1(81.45,68.17) 78.33,68.17 78.05,67.89 77.03,67.89 75.63,69.29 73.2,69.29 70.66,66.75 v1(64.15,66.75)
SOC_VDD_CANUART: length 10.7
  TOP w0.305: U136.F6 v1(71.3,81.66)
  TOP w0.381: 59.48,79.07 59.5,79.1 v1(61.41,79.1)
  L03_SIG1 w0.132: 70.86,80.52 70.86,81.02 71.3,81.46 v1(71.3,81.66) 71.75,81.2
  BOTTOM w0.254: R3731.1 66.03,80.96 64.7,79.63 63.95,79.63 63.42,79.1 v1(61.41,79.1)
  BOTTOM w0.305: v1(71.3,81.66) 71.44,81.51 C224.1
SOC_VDD_CANUART_N: length 8.3
  BOTTOM w0.147: 58.52,66.17 58.24,66.17 58.02,66.39 U3078.8 ; 58.52,66.17 U3078.9 58.52,68.12 58.31,68.33 C3761.2 58.31,69.49 58.59,69.77 58.59,70.28 58.26,70.61 57.78,70.61 R5780.1 ; 58.52,66.17 58.62,66.07 U3080.D1 U3080.D2
SOC_VDD_CANUART_P: length 8.5
  BOTTOM w0.147: R5781.1 57.88,70.96 58.41,70.96 58.94,70.42 58.94,69.77 59.23,69.49 C3761.1 59.23,68.35 59.23,68.34 59.23,68.33 59.02,68.12 U3078.10 59.02,66.22 59.25,65.99 59.25,64.77 59.07,64.59 U3080.D3
SOC_VDDSHV5_SDIO: length 56.7
  TOP w0.305: v1(78.5,83.26) U136.R8 ; v1(78.5,84.06) U136.P9
  TOP w0.381: v1(78.96,65.41) 78.96,65.87 79.04,65.95 79.04,70.36 77.77,71.63 v1(77.77,74.24)
  L03_SIG1 w0.254: v1(78.5,84.06) 78.5,83.88 78.71,83.67
  L04_PWR1 w0.381: v1(61.18,64.8) 57.68,68.3 55.47,68.3 54.68,67.51 54.68,63.62 53.08,62.02 53.08,59.31 52.29,58.52 50.89,58.52 50.18,57.81 48.73,57.81 48.07,58.47 v1(48.07,59.11)
  BOTTOM w0.381: v1(61.18,64.8) 61.87,65.48 64.15,65.48 64.81,64.82 65.88,64.82 66.46,65.41 v1(78.96,65.41) ; v1(78.5,84.06) 78.67,84.23 C3655.1 ; R243.2 46.21,56.99 46.74,57.52 47.15,57.52 48.07,58.45 v1(48.07,59.11)
SOC_VDDSHV_CANUART: length 3.4
  TOP w0.305: v1(55.82,85.34) 56.18,85.7 TP597.1 ; U136.F7 v1(71.3,82.46)
  L03_SIG1 w0.127: 70.05,81.23 70.63,81.23 70.9,81.49 70.9,81.82
  L03_SIG1 w0.132: 69.92,81.36 70.05,81.23
  L03_SIG1 w0.191: 70.9,82.05 v1(71.3,82.46)
  BOTTOM w0.254: v1(71.3,82.46) 71.49,82.65 C512.1
  vias: v1(63.52,82.4)
SOC_VDDSHV_CANUART_N: length 6.9
  BOTTOM w0.147: R5784.1 44.6,77.78 44.6,77.25 C3763.2 44.52,76.75 U3079.9 44.52,74.4 ; 44.52,74.4 44.65,74.27 U3081.D1 U3081.D2 ; 44.52,74.4 44.25,74.4 44.02,74.62 U3079.8
SOC_VDDSHV_CANUART_P: length 6.2
  BOTTOM w0.147: R5785.1 44.95,77.82 44.95,77.25 C3763.1 45.02,76.75 U3079.10 45.02,72.92 44.82,72.72 U3081.D3
SPI0_CLK: length 127.7
  TOP w0.147: v1(78.1,68.61) 77.9,68.61 77.75,68.75 R216.1 ; J12.17 121.61,142.78 119.22,140.39 119.22,130.4 118.71,129.9 118.71,124.03 118.99,123.75 118.99,108.64 117.49,107.14 117.49,84.68 115.21,82.4 115.21,71.32 114.8,70.92 114.8,67.64 112.59,65.43 v1(112.59,61.04)
  BOTTOM w0.147: v1(78.1,68.61) 78.53,69.04 80.08,69.04 80.48,68.63 82.24,68.63 84.98,65.89 91,65.89 95.78,61.11 97.2,61.11 98.04,61.95 111.68,61.95 v1(112.59,61.04)
SPI0_CLK_R: length 8.3
  TOP w0.147: U136.M1 76.5,75.64 76.9,75.23 76.9,70.84 77.75,69.99 R216.2
SPI0_CS0: length 133.1
  TOP w0.147: v1(116.65,64.85) 116.65,67.03 115.97,67.72 115.97,70.56 116.27,70.87 116.27,81.76 118.66,84.15 118.66,106.78 120.06,108.18 120.06,124.21 119.78,124.49 119.78,129.39 120.39,130 120.39,138.71 122.06,140.38 J12.23 ; U136.J3 v1(73.7,78.46)
  BOTTOM w0.147: v1(73.7,78.46) 73.7,77.32 74.47,76.55 74.47,74.42 78.05,70.84 81.45,70.84 81.68,70.61 82.8,70.61 84.65,68.76 86.07,68.76 86.71,68.12 91.03,68.12 95.75,63.4 97.4,63.4 97.45,63.45 111.55,63.45 112.95,64.85 v1(116.65,64.85)
SPI0_CS1: length 150.8
  TOP w0.147: J12.24 128.15,140.38 127.78,140.01 127.78,132.67 129.59,130.86 130.52,130.86 133.62,127.76 133.62,78.16 134.76,77.02 134.76,70.99 v1(133.16,69.39) ; U136.J4 v1(73.7,79.26)
  L03_SIG1 w0.091: v1(125.87,64.95) 125.87,66.02 126.86,67.01 133.14,67.01 133.6,67.46 133.6,68.96 v1(133.16,69.39)
  BOTTOM w0.147: v1(125.87,64.95) 125.63,64.7 119.47,64.7 118.87,65.3 112.89,65.3 111.42,63.83 95.83,63.83 91.08,68.58 86.84,68.58 86.2,69.22 84.7,69.22 82.95,70.97 81.83,70.97 81.61,71.19 78.19,71.19 74.96,74.42 74.96,76.62 74.21,77.37 74.21,78.74 v1(73.7,79.26)
SPI0_D0: length 128.7
  TOP w0.147: U136.K3 v1(75.3,78.46) ; v1(114.7,66.8) 115.26,67.36 115.26,70.87 115.56,71.17 115.56,82.25 117.95,84.63 117.95,107.09 119.35,108.48 119.35,123.9 119.07,124.18 119.07,129.69 119.63,130.25 119.63,139.45 122.16,141.98 J12.19
  BOTTOM w0.147: v1(75.3,78.46) 76.32,77.43 76.32,74.55 78.63,72.24 82.08,72.24 82.29,72.03 83.51,72.03 84.9,70.64 88.61,70.64 89.6,69.65 91.53,69.65 96.28,64.9 110.94,64.9 111.23,65.19 111.25,65.19 112.44,66.37 114.27,66.37 v1(114.7,66.8)
SPI0_D1: length 131.6
  TOP w0.147: U136.K4 v1(75.3,79.26) ; v1(115.16,65.79) 115.61,66.24 115.61,70.71 115.92,71.02 115.92,82.09 118.31,84.48 118.31,106.93 119.7,108.33 119.7,124.05 119.42,124.33 119.42,129.54 120.03,130.15 120.03,139.12 122.1,141.18 J12.21
  BOTTOM w0.147: v1(115.16,65.79) 114.7,65.79 114.57,65.66 112.74,65.66 111.27,64.19 95.98,64.19 91.23,68.94 88.74,68.94 87.75,69.93 84.6,69.93 83.2,71.32 81.98,71.32 81.77,71.54 78.34,71.54 75.46,74.42 75.46,76.65 74.59,77.52 74.59,78.97 74.88,79.26 v1(75.3,79.26)
SPI1_CLK: length 170.2
  TOP w0.132: 84.6,74.42 84.6,75.03 83.66,75.97 v1(82.97,75.97)
  TOP w0.147: v1(21.25,70.03) 22.63,68.65 31.94,68.65 33.98,70.69 33.98,71.34 35.68,73.04 40.65,73.04 42.91,70.79 44.87,70.79 45.43,70.23 47.69,70.23 48.17,70.71 54.18,70.71 56.02,68.87 56.02,67.94 56.89,67.08 56.89,64.08 56.41,63.6 56.41,61.19 57.85,59.74 57.85,59.44 60.01,57.28 61.66,57.28 62.48,56.46 63.47,56.46 65.55,54.38 72.12,54.38 74,52.5 v1(76.47,52.5) ; 84.6,74.42 R5659.1 ; J13.17 24.58,123.64 25.06,123.16 25.06,117.4 25.54,116.92 25.54,114.67 25.24,114.37 24.65,114.37 22.92,112.64 15.78,112.64 15.16,112.02 15.16,101.29 15.56,100.89 v1(15.56,99.36)
  L03_SIG1 w0.091: v1(82.97,75.97) 83.2,75.74 83.2,68.2 82.52,67.51 82.52,63.99 80.94,62.42 80.94,56.97 v1(76.47,52.5) ; v1(15.56,99.36) 16.78,99.36 18.99,97.16 18.99,81.03 19.67,80.35 19.67,75.92 18.86,75.12 18.86,71.01 19.84,70.03 v1(21.25,70.03)
SPI1_CLK_R: length 6.3
  TOP w0.132: 81.4,75.74 81.4,76.4 80.89,76.91 80.89,77.66 U136.U2
  TOP w0.147: 81.4,75.74 81.96,75.18 83.51,75.18 83.94,74.75 R5659.2
SPI1_CS0: length 171.8
  TOP w0.147: v1(80.87,76.05) 80.5,76.42 U136.U1 ; v1(76.6,54.84) 75.4,54.84 75.13,55.12 65.88,55.12 63.82,57.18 62.78,57.18 61.97,57.99 60.32,57.99 58.67,59.64 58.67,59.99 58.36,60.29 58.36,63.42 57.6,64.19 57.6,67.44 56.74,68.3 56.74,69.16 54.48,71.42 47.87,71.42 47.49,71.04 46.58,71.04 46.12,71.5 45.1,71.5 43.5,73.1 41.62,73.1 40.98,73.74 35.39,73.74 33.27,71.62 33.27,70.97 31.65,69.35 23.32,69.35 21.41,71.27 20.44,71.27 v1(18.81,69.65) ; J13.23 24.55,126.04 26.28,124.31 26.28,117.7 26.92,117.07 26.92,111.53 26.25,110.87 24.36,110.87 23.88,111.36 17.4,111.36 v1(16.5,110.46)
  L03_SIG1 w0.091: v1(80.87,76.05) 80.87,75.36 80.31,74.8 80.31,72.16 79.8,71.66 79.8,66.34 79.94,66.21 79.94,64.93 79.14,64.14 79.14,57.02 76.96,54.84 v1(76.6,54.84) ; v1(18.81,69.65) 18.2,70.26 18.2,77.14 19.3,78.23 19.3,80.14 18.64,80.8 18.64,97.1 16.96,98.78 15.55,98.78 14.88,99.44 14.88,108.84 v1(16.5,110.46)
SPI1_CS1: length 80.1
  TOP w0.147: v1(19.06,126.04) J13.24 ; U136.D15 v1(69.7,88.85)
  L03_SIG1 w0.091: v1(62.42,112.52) 62.15,112.25 62.15,101.55 v1(62.76,100.94)
  BOTTOM w0.132: v1(69.7,88.85) 70.09,89.25 70.09,92.41 69.23,93.27 69.23,94.49
  BOTTOM w0.147: 69.23,94.49 69.23,94.79 68.47,95.55 68.47,96.34 63.87,100.94 v1(62.76,100.94) ; v1(19.06,126.04) 19.06,125 20.04,124.02 28.09,124.02 31.06,121.06 40.96,121.06 41.83,120.19 43.3,120.19 44.92,118.57 45.38,118.57 45.79,118.97 49.09,118.97 53.87,114.2 55.31,114.2 56.51,113 61.94,113 v1(62.42,112.52)
SPI1_D0: length 167.3
  TOP w0.147: U136.T3 v1(80.1,78.46) ; v1(76.5,55.91) 76.27,56.13 75.15,56.13 74.97,55.96 66.06,55.96 64.13,57.89 63.09,57.89 62.27,58.7 60.7,58.7 59.81,59.59 59.81,68.28 55.39,72.69 51.96,72.69 51.5,72.24 48.43,72.24 47.8,72.87 44.98,72.87 44.04,73.81 41.95,73.81 41.32,74.44 34.96,74.44 31.92,71.41 31.92,70.87 31.11,70.06 24.02,70.06 21.46,72.62 20.39,72.62 18.13,74.88 18.13,77.77 v1(18.69,78.33) ; J13.19 24.55,124.44 25.42,123.57 25.42,117.56 26.21,116.78 26.21,111.82 26.02,111.63 24.73,111.63 24.25,112.12 15.89,112.12 v1(15.61,111.84)
  L03_SIG1 w0.091: v1(80.1,78.46) 80.1,76.27 79.52,75.7 79.52,74.82 79.72,74.63 79.72,72.39 79.26,71.92 79.26,66.08 79.39,65.94 79.39,65.2 78.55,64.36 78.55,57.21 77.25,55.91 v1(76.5,55.91) ; v1(15.61,111.84) 14.61,110.83 14.61,99.33 15.43,98.5 16.78,98.5 18.28,97 18.28,80.75 19.02,80.01 19.02,78.66 v1(18.69,78.33)
SPI1_D1: length 168.7
  TOP w0.147: v1(75.96,54.38) 75.56,53.98 73.91,53.98 73.12,54.76 65.73,54.76 63.67,56.82 62.63,56.82 61.82,57.63 60.16,57.63 58.31,59.49 58.31,59.78 56.81,61.28 56.81,63.5 57.24,63.93 57.24,67.26 56.38,68.12 56.38,69.01 54.32,71.07 48.02,71.07 47.59,70.64 46.47,70.64 45.97,71.15 44.95,71.15 44.11,71.98 42.21,71.98 40.8,73.39 35.53,73.39 33.62,71.48 33.62,70.83 31.79,69 23.01,69 v1(21.2,70.82) ; J13.21 24.34,125.24 25.93,123.65 25.93,117.55 26.56,116.92 26.56,111.67 26.16,111.28 24.45,111.28 24.02,111.71 17.1,111.71 16.05,110.65 16.05,101.14 19.52,97.66 v1(19.52,95.81) ; U136.U3 v1(80.9,78.46)
  L03_SIG1 w0.091: v1(21.2,70.82) 20.52,70.82 19.32,72.01 19.32,75.03 19.98,75.69 19.98,80.77 19.52,81.23 v1(19.52,95.81) ; v1(80.9,78.46) 81.24,78.11 81.24,70.86 80.08,69.7 80.08,66.5 80.21,66.37 80.21,66.34 80.23,66.32 80.23,64.82 79.41,64 79.41,56.9 76.89,54.38 v1(75.96,54.38)
SPI_HOLDN: length 1.8
  TOP w0.147: U69.7 43.23,28.64 43.63,28.23 R374.2
SPI_WPN: length 1.5
  TOP w0.147: U69.3 R378.2
SYNC1_OUT: length 46.7
  TOP w0.147: v1(104.79,55.3) 106.24,55.3 106.64,55.69 U3083.2 ; R5788.1 78.6,71.75 79.57,70.78 79.57,68.2 v1(80.97,66.8)
  L03_SIG1 w0.091: v1(80.11,59.74) 80.11,63.89 80.97,64.74 v1(80.97,66.8)
  BOTTOM w0.147: v1(80.11,59.74) 80.64,59.74 85.27,55.11 87.91,55.11 88.45,55.65 91.74,55.65 91.99,55.4 92.4,55.4 92.78,55.78 97.3,55.78 98.29,54.79 103.52,54.79 103.9,55.17 103.9,55.19 104.01,55.3 v1(104.79,55.3)
SYNC1_OUT_3V3: length 15.4
  TOP w0.147: U3084.1 112.11,50.63 111.75,50.27 110.48,50.27 108.79,51.96 108.79,59.99 108.55,60.22 R5793.1
SYNC1_OUT_ETH1: length 38.8
  TOP w0.147: J18.38 90.41,43.24 90.14,43.5 90.14,45.72 TP93.1 90.73,49.98 v1(90.09,50.62) ; v1(115.38,51.61) 115.99,52.22 R5791.2
  BOTTOM w0.147: v1(115.38,51.61) 114.39,52.6 106.04,52.6 104.06,50.62 v1(90.09,50.62)
SYNC1_OUT_ETH2: length 26.7
  TOP w0.147: v1(124.08,48.26) 123.61,47.79 TP87.1 123.47,46.36 122.67,45.57 122.67,43.46 122.84,43.3 J19.38 ; R5792.2 110.13,56.39 109.55,55.81 109.55,54.33 110.82,53.06 v1(111.17,53.06)
  BOTTOM w0.147: v1(124.08,48.26) 122.36,48.26 117.56,53.06 v1(111.17,53.06)
SYS_BOOTMODE0: length 33.6
  TOP w0.147: SW2.1 v1(74.54,117.73) R153.1
  L03_SIG1 w0.091: v1(74.54,117.73) 74.17,118.1 74.17,121.69 79.45,126.97 83.81,126.97 84.56,127.73 86.26,127.73 87.06,126.92 93.31,126.92 94.47,125.77 v1(94.47,124.93)
  BOTTOM w0.147: U82.1 v1(94.47,124.93) U81.10
SYS_BOOTMODE1: length 29.9
  TOP w0.147: R154.1 SW2.2 75.81,119.66 76.47,120.31 94.83,120.31 95.83,121.31 95.83,123.91 v1(95.31,124.43)
  BOTTOM w0.147: U82.2 v1(95.31,124.43) U81.9
SYS_BOOTMODE2: length 31.5
  TOP w0.147: v1(94.47,123.93) 94.79,124.25 94.79,124.59 95.17,124.97 95.62,124.97 96.21,124.38 96.21,121.2 94.95,119.94 77.26,119.94 77.08,119.76 SW2.3 R155.1
  BOTTOM w0.147: U81.8 v1(94.47,123.93) U82.3
SYS_BOOTMODE3: length 34.6
  TOP w0.147: R156.1 79.02,117.07 79.16,117.22 v1(79.16,117.65) 78.73,117.65 78.35,118.04 SW2.4
  L03_SIG1 w0.091: v1(79.16,117.65) 79.46,117.95 79.46,123.02 78.03,124.45 78.03,124.92 79.7,126.59 84.14,126.59 85,127.45 86.1,127.45 86.99,126.57 91.74,126.57 93.95,124.36 94.7,124.36 95.31,123.76 v1(95.31,123.43)
  BOTTOM w0.147: U81.7 v1(95.31,123.43) U82.4
SYS_BOOTMODE4: length 29.6
  TOP w0.147: SW2.5 79.62,117.93 v1(80.28,117.27) 80.28,117.22 80.13,117.07 R157.1
  L03_SIG1 w0.091: v1(94.47,122.93) 94.08,122.93 91.47,125.54 80.73,125.54 79.76,124.56 79.76,117.8 v1(80.28,117.27)
  BOTTOM w0.147: U82.5 v1(94.47,122.93) U81.6
SYS_BOOTMODE5: length 29
  TOP w0.147: SW2.6 v1(80.89,117.7) R158.1
  L03_SIG1 w0.091: v1(95.31,122.43) 92.63,122.43 91.83,123.24 88.56,123.24 86.54,125.26 80.84,125.26 80.03,124.45 80.03,118.57 v1(80.89,117.7)
  BOTTOM w0.147: U81.5 v1(95.31,122.43) U82.6
SYS_BOOTMODE6: length 25.1
  TOP w0.147: R159.1 v1(82.16,117.73) SW2.7
  L03_SIG1 w0.091: v1(94.47,121.93) 92.82,121.93 92.59,122.16 88.8,122.16 85.97,124.99 83.47,124.99 82.67,124.19 82.67,118.23 v1(82.16,117.73)
  BOTTOM w0.147: U81.4 v1(94.47,121.93) U82.7
SYS_BOOTMODE7: length 25.7
  TOP w0.147: SW2.8 v1(83.43,117.76) R160.1
  L03_SIG1 w0.091: v1(95.31,121.43) 93.05,121.43 92.65,121.03 88.96,121.03 85.28,124.72 83.58,124.72 83.2,124.33 83.2,117.99 v1(83.43,117.76)
  BOTTOM w0.147: U81.3 v1(95.31,121.43) U82.8
SYS_BOOTMODE8: length 23.7
  TOP w0.147: SW1.1 R145.1 85.56,117.07 84.47,118.16 84.47,118.85 v1(84.73,119.1)
  L03_SIG1 w0.091: v1(84.73,119.1) 86.89,116.94 93.74,116.94 94.2,117.4 v1(94.2,117.78)
  BOTTOM w0.147: U83.10 83.64,120.77 84.02,120.4 84.02,119.81 v1(84.73,119.1) ; U82.9 92.06,119.46 93.34,118.19 93.79,118.19 v1(94.2,117.78)
SYS_BOOTMODE9: length 14.6
  TOP w0.147: SW1.2 v1(88.32,117.76) R146.1
  BOTTOM w0.147: U82.10 91.56,119.11 90.06,117.61 90.06,117.59 89.78,117.31 88.77,117.31 v1(88.32,117.76) 86.75,117.76 84.37,120.14 84.37,120.62 83.72,121.27 U83.9
SYS_BOOTMODE10: length 19.1
  TOP w0.147: SW1.3 v1(89.59,117.76) R147.1
  L03_SIG1 w0.091: v1(84.83,120.9) 86.96,118.77 88.58,118.77 v1(89.59,117.76)
  BOTTOM w0.147: U82.11 91.06,119.7 89.95,118.58 86.56,118.58 84.83,120.32 v1(84.83,120.9) 83.96,121.77 U83.8
SYS_BOOTMODE11: length 21.1
  TOP w0.147: R148.1 v1(90.86,117.76) SW1.4
  L03_SIG1 w0.091: v1(83.74,122.27) 84.53,121.49 85.39,121.49 87.67,119.2 89.42,119.2 v1(90.86,117.76)
  BOTTOM w0.147: U82.12 90.56,119.88 89.62,118.93 87.18,118.93 85.43,120.69 85.43,120.95 84.1,122.27 v1(83.74,122.27) U83.7
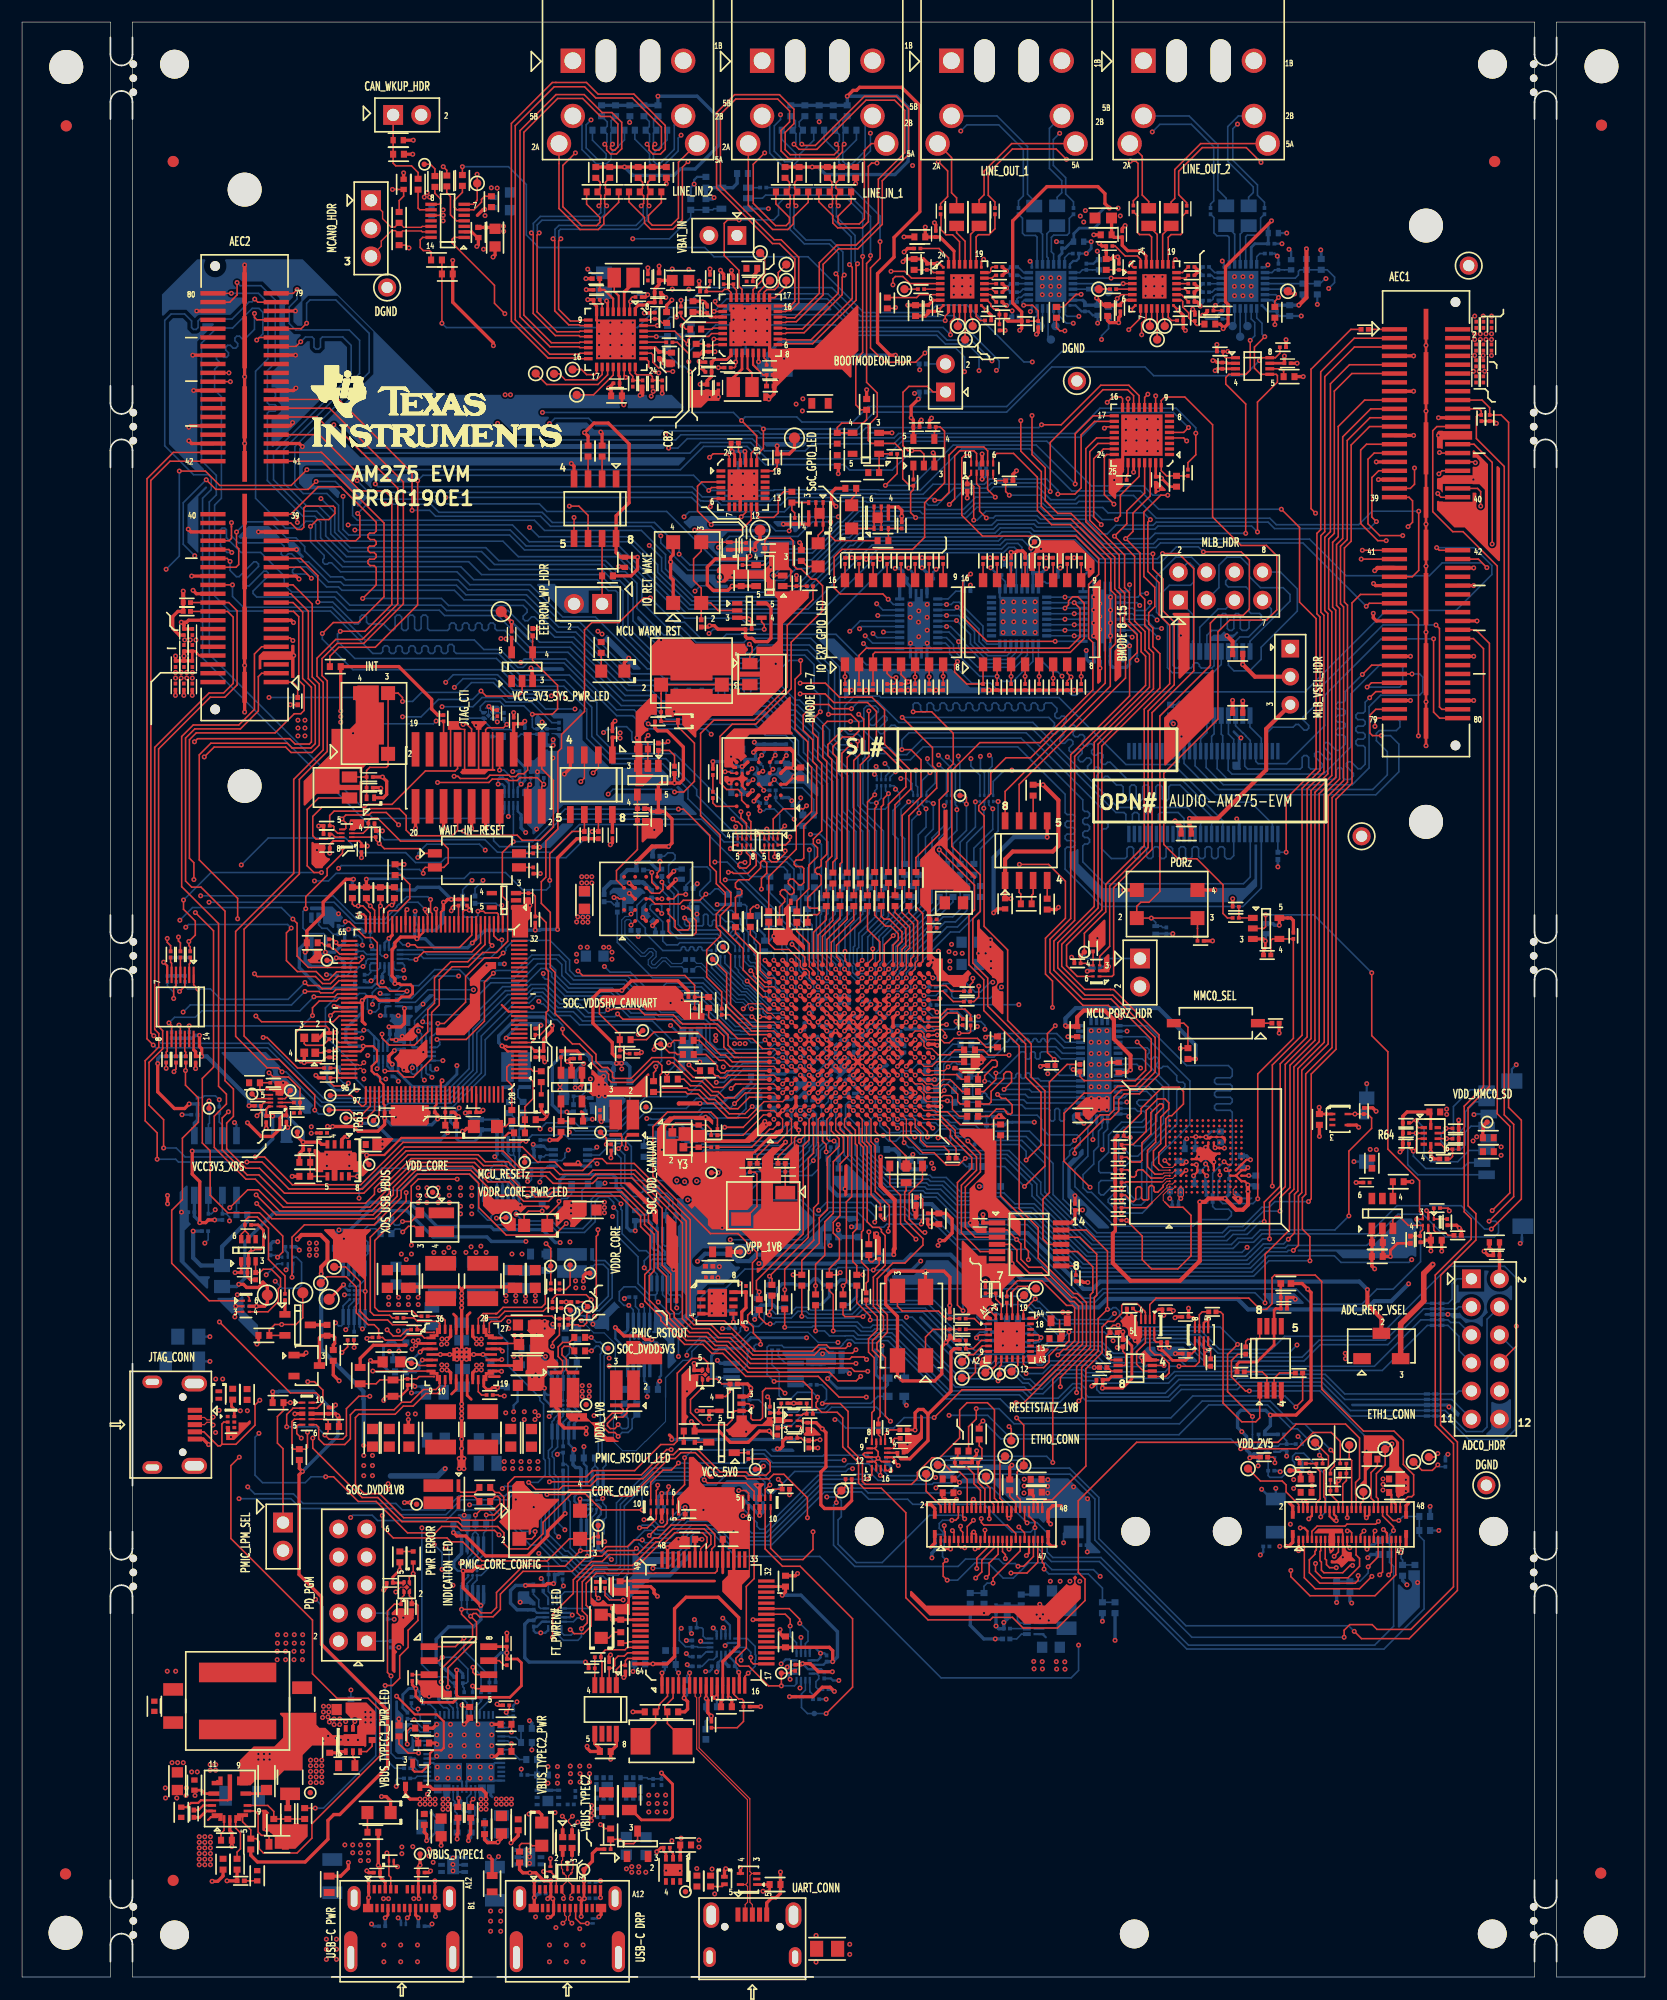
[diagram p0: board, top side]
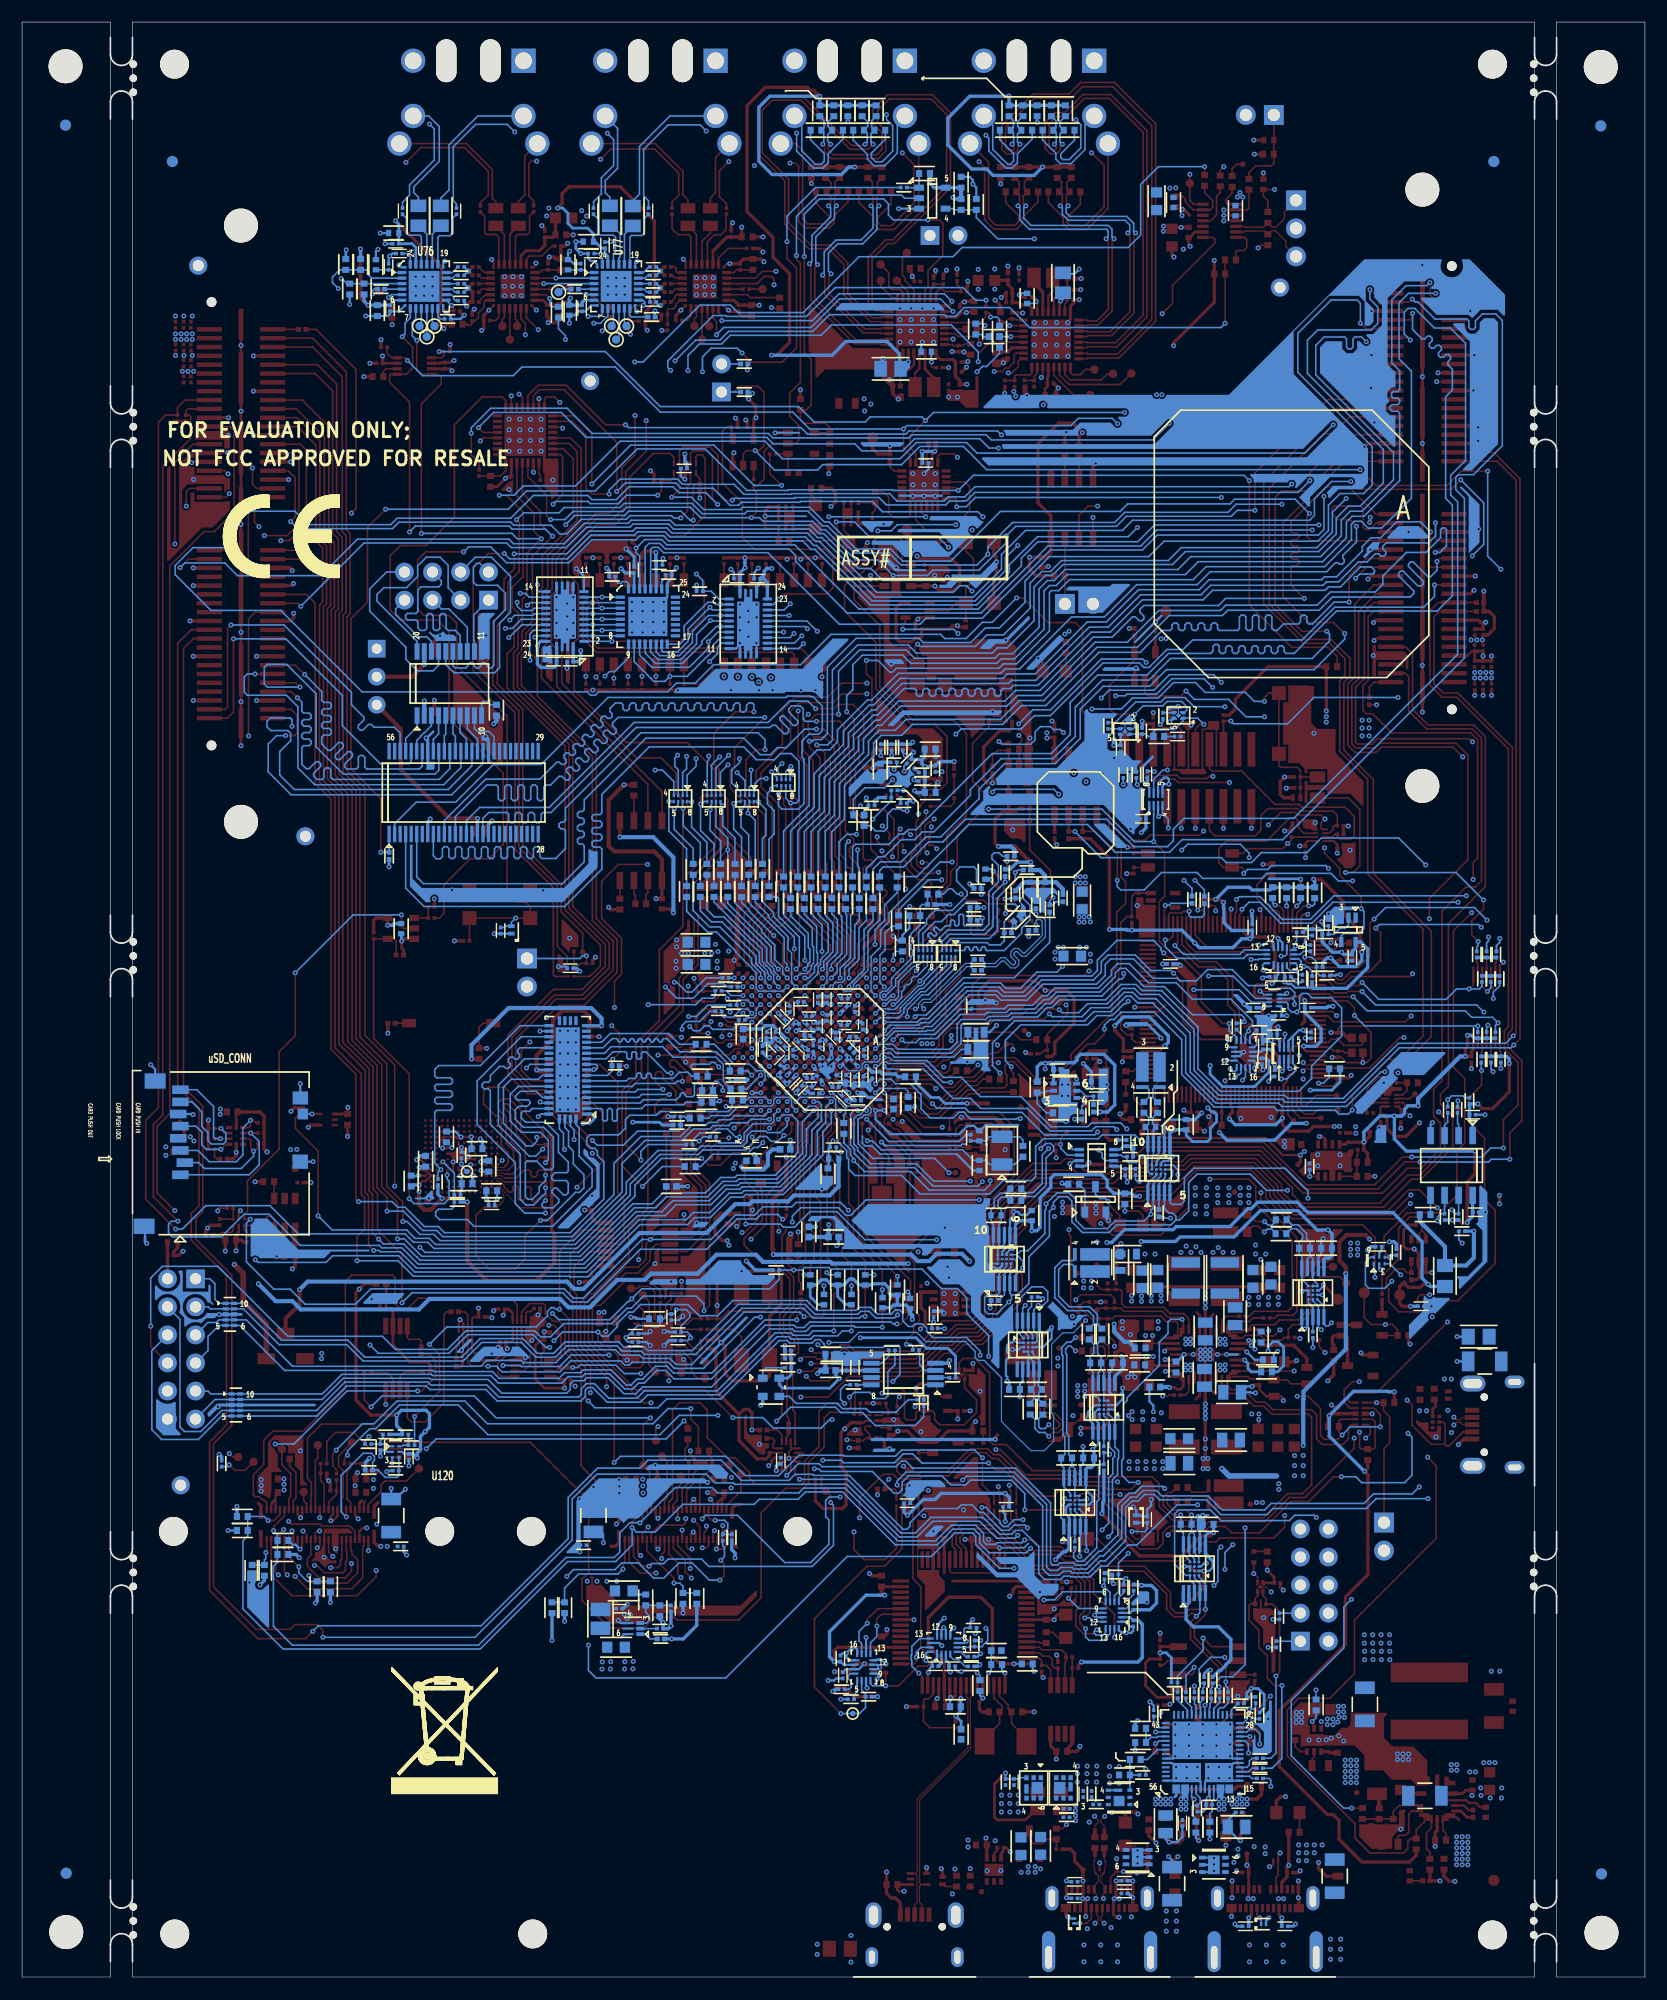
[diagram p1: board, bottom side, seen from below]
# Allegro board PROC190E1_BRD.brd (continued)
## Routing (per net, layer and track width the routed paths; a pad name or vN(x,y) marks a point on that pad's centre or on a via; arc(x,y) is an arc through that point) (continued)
SYS_BOOTMODE12: length 21.5
  TOP w0.147: R149.1 v1(92.13,117.76) SW1.5
  L03_SIG1 w0.091: v1(92.13,117.76) 89.98,119.91 88.21,119.91 85.3,122.82 v1(84.64,122.82)
  BOTTOM w0.147: U83.6 84.6,122.77 v1(84.64,122.82) 85.91,121.55 85.91,120.71 87.33,119.29 89.38,119.29 90.06,119.97 U82.13
SYS_BOOTMODE13: length 23.9
  TOP w0.147: R150.1 v1(93.4,117.59) SW1.6
  L03_SIG1 w0.091: v1(83.74,123.27) 84.09,123.27 84.19,123.16 84.19,122.66 84.81,122.05 85.44,122.05 87.93,119.56 89.67,119.56 92,117.22 93.02,117.22 v1(93.4,117.59)
  BOTTOM w0.147: U83.5 v1(83.74,123.27) 84.83,123.27 86.28,121.83 86.28,120.83 87.47,119.64 89.22,119.64 89.56,119.97 U82.14
SYS_BOOTMODE14: length 24.2
  TOP w0.147: SW1.7 94.67,118.05 v1(95.01,117.7) 94.67,117.36 R151.1
  L03_SIG1 w0.091: v1(95.01,117.7) 92.45,120.27 88.44,120.27 v1(84.7,124.01)
  BOTTOM w0.147: U82.15 89.06,120.09 88.96,119.99 87.62,119.99 86.68,120.92 86.68,122.03 v1(84.7,124.01) 84.46,123.77 U83.4
SYS_BOOTMODE15: length 24.8
  TOP w0.147: R152.1 v1(95.94,117.76) SW1.8
  L03_SIG1 w0.091: v1(83.74,124.27) 84.17,124.27 84.34,124.44 84.9,124.44 88.77,120.57 93.13,120.57 v1(95.94,117.76)
  BOTTOM w0.147: U83.3 v1(83.74,124.27) 84.17,124.27 84.37,124.47 84.89,124.47 87.04,122.32 87.04,121.06 87.42,120.68 U82.16
SYSBOOT_BUF_ENZ: length 1.3
  TOP w0.147: U23.1 R377.1
TAD1_ADDR1: length 3.1
  TOP w0.147: U5.13 87.41,151.82 87.76,151.47 87.76,151.29 88.02,151.03 88.41,151.03 88.53,150.91 R29.2 R37.2
TAD1_DREG_OUT: length 2.5
  TOP w0.147: U5.1 82.54,154.32 82.3,154.57 C45.1 81.4,154.57 C42.1
TAD1_GPI1: length 1.7
  TOP w0.147: R31.1 86.79,149.99 86.42,150.36 U5.12
TAD1_MICBIAS: length 1.4
  TOP w0.147: U5.14 87.72,152.32 87.86,152.17 87.86,152.02 88.22,151.66 C66.1
TAD1_VREF: length 3.5
  TOP w0.147: U5.24 83.92,155.64 83.06,156.5 C38.1
TAD2_ADDR2: length 4.4
  TOP w0.147: v1(90.72,151.36) 91.53,151.36 92.04,150.85 R36.2 R33.2
  BOTTOM w0.147: U77.13 90.77,151.82 90.59,151.65 90.59,151.43 90.67,151.36 v1(90.72,151.36)
TAD2_DREG_OUT: length 2.5
  BOTTOM w0.147: U77.1 95.8,154.32 96.04,154.57 C358.1 96.96,154.57 C356.1
TAD2_GPI1: length 2.4
  BOTTOM w0.147: U77.12 91.95,151.06 91.95,150.44 91.81,150.3 R429.1 90.26,150.3
TAD2_MICBIAS: length 1.5
  BOTTOM w0.147: U77.14 90.74,152.32 90.49,152.07 90.27,152.07 90.12,151.92 C370.1
TAD2_VREF: length 1.5
  BOTTOM w0.147: U77.24 94.44,155.66 94.82,156.04 C354.1
TAD3_ADDR3: length 4.2
  TOP w0.147: U6.13 105.02,151.82 105.14,151.7 105.14,151.2 105.67,150.67 105.67,150.23 105.97,149.93 R30.1 106.23,149.68 106.38,149.54 106.58,149.54 106.7,149.66 R35.1
TAD3_DREG_OUT: length 2.5
  TOP w0.147: C43.1 98.8,154.57 C46.1 99.88,154.57 100.13,154.32 U6.1
TAD3_GPI3: length 1.7
  TOP w0.147: U6.12 103.82,150.28 104.11,149.99 R32.1
TAD3_MICBIAS: length 1.4
  TOP w0.147: C67.1 105.64,151.7 105.01,152.32 U6.14
TAD3_VREF: length 3.5
  TOP w0.147: C35.1 99.02,156.72 99.92,155.82 101.03,155.82 101.32,155.53 U6.24
TAD4_ADDR4: length 2
  TOP w0.147: R28.1 R27.1 107.92,151.17 v1(108.1,151.35)
  BOTTOM w0.147: U76.13 108.11,151.35 v1(108.1,151.35)
TAD4_DREG_OUT: length 2.5
  BOTTOM w0.147: U76.1 113.22,154.32 113.46,154.57 C357.1 114.36,154.57 C355.1
TAD4_GPI4: length 1.4
  BOTTOM w0.147: R430.1 109.15,150.13 109.34,150.32 U76.12
TAD4_MICBIAS: length 1.4
  BOTTOM w0.147: C369.1 107.74,151.78 107.89,151.93 107.89,152.1 108.12,152.32 U76.14
TAD4_VREF: length 1.5
  BOTTOM w0.147: C353.1 112.12,156.04 111.84,155.76 U76.24
TAD5212_1_DIN: length 4.9
  TOP w0.147: U5.5 81.29,152.32 81.03,152.06 R5641.2
TAD5212_2_DIN: length 3.5
  TOP w0.147: v1(95.93,152.35) 95.47,152.35 94.33,151.21 R5642.2
  BOTTOM w0.147: v1(95.93,152.35) 95.9,152.32 U77.5
TAD5212_3_DIN: length 2.9
  TOP w0.147: v1(99.2,151.97) 99.55,152.32 U6.5
  BOTTOM w0.147: R5643.2 99.03,151.22 99.2,151.39 v1(99.2,151.97)
TAD5212_4_DIN: length 2.3
  TOP w0.147: v1(113.82,152.07) 113.48,151.73 R5644.2
  BOTTOM w0.147: v1(113.82,152.07) 113.56,152.32 U76.5
TAD5212_MCASP1_ACLKX: length 127.1
  TOP w0.147: R5646.1 75.34,110.14 76.24,111.05 76.24,113.87 v1(75.79,114.33) ; v1(78.71,154.43) 79.95,154.43 80.56,153.82 U5.2 ; U6.2 v1(98.65,153.82)
  L03_SIG1 w0.091: v1(118.36,152.88) 114.37,152.88 112.34,154.91 101.95,154.91 99.93,152.89 98.94,152.89 98.65,153.19 v1(98.65,153.82) 98.65,154.23 98,154.88 84.97,154.88 84.52,154.43 v1(78.71,154.43) 78.71,154.11 79.52,153.29 79.52,152.76 78.22,151.46 78.22,144.07 68.17,134.01 68.17,129.24 68.9,128.5 68.9,121.62 74.21,116.31 74.21,115.11 75,114.33 v1(75.79,114.33)
  BOTTOM w0.147: v1(118.36,152.88) 118.89,153.42 118.89,153.91 118.23,154.57 R418.2 R419.1 115.75,154.57 115.61,154.44 115.61,154.1 115.33,153.82 U76.2 ; U77.2 v1(98.65,153.82)
TAD5212_MCASP1_AFSX: length 126.2
  TOP w0.147: v1(78.88,153.21) 78.88,153.75 79.1,153.97 79.78,153.97 80.43,153.32 U5.3 ; U6.3 v1(99.74,153.32)
  L03_SIG1 w0.091: v1(72.13,102.82) 73.8,104.5 73.8,115.06 68.55,120.32 68.55,128.45 67.89,129.11 67.89,134.47 77.84,144.42 77.84,152.17 v1(78.88,153.21) 78.28,153.82 78.28,155.17 79.72,156.61 93.7,156.61 94.89,155.42 98.19,155.42 99.28,154.33 99.28,153.78 v1(99.74,153.32) 102.66,156.24 114.21,156.24 116.68,153.77 v1(118.1,153.77)
  BOTTOM w0.147: v1(118.1,153.77) 118.03,153.77 117.57,153.32 R422.2 R423.1 U76.3 ; U77.3 v1(99.74,153.32) ; v1(72.13,102.82) 72.41,102.54 R5647.2
TAD5212_MCASP1_AXR1: length 117.2
  TOP w0.147: R5641.1 79.04,151.08 v1(79.11,151.16) ; R5645.2 75.93,109.75 76.7,110.52 v1(76.7,114.63) ; v1(94.45,149.05) 94,149.05 93.69,149.35 R5642.1 ; v1(113.48,149.61) R5644.1
  L03_SIG1 w0.091: v1(113.48,149.61) 113.48,148.36 112.87,147.75 108.78,147.75 108.41,147.38 101.71,147.38 100.83,148.26 v1(97.78,148.26) 95.8,148.26 95.01,149.05 v1(94.45,149.05) 92.78,147.37 84.09,147.37 81.73,149.73 81.73,150.95 80.87,151.82 79.77,151.82 v1(79.11,151.16) 78.55,150.6 78.55,142.9 68.52,132.87 68.52,129.29 69.23,128.57 69.23,126.31 69.34,126.2 70.27,126.2 70.38,126.1 70.38,125.95 70.27,125.84 69.34,125.84 69.23,125.73 69.23,125.58 69.34,125.47 70.27,125.47 70.38,125.37 70.38,125.21 70.27,125.11 69.34,125.11 69.23,125 69.23,124.85 69.34,124.74 70.27,124.74 70.38,124.63 70.38,124.48 70.27,124.37 69.34,124.37 69.23,124.27 69.23,124.12 69.34,124.01 70.27,124.01 70.38,123.9 70.38,123.75 70.27,123.64 69.34,123.64 69.23,123.54 69.23,123.38 69.34,123.28 70.24,123.28 70.35,123.17 70.35,123.02 70.24,122.91 69.34,122.91 69.23,122.8 69.23,122.65 69.34,122.55 70.24,122.55 70.35,122.44 70.35,122.29 70.24,122.18 69.34,122.18 69.23,122.07 69.23,121.74 76.34,114.63 v1(76.7,114.63)
  BOTTOM w0.147: v1(97.78,148.26) 97.78,148.61 98.42,149.25 R5643.1
TCA6424_EXP_INT: length 2.3
  BOTTOM w0.147: R457.1 93.26,126.44 93.01,126.19 92.78,126.19 92.63,126.34 92.22,126.34 92.06,126.18 U82.32
TEST_GPIO1: length 30.8
  TOP w0.147: v1(27.12,100) 26.43,100 25.82,100.61 25.82,105.71 26.86,106.75 Q7.1 ; R235.1 15.23,93.27 15.11,93.4 v1(15.11,93.75) 15.69,94.34 15.69,95.61 14.62,96.67 v1(14.62,97.51)
  BOTTOM w0.147: v1(14.62,97.51) 17.11,100 v1(27.12,100) ; R235.1 15.23,93.27 15.11,93.4 v1(15.11,93.75)
TEST_GPIO2: length 138.8
  TOP w0.147: U21.18 97.15,140.85 95.93,139.62 95.93,134.82 95.37,134.26 v1(93.82,134.26) ; R285.2 R283.1 25.18,80.43 24.12,81.48 22.75,81.48 v1(22.37,81.86)
  L03_SIG1 w0.091: v1(32,135.18) 31.54,134.72 31.54,126.72 25.77,120.95 25.77,118.92 23.74,116.89 23.74,105.99 21.53,103.78 21.53,92.79 22.88,91.44 22.88,83.85 22.37,83.34 v1(22.37,81.86)
  BOTTOM w0.147: v1(32,135.18) 32.25,134.93 60.69,134.93 61.61,134.01 63.11,134.01 63.49,133.63 67.74,133.63 68.41,134.3 77.3,134.3 77.35,134.25 81.61,134.25 82.52,135.15 87.17,135.15 87.64,135.63 92.81,135.63 93.82,134.62 v1(93.82,134.26)
TEST_GPIO3: length 130.2
  TOP w0.147: R227.1 14.34,93.63 14.17,93.8 v1(14.17,94.16) ; U23.2 81.69,137.89 81.38,138.2 v1(80.59,138.2) 80.23,138.2 79.8,138.64 79.8,143.48 80.33,144.02 82.01,144.02 82.52,143.51 J10.1 ; v1(25.8,136.47) 24.38,135.05 17.9,135.05 16.6,136.35 v1(14.24,136.35)
  L03_SIG1 w0.091: v1(14.17,94.16) 12.82,95.51 12.82,127.23 v1(13.05,127.46)
  BOTTOM w0.147: 81.87,143.51 R439.1 J10.1 ; R227.1 14.34,93.63 14.17,93.8 v1(14.17,94.16) ; v1(14.24,136.35) 14.24,128.65 v1(13.05,127.46) ; v1(25.8,136.47) 59.63,136.47 61.74,138.58 65.68,138.58 67.33,136.93 74.47,136.93 74.95,136.44 78.84,136.44 v1(80.59,138.2)
TEST_GPIO4: length 132
  TOP w0.147: R221.1 13.45,93.38 13.15,93.68 v1(13.15,94.03)
  L03_SIG1 w0.091: v1(29.08,134.06) 28.24,133.22 14.29,133.22 12.54,131.47 12.54,94.64 v1(13.15,94.03)
  BOTTOM w0.147: R221.1 13.45,93.38 13.15,93.68 v1(13.15,94.03) ; v1(29.08,134.06) 29.08,131.06 29.58,130.56 44.16,130.56 45.51,129.21 53.84,129.21 60.02,123.03 65.12,123.03 65.67,122.48 72.97,122.48 79.44,128.95 88.89,128.95 89.38,129.44 89.88,129.44 90.06,129.27 U82.28
TEST_PORZN: length 202.8
  TOP w0.147: R219.1 v1(13.05,82.27) ; v1(103.78,134.16) 103.14,134.16 101.62,132.64 101.62,126.8 102.61,125.81 102.61,124.08 102.05,123.52 102.05,122.5 102.43,122.12 102.43,120.45 103.07,119.81 103.07,116.71 97.81,111.46 97.81,96.63 94.61,93.42 94.61,91.56 95.58,90.59 U43.6
  L03_SIG1 w0.091: v1(13.05,82.27) 13.05,85.87 11.8,87.12 11.8,132 13.99,134.19 21.89,134.19 v1(28.24,140.54)
  BOTTOM w0.147: v1(103.78,134.16) 102.43,134.16 101.59,135 96.87,135 92.82,139.05 79.71,139.05 78.12,137.46 67.46,137.46 65.99,138.93 61.45,138.93 60.5,137.98 30.8,137.98 v1(28.24,140.54) ; R219.1 v1(13.05,82.27)
TEST_POWERDOWN: length 28.3
  TOP w0.147: U54.1 16.95,61.23 13.56,64.62 13.56,69.42 14.52,70.38 14.52,75.95 15.97,77.39 15.97,79.58 14.8,80.75 v1(14.8,82.07) 14.83,82.1 R233.1
  BOTTOM w0.147: R233.1 14.83,82.1 v1(14.8,82.07)
TEST_WARMRESETN: length 116.9
  TOP w0.147: Q12.1 65.92,119.75 66.13,119.96 66.13,120.43 v1(65.88,120.68) ; R224.1 13.94,82.22 13.76,82.04 v1(13.76,81.97)
  L03_SIG1 w0.091: v1(27.07,133.86) 14.06,133.86 12.18,131.98 12.18,88.6 13.76,87.02 v1(13.76,81.97)
  BOTTOM w0.147: R224.1 13.94,82.22 13.76,82.04 v1(13.76,81.97) ; v1(65.88,120.68) 65.68,120.48 60.64,120.48 59.61,121.51 58.11,121.51 55.69,123.93 55.69,126.19 54.63,127.25 53.84,127.25 52.85,128.24 43.17,128.24 42,129.41 29.71,129.41 28.31,130.81 28.31,132.61 v1(27.07,133.86)
TM4C129_TCK: length 2.6
  TOP w0.147: U48.100 32.33,78.05 TP66.1
TM4C129_TDI: length 5.2
  TOP w0.147: U48.98 31.53,78.83 30.83,78.13 30.04,78.13 29.67,78.5 TP64.1
TM4C129_TDO: length 4.6
  TOP w0.147: TP62.1 29.79,79.82 30.76,78.85 30.93,78.85 31.13,79.06 U48.97
TM4C129_TMS: length 4.3
  TOP w0.147: TP63.1 31.22,77.76 31.93,78.48 U48.99
TMP411_ALERT: length 2.3
  TOP w0.147: R5741.2 U2357.6
TMP411_THERM: length 1.7
  TOP w0.147: U2357.4 R5742.2
TPS65224_EN: length 62.2
  TOP w0.147: v1(43.2,40.03) 42.79,40.44 39.77,40.44 39.41,40.79 38.01,40.79 37.43,40.21 34.91,40.21 32.07,43.05 30.45,43.05 28.21,45.29 v1(27.5,45.29) ; R317.1 43.14,52.69 43.23,52.6 v1(43.68,52.6) ; TP81.1 25.43,59.69 24.82,59.08 v1(23.51,59.08) 22.89,59.08 22.39,58.58 R303.1 Q4.2
  L03_SIG1 w0.091: v1(23.51,59.08) 22.09,57.66 22.09,49.86 v1(21.46,49.23) ; v1(43.2,40.03) 43.93,40.77 43.93,44.55 42.97,45.52 42.97,51.89 v1(43.68,52.6)
  BOTTOM w0.147: v1(27.5,45.29) 26.18,45.29 25.65,44.75 21.78,44.75 21.1,45.44 21.1,48.87 v1(21.46,49.23)
UART2_FET_SEL: length 160.4
  TOP w0.147: U2351.1 56.94,41.66 56.68,41.4 v1(56.33,41.4) ; U21.13 101.18,143.18 100.25,144.12 97.71,144.12 94.12,140.54 v1(92.35,140.54) ; v1(60.06,42.52) R5799.2 60.06,41.5 59.96,41.4 59.12,41.4 58.94,41.57 U2351.5
  L03_SIG1 w0.091: v1(60.06,42.52) 60.06,44.6 57.14,47.52 57.14,55.35 60.11,58.32 60.11,68.38 60.99,69.26 60.99,70.65 60.57,71.07 59.74,71.07 57.04,73.77 57.04,81.76 56.7,82.1 56.7,82.8 57.68,83.77 57.68,85.39 57.49,85.58 57.49,89.56 58.41,90.47 58.41,98.02 56.61,99.82 56.61,99.85 56.48,99.97 56.48,112.04 55.8,112.72 55.8,126.5 57.29,127.99 57.29,138.63 v1(58.29,139.62)
  BOTTOM w0.147: v1(58.29,139.62) 58.64,139.98 66.66,139.98 66.94,139.7 75.86,139.7 76.45,140.28 92.09,140.28 v1(92.35,140.54) ; v1(56.33,41.4) 57.15,41.4 57.75,40.79 58.13,40.79 58.41,41.08 58.41,41.22 59.71,42.52 v1(60.06,42.52)
UART2_RXD: length 181.3
  TOP w0.147: U2351.4 58.44,41.08 58.13,40.77 57.6,40.77 v1(56.81,39.98) ; v1(119.75,30.76) 119.75,31.39 120.26,31.9 122.29,31.9 122.73,31.47 125.8,31.47 129.66,35.33 129.66,48.29 128.01,49.94 128.01,63.55 131.26,66.8 131.26,68.66 130.63,69.29 130.63,78.85 132.38,80.59 132.38,120.27 131.47,121.18 J12.62
  BOTTOM w0.147: v1(56.81,39.98) 57.06,39.73 58.72,39.73 60.25,41.26 64.5,41.26 65.92,39.84 67.53,39.84 72.31,44.62 76.36,44.62 76.37,44.6 82.44,44.6 82.58,44.74 84.23,44.74 85.02,45.53 94.92,45.53 97.17,43.28 97.17,39.56 105.97,30.76 v1(119.75,30.76)
UART2_RXD_FET: length 111.1
  TOP w0.147: v1(83.08,102.06) 86.27,98.86 86.27,96.62 85.77,96.11 85.77,91.64 87.11,90.3 87.11,87.5 90.31,84.3 90.31,69.57 92.04,67.84 92.04,65.09 95.25,61.87 95.6,61.87 96.41,61.06 96.41,57.15 93.36,54.1 v1(93.36,46.58) ; v1(60.01,47.02) 60.01,44.58 58.94,43.51 U2351.6
  BOTTOM w0.147: v1(93.36,46.58) 92.8,47.14 83.25,47.14 81.5,45.39 78.47,45.39 76.62,47.24 72.61,47.24 72.52,47.16 67.88,47.16 67.33,47.71 60.71,47.71 v1(60.01,47.02) ; RA5.7 84.14,104.16 83.08,103.1 v1(83.08,102.06) R5718.2
UART2_TXD: length 184.9
  TOP w0.147: J12.60 131.68,121.98 132.91,120.75 132.91,80.62 130.98,78.69 130.98,69.82 131.69,69.11 131.69,66.73 128.49,63.53 128.49,49.96 130.01,48.44 130.01,35 125.65,30.63 121.33,30.63 v1(120.67,31.29) ; U2351.2 57.44,41.47 56.63,40.67 v1(55.92,40.67)
  BOTTOM w0.147: v1(120.67,31.29) 120.16,31.8 105.42,31.8 97.53,39.69 97.53,43.41 94.87,46.08 91.03,46.08 90.31,46.79 83.66,46.79 81.83,44.96 77.54,44.96 76.98,45.51 75.38,45.51 75.28,45.42 72.09,45.42 67.21,40.54 66.83,40.54 66.57,40.81 66.57,41.13 65.28,42.42 62.25,42.42 61.92,42.75 60.95,42.75 60.27,42.06 59.9,42.06 58.28,40.44 57.6,40.44 57.13,40.92 56.17,40.92 v1(55.92,40.67)
UART2_TXD_FET: length 57
  TOP w0.147: U136.T4 v1(80.1,79.26) ; v1(59.45,46.53) 58.82,45.9 58.06,45.9 56.94,44.78 U2351.10
  L03_SIG1 w0.091: v1(74.47,46.79) 74.7,47.02 74.7,53.72 76.45,55.47 77.21,55.47 78.86,57.13 78.86,64.27 79.66,65.06 79.66,66.08 79.53,66.21 79.53,71.79 80.03,72.29 80.03,74.96 80.47,75.4 80.47,78.64 80.1,79.02 v1(80.1,79.26)
  BOTTOM w0.147: v1(74.47,46.79) 72.82,46.79 72.59,46.56 67.98,46.56 67.18,47.36 66.32,47.36 65.49,46.53 v1(59.45,46.53)
UART3_FET_SEL: length 151.7
  TOP w0.147: U2352.5 65.81,43.81 65.58,44.04 v1(64.91,44.04) ; U21.14 100.68,143.17 100.14,143.71 97.91,143.71 93.13,138.94 v1(93.13,134.49) ; U2352.1 67.81,43.99 67.99,44.17 R5800.2 68.85,44.7 v1(68.5,45.06)
  L03_SIG1 w0.091: v1(59.96,132.21) 60.44,131.72 60.44,126.01 60.25,125.82 60.25,98.75 60.59,98.41 60.59,94.35 60.19,93.95 60.19,88.27 59.89,87.97 59.89,83.16 59.66,82.93 59.66,81.56 59.26,81.16 59.26,76.17 62.09,73.33 62.09,63.28 63.06,62.31 63.66,62.31 65.75,60.22 65.75,59.51 67.43,57.84 67.43,54.56 67.1,54.23 67.1,52.35 67.35,52.1 67.58,52.1 68.85,50.83 68.85,45.41 v1(68.5,45.06) 68.5,44.71 67.83,44.04 v1(64.91,44.04)
  BOTTOM w0.147: v1(93.13,134.49) 92.35,135.28 87.8,135.28 87.32,134.8 84.42,134.8 82.88,133.25 82.11,133.25 81.83,133.53 76.52,133.53 76.45,133.6 69.99,133.6 69.05,132.66 60.42,132.66 v1(59.96,132.21)
UART3_RXD: length 180.6
  TOP w0.147: U2352.4 66.31,43.97 65.55,44.73 62.07,44.73 v1(61.79,45.01) ; J13.62 v1(18.74,145.24)
  L03_SIG1 w0.091: v1(19.65,43.31) 19.65,44.22 16.13,47.74 16.13,51.74 16.94,52.54 18.22,52.54 19.16,53.48 19.16,56.81 17.34,58.62 12.52,58.62 11.09,60.06 11.09,143.31 13.03,145.24 v1(18.74,145.24)
  BOTTOM w0.147: v1(61.79,45.01) 61.47,45.33 57.24,45.33 54.55,42.64 54.55,36.93 53.99,36.37 53.08,36.37 52.72,36.73 52.01,36.73 51.86,36.58 50.41,36.58 49.32,37.67 48.89,37.67 47.03,39.52 47.03,42.5 46.46,43.08 45.92,43.08 45.31,43.69 44.44,43.69 43.96,43.21 39.74,43.21 38.4,41.86 34.23,41.86 33.67,42.42 25.24,42.42 24.35,43.31 v1(19.65,43.31)
UART3_RXD_FET: length 60.1
  TOP w0.147: U2352.6 65.81,41.95 65.62,41.76 v1(65.3,41.76) ; U136.C6 v1(68.9,80.86)
  L03_SIG1 w0.091: v1(68.9,80.86) 67.95,79.91 62.91,79.91 62.74,80.08 61,80.08 60.35,79.43 60.35,77.36 64.15,73.56 64.15,72.31 63.85,72.01 63.85,67.46 63.29,66.9 63.29,65.8 66.07,63.02 66.41,63.02 69.51,59.92 69.51,58.31 68.93,57.73 68.93,53.7 68.4,53.17 68.4,52.24 69.94,50.7 69.94,42.92 67.31,40.29 66.08,40.29 65.3,41.07 v1(65.3,41.76)
UART3_TXD: length 180.9
  TOP w0.147: U2352.2 67.31,44.12 v1(67.73,44.55) ; v1(18.86,144.44) J13.60
  L03_SIG1 w0.091: v1(18.86,144.44) 13.19,144.44 11.45,142.7 11.45,60.1 12.64,58.9 17.47,58.9 19.45,56.92 19.45,53.24 18.48,52.27 17.05,52.27 16.41,51.62 16.41,47.95 19.98,44.37 v1(20.44,44.37)
  BOTTOM w0.147: v1(20.44,44.37) 21.07,43.74 24.58,43.74 25.44,42.88 33.85,42.88 34.43,42.29 38.3,42.29 39.57,43.56 43.76,43.56 44.24,44.04 45.46,44.04 46.04,43.46 46.57,43.46 47.39,42.64 47.39,39.78 49.04,38.13 49.37,38.13 50.56,36.93 51.71,36.93 51.86,37.08 52.93,37.08 53.21,36.8 53.87,36.8 54.2,37.13 54.2,42.78 57.13,45.71 66.92,45.71 67.73,44.9 v1(67.73,44.55)
UART3_TXD_FET: length 58
  TOP w0.147: v1(71.65,40.31) 71.65,38.71 70.73,37.8 68.83,37.8 67.81,38.81 U2352.10 ; U136.N4 v1(77.7,79.26)
  L03_SIG1 w0.091: v1(71.65,40.31) 71.65,40.92 73.25,42.52 73.93,42.52 74.19,42.77 74.19,45.9 74.97,46.69 74.97,51.99 79.69,56.71 79.69,63.87 80.69,64.87 80.69,66.29 80.36,66.62 80.36,69.57 81.52,70.73 81.52,78.37 81.03,78.85 80.77,78.85 80.5,79.12 80.5,79.39 80.25,79.63 78.07,79.63 v1(77.7,79.26)
UART_SHIELD:
  vias: v1(71.92,3.76) v1(71.92,1.35)
USB_TYPEC1_EARTH:
  vias: v1(27.56,3.42) v1(27.56,2.51) v1(27.56,1.59) v1(28.48,3.42) v1(28.48,2.51) v1(28.48,1.59) v1(32.77,2.9) v1(32.77,1.37) v1(34.29,2.9) v1(34.29,1.37) v1(35.82,2.9) v1(35.82,1.37)
USB_TYPEC2_EARTH:
  vias: v1(42.44,5.97) v1(42.44,5.06) v1(42.44,4.14) v1(43.35,5.97) v1(43.35,5.06) v1(43.35,4.14) v1(47.77,2.9) v1(47.77,1.37) v1(49.29,2.9) v1(49.29,1.37) v1(50.82,2.9) v1(50.82,1.37)
USBC_CONN1_CC1: length 41.1
  TOP w0.147: v1(33.05,11.23) 33.23,11.04 D7.1 33.23,9.19 33.39,9.02 J24.A5 ; C307.1 34.14,21.11 34.98,20.27 v1(35.91,20.27)
  L03_SIG1 w0.091: v1(33.05,11.23) 33.05,10.34 34.21,9.17 42.56,9.17 46.5,13.12 46.5,18.52 45.48,19.53 36.66,19.53 v1(35.91,20.27)
  BOTTOM w0.147: v1(35.91,20.27) 35.91,21.09 36.21,21.38 U129.24
USBC_CONN1_CC2: length 40.3
  TOP w0.147: v1(34.89,5.35) 35.14,5.6 J24.B5 ; C306.1 35.15,22.53 34.89,22.28 v1(34.89,21.08)
  L03_SIG1 w0.091: v1(34.89,5.35) 38.38,8.84 42.61,8.84 46.8,13.04 46.8,18.64 45.64,19.81 43.58,19.81 42.97,20.42 36.49,20.42 35.83,21.08 v1(34.89,21.08)
  BOTTOM w0.147: v1(34.89,5.35) 34.76,5.22 D17.1 ; U129.26 36.06,22.18 35.81,22.43 35.3,22.43 34.89,22.02 v1(34.89,21.08)
USBC_CONN2_CC1: length 19.3
  TOP w0.147: J25.A5 48.39,9.01 D8.1 v1(47.24,9.55) ; C305.1 v1(44.33,22.18)
  L03_SIG1 w0.091: v1(44.33,22.18) 43.9,21.75 43.9,20.94 44.63,20.22 45.79,20.22 47.16,18.85 47.16,12.6 46.68,12.12 46.68,10.11 v1(47.24,9.55)
  BOTTOM w0.147: U129.45 v1(44.33,22.18)
USBC_CONN2_CC2: length 26.5
  TOP w0.147: v1(51.2,4.85) 50.59,4.85 50.14,5.3 J25.B5 ; C312.1 v1(44.33,21.12)
  L03_SIG1 w0.091: v1(51.2,4.85) 51.2,5.18 51.37,5.35 51.37,9.08 47.58,12.87 47.58,15.86 48.92,17.2 48.92,19.51 47.31,21.12 v1(44.33,21.12)
  BOTTOM w0.147: D16.1 v1(51.2,4.85) ; v1(44.33,21.12) 44.25,21.12 43.99,21.38 U129.47
USBC_CONN2_DM: length 14.7
  TOP w0.107: L10.3 49.82,10.59 49.9,10.51 49.9,9.8 49.83,9.73 49.83,9.47 D9.3 49.5,9.15 49.5,8.63 49.89,8.24 J25.A7 49.89,7.69 49.64,7.44 49.64,7.21 v1(49.75,7.1) ; v1(48.99,4.87) 49.29,5.17 49.29,5.46 49.14,5.61 J25.B7
  L03_SIG1 w0.094: v1(49.75,7.1) 49.52,7.33 49.52,7.77 49.22,8.08 47.34,8.08 46.91,7.65 46.91,6.55 47.46,5.99 48.86,5.99 49.27,5.58 49.27,5.15 v1(48.99,4.87)
USBC_CONN2_DP: length 13.9
  TOP w0.107: v1(49.04,7.1) 49.04,7.12 49.15,7.23 49.15,7.38 48.89,7.64 J25.A6 48.89,8.21 49.29,8.6 49.29,9.15 D9.2 48.96,9.47 48.96,9.73 48.86,9.83 48.86,10.49 48.97,10.6 L10.2 ; v1(49.8,4.87) 49.51,5.16 49.51,5.48 49.64,5.61 J25.B6
  L03_SIG1 w0.094: v1(49.8,4.87) 49.52,5.15 49.52,5.69 48.96,6.24 47.57,6.24 47.15,6.66 47.15,7.54 47.44,7.83 49.12,7.83 49.28,7.67 49.28,7.34 v1(49.04,7.1)
VMAIN: length 8.7
  TOP w0.147: U3068.10 v1(38.15,159.5)
  TOP w0.254: U134.12 16.54,16.6 16.24,16.91 C3631.1 ; C3629.1 21.82,16.6 U134.8
  TOP w0.305: U73.1 28.64,20.41 28.53,20.3 C310.1 ; R5636.1 v1(35.39,165.04)
  TOP w0.381: R5740.1 24.07,16.38 C3625.1
  vias: v1(12.97,17.12) v1(13,16.21) v1(14.01,16.21) v1(14.88,17.12) v1(14.85,16.43) v1(15.66,16.43) v1(26.13,19.63) v1(26.13,19.13) v1(26.13,18.62) v1(26.13,18.11) v1(26.13,17.6) v1(26.64,19.63) v1(26.64,19.13) v1(26.64,18.62) v1(26.64,18.11) v1(26.64,17.6) v1(27.14,19.63) v1(27.14,19.13) v1(27.14,18.62) v1(27.14,18.11) v1(27.14,17.6) v1(38.14,159.99) v1(38.14,159)
VMAIN_EN: length 19.2
  TOP w0.147: LD14.1 35.43,37.52 v1(35.43,36.53) 35.08,36.18 U71.4
  L03_SIG1 w0.091: v1(29.79,25.98) 29.79,36.07 30.32,36.6 32.81,36.6 33.37,36.04 34.94,36.04 v1(35.43,36.53)
  BOTTOM w0.147: R382.1 v1(29.79,25.98)
VMAIN_PD: length 3.5
  BOTTOM w0.254: U129.11 38.29,16.86 38.29,16.27 ; U129.11 38.45,16.43 38.29,16.27 ; U129.11 38.62,16.86 38.62,16.27 ; 38.29,16.27 v1(38.12,16.1) ; 42.59,16.31 42.45,16.44 U129.1
  vias: v1(27.22,23.5) v1(27.3,24.51) v1(27.3,23.99) v1(27.7,23.55) v1(27.78,24.5) v1(27.78,24) v1(27.83,23.09) v1(28.26,23.36) v1(28.26,22.85) v1(28.77,23.36) v1(28.77,22.85) v1(29.31,23.13) v1(38.12,15.65) v1(38.12,15.19) v1(38.58,16.1) v1(38.58,15.65) v1(38.58,15.19) v1(42.95,16.11) v1(42.95,15.66) v1(43.41,16.11) v1(43.41,15.66) v1(43.87,16.11) v1(43.87,15.66) v1(44.32,16.11) v1(44.32,15.66)
VMON1: length 7
  TOP w0.147: R5774.2 32.06,53.71 32.41,54.06 R5773.1 34.52,54.06 34.62,54.16 C3750.2 35.76,54.16 35.97,54.36 U56.9
VPHY_3V3_FT4232: length 3.3
  TOP w0.147: U64.4 v1(59.47,27.54)
  BOTTOM w0.147: v1(59.47,27.54) 59.21,27.79 C606.2 FL17.1
VPLL_3V3_FT4232: length 6.6
  TOP w0.254: v1(61.97,25.22) U64.9
  TOP w0.305: v1(61.97,25.22) 62.12,25.06 62.12,23.93 v1(62.43,23.63) 62.44,23.61 R357.2
  BOTTOM w0.254: FL18.1 61.94,23.14 v1(62.43,23.63) 61.97,24.09 C607.2 v1(61.97,25.22)
VPP_1V8: length 2.4
  TOP w0.305: U136.G5 v1(72.1,80.06)
  TOP w0.381: R304.2 TP69.1
  L03_SIG1 w0.254: 71.85,79.65 72.1,79.9 v1(72.1,80.06)
  BOTTOM w0.254: v1(72.1,80.06) 72.22,80.18 C517.1
  vias: v1(65.83,65.66)
VPP_EN: length 136.2
  TOP w0.147: v1(105.66,140.28) 105.22,139.85 U21.5
  L03_SIG1 w0.091: v1(63.44,58.7) 63.12,58.7 61.82,60 61.82,73.2 58.98,76.04 58.98,81.29 59.38,81.69 59.38,83.06 59.62,83.3 59.62,86.2 59.33,86.48 59.33,89.18 59.59,89.44 59.59,96.06 59.84,96.32 59.98,96.32 60.31,96.65 60.31,97.01 59.69,97.63 59.69,98.2 59.91,98.42 59.91,125.88 60.16,126.14 60.16,129.84 58.56,131.44 v1(58.56,138.43)
  BOTTOM w0.147: v1(63.44,58.7) 63.47,58.72 R319.1 ; v1(105.66,140.28) 104.28,141.66 98.16,141.66 95.91,139.4 79.55,139.4 78.96,138.81 71.57,138.81 70.94,138.18 67.25,138.18 66.15,139.28 60.25,139.28 59.4,138.43 v1(58.56,138.43)
VSEL_SD_SOC: length 39.5
  TOP w0.147: v1(58.64,84.38) 59.06,84.8 R5751.2 ; v1(66.11,51.64) 65.84,51.91 U3086.2
  L03_SIG1 w0.091: v1(58.64,84.38) 58.64,83.73 57.99,83.07 57.99,75.47 60.52,72.94 60.52,72.02 61.54,70.99 61.54,68.99 60.67,68.12 60.67,57.07 v1(66.11,51.64)
WD_DISABLE: length 13
  TOP w0.147: TP56.1 49.64,62.62 49.26,62.24 R282.2 R281.2 47.53,62.24 47.39,62.1 47.39,60.96 47.06,60.63 43.57,60.63 43.02,60.07 42.97,60.07 42.95,60.07 41.77,60.07 41.32,59.61 U56.29
WKUP_I2C0_SCL: length 119.3
  TOP w0.147: R301.2 C245.1 ; R301.2 60.92,89.79 60.04,90.68 50.77,90.68 v1(50.36,91.08) ; R301.2 R284.1 ; v1(34.79,71.02) 34.79,70.23 31.54,66.98 31.54,60.25 31.87,59.92 33.29,59.92 33.54,59.67 R297.1
  L03_SIG1 w0.091: v1(38.37,117.22) 38.73,116.87 38.73,110.08 41.15,107.66 41.15,103.23 39.82,101.9 39.82,100.03 37.48,97.69 37.48,97.31 38.07,96.72 38.07,95.12 38.85,94.34 38.85,87.78 39.74,86.89 39.74,83.57 37.61,81.43 37.61,80.62 34.79,77.8 v1(34.79,71.02) ; v1(50.36,91.08) 50.04,91.08 49.21,91.91 49.21,94.9 48.53,95.58 48.53,107.62 49.55,108.64 49.55,109.09 49.54,109.1 49.54,115.5 v1(49.24,115.8)
  BOTTOM w0.147: v1(38.37,117.22) 39.06,117.91 43.07,117.91 44.47,116.51 48.53,116.51 v1(49.24,115.8)
WKUP_I2C0_SCL_RC: length 8.5
  TOP w0.132: 67.07,84.05 68.1,84.05 U136.B9
  TOP w0.147: R284.2 62.19,86.87 62.43,86.64 63.14,86.64 64.81,84.96 66.16,84.96 67.07,84.05
WKUP_I2C0_SDA: length 118.3
  TOP w0.147: v1(52.44,88.01) 52.29,87.86 52.29,87.21 54.14,85.36 R256.1 R259.2 54.42,83.9 54.72,83.6 C248.1 ; R307.1 35.85,59.82 35.4,60.27 32.3,60.27 31.95,60.63 31.95,66.67 35.25,69.98 35.25,71.6 35.88,72.24 v1(39.41,72.24)
  L03_SIG1 w0.091: v1(39.41,72.24) 39.41,73.25 43.5,77.34 43.5,81.81 41.34,83.97 41.34,93.07 41.72,93.45 41.72,96.93 40.33,98.32 40.33,101.63 41.45,102.74 41.45,107.77 39.01,110.21 39.01,116.29 39.16,116.44 v1(39.16,116.76) ; v1(47.95,116) 47.95,113 47.16,112.22 47.16,109.63 48.23,108.56 48.23,95.17 47.85,94.79 47.85,92.46 48.89,91.41 48.89,89.71 50.59,88.01 v1(52.44,88.01)
  BOTTOM w0.147: v1(39.16,116.76) 39.95,117.55 42.84,117.55 44.24,116.15 46.92,116.15 47.07,116 v1(47.95,116)
WKUP_I2C0_SDA_RC: length 14
  TOP w0.147: R256.2 56.56,84.87 57.24,85.55 61.21,85.55 63.28,83.48 63.71,83.48 64.33,82.86 U136.A8
WKUP_LFOSCO_XI: length 17
  TOP w0.147: U136.E1 70.9,76.17 v1(70.43,75.7)
  BOTTOM w0.147: R568.1 56.38,74.26 57.07,73.57 Y4.1 59.36,73.57 59.73,73.94 59.82,73.94 59.82,73.94 C216.2 60.85,73.94 61.8,74.88 69.16,74.88 69.98,75.7 v1(70.43,75.7)
WKUP_LFOSCO_XO: length 5.5
  BOTTOM w0.147: R568.2 56.34,75.8 56.62,76.07 Y4.2 59.38,76.07 59.75,75.7 C213.2 60.29,75.71 R261.2
WKUP_UART0_CTSN: length 71.2
  TOP w0.147: U136.D6 v1(69.7,80.86) ; R322.2 51.96,34.54 51.97,34.54 v1(52.21,34.29)
  L03_SIG1 w0.091: v1(56.58,77.72) 56.58,73.84 59.63,70.79 60.46,70.79 60.72,70.53 60.72,69.39 59.83,68.5 59.83,59.74 59.17,59.08 57.57,59.08 56.08,57.58 56.08,47.93 54.12,45.97 54.12,36.2 v1(52.21,34.29)
  BOTTOM w0.147: v1(56.58,77.72) 56.94,77.72 56.99,77.67 61.08,77.67 61.71,78.31 62.12,78.31 62.65,77.77 64.74,77.77 65.58,78.61 65.58,79.91 66.54,80.87 67.86,80.87 68.27,81.28 69.27,81.28 v1(69.7,80.86) ; U117.9 51.29,33.37 v1(52.21,34.29)
WKUP_UART0_RTSN: length 92.6
  TOP w0.147: U136.C5 v1(68.9,80.06)
  L03_SIG1 w0.091: v1(49.04,35.41) 51.55,32.9 53.93,32.9 56.51,35.48 56.51,36.98 56.97,37.43 57.32,37.43 58.56,36.19 58.56,31.47 60.06,29.98 61.64,29.98 62.02,30.36 62.02,34.49 70.21,42.69 70.21,50.84 68.68,52.37 68.68,53.04 69.23,53.59 69.23,57.56 69.78,58.11 69.78,60.03 66.52,63.3 66.18,63.3 63.57,65.91 63.57,66.78 64.13,67.34 64.13,71.88 64.43,72.19 64.43,73.69 60.63,77.49 60.63,79.32 61.11,79.8 62.38,79.8 62.63,79.55 68.39,79.55 v1(68.9,80.06)
  BOTTOM w0.147: U117.7 48.45,34.82 v1(49.04,35.41) 48.99,35.46 48.99,35.59 48.96,35.61 R593.2
WKUP_UART0_RXD: length 93
  TOP w0.132: 65.1,80.85 68.1,80.85
  TOP w0.147: v1(54.45,34.14) 53.21,34.14 52.8,34.54 R326.2 ; v1(64.23,80.44) 64.64,80.85 65.1,80.85 ; 68.1,80.85 U136.B5
  L03_SIG1 w0.091: v1(64.23,80.44) 60.98,80.44 60.08,79.54 60.08,77.23 63.75,73.56 63.75,72.31 62.93,71.5 62.93,65.63 66.16,62.41 66.16,61.59 66.64,61.11 67.86,61.11 68.54,60.43 68.54,53.74 68.13,53.33 68.13,52.08 69.12,51.09 69.12,44.03 68.55,43.46 68.55,41.92 67.2,40.57 66.85,40.57 66.34,41.08 66.34,41.32 65.48,42.18 65.12,42.18 61.54,38.6 61.54,32.39 60.69,31.55 60.47,31.55 60.07,31.15 59.53,31.15 59.02,31.65 59.02,36.12 57.43,37.71 56.85,37.71 56.23,37.08 56.23,35.59 54.78,34.14 v1(54.45,34.14)
  BOTTOM w0.147: v1(54.45,34.14) 54.1,34.14 54.07,34.16 53.46,34.16 52.75,34.87 49.15,34.87 48.85,34.57 U117.8
WKUP_UART0_TXD: length 164
  TOP w0.147: U136.A5 65.33,80.46 64.48,79.6 63.62,79.6 63.06,80.16 62.53,80.16 61.59,81.1 60.65,81.1 58.97,82.78 v1(58.57,82.78)
  L03_SIG1 w0.091: v1(58.57,82.78) 58.57,83.27 59.07,83.76 59.07,84.82 58.04,85.84 58.04,89.29 59,90.25 59,98.91 58.67,99.24 58.67,99.44 58.39,99.72 58.39,100.48 59.17,101.27 59.17,104.01 58.09,105.1 58.09,112.09 v1(56.72,113.46) ; v1(46.8,38.35) 47.19,38.73 47.19,41.61 47.97,42.39 47.97,43.87 47.72,44.12 47.71,44.12 47.16,44.67 47.16,47.93 49.07,49.83 49.07,57.78 49.62,58.34 52.19,58.34 52.52,58.67 52.52,59.77 51.78,60.5 50.32,60.5 50.22,60.4 48.51,60.4 46.65,62.26 46.65,71.12 47.33,71.79 47.33,73.16 45.21,75.28 45.21,75.84 45.46,76.09 46.2,76.09 46.5,75.79 47.16,75.79 47.62,75.34 48.3,75.34 48.73,75.77 48.73,77.17 48.17,77.73 47.36,77.73 46.01,79.09 46.01,86.81 48,88.8 48,91.08 45.18,93.9 45.18,104.57 43.55,106.2 43.55,108.36 42.51,109.4 42.51,114.15 43.43,115.06 43.43,116.36 45.18,118.11 v1(45.18,119.02)
  BOTTOM w0.147: v1(56.72,113.46) 55.45,114.73 53.84,114.73 49.24,119.33 45.64,119.33 45.63,119.32 45.48,119.32 v1(45.18,119.02) ; U117.6 48.05,34.52 47.67,34.91 47.67,35.84 47.69,35.86 R592.2 47.69,37.47 v1(46.8,38.35)
XDS110_DIR: length 2.9
  BOTTOM w0.147: U97.4 32.43,91.38 32.17,91.12 31.58,91.12 ; 31.58,91.12 31.5,91.2 31.5,91.64 31.64,91.78 U97.5 ; 31.58,91.12 31.58,90.96 31.36,90.74 R555.2
XDS110_EMU0: length 17.3
  TOP w0.147: U48.42 39.93,96.45 40.08,96.6 v1(40.51,96.6) 40.51,96.8 R237.2
  L03_SIG1 w0.091: v1(40.51,96.6) 40.07,96.16 40.07,90.2 v1(40.89,89.38)
  BOTTOM w0.147: U102.7 35.61,88.25 36.75,89.38 v1(40.89,89.38)
XDS110_EMU1: length 15.3
  TOP w0.147: v1(38.88,96.54) 38.88,96.86 39.02,97.01 R236.2 U48.43
  L03_SIG1 w0.091: v1(38.88,96.54) 39.54,95.88 v1(39.54,90.63)
  BOTTOM w0.147: v1(39.54,90.63) 37.3,90.63 35.27,88.6 U102.6
XDS110_TCK: length 12.3
  TOP w0.147: U48.35 42.73,94.27 43.1,93.9 v1(43.45,93.9)
  BOTTOM w0.147: v1(43.45,93.9) 43.45,93.29 42.38,92.23 36.37,92.23 36.01,92.58 U97.14
XDS110_TDI: length 9.6
  TOP w0.147: U48.38 41.53,93.62 40.74,92.82 36.38,92.82 v1(35.68,92.11)
  BOTTOM w0.147: U97.15 34.97,92.18 35.04,92.11 v1(35.68,92.11)
XDS110_TDO: length 19.3
  TOP w0.147: v1(32.61,85.37) 32.61,85.02 33.24,84.38 35.55,84.38 36.75,85.57 36.75,87.55 37.36,88.16 37.36,90.45 38.83,91.92 40.38,91.92 41.93,93.48 U48.37
  BOTTOM w0.147: U109.7 32.69,84.93 32.61,85.02 v1(32.61,85.37)
XDS110_TMS: length 10.9
  TOP w0.147: U48.36 42.33,93.63 v1(42.58,93.39)
  BOTTOM w0.147: U97.13 36.29,92.98 36.7,92.58 41.77,92.58 v1(42.58,93.39)
XDS110_TRST#: length 9.3
  TOP w0.147: U48.40 40.73,94.34 39.62,93.22 35.81,93.22 35.58,93.45 v1(34.97,93.45)
  BOTTOM w0.147: U97.12 33.63,93.58 33.89,93.84 34.1,93.84 34.49,93.45 v1(34.97,93.45)
XDS_GPIO1: length 1.6
  TOP w0.147: U40.2 15.14,91.71 15.23,91.8 R235.2
XDS_GPIO2: length 1.2
  TOP w0.147: U51.2 R283.2
XDS_GPIO3: length 1.6
  TOP w0.147: U40.4 R227.2
XDS_GPIO4: length 1.6
  TOP w0.147: U40.6 13.54,91.79 13.45,91.88 R221.2
XDS_PORZN: length 1.6
  TOP w0.147: R219.2 13.05,83.73 13.14,83.82 U40.8
XDS_POWERDOWN: length 1.6
  TOP w0.147: R233.2 14.83,83.73 14.74,83.82 U40.12
XDS_RSTN: length 6.6
  TOP w0.147: TP51.1 27.96,92.05 28.2,91.81 U48.70 30.51,91.81 30.82,92.12 v1(30.82,92.34)
  BOTTOM w0.147: R556.1 29.43,90.68 29.76,91 R549.1 29.76,91.92 30.17,92.34 v1(30.82,92.34)
XDS_USB_DM: length 53.4
  TOP w0.107: J17.2 16.52,50.66 16.74,50.44 17.06,50.44 v1(17.31,50.69) ; U48.93 30.44,82.61 30.49,82.55 30.72,82.55 v1(30.96,82.79)
  L03_SIG1 w0.094: v1(30.96,82.79) 30.73,82.56 29.4,82.56 28.63,81.79 28.63,69.93 27.93,69.24 27.93,62 26.51,60.58 26.51,55.22 27,54.73 27,50.82 27.97,49.85 27.97,48.19 27.3,47.52 21.96,47.52 19.05,50.44 17.56,50.44 v1(17.31,50.69)
XDS_USB_DP: length 53.4
  TOP w0.107: J17.3 16.52,50.01 16.74,50.22 17.06,50.22 v1(17.31,49.98) ; U48.94 30.49,82.21 30.56,82.28 30.71,82.28 v1(30.96,82.03)
  L03_SIG1 w0.094: v1(30.96,82.03) 30.67,82.31 29.5,82.31 28.87,81.69 28.87,69.83 28.18,69.14 28.18,61.9 26.76,60.48 26.76,55.32 27.25,54.83 27.25,50.92 28.21,49.95 28.21,48.09 27.4,47.28 21.86,47.28 18.95,50.19 17.52,50.19 v1(17.31,49.98)
XDS_USB_ID: length 56.1
  TOP w0.147: R271.2 24.96,82.3 22.19,85.06 v1(21.84,85.06) ; U60.2 18.27,50.24 18.1,50.08 18.1,48.23 ; 18.1,48.23 17.96,48.09 17.74,48.09 16.47,49.36 J17.4 ; 18.1,48.23 19.37,48.23 21.1,49.96 21.1,51.79 v1(21.53,52.22)
  L03_SIG1 w0.091: v1(21.53,52.22) 20.49,53.26 20.49,59.03 22.12,60.66 22.12,62.81 22.57,63.27 22.57,63.89 22.15,64.31 20.69,64.31 20.03,64.97 20.03,67.61 22.04,69.62 22.04,74.19 21.28,74.96 21.28,77.32 21.7,77.74 21.7,78.15 21.28,78.58 21.28,84.51 v1(21.84,85.06)
XDS_USB_VBUS: length 27.4
  TOP w0.203: v1(31.21,74.42) 32.81,74.42 34.36,75.97 43.61,75.97 44.07,76.43 R295.1
  TOP w0.254: C250.1 18.97,52.17 18.97,51.67 19.22,51.41 U60.6
  TOP w0.305: U55.2 28.96,75.82 29.23,76.1 v1(29.48,76.1) ; TP78.1 31.21,73.78 v1(31.21,74.42) ; v1(13.17,70) v1(13.17,70.76)
  L03_SIG1 w0.305: v1(30.31,80.3) 29.48,79.47 v1(29.48,76.1)
  BOTTOM w0.254: R576.1 27.62,81.03 28.36,80.3 v1(30.31,80.3)
  vias: v1(19.77,51.27) v1(20.41,51.27) v1(30.85,74.75)
XDS_VREF: length 17.9
  TOP w0.147: U41.3 45.53,98.13 45.53,98.13 C190.1 46.21,98.13 46.48,97.86 R241.2 46.93,96.02 47.46,95.48 47.46,91.26 47.67,91.06 47.67,87.53 47.46,87.33 47.46,85.83 46.95,85.31 C215.2 46.48,84.95 46.14,84.61 U48.9
XDS_WARMRESETN: length 1.6
  TOP w0.147: U40.10 R224.2
ZENER_CLAMP: length 5.2
  TOP w0.305: D2.3 26.93,57.86 27.13,58.06 R298.1 28.16,58.06 28.31,57.91 28.31,57.35 28.19,57.22 R308.1
N16856152: length 6
  TOP w0.147: Y6.2 59.82,21.59 58.45,22.96 C270.1 58.22,24.23 58.22,24.5 58.97,25.25 U64.3
N16856224: length 6.1
  TOP w0.147: Y6.1 56.02,21.59 57.38,22.96 C269.1 57.68,24.3 57.68,24.64 58.47,25.43 U64.2
N16857368: length 1.1
  TOP w0.203: C283.2 58.68,11.47 58.97,11.18 U66.2
N16878497: length 2.1
  TOP w0.147: v1(107.21,73.61) 107.46,73.36 U49.H5
  BOTTOM w0.147: TP116.1 107.21,73.43 v1(107.21,73.61) R562.1
N16880083: length 2.2
  TOP w0.147: R21.2 127.88,69.28 U2.1 R18.1
N16956459: length 2.2
  TOP w0.147: U27.1 70.14,125.93 R122.1 71.08,125.93 R121.2
N16994873: length 1.1
  BOTTOM w0.147: R483.2 U88.4
N16994875: length 1
  BOTTOM w0.147: U87.4 R476.2
N16995245: length 0.9
  BOTTOM w0.147: C417.1 R487.2
N16997746: length 6.6
  TOP w0.147: U48.59 33.13,96.4 33.28,96.55 34.04,96.55 35.12,97.62 35.12,98.92 34.28,99.77 R218.1
N17030208: length 1.6
  BOTTOM w0.147: R544.2 30.93,92.87 31.22,92.58 U97.7
N17031262: length 2.7
  TOP w0.147: LD9.2 46.2,11.89 45.99,12.09 45.24,12.09 45.06,11.91 R402.2
N17078974: length 1.8
  BOTTOM w0.147: J10.2 R438.2 81.87,146.05
N17269599: length 1.9
  TOP w0.147: U68.6 70.64,50.87 70.75,50.97 R366.2 R363.1
N17269609: length 3
  TOP w0.147: U68.1 69.14,50.87 68.93,51.07 R367.1 ; R362.1 68.76,51.6 68.54,51.38 R367.1 ; R364.2 R367.1
N17378539: length 2
  TOP w0.147: R330.2 53.66,31.21 53.15,30.7 LD7.1
N17479799: length 1.4
  TOP w0.147: U55.8 v1(30.37,72.49)
  BOTTOM w0.147: R314.2 v1(30.37,72.49)
N17479805: length 4
  TOP w0.147: C243.2 26.02,74.46 26.1,74.38 R306.2 R313.1 U55.5
N17479881: length 3.3
  TOP w0.147: R246.1 27.16,93.64 27.39,93.4 C203.2 27.8,93.39 28.12,93.07 28.31,93.07 28.77,92.61 U48.68
N17481587: length 1.5
  TOP w0.147: R287.2 44.32,77.52 43.81,77 LD5.2
N17481598: length 6
  TOP w0.147: U48.96 C225.2 27.93,80.98 28.23,80.67 29.31,80.67 v1(29.56,80.92)
  BOTTOM w0.147: R576.2 28.6,81.45 29.13,80.92 v1(29.56,80.92)
N17481613: length 2
  TOP w0.147: U48.95 28.76,81.81 28.61,81.96 28.61,82.13 28.44,82.3 R271.1
N17481619: length 6.4
  TOP w0.147: U48.1 45.96,81.41 46.3,81.07 46.3,79.54 45.55,78.79 R289.1 R295.2
N17481621: length 3.7
  TOP w0.147: R232.2 33.73,97.2 33.58,97.05 v1(33.49,97.05) 33.22,97.05 32.73,96.57 U48.60
  BOTTOM w0.147: v1(33.49,97.05) 33.73,97.29 R232.2
N17481627: length 2.1
  TOP w0.147: R276.1 46.3,82.01 46.1,82.21 U48.3
N17481631: length 1.1
  TOP w0.147: R276.2 LD3.2
N17481633: length 4.6
  TOP w0.147: U48.63 31.53,96.32 30.88,96.98 v1(30.45,96.98) 30.09,96.98 29.92,97.15 R229.2
  BOTTOM w0.147: v1(30.45,96.98) 30.09,96.98 29.92,97.15 R229.2
N17481635: length 3.1
  TOP w0.147: U48.61 32.33,96.85 v1(32.46,96.97) R231.2
  BOTTOM w0.147: R231.2 v1(32.46,96.97)
N17481637: length 5.3
  TOP w0.147: R287.1 44.36,80.75 43.9,81.21 43.9,82.38 44.14,82.61 U48.4
N17481641: length 3.5
  TOP w0.147: R230.2 31.19,97.33 v1(31.54,96.97) 31.93,96.58 U48.62
  BOTTOM w0.147: v1(31.54,96.97) 31.19,97.33 R230.2
N17824845: length 1.6
  BOTTOM w0.147: U129.36 40.25,24.36 40.3,24.41 40.3,24.82 40.05,25.07 R654.1
N17824852: length 1.6
  BOTTOM w0.147: U129.37 40.65,24.58 40.81,24.73 R653.1
N17824859: length 1.7
  BOTTOM w0.147: R652.1 41.57,24.96 41.07,24.45 41.07,24.11 41.05,24.1 U129.38
N17824866: length 1.9
  BOTTOM w0.147: R651.1 42.33,25.06 41.45,24.18 U129.39
N19741013: length 2.1
  BOTTOM w0.147: R390.2 35.58,19.81 35.83,19.56 35.83,19.2 36.05,18.98 U129.18
N19806973: length 1.2
  BOTTOM w0.147: R566.2 37,85.77 36.58,85.36 U110.7
N21761137: length 7.8
  TOP w0.147: R5750.1 61.96,83.53 62.98,82.5 62.98,82.17 63.29,81.86 63.64,81.86 63.84,82.06 U136.A7
N21784165: length 5.3
  TOP w0.132: 82.78,83.69 82.41,84.06 81.93,84.06 81.7,84.29 81.7,84.7 81.3,85.11 U136.V11
  TOP w0.147: 82.78,83.69 82.97,83.5 84.05,83.5 84.49,83.94 R548.1
N21784176: length 9.2
  TOP w0.132: 84.9,84.99 84.4,84.99 83.99,84.58 83.53,84.58 83.28,84.84 82.72,84.84 82.7,84.86 81.93,84.86 81.7,85.09 81.7,85.41 81.46,85.65 80.89,85.65 U136.U11
  TOP w0.147: R541.1 87.34,84.18 86.53,84.99 84.9,84.99
N22498870: length 1.9
  BOTTOM w0.147: U120.6 112.57,48.05 112.47,48.15 R605.2 R602.1
N22498881: length 3
  BOTTOM w0.147: R604.2 115,48.25 R606.1 ; U120.1 113.76,48.05 113.97,48.25 R606.1 ; R606.1 114.55,48.54 114.32,48.77 R601.1
N22682556: length 2.2
  BOTTOM w0.147: R633.2 32.93,30.4 J21.1
N22682559: length 1.9
  BOTTOM w0.147: J21.3 32.65,32.94 R627.2
N24306091: length 12
  TOP w0.147: U3076.5 20.5,67.27 20.19,67.58 ; 20.19,67.58 C3746.2 20.19,68.48 20.52,68.81 21.3,68.81 22.32,67.79 22.32,64.97 23.81,63.48 R293.1 ; 20.19,67.58 19.85,67.25 U3076.6
N24306103: length 1.3
  TOP w0.305: R293.2 23.81,60.94 23.81,60.93 Q4.1
N24306157: length 49.6
  TOP w0.203: v1(33.93,25.43) 35.58,23.77 37.56,23.77 38.19,23.14 38.19,20.73 37.99,20.52 37.23,20.52 36.95,20.24 36.95,19.3 36.24,18.59 35.55,18.59 35.38,18.77 D5.3
  TOP w0.305: v1(28.72,53.98) 28.19,54.51 R308.2
  L03_SIG1 w0.254: v1(28.72,53.98) 29.18,53.52 29.18,43.74 27.14,41.71 27.14,27.71 29.43,25.43 v1(33.93,25.43)
N24306190: length 1.5
  TOP w0.305: Q4.3 R298.2
N24307354: length 3
  TOP w0.254: v1(36.06,56.59) 36.33,56.86 U56.4
  BOTTOM w0.203: v1(36.06,56.59) 35.35,55.88 R5828.2
N24307356: length 3.1
  TOP w0.254: U56.6 v1(36.26,55.86)
  BOTTOM w0.254: v1(36.26,55.86) 35.96,55.57 35.96,55.09 35.65,54.79 R5829.2
N24478126: length 1.5
  TOP w0.147: C70.1 U4.4
N24517110: length 1.3
  TOP w0.147: R214.2 46.3,100.46 SW3.3
N24517112: length 1.3
  TOP w0.147: SW3.4 R217.2
N24605604: length 14.3
  TOP w0.147: J2.5A 76.92,166 76.29,165.38 76.29,159.18 75.84,158.72 74.08,158.72 73.91,158.9 73.91,159.42 75.1,160.61 C18.1
N24605606: length 14.2
  TOP w0.147: C16.1 71.21,160.68 69.86,159.33 69.86,158.72 69.36,158.22 67.98,158.22 65.78,160.42 J2.2A
N24605709: length 2.8
  TOP w0.147: R90.1 77.63,137.91 U14.1 78.7,137.91 R84.2
N24605835: length 4.7
  TOP w0.147: U7.20 66.21,152.78 67.05,153.62 67.05,153.87 67.26,154.08 67.26,155.69 TP5.1
N24605846: length 3.3
  TOP w0.147: L3.2 66.12,145.23
  TOP w0.203: 66.12,145.23 65.71,145.63 U7.4
N24605909: length 10.2
  BOTTOM w0.147: J2.5B 67.72,167.81 67.72,165.14 68.86,164 69.83,164 70.43,164.59 70.43,165.02 71.71,166.31 C333.1
N24606047: length 2
  TOP w0.147: U7.19 66.71,152.56 66.84,152.69 TP8.1
N24606049: length 2.4
  TOP w0.147: U7.17 68.17,152.05 69.22,153.1 TP9.1
N24606166: length 9.4
  BOTTOM w0.147: J2.2B 76.37,167.84 76.37,165.35 75.15,164.13 74.62,164.13 74.34,164.41 74.34,165.1 75.58,166.34 C331.1
N24847876: length 1.5
  BOTTOM w0.147: U77.4 R421.1 96.65,152.82
N24847884: length 13.7
  BOTTOM w0.147: J3.5B 88.31,168.5 91.08,165.73 91.08,161.42 91.68,160.81 C348.1
N24847886: length 9.2
  BOTTOM w0.147: C347.1 93.76,161.14 94.18,161.56 94.18,162.64 93.06,163.75 93.06,167.38 J3.2B
N24847888: length 4
  BOTTOM w0.147: C347.2 93.55,158.57 92.83,157.84 92.83,155.75 92.94,155.64 U77.21
N24847892: length 5.8
  BOTTOM w0.147: U77.19 91.94,157.54 91.79,157.68 90.82,157.68 90.62,157.89 90.62,159.24 C344.2
N24847894: length 6.2
  BOTTOM w0.147: U77.22 93.44,156.01 93.24,156.21 93.24,157.51 93.44,157.71 94.66,157.71 94.86,157.91 94.86,159.23 C343.2
N24847910: length 3.8
  BOTTOM w0.147: C348.2 92.44,157.79 U77.20
N24847912: length 1.7
  BOTTOM w0.147: U77.11 92.44,149.66 TP113.1
N24847957: length 1.2
  BOTTOM w0.147: C367.1 90.39,152.55 90.66,152.82 U77.15
N24847963: length 1.1
  BOTTOM w0.147: U77.16 90.13,153.32 C365.1
N24847969: length 1.2
  BOTTOM w0.147: U77.17 90.57,153.82 90.32,154.07 C362.1
N24847975: length 1.3
  BOTTOM w0.147: C360.1 90.22,154.83 90.73,154.32 U77.18
N24847993: length 1.7
  BOTTOM w0.147: U77.9 93.44,149.64 TP112.1
N24847995: length 2.9
  BOTTOM w0.147: TP115.1 92.94,148.51 U77.10
N24848039: length 1.5
  TOP w0.147: R24.1 U5.4
N24848041: length 12.9
  TOP w0.147: J3.5A 89.64,166 87.14,163.5 87.14,161.37 86.68,160.91 C25.1
N24848043: length 6.6
  TOP w0.147: C24.1 84.65,161.09 84.19,161.54 84.19,164.73 J3.2A
N24848045: length 3.8
  TOP w0.147: C24.2 84.65,157.92 85.42,157.16 U5.21
N24848047: length 5.8
  TOP w0.147: C23.2 88.13,158.29 87.59,157.75 86.62,157.75 86.42,157.55 U5.19
N24848049: length 5.6
  TOP w0.147: C22.2 83.24,159.56 83.24,158.19 83.69,157.74 84.29,157.74 84.92,157.11 U5.22
N24848518: length 3.8
  TOP w0.147: C25.2 85.92,157.78 U5.20
N24848523: length 1.7
  TOP w0.147: TP18.1 86.1,150.14 85.92,150.33 U5.11
N24848568: length 1.2
  TOP w0.147: U5.15 87.85,152.82 88.12,152.55 C61.1
N24848574: length 1.1
  TOP w0.147: U5.16 88.23,153.32 C56.1
N24848580: length 1.2
  TOP w0.147: C50.1 88.11,154.07 87.86,153.82 U5.17
N24848586: length 1.4
  TOP w0.147: C47.1 87.88,154.83 87.75,154.7 87.75,154.43 87.64,154.32 U5.18
N24848600: length 1.2
  TOP w0.147: R24.2 TP12.1
N24848612: length 1.3
  BOTTOM w0.147: TP109.1 98.13,152.82 R421.2 97.21,152.82
N24848616: length 1.7
  TOP w0.147: TP17.1 84.76,150.07 84.92,150.23 U5.9
N24848618: length 2.8
  TOP w0.147: U5.10 TP22.1
N24851304: length 1.6
  BOTTOM w0.147: R420.1 U76.4
N24851306: length 1.5
  TOP w0.147: TP14.1 114.89,152.39 v1(115.26,152.39)
  BOTTOM w0.147: v1(115.26,152.39) 115.26,152.67 115.11,152.82 R420.2
N24851312: length 13.7
  BOTTOM w0.147: C346.1 109.07,161.05 108.32,161.8 108.32,165.89 105.71,168.5 J4.5B
N24851314: length 11.1
  BOTTOM w0.147: J4.2B 110.17,168.5 109.21,167.54 109.21,164.39 111.52,162.08 111.52,161.57 111.1,161.15 C345.1
N24851316: length 3.8
  BOTTOM w0.147: C345.2 110.34,157.8 U76.21
N24851320: length 5.8
  BOTTOM w0.147: U76.19 109.34,157.51 109.19,157.66 108.22,157.66 107.96,157.92 107.96,159.29 C342.2
N24851322: length 5.8
  BOTTOM w0.147: U76.22 110.84,157.56 110.98,157.71 111.98,157.71 112.19,157.92 112.19,159.26 C341.2
N24851338: length 3.8
  BOTTOM w0.147: C346.2 109.84,157.8 U76.20
N24851340: length 1.7
  BOTTOM w0.147: TP111.1 109.84,149.66 U76.11
N24851385: length 1.2
  BOTTOM w0.147: U76.15 108.06,152.82 107.78,152.55 C366.1
N24851391: length 1.1
  BOTTOM w0.147: C364.1 108.58,153.31 U76.16
N24851397: length 1.2
  BOTTOM w0.147: C361.1 107.75,154.07 108,153.82 U76.17
N24851403: length 1.3
  BOTTOM w0.147: U76.18 108.03,154.32 C359.1
N24851421: length 1.7
  BOTTOM w0.147: U76.9 110.84,149.64 TP110.1
N24851423: length 2.6
  BOTTOM w0.147: U76.10 TP114.1
N24851452: length 1.5
  TOP w0.147: R25.1 U6.4
N24851454: length 1
  TOP w0.147: R25.2 TP11.1
N24851456: length 13
  TOP w0.147: C27.1 104.08,160.71 104.41,161.04 104.41,163.65 106.76,166 J4.5A
N24851458: length 6.6
  TOP w0.147: C26.1 102.05,160.76 101.47,161.34 101.47,164.86 J4.2A
N24851460: length 3.8
  TOP w0.147: U6.21 102.82,157.78 C26.2
N24851462: length 6
  TOP w0.147: U6.19 103.82,157.5 104.08,157.76 104.95,157.76 105.1,157.91 105.1,159.42 C21.2
N24851464: length 6
  TOP w0.147: C20.2 101.03,159.46 101.03,157.95 101.22,157.76 102.1,157.76 102.32,157.55 102.32,155.07 U6.22
N24851486: length 3.8
  TOP w0.147: U6.20 103.32,157.78 C27.2
N24851488: length 1.7
  TOP w0.147: TP20.1 103.5,150.08 103.32,150.27 U6.11
N24851535: length 1.2
  TOP w0.147: C62.1 105.36,152.82 U6.15
N24851541: length 1.1
  TOP w0.147: C57.1 105.62,153.32 U6.16
N24851547: length 1.2
  TOP w0.147: C51.1 105.39,153.82 U6.17
N24851553: length 1.3
  TOP w0.147: U6.18 105.11,154.32 105.62,154.83 C48.1
N24851571: length 1.7
  TOP w0.147: TP19.1 102.16,149.97 102.32,150.13 U6.9
N24851573: length 2.8
  TOP w0.147: U6.10 TP23.1
N25521527: length 4.3
  TOP w0.147: U7.18 67.21,152.53 67.46,152.78 68.17,152.78 68.49,153.1 68.49,154.32 TP6.1
N25809420: length 9.1
  TOP w0.152: 81.88,42.75 81.9,42.77
  TOP w0.305: 94.12,42.65 94.1,42.67 93.36,42.67 92.94,42.25 J18.SH4 92.94,41.24 v1(93.17,41.01) ; 82.29,38.91 82.67,39.29 J18.SH1 ; 93.67,39 93.23,39 92.94,39.28 J18.SH3 ; 81.9,42.77 82.33,42.77 82.67,42.43 J18.SH2
  BOTTOM w0.147: v1(94.34,39.32) 94.34,40.15 94.49,40.3 C610.1
N25815350: length 5.1
  TOP w0.305: J19.SH4 125.37,42.68 125.38,42.68 125.6,42.9 ; v1(114.5,38.99) 114.73,38.99 115.1,39.36 J19.SH1 ; J19.SH3 125.37,38.99 ; 114.77,42.95 115.1,42.62 J19.SH2
  vias: v1(113.92,38.99) v1(114.88,41)
N26271323: length 1.7
  BOTTOM w0.147: U129.17 35.92,18.58 35.6,18.9 R386.2
N27107689: length 1.8
  TOP w0.147: U73.3 31.22,20.41 31.71,20.9 C308.1
N27107697: length 1.9
  TOP w0.147: v1(30.14,23.14) 30.14,23.03 29.97,22.86 U73.5
  BOTTOM w0.147: R382.2 29.79,23.47 30.11,23.15 30.13,23.15 v1(30.14,23.14)
N27107782: length 1.3
  TOP w0.147: R395.2 30.15,19.7 29.97,19.88 U73.2
N27116765: length 1.8
  TOP w0.147: v1(64.43,59.31) 64.43,59.66 64.43,59.66 U59.5
  BOTTOM w0.147: R320.1 v1(64.43,59.31) 64.43,59.13 64.59,58.97 R319.2
N27118410: length 1.4
  TOP w0.147: U46.3 R240.2
N27118414: length 2.8
  TOP w0.147: U46.4 R258.1 R255.2
N27132714: length 1.5
  TOP w0.147: SW2.13 R137.1
N27132716: length 1.5
  TOP w0.147: SW2.14 R136.1
N27132718: length 1.5
  TOP w0.147: SW2.15 R135.1
N27132720: length 1.5
  TOP w0.147: SW2.16 R134.1
N27132816: length 1.5
  TOP w0.147: SW1.11 R131.1
N27132818: length 1.5
  TOP w0.147: SW1.12 R130.1
N27132820: length 1.5
  TOP w0.147: SW1.13 R129.1
N27132822: length 1.5
  TOP w0.147: SW1.14 R128.1
N27132824: length 1.5
  TOP w0.147: SW1.9 R133.1
N27132826: length 1.5
  TOP w0.147: SW1.10 R132.1
N27132828: length 1.5
  TOP w0.147: SW1.15 R127.1
N27132836: length 1.5
  TOP w0.147: SW1.16 R126.1
N27133243: length 1.5
  TOP w0.147: SW2.9 R141.1
N27133247: length 1.5
  TOP w0.147: SW2.10 R140.1
N27133249: length 1.5
  TOP w0.147: SW2.11 R139.1
N27133251: length 1.5
  TOP w0.147: SW2.12 R138.1
N27148451: length 2.7
  TOP w0.147: R125.2 62.58,106.29 62.87,105.99 U28.A5
N27161108: length 4.4
  TOP w0.147: R401.1 R398.2 54.2,12.46 54.59,12.07 55.39,12.07 55.75,12.43 D6.3
N27162183: length 11.3
  TOP w0.254: v1(57.92,18.47) 58.92,17.47 58.92,14.48 58.67,14.22 56.11,14.22 55.22,15.11 C318.2
  BOTTOM w0.147: v1(57.92,18.47) R675.2 C638.2 56.71,17.93 56.61,18.04 Q8.3
  vias: v1(51.57,15.53) v1(51.57,15.07) v1(51.57,14.61) v1(51.57,14.15)
N27162479: length 3.7
  BOTTOM w0.147: R672.1 R669.2 ; R672.1 Q10.3 ; R672.1 R673.2
N27173972: length 2.3
  TOP w0.147: R203.2 79.68,131.15 Q1.3 R213.2
N27173989: length 3
  TOP w0.147: R442.2 69.99,132.56 69.73,132.82 R441.2 Q5.3
N27174010: length 6.4
  TOP w0.147: LD10.1 72.11,130.53 72.56,130.98 Q5.6 72.56,132.2 Q5.8 ; Q5.8 71.91,132.85 Q5.2 ; Q5.8 72.56,132.85 Q5.1 ; Q5.8 71.91,132.2 Q5.5
N27174034: length 6.5
  TOP w0.147: Q1.6 77.17,132.45 Q1.8 ; Q1.2 77.82,131.8 Q1.8 ; Q1.8 77.17,131.8 Q1.1 LD1.1 ; Q1.8 77.82,132.45 Q1.5
N27174097: length 1.7
  TOP w0.147: LD1.2 75.14,133.82 75.55,134.24 R180.1
N27174144: length 1.7
  TOP w0.147: R440.1 70.62,128.22 71.13,127.71 LD10.2
N27175817: length 5.5
  TOP w0.147: Y1.1 81.83,57.94 82.53,58.64 C104.2 84.47,58.64 R74.2
N27175821: length 7.5
  TOP w0.147: R73.2 84.04,59.61 C105.1 83.7,59.61 83.01,60.3 79.72,60.3 79.29,60.73 Y1.3
N27175987: length 16.8
  TOP w0.147: U15.24 87.75,60.24 v1(87.75,60.43) ; U15.15 92.04,57.64 v1(92.3,57.89) 92.05,58.14 U15.16 ; v1(86.45,57.87) 86.71,58.14 U15.3
  BOTTOM w0.147: C383.1 86.69,57.63 v1(86.45,57.87) 86.45,58.1 86.74,58.39 C382.1 87.3,58.94 86.5,59.74 86.5,60.1 86.83,60.43 v1(87.75,60.43) 87.75,60.27 87.99,60.03 C384.1 88.46,60.03 88.9,59.59 C385.1 89.23,59.05 89.4,58.88 89.9,58.88 90,58.98 91.23,58.98 91.74,58.47 C386.1 91.94,58.25 v1(92.3,57.89) 92.3,57.64 92.15,57.49 C387.1
N27176057: length 1.8
  TOP w0.147: TP36.1 87.65,55.11 87.94,55.11 88.2,55.37 U15.7
N27176072: length 1.3
  TOP w0.147: U15.22 R89.2
N27176107: length 4.7
  TOP w0.147: U15.21 89.7,62.05 90.19,62.53 91.08,62.53 91.28,62.33 TP39.1
N27176638: length 1.4
  TOP w0.147: U15.11 90.2,55.39 TP37.1
N27176640: length 2.2
  TOP w0.147: TP38.1 90.2,61.17 U15.20
N27224404: length 2.2
  TOP w0.147: v1(57.45,148.52) U8.29
  BOTTOM w0.147: v1(57.45,148.52) R435.2
N27224468: length 9.8
  BOTTOM w0.147: C337.1 54.57,166.33 53.36,165.13 53.36,164.59 52.95,164.19 51.99,164.19 50.72,165.46 50.72,167.67 J1.5B
N27224561: length 3.3
  TOP w0.147: L2.2 53.64,152.62 ; U8.4 54.05,150.78
  TOP w0.203: 53.64,152.62 54.04,152.22 U8.4
N27224667: length 9.2
  BOTTOM w0.147: C335.1 58.43,166.34 57.19,165.1 57.19,164.41 57.47,164.13 57.73,164.13 59.07,165.48 59.07,167.68 J1.2B
N27224751: length 5.5
  TOP w0.147: TP27.1 48.67,145.15 49.21,144.61 52.06,144.61 52.54,145.09 U8.18
N27224753: length 4.8
  TOP w0.147: TP31.1 51.75,143.25 53.54,145.04 U8.20
N27224897: length 13.7
  TOP w0.147: J1.5A 59.45,164.32 59.45,159.26 58.8,158.61 57.08,158.61 56.74,158.95 56.74,159.49 57.91,160.66 C14.1
N27225024: length 2.3
  TOP w0.147: C77.1 58,149.76 57.63,150.14 C78.1 56.98,150.14 56.87,150.02 U8.32
N27225078: length 14.4
  TOP w0.147: C12.1 54.04,160.68 52.7,159.33 52.7,158.72 52.19,158.22 50.54,158.22 48.63,160.12 48.63,164.19 48.64,164.19 J1.2A
N27225127: length 8
  TOP w0.147: U8.19 53.04,145.06 52.17,144.19 47.52,144.19 TP26.1
N27225129: length 3
  TOP w0.147: TP25.1 50.67,145.55 51.14,145.08 51.86,145.08 52.04,145.26 U8.17
N27225150: length 2.1
  TOP w0.147: U8.28 58.34,148.02 R46.2
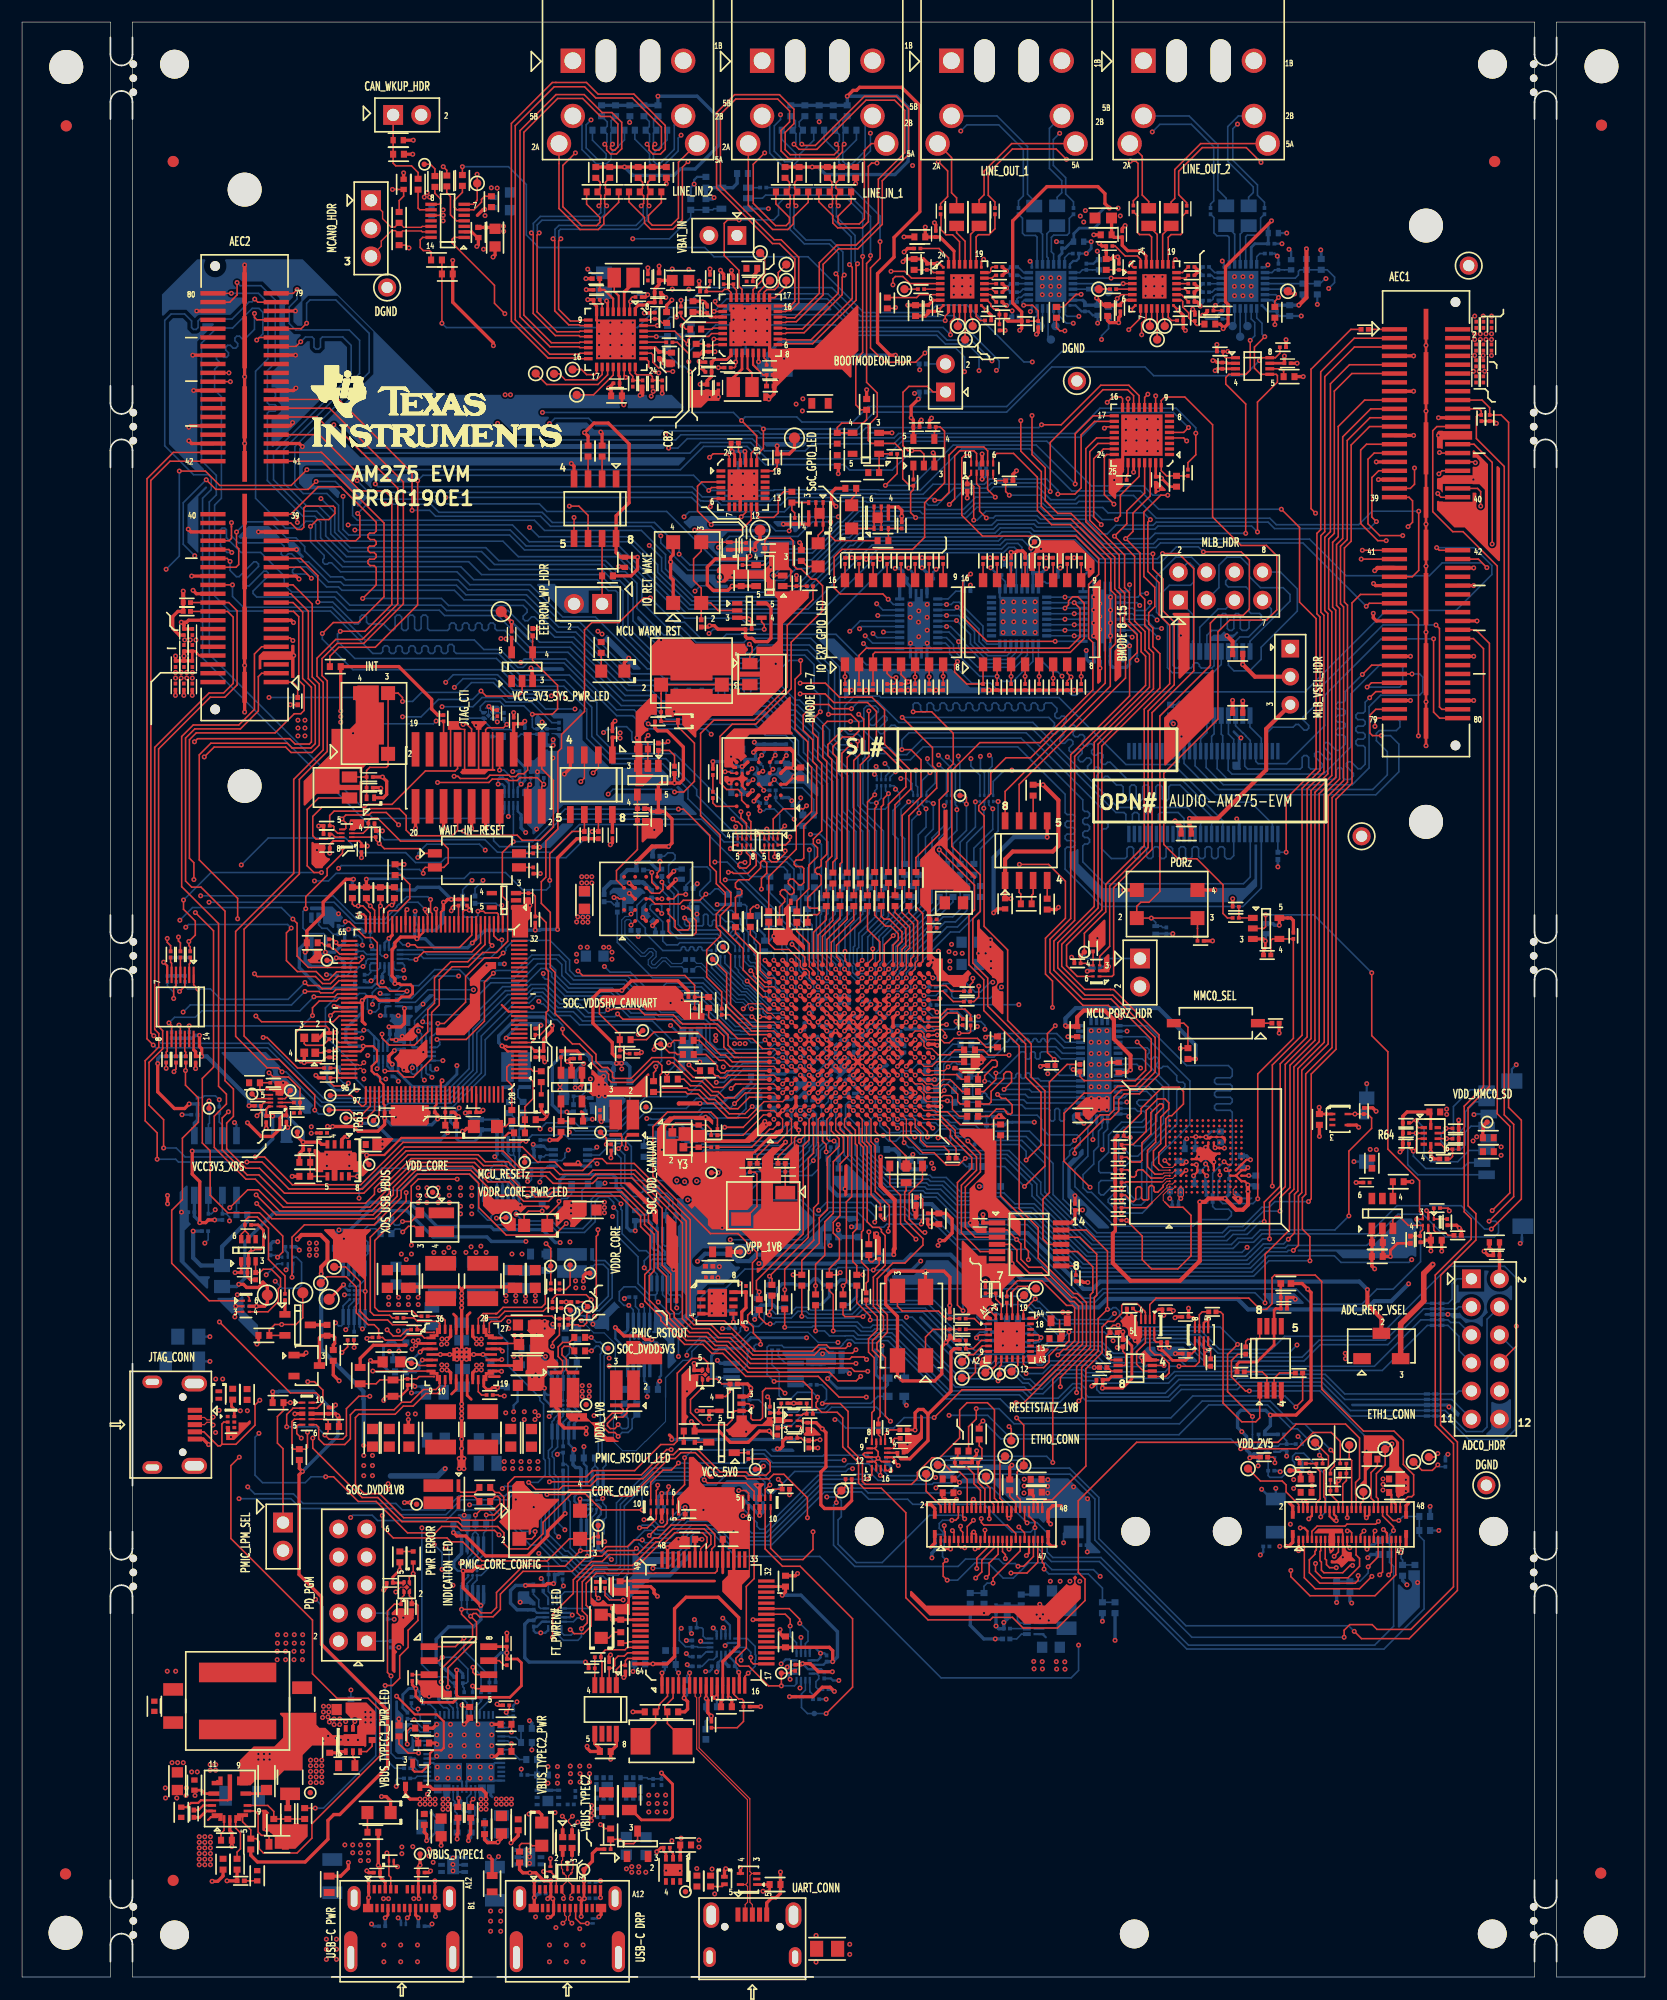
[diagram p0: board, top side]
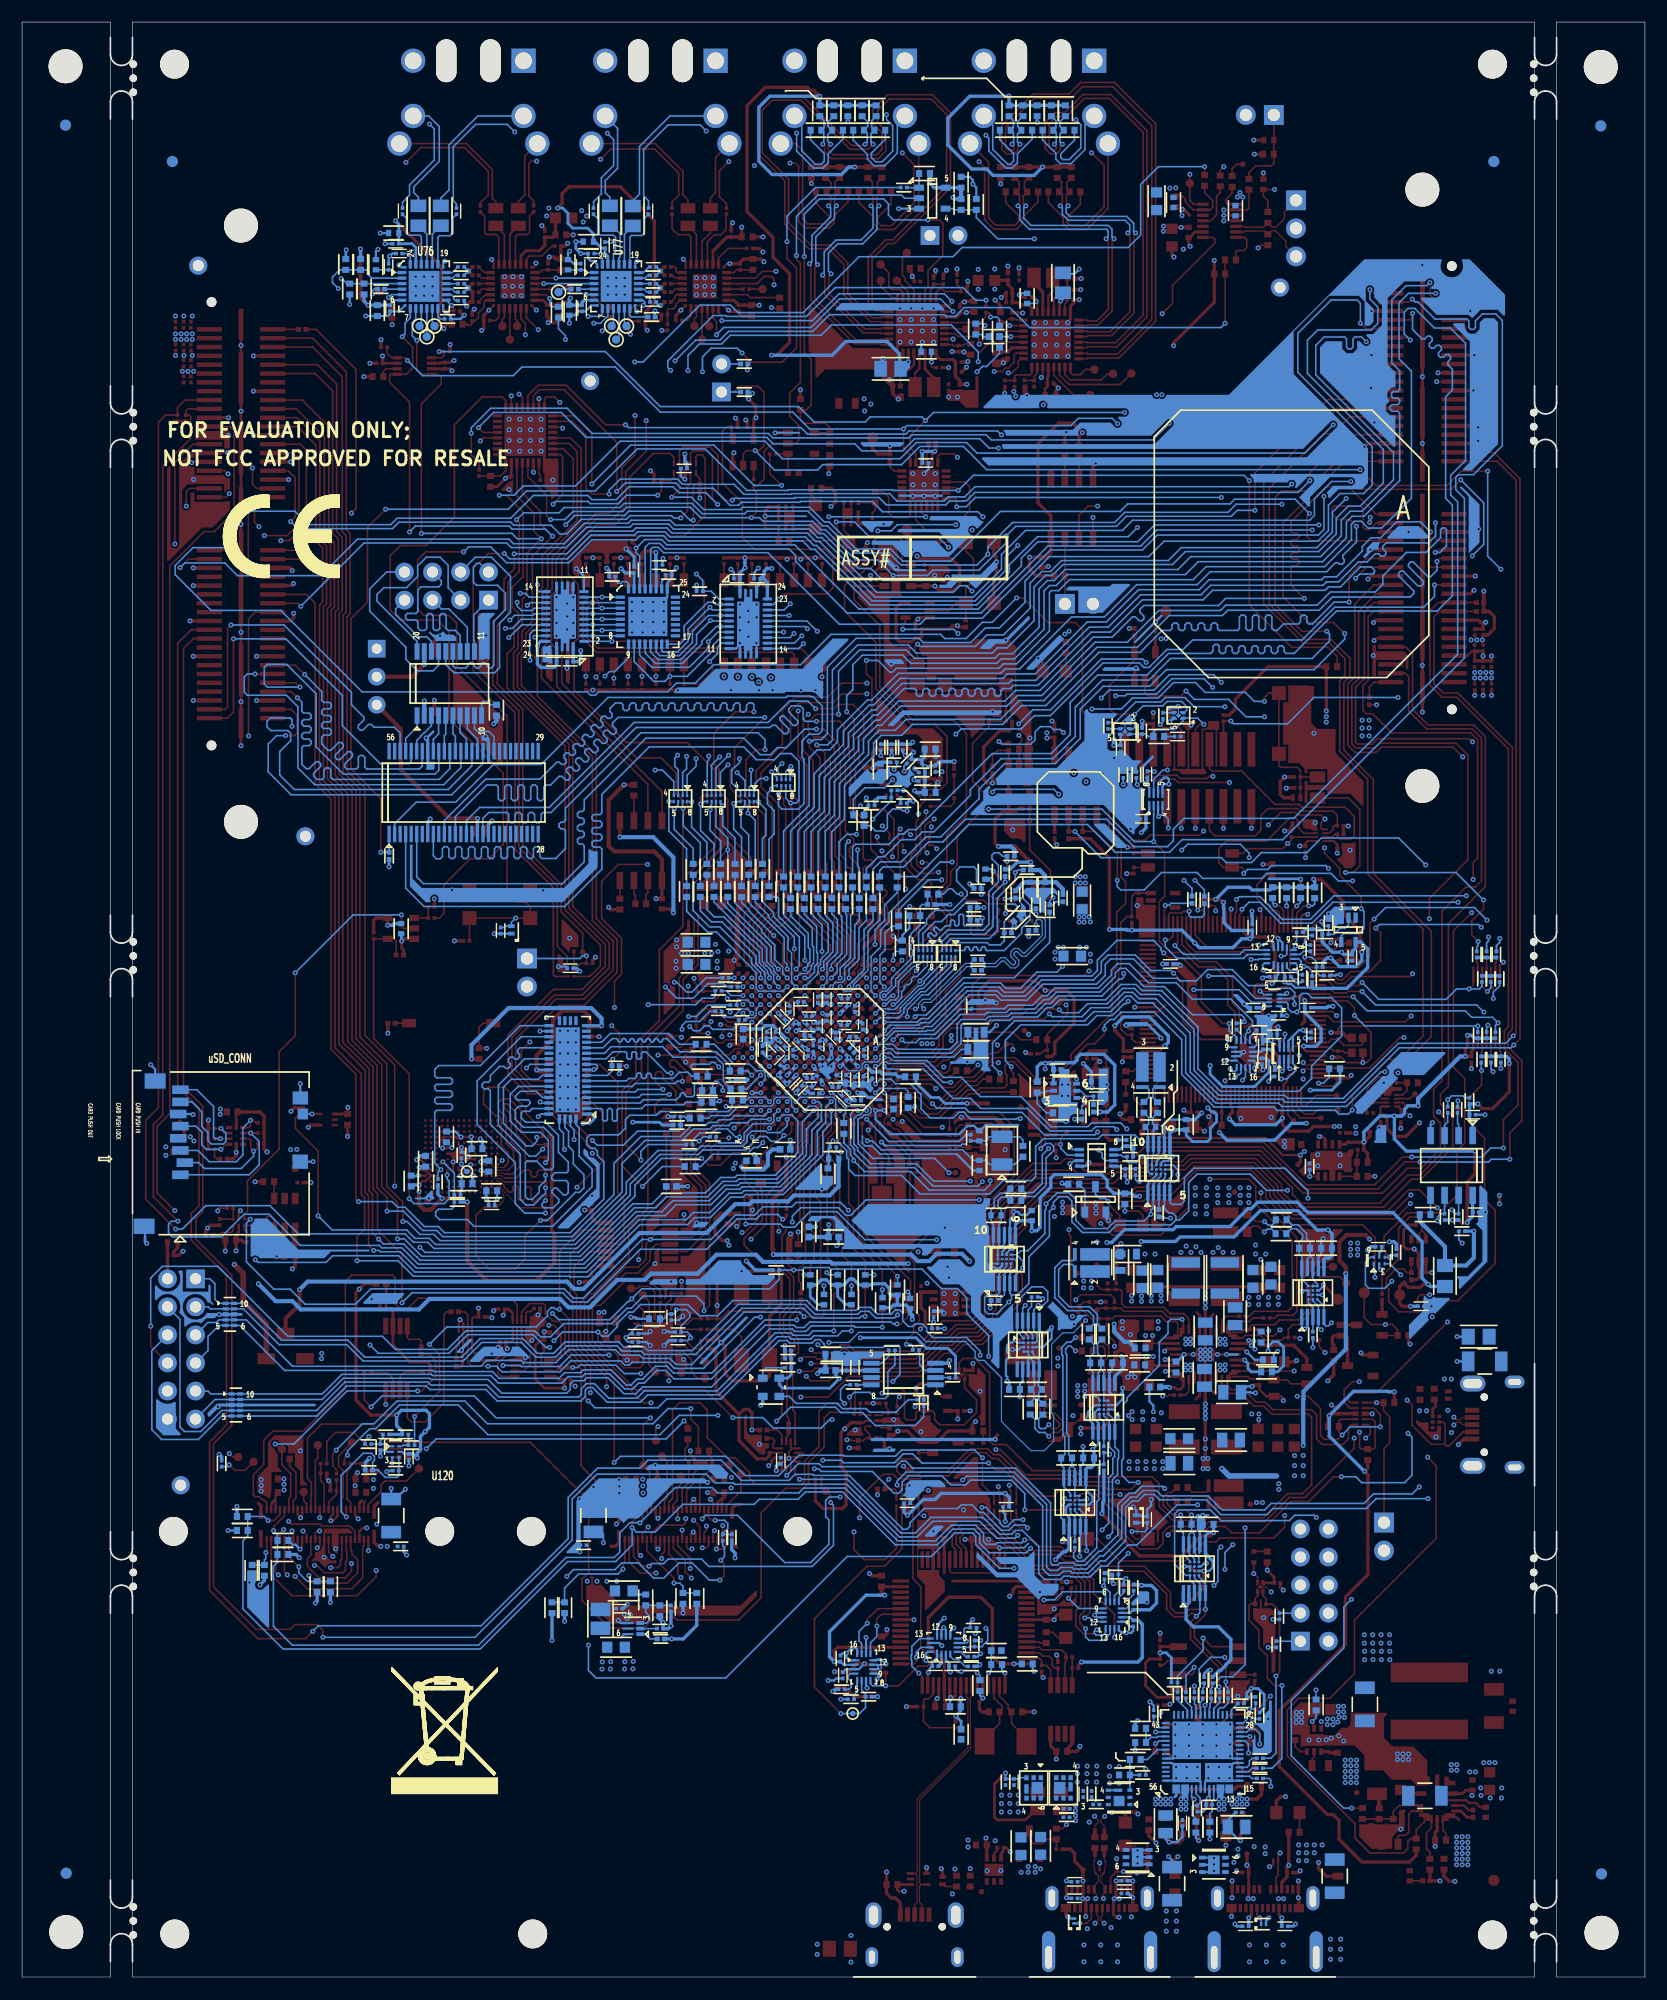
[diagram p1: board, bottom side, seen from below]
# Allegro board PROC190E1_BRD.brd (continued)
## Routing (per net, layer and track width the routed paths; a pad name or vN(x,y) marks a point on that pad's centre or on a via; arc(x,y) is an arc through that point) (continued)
N27226002: length 2.4
  BOTTOM w0.147: R414.2 66.84,162.01 U75.1 65.75,162.01 R413.1
N27239473: length 1.2
  BOTTOM w0.147: U117.5 47.65,34.36 47.21,34.8 R591.2
N27239479: length 2.4
  BOTTOM w0.147: R590.1 46.32,34.65 46.8,34.16 46.8,33.53 46.96,33.37 U117.4
N27239926: length 1.8
  BOTTOM w0.147: R635.2 71.64,25.55 71.35,25.84 71.35,25.84 71.36,25.85 71.36,26.52 71.35,26.52 U126.5
N27239932: length 2.5
  BOTTOM w0.147: U126.4 71.98,27.47 72.17,27.28 72.17,27 71.91,26.74 71.91,26.24 72.1,26.05 R636.1
N27240077: length 1.2
  BOTTOM w0.147: U125.5 61.97,29.44 61.52,29 R613.2
N27240083: length 2.2
  BOTTOM w0.147: R614.1 61.58,28.12 62.2,28.74 62.62,28.74 62.92,29.04 U125.4
N27243596: length 1.4
  TOP w0.147: TP61.1 24.1,80.08 24.1,79.81 23.81,79.52 U51.3
N27243598: length 1.8
  TOP w0.147: TP58.1 21.26,79.52 U51.6
N27248134: length 2.1
  BOTTOM w0.147: R579.2 16.97,77.31 16.88,77.21 U107.2
N27248136: length 2.2
  BOTTOM w0.147: R580.2 17.86,77.41 18.15,77.12 U107.3
N27566274: length 4.7
  TOP w0.147: v1(48.63,70.23) 48.63,70 47.58,68.94 LD2.1
  BOTTOM w0.147: Q2.3 49.77,70.88 49.38,70.48 48.88,70.48 v1(48.63,70.23)
N27566278: length 3.3
  TOP w0.147: v1(47.11,69.34) 45.87,69.34 45.48,68.95 LD2.2
  BOTTOM w0.147: R260.1 v1(47.11,69.34)
N27566306: length 2.7
  BOTTOM w0.147: R272.2 51.25,71.74 50.72,71.21 Q2.1
N27566380: length 1
  TOP w0.147: LD4.2 R292.1
N27566388: length 1.3
  TOP w0.147: Q3.3 LD4.1
N27566452: length 5
  TOP w0.147: v1(46.47,40.34) 46.47,39.98 46.16,39.67 SW7.2
  BOTTOM w0.147: D13.2 45.09,41.13 C613.2 45.09,40.53 45.29,40.34 v1(46.47,40.34)
N27765807: length 1.2
  TOP w0.147: R3661.2 C3639.1
N27766023: length 1.8
  TOP w0.203: U134.13 16.4,15.53 15.98,15.11 R5805.1
N27780868: length 4.3
  BOTTOM w0.147: U135.2 54.17,80.24 54.34,80.07 R3723.2 55.05,79.08 54.2,78.24 R3724.1
N27781327: length 1.9
  BOTTOM w0.147: R3725.2 51.01,78.85 50.82,79.04 50.82,79.35 51.06,79.59 U135.4
N27827107: length 9.8
  TOP w0.147: U136.A12 66.18,86.05 64.18,88.06 64.18,92.57 TP594.1
N27866324: length 1.7
  TOP w0.147: LD6.2 R324.1
N27969798: length 2.8
  BOTTOM w0.147: R329.1 79.6,55.16 79.91,54.86 U62.1
N27969912: length 1.3
  BOTTOM w0.147: U65.2 R348.1
N27970038: length 3
  BOTTOM w0.147: U65.3 65.19,54.92 65.69,55.42 65.69,56.38 65.75,56.44 R349.1
N27970040: length 2.4
  BOTTOM w0.147: R358.1 68.5,56.22 69.14,55.57 U65.5
N27970042: length 1.4
  BOTTOM w0.147: R359.1 71.07,53.62 71.06,53.62 U65.8
N27972730: length 11.1
  TOP w0.147: U136.D2 v1(70.5,77.65)
  BOTTOM w0.147: v1(70.5,77.65) 68.5,75.66 62.11,75.66 61.51,76.27 R261.1
N27975044: length 5
  TOP w0.147: R252.1 62.42,76.74 62.02,77.14 C205.2 60.82,77.14 60.64,77.32 59.19,77.32 58.9,77.03 Y3.1
N27975050: length 2.5
  TOP w0.147: Y3.3 C209.2 61.75,75.13 61.76,75.13 R253.1
N27975317: length 2.6
  TOP w0.147: R3733.2 C3657.2 69.13,71.91 69.13,71.91 Y8.1
N27975321: length 6.3
  TOP w0.147: Y8.3 65.42,68.62 66.57,69.77 66.57,72.69 66.39,72.87 C3658.1 R3732.2
N27995683: length 8.4
  TOP w0.147: v1(61.94,98.04) 61.38,97.49 59.89,97.49 59.57,97.16 57.34,97.16 56.89,97.61 U140.C3
  BOTTOM w0.147: v1(61.94,98.04) 62.3,98.04 62.78,98.53 63.07,98.53 63.55,98.04 R5752.2
N28011359: length 21
  TOP w0.147: SW9.2 105.23,86.36 105.61,85.99 R5759.1 104.95,84.1 v1(104.92,84.07) ; v1(101.01,84.66) 101.77,83.9 101.77,82.09 100.83,81.16 96.21,81.16 95.83,81.53 R5758.2 95.4,81.97 95.22,82.15 v1(95.22,82.17)
  L03_SIG1 w0.091: v1(104.92,84.07) 104.34,84.66 v1(101.01,84.66)
  BOTTOM w0.147: U57.10 95.05,82.63 94.9,82.49 94.9,82.28 95.01,82.17 v1(95.22,82.17) 95.25,82.13 U57.9
N28038972: length 2.5
  TOP w0.147: U2.6 127.88,67.6 128.06,67.42 128.91,67.42 129.18,67.15 R5213.1
N28044811: length 7.6
  TOP w0.147: J34.1 C1.1 R5636.2 33.61,164.22 33.85,163.98 35.27,163.98 35.87,163.38 R5635.2
N28049053: length 1.8
  TOP w0.147: R69.2 114.27,145.39 114.06,145.61 U11.6
N28061850: length 5.9
  TOP w0.147: U136.N19 77.7,92.06 77.7,93.72 76.58,94.84 R178.2
N28066355: length 8.9
  TOP w0.132: 72.09,93.04 72.09,91.26 U136.G18
  TOP w0.147: 72.09,93.04 72.09,94.33 73.44,95.67 R5672.1
N28066391: length 12.2
  TOP w0.147: U136.H16 v1(72.9,89.65)
  BOTTOM w0.132: 70.38,93.7 70.38,91.16 71.7,89.84 71.7,89.5 71.93,89.26 72.5,89.26 v1(72.9,89.65)
  BOTTOM w0.147: R5673.1 69.32,95.72 70.38,94.67 70.38,93.7
N28066418: length 9.1
  TOP w0.132: U136.H18 72.9,91.25 72.9,93.04
  TOP w0.147: 72.9,93.04 72.9,93.94 74.74,95.78 R5674.1
N28066445: length 9.2
  TOP w0.147: U136.H17 v1(72.9,90.45)
  BOTTOM w0.147: v1(72.9,90.45) 72.9,91.33 71.95,92.28 71.95,96.11 71.77,96.29 R5675.1
N28066472: length 6
  TOP w0.147: U136.G19 72.5,94.22 74.09,95.82 R5676.1
N28066500: length 8.3
  TOP w0.147: v1(69.74,93.5) 70.9,92.34 U136.E19
  BOTTOM w0.147: R5677.2 67.73,98.17 68.88,97.03 68.88,95.66 69.74,94.79 v1(69.74,93.5)
N28071414: length 2.6
  BOTTOM w0.147: R5684.1 104.52,115.19 104.82,115.48 105.23,115.48 105.37,115.34 U2345.10
N28080788: length 1.5
  TOP w0.147: R143.1 100.92,60.24 101.24,60.24 101.36,60.13 U29.4
N28081065: length 1.1
  TOP w0.147: U2347.7 98.67,54.87 98.49,55.05 98.39,55.05 R5686.2
N28082506: length 10.5
  TOP w0.132: 66.79,85.65 67.53,85.65 67.53,85.65 68.1,85.65 U136.B11 ; 64.89,86.84 66.08,85.65 66.31,85.65
  TOP w0.147: TP586.1 63.82,90.87 63.82,87.91 64.89,86.84 ; 66.31,85.65 66.79,85.65
N28084397: length 4.2
  TOP w0.147: U136.U13 v1(80.9,87.25)
  BOTTOM w0.132: v1(80.9,87.25) 81.29,87.65 81.86,87.65 82.59,86.92 83.44,86.92
  BOTTOM w0.147: R530.1 83.62,87.1 83.44,86.92
N28084399: length 4.8
  TOP w0.147: R535.1 85.92,87.12 85.41,87.63 83.79,87.63 83.01,86.85 U136.W13
N28084409: length 2.9
  TOP w0.147: U136.T14 v1(80.1,88.05)
  BOTTOM w0.132: v1(80.1,88.05) 80.5,87.65 80.5,87.09 80.74,86.85 81.32,86.85 R537.1
N28084411: length 2.5
  TOP w0.147: U136.U14 v1(80.9,88.05)
  BOTTOM w0.132: 81.83,88.45 81.29,88.45 v1(80.9,88.05)
  BOTTOM w0.147: 81.83,88.45 82.17,88.45 82.28,88.34 R529.1
N28084427: length 2.7
  TOP w0.147: U136.V16 v1(81.7,88.85)
  BOTTOM w0.132: v1(81.7,88.85) 82.78,88.85 83.22,89.3 R509.1
N28084429: length 3.6
  TOP w0.147: R518.1 84.35,88.32 83.41,89.25 U136.W16
N28084431: length 1.1
  TOP w0.147: U136.V17 v1(81.7,89.65)
  BOTTOM w0.132: v1(81.7,89.65) 82.2,89.65 R527.1
N28084433: length 1.1
  TOP w0.147: U136.W18 v1(82.5,90.46)
  BOTTOM w0.147: R528.1 82.51,90.46 v1(82.5,90.46)
N28084995: length 1.5
  TOP w0.147: R5687.1 113.3,47.07 113.48,46.89 v1(113.48,46.56)
  BOTTOM w0.147: U120.3 113.47,46.65 113.48,46.63 v1(113.48,46.56)
N28086994: length 1.2
  TOP w0.147: U68.3 69.33,49.87 69.18,49.72 R5688.1
N28087268: length 6.9
  TOP w0.147: U136.V1 82.01,76.54 v1(82.01,76.05)
  BOTTOM w0.147: R538.1 86.28,75.74 85.59,76.43 84.47,76.43 84.12,76.78 83.1,76.78 82.36,76.05 v1(82.01,76.05)
N28088261: length 9.5
  TOP w0.108: v1(65.32,87.66) 65.78,88.11 67.09,88.11 67.54,87.65 U136.A14
  BOTTOM w0.108: R5694.2 61.08,91.48 61.42,91.48 64.66,88.24 65.28,88.24 65.51,88 65.51,87.85 v1(65.32,87.66)
N28088302: length 10.1
  TOP w0.108: v1(66.08,87.66) 67.1,87.66 67.5,87.25 67.86,87.25 68.26,86.85 U136.B13
  BOTTOM w0.108: v1(66.08,87.66) 65.91,87.66 65.8,87.76 65.8,88.12 65.4,88.53 64.78,88.53 61.54,91.77 61.12,91.77 60.76,92.13 R5695.2
N28088339: length 20.5
  TOP w0.132: v1(66.11,86.94) 66.13,86.94 66.63,86.45 68.1,86.45 U136.B12
  BOTTOM w0.132: v1(66.11,86.94) 66.11,86.96 65.98,87.1 65.09,87.1 64.89,87.3
  BOTTOM w0.147: 64.89,87.3 61.71,90.47 57.12,90.47 53.92,93.68 R5696.2
N28088462: length 4
  TOP w0.147: R5699.1 59.1,110.59 58.64,111.05 R5697.2 U2348.1
N28118724: length 4.3
  TOP w0.147: U48.33 43.53,96.59 43.45,96.67 v1(43.45,97.03)
  BOTTOM w0.147: v1(43.45,97.03) 43.1,97.03 42.92,97.21 R5730.2
N28118727: length 5.8
  TOP w0.147: v1(41.29,96.49) 41.8,96.49 41.95,96.34 43.03,96.34 43.13,96.23 U48.34
  BOTTOM w0.147: R5731.2 39.91,96.18 40.12,95.96 41.15,95.96 41.29,96.11 v1(41.29,96.49)
N28118756: length 15.9
  TOP w0.147: U136.L1 75.81,77.14 75.81,75.51 76.19,75.13 76.19,67.61 76.04,67.46 76.04,64.72 76.65,64.11 76.65,63.02 76.46,62.83 R5732.1
N28122339: length 5.1
  TOP w0.147: U136.A11 67.63,85.32 65.88,85.32 64.08,87.11 R542.2
N28129103: length 15.2
  TOP w0.147: v1(25.85,49.33) 25.85,47.94 25.7,47.79 R5736.1 24.6,47.79 24.45,47.94 24.45,50.29 24.66,50.5 U2356.4 ; v1(25.87,53.9) 26.48,53.9 27.25,53.14 27.25,52.04 26.71,51.5 U2356.9
  L03_SIG1 w0.091: v1(25.87,53.9) 26.28,53.49 26.28,49.76 v1(25.85,49.33)
N28133286: length 2.2
  TOP w0.147: R5743.1 90.47,98.05 90.31,98.21 U2357.2
N28133288: length 2.2
  TOP w0.147: U2357.3 91.58,98.07 91.45,97.93 R5743.2
N28157125: length 1.8
  TOP w0.147: R3933.2 LD13.2
N28224119: length 4
  TOP w0.147: U56.36 37.82,59.18 37.64,59.36 35.81,59.36 35.49,59.67 R297.2
N28224122: length 2.6
  TOP w0.147: U56.35 38.32,59.46 37.96,59.82 R307.2
N28224348: length 8.8
  TOP w0.132: 66.89,82.45 68.1,82.45 U136.B7
  TOP w0.147: 66.89,82.45 64.12,82.45 63.58,82.99 63.15,82.99 61.35,84.8 R5751.1
N28238385: length 2
  TOP w0.147: U3077.8 95.19,64.38 95.45,64.13 R166.2
N28248996: length 1.8
  TOP w0.147: R5637.2 37.39,163.71 36.98,164.13 TP593.1
N28268314: length 7.3
  TOP w0.147: U136.C16 v1(68.9,89.65)
  BOTTOM w0.132: v1(68.9,89.65) 69.29,90.05 69.29,92.52 68.83,92.99
  BOTTOM w0.147: R5757.1 68.23,95.13 68.83,94.54 68.83,92.99
N28271262: length 2.3
  TOP w0.147: R115.2 R116.2 U26.1
N28389021: length 8.9
  TOP w0.147: U3076.3 R5766.1 21.54,63.78 21.85,64.08 22.57,64.08 23.41,63.25 23.41,62.51 23.21,62.31 23.21,61.16 22.27,60.23 U54.4
N28496978: length 2.4
  TOP w0.147: J12.1 R5775.2
N28497016: length 3.1
  TOP w0.147: R5776.2 24.96,116.79 24.51,117.24 J13.1
N28557174: length 4.7
  BOTTOM w0.147: C615.2 R634.2 R632.1 90.51,33.03 90.16,32.68 90.16,32.31 90.43,32.04 U127.3
N28557887: length 1.7
  BOTTOM w0.147: U127.1 90.53,31.05 90.09,30.61 R5777.2
N28895418: length 3.5
  TOP w0.147: R5790.2 112.34,54.79 112.76,54.36 U3084.2
N28895646: length 3.2
  TOP w0.147: R5791.1 113.9,54.69 113.41,54.2 U3084.3
N28895649: length 2.9
  TOP w0.147: U3084.8 112.11,57.89 111.95,57.73 111.02,57.73 110.84,57.55 R5792.1
N28896188: length 1.7
  TOP w0.147: R5789.1 107.66,56.96 107.44,57.19 U3083.4
N28896306: length 2.2
  TOP w0.147: U3083.7 106.64,59.96 106.9,60.22 R5793.2
N28962728: length 4.1
  TOP w0.147: U3086.4 63.73,52.56 64.13,52.96 R5806.1 63.39,53.7 62.94,54.15 U3087.2
N29136309: length 2.2
  TOP w0.147: U2353.5 78.17,49.1 78.6,49.53 R5808.1
N29136335: length 2.1
  TOP w0.147: R5733.1 79.04,48.77 78.85,48.58 78.85,48.37 78.97,48.25 78.97,47.97 78.87,47.86 U2353.4
N29218455: length 1
  TOP w0.147: U2353.6 77.77,48.89 77.56,49.1 R5734.1
N29295413: length 6.3
  TOP w0.147: U28.C2 v1(68.14,108.41)
  BOTTOM w0.147: R5826.1 71.71,106.61 70.66,107.67 68.88,107.67 v1(68.14,108.41)
N29295438: length 6.1
  TOP w0.147: U28.A3 66.73,105.71 v1(66.85,105.59)
  BOTTOM w0.147: R5827.1 70.16,104.23 69.7,103.76 68.89,103.76 68.63,104.03 68.63,105.26 68.13,105.75 67.39,105.75 67.23,105.59 v1(66.85,105.59)
N271759124: length 3
  TOP w0.147: TP32.1 85.77,56.34 86.19,56.34 86.98,57.14 U15.5
N271759125: length 4.1
  TOP w0.147: U15.6 87.11,56.64 86.36,55.88 86.36,54.75 85.84,54.23 TP33.1
N275664200: length 1.3
  TOP w0.147: Q3.1 R286.2
N280409620: length 1.3
  TOP w0.147: SW9.1 R3736.1
N284070661: length 1.2
  TOP w0.147: LD14.2 R195.2

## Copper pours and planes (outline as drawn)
AVDD_3V3_DAC on TOP: 98.35,157.29 98.35,158.41 98.21,158.56 98.21,160.35 98.28,160.43 99.56,160.43 99.78,160.21 99.78,159.11 99.73,159.05 99.56,159.05 99.29,158.78 99.29,157.92 99.42,157.79 100.28,157.79 100.49,157.57 100.49,156.13 100.33,155.96 99.71,155.96 99.25,156.43 99.25,157 98.97,157.28 98.36,157.28
AVDD_3V3_DAC on L03_SIG1: 97.55,162.56 81.86,162.56 80.92,161.62 80.92,157.56 82.16,157.56 82.16,160.81 82.59,161.24 96.49,161.24 98.7,159.03 100.09,159.03 100.73,159.66 107.28,159.66 108.37,158.57 113.96,158.57 113.96,159.51 113.15,160.32 109.19,160.32 108.25,161.26 98.85,161.26
DGND on TOP (solid shape): 36.85,77.29 36.65,77.09 33.52,77.09 33.39,77.22 33.39,78.96 36.85,78.96
DGND on TOP (solid shape): 90.84,58.51 90.71,58.37 90.71,57.41 90.84,57.28 90.84,56.49 88.06,56.49 88.06,59.28 90.84,59.28
DGND on TOP (solid shape): 77.46,67.31 77.8,66.98 77.8,65.39 77.22,65.39 77.22,66.83 77.08,66.83 77.08,67.42 77.08,67.49 77.46,67.49
DGND on TOP (solid shape): 33.54,75.97 33.63,75.91 33.61,75.8 32.64,74.83 31.72,74.83 31.72,75.97
DGND on TOP (solid shape): 99.57,120.08 99.57,117.77 99.12,117.32 99.01,117.3 98.95,117.39 98.95,120.09 99.26,120.39
DGND on TOP (solid shape): 45.55,97.75 46.06,97.75 46.1,97.7 46.1,96.02 46.11,95.97 46.11,95.93 46.11,95.91 45.84,95.63 45.84,94.11 44.36,94.11 44.36,97.07 45.42,97.07 45.42,97.75 45.55,97.75
DGND on TOP (solid shape): 60.48,39.11 60.53,39.11 60.53,38.75 58.61,38.75 58.61,36.95 58.32,36.95 58.32,38.75 58.3,38.75 58.25,38.78 58.26,38.84 59.27,39.84 60.48,39.84
DGND on TOP (solid shape): 58.05,146.61 58.21,146.61 58.36,146.46 59,146.46 59,145.8 58.98,145.76 58.95,145.75 58.9,145.74 58.39,145.74 58.06,146.07 57.81,146.07 57.52,146.36 57.52,146.66 58,146.66
DGND on TOP (solid shape): 66.69,133.72 65.19,133.72 65.19,133.24 65.18,133.17 65.17,133.11 65.17,132.77 65.08,132.68 64.97,132.66 64.91,132.75 64.91,133.72 63.91,133.72 63.91,136.5 66.69,136.5
DGND on TOP (solid shape): 105.76,118.42 104.91,117.57 104.8,117.55 104.74,117.64 104.74,122.84 104.24,123.33 104.22,123.44 104.32,123.51 105.76,123.51
DGND on TOP (solid shape): 20.55,50.38 20.66,50.4 20.72,50.3 20.72,50.12 19.22,48.61 18.48,48.61 18.48,49.87 18.62,49.87 18.69,49.87 18.75,49.89 18.84,49.89 18.84,49.39 19.61,49.39 19.61,50.22 20.39,50.22
DGND on TOP (solid shape): 97.56,126.5 97.67,126.52 97.73,126.43 97.73,117.3 97.55,117.11 97.44,117.09 97.37,117.19 97.37,120.98 96.99,121.37 96.99,125.93
DGND on TOP (solid shape): 128.69,139.97 131.35,139.97 131.35,139.18 128.69,139.18 128.69,138.36 128.58,138.36 128.56,138.36 128.43,138.4 128.29,138.39 128.2,138.41 128.16,138.49 128.16,139.85 128.31,140 128.69,140
DGND on TOP (solid shape): 30.98,104.18 30.73,103.93 29.86,103.93 29.82,103.93 29.77,103.92 29.72,103.93 29.71,103.98 29.71,104.01 29.71,104.65 29.71,104.65 29.68,104.77 29.78,104.83 30.98,104.83
DGND on TOP (solid shape): 57.6,69.44 57.6,68.21 57.54,68.12 57.43,68.14 57.11,68.46 57.11,69.32 54.63,71.8 53.28,71.8 53.21,71.83 53.18,71.9 53.18,71.96 55.08,71.96
DGND on TOP (solid shape): 60.61,144.93 60.65,144.86 60.65,143.69 63.18,143.69 63.18,142.7 62.12,142.7 61.51,142.09 60.42,142.09 60.37,142.14 60.37,144.86 60.4,144.93 60.48,144.96 60.53,144.96
DGND on TOP (solid shape): 93.91,59.51 93.94,59.55 93.99,59.54 94.05,59.49 94.05,58.55 94.36,58.55 94.43,58.51 94.46,58.43 94.45,58.39 94.46,58.35 94.46,57.76 94.25,57.55 93.91,57.55
DGND on TOP (solid shape): 92.59,56.91 92.9,56.91 93,56.85 92.97,56.74 92.65,56.42 92.65,55.83 92.37,55.55 91.19,55.55 91.08,55.66 91.08,55.99 91.07,56.08 91.03,56.16 91.03,56.17 91.03,56.31 91.86,56.31 91.86,57.21 92.29,57.21
DGND on TOP (solid shape): 56.17,104.85 56.22,104.94 56.33,104.93 57.88,104.93 58.06,104.75 58.06,103.73 57.4,103.07 56.61,103.07 56.29,102.75 56.18,102.73 56.11,102.82 56.11,104.3 56.17,104.3
DGND on TOP (solid shape): 97.97,95.71 98.08,95.73 98.14,95.64 98.14,93.48 97.48,92.81 97.42,92.8 97.39,92.85 97.39,92.91 97.38,92.95 97.38,93.25 96.6,93.25 96.6,94.34
DGND on TOP (solid shape): 56.28,57.25 57.04,57.25 57.23,57.29 57.38,57.4 57.45,57.43 57.52,57.4 57.98,56.95 57.98,55.47 54.98,55.47 54.9,55.39 54.79,55.37 54.73,55.46 54.73,57.59 55.94,57.59
DGND on TOP (solid shape): 98.52,78.64 98.31,78.43 97.5,78.43 96.66,77.6 96.59,77.57 96.52,77.6 96.51,77.62 96.08,78.04 96.07,78.11 96.07,78.5 95.45,78.5 95.36,78.56 95.38,78.67 96.36,79.65 98.52,79.65
DGND on TOP (solid shape): 71.12,49.73 71.74,49.73 72.36,49.11 72.36,49.07 72.34,49.04 72.3,49.02 72.24,49.02 71.77,49.02 71.75,48.99 70.91,48.99 70.76,49.14 70.89,49.27 70.97,49.4 71,49.54 71,49.63 71.03,49.7 71.11,49.73
DGND on TOP (solid shape): 58.36,68.95 58.42,69.04 58.53,69.02 59.27,68.28 59.27,67.19 59.43,67.03 59.43,61.06 59.4,60.99 59.32,60.96 59.26,60.96 59.18,60.98 59.15,61.06 59.15,63.81 58.36,64.6
DGND on TOP (solid shape): 87.38,83.09 86.22,81.93 86.22,81.8 85.13,81.8 85.11,81.79 84.82,82.08 84.31,82.08 84.22,82.13 84.22,82.23 84.25,82.31 84.26,82.4 84.29,82.47 84.36,82.5 84.75,82.5 84.75,82.25 85.92,82.25 85.92,83.42 86.8,83.42 86.8,83.56 86.91,83.56
DGND on TOP (solid shape): 24.53,120.62 24.57,120.63 24.65,120.6 24.68,120.53 24.68,117.62 24.37,117.62 24.37,119.25 21.67,119.25 21.67,118.42 21.54,118.42 21.51,118.39 21.46,118.38 21.43,118.43 21.43,119.63 21.83,120.04 24.37,120.04 24.37,120.53 24.4,120.6 24.48,120.63
DGND on TOP (solid shape): 87.87,56.17 87.86,56.16 87.83,56.08 87.82,55.99 87.82,55.53 87.78,55.49 87.49,55.49 87.31,55.3 87.28,55.3 87.08,55.27 86.9,55.18 86.79,55.16 86.74,55.26 86.74,55.72 87.27,56.26 87.55,56.26 87.64,56.27 87.72,56.3 87.73,56.31 87.87,56.31
DGND on TOP (solid shape): 51.17,50.65 51.58,50.24 52.11,50.24 52.12,50.25 52.23,50.27 52.29,50.18 52.29,49.61 52.98,48.92 53.53,48.92 53.63,48.82 53.64,48.81 53.78,48.63 54,48.56 54.02,48.57 54.07,48.51 53.99,48.44 52.93,48.44 52.49,48.87 51.81,48.87 51.81,49.86 51.38,50.29 49.7,50.29 49.27,50.72 49.27,51.05 51.17,51.05
DGND on TOP (solid shape): 22.38,14.88 22.39,14.82 22.34,14.79 22.28,14.79 22.28,13.82 23.32,13.82 23.32,13.93 23.55,13.93 23.55,13.82 24.59,13.82 24.59,13.93 25.07,13.93 25.07,13.82 25.88,13.82 25.88,12.73 24.75,11.61 22.89,11.61 22.89,12.71 22.74,12.71 22.74,12.84 22.38,13.21 21.84,13.21 21.76,13.29 21.76,14.91 21.69,14.98 21.67,15.09 21.77,15.15 22.1,15.15
DGND on TOP (solid shape): 32.31,115.41 32.77,115.41 32.77,111.58 32.31,111.58 32.31,109.9 31.33,109.9 30.83,109.4 30.83,109.03 30.56,109.03 30.56,109.36 28.76,109.36 28.76,107.94 30.56,107.94 30.56,108.27 30.83,108.27 30.83,108.05 30.83,108.05 30.83,106.3 30.56,106.3 30.56,107.46 28.76,107.46 28.76,107.13 26.7,107.13 25.66,106.09 25.55,106.07 25.49,106.16 25.49,108.28 28.02,110.81 28.02,113 29.68,113 30.22,113.54 30.22,116.76 30.4,116.94 32.31,116.94
DGND on TOP (solid shape): 98.32,92.59 98.43,92.61 98.5,92.52 98.5,90.97 97.59,90.97 97.55,90.97 97.48,91 97.44,91.08 97.44,91.11 97.48,91.19 97.56,91.22 97.71,91.23 97.84,91.29 97.97,91.29 97.97,91.46 97.99,91.53 97.99,91.59 97.99,92.26
DGND on TOP (solid shape): 101.6,56.73 101.71,56.75 101.78,56.66 101.78,56.63 102.45,55.96 102.96,55.96 103,55.92 103.02,55.81 102.93,55.75 102.38,55.75 102.31,55.74 102.25,55.72 101.75,55.72 101.75,55.46 101.69,55.36 101.58,55.39 101.34,55.63 101.34,56.46
DGND on TOP (solid shape): 103.31,137.72 99.83,137.72 99.83,137.23 99.81,137.16 99.8,137.1 99.8,136.26 99.68,136.13 99.68,135.9 99.68,135.9 99.68,135.17 99.71,135.17 99.8,135.1 99.78,134.99 99.11,134.32 99.11,133.92 99.04,133.83 98.93,133.85 98.41,134.37 98.41,137.47 98.93,137.47 98.99,137.48 99.06,137.49 99.56,137.49 99.56,141.48 103.31,141.48
DGND on TOP (solid shape): 60.33,55.12 60.44,55.14 60.5,55.04 60.5,54.55 61.27,54.55 61.27,54.25 61.26,54.2 61.26,54.15 61.26,53.53 60.17,52.44 60.17,50.95 60.33,50.78 60.36,50.71 60.33,50.64 60.18,50.39 60.21,50.1 60.21,50 60.12,49.95 59.73,49.95 59.73,54.51
DGND on TOP (solid shape): 81.6,50.76 81.6,48.75 80.22,47.37 79.74,47.37 79.72,47.39 79.72,47.46 79.71,47.56 79.68,47.66 79.67,47.67 79.67,47.83 79.52,47.83 79.45,47.86 79.39,47.88 79.35,47.89 79.35,48.25 79.35,48.35 79.98,48.35 79.98,49.11 80.08,49.11 80.13,49.1 80.18,49.1 80.74,49.1 80.75,49.1 81.16,49.16 81.35,49.53 81.35,50.89 81.39,50.93 81.44,50.93
DGND on TOP (solid shape): 27.2,93.06 27.17,93.02 27.1,92.73 27.29,92.41 27.27,92.34 27.17,92.14 27.19,91.92 27.17,91.83 27.09,91.79 26.09,91.79 25.87,92 25.85,92.11 25.94,92.18 26.05,92.18 26.46,92.58 26.46,93.12 27.14,93.12
DGND on TOP (solid shape): 24.2,80.87 24.22,80.78 24.16,80.7 23.95,80.58 23.84,80.37 23.84,80.35 23.72,80.23 23.72,79.96 23.66,79.9 23.39,79.9 23.27,79.88 23.15,79.82 22.95,79.82 22.95,80.17 22.73,80.17 22.62,80.23 22.49,80.25 22.1,80.25 21.97,80.38 22,80.44 22.03,80.44 22.03,80.59 22.43,80.59 22.5,80.58 22.58,80.59 22.87,80.59 22.87,81.1 23.97,81.1
DGND on TOP (solid shape): 26.2,102.68 26.27,102.77 26.38,102.75 26.47,102.66 27.46,102.66 27.46,102.43 27.46,102.42 27.42,102.33 27.41,102.22 27.41,101.75 27.53,101.45 27.81,101.3 27.89,101.23 27.86,101.13 27.25,100.51 27.25,100.48 27.22,100.41 27.14,100.38 27.08,100.38 26.59,100.38 26.2,100.77
DGND on TOP (solid shape): 51.55,82.05 51.62,82.14 51.73,82.12 52.24,81.61 52.72,81.61 52.75,81.58 52.75,81.1 53.23,80.62 55.47,80.62 56.65,81.8 56.76,81.82 56.82,81.73 56.82,81.59 56.68,81.59 56.68,79.65 54.65,79.65 54.65,79.76 51.66,79.76 51.27,80.14 51.55,80.42 51.55,80.93 51.59,80.94 51.86,81.31 51.59,81.67 51.55,81.68
DGND on TOP (solid shape): 69.79,97.63 69.81,97.59 69.81,97.06 69.56,97.06 69.56,94.91 69.6,94.91 69.6,94.87 69.81,94.87 69.81,94.52 70.92,93.41 70.92,93.04 70.93,92.95 70.88,92.9 70.01,93.77 69.6,93.85 69.36,93.51 69.33,93.44 69.26,93.41 68.36,93.41 68.01,93.75 68.01,94.89 69.2,94.89 69.2,96.14 68.99,96.14 68.99,96.74 69.46,97.2 69.46,97.64
DGND on TOP (solid shape): 27.04,74.65 28.87,74.65 28.87,74.68 30.19,74.68 30.32,74.55 30.32,73.86 30.75,73.86 30.75,73.59 31.11,73.24 31.2,73.16 31.31,73.12 31.39,73.05 31.36,72.95 30.92,72.51 30.82,72.48 30.75,72.56 30.6,72.8 30.33,72.87 30.33,72.87 29.99,72.87 29.99,73.07 28.58,73.07 28.58,72.11 28.04,72.11 28.04,73.07 27.28,73.07 27.28,72.87 26.58,72.87 26.58,73.01 26.48,73.01 26.48,73.24 26.58,73.24 26.58,74.28 26.48,74.28 26.48,74.53 26.4,74.61 26.4,74.96 26.74,74.96
DGND on TOP (solid shape): 100.25,60.16 100.46,60.16 100.76,59.86 100.98,59.86 100.98,59.53 101,59.41 101.05,59.31 101.05,58.91 101.45,58.91 101.45,58.66 101.4,58.55 101.38,58.43 101.38,57.57 101.04,57.24 100.99,57.23 100.96,57.27 100.96,57.33 100.17,58.12 100.17,58.42 100.04,58.74 99.71,58.88 99.66,58.88 99.66,58.94 99.64,59.14 99.52,59.3 99.48,59.38 99.51,59.45 99.99,59.93 99.99,60.59 100.25,60.59
DGND on TOP (solid shape): 35.89,26.86 37.59,26.86 37.59,26.76 37.74,26.41 38.13,26.38 38.14,26.38 38.2,26.38 38.2,26.3 38.37,25.93 38.78,25.93 38.88,25.93 38.93,25.84 38.93,25.36 38.87,25.3 36.39,25.3 36.1,25.59 36.1,26.12 36.06,26.28 35.97,26.42 35.78,26.62 35.78,26.81 35.77,26.87 35.76,26.93 35.76,26.99 35.89,26.99
DGND on TOP (solid shape): 51.15,68.91 51.07,68.91 50.06,67.89 49.72,67.89 49.63,67.94 49.63,68.04 49.5,68.54 49,68.46 49,68.46 48.5,67.96 48.39,67.94 48.32,68.04 48.32,68.85 48.26,68.85 48.16,68.91 48.19,69.02 49.01,69.85 49.01,70.19 49.01,70.23 49.04,70.31 49.12,70.34 51.15,70.34
DGND on TOP (solid shape): 107.77,118.34 107.78,118.35 107.81,118.37 107.84,118.37 107.87,118.37 107.9,118.36 107.92,118.34 107.94,118.32 107.94,118.29 107.94,118.27 107.94,114.05 103.62,109.72 103.61,109.71 103.58,109.7 103.55,109.69 103.52,109.7 103.49,109.71 103.47,109.73 103.45,109.75 103.44,109.78 103.44,109.79 103.44,113.46 103.9,113.46 103.91,113.41 103.92,113.35 103.94,113.3 103.97,113.25 104,113.21 104.04,113.17 104.09,113.14 104.14,113.11 104.19,113.09 104.24,113.08 104.3,113.08 104.35,113.09 104.41,113.1 104.46,113.12 104.51,113.15 104.55,113.19 104.59,113.23 104.62,113.28 104.64,113.33 104.66,113.38 104.67,113.43 104.67,113.49 104.66,113.54 104.64,113.6 104.62,113.65 104.59,113.69 104.55,113.74 104.51,113.77 104.46,113.8 104.41,113.82 104.35,113.84 104.3,113.84 104.24,113.84 104.19,113.83 104.14,113.81 104.09,113.79 104.04,113.76 104,113.72 103.97,113.67 103.94,113.62 103.92,113.57 103.91,113.52 103.9,113.46 103.44,113.46 103.44,114.02
DGND on TOP (solid shape): 65.65,50.41 66.02,50.04 67.03,50.04 67.45,50.47 67.45,50.69 68.1,50.69 68.1,50.69 68.22,50.69 68.22,50.69 68.78,50.69 68.98,50.49 69.64,50.49 69.69,50.49 69.78,50.47 69.81,50.39 69.81,50.34 69.77,50.26 69.69,50.24 69.65,50.24 69.61,50.25 69.17,50.25 69.02,50.09 68.86,50.09 68.86,50.15 68.03,50.15 68.03,49.93 67.98,49.84 67.88,49.84 67.78,49.87 67.68,49.89 66.61,49.89 65.59,48.87 64.33,48.87 63.77,49.44 63.75,49.55 63.84,49.61 64.02,49.61 64.71,50.29 64.71,50.85 64.71,50.85 65.65,50.85
DGND on TOP (solid shape): 65.31,151.35 65.96,151.35 66.06,151.45 67.87,151.45 67.87,147.44 68.33,147.44 68.4,147.42 68.46,147.42 69.32,147.42 69.39,147.49 71.76,147.49 75.59,151.33 75.7,151.35 75.76,151.25 75.76,147.24 75.14,146.62 75.14,144.91 75.08,144.81 74.97,144.83 74.26,145.54 69.92,145.54 68.34,143.97 68.34,143.51 68.16,143.32 68.05,143.3 67.99,143.4 67.99,145.88 67.81,145.88 67.81,146.32 67.81,146.32 67.81,146.52 67.59,146.74 67.59,147.05 67.59,147.11 67.57,147.18 67.57,147.64 66.27,147.64 66.27,147.7 65.2,147.7 65.2,147.64 64.06,147.64 64.06,149.83 64.2,149.83 64.2,150.77 64.06,150.77 64.06,151.45 65.31,151.45
DGND on TOP (solid shape): 32.02,24.03 32.02,21.94 31.19,21.94 31.19,20.91 31.09,20.81 31.03,20.8 31,20.85 31,20.91 30.07,20.91 30.07,20.96 26.28,20.96 25.42,20.09 25.42,18.8 25.32,18.69 23.74,18.69 22.9,17.86 21.2,17.86 20.69,17.35 19.7,17.35 19.7,19.61 20.97,20.88 22.85,20.88 23.64,21.67 23.64,23.49 23.38,23.75 23.36,23.86 23.45,23.93 26.67,23.93 26.67,22.84 26.94,22.56 27.47,22.56 28.14,21.89 29.81,21.89 29.81,22 30.35,22 30.35,22.7 30.52,22.87 30.52,23.1 30.31,23.48 29.88,23.41 29.84,23.38 29.3,23.91 29.3,24.86 31.19,24.86
DGND on TOP (solid shape): 95.53,36.24 95.56,36.16 95.53,36.09 95.46,35.68 95.8,35.45 95.88,35.42 95.91,35.35 95.91,34.24 93.64,31.98 90.83,31.98 89.86,32.94 87.77,32.94 87.54,32.71 82.22,32.71 80.43,34.5 80.43,34.86 80.49,34.95 80.61,34.93 81.91,33.63 92.65,33.63 94.62,35.59 94.65,35.56 95.19,35.56 95.19,36.1 95.15,36.13 95.39,36.37
DGND on TOP (solid shape): 28.22,67.72 28.29,67.69 28.32,67.62 28.7,67.26 29.08,67.62 29.12,67.69 29.19,67.72 31.5,67.72 31.59,67.66 31.57,67.55 31.16,67.14 31.16,60.4 31.13,60.35 31.07,60.37 31,60.44 31,63.12 29.46,64.67 28.72,64.67 28.51,64.82 28.26,64.87 28.19,64.9 28.16,64.98 28.16,66.77 27.38,67.55 27.36,67.66 27.45,67.72
DGND on TOP (solid shape): 39.51,113.72 39.59,113.67 39.6,113.57 39.64,113.19 39.99,113.03 40.14,113.03 40.2,112.98 40.17,112.91 40.16,112.91 40.16,109.38 41.28,109.38 41.28,112.91 41.1,112.91 41.1,113.15 40.7,113.54 40.68,113.65 40.78,113.72 42,113.72 42.06,113.66 42.09,113.56 42.01,113.49 41.61,113.09 41.61,112.91 41.43,112.91 41.43,109.38 42.55,109.38 42.55,112.73 42.7,112.73 42.7,109.38 42.77,109.38 42.84,109.35 42.87,109.28 42.87,109.19 42.23,109.19 41.92,108.89 39.85,108.89 39.65,109.08 39.83,109.25 39.83,109.38 40.01,109.38 40.01,112.91 38.89,112.91 38.89,109.57 38.74,109.57 38.74,112.91 38.56,112.91 38.56,113.72
DGND on TOP (solid shape): 36.55,84.84 36.66,84.86 36.72,84.77 36.72,83.29 35.87,82.43 35.78,82.41 35.7,82.47 35.13,82.63 35.09,82.04 35.12,81.93 35.03,81.86 34.74,81.86 34.21,82.4 34.08,82.4 33.99,82.43 33.98,82.52 33.98,82.76 33.86,82.96 33.69,83.14 33.69,83.19 34.05,83.55 34.15,83.71 34.18,83.89 34.21,83.97 34.28,84 35.71,84
DGND on TOP (solid shape): 59.91,89.05 59.91,88.72 59.92,88.6 59.97,88.48 59.98,88.47 59.98,88.35 60.09,88.35 60.1,88.34 60.26,88.28 60.43,88.27 60.51,88.24 60.54,88.17 60.54,87.7 60.55,87.66 60.55,87.62 60.55,87.32 61.29,87.32 61.29,87.62 61.3,87.66 61.3,87.7 61.3,88.34 61.67,88.34 61.67,87.26 61.81,87.26 61.81,86.66 59.98,86.66 59.14,87.5 56.56,87.5 56.03,88.03 53.32,88.03 53.25,87.96 53.02,87.96 52.95,87.95 52.87,87.96 52.82,88.04 52.62,88.35 52.24,88.34 52.19,88.34 52.16,88.38 52.16,88.46 52.58,88.87 54.32,88.87 54.5,88.9 54.65,89 55.38,89.74 59.22,89.74
DGND on TOP (solid shape): 45.41,44.91 45.48,44.88 45.51,44.8 45.54,44.63 45.65,44.48 45.65,44.48 46.37,43.77 47.06,43.77 47.13,43.74 47.16,43.67 47.29,43.4 47.58,43.31 47.59,43.31 48.54,43.31 48.64,43.25 48.61,43.14 46.81,41.33 46.81,40.76 46.76,40.67 46.66,40.67 46.26,40.65 46.1,40.29 46.1,40.14 46.01,40.05 45.88,40.05 45.88,40.51 44.2,40.51 44.2,39.35 44.17,39.31 44.12,39.32 44.03,39.4 44.03,40.38 43.24,41.17 43.21,41.17 43.18,41.23 44.39,42.44 44.39,44.52 44.78,44.91
DGND on TOP (solid shape): 42.94,91.34 42.9,91.26 42.81,91.24 42.58,91.25 42.39,91.12 42.39,91.12 41.5,90.23 41.5,86.69 40.07,85.27 37.63,85.27 37.58,85.27 37.51,85.3 37.48,85.37 37.48,85.86 37.52,85.94 37.6,85.96 37.65,85.95 37.7,85.96 38.4,85.96 40.55,88.11 40.55,88.96 40.6,89.05 40.7,89.05 41.27,89.38 40.7,89.72 40.6,89.72 40.55,89.81 40.55,90.42 42.03,91.9 42.94,91.9
DGND on TOP (solid shape): 86.59,95.74 86.7,95.76 86.76,95.67 86.76,94.97 88.89,92.83 88.89,90.11 88.86,90.04 88.78,90.01 88.33,89.64 88.78,89.26 88.86,89.24 88.89,89.16 88.89,87.26 88.83,87.17 88.72,87.19 87.85,88.07 87.85,89.59 87.88,89.66 87.95,89.69 88.31,90.07 87.95,90.45 87.88,90.48 87.85,90.55 87.85,90.61 86.5,91.95 86.5,95.65
DGND on TOP (solid shape): 69.47,115.91 69.58,115.93 69.64,115.83 69.64,112.82 69.79,112.67 69.82,112.56 69.72,112.5 65.91,112.5 65.45,112.04 65.45,110.77 65.62,110.6 65.65,110.5 65.58,110.43 65.49,110.38 65.4,110.32 65.13,110.04 65.11,110.04 65.07,110.04 65.05,110.07 64.47,110.2 64.72,109.66 64.75,109.65 64.77,109.61 64.77,109.55 64.78,109.5 64.76,109.41 64.69,109.37 64.38,109.37 64.25,109.51 63.72,109.51 63.7,109.51 63.63,109.54 63.6,109.61 63.6,112.17 64.49,113.06 66.62,113.06
DGND on TOP (solid shape): 34.88,34.17 34.88,33.37 35.48,33.37 35.48,32.44 34.59,31.55 34.59,30 34.53,29.94 34.49,29.98 34.48,29.99 33.88,30.13 33.93,29.52 33.98,29.45 33.95,29.36 33.83,29.24 33.83,27.63 33.77,27.53 33.66,27.55 33.66,27.55 33.48,27.73 33.48,31.92 33.52,32 33.61,32.02 34.09,32.38 33.61,32.75 33.52,32.77 33.48,32.85 33.48,32.97 33.88,33.38 33.96,33.38 33.96,33.37 34.7,33.37 34.7,33.67 34.7,33.71 34.71,33.76 34.71,34.13 34.82,34.24
DGND on TOP (solid shape): 53.51,35.44 53.72,35.23 54.66,35.23 54.82,35.39 55.06,35.39 55.06,34.99 55.77,34.99 55.89,34.94 56.02,34.92 56.72,34.92 56.79,34.85 56.79,34.7 55.06,34.7 55.06,32.78 54.75,32.78 54.75,32.83 53.82,32.83 53.39,33.26 53.26,33.26 53.26,33.55 51.74,33.55 51.48,33.81 51.48,35.49 51.51,35.52 51.56,35.53 51.59,35.48 51.59,35.3 51.59,35.26 51.58,35.21 51.58,34.39 51.59,34.38 51.92,34.05 52.24,33.91 52.54,34.09 52.61,34.14 52.7,34.11 53.05,33.76 54.41,33.76 54.41,33.76 54.83,34.14 54.41,34.52 54.41,34.52 53.36,34.52 53.18,34.7 53.18,35.21 53.18,35.26 53.17,35.3 53.17,35.5 53.26,35.77 53.18,36.03 53.17,36.05 53.17,36.17 53.51,36.17
DGND on TOP (solid shape): 65.25,109.14 65.32,109.11 65.35,109.03 65.42,108.76 65.66,108.62 65.74,108.55 65.71,108.45 65.63,108.36 65.62,108.36 65.35,108.03 65.55,107.65 65.61,107.58 65.58,107.49 65.49,107.41 65.07,107.83 65.08,107.86 64.8,108.37 64.35,108 64.32,107.93 64.24,107.9 63.98,107.9 63.6,108.28 63.6,108.64 63.63,108.71 63.7,108.75 63.94,108.75 64.07,108.61 64.68,108.61 64.69,108.61 64.99,108.72 65.11,109.03 65.13,109.11 65.21,109.14
DGND on TOP (solid shape): 124.73,48.43 124.73,46.25 125.67,45.31 125.67,43.86 125.39,43.86 125.13,43.61 124.96,43.61 124.68,43.33 124.44,43.57 124.44,43.83 124.4,43.87 124.4,45.71 123.6,45.71 123.5,45.77 123.53,45.88 123.85,46.2 123.85,47.35 123.97,47.49 124.04,47.68 124.04,47.69 124.31,47.96 124.35,48.53 123.78,48.5 123.63,48.35 123.61,48.36 123.02,48.16 122.93,47.55 122.93,47.46 122.84,47.41 122.28,47.41 122.28,46.37 122.31,46.32 121.81,45.83 121.81,44.57 121.77,44.49 121.68,44.47 121.49,44.5 121.31,44.47 121.22,44.49 121.17,44.57 121.17,44.62 121.53,44.98 121.53,48.95 121.52,48.96 121.5,49.02 121.55,49.05 124.12,49.05
DGND on TOP (solid shape): outline of 121 points within 45.59,53.09 48.58,59.46
DGND on TOP (solid shape): 119.58,40.6 119.66,40.56 119.67,40.47 119.67,40.33 119.72,40.19 119.72,39.09 119.81,39.09 119.81,38.99 119.88,38.92 119.88,38.89 120.01,38.58 120.34,38.49 120.42,38.47 120.46,38.39 120.46,38.05 120.77,37.74 120.77,37.72 120.73,37.64 120.64,37.62 120.56,37.64 120.47,37.64 120.13,37.64 119.58,37.09 119.48,37.07 119.41,37.14 119.26,37.37 119,37.44 119,37.44 118.59,37.44 118.53,37.49 118.53,37.66 118.58,37.74 118.68,37.75 118.93,37.71 119.15,37.85 119.15,37.85 119.61,38.31 119.61,39.62 119.6,39.73 119.55,39.83 119.55,40.16 118.92,40.16 118.92,39.83 118.87,39.73 118.86,39.62 118.86,38.63 118.62,38.39 118.59,38.36 118.48,38.34 118.41,38.43 118.41,39.62 118.4,39.73 118.35,39.83 118.35,40.16 117.06,40.16 117.06,40.26 117.4,40.6
DGND on TOP (solid shape): 41.74,71.17 41.81,71.27 41.92,71.24 42.75,70.41 44.72,70.41 45.27,69.86 47.71,69.86 47.8,69.79 47.78,69.68 47.6,69.51 47.52,69.48 47.44,69.53 47.28,69.68 47.07,69.72 47.07,69.72 45.72,69.72 45.23,69.24 45.15,69.21 45.07,69.26 44.43,69.28 44.68,68.69 44.73,68.68 44.73,67.55 44.02,67.55 43.41,68.16 43.39,68.27 43.49,68.33 43.51,68.33 43.54,68.37 43.56,68.37 44.27,68.74 43.56,69.12 43.23,69.12 43.19,69.09 42.85,69.07 42.71,68.99 42.64,68.96 42.57,68.99 41.74,69.82
DGND on TOP (solid shape): outline of 139 points within 84.89,67.02 90.45,76.81
DGND on TOP (solid shape): 85.11,66.58 85.17,66.68 85.28,66.65 86.63,65.3 87.36,65.3 87.36,64.6 89.27,64.6 89.27,65.95 89.43,65.95 89.73,65.65 89.73,64.69 90.83,63.59 90.85,63.48 90.76,63.42 90.01,63.42 88.82,62.24 88.82,61.62 88.82,61.57 88.83,61.53 88.83,61.4 88.8,61.36 88.74,61.37 88.58,61.53 88.58,61.88 88.58,61.93 88.57,61.98 88.57,62.28 87.84,62.28 87.7,62.28 87.72,62.4 87.72,62.46 87.72,62.99 87.26,63.45 86.81,62.99 86.81,62.46 86.83,62.32 86.89,62.19 86.89,61.99 86.88,61.9 86.89,61.81 86.89,61.52 87.63,61.52 87.63,61.52 87.83,61.52 87.83,61.22 88.32,60.72 88.32,60.29 88.23,60.29 88.13,60.39 88.13,60.41 87.74,60.81 87.37,60.39 87.37,60.08 87.87,59.58 87.87,59.47 87.73,59.47 87.72,59.47 87.64,59.5 87.55,59.51 86.89,59.51 86.41,59.99 85.66,59.99 85.57,60.04 85.57,60.14 85.61,60.4 85.47,60.62 85.47,60.62 85.11,60.99
DGND on TOP (solid shape): 83.8,105.7 83.84,105.61 83.84,102.2 86.41,99.64 86.41,99.51 86.34,99.41 86.23,99.44 83.37,102.29 83.37,102.3 82.81,102.33 82.84,101.76 85.9,98.7 85.9,98.32 84.55,98.32 84.54,98.32 84.43,98.3 84.37,98.39 84.37,98.45 82.34,98.45 82.34,96.14 82.36,96.11 82.36,94.53 82.48,94.53 82.48,92.52 82.77,92.23 83.41,92.23 83.41,91.21 83.89,90.73 85.21,90.73 85.68,91.2 85.96,90.92 85.99,90.83 85.94,90.76 85.79,90.6 85.75,90.38 85.75,90.23 85.5,89.99 85.5,89.62 85.41,89.62 85.36,89.63 85.32,89.63 84.35,89.63 83.84,90.15 82.93,90.15 82.84,90.2 82.84,90.29 82.87,90.52 82.76,90.72 82.63,90.86 82.63,90.88 82.57,91.1 82.42,91.28 82.38,91.35 82.4,91.42 82.43,91.84 82.07,92.04 81.99,92.06 81.96,92.14 81.96,96.44 81.35,97.06 81.35,98.58 81.49,98.58 81.49,100.52 81.35,100.52 81.35,101.19 83.45,103.3 83.45,105.56 83.48,105.63 83.55,105.66 83.63,105.68 83.7,105.7
DGND on TOP (solid shape): outline of 81 points within 91.23,126.68 97.14,130.09
DGND on TOP (solid shape): 131.39,138.13 131.45,138.23 131.56,138.2 132.79,136.98 132.79,129.79 132.79,129.78 133.16,129.36 133.54,129.78 133.54,129.79 133.54,136.7 133.61,136.79 133.72,136.77 133.88,136.61 133.88,128.29 133.82,128.19 133.7,128.21 130.68,131.24 129.75,131.24 128.16,132.83 128.16,133.56 128.22,133.65 128.33,133.63 128.37,133.6 128.69,133.6 128.69,133.57 131.39,133.57 131.39,134.4 131.68,134.4 131.74,134.34 131.74,133.22 131.74,133.21 132.12,132.79 132.5,133.21 132.5,133.22 132.5,134.65 131.99,135.16 131.39,135.16 131.39,135.18 128.69,135.18 128.69,134.47 128.66,134.42 128.61,134.43 128.59,134.45 128.46,134.62 128.26,134.7 128.19,134.73 128.16,134.8 128.16,135.62 128.2,135.69 128.28,135.72 128.48,135.74 128.64,135.85 128.75,135.97 131.39,135.97 131.39,136.65 131.43,136.73 131.52,136.75 131.98,136.93 131.88,137.41 131.73,137.56 131.39,137.56
DGND on TOP (solid shape): outline of 188 points within 59.25,33.22 65.93,47.09
DGND on TOP (solid shape): outline of 166 points within 55.57,107.81 71.27,129.9
DGND on TOP (solid shape): outline of 457 points within 57.52,63.74 70.38,77.93
DGND on BOTTOM (solid shape): 94.59,151.67 91.78,151.67 91.78,154.47 94.59,154.47
DGND on BOTTOM (solid shape): 98.67,78.29 96.49,78.29 96.49,85.97 98.67,85.97
DGND on BOTTOM (solid shape): 111.99,151.67 109.18,151.67 109.18,154.47 111.99,154.47
DGND on BOTTOM (solid shape): 45.94,34.49 46.42,34.01 46.42,33.78 45.05,33.78 44.9,33.93 44.9,34.8 45.03,34.92 45.94,34.92
DGND on BOTTOM (solid shape): 49.47,80.11 49.57,80.01 49.57,79.41 49.53,79.41 49.53,78.94 49.04,78.94 48.61,79.37 48.61,82.26 49.47,82.26
DGND on BOTTOM (solid shape): 47.27,86.24 47.29,86.13 47.2,86.07 45,86.07 43.68,84.75 43.63,84.8 43.63,85.03 45.07,86.46 47.04,86.46
DGND on BOTTOM (solid shape): 110.18,121.73 109.54,121.09 109.54,120.97 107.7,120.97 107.7,121.32 107.92,121.54 108.57,121.54 108.88,121.85 109.19,121.54 109.59,121.54 109.74,121.57 109.86,121.65 110.06,121.85
DGND on BOTTOM (solid shape): 73.75,56.5 73.74,56.44 73.73,56.38 73.73,55.57 73.73,55.43 72.8,55.43 72.8,55.35 71.4,55.35 71.02,55.35 71.02,56 69.25,56 68.88,56.37 68.88,56.62 73.75,56.62
DGND on BOTTOM (solid shape): 56.6,97.22 56.59,97.2 56.53,97.1 56.51,96.98 56.51,96.52 56.98,96.04 56.92,95.98 56.87,95.95 56.83,95.91 56.65,95.73 56.65,95.71 56.45,95.51 56.07,95.89 56.07,96.87 56.51,97.31 56.6,97.31
DGND on BOTTOM (solid shape): 46.25,120.95 46.27,120.84 46.18,120.77 46.12,120.77 43.73,123.17 43.7,123.28 43.8,123.34 43.85,123.34
DGND on BOTTOM (solid shape): 49.81,104.45 49.91,104.38 49.88,104.27 47.83,102.22 46.94,102.22 46.85,102.28 46.87,102.39 48.93,104.45
DGND on BOTTOM (solid shape): 85.61,55.66 85.63,55.55 85.54,55.48 85.43,55.48 81.27,59.64 81.25,59.75 81.34,59.82 81.45,59.82
DGND on BOTTOM (solid shape): 107.59,56.67 107.61,56.56 107.52,56.5 107.34,56.5 106.24,57.6 106.22,57.71 106.31,57.77 106.49,57.77
DGND on BOTTOM (solid shape): 37.19,89 37.28,88.94 37.26,88.83 35.75,87.32 35.64,87.3 35.58,87.39 35.58,87.87 35.77,87.87 36.91,89
DGND on BOTTOM (solid shape): 16.59,134.93 16.7,134.95 16.76,134.86 16.76,134.83 15.97,134.04 15.97,129 15.94,128.96 15.89,128.96 15.88,128.98 14.98,129.87 14.98,133.32
DGND on BOTTOM (solid shape): 68.53,113.43 68.55,113.32 68.45,113.26 68.07,113.26 67.08,114.25 58.52,114.25 58.25,114.51 58.23,114.62 58.33,114.68 67.27,114.68
DGND on BOTTOM (solid shape): 68.96,128.55 69.06,128.49 69.03,128.38 67.93,127.28 65.15,127.28 65.13,127.29 65.11,127.4 65.2,127.47 67.53,127.47 68.62,128.55
DGND on BOTTOM (solid shape): 99.27,120.58 99.4,120.5 99.56,120.48 99.83,120.48 99.86,120.44 99.86,119.07 99.83,119.03 99.04,119.03 99.04,120.46 99.04,120.48 99.06,120.56 99.14,120.59 99.25,120.59
DGND on BOTTOM (solid shape): 23.31,130.4 23.34,130.29 23.24,130.22 19.76,130.22 19.62,130.36 19.59,130.44 19.63,130.52 19.68,130.55 19.72,130.6 20.49,131.37 22.34,131.37
DGND on BOTTOM (solid shape): 74.67,73.44 74.73,73.53 74.84,73.51 76.92,71.43 76.94,71.32 76.85,71.26 74.06,71.26 73.54,71.78 73.54,72.54 74.41,72.54 74.67,72.8
DGND on BOTTOM (solid shape): 24.4,76.63 24.4,75.79 24.51,75.69 24.53,75.58 24.44,75.51 23.48,75.51 23.38,75.58 23.41,75.69 23.44,75.72 23.44,77.09 23.49,77.14 23.89,77.14
DGND on BOTTOM (solid shape): 48.49,125.91 52.19,125.91 52.39,125.7 52.42,125.59 52.32,125.53 51.33,125.53 51.33,123.52 49.12,123.52 46.67,125.97 46.65,126.08 46.74,126.14 48.25,126.14
DGND on BOTTOM (solid shape): 55.72,123.12 55.78,123.22 55.89,123.2 57.95,121.14 59.45,121.14 60.17,120.41 60.19,120.3 60.1,120.24 59.28,120.24 58.8,120.72 57.93,120.72 55.72,122.94
DGND on BOTTOM (solid shape): 61.53,88.1 61.54,88.04 61.49,88.01 61.42,88.01 61.42,88.01 60.69,88.01 60.69,88.01 59.97,88.01 59.92,88.06 58.73,88.06 58.64,88.12 58.66,88.23 58.98,88.55 61.08,88.55
DGND on BOTTOM (solid shape): 130.25,51.02 130.23,50.99 130.19,50.89 130.16,50.79 130.09,50.72 129.99,50.75 129.07,51.67 120.48,51.67 120.41,51.74 120.39,51.85 120.48,51.91 129.35,51.91
DGND on BOTTOM (solid shape): 25.22,129.36 25.22,128.96 25.5,128.67 25.53,128.56 25.43,128.5 25.32,128.5 24.57,129.25 24.12,129.25 24.12,129.53 24.1,129.68 24.01,129.8 23.98,129.84 23.97,129.89 24.02,129.92 24.65,129.92
DGND on BOTTOM (solid shape): 55.94,39.27 56.27,38.94 58.51,38.94 58.58,38.87 58.59,38.82 58.54,38.79 56.2,38.79 55.94,39.05 55.89,39.1 55.83,39.15 55.77,39.22 55.8,39.31 55.85,39.36
DGND on BOTTOM (solid shape): 90.49,46.08 90.51,45.97 90.42,45.9 84.86,45.9 84.07,45.12 83.23,45.12 83.16,45.15 83.13,45.22 83.11,45.36 83.03,45.48 83,45.56 83.03,45.62 83.82,46.41 90.15,46.41
DGND on BOTTOM (solid shape): 105.41,112.4 105.45,112.37 105.44,112.31 105.37,112.24 105.37,111.94 104.9,111.94 104.9,111.12 104.88,111.05 104.87,110.99 104.87,110 104.81,109.9 104.7,109.92 104.6,110.02 104.61,110.03 104.61,110.86 104.63,110.93 104.63,110.99 104.63,112.15 104.87,112.4
DGND on BOTTOM (solid shape): 116.07,61.11 116.09,61 116,60.94 113.07,60.94 113,60.97 112.97,61.04 112.93,61.2 112.83,61.33 112.83,61.33 112.41,61.75 112.39,61.87 112.48,61.93 115.25,61.93
DGND on BOTTOM (solid shape): 79.69,85.09 79.77,85.05 79.78,84.96 79.82,84.68 80.06,84.53 80.1,84.52 80.1,84.25 79.36,84.25 79.12,84.49 79.05,84.58 78.96,84.65 78.71,84.9 78.53,84.72 78.47,84.72 78.29,84.55 78.17,84.68 78.58,85.09
DGND on BOTTOM (solid shape): 73.91,82.38 74.23,82.7 74.29,82.68 74.71,82.68 74.71,81.89 74.68,81.84 74.62,81.85 74.59,81.88 73.95,81.24 73.92,81.25 73.85,81.29 73.78,81.3 73.7,81.37 73.73,81.48 73.93,81.68 73.3,82.3 73.31,82.33 73.33,82.43 73.32,82.53 73.32,82.56 73.37,82.61 73.36,82.62 73.51,82.78
DGND on BOTTOM (solid shape): 14.83,71.63 14.94,71.66 15,71.56 15,69.47 15.11,69.37 15.11,68.38 15.31,68.17 14.72,67.59 14.72,64.77 16.05,63.45 16.92,63.45 17.01,63.39 16.99,63.28 16.86,63.14 16.86,62.42 16.8,62.33 16.68,62.35 14.27,64.77 14.27,71.07
DGND on BOTTOM (solid shape): 105.71,123.16 105.71,121.16 105.64,121.09 105.64,120.97 105.59,120.97 105.59,119.42 105.54,119.34 105.45,119.33 105.37,119.36 105.29,119.36 104.89,119.36 104.81,119.29 104.7,119.26 104.64,119.36 104.64,122.91 104.22,123.33 104.2,123.44 104.29,123.51 105.36,123.51
DGND on BOTTOM (solid shape): 40.58,41.91 40.65,41.88 40.69,41.81 40.69,41.5 40.58,41.5 40.58,40.41 40.43,40.25 40.43,39.16 40.43,39.1 40.45,39.03 40.45,38.35 40.36,38.26 40.31,38.25 40.28,38.29 40.28,40.18 39.87,40.59 39.87,41.48 39.64,41.71 39.56,41.71 39.46,41.77 39.49,41.88 39.52,41.91
DGND on BOTTOM (solid shape): 14.98,149.78 14.98,149.19 15.37,148.8 15.77,148.8 15.92,148.82 16.04,148.91 16.21,149.08 16.29,149.2 16.32,149.35 16.32,149.74 17.27,149.74 17.37,149.67 17.35,149.56 15.87,148.09 15.87,137.15 16.45,136.57 16.47,136.46 16.38,136.4 15.69,136.4 13.3,138.79 13.3,149.83 13.66,150.19 14.57,150.19
DGND on BOTTOM (solid shape): 126.61,33.48 124.79,31.66 124.68,31.63 124.62,31.73 124.62,35.45 124.68,35.54 124.79,35.52 125.12,35.19 125.77,35.19 125.77,35.83 125.57,36.03 125.57,36.82 126.61,36.82
DGND on BOTTOM (solid shape): 85.61,63.18 86.79,63.18 86.87,63.15 86.89,63.06 86.89,62.94 86.92,62.83 86.91,62.73 86.83,62.68 79.42,62.68 78.81,63.3 78.81,63.45 78.84,63.53 78.92,63.56 78.99,63.55 80.77,63.55 81.72,64.5 81.82,64.64 81.86,64.8 81.89,64.87 81.96,64.9 83.9,64.9
DGND on BOTTOM (solid shape): 134.8,52.32 134.87,52.22 134.87,49.71 134.2,49.04 132.72,49.04 132.63,49.11 132.65,49.22 133.08,49.64 133.08,51.98 133.13,52.06 133.23,52.06 134,51.91 134.69,52.29
DGND on BOTTOM (solid shape): 109.65,112.78 109.71,112.87 109.82,112.85 110.41,112.27 110.44,112.27 110.48,112.22 110.48,112.19 110.56,112.11 110.58,112 110.49,111.94 110.4,111.94 110.4,111.12 110.38,111.05 110.37,110.99 110.37,109.48 110.39,109.47 110.41,109.36 110.31,109.29 109.75,109.29 109.63,109.41 109.63,110.03 110.11,110.03 110.11,110.86 110.13,110.93 110.13,110.99 110.13,112.22 109.65,112.69
DGND on BOTTOM (solid shape): 66.9,44.65 66.9,43.96 67.18,43.68 67.2,43.57 67.11,43.51 66.9,43.51 66.57,43.18 66.57,43.07 66.5,42.98 66.39,43 65.29,44.1 65.29,44.11 65.05,44.4 64.69,44.35 63.43,44.35 63.34,44.41 63.36,44.52 63.83,44.99 66.56,44.99
DGND on BOTTOM (solid shape): 125.85,68.68 125.92,68.65 125.95,68.59 125.99,68.43 126.1,68.31 126.3,68.1 126.3,65.3 126.24,65.21 126.13,65.23 125.84,65.33 125.58,65.18 125.47,65.08 119.63,65.08 119.02,65.68 115.64,65.68 115.57,65.71 115.54,65.78 115.54,65.86 121.97,65.86 124.78,68.68
DGND on BOTTOM (solid shape): 29.04,95.99 29.07,95.92 29.03,95.85 28.94,95.73 28.9,95.59 28.89,95.55 28.29,95.55 28.29,95.25 28.28,95.21 28.28,95.17 28.28,95.07 28.22,94.98 28.11,95 27.78,95.32 27.33,95.32 27.26,95.39 27.26,96.58 26.18,96.58 26.1,96.62 26.08,96.69 26.08,96.75 26.07,96.81 26.09,96.89 26.17,96.93 28.1,96.93
DGND on BOTTOM (solid shape): 35.31,87.12 35.4,87.06 35.38,86.95 35.17,86.75 35.17,86.13 35.08,86.11 34.79,86.11 34.79,85.38 34.79,85.38 34.79,84.56 33.7,84.56 33.61,84.62 33.63,84.73 33.72,84.82 33.72,85.14 33.75,85.24 33.77,85.35 33.77,86.14 33.56,86.35 33.47,86.42 33.36,86.47 33.29,86.54 33.32,86.64 33.42,86.74 33.42,87.12
DGND on BOTTOM (solid shape): 58.66,128.26 58.73,128.35 58.84,128.33 60.18,126.99 62.73,126.99 62.81,126.95 62.82,126.86 62.82,126.63 62.95,126.45 63.33,126.07 63.83,126.07 63.91,126.03 63.93,125.96 63.93,125.91 63.94,125.87 63.92,125.79 63.84,125.75 62.81,125.75 62.23,126.34 61.28,126.34 60.72,125.77 60.69,125.75 60.62,125.72 60.55,125.75 58.66,127.64
DGND on BOTTOM (solid shape): 54.74,98.62 55,98.55 55.27,98.62 56.02,98.62 56.1,98.55 56.13,98.55 56.44,98.24 56.46,98.13 56.36,98.07 56.2,98.07 55.29,97.16 54.74,97.16 54.74,96.38 54.48,96.38 54.42,96.32 54.37,96.31 54.34,96.36 54.34,97.51 54.3,97.51 54.3,97.59 53.91,97.98 53.91,97.98 53.61,98.12 53.31,97.97 53.25,97.95 53.22,98 53.22,98.3 53.55,98.62
DGND on BOTTOM (solid shape): 102.56,57.07 102.64,57.04 102.66,56.96 103.04,56.51 103.42,56.96 103.44,57.04 103.52,57.07 105.2,57.07 106.43,55.85 106.45,55.74 106.36,55.67 105.59,55.67 105.07,56.2 101.64,56.2 101.45,56 101.12,56 101.03,56.07 101.05,56.18 101.95,57.07
DGND on BOTTOM (solid shape): 53.03,80.7 53.06,80.66 53.06,79.86 54.02,79.86 54.19,79.69 54.53,79.69 54.53,79.59 54.67,79.59 54.67,79.24 54.16,78.74 54.11,78.76 53.14,78.76 53.14,77.72 53.74,77.72 53.83,77.66 53.81,77.55 53.64,77.37 52.18,77.37 52.1,77.41 52.03,77.93 51.66,78.12 51.43,78.12 51.43,78.76 51.39,78.76 51.39,79.01 51.36,79.03 51.34,79.14 51.44,79.21 51.98,79.21 51.98,80.37 52.11,80.37 52.11,82.22 53.03,82.22
DGND on BOTTOM (solid shape): 111.87,98.75 110.43,97.3 110.09,97.3 110,97.35 110,97.45 109.66,98.01 109.32,97.45 109.31,97.35 109.23,97.3 98.02,97.3 94.86,100.46 94.86,101.92 95.2,101.92 95.34,101.95 95.46,102.03 95.53,102.1 95.64,102.12 95.7,102.03 95.7,100.81 97.91,98.61 110.79,98.61 111.63,99.44 111.63,102.53 111.87,102.53
DGND on BOTTOM (solid shape): 19.91,61.66 20,61.63 20.06,61.57 20.06,60.35 21.38,59.03 21.38,57.9 21.32,57.81 21.21,57.83 19.54,59.49 19.57,59.53 19.54,60.04 19.03,60.07 19,60.04 17.72,61.32 17.69,61.43 17.79,61.49 18.97,61.49 19.04,61.56 19.12,61.59 19.19,61.55 19.53,61.39 19.84,61.6
DGND on BOTTOM (solid shape): 95.99,74.96 96.1,74.98 96.16,74.89 96.16,74.48 94.99,73.31 94.99,71.4 98.45,67.94 98.47,67.83 98.38,67.76 97.51,67.76 96.28,68.99 96.25,69.07 96.29,69.14 96.32,69.71 95.75,69.68 95.68,69.64 95.6,69.67 94.68,70.59 94.68,73.66 95.23,74.21 95.26,74.2 95.61,74.3 95.72,74.66 95.71,74.68
DGND on BOTTOM (solid shape): 60.81,84.85 60.95,84.85 60.95,84.68 60.81,84.68 60.81,83.29 61.86,83.29 61.93,83.35 62.03,83.33 62.45,82.91 62.87,82.91 62.96,82.85 62.94,82.73 62.88,82.68 60.78,82.68 60.77,82.71 60.19,82.9 60.15,82.3 60.18,82.23 60.15,82.16 59.99,81.99 59.35,81.99 59.25,82.05 59.28,82.16 59.47,82.36 59.47,84.72 59.44,84.76 59.43,84.82 59.47,84.85 60.37,84.85 60.37,85.96 60.81,85.96
DGND on BOTTOM (solid shape): 53.63,61.14 53.69,61.15 53.72,61.11 53.72,61.07 54.12,60.67 54.14,60.61 54.09,60.58 54.02,60.58 53.18,59.74 53.18,58.61 53.12,58.52 53.01,58.54 52.87,58.67 51.93,58.67 51.01,59.59 51.01,59.6 50.83,59.78 50.58,59.81 50.56,59.8 50.5,59.86 50.59,59.95 51.38,59.95 51.45,59.92 51.48,59.84 51.86,59.44 52.24,59.84 52.27,59.92 52.34,59.95 52.44,59.95
DGND on BOTTOM (solid shape): 55.29,38.51 55.32,38.55 55.37,38.54 55.41,38.51 55.89,38.03 58.71,38.03 58.81,37.97 58.78,37.86 58.32,37.39 57.19,37.39 57.18,37.39 56.76,37.01 57.18,36.63 57.19,36.63 58.63,36.63 60.37,38.37 60.48,38.4 60.55,38.3 60.55,37.97 58.75,36.18 56.94,36.18 54.98,34.22 54.88,34.19 54.81,34.26 54.66,34.46 54.41,34.52 54.25,34.52 54.23,34.54 53.62,34.54 53.1,35.05 53.1,35.61 54.53,35.61 55.29,36.37
DGND on BOTTOM (solid shape): 70.08,81.46 70.18,81.32 70.32,81.23 70.32,81.06 71.1,81.06 71.1,81.03 72.04,81.03 72.04,81.18 72.84,81.18 72.84,81.2 72.9,81.2 73.04,81.2 73.14,81.1 73.11,81.04 73.11,81.04 73.11,80.55 73.07,80.47 72.99,80.45 72.94,80.46 72.9,80.46 72.86,80.48 72.85,80.51 72.85,80.66 71.91,80.66 71.91,80.48 71.79,80.36 71.71,80.33 71.64,80.36 71.48,80.47 71.3,80.51 70.61,80.51 70.16,80.06 70.07,80.06 70.06,80.1 70.03,80.22 69.96,80.32 69.89,80.38 69.86,80.47 70.07,80.82 69.96,81.12 69.8,81.29 69.78,81.4 69.87,81.46
DGND on BOTTOM (solid shape): 33.95,25.04 34.02,25.02 34.05,24.94 34.05,24.19 34.54,23.71 34.54,23.46 34.53,23.38 34.54,23.29 34.54,22.99 35.27,22.99 35.37,22.89 35.39,22.84 35.34,22.81 35.14,22.81 34.51,22.18 34.51,21.13 34.51,21.12 34.89,20.7 35.27,21.12 35.27,21.13 35.27,21.87 35.36,21.95 35.42,21.9 35.41,21.87 35.42,21.63 35.57,21.45 35.61,21.37 35.58,21.29 35.53,21.24 35.53,20.32 35.53,20.28 35.5,20.21 35.43,20.19 35.16,20.19 35.12,20.18 35.07,20.17 34.69,20.17 34.64,20.18 34.6,20.19 34.04,20.19 33.8,20.43 33.8,24.94 33.83,25.02 33.9,25.05
DGND on BOTTOM (solid shape): 23.39,82.45 23.42,82.36 23.36,82.29 23.19,81.84 23.59,81.57 23.75,81.57 26.34,78.98 26.37,78.89 26.32,78.82 26.14,78.59 26.17,78.31 26.17,78.21 26.08,78.16 25.57,78.16 22.4,81.32 22.38,81.42 22.45,81.49 22.58,82.19 22,81.78 21.98,81.7 21.9,81.66 20.01,81.66 18.09,83.58 18.07,83.69 18.16,83.75 22.08,83.75
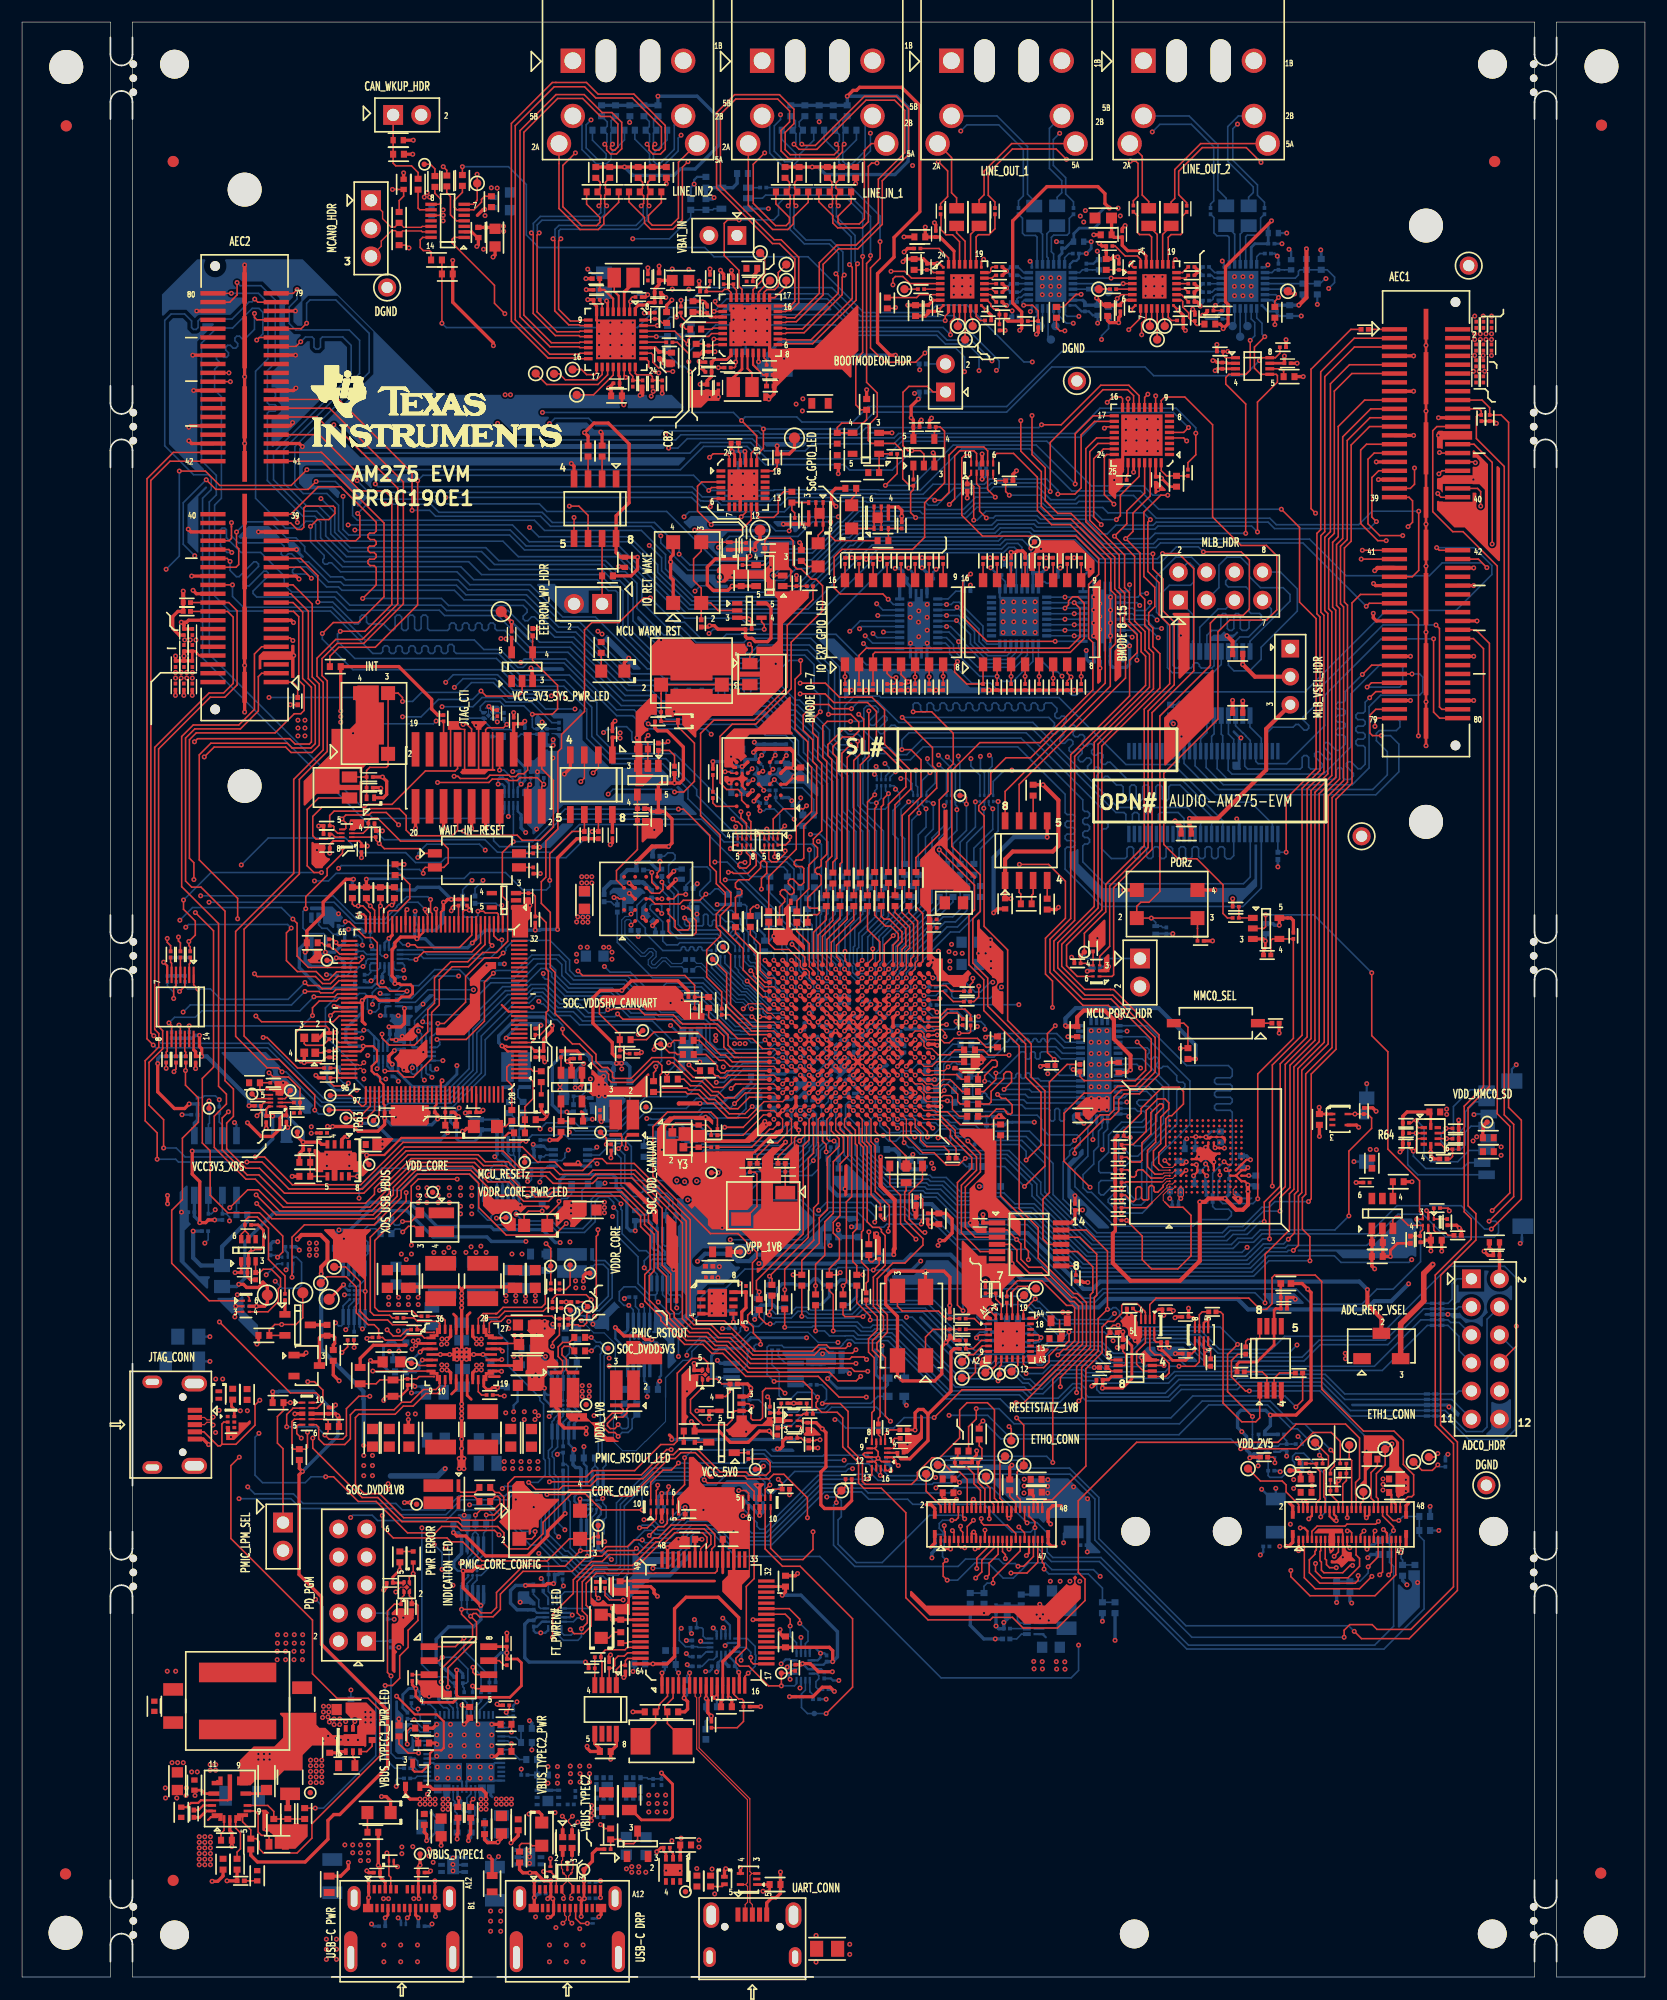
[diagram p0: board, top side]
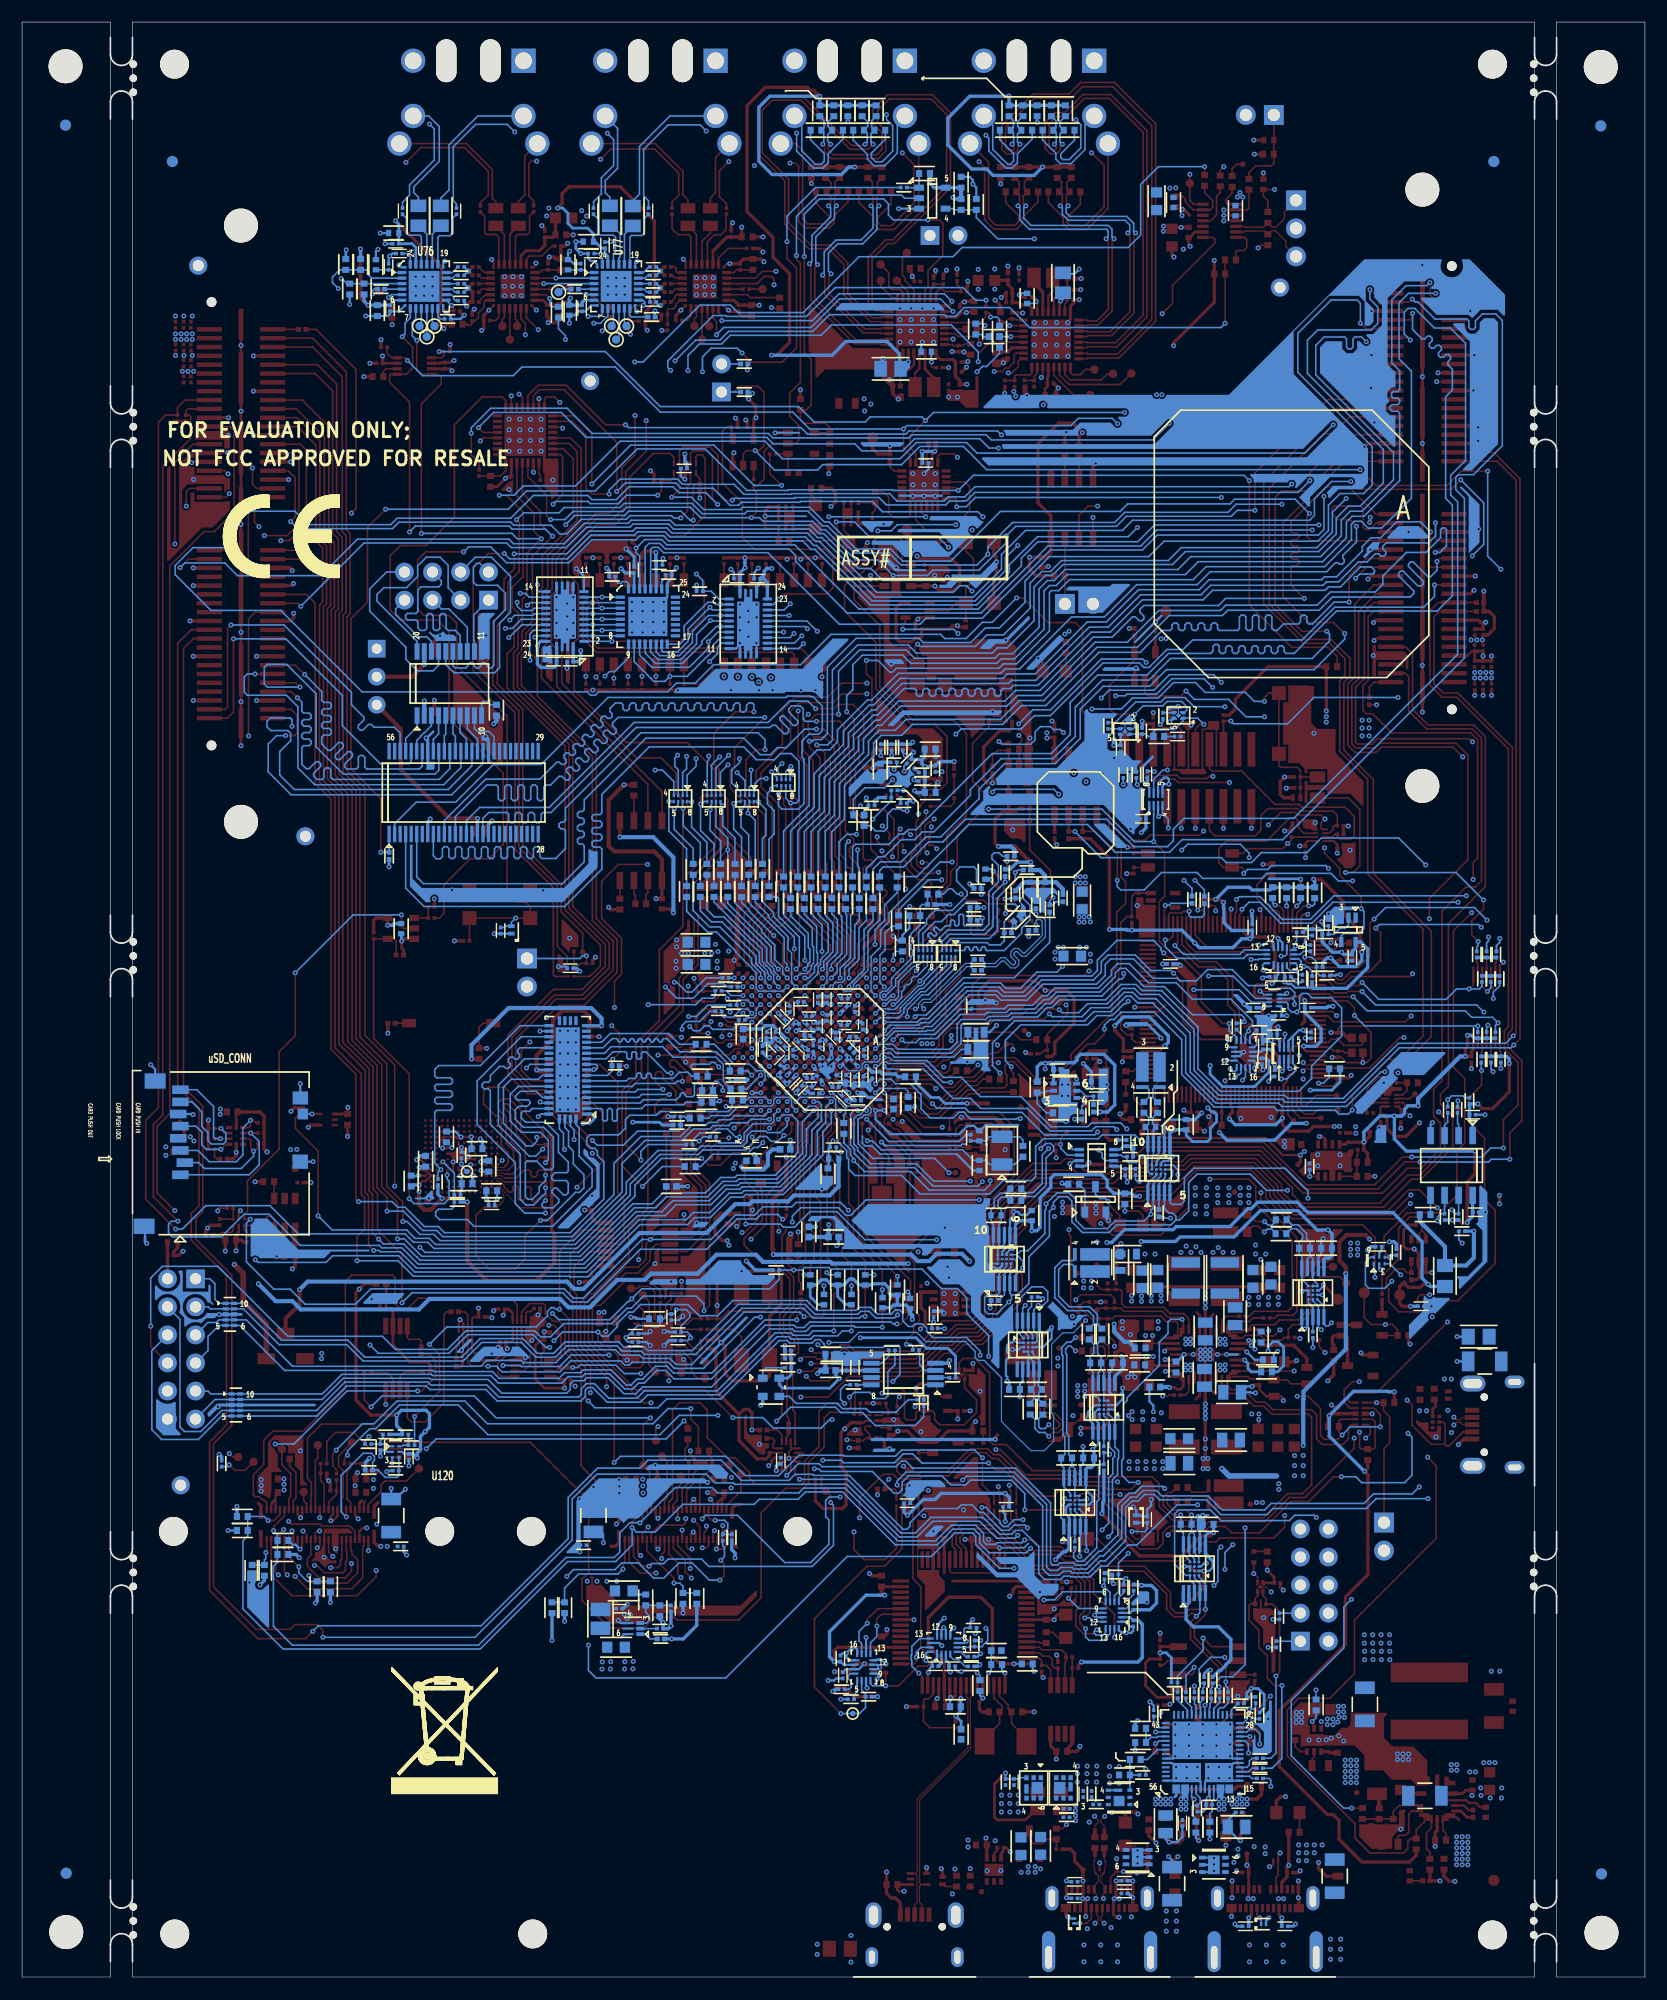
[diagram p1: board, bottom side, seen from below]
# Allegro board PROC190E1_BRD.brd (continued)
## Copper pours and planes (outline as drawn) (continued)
DGND on BOTTOM (solid shape): 90.29,45.15 90.36,45.12 90.4,45.05 90.43,44.92 90.51,44.8 90.52,44.77 90.51,44.73 90.39,44.48 90.48,44.21 90.5,44.14 90.48,44.08 90.74,43.43 91.04,44.06 91.02,44.13 91.05,44.19 91.15,44.46 91.04,44.73 91.03,44.76 91.04,44.8 91.12,44.91 91.16,45.05 91.19,45.12 91.26,45.15 94.77,45.15 96.79,43.12 96.79,39.4 97.66,38.54 97.68,38.42 97.59,38.36 96.4,38.36 96.4,41.56 92.98,41.56 92.63,41.21 92.56,41.12 92.46,41.15 92.09,41.52 91.17,41.52 88,44.69 84.96,44.69 84.87,44.75 84.89,44.86 85.17,45.15
DGND on BOTTOM (solid shape): 64.66,132.29 64.73,132.26 64.76,132.19 64.78,132.1 64.81,132.02 64.81,131.92 64.72,131.87 62.47,131.87 62.47,131.87 62.04,131.5 62.47,131.12 62.47,131.12 67.55,131.12 67.69,130.98 67.71,130.87 67.62,130.81 63.92,130.81 62.85,129.74 62.82,129.17 63.38,129.2 64.23,130.05 69.95,130.05 70.03,130.01 70.05,129.93 70.05,129.86 70.05,129.79 70.03,129.7 69.96,129.66 68.16,129.66 67.07,128.57 66.41,128.57 66.34,128.6 66.31,128.67 65.93,129.03 65.55,128.67 65.52,128.6 65.45,128.57 63.04,128.57 61.09,130.52 61.06,130.61 61.11,130.68 61.2,131.28 60.59,131.2 60.52,131.15 60.43,131.18 59.95,131.66 59.93,131.76 60.01,131.83 60.15,131.88 60.26,131.97 60.58,132.29
DGND on BOTTOM (solid shape): 66.59,109.62 66.73,109.48 66.73,109.46 66.75,109.44 66.75,109.31 66.74,109.3 66.91,108.84 67.4,108.93 67.5,109.04 67.5,109.08 67.57,109.17 67.68,109.15 67.72,109.11 68.17,109 68.39,109.4 68.41,109.49 68.49,109.52 68.74,109.52 68.74,109.37 69.45,109.37 69.48,109.34 69.48,109.33 69.9,109 70.35,109.3 70.42,109.36 70.52,109.33 72.13,107.72 72.13,106.98 72.07,106.88 71.96,106.9 70.81,108.05 69.03,108.05 68.44,108.64 67.87,108.68 67.9,108.11 68.03,107.98 68.05,107.87 67.96,107.81 67.79,107.81 67.75,107.82 67.71,107.82 67.22,107.82 67.22,107.82 67.05,107.8 66.9,107.71 66.83,107.68 66.76,107.71 66.42,108.05 66.48,108.11 66.56,108.22 66.59,108.36 66.5,108.66 66.21,108.79 66.18,108.8 66.16,108.84 66.16,108.9 66.37,109.1 66.51,109.33 66.46,109.6 66.45,109.61 66.45,109.68 66.54,109.68
DGND on BOTTOM (solid shape): 132.75,63.96 132.84,63.91 132.83,63.81 133.21,62.24 134.78,62.57 134.9,62.61 134.97,62.51 134.97,61.38 134.9,61.28 134.78,61.32 133.26,61.68 132.77,60.2 132.79,60.17 132.32,59.7 132.32,58.98 132.25,58.88 132.14,58.91 131.52,59.27 130.81,59.19 130.78,59.17 130.32,59.64 129.56,59.64 129.33,59.87 127.12,59.87 127.02,59.94 127.05,60.05 127.12,60.12 130.11,60.12 130.12,60.12 130.21,60.15 130.28,60.1 132.44,60.78 130.19,61.05 129.98,61.05 129.8,60.87 129.7,60.87 129.66,60.9 129.67,60.96 129.91,61.2 129.91,62.61 129.96,62.65 130.07,62.67 130.13,62.58 130.13,62.06 132.44,62.06 132.44,63.96
DGND on BOTTOM (solid shape): outline of 292 points within 72.14,115.69 87.96,121.19
DGND on BOTTOM (solid shape): outline of 130 points within 57.09,55.1 75.81,70.53
DGND on BOTTOM (solid shape): outline of 380 points within 45.28,103.45 61.11,114.8
DGND on BOTTOM (solid shape): outline of 233 points within 12.67,133.12 60.07,155.52
DGND on L03_SIG1 (solid shape): 42.93,19.97 42.94,19.91 42.89,19.88 36.8,19.88 36.7,19.98 36.69,20.04 36.74,20.07 42.82,20.07
DGND on L03_SIG1 (solid shape): 21.92,68.42 22.03,68.44 22.09,68.35 22.09,68.11 21.76,67.78 21.76,67.7 21.68,67.63 21.68,65.87 21.76,65.8 21.76,65.04 21.04,65.04 20.76,65.32 20.76,67.27
DGND on L03_SIG1 (solid shape): 11.02,59.39 11.08,59.48 11.19,59.46 12.38,58.27 17.2,58.27 18.81,56.66 18.81,53.63 18.07,52.89 17.78,52.89 17.75,52.96 17.77,52.97 17.77,54.53 16.71,55.58 11.02,55.58
DGND on L03_SIG1 (solid shape): 46.36,79.49 46.42,79.58 46.53,79.56 47.84,78.25 47.86,78.14 47.77,78.08 47.51,78.08 46.36,79.23
DGND on L03_SIG1 (solid shape): 69.47,50.55 69.5,50.6 69.56,50.59 69.59,50.56 69.59,43.07 69.07,42.55 68.96,42.53 68.9,42.62 68.9,43.31 69.47,43.89
DGND on L03_SIG1 (solid shape): 78.03,57.55 78.14,57.57 78.2,57.48 78.2,57.35 77.11,56.26 76.98,56.26 76.89,56.32 76.91,56.43
DGND on L03_SIG1 (solid shape): 81.99,64.32 82.1,64.34 82.17,64.25 82.17,64.14 81.09,63.06 80.97,63.03 80.91,63.13 80.91,63.24
DGND on L03_SIG1 (solid shape): 86.03,69.03 86.14,69.06 86.21,68.96 86.21,66.01 85.99,65.8 85.88,65.77 85.81,65.87 85.81,68.82
DGND on L03_SIG1 (solid shape): 119.44,76.11 119.47,76 119.37,75.94 115.33,75.94 115.03,76.23 115.01,76.35 115.1,76.41 119.15,76.41
DGND on L03_SIG1 (solid shape): 36.08,53.61 36.08,52.08 36.02,51.99 35.9,52.01 34.73,53.18 34.73,53.76 34.57,53.93 34.54,54.04 34.64,54.11 35.58,54.11
DGND on L03_SIG1 (solid shape): 52.54,81.59 52.6,81.68 52.71,81.66 52.88,81.5 52.88,78.57 52.81,78.47 52.7,78.49 52.16,79.04 52.16,80.83 52.54,81.21
DGND on L03_SIG1 (solid shape): 63.01,64.82 63.07,64.91 63.18,64.89 65.81,62.26 65.81,62.13 65.75,62.03 65.64,62.06 63.56,64.13 63.24,64.13 63.01,64.36
DGND on L03_SIG1 (solid shape): 90.27,60.98 90.38,61 90.45,60.91 90.45,56.13 90.17,55.85 90.17,54.31 90.85,53.63 90.85,53.6 90.82,53.55 90.77,53.56 89.8,54.53 89.8,60.51
DGND on L03_SIG1 (solid shape): 120.1,41.67 120.12,41.56 120.02,41.5 120,41.5 118.91,42.59 118.43,42.59 118.43,42.99 118.41,43.1 118.5,43.16 118.61,43.16
DGND on L03_SIG1 (solid shape): 64.95,40.93 65.93,39.94 66.73,39.94 66.82,39.88 66.8,39.77 62.06,35.03 61.95,35.01 61.89,35.1 61.89,38.45 64.79,41.35 64.95,41.35
DGND on L03_SIG1 (solid shape): 90.07,38.95 90.07,38.23 89.22,38.23 89.21,38.24 88.95,38.24 88.75,38.08 88.67,38.03 88.59,38.06 88.53,38.12 89.51,39.1 89.92,39.1
DGND on L03_SIG1 (solid shape): 32.98,63.22 33.04,63.32 33.16,63.29 33.3,63.15 33.3,60.88 33.22,60.8 33.12,60.8 30.6,58.28 30.49,58.26 30.43,58.35 30.43,58.49 32.98,61.04
DGND on L03_SIG1 (solid shape): 48.57,19.37 48.57,17.35 47.68,16.46 47.57,16.44 47.51,16.53 47.51,18.99 45.93,20.57 44.77,20.57 44.75,20.6 44.72,20.71 44.82,20.77 47.17,20.77
DGND on L03_SIG1 (solid shape): 115.25,47.36 115.28,47.29 115.26,47.22 115.17,47.05 115.17,46.86 115.15,46.77 115.07,46.73 114.85,46.73 113.64,47.94 113.62,47.96 113.65,48.05 114.56,48.05
DGND on L03_SIG1 (solid shape): 115.73,39.32 115.99,39.32 115.99,38.37 115.59,37.97 115.59,37.92 115.53,37.83 115.42,37.85 115.28,37.99 115.28,39.27 115.29,39.31 115.32,39.33 115.45,39.36 115.55,39.43 115.59,39.47
DGND on L03_SIG1 (solid shape): 61.28,82.98 61.34,83.07 61.45,83.05 61.78,82.73 61.69,82.64 61.69,81.37 62.09,80.97 62.11,80.86 62.02,80.79 60.83,80.79 60.33,80.29 60.22,80.27 60.15,80.36 60.15,80.65 61.28,81.77
DGND on L03_SIG1 (solid shape): 61.42,64.43 61.47,64.35 61.47,59.86 62.97,58.35 63.26,58.35 63.26,55.76 63.2,55.66 63.09,55.69 61.75,57.02 61.22,57.02 61.02,57.22 61.02,64.32 61.06,64.39 61.14,64.42 61.23,64.42 61.33,64.44
DGND on L03_SIG1 (solid shape): 57.67,75.05 57.73,75.14 57.84,75.12 60.17,72.79 60.17,72.49 60.14,72.41 60.06,72.39 59.9,72.37 59.77,72.3 59.69,72.28 59.62,72.32 59.55,72.4 59.45,72.46 59.44,72.46 57.67,74.24
DGND on L03_SIG1 (solid shape): 37.23,85.17 37.23,85.04 37.23,85.03 37.22,84.78 37.37,84.57 37.41,84.5 37.38,84.42 36.33,83.36 35.8,83.89 35.8,85.17 35.83,85.24 35.9,85.27 36.1,85.32 36.25,85.47 36.26,85.5 36.91,85.5
DGND on L03_SIG1 (solid shape): 45.65,18.79 45.75,18.77 46.15,18.37 46.15,13.26 46.01,13.13 45.9,13.11 45.84,13.2 45.84,17.96 42.85,17.96 42.88,18.08 42.95,18.12 45,18.12 45.36,18.47 45.37,18.47 45.5,18.57 45.58,18.72
DGND on L03_SIG1 (solid shape): 47.69,59.51 47.7,59.51 47.79,59.45 47.78,59.35 47.71,59 47.95,58.75 48.01,58.67 47.98,58.58 47.29,57.89 45.59,57.89 45.59,57.95 45.6,57.99 46.14,58.53 46.14,59.82 47.39,59.82
DGND on L03_SIG1 (solid shape): 53.18,46.97 53.27,46.91 53.25,46.8 52.25,45.79 52.25,43.49 52.24,43.47 51.61,42.84 50.39,42.84 49.68,42.13 49.6,42.1 49.52,42.15 49.38,42.29 49.19,42.34 49.12,42.37 49.09,42.44 49.09,46.63 48.83,46.88 48.83,46.97
DGND on L03_SIG1 (solid shape): 36.19,21.64 36.27,21.62 36.76,21.14 42.93,21.14 43.38,21.58 43.49,21.6 43.55,21.51 43.55,20.8 44.02,20.34 44.04,20.23 43.94,20.16 43.72,20.16 43.11,20.77 36.64,20.77 36.05,21.36 36.02,21.43 36.05,21.5 36.08,21.54 36.11,21.59
DGND on L03_SIG1 (solid shape): 34.3,25.15 34.37,25.12 34.74,24.76 34.74,23.57 35.02,23.29 35.04,23.18 34.95,23.11 34.2,23.11 34,22.92 33.89,22.9 33.83,22.99 33.83,24.91 33.81,24.96 33.86,24.99 33.93,24.99 34.09,25.03 34.23,25.12
DGND on L03_SIG1 (solid shape): 62.17,62.46 62.23,62.55 62.34,62.53 62.91,61.96 63.52,61.96 65.4,60.07 65.4,59.99 64.8,59.99 64.49,59.69 64.47,59.69 64.16,59.58 64.05,59.27 64.05,59.25 63.78,58.98 63.74,58.96 63.71,58.98 63.51,59.08 63.29,59.05 63.26,59.05 62.17,60.15
DGND on L03_SIG1 (solid shape): 123.3,41.2 123.35,41.21 123.39,41.16 123.39,39.87 123.31,39.79 122.36,39.79 122.33,39.85 122.34,39.86 122.34,39.92 122.38,39.99 122.46,40.01 122.84,40.14 122.9,40.53 122.9,40.54 122.9,40.87 122.94,40.88 123.1,40.96 123.21,41.1 123.21,41.11
DGND on L03_SIG1 (solid shape): 34,63.2 34.06,63.29 34.17,63.27 34.21,63.23 34.21,60.39 33.3,59.48 33.3,59.06 33.26,58.98 33.17,58.96 32.9,58.94 32.71,58.75 32.71,58.74 31.78,57.81 31.68,57.79 31.61,57.87 31.58,57.98 31.52,58.07 31.49,58.14 31.52,58.21 33.41,60.1 33.51,60.1 34,60.59
DGND on L03_SIG1 (solid shape): 88.41,63.13 88.41,62.43 87.96,61.97 87.96,60.9 87.92,60.82 87.83,60.8 87.37,60.43 87.83,60.06 87.92,60.04 87.96,59.96 87.96,59.89 87.48,59.4 87.42,59.39 87.39,59.44 87.39,59.48 87.06,59.81 87.06,61.68 88.13,62.75 88.13,63.2 88.23,63.31
DGND on L03_SIG1 (solid shape): 60.19,69.77 60.31,69.79 60.37,69.69 60.37,69.53 59.48,68.65 59.48,61.14 59.42,61.04 59.31,61.07 58.56,61.82 58.56,64.28 57.59,65.25 55.65,65.25 54.2,63.8 54.2,61.57 54.2,61.56 53.97,61.33 53.97,59.27 53.93,59.18 53.84,59.17 53.78,59.18 53.71,59.18 53.64,59.21 53.61,59.28 53.61,60.98 51.9,62.68 51.9,67.29 51.92,67.32 51.96,67.34 51.98,67.33 52.02,67.31 52.63,66.71 57.14,66.71
DGND on L03_SIG1 (solid shape): 33.94,79.27 34.05,79.29 34.11,79.2 34.11,74.74 33.42,74.06 33.42,73.08 33.36,72.98 33.25,73 32.47,73.78 32.47,77.36 32.53,77.45 32.63,77.44 33.18,77.59 32.98,78.11 32.92,78.19 32.95,78.28
DGND on L03_SIG1 (solid shape): 95.14,74.04 95.2,74.14 95.31,74.11 95.68,73.74 95.68,70.64 96.26,70.06 96.26,69.91 96.23,69.83 96.14,69.82 95.67,69.44 96.14,69.07 96.23,69.05 96.26,68.97 96.26,68.1 96.2,68 96.09,68.02 95.14,68.98
DGND on L03_SIG1 (solid shape): 59.59,59 59.7,59.02 59.76,58.93 59.76,58.46 56.79,55.49 56.79,54.96 56.6,54.77 56.49,54.75 56.43,54.84 56.43,57.44 56.54,57.55 56.63,57.58 56.7,57.53 57.31,57.44 57.22,58.05 57.17,58.12 57.2,58.21 57.72,58.73 59.32,58.73
DGND on L03_SIG1 (solid shape): 56.43,73.25 56.49,73.35 56.6,73.33 59.49,70.44 59.63,70.44 59.73,70.38 59.7,70.27 56.84,67.41 56.02,67.41 55.95,67.44 55.92,67.52 55.54,67.95 55.16,67.52 55.14,67.44 55.06,67.41 54.8,67.41 54.71,67.47 54.73,67.58 56.43,69.27
DGND on L03_SIG1 (solid shape): 77.7,68.32 77.77,68.35 77.84,68.32 77.87,68.3 77.91,68.23 77.88,68.15 77.57,67.84 77.57,67.23 75.78,65.43 75.67,65.41 75.6,65.51 75.6,66.4 76.38,67.18 76.41,67.19 76.45,67.18 76.92,67.15 77.05,67.6 77.05,67.61 77.05,67.88 77.09,67.95 77.17,67.98 77.42,68.02 77.58,68.2 77.59,68.21
DGND on L03_SIG1 (solid shape): 73.98,48.68 73.41,48.11 73.31,48.09 73.24,48.18 72.63,48.78 72.63,48.79 72.1,48.98 71.96,48.44 71.96,48.39 71.92,48.36 71.84,48.36 71.39,48.8 71.39,49.51 71.49,49.61 71.86,49.61 72.16,49.31 72.64,49.2 72.94,49.6 72.97,49.67 73.04,49.69 73.98,49.69
DGND on L03_SIG1 (solid shape): 88.93,59.05 89.04,59.07 89.1,58.98 89.1,54.24 90.27,53.06 90.27,52.33 90.21,52.33 90.18,52.35 88.76,53.76 88.76,53.83 88.76,53.83 88.41,54.36 88.06,53.83 88.06,53.83 88.06,53.47 89.68,51.85 89.69,51.84 89.87,51.65 90.13,51.62 90.16,51.63 90.21,51.58 90.14,51.51 89.72,51.51 88.99,52.24 86.72,52.24 86.47,52 86.36,51.98 86.3,52.07 86.3,52.61 88.49,54.81 88.49,58.62
DGND on L03_SIG1 (solid shape): 57.47,36.75 57.54,36.72 58.21,36.04 58.21,31.33 59.91,29.63 60.93,29.63 61.03,29.56 61.01,29.45 60.76,29.2 59.73,29.2 59.14,29.79 55.27,29.79 55.18,29.85 55.2,29.96 57.21,31.97 57.21,34.05 57.26,34.13 57.36,34.13 57.93,34.47 57.36,34.8 57.26,34.8 57.21,34.89 57.21,36.58 57.28,36.65 57.35,36.69 57.4,36.72
DGND on L03_SIG1 (solid shape): 118.11,39.48 118.22,39.4 118.36,39.38 118.53,39.38 118.6,39.35 118.63,39.29 118.95,38.97 119.06,38.89 119.19,38.87 119.59,38.87 119.82,39.1 119.88,39.11 119.91,39.06 119.91,39.01 119.91,39 119.9,38.73 120.08,38.52 120.14,38.45 120.11,38.36 119.58,37.84 119.31,37.84 119.23,37.88 119.21,37.97 119.11,38.36 118.71,38.44 118.7,38.44 117.79,38.44 117.79,39.31 117.77,39.33 117.82,39.38 117.83,39.38 117.94,39.41 118.03,39.48 118.07,39.52
DGND on L03_SIG1 (solid shape): 34.46,52.22 34.52,52.32 34.63,52.29 35.76,51.16 35.76,41.54 36.11,41.19 36.14,41.09 36.07,41.02 36.06,41.02 35.85,41.02 34.46,42.41 34.46,42.48 34.49,42.56 34.57,42.58 34.74,42.59 34.88,42.66 34.91,42.68 34.95,42.66 35.57,42.96 34.95,43.25 34.91,43.24 34.88,43.25 34.74,43.33 34.57,43.33 34.49,43.36 34.46,43.43
DGND on L03_SIG1 (solid shape): 45.96,54.54 46.02,54.63 46.13,54.61 46.6,54.14 46.6,52.69 46.25,52.34 46.25,50.35 46.97,49.63 48.12,49.63 48.21,49.57 48.19,49.46 46.81,48.07 46.81,47.15 46.78,47.08 46.71,47.05 46.55,47.01 46.42,46.9 46.34,46.86 45.96,47.05 45.58,46.86 45.2,47.05 44.82,46.86 44.44,47.05 44.06,46.86 43.98,46.9 43.85,47 43.7,47.05 43.63,47.08 43.6,47.15 43.6,51.43 45.96,53.78
DGND on L03_SIG1 (solid shape): 34.83,82.7 34.94,82.72 35,82.63 35,82.47 35,82.46 35.04,82.1 35.37,81.94 35.46,81.88 35.44,81.77 32.25,78.58 32.14,78.56 32.08,78.65 32.08,82.29 32.37,82.58 33.16,82.58 33.17,82.54 33.22,82.43 33.31,82.34 33.35,82.26 33.32,82.18 33.25,82.12 33.21,82.16 33.21,82.17 32.62,82.31 32.64,81.71 32.68,81.64 32.65,81.56 32.73,80.98 33.29,81.15 33.29,81.16
DGND on L03_SIG1 (solid shape): outline of 179 points within 17.03,47.88 24.45,53.07
DGND on L03_SIG1 (solid shape): 29.24,43.19 29.35,43.21 29.41,43.12 29.41,41.75 29.41,41.75 29.76,41.22 30.12,41.75 30.11,41.75 30.11,42.49 30.17,42.59 30.29,42.57 30.99,41.86 31.02,41.76 30.94,41.69 30.36,39.78 32.31,40.21 33.81,40.21 34.69,39.33 34.72,39.21 34.62,39.15 31.84,39.15 31.74,39.05 31.71,39.07 30.34,38.78 30.24,37.39 30.25,37.28 30.16,37.23 29.96,37.23 29.7,37.49 29.71,37.52 29.28,39.01 27.76,38.74 27.65,38.7 27.58,38.8 27.58,41.53
DGND on L03_SIG1 (solid shape): outline of 244 points within 75.16,41.78 81.79,54.94
DGND on L03_SIG1 (solid shape): outline of 284 points within 36.78,37.82 47.62,44.46
DGND on L03_SIG1 (solid shape): outline of 420 points within 27.11,55.11 31.38,81.96
DGND on L03_SIG1 (solid shape): outline of 432 points within 35.09,59.09 47.43,69.42
DGND on TOP: 62.88,73.99 62.88,67.36 62.93,67.31 70.22,67.31 70.38,67.46 70.38,73.99
DGND on TOP: 117.09,45.41 117.34,45.41 116.85,45.9 116.38,45.9 116.38,45.25 116.52,45.11 116.52,43.52 117.09,43.52
DGND on TOP: 40.4,57.78 39.39,57.78 38.93,57.33 38.93,56.72 38.8,56.59 36.7,56.59 36.57,56.46 36.57,56.24 36.67,56.13 38.63,56.13 38.93,55.83 38.93,55.6 39.06,55.47 39.31,55.47 39.64,55.14 39.64,54.36 39.67,54.33 39.92,54.33 40.02,54.43 40.02,55.37 40.23,55.58 40.68,55.58 40.84,55.73 40.84,55.96 41.04,56.16 42.99,56.16 43.07,56.24 43.07,56.44 42.92,56.59 40.94,56.59 40.68,56.85 40.68,57.51
DGND on TOP: 66.95,155.07 66.31,155.07 66.21,154.97 66.21,154.18 66.01,153.97 66.01,153.34 66.03,153.31 66.41,153.31 66.64,153.54 66.64,153.95 66.97,154.28 66.97,155.04
DGND on TOP: 41.67,157.73 41.11,157.73 40.96,157.58 40.96,156.18 41.6,155.55 42.97,155.55 43.53,156.11 43.53,157.02 43.4,157.15 42.26,157.15
DGND on TOP: 134.38,74.06 134.38,76.39 133.09,76.39 133.09,74.06
DGND on TOP: 84.8,45.31 84.09,45.31 84.09,43.52 84.23,43.52 84.42,43.33 84.42,43 84.5,42.93 85.08,42.93 85.08,43.45 85.16,43.52 85.16,44.96
DGND on TOP: 20.36,55.27 17.21,55.27 17.21,52.97 20.64,52.97 20.82,53.14 20.82,54.81
DGND on TOP: 49.45,70.28 49.45,68.88 51.07,68.88 51.07,70.28
DGND on TOP: 15.31,17.48 14.88,17.91 13.45,17.91 13.4,17.96 12.34,17.96 11.55,18.75 11.55,24.21 14.62,24.21 14.62,21.16 15.64,20.14 17.47,20.14 17.87,19.74 17.87,17.48
DGND on TOP: 51.78,98.04 50.11,98.04 50.11,100.08 51.78,100.08
DGND on TOP: 36.37,50.16 39.24,50.16 39.64,50.57 40.02,50.57 40.43,50.16 43.1,50.16 43.53,50.6 43.53,51.08 44.06,51.61 46.57,51.61 47.01,51.17 47.01,49.35 46.78,49.12 31.23,49.12 31.13,49.23 31.13,50.55 33.95,50.55 34.71,51.31 35.81,51.31 35.98,51.13 35.98,50.55
DGND on TOP: 129.45,77.83 129.45,78.84 128.15,78.84 128.15,77.83
DGND on TOP: 60.3,11.53 61.58,11.53 61.58,12.63 60.3,12.63
DGND on TOP: 31.77,75.84 31.77,74.93 32.71,74.93 32.94,75.16 32.94,75.9 31.82,75.9
DGND on TOP: 73.2,3.76 73.2,1.7 75.74,1.7 75.74,3.76
DGND on TOP: 65.65,64.62 62.43,64.62 62.3,64.49 62.3,62.51 62.1,62.31 62.1,59.79 63.85,59.79 63.87,59.82 63.87,62.23 64,62.36 65.55,62.36 65.73,62.53 65.73,64.54
DGND on TOP: 93.16,45.41 92.09,45.41 92.09,43.59 93.16,43.59
DGND on TOP: 46.78,63.07 46.98,62.87 46.98,61.06 46.88,60.96 43.5,60.96 43.45,61.01 43.45,62.38 43.35,62.48 40.33,62.48 40,62.15 39.62,62.15 39.29,62.48 36.47,62.48 36.11,62.13 36.11,60.66 32.96,60.66 32.58,61.04 32.58,63.07
DGND on TOP: 125.58,45.41 124.52,45.41 124.52,43.52 125.01,43.52 125.23,43.74 125.58,43.74
DGND on TOP: 30.62,23.42 30.62,22.74 30.58,22.71 30.58,22.06 30.36,21.84 28.1,21.84 27.83,22.12 27.01,22.12 27.01,21.13 27.08,21.05 29.26,21.05 29.39,20.92 31.03,20.92 31.08,20.97 31.08,21.89 31.34,22.15 31.62,22.15 31.7,22.23 32.02,22.23 32.02,24.03 31.24,24.81 29.71,24.81 29.62,24.72 29.62,23.69 29.77,23.54 30.5,23.54
DGND on TOP: 130.52,143.32 130.5,143.35 128.37,143.35 127.78,143.94 127.78,149.92 128.48,150.63 133.89,150.63 134.19,150.33 134.19,143.67 133.84,143.32
DGND on TOP: 19.93,17.53 19.75,17.7 19.75,18.92 21.4,20.57 23.16,20.57 24,21.41 24,23.55 24.38,23.93 26.26,23.93 26.26,21.74 25.25,20.74 25.25,19.01 25.16,18.92 23.74,18.92 22.83,18.01 21.28,18.01 20.79,17.53
DGND on TOP: 46.07,55.96 46.07,53.06 47.01,53.06 47.01,55.96
DGND on TOP: 60.78,10.08 60.78,9.04 60.96,8.86 64.17,8.86 64.38,8.8 64.72,9.14 65.37,9.14 65.42,9.18 65.42,10.07 65.28,10.21 60.9,10.21
DGND on TOP: 25.92,77.25 25.92,76.15 27.22,76.15 27.22,77.25
DGND on BOTTOM: 55.72,72.49 61.87,72.49 64,74.63 69.64,74.63 70.93,75.92 70.93,77.65 69.41,77.65 68.22,76.45 62.25,76.45 61.41,77.29 56.71,77.29 55.57,76.15 55.57,72.64
DGND on BOTTOM: 49.57,81.28 48.79,81.28 48.51,81 48.51,79.88 48.79,79.6 49.52,79.6 49.57,79.65
DGND on BOTTOM: 25.95,22.17 26.31,22.53 26.31,24.36 26,24.66 21.13,24.66 20.52,24.05 20.52,15.42 23.39,15.42 23.39,21.13 24.43,22.17
DGND on BOTTOM: 48.81,19.31 47.46,19.31 47.22,19.07 47.22,16.83 47.38,16.68 48.75,16.68 49.03,16.96 49.03,19.08
DGND on BOTTOM: 51.83,99.97 50.74,99.97 50.44,99.67 50.44,97.94 51.83,97.94
DGND on BOTTOM: 37.87,45.75 37.87,49.92 37.7,50.08 33.62,50.08 33.22,50.49 33.22,54.03 31.95,55.3 31.95,59.05 32.66,59.77 32.66,62.46 33.06,62.87 33.15,62.87 33.15,63.03 33.39,63.27 34.46,63.27 34.84,62.89 44.73,62.89 44.86,63.02 46.4,63.02 46.53,62.89 46.53,60.86 46.02,60.35 35.91,60.35 35.37,59.82 35.37,58.37 34.59,57.58 34.59,56.82 34.79,56.62 38.78,56.62 39.08,56.92 39.08,57.94 39.24,58.09 40.25,58.09 40.45,57.89 40.45,56.92 40.43,56.9 40.56,56.77 42.72,56.77 42.94,56.54 42.94,55.6 42.79,55.45 42.31,55.45 42.26,55.5 42.26,55.7 42.05,55.91 40.78,55.91 40.56,55.68 40.56,54.69 40.4,54.53 39.31,54.53 39.21,54.64 39.21,55.45 39.24,55.47 38.88,55.83 37.71,55.83 37.05,55.17 37.05,52.2 37.28,51.97 46.64,51.97 46.74,51.87 46.74,51.28 47.01,51.01 47.01,50.32 46.93,50.24 41.97,50.24 41.86,50.13 41.86,45.75
DGND on BOTTOM: 31.62,10.24 31.62,12.77 27.95,12.77 27,11.82 27,10.01 27.18,9.83 31.2,9.83
DGND on BOTTOM: 88.56,94.39 88.56,91.08 86.2,91.08 86.2,94.39
DGND on BOTTOM: 93.38,30.45 93.38,27.61 95.02,27.61 95.02,30.45
DGND on BOTTOM: 45.18,162.26 42.28,162.26 42.28,160.96 45.2,160.96 45.2,162.23
DGND on BOTTOM: 54.1,11.7 54.1,8.87 57.43,8.87 57.43,11.7
DGND on BOTTOM: 92.27,35.46 90.51,35.46 90.08,35.03 90.08,34.39 90.2,34.27 91.12,34.27 91.31,34.08 91.31,33.11 91.62,32.81 91.62,31.98 91.68,31.92 92.99,31.92 93.25,32.18 93.25,32.4 92.68,32.97 92.68,33.66 92.27,34.06
DGND on BOTTOM: 46.7,55.78 46.02,55.78 45.94,55.7 45.94,54.08 46.07,53.95 47.21,53.95 47.21,54.43 46.93,54.71 46.83,54.71 46.7,54.84
DGND on BOTTOM: 51.89,153.77 53.47,153.77 53.67,153.96 53.67,155.22 53.31,155.57 52.14,155.57 51.89,155.32
DGND on BOTTOM: 36.16,161.85 36.16,160.12 37.66,160.12 37.66,161.85
DGND on BOTTOM: 68.44,144.78 68.66,144.56 69.53,144.56 69.88,144.92 69.88,146.47 69.6,146.76 68.65,146.76 68.44,146.56
DGND on BOTTOM: 50.16,91.52 51.43,91.52 51.43,93.6 50.26,93.6 49.98,93.32 49.98,91.69
DGND on BOTTOM: 16.69,58.69 15.25,58.69 15.25,55.06 15.42,54.89 16.99,54.89 17.26,55.16 17.26,58.12
DGND on L02_GND1: 11.02,1.02 11.02,175.98 135.98,175.98 135.98,1.02 ; 4 cut-outs
DGND on L05_GND2: 11.02,1.02 11.02,175.98 135.98,175.98 135.98,1.02 ; 4 cut-outs
VBAT_IN on TOP: 63.88,158.56 63.88,155.96 65.32,154.53 65.32,153.29 65.41,153.2 65.41,153.2 65.62,153 65.62,151.66 65.84,151.66 65.86,151.68 65.86,153.15 65.81,153.19 65.81,154.03 65.95,154.17 65.95,158.45 65.83,158.56
VBUS_TYPEC1 on TOP: 32.99,5.87 32.99,6.75 32.91,6.83 32.62,6.83 32.5,6.94 32.5,7.26 32.6,7.35 32.75,7.35 32.75,8.27 33.04,8.27 33.04,7.35 33.31,7.35 33.42,7.25 33.42,6.95 33.3,6.84 33.3,5.87
VBUS_TYPEC1 on TOP: 35.74,8.31 35.74,7.43 35.66,7.35 35.37,7.35 35.25,7.24 35.25,6.92 35.35,6.83 35.5,6.83 35.5,5.91 35.79,5.91 35.79,6.83 36.06,6.83 36.17,6.93 36.17,7.23 36.05,7.34 36.05,8.31
VBUS_TYPEC1 on TOP: 35.8,14.48 35.8,16.36 36.16,16.36 36.59,16.79 36.92,16.79 37.35,16.36 37.62,16.36 37.62,15.54 37.1,15.03 37.1,14.48
VBUS_TYPEC1 on BOTTOM: 32.07,5.11 32.07,15.09 33.58,16.59 36.42,16.59 36.79,16.96 36.79,17.36 37.98,17.36 37.98,16.56 37.67,16.25 37.67,15.42 36.8,15.42 36.7,15.32 36.7,14.25 36.59,14.25 36.59,12.09 38.3,12.09 38.3,9.02 36.59,7.32 36.59,5.11
VBUS_TYPEC1 on L04_PWR1: 37.71,16.84 32.05,16.84 32.05,8.66 32.48,8.23 32.48,4.8 36.59,4.8 36.59,8.1 37.71,9.22
VBUS_TYPEC2 on TOP: 50.74,8.31 50.74,7.43 50.66,7.35 50.37,7.35 50.25,7.24 50.25,6.92 50.35,6.83 50.5,6.83 50.5,5.91 50.79,5.91 50.79,6.83 51.06,6.83 51.17,6.93 51.17,7.23 51.05,7.34 51.05,8.31
VBUS_TYPEC2 on TOP: 41.32,13.64 41.32,16.19 41.46,16.33 42.1,16.33 42.23,16.2 42.23,13.64
VBUS_TYPEC2 on TOP: 47.99,5.87 47.99,6.77 47.93,6.83 47.53,6.83 47.38,6.97 47.38,7.21 47.53,7.35 47.75,7.35 47.75,8.27 48.04,8.27 48.04,7.35 48.18,7.35 48.3,7.23 48.3,5.87
VBUS_TYPEC2 on BOTTOM: 46.17,5.2 46.17,8.51 45.84,8.84 45.84,12.55 44.55,13.83 43.93,13.83 43.7,14.06 41.66,14.06 41.26,14.47 41.26,16.51 41.31,16.56 41.31,17.39 41.97,17.39 41.97,16.46 42.25,16.18 42.25,15.38 42.55,15.08 42.91,15.08 42.91,15.09 45.09,15.09 45.96,14.21 47.34,14.21 47.85,13.7 53.38,13.7 53.99,14.32 53.99,15.07 54.3,15.38 55.63,15.38 55.75,15.49 55.75,17.43 55.88,17.56 58.47,17.56 58.47,13.46 57.12,12.11 52.39,12.11 51.56,11.28 51.56,5.69 51.07,5.2
VBUS_TYPEC2 on L04_PWR1: 41.04,16.71 41.04,11.99 43.91,9.12 45.69,9.12 46.17,8.64 46.17,4.93 46.65,4.45 51.02,4.45 51.76,5.18 51.76,11.61 52.72,12.57 59.23,12.57 59.23,16.71
VCC1V8_SYS on TOP: 71.95,141.39 71.95,143.5 70.2,143.5 69.41,142.71 69.41,141.39
VCC1V8_SYS on TOP: 66.11,128.96 65.52,128.96 65.19,128.63 62.63,128.63 61.79,127.79 61.79,126.01 62.68,125.12 66.79,125.12 67.15,125.48 67.15,126.14 67,126.29 64.18,126.29 63.82,125.93 62.81,125.93 62.63,126.11 62.63,127.61 63.24,128.22 66.26,128.22 66.26,128.8
VCC1V8_SYS on TOP: 132.58,144.78 128.6,144.78 128.48,144.89 128.48,146.15 128.56,146.23 131,146.23 131.23,146 132.53,146 132.59,145.94 132.59,144.79
VCC1V8_SYS on TOP: 94.35,58.85 94.96,58.85 94.96,60.43 94.23,60.43 94.07,60.27 94.07,59.89 94.35,59.61
VCC1V8_SYS on TOP: 39.09,48.54 39.09,43.92 31.38,43.92 30.57,44.72 30.57,48.2 30.91,48.54
VCC1V8_SYS on TOP: 14.42,121.64 18.4,121.64 18.43,121.61 18.43,120.24 16.15,120.24 15.89,120.5 14.41,120.5 14.41,121.63
VCC1V8_SYS on TOP: 45.51,59.44 45.51,58.78 45.33,58.6 44.37,58.6 43.48,57.71 42.51,57.71 42.45,57.77 42.45,57.99 42.47,58.01 43.15,58.01 43.22,58.09 43.22,58.5 43.86,59.14 43.86,59.46 44.04,59.64 45.31,59.64
VCC1V8_SYS on TOP: 47.03,75.92 46.35,75.92 46.09,75.67 46.09,75.08 47.13,74.04 50.74,74.04 51.1,73.69 53.76,73.69 54.07,73.99 54.07,74.22 53.79,74.5 53.79,74.57 53.64,74.73 53.64,75.03 53.56,75.11 52.82,75.11 51.99,75.95 49.37,75.95 48.81,75.39 47.57,75.39
VCC1V8_SYS on TOP: 61.21,95.86 60.9,96.16 60.9,96.7 61.18,96.98 62.07,96.98 62.37,97.28 62.37,98.17 62.01,98.54 59.06,98.54 58.84,98.32 58.51,98.32 58.23,98.6 58.23,98.88 59.43,100.08 59.43,100.99 58.84,101.57 56.94,101.57 55.9,100.53 55.47,100.53 55.16,100.84 55.16,101.19 56.74,102.77 57.52,102.77 58.36,103.61 58.36,104.88 58.01,105.23 56.46,105.23 56.18,105.51 56.18,106.17 56.48,106.48 56.48,107.59 57.65,108.76 58.16,108.76 58.59,109.19 59.53,109.19 59.61,109.27 59.61,111.25 58.59,112.27 57.62,112.27 57.04,112.85 57.04,113.89 57.12,113.97 57.47,113.97 57.62,113.82 57.62,113.56 57.96,113.23 58.89,113.23 60.44,111.68 60.44,108.31 59.86,107.72 58.74,107.72 58.34,107.31 58.34,106.12 59.33,105.13 59.33,102.95 62.22,100.05 62.22,99.8 62.5,99.52 62.5,98.65 63.16,97.99 63.16,96.95 62.07,95.86
VCC1V8_SYS on TOP: 44.57,121.54 43.27,121.54 43.1,121.36 43.1,119.46 43.32,119.23 44.62,119.23 44.8,119.41 44.8,121.31
VCC1V8_SYS on TOP: 50.82,138.33 50.82,139.4 50.64,139.57 50.64,140.11 51.45,140.92 53.48,140.92 56.2,138.2 56.2,126.87 55.49,126.16 53.38,126.16 53.15,126.39 53.15,127.1 53.26,127.2 53.92,127.2 54.02,127.1 55.08,127.1 55.49,127.51 55.49,127.99 55.26,128.22 53.97,128.22 53.38,128.8 53.38,132.56 54.6,133.78 54.6,138.66 52.95,140.31 52.06,140.31 51.83,140.08 51.83,138.56 51.86,138.53 51.66,138.33
VCC1V8_SYS on TOP: 66.03,112.19 70.25,112.19 70.68,111.76 70.68,109.96 70.91,109.73 70.91,109.17 69.33,109.17 68.88,108.71 68.7,108.71 68.42,108.99 68.42,109.17 69.54,110.29 69.54,110.72 69.39,110.87 66.82,110.87 66.49,110.54 66.11,110.54 65.75,110.9 65.75,111.91
VCC1V8_SYS on BOTTOM: 29.05,46.23 29.05,52.1 27.09,54.05 24.78,54.05 23.13,55.7 23.13,60.73 20.97,62.89 20.97,66.07 23,68.1 26.92,68.1 27.58,67.44 27.58,63.63 28.29,62.92 28.29,58.5 33.62,53.16 33.62,50.22 34.32,49.51 37.13,49.51 37.13,45.95 36.29,45.11 30.17,45.11 ; 1 cut-out
VCC1V8_SYS on BOTTOM: 79.88,127.81 78.99,127.81 78.86,127.69 78.86,124.82 79.09,124.59 79.85,124.59 80.05,124.79 80.54,124.79 80.66,124.92 80.66,125.98 80.33,126.31 80.33,126.8 80.08,127.05 80.03,127.05 79.98,127.1 79.98,127.71
VCC1V8_SYS on BOTTOM: 57.27,42.42 57.27,43.54 57.78,44.04 64.91,44.04 66.44,42.52 66.77,42.52 66.87,42.62 66.87,43.05 67.02,43.21 67.38,43.21 67.4,43.18 67.4,41.73 67.15,41.48 66.67,41.48 65.22,42.93 63.9,42.93 63.52,43.31 58.21,43.31 57.9,43 57.9,42.42 57.88,42.39 57.29,42.39
VCC1V8_SYS on BOTTOM: 48.79,75.16 47.72,75.16 47.44,75.44 46.68,75.44 46.42,75.69 46.19,75.69 46.04,75.54 46.04,74.17 46.14,74.07 46.58,74.07 46.63,74.12 46.63,74.75 46.73,74.85 47.41,74.85 47.57,74.7 48.73,74.7 48.84,74.8 48.84,75.11
VCC1V8_SYS on BOTTOM: 31.16,95.12 29.35,95.12 29,94.77 29,93.75 28.29,93.04 26.92,93.04 26.61,93.34 26.61,94.06 26.46,94.21 25.44,94.21 24.81,93.57 24.81,91.41 26.92,89.31 31.64,89.31 32.1,89.76 32.71,89.76 33.01,90.07 33.01,91.87 32.91,91.97 32.73,91.97 32.63,91.87 32.63,91.14 32.33,90.83 32.33,90.37 32.12,90.17 32.02,90.17 31.67,89.81 30.6,89.81 30.52,89.89 30.52,90.22 30.45,90.3 30.04,90.3 29.89,90.14 29.89,89.92 29.81,89.84 27.14,89.84 25.39,91.59 25.39,92.91 25.75,93.27 25.8,93.27 26.18,92.89 26.18,92.51 26.33,92.35 27.4,92.35 27.65,92.61 28.59,92.61 29.51,93.52 29.51,94.44 29.66,94.59 30.62,94.59 30.83,94.39 31.23,94.39 31.23,95.05
VCC1V8_SYS on BOTTOM: 35.91,83.9 35.2,83.9 34.84,84.25 33.65,84.25 33.49,84.1 33.49,83.72 33.39,83.62 33.06,83.62 32.94,83.49 32.94,82.35 33.39,81.89 33.6,81.89 33.8,82.09 33.8,83.26 34.16,83.62 35.91,83.62
VCC1V8_SYS on BOTTOM: 110.69,71.93 112.37,71.93 112.37,70.89 110.69,70.89 109.85,71.73 109.85,73.38 110.15,73.69 111.12,73.69 111.37,73.43 111.37,73.25 111.22,73.1 110.76,73.1 110.53,72.87 110.53,72.09
VCC1V8_SYS on BOTTOM: 45.2,106.6 44.85,106.6 44.77,106.53 44.77,105.44 44.95,105.26 44.95,103.71 45.31,103.35 45.74,103.35 45.92,103.53 45.92,103.73 45.43,104.22 45.43,105.44 45.2,105.66
VCC1V8_SYS on BOTTOM: 87.83,77.5 88.94,77.5 89.1,77.65 91.76,77.65 91.94,77.47 91.94,77.32 91.61,76.99 89.04,76.99 88.87,76.81 87.8,76.81 87.77,76.83 87.77,77.44
VCC1V8_SYS on BOTTOM: 69.23,112.04 66.82,112.04 66.44,112.42 65.24,112.42 64.79,111.96 64.79,110.34 64.53,110.08 63.87,110.08 63.44,110.52 62.27,110.52 62.27,109.78 63.9,109.78 64.25,109.42 64.56,109.42 64.79,109.19 64.79,106.98 64.91,106.86 66.13,106.86 66.5,107.23 66.5,107.53 66.26,107.77 65.55,107.77 65.5,107.82 65.5,109.4 66.08,109.98 66.39,109.98 66.72,110.31 66.72,111.07 66.97,111.33 69.39,111.33 69.46,111.4 69.46,111.81
VCC1V8_SYS on BOTTOM: 33.49,88.04 32.86,88.04 32.71,87.88 32.71,87.63 32.2,87.12 32.2,86.79 32.3,86.69 32.94,86.69 33.11,86.87 33.11,87.5 33.27,87.66 33.44,87.66 33.49,87.71
VCC1V8_SYS on L03_SIG1: 44.52,143.79 43.73,143.79 42.79,142.85 42.79,141.53 43.4,140.92 43.4,140.49 42.82,139.9 42.82,121.21 43.2,120.83 44.14,120.83 45.18,121.87 45.18,143.13
VCC1V8_SYS on L03_SIG1: 104.03,70.03 111.37,70.03 111.63,70.28 111.63,74.78 111.37,75.03 104.03,75.03 103.78,74.78 103.78,70.28
VCC1V8_SYS on L03_SIG1: 61.33,56.01 60.85,56.01 60.62,55.78 60.62,55.19 62.43,53.39 62.43,51.16 62.07,50.8 62.07,50.27 62.88,49.45 62.88,44.22 64.74,42.37 65.78,42.37 66.67,41.48 67.07,41.48 67.33,41.73 67.33,42.19 66.13,43.38 65.24,43.38 64.28,44.35 64.28,53.06
VCC1V8_SYS on L03_SIG1: 25.11,132.44 14.57,132.44 13.1,130.96 13.1,127.99 13.51,127.58 13.51,121.01 13.73,120.78 15.87,120.78 16.1,121.01 16.1,123.67 15.05,124.71 15.05,126.49 14.75,126.8 14.75,129.82 16.22,131.29 25.15,131.29 25.2,131.34 25.2,132.35
VCC1V8_SYS on L03_SIG1: 46.75,75.74 46.27,75.74 45.92,75.39 45.92,74.93 47.57,73.28 47.57,70.71 47.19,70.33 47.19,67.01 47.69,66.5 47.69,62.13 49.01,60.81 49.47,60.81 49.78,61.11 49.78,61.49 48.79,62.48 48.79,66.78 47.92,67.64 47.92,68.88 48.86,69.82 48.86,73.63
VCC1V8_SYS on L03_SIG1: 22.7,66.29 22.7,67.21 23.11,67.61 23.11,91.62 22.17,92.56 22.17,103.86 24.12,105.82 24.12,114.15 24.25,114.27 27.6,114.27 27.93,113.94 27.93,101.47 26.68,100.22 26.68,95.99 28.09,94.57 28.09,93.84 28.21,93.73 28.21,88.09 27.78,87.66 27.78,86.23 28.21,85.8 28.21,70.13 27.42,69.34 27.42,63.65 27.25,63.47 25.14,63.47 24.86,63.75 24.86,64.14
VCC1V8_SYS on L03_SIG1: 54.78,90.45 54.07,89.74 54.07,89.08 55.82,87.33 55.82,84.96 54.98,84.12 54.98,81.94 54.63,81.58 54.63,76.17 53.66,75.21 53.66,74.98 53.05,74.37 53.05,74.12 54.04,73.13 54.63,73.13 55.72,74.22 55.72,80.49 55.97,80.75 55.97,83.16 57.22,84.4 57.22,88.62 56.51,89.33 56.51,93.78 57.88,95.15 57.88,97.23 56.02,99.09 56.02,101.19 55.73,101.49 54.18,101.49 53.97,101.27 53.97,98.65 54.78,97.84
VCC1V8_SYS on L03_SIG1: 44.95,59.82 43.96,59.82 43.65,59.51 43.65,58.75 42.41,57.51 42.41,53.98 41.24,52.81 41.24,45.26 40.89,44.91 39.79,44.91 38.42,46.28 38.14,46.28 37.97,46.1 37.97,45.52 40.35,43.13 41.88,43.13 42.59,43.84 42.59,52.02 43.83,53.26 43.83,55.98 43.3,56.52 43.3,57.12 45.13,58.95 45.13,59.64
VCC1V8_SYS on L03_SIG1: 33.19,108.08 32.22,108.08 31.79,107.65 31.79,104.19 30.73,103.12 30.73,102.21 30.93,102.01 31.49,102.01 33.01,103.53 33.01,106.3 33.32,106.6 33.32,107.95
VCC1V8_SYS on L03_SIG1: 33.27,90.47 32.5,90.47 32.28,90.25 32.28,89.61 32.5,89.38 32.5,87.5 31.72,86.72 31.72,84.43 32.56,83.59 34.03,83.59 34.41,83.97 34.41,84.68 34.13,84.96 33.37,84.96 33.11,85.22 33.11,87.71 33.62,88.21 33.62,90.12
VCC1V8_SYS on L04_PWR1: 11.02,1.02 11.02,175.98 135.98,175.98 135.98,1.02 ; 58 cut-outs
VCC1V8_SYS_SW on TOP: 36.52,50.5 36.52,52.19 37.85,52.19 39.15,53.5 39.15,54.65 39.48,54.65 39.48,50.5
VCC1V8_TA on TOP: 12.64,83.03 12.16,83.03 11.88,82.75 11.88,79.83 13.33,78.38 14.95,78.38 15.51,78.94 15.51,79.27 15.33,79.45 14.98,79.45 14.83,79.3 13.76,79.3 12.57,80.49 12.57,82.65 12.69,82.78 12.69,82.98
VCC1V8_TA on TOP: 80.26,138.91 80.41,138.76 80.97,138.76 81.09,138.89 81.09,139.83 80.94,139.98 80.94,142.04 81.6,142.7 81.6,143.46 81.42,143.64 80.46,143.64 80.26,143.43
VCC1V8_TA on TOP: 19.63,81.2 19.63,77.27 21.05,75.84 22.8,75.84 23.51,76.56 23.51,77.62 23.64,77.75 24.63,77.75 24.78,77.9 24.78,78.79 24.66,78.92 23.06,78.92 23.03,78.89 23.03,78.31 23.16,78.18 23.16,76.91 22.62,76.38 21.81,76.38 20.24,77.95 20.24,80.42 20.39,80.57 20.85,80.57 20.95,80.67 20.95,81.31 19.73,81.31
VCC1V8_TA on BOTTOM: 20.82,69.57 20.24,69.57 20.03,69.37 20.03,68.48 17.67,66.12 17.67,65.43 17.26,65.02 16.38,65.02 16.07,65.33 16.07,66.8 16.48,67.21 16.48,67.64 16.27,67.84 15.41,67.84 15.03,67.46 15.03,64.9 16.17,63.75 18.84,63.75 19.02,63.93 19.02,66.45 20.92,68.35 20.92,69.47
VCC1V8_TA on BOTTOM: 15.23,75.23 15.16,75.31 15.16,77.17 15.74,77.75 15.74,78.41 15.51,78.64 11.98,78.64 11.02,79.6 11.02,91.31 11.55,91.85 11.55,155.52 15,158.98 24.76,158.98 38.91,144.83 59.68,144.83 60.55,143.97 69.41,143.97 70.76,145.31 80.84,145.31 81.53,144.63 81.53,142.67 80.56,142.67 80.51,142.72 80.51,143.56 79.9,144.17 71.01,144.17 69.13,142.29 60.24,142.29 58.97,143.56 37.81,143.56 25.54,155.83 15.74,155.83 12.36,152.45 12.36,93.37 13.25,92.48 15.44,92.48 15.61,92.3 15.61,91.36 15.51,91.26 12.24,91.26 11.63,90.65 11.63,84.3 12.06,83.87 15,83.87 15.11,83.77 15.11,83.26 15,83.16 12.69,83.16 12.54,83.01 12.54,81.41 13.38,80.57 18.23,80.57 20.85,77.95 20.85,77.04 20.67,76.86 20.03,76.86 19.96,76.94 19.96,77.93 17.72,80.16 15.66,80.16 15.49,79.98 15.49,79.25 15.51,79.22 16.17,79.22 16.27,79.12 16.27,77.14 16.05,76.91 16.05,75.41 15.87,75.23
VCC1V8_TA on L03_SIG1: 12.64,83.03 11.65,83.03 11.65,67.89 12.39,67.16 15.49,67.16 16.15,67.82 16.15,70.84 14.7,72.29 14.7,77.72 15.84,78.87 15.84,80.9 15.54,81.2 13.02,81.2 12.64,81.58
VCC1V8_TA on L04_PWR1: 80.04,128.18 82.75,125.48 91.05,125.48 92.68,123.85 92.68,119.66 92.98,119.35 97.38,119.35 98.62,120.6 98.62,128.04 96.46,130.2 84.85,130.2 83.48,131.57 83.48,142.14 81.91,143.71 79.57,143.71 78.1,142.24 78.1,132 74.64,128.55 74.64,128.09 74.95,127.79 78.07,127.79 78.47,128.18
VCC3V3_XDS on TOP: 53.71,106.35 53.18,106.35 52.98,106.15 52.98,103.99 52.32,103.33 50.03,103.33 48.23,101.52 48.23,94.59 48.33,94.49 48.66,94.49 48.79,94.61 48.79,100.99 50.54,102.74 52.49,102.74 53.21,103.45 53.69,103.45 53.87,103.63 53.87,106.2
VCC3V3_XDS on TOP: 22.78,78.92 22.14,78.92 21.96,78.74 21.96,77.8 22.06,77.7 22.85,77.7 22.95,77.8 22.95,78.08 22.78,78.26
VCC3V3_XDS on TOP: outline of 101 points within 24.55,73.33 37.94,96.09
VCC3V3_XDS on TOP: 40.91,82.5 40.91,78.13 41.01,78.03 41.85,78.03 42.05,78.23 42.05,78.61 41.93,78.74 41.65,78.74 41.27,79.12 41.27,80.8 41.52,81.05 41.52,81.76 43.45,83.69 46.27,83.69 46.35,83.62 47.39,83.62 48.33,84.56 48.33,86.26 48.15,86.44 47.87,86.44 47.67,86.23 47.67,85.78 46.96,85.06 46.96,84.76 46.55,84.35 44.01,84.35 43.76,84.61 43.55,84.61 43.22,84.94 43.22,86.44 44.06,87.27 45.76,87.27 45.86,87.38 45.86,87.45 45.76,87.55 44.32,87.55 44.04,87.83 44.04,91.11 44.21,91.29 46.27,91.29 46.35,91.21 46.73,91.21 46.78,91.26 46.78,95.58 46.7,95.66 46.3,95.66 46.14,95.5 46.14,92.58 45.89,92.33 43.48,92.33 43.25,92.1 43.25,88.85 42.74,88.34 42.74,86.94 42.36,86.56 42.36,84.91 42.59,84.68 42.59,84.18
VCC3V3_XDS on TOP: 15.89,75.13 15.31,75.13 15.05,74.88 15.05,68.96 16.02,68 17.57,68 17.82,68.25 17.82,68.86 17.62,69.06 17.19,69.06 16.38,69.88 16.38,74.65
VCC3V3_XDS on TOP: 54.42,69.29 53.56,69.29 53.26,68.99 53.26,68.58 53.48,68.35 53.48,60.3 55.26,58.52 56.84,58.52 58.29,57.07 58.29,48.84 58.72,48.41 59.02,48.41 59.2,48.59 59.2,57.53 57.12,59.61 55.9,59.61 55.62,59.89 55.62,65.05 54.78,65.89 54.78,68.94
VCC3V3_XDS on TOP: 40.68,97.92 38.19,97.92 37.91,97.64 37.91,96.62 37.79,96.49 37.79,94.54 37.81,94.51 38.02,94.51 38.07,94.56 38.07,96.11 38.47,96.52 38.47,97.05 38.73,97.31 40.68,97.31 40.73,97.36 40.73,97.87
VCC3V3_XDS on TOP: 30.27,99.85 29.08,99.85 26.66,97.43 26.66,96.32 25.34,95 25.34,92.58 25.44,92.48 25.93,92.48 26.15,92.71 26.15,94.41 27.7,95.96 27.7,97.28 29.56,99.14 30.32,99.14 30.32,99.8
VCC3V3_XDS on TOP: 16.32,85.8 15.56,85.8 15.38,85.62 15.38,83.34 15.59,83.13 16.5,83.13 16.55,83.19 16.55,85.57
VCC3V3_XDS on BOTTOM: 14.98,90.96 12.67,90.96 12.13,90.42 12.13,85.6 13,84.73 15.97,84.73 16.38,85.14 16.38,85.42 16.25,85.55 15.74,85.55 15.41,85.22 13.35,85.22 12.77,85.8 12.77,87.27 13.12,87.63 13.12,89.46 12.84,89.74 12.84,90.32 12.97,90.45 14.95,90.45 15.03,90.53 15.03,90.91
VCC3V3_XDS on BOTTOM: 30.95,88.67 30.73,88.67 30.55,88.49 30.55,87.53 29.1,86.08 29.1,84.61 29.68,84.02 31.06,84.02 31.18,84.15 31.18,84.45 31.06,84.58 30.07,84.58 29.86,84.79 29.86,85.95 31.11,87.2 31.11,88.52
VCC3V3_XDS on BOTTOM: 16.12,71.63 15.38,71.63 15.31,71.55 15.31,69.6 15.41,69.49 15.41,68.5 15.84,68.07 18.18,68.07 18.36,68.25 18.36,68.71 18.28,68.78 16.63,68.78 16.12,69.29
VCC3V3_XDS on BOTTOM: 17.44,83.79 15.97,83.79 15.84,83.67 15.84,83.03 17.87,81 18.48,81 20.26,79.22 20.26,78.82 20.52,78.56 21.25,78.56 21.53,78.28 21.53,78.13 22.04,77.62 22.27,77.62 22.42,77.47 22.42,76.02 21.48,75.08 15.23,75.08 15.11,74.96 15.11,74.68 15.31,74.47 21.76,74.47 23.13,75.84 23.13,77.22 23.36,77.44 24.02,77.44 24.71,76.76 24.71,75.92 25.29,75.34 25.72,75.34 25.98,75.59 25.98,76.07 26.23,76.33 28.29,76.33 28.64,76.68 28.64,77.34 28.14,77.85 25.44,77.85 21.94,81.36 19.88,81.36
VCC3V3_XDS on BOTTOM: 30.32,99.64 29.58,99.64 29.38,99.44 29.38,98.53 29.71,98.2 35.73,98.2 35.98,98.45 37.13,98.45 37.79,97.79 37.79,95.58 37.23,95.02 35.48,95.02 35.27,94.82 35.27,94.08 35.76,93.6 36.54,93.6 37.13,93.01 40.81,93.01 42.13,94.34 48.53,94.34 48.96,94.77 48.96,95.07 48.68,95.35 41.95,95.35 40.58,93.98 37.74,93.98 37.48,94.23 37.48,94.49 38.47,95.48 38.47,97.03 38.7,97.26 39.18,97.26 39.31,97.38 39.31,97.97 38.27,99.01 30.95,99.01
VCC3V3_XDS on BOTTOM: 60.85,49.61 58.74,49.61 58.39,49.25 58.39,48.74 58.97,48.16 69.92,48.16 70.54,47.54 72.34,47.54 72.99,48.18 77.87,48.18 78.02,48.03 78.02,46.89 78.1,46.81 78.58,46.81 78.99,46.41 78.99,46.13 79.16,45.95 79.6,45.95 79.95,46.3 79.95,48.13 78.81,49.28 74.47,49.28 73.02,50.72 71.11,50.72 69.66,49.28 61.18,49.28
VCC3V3_XDS on BOTTOM: 33.16,78.03 32.68,78.03 32.5,77.85 32.5,77.47 33.44,76.53 37.3,76.53 38.09,77.32 38.09,77.8 37.86,78.03 37.38,78.03 36.82,77.47 33.72,77.47
VCC3V3_XDS on L03_SIG1: 38.17,78.26 37.66,78.26 37.33,77.93 37.33,77.27 37.79,76.81 40.76,76.81 42.05,78.11 42.05,78.56 41.85,78.77 41.39,78.77 40.73,78.11 38.32,78.11
VCC3V3_XDS on L03_SIG1: 50,86.69 48,86.69 47.67,86.36 47.67,80.04 50.03,77.67 50.03,74.8 49.73,74.5 49.73,70.38 51.68,68.43 53.36,68.43 53.79,68.86 53.79,69.27 53.66,69.39 53.26,69.39 53.15,69.49 53.15,70.05 50.87,72.34 50.87,74.27 50.61,74.52 50.61,77.34 50.84,77.57 50.84,79.71 50.21,79.71 49.7,80.21 49.7,81.79 50.44,82.52 50.44,83.69 50.84,84.1 50.84,85.85
VCC_0V85 on TOP: 45.72,56.9 45.72,58.11 45.56,58.27 44.57,58.27 43.91,57.61 42.18,57.61 42.08,57.51 42.08,57.2 42.13,57.15 43.73,57.15 43.81,57.07 43.81,56.9
VCC_0V85 on BOTTOM: 44.32,58.17 44.32,57.81 45.74,57.81 45.74,58.37 47.9,60.53 47.9,63.47 48.13,63.7 48.13,64.31 48.07,64.36 47.06,64.36 46.86,64.16 46.86,63.14 47.08,62.92 47.08,60.81 46.25,59.97 45.89,59.97 44.67,58.75 44.67,58.52
VCC_1V8_FT4232 on TOP: 63.74,39.25 63.74,40.01 63.22,40.01 63.14,39.93 63.14,39.29 63.31,39.13 63.31,36.84 62.59,36.13 53.84,36.13 53.82,36.1 53.82,35.56 53.85,35.54 54.54,35.54 54.7,35.7 62.14,35.7 62.36,35.48 62.36,34.82 62.2,34.67 59.88,34.67 58.83,33.61 58.83,29.13 58.26,28.56 56.87,28.56 56.81,28.5 55.26,28.5 55.23,28.47 55.23,28.21 55.26,28.18 56.9,28.18 57.02,28.07 58.67,28.07 59.4,28.79 59.4,33.13 60.29,34.03 62.98,34.03 64.72,32.29 64.72,30.2 63.25,28.73 63.25,25.1 62.98,24.84 62.98,23.42 63.13,23.27 63.53,23.27 63.66,23.41 63.66,28.4 65.2,29.94 65.2,32.67 63.11,34.76 63.11,35.98 63.63,36.49 63.63,39.13
VCC_1V8_IOVDD on TOP: 75.71,135.76 74.82,136.65 74.82,137.16 74.62,137.36 72.71,137.36 72.33,137.74 72.33,140.98 72.6,141.25 72.6,143.62 72.33,143.89 70.15,143.89 69.11,142.85 69.11,142.39 68.19,141.48 63.01,141.48 61.59,140.06 57.27,140.06 54.96,142.37 54.96,144.07 55.16,144.27 55.47,144.27 55.62,144.12 55.62,142.93 55.8,142.75 56.38,142.75 56.66,143.03 56.66,144.09 56.79,144.22 57.35,144.22 57.45,144.12 57.45,142.16 57.9,141.71 58.92,141.71 59.3,142.09 59.3,146.58 59.12,146.76 58.49,146.76 58.29,146.96 57.52,146.96 57.19,147.29 55.9,147.29 55.85,147.35 55.85,147.7 55.87,147.73 57.57,147.73 57.85,147.45 59.56,147.45 60.06,146.94 60.06,142.01 60.29,141.78 61.64,141.78 62.25,142.39 67.66,142.39 68.65,143.38 68.65,143.84 70.05,145.24 74.13,145.24 74.85,144.52 74.85,141.25 74.7,141.1 73.8,141.1 73.12,140.41 73.12,139.4 73.32,139.19 74.24,139.19 74.34,139.09 75.68,139.09 76.98,137.79 76.98,135.92 76.83,135.76
VCC_1V8_IOVDD on TOP: 63.9,150.47 62.48,150.47 62.27,150.67 62.27,150.85 61.84,150.85 61.69,151 60.39,151 60.37,150.98 60.37,150.5 60.6,150.27 61.94,150.27 62.02,150.19 62.93,150.19 62.98,150.14 63.9,150.14
VCC_1V8_IOVDD on BOTTOM: 65.12,163.7 64.2,163.7 64.1,163.6 64.1,162.76 63.77,162.43 61.69,162.43 61.41,162.15 61.41,160.86 61.64,160.63 63.31,160.63 65.22,162.53 65.22,163.6
VCC_1V8_IOVDD on L03_SIG1: 57.47,143.23 57.47,143.03 57.29,142.85 56.71,142.85 55.16,144.4 55.16,155.63 61.69,162.15 62.5,162.15 63.29,161.37 63.29,160.78 60.37,157.86 60.37,157.1 61.74,155.73 63.92,155.73 64.64,155.02 64.64,153.24 63.9,152.5 63.9,150.27 63.21,149.58 61.61,149.58 61.05,150.14 61.05,150.7 61.28,150.93 61.66,150.93 62.1,150.5 62.86,150.5 63.19,150.83 63.19,153.44 62.78,153.85 58.29,153.85 57.45,153.01 57.45,143.26
VCC_3V3_AVDD on TOP: 63.48,142.97 65.12,142.97 65.12,145.32 62.83,145.32 62.83,146.13 63.72,146.13 63.72,146.83 62.27,146.83 62.27,144.88 60.95,144.88 60.95,143.99 63.48,143.99
VCC_3V3_AVDD on TOP: 59.38,154.9 59.38,152.6 58.59,152.6 58.26,152.93 57.57,152.93 57.57,151.26 57.01,151.26 57.01,152.94 54.59,152.94 54.59,154.89 56.19,154.89 56.19,153.96 56.38,153.77 58.16,153.77 58.26,153.87 58.26,154.73 58.44,154.9
VCC_3V3_FT4232 on TOP: 59.42,10.45 59.42,11.6 59.32,11.69 59.32,12.03 59.25,12.1 58.71,12.1 58.59,12.21 58.59,12.56 58.85,12.82 59.78,12.82 59.92,12.69 59.92,10.45
VCC_3V3_FT4232 on BOTTOM: 53.08,18.96 58.72,18.96 59.33,18.35 59.33,13.49 58.56,12.73 58.56,11.89 58.74,11.71 59.83,11.71 60.65,12.52 60.65,18.3 61.31,18.96 63.94,18.96 65.82,20.84 67.5,20.84 67.93,21.28 67.93,22.8 67.92,22.82 67.92,25.43 66.78,26.57 65.36,26.57 64.27,27.67 64.27,28.22 63.85,28.64 63.85,29.61 63.82,29.64 63.64,29.64 63.53,29.53 63.53,22.28 63.09,21.84 55.94,21.84 54.87,22.9 54.87,28.78 55.23,29.14 58.55,29.14 58.69,29.28 58.69,33.31 60.63,35.26 67.02,35.26 67.99,34.29 68.98,34.29 69.61,34.92 69.61,35.78 68.75,36.65 62.58,36.65 62.17,37.06 62.17,39.52 61.87,39.83 61.08,39.83 60.85,39.6 60.85,37.85 58.88,35.87 57.07,35.87 53.89,32.69 52.21,32.69 51.43,31.9 51.43,30.18 50.26,29.01 50.26,24.21 53.08,21.39
VCC_3V3_SYS on TOP: 28.08,113.31 27.91,113.49 27.91,117.73 28.41,118.24 28.41,118.92 28.62,119.13 34.87,119.13 38.09,115.9 41.55,115.9 43.48,113.97 43.48,113.64 43.17,113.33 42.82,113.33 42.13,114.02 37.36,114.02 34.13,117.25 30.27,117.25 29.91,116.89 29.91,113.67 29.56,113.31
VCC_3V3_SYS on TOP: 97.65,158.54 95.91,158.54 95.54,158.91 95.54,160.11 95.66,160.23 97.65,160.23
VCC_3V3_SYS on TOP: 51.71,122.1 51.71,120.55 53,120.55 53,122.1
VCC_3V3_SYS on TOP: 122.62,68.36 122.62,64.87 122.86,64.63 122.86,63.88 122.7,63.72 121.88,63.72 121.81,63.79 121.81,68.26 122.52,68.26
VCC_3V3_SYS on TOP: 40.36,48.56 40.36,45.95 40.64,45.67 50.92,45.67 51.5,46.25 54.63,46.25 57.96,49.58 57.96,55.17 55.11,55.17 54.78,54.84 54.78,52.25 54.88,52.15 56.28,52.15 56.28,51.54 56,51.26 56,50.01 54.12,48.13 52.8,48.13 52.37,48.56
VCC_3V3_SYS on TOP: 124.1,45.41 123.06,45.41 123.06,43.87 123.94,42.98 123.94,42.8 123.94,42.8 123.94,42 124.53,42 124.53,43.05 124.1,43.48
VCC_3V3_SYS on TOP: 91.67,45.41 90.5,45.41 90.5,43.65 90.88,43.27 91.13,43.27 91.51,42.89 91.51,42 92.1,42 92.1,43.05 91.67,43.48
VCC_3V3_SYS on TOP: 59.91,154.86 59.91,152.51 60.94,152.51 60.94,154.86
VCC_3V3_SYS on BOTTOM: 42.08,35.51 41.14,35.51 41.11,35.48 41.11,33.63 41.34,33.4 41.34,32.69 40.68,32.03 38.32,32.03 37.25,30.96 37.25,28.5 38.35,27.41 38.63,27.41 38.93,27.1 38.93,27 39.01,26.92 39.34,26.92 39.39,26.97 39.39,27.3 38.35,28.35 38.19,28.35 37.71,28.83 37.71,30.3 38.75,31.34 41.29,31.34 42.26,32.31 42.26,35.33
VCC_3V3_SYS on BOTTOM: 47.82,56.46 47.16,56.46 46.98,56.29 46.98,55.17 47.85,54.31 47.85,53.04 47.9,52.98 48.15,52.98 48.23,53.06 48.23,54.61 47.69,55.14 47.69,55.83 47.87,56.01 47.87,56.41
VCC_3V3_SYS on BOTTOM: 45.76,66.17 42.46,66.17 41.8,66.83 36.72,66.83 34.51,69.04 31.64,69.04 29.91,67.31 28.82,67.31 28.57,67.06 28.57,66.45 28.77,66.24 28.77,65.51 29.3,64.97 29.3,63.4 29.23,63.32 28.21,63.32 27.86,63.68 27.86,67.41 28.54,68.1 29.84,68.1 31.21,69.47 34.99,69.47 37.18,67.28 42.28,67.28 42.72,66.85 45.99,66.85 46.14,66.7 46.14,66.55
VCC_3V3_SYS on BOTTOM: 56.23,57.61 56.48,57.61 56.86,57.99 57.55,57.99 58.16,57.38 58.16,52.93 57.96,52.73 57.35,52.73 57.19,52.88 57.19,53.85 56.76,54.28 56.69,54.28 56.69,55.68 56.71,55.7 56.71,55.75 56.51,55.96 56.51,56.21 56.66,56.36 57.27,56.36 57.6,56.69 57.6,57 57.37,57.23 56.18,57.23 56.18,57.56
VCC_3V3_SYS on BOTTOM: 28.14,115.11 29.43,115.11 33.09,111.46 43.32,111.46 43.55,111.68 44.95,111.68 45.15,111.89 47.67,111.89 47.9,112.12 48.25,112.12 48.38,111.99 48.38,111.35 48.35,111.33 47.11,111.33 46.26,110.48 45.04,110.48 44.54,109.98 30.88,109.98 27.6,113.26 27.6,114.58
VCC_3V3_SYS on BOTTOM: 127.73,45.92 122.93,45.92 122.45,45.44 122.45,43.64 122.95,43.13 126.56,43.13 127.17,42.52 127.17,41.4 127.35,41.22 128.08,41.22 128.31,41.45 128.31,45.34
VCC_3V3_SYS on BOTTOM: 39.51,41.4 38.85,41.4 38.7,41.25 38.7,40.13 39.21,39.62 39.21,38.18 38.93,37.9 38.93,36.83 39.26,36.5 40.12,36.5 40.2,36.58 40.45,36.58 40.56,36.68 40.56,36.83 40.4,36.98 39.46,36.98 39.31,37.13 39.31,37.54 39.97,38.2 39.97,40.06 39.57,40.46 39.57,41.35
VCC_3V3_SYS on BOTTOM: 42.49,49.89 42.49,45.69 42.31,45.52 38.42,45.52 37.71,44.81 27.04,44.81 26.38,44.15 26.38,42.62 26.71,42.29 32.78,42.29 33.83,43.33 38.8,43.33 39.18,43.71 42.44,43.71 43.58,44.86 46.12,44.86 46.96,45.69 46.96,49.89
VCC_3V3_SYS on BOTTOM: 107.7,74.82 109.17,74.82 109.17,75.79 107.7,75.79
VCC_3V3_SYS on BOTTOM: 45.61,71.09 46.17,71.09 46.42,71.35 47.16,71.35 47.72,71.91 47.72,72.39 48.28,72.95 53.61,72.95 54.09,72.47 54.09,71.48 55.03,70.54 55.03,69.01 55.31,68.73 56.81,68.73 57.24,68.3 57.24,66.14 57.42,65.96 57.62,65.96 57.98,65.61 57.98,65.33 57.88,65.23 57.78,65.23 57.62,65.38 57.62,65.53 57.5,65.66 57.12,65.66 56.74,66.04 56.74,67.84 56.46,68.12 56.18,68.12 55.97,67.92 55.97,67.54 55.75,67.31 55.03,67.31 54.6,67.74 54.6,70.18 53.46,71.32 53.46,72.03 53.23,72.26 49.27,72.26 48.96,71.96 48.96,71.4 48.13,70.56 46.45,70.56 46.27,70.38 45.61,70.38 45.46,70.54 45.46,70.94
VCC_3V3_SYS on BOTTOM: 55.06,60.27 54.15,60.27 53.48,59.61 53.48,57.89 54.5,56.87 55.54,56.87 55.59,56.92 55.59,57.07 55.44,57.23 54.68,57.23 54.6,57.3 54.6,58.09 55.08,58.57 55.08,60.25
VCC_3V3_SYS on BOTTOM: 49.32,51.56 49.67,51.56 49.98,51.26 49.98,50.42 49.73,50.16 49.73,48.41 50.31,47.83 50.31,46.58 50.87,46.02 50.87,44.12 50.18,43.43 50.18,43.13 50.34,42.98 51.3,42.98 51.43,42.85 51.43,42.67 51.35,42.6 50.21,42.6 49.85,42.95 49.85,43.64 50.34,44.12 50.34,45.57 49.62,46.28 49.62,47.83 49.32,48.13 49.32,50.14 49.67,50.5 49.67,51.08 49.57,51.18 49.29,51.18 49.22,51.26 49.22,51.46
VCC_3V3_SYS on L03_SIG1: 58.23,54.36 57.62,54.36 57.4,54.13 57.4,52.15 59.73,49.81 60.62,49.81 60.93,50.11 60.93,50.67 58.46,53.14 58.46,54.13
VCC_3V3_SYS on L03_SIG1: 129.76,47.6 128.97,47.6 128.59,47.22 128.59,44.86 127.02,43.28 127.02,42.67 127.53,42.16 128.03,42.16 130.09,44.22 130.09,47.27
VCC_3V3_SYS on L03_SIG1: 52.8,122.2 51.86,122.2 51.66,122 51.66,115.77 52.25,115.18 52.25,113.17 53.08,112.34 53.08,112.12 53.41,111.79 54.35,111.79 54.96,112.39 54.96,114.73 53.93,115.76 53.93,121.07
VCC_3V3_SYS on L03_SIG1: 39.97,82.98 39.46,82.98 39.06,82.58 39.06,79.4 38.88,79.22 38.88,78.82 39.26,78.44 39.87,78.44 40.51,79.07 40.51,82.45
VCC_3V3_SYS on L03_SIG1: 43.71,74.8 42.99,74.8 42.44,74.24 42.44,73.36 45.18,70.61 45.18,66.55 45.43,66.29 46.12,66.29 46.47,66.65 46.47,70.71 43.99,73.2 43.99,74.52
VCC_3V3_SYS on L03_SIG1: 47.57,56.57 47.03,56.57 46.96,56.49 46.96,55.22 47.62,54.56 47.62,52.27 47.26,51.92 47.26,50.77 47.39,50.65 48.02,50.65 48.38,51 48.38,55.75
VCC_3V3_SYS on L04_PWR1: outline of 106 points within 42.51,21.39 126.31,116.15
VCC_3V3_SYS on L04_PWR1: 66.95,49.56 67.51,49 69.33,49 70.68,47.65 72.15,47.65 72.84,48.34 72.84,53.8 72.33,54.31 67.91,54.31 66.95,53.34
VCC_3V3_SYS on L04_PWR1: 30.12,115.27 28.92,115.27 28.62,114.96 28.62,113 26.84,111.23 26.84,105.26 24.73,103.15 24.73,62.28 25.54,61.47 25.54,50.65 29.94,46.25 29.94,44.88 30.98,43.84 33.19,43.84 33.42,44.07 33.42,47.07 29.46,51.03 29.46,71.07 27.73,72.8 27.73,91.52 26.71,92.53 26.71,94.84 28.85,96.98 28.85,102.49 30.83,104.47 30.83,114.55
VCC_3V3_SYS on L04_PWR1: 46.45,122.5 46.07,122.12 46.07,119.71 46.42,119.35 66.51,119.35 68.52,121.36 68.52,125.83 67,127.36 66.13,127.36 64.97,128.52 64.97,129.41 65.73,130.18 68.85,130.18 70.17,128.85 74.13,128.85 77.59,132.31 77.59,138.61 76.75,139.45 70.25,139.45 69.28,140.41 69.28,147.96 74.21,152.88 103.68,152.88 106.88,149.68 106.88,146.94 107.64,146.18 114.62,146.18 115.38,146.94 115.38,152.98 108.15,160.22 69.74,160.22 66.03,156.51 61.51,156.51 60.14,155.14 60.14,146.74 62.1,144.78 62.1,142.54 61.08,141.53 61.08,130.25 65.35,125.98 65.35,125.04 65.09,124.79 63.67,124.79 63.33,124.45 63.33,121.96 62.6,121.23 59.43,121.23 58.16,122.5
VCC_3V3_SYS_REG_SW on TOP: 43.15,50.5 43.15,52.02 42.97,52.19 41.79,52.19 40.49,53.5 40.49,54.65 40.15,54.65 40.15,50.5
VCC_5V0 on TOP: 53.71,19.46 53.71,17.47 53.98,17.2 55.96,17.2 55.96,16.25 49.08,16.25 49.08,19.46
VCC_5V0 on TOP: 64.1,62.2 65.8,62.2 66.03,61.98 66.03,60.45 65.6,60.02 65.6,59.26 65.98,58.88 65.98,58.52 65.8,58.34 65.3,58.34 64.89,58.75 64.89,60.53 65.24,60.88 65.24,61.57 65.07,61.75 64.15,61.75 64.1,61.8
